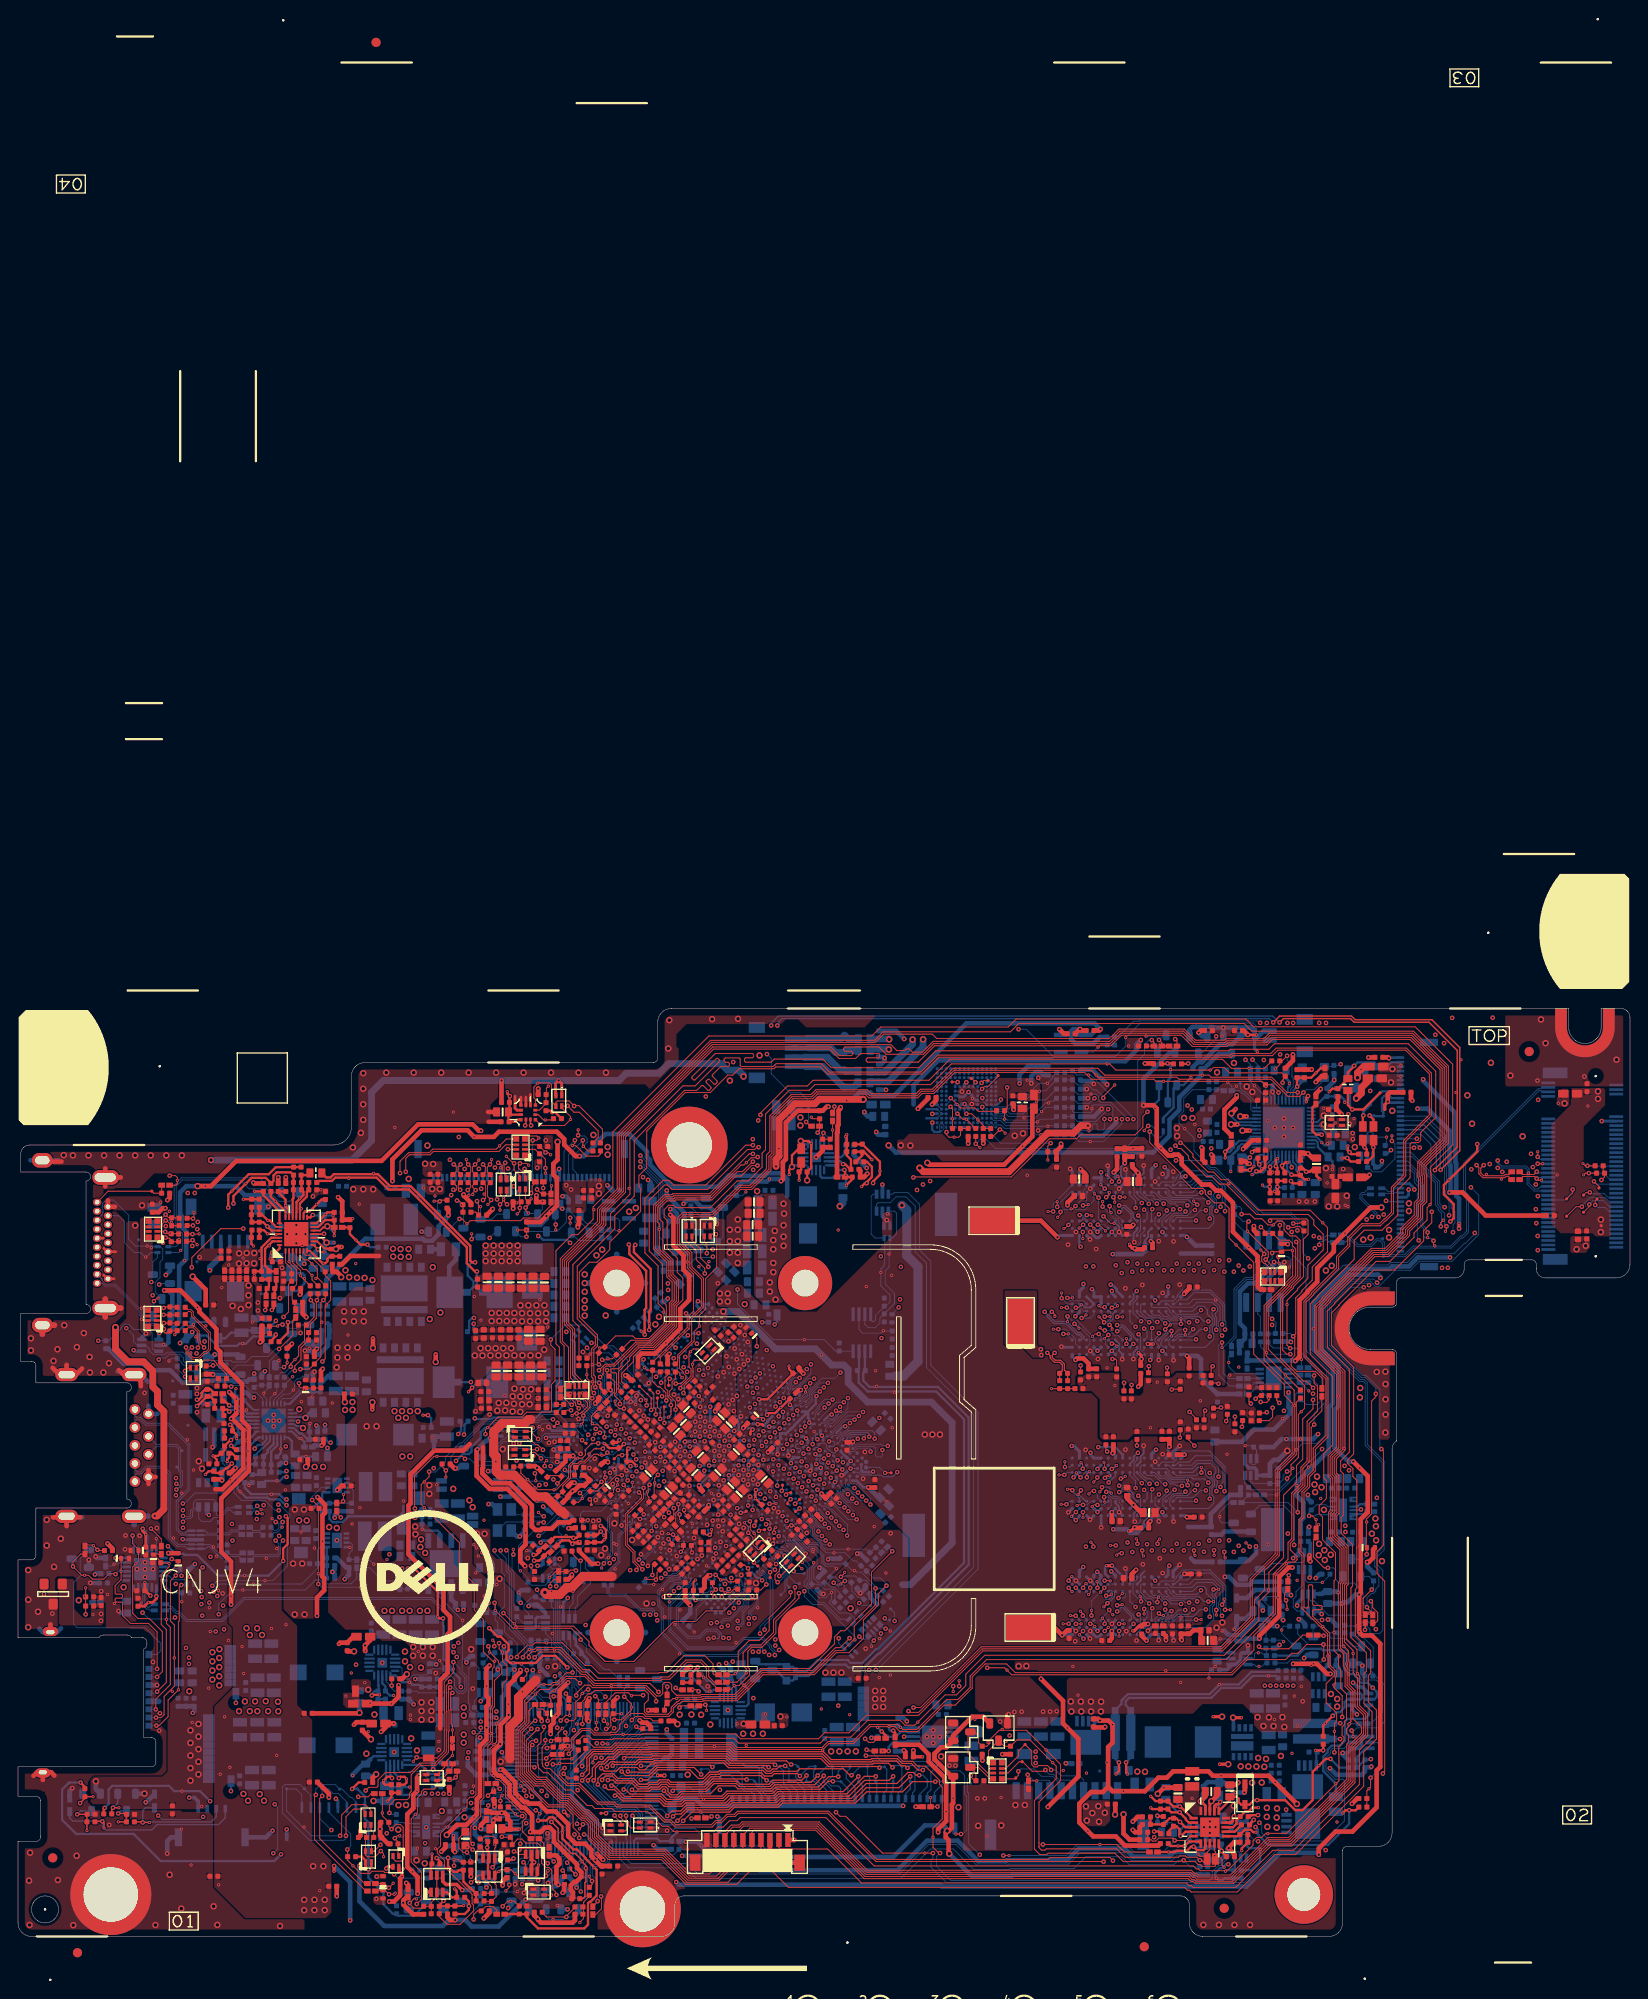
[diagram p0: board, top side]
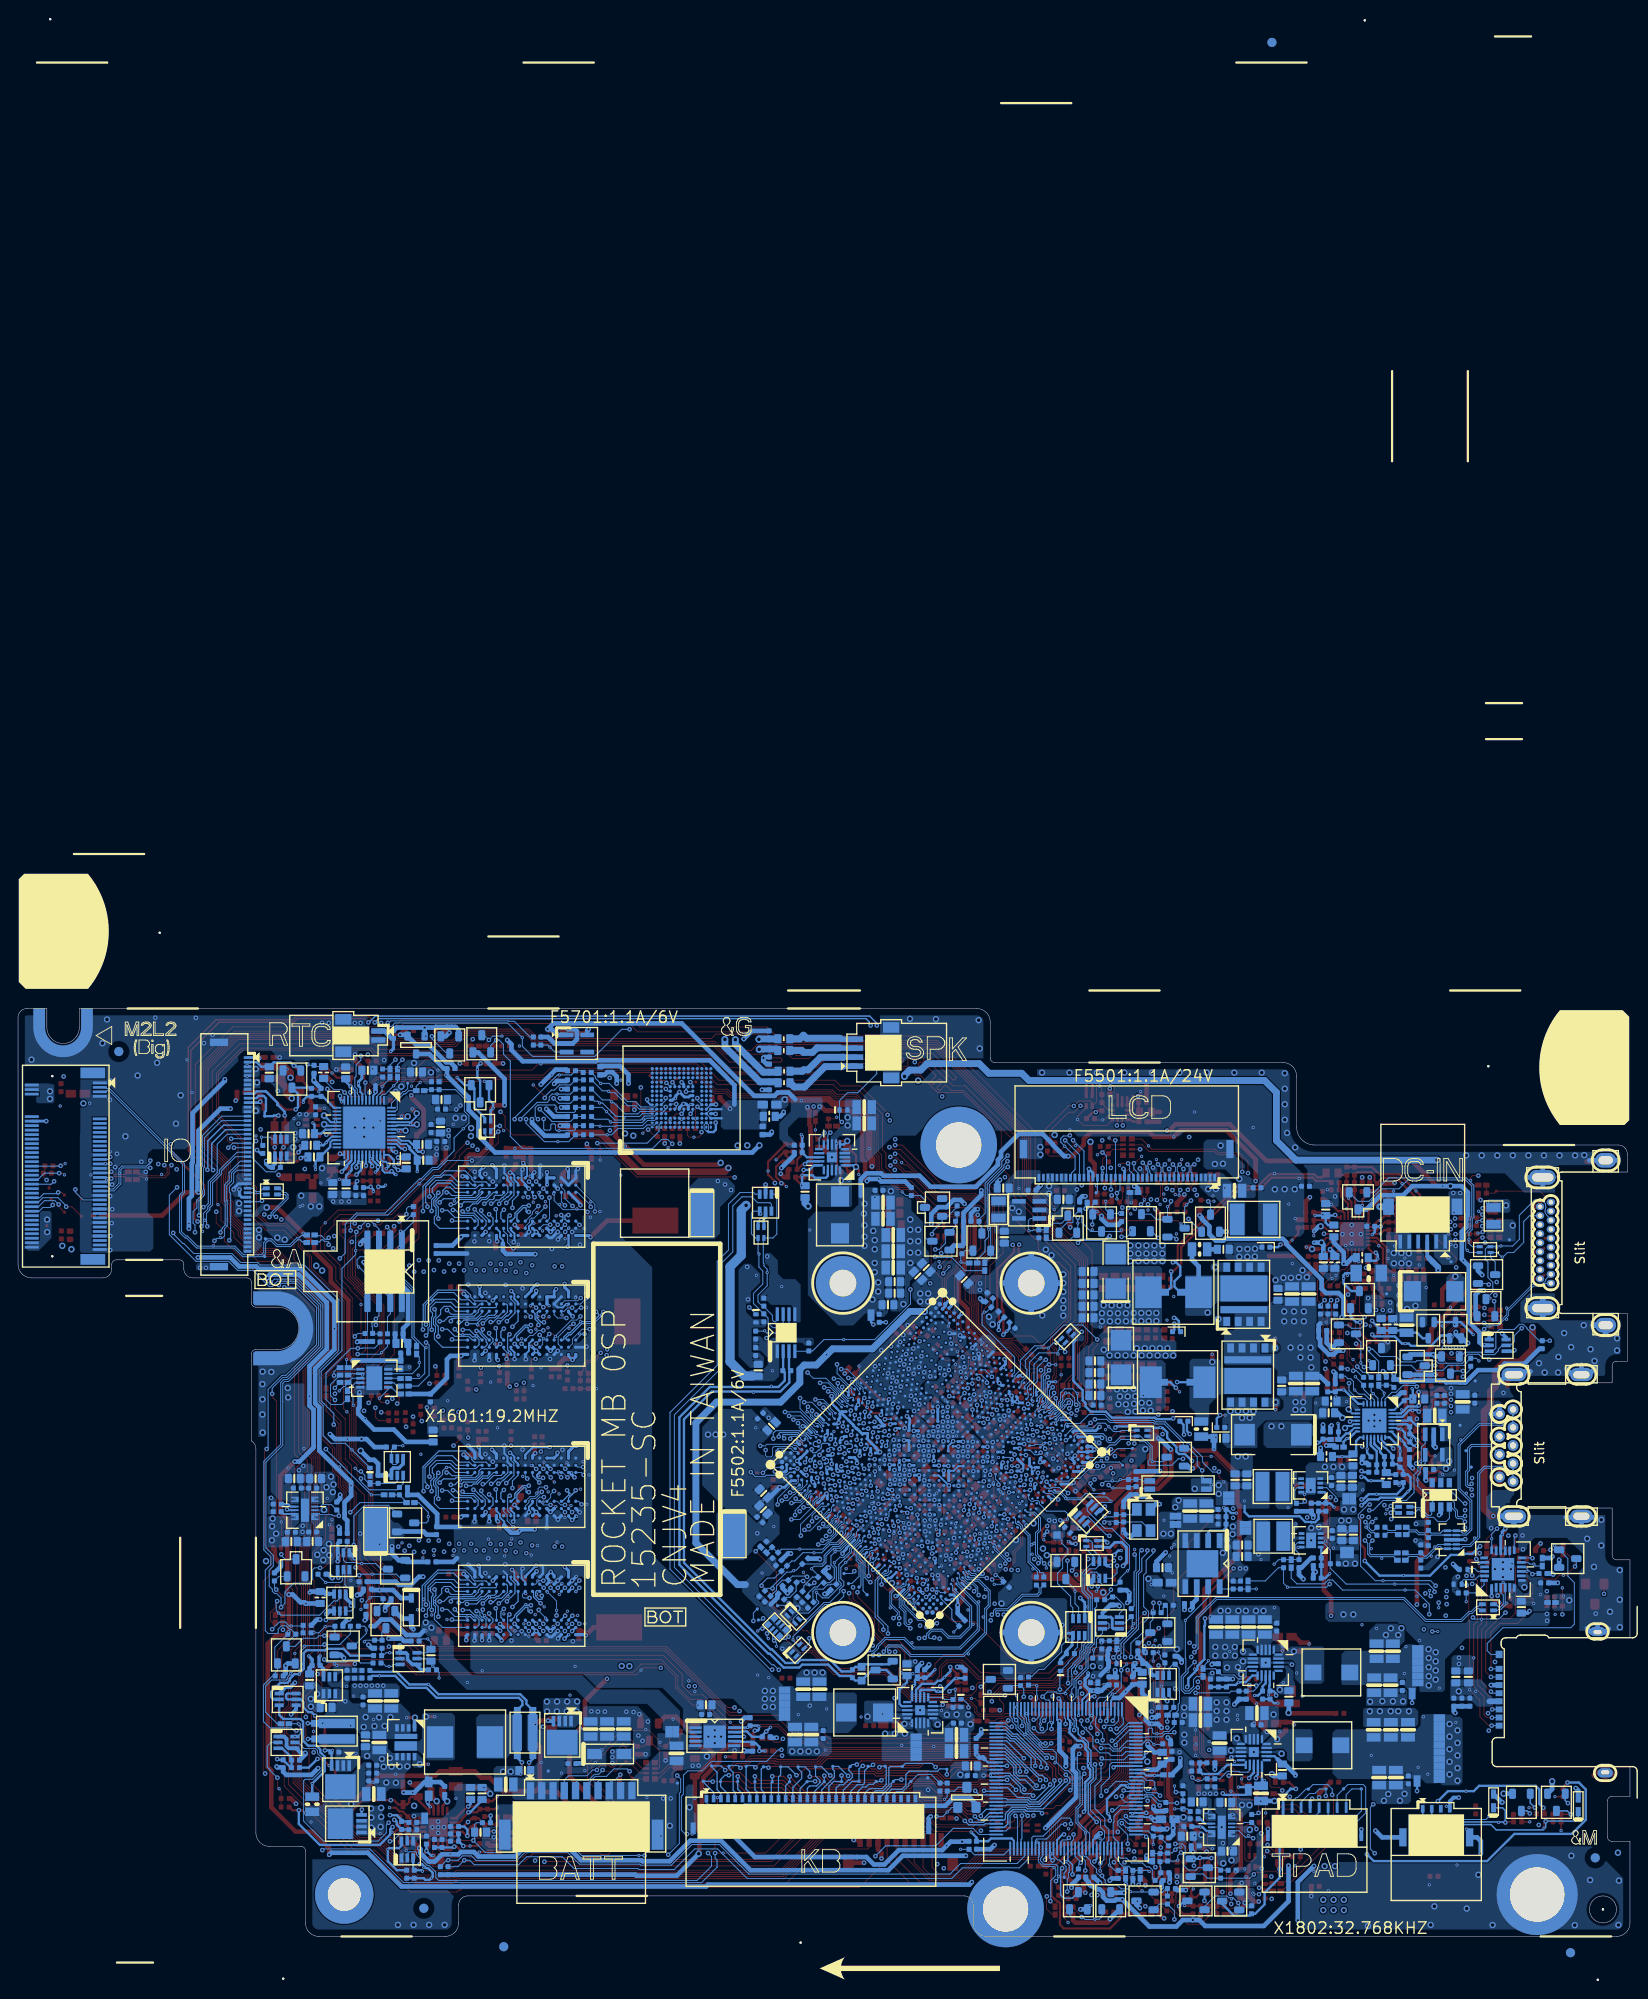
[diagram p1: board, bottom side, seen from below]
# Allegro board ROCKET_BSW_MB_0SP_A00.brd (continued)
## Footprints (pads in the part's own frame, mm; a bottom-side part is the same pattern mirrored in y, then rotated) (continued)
G6179HT0321-001
  rect 0.635x2.108 smd: 1(1.905,3.466) 2(0.635,3.466) 3(-0.635,3.466) 4(-1.905,3.466) 5(-1.905,-3.466) 6(-0.635,-3.466) 7(0.635,-3.466) 8(1.905,-3.466)
GAP-CLOSE-PWR-3
  rect 0.66x0.762 smd: 1(-0.305,0) 2(0.305,0)
HOLE256R142-OG
  round 6.502 hole 3.607: 1(0,0)
HOLE335R197
  round 8.509 hole 5.004: 1(0,0)
HOLE354R237
  round 8.992 hole 6.02: 1(0,0)
L1608-UH38
  custom 0.197x0.197 smd: 1(0,0.66) 2(0,-0.66)
L3030-3009H60
  rect 3.251x1.524 smd: 1(0,1.108) 2(0,-1.108)
L4947-1015H119
  rect 1.753x1.88 smd: 1(0,2.045) 2(0,-2.045)
L4947-1115H119
  rect 2.007x2.261 smd: 1(0,2.049) 2(0,-2.049)
L6965-1330-UH119
  rect 3.505x2.438 smd: 1(0,2.973) 2(0,-2.973)
L7066-1830-UH119
  rect 3.505x2.921 smd: 1(0,2.78) 2(0,-2.78)
L125100-4P-4H24
  rect 0.762x0.432 smd: 1(-0.625,0.341) 2(0.625,0.341) 3(0.625,-0.341) 4(-0.625,-0.341)
L125100-4P-4H28
  rect 0.762x0.432 smd: 1(-0.625,0.341) 2(0.625,0.341) 3(0.625,-0.341) 4(-0.625,-0.341)
LFQFN28J4-G2D7-UH40
  rect 0.203x0.584 smd: 1(1.2,1.86) 2(0.8,1.86) 3(0.4,1.86) 4(0,1.86) 5(-0.4,1.86) 6(-0.8,1.86) 7(-1.2,1.86) 15(-1.2,-1.86) 16(-0.8,-1.86) 17(-0.4,-1.86) 18(0,-1.86) 19(0.4,-1.86) 20(0.8,-1.86) 21(1.2,-1.86)
  rect 0.584x0.203 smd: 8(-1.86,1.2) 9(-1.86,0.8) 10(-1.86,0.4) 11(-1.86,0) 12(-1.86,-0.4) 13(-1.86,-0.8) 14(-1.86,-1.2) 22(1.86,-1.2) 23(1.86,-0.8) 24(1.86,-0.4) 25(1.86,0) 26(1.86,0.4) 27(1.86,0.8) 28(1.86,1.2)
  rect 2.692x2.692 smd: 29(0,0)
LGA12G2H40
  rect 0.381x0.381 smd: 1(0.809,0.809) 4(-0.809,0.809) 7(-0.809,-0.809) 10(0.809,-0.809)
  rect 0.305x0.432 smd: 2(0.25,0.784) 3(-0.25,0.784) 8(-0.25,-0.784) 9(0.25,-0.784)
  rect 0.432x0.305 smd: 5(-0.784,0.25) 6(-0.784,-0.25) 11(0.784,-0.25) 12(0.784,0.25)
LQFP128H63
  rect 0.203x1.524 smd: 1(6.2,7.747) 2(5.8,7.747) 3(5.4,7.747) 4(5,7.747) 5(4.6,7.747) 6(4.2,7.747) 7(3.8,7.747) 8(3.4,7.747) 9(3,7.747) 10(2.6,7.747) 11(2.2,7.747) 12(1.8,7.747) 13(1.4,7.747) 14(0.999,7.747) 15(0.599,7.747) 16(0.199,7.747) 17(-0.199,7.747) 18(-0.599,7.747) 19(-0.999,7.747) 20(-1.4,7.747) 21(-1.8,7.747) 22(-2.2,7.747) 23(-2.6,7.747) 24(-3,7.747) 25(-3.4,7.747) 26(-3.8,7.747) 27(-4.2,7.747) 28(-4.6,7.747) 29(-5,7.747) 30(-5.4,7.747) 31(-5.8,7.747) 32(-6.2,7.747) 65(-6.2,-7.747) 66(-5.8,-7.747) 67(-5.4,-7.747) 68(-5,-7.747) 69(-4.6,-7.747) 70(-4.2,-7.747) 71(-3.8,-7.747) 72(-3.4,-7.747) 73(-3,-7.747) 74(-2.6,-7.747) 75(-2.2,-7.747) 76(-1.8,-7.747) 77(-1.4,-7.747) 78(-0.999,-7.747) 79(-0.599,-7.747) 80(-0.199,-7.747) 81(0.199,-7.747) 82(0.599,-7.747) 83(0.999,-7.747) 84(1.4,-7.747) 85(1.8,-7.747) 86(2.2,-7.747) 87(2.6,-7.747) 88(3,-7.747) 89(3.4,-7.747) 90(3.8,-7.747) 91(4.2,-7.747) 92(4.6,-7.747) 93(5,-7.747) 94(5.4,-7.747) 95(5.8,-7.747) 96(6.2,-7.747)
  rect 1.524x0.203 smd: 33(-7.747,6.2) 34(-7.747,5.8) 35(-7.747,5.4) 36(-7.747,5) 37(-7.747,4.6) 38(-7.747,4.2) 39(-7.747,3.8) 40(-7.747,3.4) 41(-7.747,3) 42(-7.747,2.6) 43(-7.747,2.2) 44(-7.747,1.8) 45(-7.747,1.4) 46(-7.747,0.999) 47(-7.747,0.599) 48(-7.747,0.199) 49(-7.747,-0.199) 50(-7.747,-0.599) 51(-7.747,-0.999) 52(-7.747,-1.4) 53(-7.747,-1.8) 54(-7.747,-2.2) 55(-7.747,-2.6) 56(-7.747,-3) 57(-7.747,-3.4) 58(-7.747,-3.8) 59(-7.747,-4.2) 60(-7.747,-4.6) 61(-7.747,-5) 62(-7.747,-5.4) 63(-7.747,-5.8) 64(-7.747,-6.2) 97(7.747,-6.2) 98(7.747,-5.8) 99(7.747,-5.4) 100(7.747,-5) 101(7.747,-4.6) 102(7.747,-4.2) 103(7.747,-3.8) 104(7.747,-3.4) 105(7.747,-3) 106(7.747,-2.6) 107(7.747,-2.2) 108(7.747,-1.8) 109(7.747,-1.4) 110(7.747,-0.999) 111(7.747,-0.599) 112(7.747,-0.199) 113(7.747,0.199) 114(7.747,0.599) 115(7.747,0.999) 116(7.747,1.4) 117(7.747,1.8) 118(7.747,2.2) 119(7.747,2.6) 120(7.747,3) 121(7.747,3.4) 122(7.747,3.8) 123(7.747,4.2) 124(7.747,4.6) 125(7.747,5) 126(7.747,5.4) 127(7.747,5.8) 128(7.747,6.2)
MSOP8-1H44
  rect 0.356x1.524 smd: 1(-0.975,-2.055) 2(-0.325,-2.055) 3(0.325,-2.055) 4(0.975,-2.055) 5(0.975,2.055) 6(0.325,2.055) 7(-0.325,2.055) 8(-0.975,2.055)
MSOP10-G2D5H44
  rect 0.305x1.372 smd: 1(-1,-2.146) 2(-0.5,-2.146) 3(0,-2.146) 4(0.5,-2.146) 5(1,-2.146) 6(1,2.146) 7(0.5,2.146) 8(0,2.146) 9(-0.5,2.146) 10(-1,2.146)
  rect 2.489x2.489 smd: 11(0,0)
NFSA0-S6705-TP20
  round 0.254 hole 1.651 unplated: (-10,0)
  round 0.254 hole 1.168 unplated: (10,0)
  rect 0.305x1.549 smd: 1(9.25,-5.275) 2(9,2.275) 3(8.75,-5.275) 4(8.5,2.275) 5(8.25,-5.275) 6(8,2.275) 7(7.75,-5.275) 16(5.5,2.275) 17(5.25,-5.275) 18(5,2.275) 19(4.75,-5.275) 20(4.5,2.275) 21(4.25,-5.275) 22(4,2.275) 23(3.75,-5.275) 24(3.5,2.275) 25(3.25,-5.275) 26(3,2.275) 27(2.75,-5.275) 28(2.5,2.275) 29(2.25,-5.275) 30(2,2.275) 31(1.75,-5.275) 32(1.5,2.275) 33(1.25,-5.275) 34(1,2.275) 35(0.75,-5.275) 36(0.5,2.275) 37(0.25,-5.275) 38(0,2.275) 39(-0.25,-5.275) 40(-0.5,2.275) 41(-0.75,-5.275) 42(-1,2.275) 43(-1.25,-5.275) 44(-1.5,2.275) 45(-1.75,-5.275) 46(-2,2.275) 47(-2.25,-5.275) 48(-2.5,2.275) 49(-2.75,-5.275) 50(-3,2.275) 51(-3.25,-5.275) 52(-3.5,2.275) 53(-3.75,-5.275) 54(-4,2.275) 55(-4.25,-5.275) 56(-4.5,2.275) 57(-4.75,-5.275) 58(-5,2.275) 59(-5.25,-5.275) 60(-5.5,2.275) 61(-5.75,-5.275) 62(-6,2.275) 63(-6.25,-5.275) 64(-6.5,2.275) 65(-6.75,-5.275) 66(-7,2.275) 67(-7.25,-5.275) 68(-7.5,2.275) 69(-7.75,-5.275) 70(-8,2.275) 71(-8.25,-5.275) 72(-8.5,2.275) 73(-8.75,-5.275) 74(-9,2.275) 75(-9.25,-5.275)
  rect 1.194x2.743 smd: 76(10.35,-4.5) 77(-10.35,-4.5)
NTC-402H24-U
  custom 0.14x0.14 smd: 1(0,0.445) 2(0,-0.445)
NTC-603H38
  custom 0.216x0.216 smd: 1(0,0.762) 2(0,-0.762)
OSC-3225-4P-4H32
  rect 1.397x1.067 smd: 1(-1.171,-0.756) 2(1.171,-0.756) 3(1.171,0.756) 4(-1.171,0.756)
PAD-87212-1002N
  rect 0.61x1.549 smd: 1(-4.5,-2.525) 2(-3.5,-2.525) 3(-2.5,-2.525) 4(-1.5,-2.525) 5(-0.5,-2.525) 6(0.5,-2.525) 7(1.5,-2.525) 8(2.5,-2.525) 9(3.5,-2.525) 10(4.5,-2.525)
  rect 1.194x1.803 smd: 11(-5.797,0) 12(5.797,0)
POLYSW-2114H30
  rect 1.6x0.965 smd: 1(0,0.94) 2(0,-0.94)
POLYSW-4633-UH43
  rect 3.505x1.626 smd: 1(0,1.834) 2(0,-1.834)
PPAK-8P-2H45
  rect 0.406x1.168 smd: 1(-0.975,-2.351) 2(-0.325,-2.351) 3(0.325,-2.351) 4(0.975,-2.351)
  rect 3.404x2.769 smd: 5(0,0)
  rect 0.025x0.025 smd: 6(1.029,0.902) 7(0.013,0.902) 8(-0.991,0.902)
PPAK-8P-G5324H44-COLAY
  rect 0.762x1.016 smd: 1(-1.905,-3.01) 2(-0.635,-3.01) 3(0.635,-3.01) 4(1.905,-3.01) 5(1.905,3.01) 6(0.635,3.01) 7(-0.635,3.01) 8(-1.905,3.01)
  rect 5.207x2.896 smd: 9(0,0.65)
  rect 5.207x0.787 smd: 10(0,-1.7)
PTFBT4-09GLBS1NN4H2
  rect 0.813x0.762 smd: 1(5.3,11.775)
  rect 0.66x0.762 smd: 2(3.7,11.775) 3(2.8,11.775) 4(1.9,11.775) 5(1,11.775) 6(0.1,11.775) 7(-0.8,11.775) 8(-1.7,11.775) 9(-2.6,11.775)
  oval 1.016x1.702 hole 0.457x0.914: 10(-7.775,0) 11(7.775,0.85)
QFN20G3D5-G2D15H40
  rect 0.305x0.914 smd: 1(1,1.801) 5(-1,1.801) 11(-1,-1.801) 15(1,-1.801)
  rect 0.305x0.965 smd: 2(0.5,1.775) 3(0,1.775) 4(-0.5,1.775) 12(-0.5,-1.775) 13(0,-1.775) 14(0.5,-1.775)
  rect 0.914x0.305 smd: 6(-1.801,1) 10(-1.801,-1) 16(1.801,-1) 20(1.801,1)
  rect 0.965x0.305 smd: 7(-1.775,0.5) 8(-1.775,0) 9(-1.775,-0.5) 17(1.775,-0.5) 18(1.775,0) 19(1.775,0.5)
  rect 2.159x2.159 smd: 21(0,0)
QFN20Z3-G1D1H36
  custom 0.064x0.064 smd: 1(0.9,1.424) 5(-0.9,1.424) 6(-1.424,0.9) 10(-1.424,-0.9) 11(-0.9,-1.424) 15(0.9,-1.424) 16(1.424,-0.9) 20(1.424,0.9)
  rect 0.254x1.168 smd: 2(0.45,1.424) 3(0,1.424) 4(-0.45,1.424) 12(-0.45,-1.424) 13(0,-1.424) 14(0.45,-1.424)
  rect 1.168x0.254 smd: 7(-1.424,0.45) 8(-1.424,0) 9(-1.424,-0.45) 17(1.424,-0.45) 18(1.424,0) 19(1.424,0.45)
  rect 1.092x1.092 smd: 21(0,0)
QFN24-G2D5H40-U
  rect 0.305x0.838 smd: 1(1.25,2.095) 6(-1.25,2.095) 13(-1.25,-2.095) 18(1.25,-2.095)
  rect 0.305x0.965 smd: 2(0.751,2.032) 3(0.25,2.032) 4(-0.25,2.032) 5(-0.751,2.032) 14(-0.751,-2.032) 15(-0.25,-2.032) 16(0.25,-2.032) 17(0.751,-2.032)
  rect 0.838x0.305 smd: 7(-2.095,1.25) 12(-2.095,-1.25) 19(2.095,-1.25) 24(2.095,1.25)
  rect 0.965x0.305 smd: 8(-2.032,0.751) 9(-2.032,0.25) 10(-2.032,-0.25) 11(-2.032,-0.751) 20(2.032,-0.751) 21(2.032,-0.25) 22(2.032,0.25) 23(2.032,0.751)
  rect 2.489x2.489 smd: 25(0,0)
QFN48J6-G465H40
  rect 0.203x0.965 smd: 1(2.2,3.025) 2(1.8,3.025) 3(1.4,3.025) 4(1,3.025) 5(0.6,3.025) 6(0.2,3.025) 7(-0.2,3.025) 8(-0.6,3.025) 9(-1,3.025) 10(-1.4,3.025) 11(-1.8,3.025) 12(-2.2,3.025) 25(-2.2,-3.025) 26(-1.8,-3.025) 27(-1.4,-3.025) 28(-1,-3.025) 29(-0.6,-3.025) 30(-0.2,-3.025) 31(0.2,-3.025) 32(0.6,-3.025) 33(1,-3.025) 34(1.4,-3.025) 35(1.8,-3.025) 36(2.2,-3.025)
  rect 0.965x0.203 smd: 13(-3.025,2.2) 14(-3.025,1.8) 15(-3.025,1.4) 16(-3.025,1) 17(-3.025,0.6) 18(-3.025,0.2) 19(-3.025,-0.2) 20(-3.025,-0.6) 21(-3.025,-1) 22(-3.025,-1.4) 23(-3.025,-1.8) 24(-3.025,-2.2) 37(3.025,-2.2) 38(3.025,-1.8) 39(3.025,-1.4) 40(3.025,-1) 41(3.025,-0.6) 42(3.025,-0.2) 43(3.025,0.2) 44(3.025,0.6) 45(3.025,1) 46(3.025,1.4) 47(3.025,1.8) 48(3.025,2.2)
  rect 4.648x4.648 smd: 49(0,0)
R402H14
  custom 0.14x0.14 smd: 1(0,0.445) 2(0,-0.445)
R402H16
  custom 0.14x0.14 smd: 1(0,0.445) 2(0,-0.445)
R603H22
  custom 0.197x0.197 smd: 1(0,0.66) 2(0,-0.66)
R805H24
  rect 1.549x0.94 smd: 1(0,0.838) 2(0,-0.838)
R1206H28
  rect 1.854x1.27 smd: 1(0,1.397) 2(0,-1.397)
R3720H40
  rect 4.013x1.041 smd: 1(0,0.867) 2(0,-0.867)
SC70-2D2-312H44
  custom 0.152x0.152 smd: 1(-0.65,-0.902) 2(0.65,-0.902) 3(0,0.902)
SC70-6H44
  rect 0.406x1.016 smd: 1(-0.65,-0.94) 2(0,-0.94) 3(0.65,-0.94) 4(0.65,0.94) 5(0,0.94) 6(-0.65,0.94)
SKT-HDMI23-188125-1-U1
  oval 0.762x0.914 hole 0.508: 1(-4.5,6.08) 2(-4,7.28) 3(-3.5,6.08) 4(-3,7.28) 5(-2.5,6.08) 6(-2,7.28) 7(-1.5,6.08) 8(-1,7.28) 9(-0.5,6.08) 10(0,7.28) 11(0.5,6.08) 12(1,7.28) 13(1.5,6.08) 14(2,7.28) 15(2.5,6.08) 16(3,7.28) 17(3.5,6.08) 18(4,7.28) 19(4.5,6.08)
  oval 1.626x2.972 hole 0.914x2.362: 20(7.25,6.98) 22(-7.25,6.98)
  oval 1.626x2.311 hole 0.914x1.6: 21(9.15,0) 23(-9.15,0)
SKT-USB13-160161
  round 1.194 hole 0.711: 1(3.5,9.09) 2(1,9.09) 3(-1,9.09) 4(-3.5,9.09) 5(-4,7.59) 6(-2,7.59) 7(0,7.59) 8(2,7.59) 9(4,7.59)
  oval 1.473x2.515 hole 0.813x1.803: 10(-7.85,0) 11(7.85,0)
  oval 1.473x2.718 hole 0.813x2.007: 12(-7.85,7.5) 13(7.85,7.5)
SMD-ARES4
  rect 0.356x0.66 smd: 1(-0.325,-0.599) 2(0.325,-0.599) 3(0.325,0.599) 4(-0.325,0.599)
SMD-ARES4H18
  rect 0.356x0.66 smd: 1(-0.325,-0.599) 2(0.325,-0.599) 3(0.325,0.599) 4(-0.325,0.599)
SMD-ARES4H20
  rect 0.356x0.66 smd: 1(-0.325,-0.599) 2(0.325,-0.599) 3(0.325,0.599) 4(-0.325,0.599)
SMD-OSC2H56
  rect 1.194x0.61 smd: 1(-3.147,-0.457) 2(3.147,-0.457) 3(3.147,0.457) 4(-3.147,0.457)
SOD123FLAKH40
  rect 1.143x1.651 smd: A(0,1.622) K(0,-1.622)
SOD323AKH38
  rect 0.559x1.016 smd: A(0,1.143) K(0,-1.143)
SOD323AKH42
  rect 0.559x1.016 smd: A(0,1.143) K(0,-1.143)
SOD882-10D6-1H20
  custom 0.114x0.114 smd: 1(0,0.445) 2(0,-0.445)
SOD-523-2H26
  rect 0.559x1.016 smd: 1(0,0.762) 2(0,-0.762)
SOIC8-1H86
  rect 0.635x1.651 smd: 1(-1.905,-3.493) 2(-0.635,-3.493) 3(0.635,-3.493) 4(1.905,-3.493) 5(1.905,3.493) 6(0.635,3.493) 7(-0.635,3.493) 8(-1.905,3.493)
SOIC8-G3530H63
  rect 0.635x1.651 smd: 1(-1.905,-2.555) 2(-0.635,-2.555) 3(0.635,-2.555) 4(1.905,-2.555) 5(1.905,2.555) 6(0.635,2.555) 7(-0.635,2.555) 8(-1.905,2.555)
  rect 3.505x2.997 smd: 9(0,0)
SON14J3020-G2610H32
  rect 0.025x0.025 smd: 1(1.2,1.105) 6(-0.8,1.105) 9(-0.8,-1.105) 14(1.2,-1.105)
  custom 0.151x0.151 smd: 2(0.8,1.105) 7(-1.2,1.105) 8(-1.2,-1.105) 13(0.8,-1.105)
  rect 0.203x0.813 smd: 3(0.4,1.105) 4(0,1.105) 5(-0.4,1.105) 10(-0.4,-1.105) 11(0,-1.105) 12(0.4,-1.105)
  rect 2.591x0.889 smd: 15(0,0)
SOT23-2D4-312H44
  custom 0.191x0.191 smd: 1(-0.984,-0.953) 2(0.984,-0.953) 3(0,0.953)
SOT23-2D4-312H48
  custom 0.191x0.191 smd: 1(-0.984,-0.953) 2(0.984,-0.953) 3(0,0.953)
SOT23-2D8-123H52
  custom 0.254x0.254 smd: 1(0,1.118) 2(-1.016,-1.118) 3(1.016,-1.118)
SOT23CBE2D4H44
  custom 0.191x0.191 smd: B(-0.984,-0.953) C(0,0.953) E(0.984,-0.953)
SOT23CBE2D8H56
  custom 0.254x0.254 smd: B(-1.016,-1.118) C(0,1.118) E(1.016,-1.118)
SOT23DGS2D4H35
  custom 0.191x0.191 smd: D(0,0.953) G(-0.984,-0.953) S(0.984,-0.953)
SOT23DGS2D4H44
  custom 0.191x0.191 smd: D(0,0.953) G(-0.984,-0.953) S(0.984,-0.953)
SOT23DGS2D4H48
  custom 0.191x0.191 smd: D(0,0.953) G(-0.984,-0.953) S(0.984,-0.953)
SOT-6H58
  rect 0.584x1.016 smd: 1(-0.953,-1.346) 2(0,-1.346) 3(0.953,-1.346) 4(0.953,1.346) 5(0,1.346) 6(-0.953,1.346)
SOT-23-5H51
  rect 0.508x1.524 smd: 1(-0.95,-1.143) 2(0,-1.143) 3(0.95,-1.143) 4(0.95,1.143) 5(-0.95,1.143)
SOT-23-5H52
  rect 0.508x1.524 smd: 1(-0.95,-1.143) 2(0,-1.143) 3(0.95,-1.143) 4(0.95,1.143) 5(-0.95,1.143)
SOT-23-5H58
  rect 0.508x1.524 smd: 1(-0.95,-1.143) 2(0,-1.143) 3(0.95,-1.143) 4(0.95,1.143) 5(-0.95,1.143)
SOT-23-9H44
  custom 0.178x0.178 smd: 1(-0.95,-0.999) 2(0.95,-0.999) 3(0,0.999)
SOT-363H44
  rect 0.406x1.016 smd: 1(-0.65,-0.94) 2(0,-0.94) 3(0.65,-0.94) 4(0.65,0.94) 5(0,0.94) 6(-0.65,0.94)
SPR5128H111
  rect 4.801x2.489 smd: 1(-1.397,0)
SPR5432H83
  rect 5.105x2.896 smd: 1(-1.499,0)
STF237R117H67
  round 6.02 hole 2.972: 1(0,0)
TPAD14-OP
  round 0.356 smd: 1(0,0)
unnamed
  round 1.016 smd: (0,0)

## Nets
1V_CPU_CORE: C1027.1 C1029.1 C1030.1 C1032.1 C1033.1 C1036.1 CPU1.AF29 CPU1.AF30 CPU1.AF36 CPU1.AG27 CPU1.AG29 CPU1.AG30 CPU1.AG33 CPU1.AG35 CPU1.AG36 CPU1.AG38 CPU1.AJ27 CPU1.AJ29 CPU1.AJ30 CPU1.AJ33 CPU1.AJ36 CPU1.AJ38 EC1001.1 EC1002.1 EC1003.1 EC1004.1 PC1040.1 PC1041.1 PC1042.1 PC1048.1 PC1058.1 PC1059.1 PC1060.1 PC1061.1 PC1066.1 PC1067.1 PC1068.1 PC1069.1 PC4706.1 PC4707.1 PC4708.1 PG4709.2 PL4701.2 PT4701.1 R1848.1 R1851.1
3V_5V_EN: D4001.1 PR4511.1 PR4514.1 R4001.1 R4005.1 RN4501.1(A)
3V_5V_POK: EC1814.1 PG4534.1 PR4504.1 R1844.2 R4017.1
5V_DDC_HDMI1: D5701.1 RN5701.3(B)
5V_DDC_HDMI2: D5701.2 RN5701.4(B)
5V_HDMI: EC5701.1 F5701.1 HDMI1.18
5V_PWR: PC4514.1 PC4515.1 PC4516.1 PC4517.1 PC4518.1 PC4527.1 PG4519.2 PG4521.1 PG4523.2 PG4532.2 PG4533.2 PG4537.2 PG4538.2 PG4540.2 PG4541.2 PG4544.2 PG4545.2 PL4502.2
5V_PWR_2: PG4525.1 R2915.1
5V_S0: C2706.1 C2707.1 C2708.1 C2709.1 C4003.1 D5701.3 EC4003.1 IOBD1.38 Q5701.2 Q6501.E R2427.1 R2703.2 U2701.41 U2701.46 U4001.13 U4001.14
5V_S0_CT: C4004.1 U4001.12
5V_S5: AFTP5402.1 C3606.1 C4037.1 EC4001.1 EC4006.1 F5701.2 IOBD1.39 IOBD1.40 IOBD1.41 IOBD1.42 IOBD1.43 IOBD1.44 PC5401.1 PG4519.1 PG4523.1 PG4532.1 PG4533.1 PG4537.1 PG4538.1 PG4540.1 PG4541.1 PG4544.1 PG4545.1 PR4303.1 PR4620.1 PR4637.1 PR4817.1 PR4818.1 PR5117.2 PU5402.6 Q6403.E Q6404.E U3601.5 U4001.1 U4001.2 U4001.4 U4016.4
5V_USB30: AFTP3401.1 C3601.1 C3602.1 C3608.1 C3609.1 EU3505.5 R3605.1 U3601.1 USB1.1
12V_BT+: AFTP4304.1 BATT1.1 BATT1.2 BATT1.3 EC4303.1 PC4415.1 PC4416.1 PC4417.1 PC4418.1 PC4419.1 PD4302.K PG4405.2 PG4410.2 PR4416.2 PU4403.5 PU4403.6 PU4403.7 PU4403.8
19V_AD+: PC4303.1 PC4304.1 PC4305.1 PC4306.1 PR4404.1 PR4405.1 PR4407.1 PR4408.1 PR4469.1 PU4301.5 PU4301.6 PU4301.7 PU4301.8 PU4402.5 PU4402.6 PU4402.7 PU4402.8 PU4403.4
19V_DCBATOUT: EC4401.1 EC4402.1 EC4701.1 EC4801.1 EC5501.1 EC5502.1 EC5503.1 F5501.1 PC4406.1 PC4408.1 PC4409.1 PC4426.1 PC4431.1 PC4501.1 PC4502.1 PC4503.1 PC4504.1 PC4505.1 PC4519.1 PC4522.1 PC4523.1 PC4528.1 PC4529.1 PC4702.1 PC4705.1 PC4801.1 PC4811.1 PC5004.1 PC5008.1 PG4403.1 PG5101.1 PG5103.1 PG5106.1 PG5107.1 PR4402.2 PR4468.1 PR4512.1 PR4515.1 PR4607.1 PR4827.1 PT4702.1 PU4403.1 PU4403.2 PU4403.3 PU4405.2 PU4405.3 PU4405.4 PU4405.10 PU4407.3 PU4502.2 PU4502.3 PU4502.4 PU4502.5 PU4503.2 PU4503.3 PU4503.4 PU4503.5 PU4701.2 PU4701.3 PU4701.4 PU4701.10 PU4801.2 PU4801.3 PU4801.4 PU4801.10 PU5001.2 PU5001.3 PU5001.4 PU5001.5
19V_DCBATOUT_LCD: C5502.1 C5503.1 C5504.1 F5501.2 LCD1.1 LCD1.2 LCD1.3 LCD1.4
+3V_1D5V_AVDD: C2715.1 R2705.2 U2701.40
+3V_AVDD: C2701.1 R2713.2 U2701.36
+5V_AVDD: C2710.1 C2711.1 R2703.1 U2701.26
DVDD_1D5V: C2714.2 C2719.1 C2721.2 R2701.2 U2701.9
GND: AFTP3404.1 AFTP4203.1 AFTP4305.1 AFTP6226.1 BATT1.8 BATT1.9 BATT1.10 BATT1.11 BATT1.12 C1001.2 C1002.2 C1003.2 C1004.2 C1005.2 C1006.2 C1007.2 C1008.2 C1013.2 C1015.2 C1016.2 C1017.2 C1018.2 C1019.2 C1020.2 C1021.2 C1022.2 C1023.2 C1024.2 C1025.2 C1026.2 C1027.2 C1028.2 C1029.2 C1030.2 C1032.2 C1033.2 C1034.2 C1035.2 C1036.2 C1037.2 C1038.2 C1039.2 C1047.2 C1049.2 C1050.2 C1056.2 C1057.2 C1101.2 C1102.2 C1103.2 C1104.2 C1105.2 C1106.2 C1107.2 C1108.2 C1109.2 C1110.2 C1111.2 C1112.2 C1113.2 C1114.2 C1115.2 C1116.2 C1117.2 C1121.2 C1125.2 C1126.2 C1127.2 C1128.2 C1129.2 C1130.2 C1131.2 C1132.2 C1133.2 C1134.2 C1137.2 C1138.2 C1143.2 C1144.2 C1147.2 C1148.2 C1149.2 C1150.2 C1201.2 C1203.2 C1204.2 C1205.2 C1206.2 C1207.2 C1209.2 C1210.2 C1211.2 C1212.2 C1213.2 C1214.2 C1215.2 C1216.2 C1217.2 C1219.2 C1220.2 C1221.2 C1222.2 C1223.2 C1601.2 C1602.2 C1801.2 C1802.2 C1803.2 C1806.2 C1807.2 C1810.1 C1811.2 C1910.2 C2401.2 C2414.2 C2417.2 C2428.1 C2429.2 C2430.2 C2431.2 C2432.2 C2433.2 C2439.2 C2440.2 C2441.2 C2443.2 C2444.2 C2445.2 C2446.2 C2447.2 C2501.2 C2502.2 C2505.2 C2601.2 C2602.2 C2606.2 C2701.2 C2704.1 C2706.2 C2707.2 C2708.2 C2709.2 C2714.1 C2716.2 C2717.2 C2718.2 C2719.2 C2721.1 C2723.1 C2901.2 C3301.2 C3302.2 C3303.2 C3304.2 C3305.2 C3306.2 C3307.2 C3308.1 C3309.1 C3310.2 C3508.2 C3509.2 C3510.2 C3511.2 C3601.2 C3602.2 C3606.2 C3608.2 C3609.2 C4001.2 C4002.2 C4003.2 C4004.2 C4005.2 C4011.2 C4012.2 C4037.2 C4038.2 C4039.2 C4041.2 C4042.2 C4043.2 C4046.2 C4050.2 C4051.2 C5502.2 C5503.2 C5504.2 C5508.2 C5509.1 C5511.2 C5512.2 C5514.2 C6102.2 C6103.2 C6104.2 C6301.2 C6302.2 C6303.2 C6304.2 C6305.2 C6701.2 C6702.2 C6901.2 C6902.2 CPU1.A5 CPU1.A7 CPU1.A11 CPU1.A15 CPU1.A19 CPU1.A23 CPU1.A31 CPU1.A39 CPU1.A43 CPU1.A47 CPU1.AA16 CPU1.AA27 CPU1.AA38 CPU1.AA53 CPU1.AB4 CPU1.AB6 CPU1.AB10 CPU1.AB12 CPU1.AB13 CPU1.AB14 CPU1.AB42 CPU1.AB47 CPU1.AB50 CPU1.AC16 CPU1.AC29 CPU1.AC33 CPU1.AC35 CPU1.AC38 CPU1.AD4 CPU1.AD21 CPU1.AD30 CPU1.AD32 CPU1.AD36 CPU1.AD44 CPU1.AE1 CPU1.AE6 CPU1.AE8 CPU1.AE9 CPU1.AE11 CPU1.AE12 CPU1.AE14 CPU1.AE40 CPU1.AE42 CPU1.AE43 CPU1.AE45 CPU1.AE46 CPU1.AE48 CPU1.AE50 CPU1.AE53 CPU1.AF10 CPU1.AF24 CPU1.AF25 CPU1.AF32 CPU1.AF38 CPU1.AF47 CPU1.AG25 CPU1.AH9 CPU1.AH10 CPU1.AH12 CPU1.AH13 CPU1.AH14 CPU1.AH41 CPU1.AH42 CPU1.AH44 CPU1.AH47 CPU1.AJ1 CPU1.AJ3 CPU1.AJ16 CPU1.AJ18 CPU1.AJ25 CPU1.AJ51 CPU1.AJ53 CPU1.AK4 CPU1.AK7 CPU1.AK16 CPU1.AK22 CPU1.AK25 CPU1.AK27 CPU1.AK29 CPU1.AK32 CPU1.AK38 CPU1.AK40 CPU1.AK44 CPU1.AK45 CPU1.AK47 CPU1.AK50 CPU1.AM4 CPU1.AM13 CPU1.AM16 CPU1.AM24 CPU1.AM27 CPU1.AM30 CPU1.AM35 CPU1.AM38 CPU1.AM42 CPU1.AM50 CPU1.AN1 CPU1.AN3 CPU1.AN5 CPU1.AN6 CPU1.AN8 CPU1.AN9 CPU1.AN11 CPU1.AN12 CPU1.AN14 CPU1.AN16 CPU1.AN21 CPU1.AN24 CPU1.AN25 CPU1.AN29 CPU1.AN30 CPU1.AN33 CPU1.AN38 CPU1.AN40 CPU1.AN42 CPU1.AN43 CPU1.AN45 CPU1.AN46 CPU1.AN48 CPU1.AN49 CPU1.AN51 CPU1.AN53 CPU1.AP4 CPU1.AP9 CPU1.AP45 CPU1.AP50 CPU1.AT3 CPU1.AT9 CPU1.AT18 CPU1.AT19 CPU1.AT27 CPU1.AT35 CPU1.AT36 CPU1.AT45 CPU1.AT51 CPU1.AU1 CPU1.AU3 CPU1.AU51 CPU1.AU53 CPU1.AV14 CPU1.AV19 CPU1.AV24 CPU1.AV27 CPU1.AV30 CPU1.AV35 CPU1.AV40 CPU1.AW13 CPU1.AW19 CPU1.AW27 CPU1.AW35 CPU1.AW41 CPU1.AY3 CPU1.AY7 CPU1.AY9 CPU1.AY20 CPU1.AY22 CPU1.AY24 CPU1.AY26 CPU1.AY28 CPU1.AY30 CPU1.AY32 CPU1.AY34 CPU1.AY45 CPU1.AY47 CPU1.AY51 CPU1.B2 CPU1.B28 CPU1.B36 CPU1.BA19 CPU1.BA24 CPU1.BA27 CPU1.BA30 CPU1.BA35 CPU1.BB4 CPU1.BB19 CPU1.BB27 CPU1.BB35 CPU1.BB50 CPU1.BC10 CPU1.BC14 CPU1.BC16 CPU1.BC26 CPU1.BC28 CPU1.BC38 CPU1.BC40 CPU1.BC44 CPU1.BD1 CPU1.BD19 CPU1.BD27 CPU1.BD35 CPU1.BD53 CPU1.BE19 CPU1.BE35 CPU1.BF4 CPU1.BF12 CPU1.BF22 CPU1.BF26 CPU1.BF27 CPU1.BF28 CPU1.BF32 CPU1.BF42 CPU1.BF50 CPU1.BG1 CPU1.BG5 CPU1.BG7 CPU1.BG14 CPU1.BG16 CPU1.BG18 CPU1.BG19 CPU1.BG20 CPU1.BG24 CPU1.BG27 CPU1.BG30 CPU1.BG34 CPU1.BG35 CPU1.BG36 CPU1.BG38 CPU1.BG40 CPU1.BG47 CPU1.BG49 CPU1.BG53 CPU1.BH1 CPU1.BH2 CPU1.BH52 CPU1.BJ7 CPU1.BJ11 CPU1.BJ15 CPU1.BJ19 CPU1.BJ23 CPU1.BJ27 CPU1.BJ31 CPU1.BJ35 CPU1.BJ39 CPU1.BJ43 CPU1.BJ47 CPU1.C1 CPU1.C3 CPU1.C20 CPU1.C22 CPU1.C28 CPU1.C30 CPU1.C36 CPU1.C39 CPU1.C47 CPU1.D10 CPU1.D16 CPU1.D24 CPU1.D27 CPU1.D32 CPU1.D38 CPU1.D40 CPU1.D42 CPU1.E19 CPU1.E35 CPU1.E46 CPU1.E51 CPU1.F1 CPU1.F5 CPU1.F19 CPU1.F24 CPU1.F27 CPU1.F32 CPU1.F35 CPU1.G12 CPU1.G14 CPU1.G22 CPU1.G26 CPU1.G28 CPU1.G30 CPU1.H8 CPU1.H19 CPU1.H27 CPU1.H35 CPU1.J18 CPU1.J19 CPU1.J22 CPU1.J27 CPU1.J30 CPU1.J35 CPU1.J38 CPU1.J42 CPU1.J53 CPU1.K4 CPU1.K12 CPU1.K14 CPU1.K16 CPU1.K22 CPU1.K24 CPU1.K30 CPU1.K32 CPU1.K34 CPU1.K36 CPU1.K45 CPU1.K50 CPU1.L1 CPU1.L19 CPU1.L27 CPU1.L35 CPU1.L41 CPU1.M9 CPU1.M14 CPU1.M19 CPU1.M24 CPU1.M27 CPU1.M35 CPU1.M40 CPU1.M45 CPU1.M50 CPU1.N22 CPU1.N24 CPU1.N32 CPU1.N51 CPU1.N53 CPU1.P4 CPU1.P10 CPU1.P19 CPU1.P22 CPU1.P27 CPU1.P32 CPU1.P35 CPU1.P36 CPU1.P42 CPU1.R1 CPU1.T9 CPU1.T14 CPU1.T47 CPU1.U5 CPU1.U6 CPU1.U8 CPU1.U9 CPU1.U11 CPU1.U12 CPU1.U14 CPU1.U18 CPU1.U21 CPU1.U25 CPU1.U29 CPU1.U30 CPU1.U32 CPU1.U33 CPU1.U36 CPU1.U38 CPU1.U40 CPU1.U42 CPU1.U43 CPU1.U45 CPU1.U46 CPU1.U48 CPU1.U49 CPU1.U53 CPU1.V16 CPU1.V21 CPU1.V25 CPU1.V32 CPU1.V38 CPU1.V41 CPU1.V42 CPU1.V44 CPU1.W1 CPU1.Y4 CPU1.Y9 CPU1.Y10 CPU1.Y14 CPU1.Y16 CPU1.Y19 CPU1.Y21 CPU1.Y22 CPU1.Y24 CPU1.Y29 CPU1.Y38 CPU1.Y40 CPU1.Y45 CPU1.Y50 D4301.1 D4302.1 D4303.1 DB1.1 DB1.3 DB1.11 DB1.12 DCIN1.1 DCIN1.2 DCIN1.7 DCIN1.8 EC502.2 EC503.2 EC504.2 EC1001.2 EC1002.2 EC1003.2 EC1004.2 EC1005.2 EC1006.2 EC1007.2 EC1101.2 EC1102.2 EC1103.2 EC1104.2 EC1105.2 EC1106.2 EC1107.2 EC1108.2 EC1201.2 EC1202.2 EC1203.2 EC1204.2 EC1205.2 EC1206.2 EC1801.2 EC1802.2 EC1803.2 EC1808.2 EC1809.2 EC1810.2 EC1811.2 EC1812.2 EC1813.2 EC1814.2 EC2401.2 EC2402.2 EC2403.2 EC2501.2 EC2502.2 EC2503.2 EC2601.2 EC2602.2 EC2703.2 EC2704.2 EC2705.2 EC2706.2 EC2707.2 EC2708.2 EC2709.2 EC2710.2 EC2901.2 EC2902.2 EC2903.2 EC2904.2 EC3301.2 EC3302.2 EC3303.2 EC3304.2 EC3305.2 EC3306.2 EC3307.2 EC4001.2 EC4002.2 EC4003.2 EC4004.2 EC4005.2 EC4006.2 EC4301.2 EC4302.2 EC4303.2 EC4304.2 EC4305.1 EC4306.2 EC4307.2 EC4308.2 EC4309.2 EC4310.2 EC4311.2 EC4312.2 EC4313.2 EC4401.2 EC4402.2 EC4403.2 EC4701.2 EC4801.2 EC5501.2 EC5502.2 EC5503.2 EC5505.2 EC5506.2 EC5507.2 EC5510.2 EC5701.2 EC6403.2 EC6405.2 EC6427.2 EC6428.2 EC6501.2 EC6502.2 EC6503.2 EC6504.2 EC6505.2 EC6506.2 EU3501.3 EU3501.8 EU3505.2 G1801.1 H1.1 H2.1 H4.1 H9.1 HDMI1.2 HDMI1.5 HDMI1.8 HDMI1.11 HDMI1.17 HDMI1.20 HDMI1.21 HDMI1.22 HDMI1.23 HS1.1 HS2.1 HS3.1 HS4.1 IOBD1.12 IOBD1.13 IOBD1.27 IOBD1.28 IOBD1.29 IOBD1.32 IOBD1.45 IOBD1.46 KB1.30 KB1.31 KB1.32 LCD1.8 LCD1.11 LCD1.14 LCD1.17 LCD1.21 LCD1.28 LCD1.29 LCD1.32 LCD1.34 LCD1.35 LCD1.41 LCD1.42 LED1.4 LED1.5 LED1.6 LIDSW1.1 PC1009.2 PC1010.2 PC1011.2 PC1012.2 PC1014.2 PC1031.2 PC1040.2 PC1041.2 PC1042.2 PC1043.2 PC1044.2 PC1045.2 PC1046.2 PC1048.2 PC1051.2 PC1052.2 PC1053.2 PC1054.2 PC1055.2 PC1058.2 PC1059.2 PC1060.2 PC1061.2 PC1062.2 PC1063.2 PC1064.2 PC1065.2 PC1066.2 PC1067.2 PC1068.2 PC1069.2 PC1070.2 PC1071.2 PC1072.2 PC1073.2 PC1074.2 PC1075.2 PC1076.2 PC1077.2 PC1078.2 PC1079.2 PC1080.2 PC1118.2 PC1119.2 PC1120.2 PC1122.2 PC1123.2 PC1124.2 PC4302.2 PC4303.2 PC4304.2 PC4305.2 PC4306.2 PC4401.2 PC4406.2 PC4407.2 PC4408.2 PC4409.2 PC4415.2 PC4416.2 PC4417.2 PC4418.2 PC4419.2 PC4425.2 PC4426.2 PC4427.2 PC4431.2 PC4501.2 PC4502.2 PC4503.2 PC4504.2 PC4505.2 PC4507.2 PC4508.2 PC4509.2 PC4510.2 PC4511.2 PC4512.2 PC4513.2 PC4514.2 PC4515.2 PC4516.2 PC4517.2 PC4518.2 PC4519.2 PC4520.2 PC4522.2 PC4523.2 PC4524.2 PC4527.2 PC4528.2 PC4529.2 PC4530.2 PC4531.2 PC4534.2 PC4535.2 PC4538.2 PC4603.2 PC4604.2 PC4606.2 PC4608.2 PC4610.1 PC4611.2 PC4614.2 PC4615.2 PC4617.1 PC4618.2 PC4619.2 PC4620.2 PC4702.2 PC4705.2 PC4706.2 PC4707.2 PC4708.2 PC4710.2 PC4801.2 PC4803.2 PC4805.2 PC4806.1 PC4807.2 PC4808.2 PC4809.2 PC4811.2 PC4812.2 PC4814.1 PC4817.2 PC4819.2 PC4820.2 PC4821.2 PC4822.2 PC4823.2 PC4834.2 PC4839.2 PC5000.2 PC5001.2 PC5003.2 PC5004.2 PC5005.2 PC5007.2 PC5008.2 PC5009.2 PC5010.2 PC5011.2 PC5012.2 PC5013.2 PC5014.2 PC5015.2 PC5016.2 PC5018.2 PC5019.2 PC5101.2 PC5102.2 PC5103.2 PC5104.2 PC5105.2 PC5106.2 PC5107.2 PC5108.2 PC5110.2 PC5111.2 PC5113.2 PC5114.2 PC5115.2 PC5116.2 PC5118.2 PC5119.2 PC5120.2 PC5138.2 PC5219.2 PC5220.2 PC5221.2 PC5223.2 PC5224.2 PC5225.2 PC5301.2 PC5306.2 PC5326.2 PC5401.2 PC5402.2 PC5404.2 PC5407.2 PC5427.2 PD4301.A PD4302.A PD4303.1 PG4411.2 PQ4302.E PQ4304.2 PQ4309.S PQ4402.1 PQ4402.4 PQ4408.1 PQ4408.4 PQ4410.1 PQ4410.4 PQ4414.S PR4302.2 PR4310.2 PR4405.2 PR4432.2 PR4433.2 PR4436.2 PR4464.2 PR4467.2 PR4470.1 PR4474.2 PR4513.2 PR4516.2 PR4517.2 PR4518.2 PR4609.2 PR4615.2 PR4619.2 PR4638.2 PR4643.2 PR4644.2 PR4661.2 PR4684.2 PR4802.2 PR4812.2 PR4813.2 PR4819.2 PR4821.2 PR4822.2 PR4828.2 PR4833.2 PR5002.2 PR5003.2 PR5005.2 PR5010.2 PR5104.2 PR5106.1 PR5213.1 PR5401.2 PR5420.2 PT4701.2 PT4702.2 PT4801.2 PU4404.14 PU4405.5 PU4405.6 PU4405.7 PU4407.1 PU4407.2 PU4502.7 PU4502.8 PU4502.18 PU4502.21 PU4503.7 PU4503.8 PU4503.18 PU4503.21 PU4601.11 PU4601.29 PU4701.5 PU4701.6 PU4701.7 PU4801.5 PU4801.6 PU4801.7 PU4802.11 PU4802.29 PU5001.7 PU5001.8 PU5001.18 PU5001.21 PU5002.4 PU5002.8 PU5002.9 PU5101.7 PU5101.8 PU5101.18 PU5101.21 PU5102.4 PU5102.8 PU5102.11 PU5204.4 PU5204.8 PU5204.9 PU5301.2 PU5402.1 Q1801.1 Q1801.4 Q1810.1 Q1810.4 Q1812.S Q1813.1 Q1813.4 Q1814.1 Q1814.4 Q2401.C Q2402.S Q2403.S Q2502.S Q3301.S Q4001.1 Q4001.4 Q4014.1 Q4014.4 Q4015.S Q4016.1 Q4016.4 Q4017.S Q4020.S Q5506.S Q5701.1 Q5701.4 Q5707.S Q6507.1 Q6507.4 R504.2 R508.2 R809.2 R812.2 R813.1 R814.2 R815.2 R817.2 R819.2 R1204.2 R1206.2 R1208.2 R1209.2 R1210.2 R1211.2 R1503.2 R1504.2 R1508.2 R1513.2 R1515.2 R1519.2 R1522.2 R1524.2 R1526.2 R1536.2 R1601.1 R1611.2 R1617.2 R1636.1 R1637.1 R1639.1 R1641.1 R1823.2 R1828.2 R1849.1 R1852.1 R1859.1 R1861.2 R1873.2 R1901.1 R1903.1 R1906.1 R1907.1 R2415.2 R2419.2 R2428.1 R2438.2 R2442.2 R2443.1 R2468.2 R2505.2 R2530.1 R2613.2 R2706.2 R2712.2 R2717.2 R3304.1 R3311.2 R3605.2 R4005.2 R4008.1 R4011.1 R4301.1 R5502.2 R5505.1 R5506.1 R5507.1 R5508.1 R5703.1 R6338.2 R6504.2 R6515.1 R6903.1 RAM1.A9 RAM1.B1 RAM1.B3 RAM1.B9 RAM1.D1 RAM1.D8 RAM1.E1 RAM1.E2 RAM1.E8 RAM1.F9 RAM1.G1 RAM1.G8 RAM1.G9 RAM1.J2 RAM1.J8 RAM1.M1 RAM1.M9 RAM1.P1 RAM1.P9 RAM1.T1 RAM1.T9 RAM2.A9 RAM2.B1 RAM2.B3 RAM2.B9 RAM2.D1 RAM2.D8 RAM2.E1 RAM2.E2 RAM2.E8 RAM2.F9 RAM2.G1 RAM2.G8 RAM2.G9 RAM2.J2 RAM2.J8 RAM2.M1 RAM2.M9 RAM2.P1 RAM2.P9 RAM2.T1 RAM2.T9 RAM3.A9 RAM3.B1 RAM3.B3 RAM3.B9 RAM3.D1 RAM3.D8 RAM3.E1 RAM3.E2 RAM3.E8 RAM3.F9 RAM3.G1 RAM3.G8 RAM3.G9 RAM3.J2 RAM3.J8 RAM3.M1 RAM3.M9 RAM3.P1 RAM3.P9 RAM3.T1 RAM3.T9 RAM4.A9 RAM4.B1 RAM4.B3 RAM4.B9 RAM4.D1 RAM4.D8 RAM4.E1 RAM4.E2 RAM4.E8 RAM4.F9 RAM4.G1 RAM4.G8 RAM4.G9 RAM4.J2 RAM4.J8 RAM4.M1 RAM4.M9 RAM4.P1 RAM4.P9 RAM4.T1 RAM4.T9 RN1501.3(B) RN1501.4(B) RN1806.1(A) RN1806.2(A) RTC1.2 RTC1.3 RTC1.4 SD1.4 SD1.10 SD1.11 SPK1.5 SPK1.6 SPR1.1 SPR2.1 SPR3.1 SPR4.1 SPR5.1 SPR6.1 SSKT1.4 TPAD1.4 TPAD1.9 TPAD1.10 U2401.5 U2401.18 U2401.45 U2401.78 U2401.89 U2401.116 U2404.2 U2501.4 U2503.5 U2503.11 U2601.5 U2701.4 U2701.49 U2901.1 U3301.25 U3601.2 U4001.11 U4001.15 U4016.11 U4016.15 U5501.2 U6301.A6 U6301.C4 U6301.E7 U6301.G5 U6301.H10 U6301.J5 U6301.K8 U6301.N2 U6301.N5 U6301.P4 U6301.P6 U6901.5 U6901.6 U6901.7 U6901.8 USB1.4 USB1.7 USB1.10 USB1.11 USB1.12 USB1.13 WLAN1.1 WLAN1.7 WLAN1.18 WLAN1.33 WLAN1.39 WLAN1.45 WLAN1.51 WLAN1.57 WLAN1.63 WLAN1.69 WLAN1.75 X1601.2 X1601.4 X1802.2 X1802.3
VCC_AXG_SENSE: CPU1.AD24 PR4809.1 R1874.2
VCC_SENSE: CPU1.AG32 PR4658.2 R1851.2
VCC_VCORE1_SENSE: CPU1.AD29 PR4676.1 R1848.2
VSS5: CPU1.B52
VSS_AXG_SENSE: CPU1.AD22 PR4808.1 R1873.1
VSS_SENSE: CPU1.AJ32 PR4652.2 R1852.2
VSS_VCORE1_SENSE: CPU1.AF27 PR4678.1 R1849.2
VSS_VNN_SENSE: CPU1.AC27 PR5039.2 R1875.1
0D675V_PWR: PC5114.1 PG5117.1 PG5118.1 PU5102.3 PU5102.5
0D675V_S0_DISCHG: Q4014.3 R4047.2
0D675V_VREF_S0: C1208.1 C1214.1 C1215.1 C1216.1 C1217.1 C1219.1 C1220.1 EC1205.1 EC1206.1 PG5117.2 PG5118.2 R1217.1 R1218.1 R1219.1 R1220.1 R1221.1 R1222.1 R1223.1 R1224.1 R1225.1 R1226.1 R1227.1 R1228.1 R1229.1 R1230.1 R1231.1 R1232.1 R1233.1 R1234.1 R1237.1 R1240.1 R1241.1 R1242.1 R1244.1 R1245.1 R1246.1 R4047.1
1D5V_BRI_S0: R4021.2 R4022.1
1D5V_DIS_Q: Q4001.3 R4027.2
1D05V_PWR_BS: PR5001.1 PU5001.1
1D05V_PWR_BS_R: C5006.1 PR5001.2
1D05V_PWR_BYP: PC5007.1 PR5007.1 PU5001.15
1D05V_PWR_FB: PC5002.2 PR5005.1 PR5014.2 PU5001.14
1D05V_PWR_FBH: PR5006.2 PR5014.1 PR5039.1
1D05V_PWR_FBL: PC5002.1 PG5001.1 PR5006.1
1D05V_PWR_LDO: PC5009.1 PU5001.17
1D05V_PWR_PH: C5006.2 PL5001.1 PU5001.6 PU5001.19 PU5001.20
1D05V_PWRGD: PR5013.2 PR5066.2 PU5001.9
1D5V_S0: C1102.1 CPU1.AF4 CPU1.AH4 PC5306.1 PU5301.5 R2701.1 R2705.1 R4022.2 R4027.1
1D5V_S0_EN: PC5326.1 PR5315.2 PU5301.3
1D05V_S5: C1001.1 C1002.1 C1003.1 C1004.1 C1005.1 C1006.1 C1007.1 C1008.1 C1013.1 C1015.1 C1016.1 C1017.1 C1018.1 C1019.1 C1020.1 C1021.1 C1022.1 C1023.1 C1024.1 C1025.1 C1050.1 C1056.1 C1057.1 C1125.1 CPU1.AA18 CPU1.AA19 CPU1.AA21 CPU1.AA22 CPU1.AA24 CPU1.AA25 CPU1.AA32 CPU1.AA33 CPU1.AA35 CPU1.AA36 CPU1.AC18 CPU1.AC19 CPU1.AC21 CPU1.AC22 CPU1.AC24 CPU1.AC25 CPU1.AC32 CPU1.AD25 CPU1.AD27 CPU1.AM21 CPU1.AM22 CPU1.AM32 CPU1.AM33 CPU1.AN22 CPU1.AN32 CPU1.G10 CPU1.H10 CPU1.N18 CPU1.U19 CPU1.U22 CPU1.U24 CPU1.U27 CPU1.V18 CPU1.V19 CPU1.V22 CPU1.V24 CPU1.V27 CPU1.V29 CPU1.V33 CPU1.Y30 CPU1.Y32 CPU1.Y33 CPU1.Y35 PC1009.1 PC1010.1 PC1011.1 PC1012.1 PC1014.1 PC1051.1 PC1052.1 PC1053.1 PC1054.1 PC1055.1 PC4615.1 PC4823.1 PC5003.1 PC5005.1 PC5010.1 PC5011.1 PC5012.1 PC5013.1 PG5001.2 PL5001.2 PR4601.2 PR4602.2 PR4621.1 PR4665.2 PR4804.2 PR4805.2 PR4816.1 PR4843.2 R1824.2 R1875.2
1D05V_VNN_EN: PR5004.1 PR5201.1 Q4020.D R4016.2 R4017.2
1D05V_VNN_PG_G: C1801.1 Q1801.2 R1826.2 R1844.1 R1845.1
1D05V_VNN_PWRGD: EC1813.1 PR5009.1 PR5066.1 R1845.2
1D8V_S0: C2432.1 C2433.1 C4012.1 Q5703.G Q5705.G R4021.1 R5521.1 R5526.1 R6311.1 U2401.4 U4016.13 U4016.14
1D8V_S0_EN: C4046.1 RN4001.1(A) U4016.3
1D8V_S5: C1104.1 C1105.1 C1110.1 C1111.1 C1113.1 C1114.1 C1121.1 C1130.1 C2439.1 C2446.1 C4039.1 CPU1.AA29 CPU1.AD33 CPU1.AF33 CPU1.AK18 CPU1.AK19 CPU1.U16 CPU1.Y18 PG5209.2 PG5210.2 PR4635.1 PR4814.1 Q1606.2 Q1606.5 Q1811.G Q6301.G R803.1 R804.1 R808.1 R810.1 R818.1 R1506.1 R1514.1 R1517.1 R1520.1 R1523.1 R1525.1 R1527.1 R1529.1 R1531.1 R1532.1 R1535.1 R1537.1 R1808.2 R1813.2 R1825.1 R1839.1 R1842.1 R1850.2 R1860.1 R2421.1 R2436.1 R2486.1 R2512.1 R5401.2 R5517.1 R5522.1 R5705.1 R6325.2 R6329.2 R6330.2 R6331.2 R6332.2 R6333.2 R6334.2 R6335.2 R6336.2 R6337.2 R6514.1 RN803.3(B) RN803.4(B) RN1502.1(A) RN1502.2(A) RN1601.1(A) RN1601.2(A) RN1607.1(A) RN1607.2(A) RN1801.3(B) RN1801.4(B) RN1805.1(A) RN1805.2(A) RN1805.3(A) RN1805.4(A) RN1901.1(A) RN1901.2(A) RN1902.1(A) RN1902.2(A) U2404.1 U4016.1 U4016.2
1D8V_S5_PG: PR5218.2 PU5204.2 R4064.1
1D8V_SPI: C2501.1 C2502.1 R2512.2 RN2501.6(B) RN2501.7(B) RN2501.8(B) SSKT1.8 U2501.8
1D15V_S5: C1026.1 C1028.1 C1034.1 C1035.1 C1037.1 C1038.1 C1039.1 C1047.1 C1049.1 CPU1.AJ35 CPU1.AK21 CPU1.AK30 CPU1.AK33 CPU1.AK35 CPU1.AK36 CPU1.AM19 CPU1.AM29 PG5002.2 PG5003.2
1D24V_S5: C1106.1 C1107.1 C1108.1 C1109.1 C1116.1 C1117.1 C1128.1 C1129.1 C1131.1 C1134.1 C1137.1 C1138.1 C1147.1 C1148.1 C1149.1 C1150.1 CPU1.AC30 CPU1.AC36 CPU1.AD35 CPU1.AD38 CPU1.AF35 CPU1.H44 CPU1.M41 CPU1.P38 CPU1.P40 CPU1.P41 CPU1.T40 CPU1.U35 CPU1.V30 CPU1.V35 CPU1.V36 CPU1.Y25 CPU1.Y27 CPU1.Y36 PG5408.2 PG5409.2
1D24V_S5_PG: PU5402.7 R4065.1
1D35V_CPU_VDDQ_S3: C1101.1 C1112.1 C1143.1 C1144.1 C1203.1 C1204.1 C1205.1 C1206.1 C1207.1 C1209.1 C1210.1 C1211.1 C1212.1 C1221.1 C1222.1 C1223.1 CPU1.AM18 CPU1.AM25 CPU1.AM36 CPU1.AN18 CPU1.AN19 CPU1.AN27 CPU1.AN35 CPU1.AN36 CPU1.AU18 CPU1.AU36 CPU1.AV10 CPU1.AV16 CPU1.AV38 CPU1.AV44 CPU1.AY10 CPU1.AY44 CPU1.BE1 CPU1.BE3 CPU1.BE51 CPU1.BE53 CPU1.BG3 CPU1.BG51 CPU1.BH4 CPU1.BH5 CPU1.BH49 CPU1.BH50 CPU1.BJ2 CPU1.BJ3 CPU1.BJ5 CPU1.BJ49 CPU1.BJ51 CPU1.BJ52 EC1101.1 EC1102.1 EC1103.1 EC1104.1 EC1105.1 EC1106.1 EC1107.1 EC1108.1 EC1201.1 EC1202.1 EC1203.1 EC1204.1 PC1118.1 PC1119.1 PC1120.1 PC1122.1 PC1123.1 PC1124.1 PC5115.1 PC5118.1 PG5102.2 PG5104.2 PG5105.2 PG5108.2 PG5109.2 PU5102.1 PU5102.2 R1202.1 R1205.1 R4024.1 R4031.1 R4048.1 RAM1.A1 RAM1.A8 RAM1.B2 RAM1.C1 RAM1.C9 RAM1.D2 RAM1.D9 RAM1.E9 RAM1.F1 RAM1.G7 RAM1.H2 RAM1.H9 RAM1.K2 RAM1.K8 RAM1.N1 RAM1.N9 RAM1.R1 RAM1.R9 RAM2.A1 RAM2.A8 RAM2.B2 RAM2.C1 RAM2.C9 RAM2.D2 RAM2.D9 RAM2.E9 RAM2.F1 RAM2.G7 RAM2.H2 RAM2.H9 RAM2.K2 RAM2.K8 RAM2.N1 RAM2.N9 RAM2.R1 RAM2.R9 RAM3.A1 RAM3.A8 RAM3.B2 RAM3.C1 RAM3.C9 RAM3.D2 RAM3.D9 RAM3.E9 RAM3.F1 RAM3.G7 RAM3.H2 RAM3.H9 RAM3.K2 RAM3.K8 RAM3.N1 RAM3.N9 RAM3.R1 RAM3.R9 RAM4.A1 RAM4.A8 RAM4.B2 RAM4.C1 RAM4.C9 RAM4.D2 RAM4.D9 RAM4.E9 RAM4.F1 RAM4.G7 RAM4.H2 RAM4.H9 RAM4.K2 RAM4.K8 RAM4.N1 RAM4.N9 RAM4.R1 RAM4.R9
1D35V_PWR: PC5101.1 PC5102.1 PC5103.1 PC5104.1 PC5105.1 PC5112.1 PG5102.1 PG5104.1 PG5105.1 PG5108.1 PG5109.1 PL5101.2 PR5103.1
1D35V_S3_DISCHG: Q4014.6 R4048.2
1D35V_VTT_PWRGD: EC4005.1 PR5107.1 R4015.2
3D3V_AUX_KBC: D4301.2 D4302.2 D4303.2 PR4412.1 PR4415.1 PR4534.1 Q2404.D R2403.1 R2407.1 R2408.2 R2409.2 R2410.1 R2437.1 R2462.1 R2490.1 R2608.1 R2615.1 RN2402.1(A) RN2402.2(A)
3D3V_AUX_S5: C2442.2 PR4417.1 PR4419.1 PR4434.1 PR4435.1 PR4438.2 PR4532.2 Q2404.S Q2501.2 R1820.2 R1826.1 R1830.2 R2405.1 R2489.2 R2491.2 R2513.2 R2514.1 R2614.1 R4053.1 RN1803.4(B) RN4501.3(B) RN4501.4(B) U2401.75
3D3V_AUX_S5_MUX: R2532.1 U2503.10
3D3V_CAMERA_S0: C5514.1 EC5510.1 F5502.2 LCD1.40
3D3V_CARD: C3301.1 C3302.1 C3303.1 C3304.1 C3305.1 SD1.6 U3301.7
3D3V_CARD_S0: C3306.1 C3307.1 R3302.2 U3301.5 U3301.6 U3301.8
3D3V_GSEN2: C6901.1 C6902.1 R6901.2 R6902.1 R6905.1 U6901.9 U6901.10
3D3V_LCDVDD_S0: C5508.1 C5509.2 C5511.1 LCD1.37 LCD1.38 U5501.3
3D3V_PU5402: PC5402.1 PU5402.5 PU5402.9 R5401.1
3D3V_PWR: PC4509.1 PC4510.1 PC4511.1 PC4512.1 PC4513.1 PG4517.1 PG4527.1 PG4528.1 PG4529.1 PG4535.1 PG4539.1 PG4546.1 PL4501.2
3D3V_PWR_2: PG4542.1 PR4532.1
3D3V_S0: C2601.1 C2602.1 C2716.1 C2717.1 C4005.1 C5512.1 DB1.10 EC4004.1 F5502.1 IOBD1.35 PR5102.2 Q801.G Q1901.G Q2604.2 Q2604.5 R806.1 R1864.1 R1904.1 R2400.1 R2430.1 R2445.1 R2464.1 R2475.1 R2605.1 R2606.1 R2607.2 R2702.1 R2713.1 R2719.1 R2918.1 R3302.1 R3307.1 R3308.1 R5516.1 R5527.1 R6105.1 R6310.1 R6901.1 RN2403.1(A) RN2403.2(A) RN2601.1(A) RN2601.2(A) RN4001.4(B) RN6901.1(A) RN6901.2(A) U2601.1 U2701.1 U4001.8 U4001.9 U5501.4 U5501.5
3D3V_S0_CT: C4001.1 U4001.10
3D3V_S5: C2445.1 C2505.1 C4038.1 C4042.1 C6702.1 EC4002.1 EC4403.1 IOBD1.36 LIDSW1.2 PC5301.1 PD4303.2 PG4517.2 PG4527.2 PG4528.2 PG4529.2 PG4539.2 PG4546.2 PG5004.1 PG5005.1 PG5207.1 PG5208.1 PR4306.1 PR4472.1 PR4473.2 PR4649.1 PR5007.2 PR5008.1 PR5012.1 PR5013.1 PR5218.1 PU5301.1 R1620.1 R1621.1 R1843.2 R1856.2 R1858.2 R1902.1 R2420.1 R2426.1 R2434.1 R2471.1 R2532.2 R2711.2 R4014.1 R4020.1 R6106.1 R6501.1 R6511.1 R6701.2 RN801.3(B) RN801.4(B) RN1803.3(B) RN2401.1(A) RN2401.2(A) RN4001.3(B) RN5704.3(B) RN5704.4(B) U2404.6 U4001.6 U4001.7 U4016.6 U4016.7
3D3V_S5_PRIME: C1103.1 C1115.1 C1126.1 C1127.1 C1133.1 C4011.1 CPU1.B22 CPU1.C23 CPU1.D4 CPU1.E1 CPU1.E2 CPU1.E3 CPU1.G1 R4002.2 R6324.2 U4016.8 U4016.9
3D3V_S5_PRIME_EN: C4050.1 R4064.2 R4065.2 RN4001.2(A) U4016.5
3D3V_S5_PRIME_PG: C4002.1 R4004.2 U2401.29
3D3V_S5_PRIME_PG_1: R4002.1 R4004.1
3D3V_WLAN_S0: AFTP6101.1 C6102.1 C6103.1 C6104.1 R6105.2 R6106.2 WLAN1.2 WLAN1.4 WLAN1.72 WLAN1.74
12MHZ_IN: C3310.1 U3301.24
+DC_IN: AFTP4201.1 EC4308.1 EC4309.1 EC4310.1 EC4311.1 EC4312.1 EC4313.1 EL4301.2 EL4302.2 EL4303.2 EL4304.2 PC4301.1 PC4302.1 PD4301.K PQ4305.2 PR4309.1 PR4316.1 PU4301.1 PU4301.2 PU4301.3
+DC_IN_C: DCIN1.5 DCIN1.6 EC4304.1 EC4306.1 EL4301.1 EL4302.1 EL4303.1 EL4304.1
+RTC_PWR: R2501.2 RTC1.1
+VCHGR_R: PG4405.1 PR4454.1
AC_IN#: PC4401.1 PQ4408.5 PR4425.2 PR4433.1 PR4434.2 PU4404.5 R2487.1
AC_IN_KBC#: R2462.2 U2401.65
AC_PRESENT_CPU: CPU1.C13 R1813.1 R2495.2
AC_PRESENT_KBC: R2495.1 U2401.113
AD+_G_1: PQ4402.5 PQ4402.6 PR4401.1
AD+_G_2: PR4401.2 PR4403.2 PU4402.4
AD+_TO_SYS: PG4402.1 PR4402.1 PR4403.1 PU4402.1 PU4402.2 PU4402.3
AD_IA: C2428.2 C2438.2 PR4422.2 U2401.97
AD_IA_HW: PQ4407.5 U2401.105
AD_IA_HW2: PQ4407.2 U2401.9
AD_OFF_L: PQ4304.3 PQ4305.1
AD_OFF_R: PC4301.2 PQ4305.3 PR4309.2 PR4310.1 PU4301.4
ALERT#: R2605.2 U2601.6
ALL_SYS_PWRGD: R2439.2 U2401.10
ALS_INT#: IOBD1.19 LCD1.33
AMBER_LED_BAT: EC6405.1 Q6404.C R6407.2
AMP_MUTE#: R2708.1 R2712.1 R2719.2 U2401.30
AUD_AGND: AFTP2908.1 C2702.1 C2705.1 C2710.2 C2711.2 C2712.1 C2713.2 C2715.2 C2902.1 EC2703.1 EC2704.1 EC2705.1 EC2706.1 EC2707.1 EC2710.1 EC2905.2 EC2906.2 EC2907.2 EC2908.2 IOBD1.1 IOBD1.11 Q2901.S R2704.1 R2706.1 R2707.2 R2905.2 R2919.2 R2920.2 U2701.25 U2701.38 U2901.4
AUD_HP1_JACK_L: R2908.1 U2701.32
AUD_HP1_JACK_L1: EC2907.1 R2907.1 R2908.2 R2912.2 R2919.1 R2922.2
AUD_HP1_JACK_R: R2910.1 U2701.33
AUD_HP1_JACK_R1: EC2908.1 R2909.1 R2910.2 R2913.2 R2920.1 R2921.2
AUD_PC_BEEP: C2720.2 U2701.12
AUD_PC_BEEP_C: C2720.1 D2701.3 R2717.1
AUD_PORTA_L_R_B: AFTP2906.1 IOBD1.10 R2907.2
AUD_PORTA_R_R_B: AFTP2907.1 IOBD1.9 R2909.2
AUD_SENSE: AFTP2909.1 Q2901.D R2709.2 R2914.2
AUD_SENSE_A: R2702.2 R2709.1 U2701.13
AUD_SPK_L+: EC2902.1 R2902.1 U2701.42
AUD_SPK_L+_C: AFTP2902.1 R2902.2 SPK1.3
AUD_SPK_L-: EC2901.1 R2901.1 U2701.43
AUD_SPK_L-_C: AFTP2901.1 R2901.2 SPK1.4
AUD_SPK_R+: EC2904.1 R2904.1 U2701.45
AUD_SPK_R+_C: AFTP2904.1 R2904.2 SPK1.1
AUD_SPK_R-: EC2903.1 R2903.1 U2701.44
AUD_SPK_R-_C: AFTP2903.1 R2903.2 SPK1.2
AUD_VREF: C2705.2 U2701.28
BAT_AMBER: EC6427.1 LED1.1 R6407.1
BAT_IN#: D4302.3 EC4305.2 PC4433.1 PR4472.2 RN2402.3(B) RN4301.4(A) U2401.80
BAT_SCL: D4301.3 EC4301.1 PG4407.2 PR4415.2 RN4301.2(A) U2401.70
BAT_SDA: D4303.3 EC4302.1 PG4408.2 PR4412.2 RN4301.3(A) U2401.69
BAT_WHITE: EC6428.1 LED1.2 R6408.1
BATT_WHITE_LED#: R6409.2 U2401.118
BATT_WHITE_LED_R#: Q6403.B R6409.1
BKLT_CTRL: D5502.3 R5505.2 R5524.1 RN5501.7(B)
BLON_OUT: RN5501.6(B) U2401.27
BLON_OUT_C: LCD1.25 R5506.2 RN5501.3(A)
BLUETOOTH_EN: AFTP6110.1 R2464.2 U2401.83 WLAN1.54
BOOST_MODE#: PR4418.1 PR4435.2
BOOST_MON_1: PC4427.1 PR4446.1
BT+_R: PG4404.2 PG4409.2 PL4401.2 PR4416.1
BVCCRTC_EXTPAD: C1810.2 CPU1.F16
CAMERA_DET#: LCD1.27 TP5501.1
CAP_LED: AFTP6233.1 EC6506.1 KB1.27 R6503.2
CAP_LED#: R6502.1 U2401.109
CAP_LED_Q: Q6501.C R6503.1
CAP_LED_R#: Q6501.B R6502.2
CARD_AV18: C3308.2 U3301.1
CARD_RREF: R3304.2 U3301.2
CBN: C2703.1 U2701.35
CBP: C2703.2 U2701.37
CFG0: CPU1.AM40 TP1613.1
CFG1: CPU1.AM41 TP1614.1
CFG2: CPU1.AM44 TP1615.1
CFG3: CPU1.AM45 TP1616.1
CFG4: CPU1.AM47 TP1617.1
CFG5: CPU1.AK48 TP1618.1
CFG6: CPU1.AM48 TP1619.1
CFG7: CPU1.AK41 TP1620.1
CFG8: CPU1.AK42 TP1621.1
CHG_AGND: PC4403.2 PC4404.2 PC4410.2 PC4412.2 PC4420.2 PC4422.2 PC4423.2 PG4411.1 PQ4407.1 PQ4407.4 PR4413.2 PR4423.2 PR4424.2 PR4431.2 PU4404.21
CHG_AMBER_LED#: R6406.2 U2401.16
CHG_AMBER_LED_R#: Q6404.B R6406.1
COMBO-GPI: TP2702.1 U2701.48
COREPWROK: CPU1.G16 EC1808.1 Q4016.2 R4008.2 R4029.2
CPU_VSS2: CPU1.A6 TP902.1
CPU_VSS16: CPU1.BH53 TP901.1
CPVEE: C2704.2 U2701.34
CPVREF: R2711.1 U2701.20
D_BAT_AMBER: TP2408.1 U2401.62
D_BAT_WHITE: TP2409.1 U2401.81
DBC_EN: Q801.S R806.2 R5501.2
DBC_EN_C: CPU1.F2 Q801.D RN801.2(A)
DBC_EN_R: LCD1.22 R5501.1
DC_IN_D: PQ4402.3 PR4404.2
DCBATOUT_R: PG4404.1 PR4448.1
DDI0_PLLOBS_N: CPU1.G38 R802.1
DDI0_PLLOBS_P: CPU1.F38 R802.2
DDI1_PLLOBS_N: CPU1.F49 R801.1
DDI1_PLLOBS_P: CPU1.F47 R801.2
DDR3_DRAM_PWROK: CPU1.AV28 EC503.1 R4015.1 R4019.1 R4031.2
DDR3_DRAM_PWROK_D: Q4017.D R4019.2
DDR3_VCCA_PWRGD: CPU1.AV26 EC504.1 Q4016.3 R4024.2
DDR3_VCCA_PWRGD_G: Q4016.5 Q4016.6 R4020.2
DDR_VREF_S3: PC5116.1 PU5102.6
DMIC_CLK: C2723.2 EC5506.1 R2716.1 RN5502.3(B)
DMIC_CLK_C: LCD1.18 RN5502.2(A)
DMIC_CLK_R: R2716.2 U2701.3
DMIC_DATA: EC5505.1 R2714.1 RN5502.4(B)
DMIC_DATA_C: LCD1.19 RN5502.1(A)
DMIC_DATA_R: R2714.2 U2701.2
DP_HPD0_C: LCD1.24 R5507.2 R5518.1
DP_HPD0_G: Q5506.G R5518.2
DRAM_RCOMP_1: CPU1.BA26 R508.1
DRAM_SEL0: CPU1.M12 R808.2 R809.1
DRAM_SEL1: CPU1.M10 R810.2 R812.1
DRAM_SEL2: CPU1.K7 R818.2 R819.1
E51_RX1: TP6102.1 WLAN1.46
E51_RX2: TP6101.1 WLAN1.58
E51_TX1: R6107.2 WLAN1.44
E51_TX2: R6108.2 WLAN1.38
E51_TXD: R6107.1 R6108.1 U2401.111
EAPD#: R2708.2 U2701.47
EC_AGND: C2416.2 C2436.2 C2438.1 R2415.1 U2401.103
EC_AVCC: C2416.1 C2436.1 R2409.1 U2401.102
EC_BRIGHTNESS: D5502.2 U2401.106
EC_VCC1V8: R2486.2 U2401.88
EC_VTT: C2447.1 R2430.2 R2443.2 U2401.12
ECRST#: C2444.1 Q2401.E R2404.2 RN2402.4(B) U2401.85
ECSMI#_KBC: R2461.1 U2401.119
EDM_SOC: CPU1.M13 TP1803.1
EDP_AUX_CON_N: C5505.1 LCD1.13
EDP_AUX_CON_P: C5501.1 LCD1.12
EDP_AUX_CPU_N: C5505.2 CPU1.K42
EDP_AUX_CPU_P: C5501.2 CPU1.M42
EDP_HPD_CPU: CPU1.R51 Q5506.D R5517.2
EDP_TX_CON_N0: C5507.1 LCD1.9
EDP_TX_CON_N1: C5513.1 LCD1.6
EDP_TX_CON_P0: C5506.1 LCD1.10
EDP_TX_CON_P1: C5510.1 LCD1.7
EDP_TX_CPU_N0: C5507.2 CPU1.H51
EDP_TX_CPU_N1: C5513.2 CPU1.K52
EDP_TX_CPU_P0: C5506.2 CPU1.J51
EDP_TX_CPU_P1: C5510.2 CPU1.K51
EMMC_CLK: EC1803.1 R807.2 R6312.1
EMMC_CLK_L: CPU1.M7 R807.1
EMMC_CLK_R: R6312.2 U6301.M6
EMMC_CMD: CPU1.P6 R6313.1 R6329.1
EMMC_CMD_R: R6313.2 U6301.M5
EMMC_DATA_0: CPU1.M6 R6315.2 R6330.1
EMMC_DATA_0_R: R6315.1 U6301.A3
EMMC_DATA_1: CPU1.M4 R6316.2 R6331.1
EMMC_DATA_1_R: R6316.1 U6301.A4
EMMC_DATA_2: CPU1.P9 R6317.2 R6332.1
EMMC_DATA_2_R: R6317.1 U6301.A5
EMMC_DATA_3: CPU1.P7 R6318.2 R6333.1
EMMC_DATA_3_R: R6318.1 U6301.B2
EMMC_DATA_4: CPU1.T6 R6319.2 R6334.1
EMMC_DATA_4_R: R6319.1 U6301.B3
EMMC_DATA_5: CPU1.T7 R6320.2 R6335.1
EMMC_DATA_5_R: R6320.1 U6301.B4
EMMC_DATA_6: CPU1.T10 R6321.2 R6336.1
EMMC_DATA_6_R: R6321.1 U6301.B5
EMMC_DATA_7: CPU1.T12 R6322.2 R6337.1
EMMC_DATA_7_R: R6322.1 U6301.B6
EMMC_E9: TP6301.1 U6301.E9
EMMC_E10: TP6302.1 U6301.E10
EMMC_F10: TP6303.1 U6301.F10
EMMC_K10: TP6304.1 U6301.K10
EMMC_RCLK: CPU1.T13 R6314.1
EMMC_RCLK_R: R6314.2 R6338.1 U6301.H5
EMMC_RESET#: Q6301.S R6309.1 R6326.1 R6327.1
EMMC_RESET#_R: R6309.2 U6301.K5
EMMC_VCC: C6302.1 C6305.1 R6310.2 R6324.1 U6301.E6 U6301.F5 U6301.J10 U6301.K9
EMMC_VCCQ: C6303.1 C6304.1 R6311.2 R6325.1 R6326.2 U6301.C6 U6301.M4 U6301.N4 U6301.P3 U6301.P5
EMMC_VDDI: C6301.1 U6301.C2
FFS_INT2_CPU: CPU1.H3 RN801.1(A)
GFX_CORE: CPU1.AD16 CPU1.AD18 CPU1.AD19 CPU1.AF16 CPU1.AF18 CPU1.AF19 CPU1.AF21 CPU1.AF22 CPU1.AG16 CPU1.AG18 CPU1.AG19 CPU1.AG21 CPU1.AG22 CPU1.AG24 CPU1.AJ19 CPU1.AJ21 CPU1.AJ22 CPU1.AJ24 CPU1.AK24 EC1005.1 EC1006.1 EC1007.1 PC1031.1 PC1043.1 PC1044.1 PC1045.1 PC1046.1 PC1062.1 PC1063.1 PC1064.1 PC1065.1 PC1070.1 PC1071.1 PC1072.1 PC1073.1 PC1074.1 PC1075.1 PC1076.1 PC1077.1 PC1078.1 PC1079.1 PC1080.1 PC4820.1 PC4821.1 PC4822.1 PG4801.2 PL4801.2 PT4801.1 R1874.1
GFX_PWRGD: PC4614.1 PC4809.1 PR4638.1 PU4601.1 PU4802.6 RN5704.1(A)
GP_CAMERASB00: CPU1.AB41 TP807.1
GP_CAMERASB01: CPU1.AB45 TP808.1
GP_CAMERASB02: CPU1.AB44 TP809.1
GP_CAMERASB03: CPU1.AC53 TP810.1
GP_CAMERASB04: CPU1.AB51 TP811.1
GP_CAMERASB05: CPU1.AB52 TP812.1
GP_CAMERASB06: CPU1.AA51 TP813.1
GP_CAMERASB07: CPU1.AB40 TP814.1
GP_CAMERASB08: CPU1.Y44 R1529.2 RN1501.1(A)
GP_CAMERASB09: CPU1.Y42 R1535.2 RN1501.2(A)
GP_CAMERASB11: CPU1.V40 R1536.1 R1537.2
GPIO_ALERT: CPU1.Y3 TP1612.1
GPIO_RCOMP18: CPU1.AH40 R1639.2
GPIO_SUS0: CPU1.AD51 RN1502.4(B)
GPIO_SUS1: CPU1.AD52 RN1502.3(B)
GPIO_SUS2: CPU1.AH50 R1508.1 R1517.2
GPIO_SUS3: CPU1.AH48 R1504.1 R1520.2
GPIO_SUS4: CPU1.AH51 R1503.1 R1532.2
GSEN2_INT1: IOBD1.17 U6901.12
GSEN2_INT2: IOBD1.16 U6901.11
GSENSOR_CS: R6905.2 U6901.2
GSENSOR_SDO: R6902.2 R6903.2 U6901.3
H_A20GATE: R2445.2 U2401.121
H_PROCHOT#: PR4426.2 PR4465.1 PR4466.2 PR4640.2 PR4807.2 Q2402.D R1809.1
H_RCIN#: R2400.2 U2401.122
HALL_KB_DIS#: IOBD1.24 R2434.2 U2401.112
HDA_BITCLK_CODEC: EC2709.1 R1927.1 U2701.6
HDA_BITCLK_CPU: CPU1.AD9 R1927.2
HDA_CODEC_RST#_CTRL: C2901.1 R2918.2 R2923.1 U2901.2
HDA_RST#_CODEC: R1928.1 R2923.2 U2701.11
HDA_RST#_CPU: C1910.1 CPU1.AF13 R1928.2
HDA_SDIN0_CODEC: R2718.2 U2701.8
HDA_SDIN0_CPU: CPU1.AD7 R2718.1
HDA_SDOUT_CODEC: EC2708.1 R1929.1 U2701.5
HDA_SDOUT_CPU: CPU1.AF14 R1929.2
HDA_SPKR: CPU1.H4 RN2701.2(A)
HDA_SPKR_R: D2701.1 RN2701.3(B)
HDA_SYNC_CODEC: R1926.1 U2701.10
HDA_SYNC_CPU: CPU1.AF12 R1926.2
HDD_FALL_INT_C: CPU1.J1 TP806.1
HDMI_CLK_CON: HDMI1.15 Q5703.D RN5701.2(A)
HDMI_CLK_CPU: CPU1.Y51 Q5703.S RN803.1(A)
HDMI_DATA_CON: HDMI1.16 Q5705.D RN5701.1(A)
HDMI_DATA_CON_N0: C5703.2 HDMI1.9 R5714.1 RN5703.2(A)
HDMI_DATA_CON_N1: C5705.2 HDMI1.6 R5715.1 RN5702.4(A)
HDMI_DATA_CON_N2: C5707.2 HDMI1.3 R5716.1 RN5702.2(A)
HDMI_DATA_CON_N3: C5701.2 HDMI1.12 R5717.1 RN5703.4(A)
HDMI_DATA_CON_P0: C5704.2 HDMI1.7 R5714.2 RN5703.1(A)
HDMI_DATA_CON_P1: C5706.2 HDMI1.4 R5715.2 RN5702.3(A)
HDMI_DATA_CON_P2: C5708.2 HDMI1.1 R5716.2 RN5702.1(A)
HDMI_DATA_CON_P3: C5702.2 HDMI1.10 R5717.2 RN5703.3(A)
HDMI_DATA_CPU: CPU1.Y52 Q5705.S RN803.2(A)
HDMI_DATA_CPU_N0: C5703.1 CPU1.F52
HDMI_DATA_CPU_N1: C5705.1 CPU1.H50
HDMI_DATA_CPU_N2: C5707.1 CPU1.C51
HDMI_DATA_CPU_N3: C5701.1 CPU1.G52
HDMI_DATA_CPU_P0: C5704.1 CPU1.F53
HDMI_DATA_CPU_P1: C5706.1 CPU1.H49
HDMI_DATA_CPU_P2: C5708.1 CPU1.D50
HDMI_DATA_CPU_P3: C5702.1 CPU1.G53
HDMI_HPD_G: Q5701.5 Q5707.G R5702.2
HDMI_IN#: Q5707.D RN5704.2(A) U2401.124
HDMI_PCH_DET#: CPU1.W51 Q5701.3 R5705.2
HDMI_PLL_GND: Q5701.6 RN5702.5(B) RN5702.6(B) RN5702.7(B) RN5702.8(B) RN5703.5(B) RN5703.6(B) RN5703.7(B) RN5703.8(B)
HPD_HDMI_CON: HDMI1.19 R5702.1 R5703.2 TP5401.1
ICLKICOMP: CPU1.P20 R1601.2
ICLKRCOMP: CPU1.N20 R1636.2
IMVP_PWRGD: EC2401.1 PC4618.1 PR4649.2 PU4601.6 R2439.1
INT_SERIRQ: C2401.1 R2420.2 R2435.1 U2401.125 U2404.4
INT_SERIRQ_OE: R2419.1 R2421.2 U2404.5
INT_TP#: CPU1.J3 Q6502.D R6510.2 R6511.2
INT_TP#_CONN: Q6502.S R6510.1 R6512.2 TPAD1.5
JACK_PLUG: C2902.2 IOBD1.2 Q2901.G R2905.1 R2914.1
JDREF: R2707.1 U2701.15
KB_LOOP: KB1.1 R6515.2
KBC_BEEP: RN2701.1(A) U2401.32
KBC_BEEP_R: D2701.2 RN2701.4(B)
KBC_ON#_GATE: C2442.1 Q2403.G Q2404.G R2492.2
KBC_ON#_GATE_L: R2491.1 R2492.1 R2493.2
KBC_PECI: TP2407.1 U2401.13
KBC_PWRBTN#: IOBD1.25 R2488.1
KBC_VBKUP: R2425.1 U2401.114
KBC_VCC: C2414.1 C2429.1 C2430.1 C2431.1 C2440.1 C2441.1 R2408.1 U2401.19 U2401.46 U2401.76 U2401.115
KBC_VCORF: C2443.1 U2401.44
KCOL0: AFTP6217.1 KB1.18 U2401.53
KCOL1: AFTP6215.1 KB1.16 U2401.52
KCOL2: AFTP6216.1 KB1.17 U2401.51
KCOL3: AFTP6214.1 KB1.15 U2401.50
KCOL4: AFTP6210.1 KB1.11 U2401.49
KCOL5: AFTP6209.1 KB1.10 U2401.48
KCOL6: AFTP6212.1 KB1.13 U2401.47
KCOL7: AFTP6211.1 KB1.12 U2401.43
KCOL8: AFTP6213.1 KB1.14 U2401.42
KCOL9: AFTP6223.1 KB1.24 U2401.41
KCOL10: AFTP6225.1 KB1.26 U2401.40
KCOL11: AFTP6224.1 KB1.25 U2401.39
KCOL12: AFTP6218.1 KB1.19 U2401.38
KCOL13: AFTP6221.1 KB1.22 U2401.37
KCOL14: AFTP6222.1 KB1.23 U2401.36
KCOL15: AFTP6220.1 KB1.21 U2401.35
KCOL16: AFTP6227.1 KB1.20 U2401.34
KROW0: AFTP6208.1 KB1.9 U2401.54
KROW1: AFTP6206.1 KB1.7 U2401.55
KROW2: AFTP6204.1 KB1.5 U2401.56
KROW3: AFTP6207.1 KB1.8 U2401.57
KROW4: AFTP6203.1 KB1.4 U2401.58
KROW5: AFTP6205.1 KB1.6 U2401.59
KROW6: AFTP6202.1 KB1.3 U2401.60
KROW7: AFTP6201.1 KB1.2 U2401.61
L_BKLT_CTRL: D5502.1 Q5503.C R5524.2 R5527.2
L_BKLT_CTRL_B: Q5503.B R5526.2
L_BKLT_CTRL_CPU: CPU1.P52 Q5503.E R804.2
L_BKLT_EN: R2424.1 U2401.22
L_BKLT_EN_CPU: CPU1.P51 R803.2 R813.2 R2424.2
LCD_BRIGHTNESS: EC5507.1 LCD1.26 RN5501.2(A)
LCD_TST: R2413.1 RN5501.5(B)
LCD_TST_C: LCD1.23 RN5501.4(A)
LCD_TST_EN: D5501.2 R5503.1 U2401.28
LCD_TST_KBC: R2413.2 U2401.123
LDO1_CAP: C2702.2 R2704.2 U2701.27
LDO2_CAP: C2712.2 U2701.39
LDO3_CAP: C2718.1 U2701.7
LID_CLOSE#: C6701.1 LIDSW1.3 R6701.1 U2401.107
LINE1-L_C: C2907.2 R2922.1
LINE1-L_R: C2908.2 R2921.1
LINE1_L: C2907.1 U2701.22
LINE1_R: C2908.1 U2701.21
LINE1_VREFO_L: R2912.1 U2701.31
LINE1_VREFO_R: R2913.1 U2701.30
LPC_AD_CPU_P0: CPU1.M3 RN1802.8(B)
LPC_AD_CPU_P1: CPU1.M2 RN1802.7(B)
LPC_AD_CPU_P2: CPU1.N3 RN1802.6(B)
LPC_AD_CPU_P3: CPU1.N1 RN1802.5(B)
LPC_AD_CPU_R_P0: DB1.9 RN1802.1(A) U2401.126
LPC_AD_CPU_R_P1: DB1.8 RN1802.2(A) U2401.127
LPC_AD_CPU_R_P2: DB1.7 RN1802.3(A) U2401.128
LPC_AD_CPU_R_P3: DB1.6 RN1802.4(A) U2401.1
LPC_CLK_CPU_P0: CPU1.P2 R1803.2
LPC_CLK_CPU_P1: CPU1.R3 R1802.2
LPC_CLK_KBC: EC1802.1 R1802.1 U2401.2
LPC_CLK_LPC: DB1.2 EC1801.1 R1803.1
LPC_CLKRUN#_CPU: CPU1.T3 R2475.2 U2401.8
LPC_FRAME#_CPU: CPU1.P3 R1807.2
LPC_FRAME#_CPU_R: DB1.5 R1807.1 U2401.3
LPC_SERIRQ_CPU: CPU1.T2 R2435.2 R2436.2 U2404.3
LVDS_VDD_EN: D5501.1 Q5501.C R5516.2
LVDS_VDD_EN_B: Q5501.B R5521.2
LVDS_VDD_EN_CPU: CPU1.R53 Q5501.E R2440.2 R5522.2
LVDS_VDD_EN_KBC: R2440.1 U2401.20
LVDS_VDD_EN_R: D5501.3 R5503.2 R5508.2 U5501.1
M_A_A0: CPU1.BB47 R1217.2 RAM1.N3 RAM2.N3 RAM3.N3 RAM4.N3
M_A_A1: CPU1.BC42 R1218.2 RAM1.P7 RAM2.P7 RAM3.P7 RAM4.P7
M_A_A2: CPU1.BJ48 R1219.2 RAM1.P3 RAM2.P3 RAM3.P3 RAM4.P3
M_A_A3: CPU1.BH47 R1220.2 RAM1.N2 RAM2.N2 RAM3.N2 RAM4.N2
M_A_A4: CPU1.BD42 R1221.2 RAM1.P8 RAM2.P8 RAM3.P8 RAM4.P8
M_A_A5: CPU1.BH48 R1222.2 RAM1.P2 RAM2.P2 RAM3.P2 RAM4.P2
M_A_A6: CPU1.BB46 R1223.2 RAM1.R8 RAM2.R8 RAM3.R8 RAM4.R8
M_A_A7: CPU1.BE46 R1224.2 RAM1.R2 RAM2.R2 RAM3.R2 RAM4.R2
M_A_A8: CPU1.BD44 R1225.2 RAM1.T8 RAM2.T8 RAM3.T8 RAM4.T8
M_A_A9: CPU1.BE52 R1226.2 RAM1.R3 RAM2.R3 RAM3.R3 RAM4.R3
M_A_A10: CPU1.BJ45 R1227.2 RAM1.L7 RAM2.L7 RAM3.L7 RAM4.L7
M_A_A11: CPU1.BB49 R1228.2 RAM1.R7 RAM2.R7 RAM3.R7 RAM4.R7
M_A_A12: CPU1.BF48 R1229.2 RAM1.N7 RAM2.N7 RAM3.N7 RAM4.N7
M_A_A13: CPU1.BF44 R1230.2 RAM1.T3 RAM2.T3 RAM3.T3 RAM4.T3
M_A_A14: CPU1.BD47 R1231.2 RAM1.T7 RAM2.T7 RAM3.T7 RAM4.T7
M_A_A15: CPU1.BD49 R1232.2 RAM1.M7 RAM2.M7 RAM3.M7 RAM4.M7
M_A_BS0: CPU1.BH46 R1242.2 RAM1.M2 RAM2.M2 RAM3.M2 RAM4.M2
M_A_BS1: CPU1.AY40 R1244.2 RAM1.N8 RAM2.N8 RAM3.N8 RAM4.N8
M_A_BS2: CPU1.BF52 R1245.2 RAM1.M3 RAM2.M3 RAM3.M3 RAM4.M3
M_A_CAS#: CPU1.BG45 R1240.2 RAM1.K3 RAM2.K3 RAM3.K3 RAM4.K3
M_A_CKE0: CPU1.BB44 R1233.2 RAM1.K9 RAM2.K9 RAM3.K9 RAM4.K9
M_A_CLK0: C1202.1 CPU1.BD40 R1235.2 RAM1.J7 RAM2.J7 RAM3.J7 RAM4.J7
M_A_CLK0_L: C1208.2 R1235.1 R1236.1
M_A_CLK#0: C1202.2 CPU1.BF40 R1236.2 RAM1.K7 RAM2.K7 RAM3.K7 RAM4.K7
M_A_CS#0: CPU1.AY38 R1234.2 RAM1.L2 RAM2.L2 RAM3.L2 RAM4.L2
M_A_DIM0_ODT0: CPU1.AV36 R1246.2 RAM1.K1 RAM2.K1 RAM3.K1 RAM4.K1
M_A_DM0: CPU1.AP52 RAM3.D3
M_A_DM1: CPU1.AT48 RAM1.E7
M_A_DM2: CPU1.AP44 RAM3.E7
M_A_DM3: CPU1.BA53 RAM1.D3
M_A_DM4: CPU1.BG41 RAM2.D3
M_A_DM5: CPU1.AY36 RAM4.E7
M_A_DM6: CPU1.BD32 RAM2.E7
M_A_DM7: CPU1.BH30 RAM4.D3
M_A_DQ0: CPU1.AK51 RAM3.B8
M_A_DQ1: CPU1.AL51 RAM3.A7
M_A_DQ2: CPU1.AT52 RAM3.C3
M_A_DQ3: CPU1.AR51 RAM3.A3
M_A_DQ4: CPU1.AL53 RAM3.D7
M_A_DQ5: CPU1.AK52 RAM3.C8
M_A_DQ6: CPU1.AR53 RAM3.A2
M_A_DQ7: CPU1.AP51 RAM3.C2
M_A_DQ8: CPU1.AP48 RAM1.F8
M_A_DQ9: CPU1.AT47 RAM1.H7
M_A_DQ10: CPU1.AY48 RAM1.F2
M_A_DQ11: CPU1.AV50 RAM1.E3
M_A_DQ12: CPU1.AP47 RAM1.F7
M_A_DQ13: CPU1.AT50 RAM1.H8
M_A_DQ14: CPU1.AY50 RAM1.G2
M_A_DQ15: CPU1.AV45 RAM1.H3
M_A_DQ16: CPU1.AT40 RAM3.F7
M_A_DQ17: CPU1.AP42 RAM3.H8
M_A_DQ18: CPU1.AT38 RAM3.E3
M_A_DQ19: CPU1.AP40 RAM3.F8
M_A_DQ20: CPU1.AT44 RAM3.H3
M_A_DQ21: CPU1.AV41 RAM3.G2
M_A_DQ22: CPU1.AP41 RAM3.H7
M_A_DQ23: CPU1.AV42 RAM3.F2
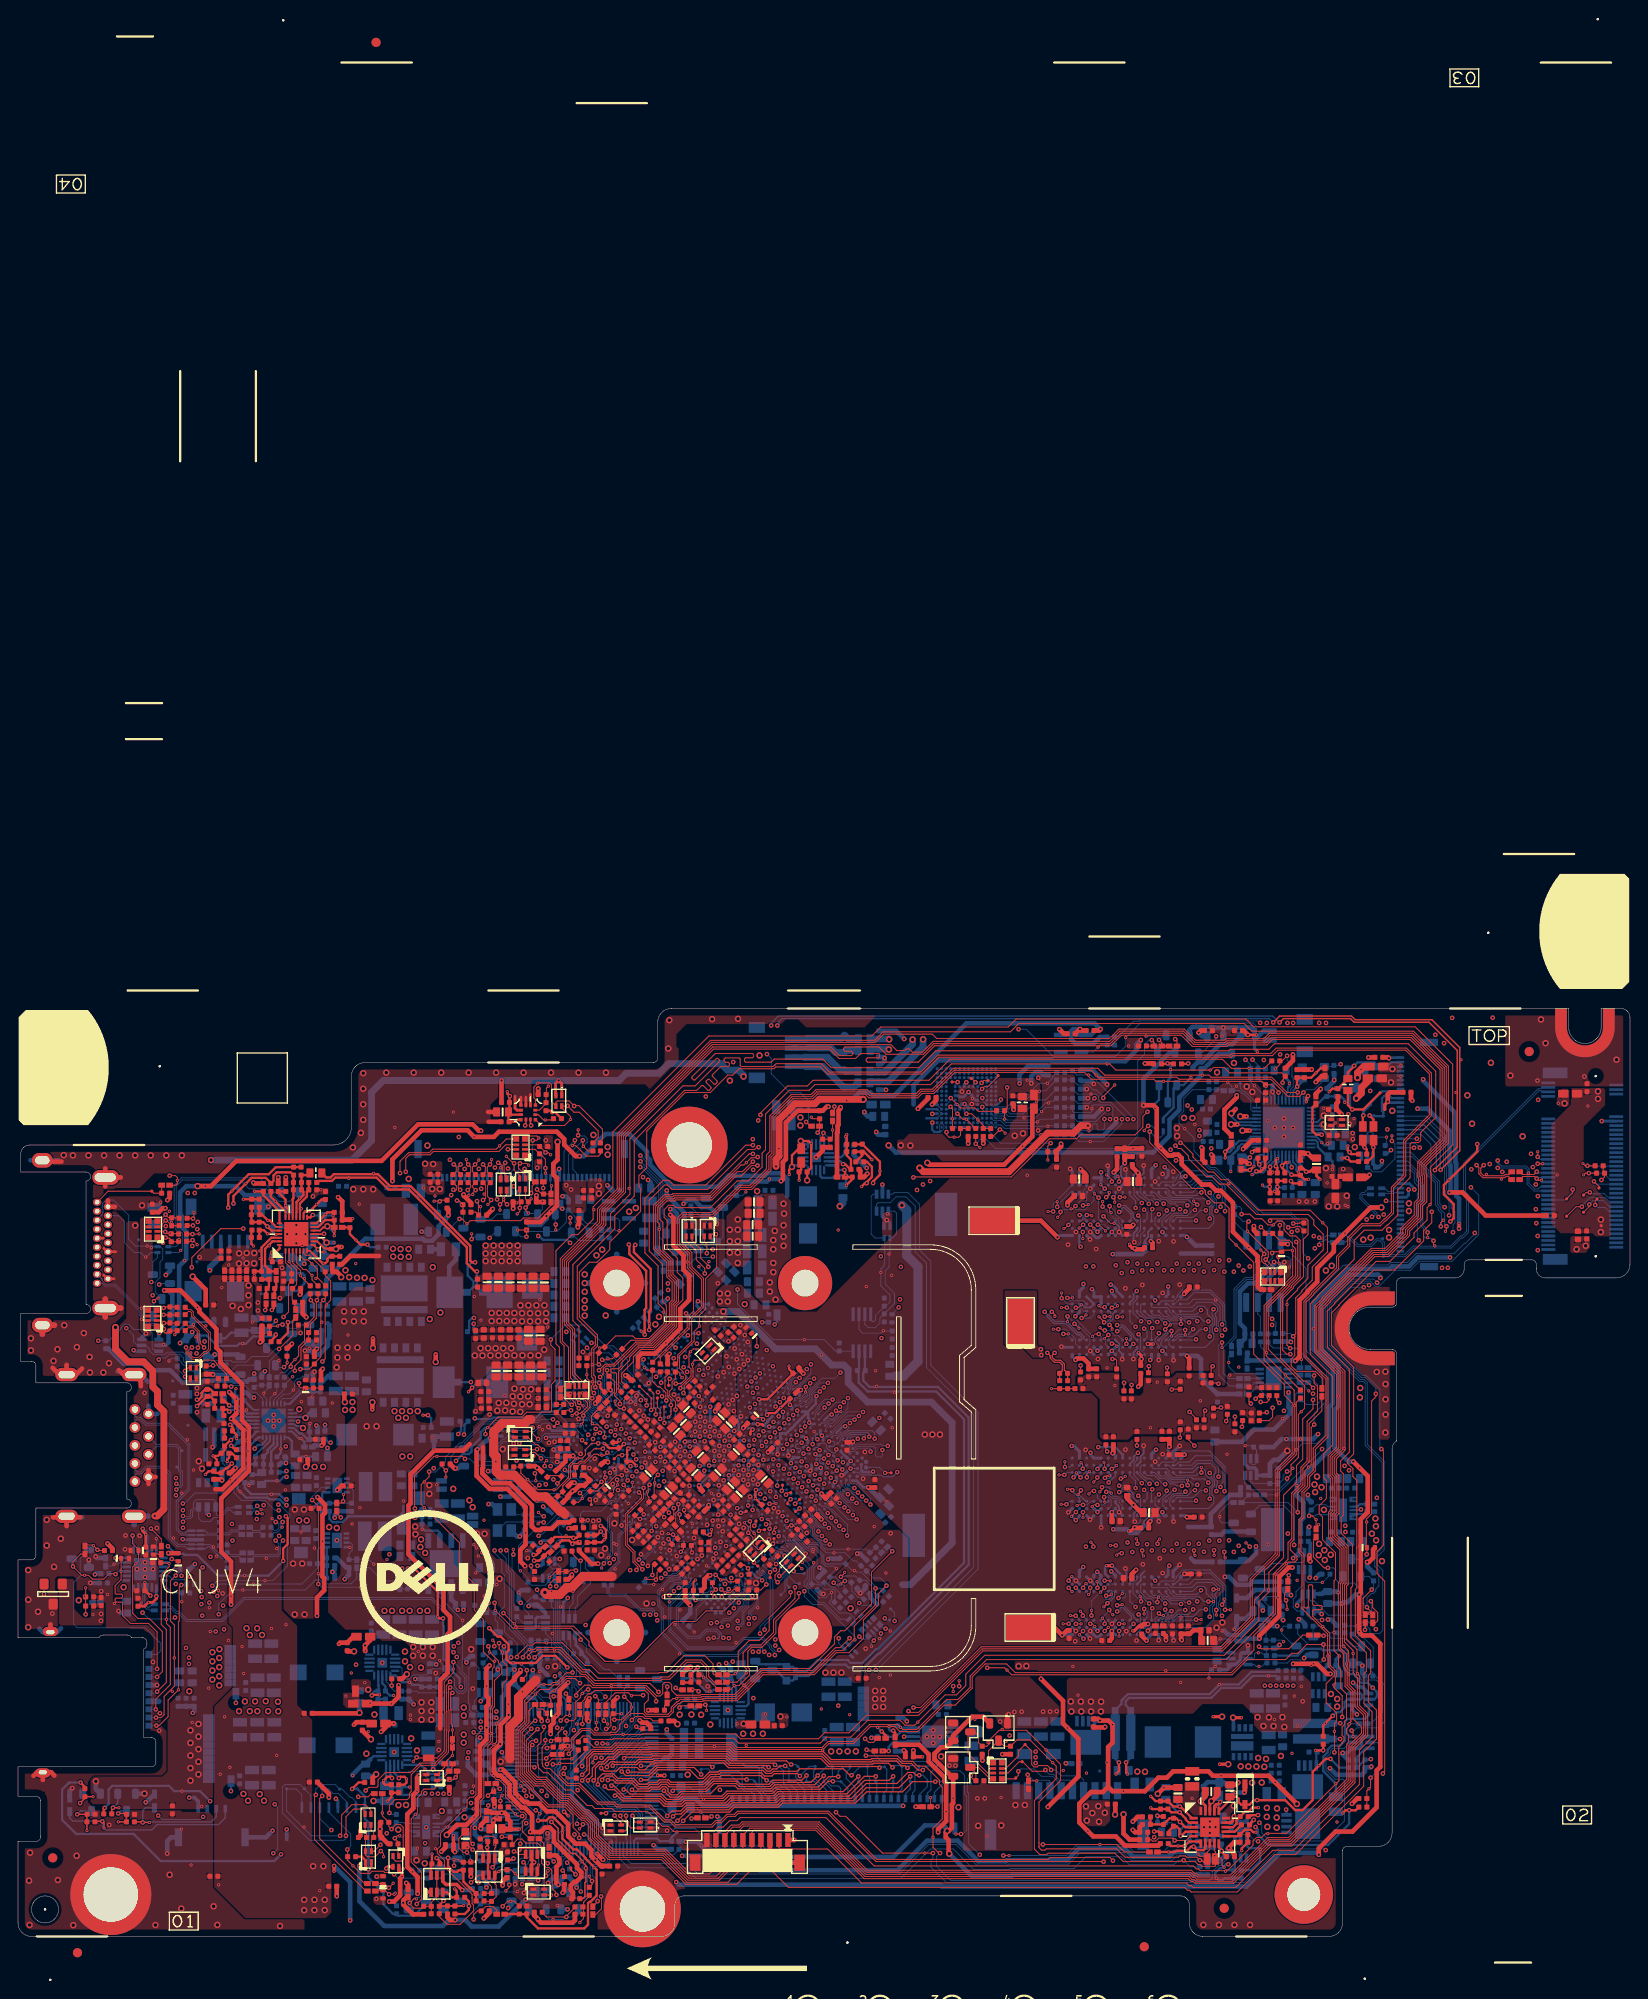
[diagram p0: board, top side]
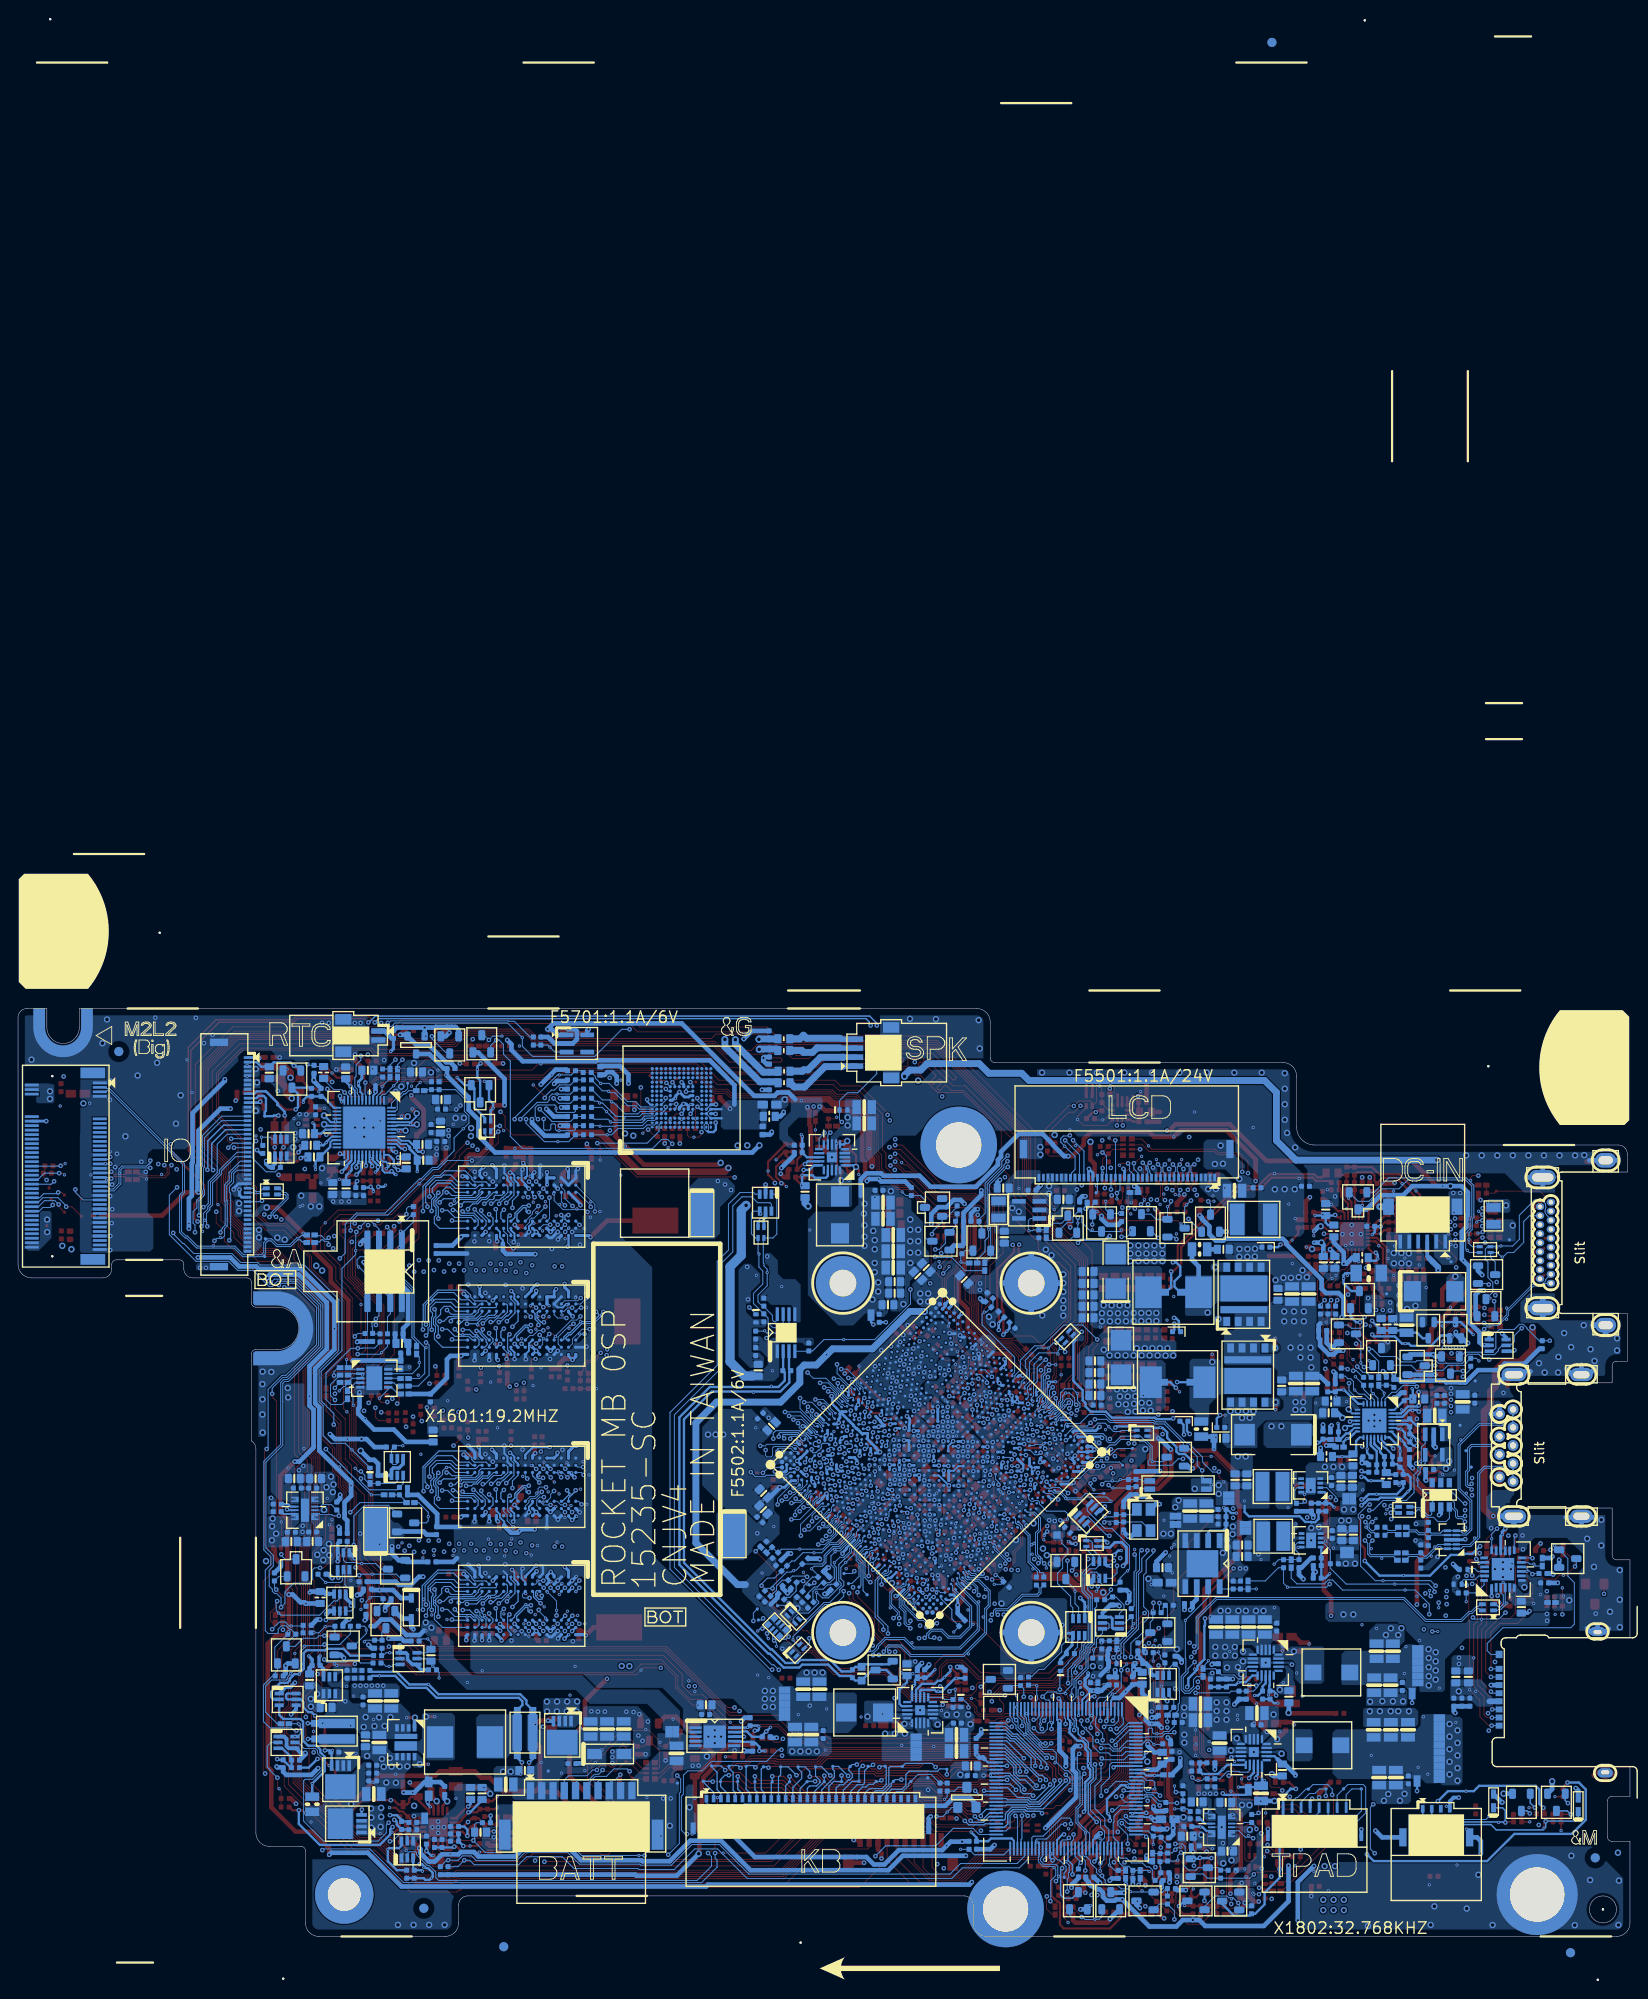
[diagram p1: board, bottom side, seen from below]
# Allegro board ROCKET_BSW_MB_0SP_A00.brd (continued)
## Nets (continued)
M_A_DQ24: CPU1.BD52 RAM1.C3
M_A_DQ25: CPU1.AV52 RAM1.A7
M_A_DQ26: CPU1.BC53 RAM1.C2
M_A_DQ27: CPU1.AV51 RAM1.C8
M_A_DQ28: CPU1.AW51 RAM1.B8
M_A_DQ29: CPU1.BC52 RAM1.A2
M_A_DQ30: CPU1.AW53 RAM1.D7
M_A_DQ31: CPU1.BB51 RAM1.A3
M_A_DQ32: CPU1.BG42 RAM2.C8
M_A_DQ33: CPU1.BG43 RAM2.D7
M_A_DQ34: CPU1.BG37 RAM2.C2
M_A_DQ35: CPU1.BJ37 RAM2.C3
M_A_DQ36: CPU1.BH42 RAM2.B8
M_A_DQ37: CPU1.BJ41 RAM2.A7
M_A_DQ38: CPU1.BH36 RAM2.A2
M_A_DQ39: CPU1.BH38 RAM2.A3
M_A_DQ40: CPU1.BC36 RAM4.H8
M_A_DQ41: CPU1.BA36 RAM4.H7
M_A_DQ42: CPU1.AU34 RAM4.H3
M_A_DQ43: CPU1.AU32 RAM4.G2
M_A_DQ44: CPU1.BF36 RAM4.F8
M_A_DQ45: CPU1.BD36 RAM4.F7
M_A_DQ46: CPU1.AV34 RAM4.E3
M_A_DQ47: CPU1.AV32 RAM4.F2
M_A_DQ48: CPU1.BF34 RAM2.F8
M_A_DQ49: CPU1.BC34 RAM2.H7
M_A_DQ50: CPU1.BA32 RAM2.G2
M_A_DQ51: CPU1.BD30 RAM2.H3
M_A_DQ52: CPU1.BD34 RAM2.H8
M_A_DQ53: CPU1.BA34 RAM2.F7
M_A_DQ54: CPU1.BF30 RAM2.E3
M_A_DQ55: CPU1.BD28 RAM2.F2
M_A_DQ56: CPU1.BJ33 RAM4.C8
M_A_DQ57: CPU1.BG29 RAM4.A2
M_A_DQ58: CPU1.BH34 RAM4.D7
M_A_DQ59: CPU1.BG32 RAM4.B8
M_A_DQ60: CPU1.BG28 RAM4.C2
M_A_DQ61: CPU1.BJ29 RAM4.C3
M_A_DQ62: CPU1.BH28 RAM4.A3
M_A_DQ63: CPU1.BG33 RAM4.A7
M_A_DQS_DN0: CPU1.AM51 RAM3.B7
M_A_DQS_DN1: CPU1.AV48 RAM1.G3
M_A_DQS_DN2: CPU1.AT41 RAM3.G3
M_A_DQS_DN3: CPU1.BA51 RAM1.B7
M_A_DQS_DN4: CPU1.BG39 RAM2.B7
M_A_DQS_DN5: CPU1.AT34 RAM4.G3
M_A_DQS_DN6: CPU1.BC32 RAM2.G3
M_A_DQS_DN7: CPU1.BG31 RAM4.B7
M_A_DQS_DP0: CPU1.AM52 RAM3.C7
M_A_DQS_DP1: CPU1.AV47 RAM1.F3
M_A_DQS_DP2: CPU1.AT42 RAM3.F3
M_A_DQS_DP3: CPU1.AY52 RAM1.C7
M_A_DQS_DP4: CPU1.BH40 RAM2.C7
M_A_DQS_DP5: CPU1.AT32 RAM4.F3
M_A_DQS_DP6: CPU1.BC30 RAM2.F3
M_A_DQS_DP7: CPU1.BH32 RAM4.C7
M_A_RAS#: CPU1.BA40 R1237.2 RAM1.J3 RAM2.J3 RAM3.J3 RAM4.J3
M_A_WE#: CPU1.BH44 R1241.2 RAM1.L3 RAM2.L3 RAM3.L3 RAM4.L3
M_VREF_DQ_DIM0: CPU1.AU28 TP502.1
MCSI_COMP: CPU1.P44 R817.1
ME_FWP_SOC: CPU1.AH52 R1519.1 R1531.2 R1615.1
ME_UNLOCK#: R1615.2 U2401.79
MIC2_VREFO: RN2901.1(A) RN2901.2(A) U2701.29
MIC_CAP: C2713.1 U2701.19
MIC_GND: LCD1.20 R5502.1
MODEL_ID: IOBD1.14 R2414.1
MODEL_ID_AD: R2410.2 R2414.2 U2401.94
NCT3956_OE#_MUX: R2530.2 U2503.6
NCT_CLK: EC2601.1 Q2604.1 RN2601.4(B) U2601.8
NCT_DATA: EC2602.1 Q2604.4 RN2601.3(B) U2601.7
P2800_DXN: C2604.2 C2605.2 Q2601.E R2604.2 U2601.3
P2800_DXP: C2604.1 C2605.1 Q2601.B Q2601.C R2604.1 U2601.2
PBAT_PRES1#: AFTP4301.1 BATT1.6 RN4301.5(B)
PBAT_SMBCLK1: AFTP4303.1 BATT1.4 RN4301.7(B)
PBAT_SMBDAT1: AFTP4302.1 BATT1.5 RN4301.6(B)
PCB_VER_AD: C2417.1 R2437.2 R2438.1 U2401.98
PCH_SUSCLK: CPU1.C15 TP1802.1
PCH_SUSCLK_KBC: TP2403.1 U2401.77
PCIE_OBSN_CPU: CPU1.F26 R1930.1
PCIE_OBSP_CPU: CPU1.D26 R1930.2
PCIE_RX_CPU_N0: CPU1.J20 R6104.2
PCIE_RX_CPU_P0: CPU1.G20 R6101.2
PCIE_TX_CON_N0: C1916.2 WLAN1.37
PCIE_TX_CON_P0: C1915.2 WLAN1.35
PCIE_TX_CPU_N0: C1916.1 CPU1.B24
PCIE_TX_CPU_P0: C1915.1 CPU1.C24
PCU_SMB_ALERT#: CPU1.AM9 TP1622.1
PD4403_A: PD4404.A PQ4409.B
PD4403_K: PD4404.K PR4468.2
PEG_CLK0_CPU: CPU1.A21 WLAN1.47
PEG_CLK0_CPU#: CPU1.C21 WLAN1.49
PEG_CLKREQ0_CPU#: CPU1.AM10 D1901.1 R1905.2 RN1902.4(B)
PEG_CLKREQ0_D: D1901.3 Q1901.D R1902.2
PEG_CLKREQ0_WLAN#: AFTP6102.1 Q1901.S R1904.2 R1905.1 WLAN1.53
PEG_CLKREQ1_CPU#: CPU1.AM12 RN1901.3(B)
PEG_CLKREQ2_CPU#: CPU1.AK14 RN1901.4(B)
PEG_CLKREQ3_CPU#: CPU1.AM14 RN1902.3(B)
PLT_RST#: AFTP6105.1 DB1.4 EC1809.1 R1810.2 U2401.7 WLAN1.52
PLT_RST#_CPU_G: Q1812.G R1827.2 R1842.2
PLT_RST#_D: Q1812.D Q1813.2 R1843.1
PLTRST#: Q1813.6 R1810.1 R1864.2
PLTRST#_CPU: CPU1.F14 R1827.1 R6328.2
PLTRST#_CPU_D: Q6301.D R6327.2 R6328.1
PM_PCIE_WAKE#: CPU1.N16 RN1801.2(A)
PM_PWRBTN#: R2417.1 U2401.91
PM_PWRBTN#_CPU: CPU1.M16 R2417.2 RN1801.1(A)
PM_RSMRST#: CPU1.F18 Q1801.3 R1841.1 R1861.1
PM_SLP_S0IX#: CPU1.A13 TP1801.1
PM_SLP_S3#: PC4803.1 PR4813.1 PR5125.1 PR5315.1 PU4802.1 Q1810.3 R1856.1 R4003.1 R4010.1 U2401.64
PM_SLP_S3#_CPU: CPU1.B14 Q1814.5
PM_SLP_S3#_CPU_D: Q1810.5 Q1814.3 Q4001.5 RN1803.1(A)
PM_SLP_S4#: PR5105.1 PR5114.1 Q1810.6 R4055.2 RN1803.2(A) U2401.21
PM_SLP_S4#_CPU: CPU1.C12 Q1814.2
PM_SLP_S4#_CPU_D: Q1810.2 Q1814.6 Q4017.G R1830.1
PM_SUS_STAT#_CPU: CPU1.D14 R1808.1
PMC_BATLOW#: CPU1.C14 R1839.2
PMC_RSTBTN#: C1811.1 CPU1.AF2 R1825.2
PQ3802_1: PQ4302.B PR4302.1 PR4311.2
PQ4008_2: PC4425.1 PQ4408.2 PR4437.2
PQ4008_6: PQ4408.6 PR4426.1
PQ4209_D: PQ4309.D PR4316.2
PQ4405_2: PQ4410.2 PR4475.2 PR4476.2
PQ4405_3: PQ4410.3 PR4466.1
PQ4405_5: PC4434.1 PQ4410.5 PR4470.2
PQ4405_6: PC4434.2 PQ4410.6 PR4473.1
PQ4406_D: PQ4414.D PR4465.2
PQ4406_G: PC4433.2 PQ4414.G PR4474.1
PQ4408_C: PQ4409.C PR4464.1 PR4475.1
PQ4408_E: PQ4409.E PR4467.1 PR4469.2
PROCHOT#_CPU: CPU1.AD50 R1809.2 R1860.2
PROCHOT#_EC: Q2402.G R2442.1 U2401.24
PS_ID: PQ4301.S PR4307.1
PS_ID_R: AFTP4202.1 DCIN1.3 EC4307.1 PQ4301.D PR4311.1
PSID_DISABLE#_R_C: PQ4301.G PQ4302.C PR4303.2
PSID_EC: PD4303.3 PR4306.2 PR4307.2 U2401.99
PSL_IN1#: R2487.2 U2401.73
PSL_IN2#: R2488.2 R2489.1 U2401.93
PSL_OUT#: R2493.1 U2401.74
PU4401_4: PC4424.2 PR4410.2 PR4454.2 PU4407.4
PU4401_5: PC4424.1 PR4410.1 PR4448.2 PU4407.5
PU4401_6: PR4446.2 PU4407.6
PU4902_S5: PC5119.1 PR5114.2 PU5102.9
PU4902_VCNTL: PC5111.1 PR5117.1 PU5102.10
PURE_HW_SHUTDOWN#: C2606.1 D4001.3 EC2403.1 Q2401.B Q2603.D R2404.1 R2405.2 R2603.1
PWR_1D05V_PWR_EN: PC5001.1 PR5003.1 PR5004.2 PU5001.11
PWR_1D05V_PWR_ILIM: PR5002.1 PR5008.2 PU5001.13
PWR_1D8V: PC5222.1 PC5223.1 PC5224.1 PG5209.1 PG5210.1 PL5201.2 PR5211.2
PWR_1D8V_FB: PC5222.2 PR5211.1 PR5213.2 PU5204.1
PWR_1D8V_PHASE: PL5201.1 PU5204.6
PWR_1D8V_PVDD: PC5219.1 PC5220.1 PC5221.1 PG5207.2 PG5208.2 PU5204.3
PWR_1D8V_S5_EN: PC5225.1 PR5201.2 PR5202.2 PU5204.7
PWR_1D15V: PC5017.1 PC5018.1 PC5019.1 PG5002.1 PG5003.1 PL5002.2 PR5011.1
PWR_1D15V_FB: PC5017.2 PR5010.1 PR5011.2 PU5002.1
PWR_1D15V_PG: PR5012.2 PR5202.1 PR5417.1 PU5002.2
PWR_1D15V_PHASE: PL5002.1 PU5002.6
PWR_1D15V_PVDD: PC5014.1 PC5015.1 PC5016.1 PG5004.2 PG5005.2 PU5002.3
PWR_1D15V_S5_EN: PC5000.1 PR5009.2 PU5002.7
PWR_1D24V: PC5404.1 PC5405.1 PC5407.1 PG5408.1 PG5409.1 PR5419.1 PU5402.3 PU5402.4
PWR_1D24V_EN: PC5427.1 PR5401.1 PR5417.2 PU5402.8
PWR_1D24V_FB\: PC5405.2 PR5419.2 PR5420.1 PU5402.2
PWR_1D35V_BOOT: PR5101.1 PU5101.1
PWR_1D35V_BOOT_R: PC5117.1 PR5101.2
PWR_1D35V_BYP: PC5110.1 PR5102.1 PU5101.15
PWR_1D35V_EN: PC5138.1 PR5105.2 PU5101.11
PWR_1D35V_IMAX: PR5106.2 PU5101.13
PWR_1D35V_LDO_P5: PC5113.1 PU5101.17
PWR_1D35V_PGOOD: PR5107.2 PU5101.9
PWR_1D35V_PHASE: PC5117.2 PL5101.1 PU5101.6 PU5101.19 PU5101.20
PWR_1D35V_VFB: PC5112.2 PR5103.2 PR5104.1 PU5101.14
PWR_3D3V_BOOT: PR4501.1 PU4502.1
PWR_3D3V_BOOT_A: PC4506.1 PR4501.2
PWR_3D3V_EN: PR4510.1 PR4514.2 RN4501.2(A)
PWR_3D3V_EN1: PC4508.1 PC4530.1 PR4510.2 PR4518.1 PU4502.12
PWR_3D3V_EN2: PC4538.1 PR4515.2 PR4517.1 PU4502.11
PWR_3D3V_FB: PC4525.1 PU4502.13
PWR_3D3V_FB2: PC4525.2 PR4506.2
PWR_3D3V_LDO: PC4535.1 PG4542.2 PU4502.17
PWR_3D3V_PH: PC4506.2 PL4501.1 PU4502.6 PU4502.19 PU4502.20
PWR_3D3V_VOUT: PG4535.2 PR4506.1 PU4502.14
PWR_3V_PG: PR4504.2 PR4534.2 PU4502.9
PWR_5V_BOOT: PR4502.1 PU4503.1
PWR_5V_BOOT_A: PC4521.1 PR4502.2
PWR_5V_EN1: PC4507.1 PC4531.1 PR4511.2 PR4516.1 PU4503.12
PWR_5V_EN2: PC4534.1 PR4512.2 PR4513.1 PU4503.11
PWR_5V_FB: PC4526.1 PU4503.13
PWR_5V_FB_A: PC4526.2 PR4507.2
PWR_5V_LDO: PC4520.1 PG4525.2 PU4503.15
PWR_5V_PG: PG4534.2 PU4503.9
PWR_5V_PH: PC4521.2 PL4502.1 PU4503.6 PU4503.19 PU4503.20
PWR_5V_VCC: PC4524.1 PU4503.17
PWR_5V_VOUT: PG4521.2 PR4507.1 PU4503.14
PWR_CHG_ACDET: PC4412.1 PR4407.2 PR4431.1 PU4404.6
PWR_CHG_ACN: PC4402.2 PC4403.1 PG4403.2 PR4406.1 PU4404.1
PWR_CHG_ACOK: PQ4402.2 PQ4408.3 PR4419.2 PR4428.2 PR4436.1 PR4476.1
PWR_CHG_ACP: PC4402.1 PC4404.1 PG4402.2 PR4406.2 PU4404.2
PWR_CHG_AD_OFF: PQ4309.G PR4312.1 U2401.11
PWR_CHG_AD_OFF_R: PQ4304.1 PR4312.2
PWR_CHG_BAT_SCL: PG4407.1 PU4404.9
PWR_CHG_BAT_SDA: PG4408.1 PU4404.8
PWR_CHG_BTST: PR4409.1 PU4404.17
PWR_CHG_BTST_R: PC4411.1 PD4401.K PR4409.2
PWR_CHG_CMPIN: PR4411.2 PR4413.1 PR4414.2 PR4427.2 PR4429.1 PU4404.4
PWR_CHG_CMPIN_R: PQ4407.3 PR4429.2
PWR_CHG_CMPIN_RR: PQ4407.6 PR4427.1
PWR_CHG_CMPOUT: PR4414.1 PR4430.2 PR4432.1 PR4437.1 PR4438.1 PU4404.3
PWR_CHG_CSON_1: PC4421.2 PC4423.1 PG4410.1 PR4420.2
PWR_CHG_CSOP_1: PC4420.1 PC4421.1 PG4409.1 PR4421.2
PWR_CHG_HIDRV: PC4413.2 PU4404.18 PU4405.1
PWR_CHG_IFAULT: PR4418.2 PU4404.11
PWR_CHG_ILIM: PR4417.2 PR4423.1 PU4404.10
PWR_CHG_IOUT: PC4422.1 PR4411.1 PR4422.1 PR4424.1 PU4404.7
PWR_CHG_LODRV: PU4404.15 PU4405.8
PWR_CHG_PHASE: PC4411.2 PC4413.1 PL4401.1 PU4404.19 PU4405.9
PWR_CHG_REGN: PC4407.1 PD4401.A PR4425.1 PR4428.1 PR4430.1 PU4404.16
PWR_CHG_SRN: PR4420.1 PU4404.12
PWR_CHG_SRP: PR4421.1 PU4404.13
PWR_CHG_VCC: PC4410.1 PR4408.2 PU4404.20
PWR_DCBATOUT_1D35V: PC5106.1 PC5107.1 PC5108.1 PG5101.2 PG5103.2 PG5106.2 PG5107.2 PU5101.2 PU5101.3 PU5101.4 PU5101.5
PWR_GFX_ISEN1N: PG4801.1 PR4824.1
PWR_GFX_ISEN1P: PG4802.1 PR4832.2
PWR_GFX_RGND_1: PC4815.1 PC4839.1 PR4808.2 PR4835.2
PWR_GFX_SEN_1: PC4834.1 PR4809.2 PR4836.2
PWR_GFX_SNUB: PC4817.1 PR4847.2
PWR_GFX_VRHOT#: PR4807.1 PR4814.2 PR4816.2 PU4802.2
PWR_VCC0_BT: PR4612.1 PU4601.8
PWR_VCC0_BTR: PC4609.2 PR4612.2
PWR_VCC0_COMP: PC4602.1 PC4613.1 PU4601.23
PWR_VCC0_COMP1: PC4601.2 PR4603.1
PWR_VCC0_COMP2: PC4613.2 PR4616.1
PWR_VCC0_CSCOMP: PC4607.2 PC4612.2 PR4168.2 PR4606.2 PR4648.1 PU4601.19
PWR_VCC0_CSMP1: PR4606.1 PR4614.1 PR4648.2
PWR_VCC0_CSREF: PC4603.1 PR4613.2 PU4601.17
PWR_VCC0_CSSUM: PC4607.1 PC4612.1 PR4614.2 PR4617.1 PU4601.18
PWR_VCC0_DIFFOUT: PR4603.2 PR4604.2 PU4601.25
PWR_VCC0_FB: PC4601.1 PC4602.2 PR4604.1 PR4609.1 PR4616.2 PU4601.24
PWR_VCC0_HG: PU4601.9 PU4701.1
PWR_VCC0_ILIM: PR4168.1 PU4601.21
PWR_VCC0_IMAX: PR4684.1 PU4601.16
PWR_VCC0_IOUT: PC4608.1 PR4619.1 PU4601.20
PWR_VCC0_PVCC: PC4611.1 PR4637.2 PU4601.15
PWR_VCC0_ROSC: PR4615.1 PU4601.22
PWR_VCC0_TSEN: PC4617.2 PR4660.1 PU4601.13
PWR_VCC0_TSEN1: PR4643.1 PR4660.2 PR4661.1
PWR_VCC0_VBOOT/ADDR: PR4644.1 PU4601.14
PWR_VCC0_VCC: PC4604.1 PR4620.2 PU4601.28
PWR_VCC0_VRMP: PC4610.2 PR4607.2 PU4601.7
PWR_VCC0_VSN: PC4606.1 PR4610.1 PU4601.26
PWR_VCC0_VSP: PC4605.2 PR4605.1 PU4601.27
PWR_VCORE_ISEN1N: PG4709.1 PR4613.1
PWR_VCORE_ISEN1P: PG4707.1 PR4617.2
PWR_VCORE_LG1: PU4601.12 PU4701.8
PWR_VCORE_PH1: PC4609.1 PG4707.2 PL4701.1 PR4704.1 PU4601.10 PU4701.9
PWR_VCORE_RGND_1: PC4605.1 PC4619.1 PR4610.2 PR4652.1 PR4678.2
PWR_VCORE_SEN_1: PC4620.1 PR4605.2 PR4658.1 PR4676.2
PWR_VCORE_SNUB: PC4710.1 PR4704.2
PWR_VCORE_VRHOT#: PR4621.2 PR4635.2 PR4640.1 PU4601.2
PWR_VGG_BT: PR4823.1 PU4802.8
PWR_VGG_BTR: PC4813.2 PR4823.2
PWR_VGG_COMP: PC4816.1 PC4818.1 PU4802.23
PWR_VGG_COMP1: PC4804.2 PR4801.1
PWR_VGG_COMP2: PC4816.2 PR4831.1
PWR_VGG_CSCOMP: PC4802.2 PC4810.2 PR4810.1 PR4820.2 PR4825.2 PU4802.19
PWR_VGG_CSMP1: PR4810.2 PR4825.1 PR4830.1
PWR_VGG_CSREF: PC4812.1 PR4824.2 PU4802.17
PWR_VGG_CSSUM: PC4802.1 PC4810.1 PR4830.2 PR4832.1 PU4802.18
PWR_VGG_DIFFOUT: PR4801.2 PR4803.2 PU4802.25
PWR_VGG_FB: PC4804.1 PC4818.2 PR4802.1 PR4803.1 PR4831.2 PU4802.24
PWR_VGG_HG: PU4801.1 PU4802.9
PWR_VGG_ILIM: PR4820.1 PU4802.21
PWR_VGG_IMAX: PR4821.1 PU4802.16
PWR_VGG_IOUT: PC4805.1 PR4819.1 PU4802.20
PWR_VGG_LG: PU4801.8 PU4802.12
PWR_VGG_PVCC: PC4808.1 PR4818.2 PU4802.15
PWR_VGG_ROSC: PR4828.1 PU4802.22
PWR_VGG_SW: PC4813.1 PG4802.2 PL4801.1 PR4847.1 PU4801.9 PU4802.10
PWR_VGG_TSEN: PC4814.2 PR4834.1 PU4802.13
PWR_VGG_TSEN1: PR4812.1 PR4833.1 PR4834.2
PWR_VGG_VBOOT/ADDR: PR4822.1 PU4802.14
PWR_VGG_VCC: PC4807.1 PR4817.2 PU4802.28
PWR_VGG_VRMP: PC4806.2 PR4827.2 PU4802.7
PWR_VGG_VSN: PC4819.1 PR4835.1 PU4802.26
PWR_VGG_VSP: PC4815.2 PR4836.1 PU4802.27
Q3601_2: Q4001.2 R4010.2
Q3615_G: Q4015.G R4055.1
Q6203_S: C6504.2 Q6503.S R6501.2 R6513.2
Q6204_S: C6505.2 Q6504.S R6514.2 R6518.2
Q6205_D: Q6507.6 R6505.2
Q6206_D: Q6507.3 R6506.2
RCOMP_LPC_HVT: CPU1.T4 R1859.2
RING2: EC2905.1 R2906.1 RN2901.3(B) U2701.17
RING2_R: IOBD1.3 IOBD1.4 IOBD1.5 R2906.2
RSMRST#_KBC: EC1812.1 R1841.2 R2528.2 U2401.15
RSMRST#_KBC_G: Q1801.5 Q1801.6 R1820.1
RSMRST#_KBC_MUX: R2528.1 U2503.9
RSVD_VSS#A3: CPU1.A3 TP2101.1
RTC_AUX_S5: C1132.1 CPU1.B6 CPU1.C5 Q2501.3 R1862.1 R1863.1 R2425.2 R2513.1
RTC_DET#: Q2502.D R2403.2 U2401.6
RTC_DET#_G: Q2501.1 Q2502.G R2501.1 R2505.1 R2514.2
RTC_INTRUDER: CPU1.G18 R1823.1
RTC_RST#: C1802.1 CPU1.D18 EC1811.1 G1801.2 Q1813.3 R1863.2
RTC_TEST#: C1803.1 CPU1.J16 R1862.2
RTCRST_ON: EC1810.1 Q1813.5 R1828.1 U2401.120
RUN_ON#: Q4001.6 Q4014.5 R4014.2
RUN_ON_R: C4051.1 R4003.2 U4001.3 U4001.5
S5_ENABLE: Q2403.D R2490.2 R4001.2 U2401.14
SATA_OBSN: CPU1.M30 R1931.1
SATA_OBSP: CPU1.N30 R1931.2
SATA_RXN0: CPU1.M28 R1903.2
SATA_RXN1: CPU1.K28 R1907.2
SATA_RXP0: CPU1.N28 R1901.2
SATA_RXP1: CPU1.J28 R1906.2
SD_CD#: Q3301.G R3308.2 R3309.2 SD1.1
SD_CD#_CARD: Q3301.D R3307.2 R3309.1 U3301.10
SD_MMC_CLK/MS_DATA2: EC3305.1 EC3307.1 R3303.2 SD1.5
SD_MMC_CMM/MS_DATA3: EC3304.1 SD1.7 U3301.20
SD_MMC_DAT1: EC3301.1 SD1.2 U3301.12
SD_MMC_DATA0/MS_DATA5: EC3306.1 SD1.3 U3301.13
SD_MMC_DATA2/MS_BS: EC3302.1 SD1.9 U3301.23
SD_MMC_DATA3/MS_CLK: EC3303.1 SD1.8 U3301.22
SD_WP#/MS_DATA1_C: R3311.1 U3301.11
SDMMC1_RCOMP: CPU1.P13 R814.1
SDMMC3_RCOMP: CPU1.P12 R815.1
SDREG: C3309.2 U3301.16
SEC_GPIO_SUS8: CPU1.AF51 R1522.1 R1523.2
SEC_GPIO_SUS9: CPU1.AF52 R1524.1 R1525.2
SEC_GPIO_SUS10: CPU1.AE51 R1526.1 R1527.2
SENSOR_HUB_RST#_R: CPU1.G2 TP805.1
SENSOR_I2C_SCL: IOBD1.20 R6906.2 RN6901.4(B) U6901.1
SENSOR_I2C_SCL_ALS: LCD1.31 R6906.1
SENSOR_I2C_SDA: IOBD1.21 R6907.2 RN6901.3(B) U6901.4
SENSOR_I2C_SDA_ALS: LCD1.30 R6907.1
SENSOR_KB_DIS: IOBD1.15 R2428.2 U2401.31
SIO_I2C5_CLK: CPU1.AB2 Q1606.1 RN1603.2(A)
SIO_I2C5_DATA: CPU1.AC3 Q1606.4 RN1603.1(A)
SIO_SLP_S4: Q4014.2 Q4015.D R4053.2
SLEEVE: EC2906.1 R2911.1 RN2901.4(B) U2701.18 U2901.3
SLEEVE_CTRL: R2915.2 U2901.5 U2901.6
SLEEVE_R: IOBD1.6 IOBD1.7 IOBD1.8 R2911.2
SM_DRAMRST#: CPU1.BA42 EC502.1 RAM1.T2 RAM2.T2 RAM3.T2 RAM4.T2
SM_RCOMP_0: CPU1.BA28 R504.1
SMB_CLK: CPU1.AM6 RN1601.3(B)
SMB_DATA: CPU1.AM7 RN1601.4(B)
SML1_CLK: Q2604.6 RN2401.3(B) U2401.67
SML1_DATA: Q2604.3 RN2401.4(B) U2401.68
SOC_EXTSMI_N: CPU1.AG53 R1514.2 R1515.1 R2461.2
SOC_RUNTIME_SCI#: CPU1.AG51 R1506.2 R1513.1 R2496.2
SOC_RUNTIME_SCI#_KBC: R2496.1 U2401.17
SP5: R3303.1 U3301.18
SPI_CLK_CPU: CPU1.W3 R1911.1
SPI_CLK_CPU_MUX: R2526.2 U2503.4
SPI_CLK_KBC: R2418.1 U2401.92
SPI_CLK_KBC_MUX: R2524.2 U2503.2
SPI_CLK_KBC_R: R2418.2 R2524.1
SPI_CLK_ROM: R1911.2 R2526.1 R2527.1
SPI_CLK_ROM_MUX: R2522.2 U2503.7
SPI_CLK_ROM_R: EC2502.1 R2522.1 R2527.2 SSKT1.6 U2501.6
SPI_CS_CPU_MUX: R2525.2 U2503.3
SPI_CS_CPU_N0: CPU1.V4 R1909.1
SPI_CS_KBC_MUX: R2523.2 U2503.1
SPI_CS_KBC_N0: R2416.1 U2401.90
SPI_CS_KBC_R_N0: R2416.2 R2523.1
SPI_CS_ROM_MUX: R2521.2 U2503.8
SPI_CS_ROM_N0: R1909.2 R2516.2 R2525.1
SPI_CS_ROM_N0_R: R2516.1 R2521.1 RN2501.2(A) SSKT1.1 U2501.1
SPI_HOLD_CPU: CPU1.U3 R2536.1
SPI_HOLD_ROM: R2536.2 RN2501.1(A) SSKT1.7 U2501.7
SPI_SI_CPU: CPU1.V2 R1910.1
SPI_SI_KBC: R2401.1 U2401.87
SPI_SI_KBC_R: R2401.2 R2511.1
SPI_SI_ROM: EC2503.1 R1910.2 R2511.2 SSKT1.5 U2501.5
SPI_SO_CPU: CPU1.V3 R2529.2
SPI_SO_KBC: R2517.1 U2401.86
SPI_SO_ROM: EC2501.1 R2517.2 R2529.1 SSKT1.2 U2501.2
SPI_WP_CPU: CPU1.U1 R2531.2
SPI_WP_ROM: R2531.1 RN2501.3(A) SSKT1.3 U2501.3
SUS_PWR_ACK_R: R2411.2 U2401.25
SUS_PWRDN_ACK: Q1811.D R1811.2 R1858.1 R2411.1
SUS_PWRDN_ACK_CPU: CPU1.AE3 Q1811.S R1811.1 R1850.1
SUSPWRDNACK_SOC_EC: Q4020.G R4011.2 R4016.1 U2401.100
SYS_PRES1#: BATT1.7 R4301.2
SYS_PWROK: EC2402.1 R2426.2 R2609.2 R4029.1 U2401.84
SYS_PWROK_G: Q2603.G R2607.1 R2609.1
T_CRIT#: R2601.1 R2606.2 U2601.4
THERM_SYS_SHDN#: Q2603.S R2601.2 R2602.1
TOUCH_PANEL_EN: IOBD1.18 R2427.2 U2401.23
TP_CLK: AFTP6232.1 R6509.2 TPAD1.3
TP_CLK_C: AFTP6229.1 RN6502.3(B) TPAD1.8
TP_DAT: AFTP6231.1 R6508.2 TPAD1.2
TP_DATA_C: AFTP6230.1 RN6502.4(B) TPAD1.7
TP_DISABLE#: R2494.1 TPAD1.6
TP_DISABLE#_R: R2494.2 U2401.101
TP_I2C_CLK: EC6505.1 Q1622.1 R1618.2 R1623.2 R6509.1
TP_I2C_CLK_D: Q1606.6 Q1622.6 R1616.2 R1619.1 R1621.2
TP_I2C_DATA: EC6504.1 Q1622.4 R1619.2 R1622.2 R6508.1
TP_I2C_DATA_D: Q1606.3 Q1622.3 R1610.2 R1618.1 R1620.2
TP_ON#: R2407.2 R6516.1 U2401.33
TP_ON#_GATE: C6504.1 C6505.1 Q6503.G Q6504.G Q6507.2 Q6507.5 R6516.2
TP_VDD: AFTP6228.1 EC6502.1 Q1622.2 Q1622.5 Q6502.G Q6503.D R1610.1 R1616.1 R1622.1 R1623.1 R6504.1 R6505.1 R6512.1 R6513.1 RN6503.1(A) RN6503.2(A) TPAD1.1
TP_VDD_1D8V: Q6504.D R6506.1 R6518.1 RN1603.3(B) RN1603.4(B)
TPCLK: EC6501.1 RN6502.2(A) RN6503.3(B) U2401.72
TPDATA: EC6503.1 RN6502.1(A) RN6503.4(B) U2401.71
UART1_CTS: CPU1.AD13 TP1610.1
UART1_RTS: CPU1.AD14 TP1611.1
UART1_RX: CPU1.T52 TP802.1
UART1_RXD: CPU1.AD12 TP1609.1
UART1_TX: CPU1.T51 TP801.1
UART1_TXD: CPU1.AD10 TP1608.1
USB3_OBSN: CPU1.F34 R1642.1
USB3_OBSP: CPU1.D34 R1642.2
USB30_RX_CON_N0: C3511.1 EU3501.1 EU3501.10 R3502.2 USB1.5
USB30_RX_CON_P0: C3510.1 EU3501.2 EU3501.9 R3503.2 USB1.6
USB30_RX_CPU_N0: CPU1.D28 R3502.1
USB30_RX_CPU_P0: CPU1.F28 R3503.1
USB30_TX_CMC_N0: C3506.2 R3509.1
USB30_TX_CMC_P0: C3505.2 R3512.1
USB30_TX_CON_N0: C3509.1 EU3501.4 EU3501.7 R3509.2 USB1.8
USB30_TX_CON_P0: C3508.1 EU3501.5 EU3501.6 R3512.2 USB1.9
USB30_TX_CPU_N0: C3506.1 CPU1.C32
USB30_TX_CPU_P0: C3505.1 CPU1.B32
USB_CON_PN0: AFTP3402.1 EU3505.3 TR3503.3 USB1.2
USB_CON_PN1: IOBD1.30 TR6601.1
USB_CON_PN2: AFTP6111.1 R6103.1 WLAN1.5
USB_CON_PN3: TR3301.4 U3301.3
USB_CON_PN4: LCD1.16 TR5501.1
USB_CON_PP0: AFTP3403.1 EU3505.1 TR3503.2 USB1.3
USB_CON_PP1: IOBD1.31 TR6601.4
USB_CON_PP2: AFTP6113.1 R6102.1 WLAN1.3
USB_CON_PP3: TR3301.1 U3301.4
USB_CON_PP4: LCD1.15 TR5501.4
USB_CPU_PN0: CPU1.B42 TR3503.4
USB_CPU_PN1: CPU1.B44 TR6601.2
USB_CPU_PN2: CPU1.A41 R6103.2
USB_CPU_PN3: CPU1.A45 TR3301.3
USB_CPU_PN4: CPU1.C40 TR5501.2
USB_CPU_PP0: CPU1.C42 TR3503.1
USB_CPU_PP1: CPU1.C43 TR6601.3
USB_CPU_PP2: CPU1.C41 R6102.2
USB_CPU_PP3: CPU1.C45 TR3301.2
USB_CPU_PP4: CPU1.B40 TR5501.3
USB_HSIC_RCOMP: CPU1.N38 R1637.2
USB_OC#0: CPU1.P14 IOBD1.33 RN1607.4(B)
USB_OC#1: CPU1.P16 RN1607.3(B) U3601.3
USB_OTG_ID: CPU1.B48 R1611.1
USB_PWR_EN#: IOBD1.26 R2471.2 U2401.108 U3601.4
USB_RCOMP: CPU1.A48 R1641.2
USB_VBUSSNS: CPU1.B47 R1617.1
V_SM_VREF_CNT: CPU1.AT28 TP501.1
VD1_EN#: R2468.1 U2401.66
VD_IN1: C2612.1 C2613.1 R2608.2 R2612.1 R2614.2 U2401.95 U2401.104
VD_IN1_C: C2612.2 C2613.2 R2612.2 R2613.1
VD_OUT1#: R2602.2 R2603.2 R2615.2 U2401.110
VIDALERT#_CORE: PR4663.1 PU4601.4
VIDALERT#_CPU: CPU1.AD40 R1835.1
VIDALERT#_CPU_R: PR4602.1 PR4663.2 PR4805.1 PR4854.2 R1824.1 R1835.2
VIDALERT#_GFX: PR4854.1 PU4802.4
VIDSCK_CORE: PR4645.2 PU4601.5
VIDSCK_CPU: CPU1.AD42 R1833.1
VIDSCK_CPU_R: PR4601.1 PR4645.1 PR4804.1 PR4875.2 R1833.2
VIDSCK_GFX: PR4875.1 PU4802.5
VIDSOUT_CORE: PR4669.1 PU4601.3
VIDSOUT_CPU: CPU1.AD41 R1821.1
VIDSOUT_CPU_R: PR4665.1 PR4669.2 PR4843.1 PR4855.2 R1821.2
VIDSOUT_GFX: PR4855.1 PU4802.3
VOL_DOWN#: IOBD1.22 RN2403.3(B) U2401.63
VOL_UP#: IOBD1.23 RN2403.4(B) U2401.117
VRAM_CH_A_ZQ_1A: R1208.1 RAM1.L8
VRAM_CH_A_ZQ_2A: R1209.1 RAM2.L8
VRAM_CH_A_ZQ_3A: R1210.1 RAM3.L8
VRAM_CH_A_ZQ_4A: R1211.1 RAM4.L8
VREF_CA: C1201.1 R1207.1 RAM1.M8 RAM2.M8 RAM3.M8 RAM4.M8
VREF_CA_R1207: R1205.2 R1206.1 R1207.2
VREF_DQ: C1213.1 R1203.1 RAM1.H1 RAM2.H1 RAM3.H1 RAM4.H1
VREF_DQ_R1203: R1202.2 R1203.2 R1204.1
VTT_CT_1D8VC: C4041.1 U4016.12
VTT_CT_3D3V_S5_PRIME: C4043.1 U4016.10
VTT_EN: PC5120.1 PR5125.2 PU5102.7
WHITE_LED_BAT: EC6403.1 Q6403.C R6408.2
WIFI_RF_EN: AFTP6104.1 U2401.82 WLAN1.56
WLANTX_N3: R6104.1 WLAN1.43
WLANTX_P3: R6101.1 WLAN1.41
XDP_PREQ#: CPU1.AF41 RN1805.5(B)
XDP_TCK: CPU1.AF42 RN1806.4(B)
XDP_TDI: CPU1.AD47 RN1805.7(B)
XDP_TDO: CPU1.AF40 RN1805.6(B)
XDP_TMS: CPU1.AD48 RN1805.8(B)
XDP_TRST#: CPU1.AB48 RN1806.3(B)
XTL_19D2M_X1_CPU: C1601.1 CPU1.P24 R1603.2 X1601.1
XTL_19D2M_X2_CPU: C1602.1 CPU1.M22 R1603.1 X1601.3
XTL_32D768K_X1_CPU: C1807.1 CPU1.M18 R1816.1 X1802.1
XTL_32D768K_X2_CPU: C1806.1 CPU1.K18 R1816.2 X1802.4

Pads without a net: CPU1 A9 A17 A25 A27 A29 A33 A35 A37 A49 A51 A52 AA1 AA3 AA30 AB3 AB7 AB9 AC1 AC51 AD2 AD3 AD6 AD45 AE4 AF3 AF6 AF7 AF9 AF44 AF45 AF48 AF50 AG1 AG3 AH2 AH3 AH6 AH7 AH45 AK2 AK3 AK6 AK9 AK10 AK12 AK13 AL1 AL3 AM2 AM3 AP2 AP3 AP6 AP7 AP10 AP12 AP13 AP14 AR1 AR3 AT2 AT4 AT6 AT7 AT10 AT12 AT13 AT14 AT16 AT20 AT22 AT24 AT26 AT30 AU16 AU20 AU22 AU24 AU26 AU30 AU38 AV2 AV3 AV4 AV6 AV7 AV9 AV12 AV13 AV18 AV20 AV22 AW1 AW3 AY2 AY4 AY6 AY12 AY14 AY16 AY18 AY42 B4 B5 B7 B8 B10 B12 B16 B18 B20 B26 B30 B34 B38 B46 B49 B50 B53 BA1 BA3 BA12 BA14 BA16 BA18 BA20 BA22 BA38 BB3 BB5 BB7 BB8 BB10 BC1 BC2 BC12 BC18 BC20 BC22 BC24 BD2 BD5 BD7 BD10 BD12 BD14 BD16 BD18 BD20 BD22 BD24 BD26 BD38 BE2 BE8 BF2 BF6 BF10 BF14 BF16 BF18 BF20 BF24 BF38 BG9 BG11 BG12 BG13 BG15 BG17 BG21 BG22 BG23 BG25 BG26 BH6 BH7 BH8 BH10 BH12 BH14 BH16 BH18 BH20 BH22 BH24 BH26 BJ6 BJ9 BJ13 BJ17 BJ21 BJ25 C7 C9 C11 C16 C17 C18 C19 C25 C26 C27 C29 C31 C33 C34 C35 C37 C38 C49 C53 D2 D6 D12 D20 D22 D30 D36 D44 D48 D52 E8 E52 E53 F7 F10 F12 F20 F22 F30 F36 F40 F42 F44 G24 G32 G34 G36 G40 G42 G44 H5 H7 H46 H47 J12 J14 J24 J26 J32 J34 J36 J40 K2 K3 K6 K9 K10 K20 K26 K38 K40 K44 K47 K48 L3 L13 L51 L53 M20 M26 M32 M34 M36 M38 M44 M47 M48 M51 M52 N26 N34 N36 P18 P26 P28 P30 P34 P45 P47 P48 P50 T41 T42 T44 T45 T48 T50 U51 V6 V7 V9 V10 V12 V13 V14 V45 V47 V48 V50 V51 V52 W53 Y2 Y6 Y7 Y12 Y13 Y41 Y47 Y48; D1901 2; D4001 2; DCIN1 4; EU3505 4 6; HDMI1 13 14; IOBD1 34 37; KB1 28 29; LCD1 5 36 39; LED1 3; PU4502 10 15 16; PU4503 10 16; PU5001 10 12 16; PU5002 5; PU5101 10 12 16; PU5204 5; PU5301 4; RAM1 J1 J9 L1 L9; RAM2 J1 J9 L1 L9; RAM3 J1 J9 L1 L9; RAM4 J1 J9 L1 L9; RN2501 4 5; RN4301 1 8; RN5501 1 8; U2401 26 96; U2701 14 16 23 24; U3301 9 14 15 17 19 21; U6301 A1 A2 A7 A8 A9 A10 A11 A12 A13 A14 B1 B7 B8 B9 B10 B11 B12 B13 B14 C1 C3 C5 C7 C8 C9 C10 C11 C12 C13 C14 D1 D2 D3 D4 D12 D13 D14 E1 E2 E3 E5 E8 E12 E13 E14 F1 F2 F3 F12 F13 F14 G1 G2 G3 G10 G12 G13 G14 H1 H2 H3 H12 H13 H14 J1 J2 J3 J12 J13 J14 K1 K2 K3 K6 K7 K12 K13 K14 L1 L2 L3 L12 L13 L14 M1 M2 M3 M7 M8 M9 M10 M11 M12 M13 M14 N1 N3 N6 N7 N8 N9 N10 N11 N12 N13 N14 P1 P2 P7 P8 P9 P10 P11 P12 P13 P14; WLAN1 6 16 17 19 20 21 22 23 24 25 26 27 28 29 30 31 32 34 36 40 42 48 50 55 59 60 61 62 64 65 66 67 68 70 71 73 76 77

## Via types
v1: diameter 0.508, hole 0.254, TOP to BOTTOM, 2297 vias
v2: diameter 0.356, hole 0.178, TOP to BOTTOM, 986 vias
v3: diameter 0.711, hole 0.406, TOP to BOTTOM, 568 vias

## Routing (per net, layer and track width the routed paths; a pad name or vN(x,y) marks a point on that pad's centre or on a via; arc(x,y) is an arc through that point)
1V_CPU_CORE:
  vias: v1(60.13,41.9) v1(77.29,53.9) v1(77.84,54.45) v1(77.83,53.36) v1(78.38,53.91) v1(78.36,52.82) v1(78.92,54.45) v1(79.45,51.74) v1(79.97,51.22) v1(80.53,51.77) v1(80.51,50.68) v1(81.03,50.17) v1(81.06,51.23) v1(81.63,51.76) v1(81.6,50.7) v1(82.11,50.18) v2(54.03,60.05) v2(57.66,59.77) v2(65.53,42.04) v3(53.19,58.36) v3(53.35,59.22) v3(54.06,58.38) v3(54.19,59.23) v3(54.91,59.95) v3(54.89,58.27) v3(55.04,59.12) v3(55.09,60.8) v3(55.74,59.93) v3(55.74,58.23) v3(55.94,59.06) v3(56.04,60.73) v3(56.61,59.94) v3(56.78,59.07) v3(56.94,60.73) v3(64.72,42.32) v3(65.15,43.05)
3V_5V_EN: length 169.1
  TOP w0.102: R4001.1 149.28,35.97 149.28,37.54 v1(150.25,38.5) ; v1(44.25,3.6) 44.78,4.13 44.78,7.12 43.63,8.27 43.63,13.05 v2(44.13,13.55) 44.35,13.77 44.35,15.39 44.76,15.81 44.76,16.07 45.05,16.35 46.17,16.35 46.51,16.7 RN4501.1 46.9,17.32 47.85,18.27 PR4511.1 48.09,18.59 48.09,18.7 48.24,18.85 PR4514.1
  L3 w0.102: v1(150.25,38.5) 149.06,37.32 149.06,30.81 149.63,30.24 149.63,29.33 148.74,28.45 148.74,26.7 149.12,26.32 149.12,25.74 149.52,25.35 149.52,21.61 148.59,20.68 148.59,16.72 140.96,9.09 139.94,9.09 135.84,4.99 131.68,4.99 130.31,6.37 119.66,6.37 114.26,11.77 107.97,11.77 107.66,11.46 105.83,11.46 105.43,11.86 105.23,11.86 104.53,12.56 103.77,12.56 103.55,12.78 100.97,12.78 99.1,10.91 94.13,10.91 93.34,10.13 93.34,10.12 92.28,9.07 88.69,9.07 88.43,9.32 84.43,9.32 84.11,9.64 75.72,9.64 74.35,8.27 73.11,8.27 72.77,8.61 66.13,8.61 65.15,7.63 63.66,7.63 63.29,8 61.61,8 61.29,7.68 60.93,7.68 60.87,7.75 59.02,7.75 58.96,7.69 58.94,7.69 58.16,6.91 58.16,3.85 57.34,3.03 55.15,3.03 54.4,3.78 51.17,3.78 50.65,4.29 50.06,4.29 49.81,4.04 47.96,4.04 47.44,3.52 44.33,3.52 v1(44.25,3.6)
  BOTTOM w0.102: v1(150.25,38.5) 150.44,38.7 R4005.1 149.94,39.97 D4001.1
3V_5V_POK: length 123.7
  TOP w0.102: v1(57.34,30.98) 57.94,31.57 60.04,31.57 62.52,29.1 62.98,29.1 63.99,28.09 70.14,28.09 v1(71.08,27.14) ; v1(137.73,32.17) 137.97,31.93 141.04,31.93 142.56,33.45 R4017.1 ; v1(48.32,30.45) v2(48.32,29.67) 48.32,29.27 47.3,28.26 47.3,27.18 47.32,27.16 47.32,26.67 47.32,26.66 47.32,24.95 47.37,24.89 47.37,22.99 47.3,22.92 47.3,20.6 46.5,19.8 PG4534.1
  L3 w0.102: v1(71.08,27.14) 71.35,26.87 73.34,26.87 74.29,27.83 75.47,27.83 76.65,29.01 88.61,29.01 89.36,28.26 95.26,28.26 97.72,30.72 105.96,30.72 107.3,29.38 112.92,29.38 113.81,30.27 130.05,30.27 131.33,31.55 137.1,31.55 v1(137.73,32.17)
  L4 w0.102: v1(48.32,30.45) 49,30.45 49.48,29.97 51.82,29.97 51.89,29.9 51.89,29.9 52.14,29.64 52.15,29.64 52.16,29.63 52.52,29.63 53.3,30.42 56.78,30.42 v1(57.34,30.98)
  BOTTOM w0.102: EC1814.1 56.98,30.62 v1(57.34,30.98) 56.97,31.35 56.97,31.89 R1844.2 ; PR4504.1 48.11,28.85 48.44,28.53 48.44,27.76 48.73,27.46 48.74,27.46 48.95,27.25 49.35,27.25 49.58,27.48 49.58,28.75 49.04,29.29 49.04,29.73 v1(48.32,30.45)
5V_DDC_HDMI1: length 20.9
  BOTTOM w0.102: D5701.1 28.38,82.6 26.78,84.2 18.16,84.2 17.33,83.37 17.33,80.14 17.33,80.14 17.33,79.83 17.51,79.65 17.51,78.45 17.88,78.09 v2(17.88,77.36) 17.88,77.35 17.88,76.93 17.51,76.56 RN5701.3
5V_DDC_HDMI2: length 24.3
  BOTTOM w0.102: RN5701.4 17.82,75.91 v2(18.06,76.15) 18.23,76.32 18.23,78.05 17.74,78.55 17.74,79.74 17.57,79.91 17.57,79.91 17.56,79.93 17.56,83.28 18.26,83.97 24.64,83.97 25.63,82.98 27.58,82.98 28.96,81.6 30.16,81.6 D5701.2
5V_HDMI: length 1.5
  TOP w0.508: 9.98,81.71 HDMI1.18 10.77,81
  vias: v2(15.83,81.51) v3(13.76,81.14)
5V_PWR:
  vias: v2(22.93,24.38) v2(23.52,18.77) v2(28.7,20.09)
5V_PWR_2: length 196.7
  TOP w0.254: v1(161.95,87.95) 161.95,87.11 v2(158.81,83.97) 158.25,83.41 158.25,82.37 159.33,81.29 159.33,79.72 v1(158.97,79.36)
  L3 w0.254: v1(161.95,87.95) 161.65,87.65 157.05,87.65 156.39,86.99 152.67,86.99 v1(152.37,87.29) ; v1(158.97,79.36) 158.78,79.36 158.6,79.55 157.6,79.55 157.44,79.4 155.04,79.4 154.84,79.21 152.08,79.21 151.15,78.27 151.15,76.65 150.51,76.02 148.98,76.02 148.85,76.02 144.46,71.63 144.46,65.35 144.46,65.1 145.88,63.68 145.88,55.42 145.99,55.32 145.99,52.08 146.75,51.32 146.75,48.35 146.74,48.34 146.41,48.01 146.41,46.77 146.1,46.45 143.75,44.1 143.75,42.07 144.06,41.75 144.06,40.58 144.75,39.89 144.75,39.34 144.75,39.34 144.75,39.33 144.45,39.03 144.44,39.03 143.4,38 143.4,36.7 143.07,36.36 143.07,35.41 143.05,35.39 143.05,35.38 142.76,35.08 142.74,35.08 142.41,34.75 142.41,34.03 138.17,29.79 132.06,29.79 130.78,28.52 115.51,28.52 113.93,26.94 106.37,26.94 104.98,28.33 100.51,28.33 100.2,28.01 100.2,24.07 99.28,23.15 99.28,21.98 98.59,21.3 98.21,21.3 97.37,20.45 97.37,20.21 96.47,19.31 95.45,19.31 93.83,17.69 93.83,17.6 91.99,15.76 76.11,15.76 74.95,16.92 71.3,16.92 71.25,16.86 66.75,16.86 66.05,16.15 64.31,16.15 63.66,16.8 61.89,16.8 61.31,16.23 59.68,16.23 58.76,17.15 58.66,17.15 58.66,17.15 58.04,17.15 58.04,17.15 55.1,17.15 54.71,17.54 52.22,17.54 51.41,16.74 50.4,16.74 49,15.34 45.73,15.34 45.19,15.88 v1(45.19,15.89)
  BOTTOM w0.254: R2915.1 152,86.91 v1(152.37,87.29) ; v1(45.19,15.89) 45.02,15.71 42.61,15.71 PG4525.1
5V_S0: length 328.7
  TOP w0.508: R2427.1 66.05,26.08 v1(66.52,26.54) ; v1(145.65,29.14) 145.29,29.14 144.17,30.26 v2(143.79,30.26) v1(141.51,30.26) ; v1(113.53,28.59) 115.98,26.15 115.98,23.64 v2(116.48,23.14) 117.68,21.94 117.68,17.76 v1(114.3,14.37) ; v1(51.38,89.44) 51.16,89.44 50.44,90.15 44.4,90.15 40.35,86.09 24.22,86.09 21.41,83.29 v2(20.78,83.29) v3(19.93,83.29)
  L3 w0.508: v1(113.53,28.59) 113.34,28.4 106.96,28.4 105.57,29.78 98.93,29.78 97.43,28.29 97.43,25.5 97.43,25.13 96.08,23.79 94.11,23.79 91.83,21.51 89.84,21.51 88.78,20.44 72.98,20.44 70.74,22.67 70.74,25.23 70.09,25.89 69,25.89 68.93,25.95 67.04,25.95 66.52,26.47 v1(66.52,26.54) ; v1(51.38,89.44) 51.45,89.37 56.05,89.37 56.36,89.05 60.2,89.05 60.99,89.84 62.98,89.84 v3(63.85,88.96) ; v1(114.3,14.37) 112.6,16.07 101.36,16.07 100.76,15.47 99.21,15.47 v1(98.23,14.49) ; v3(150.72,43.97) 150.72,43.97 150.33,43.97 149.05,42.68 149.05,39.17 147.94,38.07 147.94,35.23 147.91,35.19 147.91,34.87 147.06,34.02 146.39,33.35 146.39,29.87 v1(145.65,29.14)
  L4 w0.508: v3(63.85,88.96) 63.85,88.98 68.13,88.98 71.64,92.49 76.49,92.49 77.24,93.24 77.24,97.21 78.63,98.6 86.95,98.6 91.21,94.34 94.42,94.34 95.65,93.11 97.54,93.11 102.38,88.27 104.81,88.27 105.2,88.66 109.16,88.66 110.62,90.11 116.76,90.11 117.53,89.35 119.97,89.35 120.58,89.96 124.41,89.96 125.31,90.85 129.4,90.85 v3(129.41,90.86) ; v1(113.53,28.59) 114.89,29.95 141.21,29.95 v1(141.51,30.26)
  BOTTOM w0.406: Q5701.2 16.38,65.61 16.7,65.93
  BOTTOM w0.508: 16.7,65.93 16.7,67.03 17.88,68.22 17.88,74.41 v2(18.48,75.01) 18.66,75.19 18.66,78.23 18.17,78.73 18.17,79.56 18.17,79.56 18.17,79.92 18.16,79.93 18.05,80.04 17.99,80.1 17.99,82.58 18.69,83.29 v3(19.93,83.29) 24.16,83.29 25.16,82.28 27.67,82.28 29.25,80.7 D5701.3 ; v1(98.23,14.49) 76,14.49 75.18,15.31 73.2,15.31 72.57,14.69 Q6501.E
  vias: v2(130.6,90.14) v2(147.29,81.15) v2(147.6,81.03) v2(149.68,46) v3(130.34,90.84) v3(145.15,73.91) v3(145.47,81.03) v3(145.8,74.44) v3(146.41,81.03) v3(147.47,82.22) v3(149.3,77.34) v3(150.12,77.56) v3(150.25,44.71) v3(150.65,46.38) v3(150.7,45.53)
5V_S0_CT: length 1.6
  BOTTOM w0.203: U4001.12 148.17,46.91 148.76,46.91 148.77,46.89 149.43,46.89 C4004.1
5V_S5: length 100.3
  TOP w0.508: PR5117.2 97.69,21.26 97.7,21.28 100.01,21.28 101.08,20.21 101.08,19.4 102.83,17.65 102.83,17.24 103.01,17.06 v2(103.01,13.85) 103.01,12.8 102.11,11.9 v1(102.11,11.57) ; v1(23.46,60.42) v2(24.23,59.65) 24.23,58.03 v1(23.66,57.45) 23.79,57.45 24.99,56.25 24.99,51.98 24.99,51.95 22.67,49.64 21.89,49.64 ; PR4303.1 29.9,65.3 v1(30.39,65.79)
  L3 w0.508: v1(31.77,74.67) 31.76,74.67 31.21,74.67 30.61,74.07 30.61,66 v1(30.39,65.79) ; v1(29.71,54.39) 29.72,54.4 32.47,54.4 33.05,53.82 33.93,53.82 v1(34.34,54.23)
  L4 w0.508: v1(23.46,60.42) 23.35,60.42 23,60.77 23,61.93 23.5,62.43 24.45,62.43 26.64,64.62 27.46,64.62 28.76,65.92 30.26,65.92 v1(30.39,65.79) ; v1(29.71,54.39) 29.7,54.4 28.86,54.4 26.08,57.18 25.05,57.18 24.77,57.45 v1(23.66,57.45) ; v1(22.71,38.08) 22.96,38.33 34.66,38.33 34.96,38.03 47.4,38.03 48.8,36.62 v1(48.8,36.24)
  BOTTOM w0.508: v1(31.77,74.67) 31.76,74.67 ; 31.76,74.67 31.76,75.92 32.87,77.03 PR4818.1 ; 31.76,74.67 31.76,74.67 31.48,74.67 31.07,75.09 31.07,75.09 30.82,75.35 PR4817.1 ; Q6404.E 8.64,16.35 v3(8.64,17.22) ; v3(14.03,15.85) 13.05,15.85 Q6403.E ; v1(48.8,36.24) 48.56,36.49 PC5401.1 48.08,37.42 PU5402.6 ; v1(34.34,54.23) PR4637.1
  vias: v2(16.16,65.7) v2(19.33,23.75) v2(20.38,14.44) v2(21.67,43.23) v2(23.36,32.86) v2(144.35,45.7) v3(13.01,78.91) v3(19.14,22.88) v3(19.14,21.48) v3(19.14,20.08) v3(19.14,18.69) v3(19.14,17.29) v3(20.03,23.58) v3(20.03,22.18) v3(20.03,20.78) v3(20.03,19.39) v3(20.03,17.99) v3(20.06,52.75) v3(20.42,51.92) v3(42.2,11.84) v3(144.4,43.57) v3(144.36,42.32) v3(144.94,47.36) v3(144.98,42.88) v3(145.03,41.79) v3(145.69,42.37) v3(152.16,78.42) v3(152.16,77.58)
5V_USB30: length 1.9
  BOTTOM w0.508: 14.48,58.91 USB1.1 15.48,58
  vias: v2(19.48,51.77)
12V_BT+:
  vias: v2(116,18.42) v2(118.58,18.12) v2(120.85,19.31)
19V_AD+: length 72.9
  TOP w0.508: v3(141.93,14.7) v2(139.52,17.11) 138.79,17.84 v2(133.52,17.84) 132.61,17.84 132.12,18.33 PR4408.1 128.21,18.33 127.5,17.62 126.56,17.62 125.07,16.12 v2(122.68,16.12) 121.47,16.12 120.98,16.61 ; PR4405.1 119.89,24.15 v1(120.08,23.96) 121.03,23.96 v2(121.48,23.51) 121.48,21.51 120.98,21.01 120.98,16.61 ; PR4407.1 126.55,10.08 122.86,10.08 121.84,11.1 119.33,11.1 v2(118.73,11.7) 117.78,12.65 117.78,14.73 119.08,16.03 120.41,16.03 120.98,16.61
  L4 w0.508: v1(140.41,35.1) 140.41,33.96 141.97,32.4 141.97,30.73 142.75,29.96 142.75,27.29 141.91,26.45 141.91,25.67 142.64,24.94 142.64,20.22 141.93,19.5 v3(141.93,14.7)
  BOTTOM w0.381: v1(120.08,23.96) 120.02,23.9 PU4403.4
  BOTTOM w0.508: PR4469.1 140.29,35.23 v1(140.41,35.1)
  vias: v2(146.38,12.7)
19V_DCBATOUT: length 21.9
  TOP w0.508: PR4827.1 35.97,74.61 36.89,75.54 40.07,75.54
  L4 w0.508: v1(142.58,26.1) 143.4,26.92 143.4,32.4 141.12,34.67 141.12,36.8 141.38,37.05 141.38,37.58 141.27,37.68 v1(141.27,37.87)
  BOTTOM w0.508: PR4512.1 v1(46.07,18.55) ; PR4607.1 34.41,62.2 PC4702.1 ; PR4468.1 140.58,38.29 140.92,37.95 141.2,37.95 v1(141.27,37.87)
  vias: v1(46.36,29.24) v2(36.62,66.76) v2(36.83,43.18) v2(37.15,79.68) v2(37.87,81.28) v2(43.55,24.07) v2(43.56,24.56) v2(44.42,31.62) v2(45.95,55.4) v2(80.82,21.21) v2(84.44,87.45) v2(117.64,26.78) v2(139.45,24.08) v2(141.98,23.38) v3(35.45,65.35) v3(35.45,64.26) v3(35.37,63.17) v3(36.19,69.37) v3(36.19,68.28) v3(36.57,65.37) v3(36.57,64.27) v3(37.21,82.94) v3(37.28,69.37) v3(37.28,68.28) v3(37.67,65.37) v3(38.32,82.94) v3(38.37,69.37) v3(38.37,68.28) v3(38.69,56.63) v3(39.41,82.93) v3(39.79,56.63) v3(43.84,31.16) v3(43.86,32.13) v3(44.78,25.98) v3(44.78,25.02) v3(44.78,24.05) v3(44.93,32.13) v3(44.93,31.16) v3(45.87,25.98) v3(45.87,25.02) v3(45.87,24.05) v3(46.02,32.13) v3(46.02,31.16) v3(80.48,22.5) v3(81.57,22.5) v3(82.67,22.5) v3(116.85,26.08) v3(116.9,24.97) v3(117.96,26.07) v3(118,24.97) v3(119.08,26.07) v3(119.09,24.97) v3(120.2,26.06) v3(120.18,24.97) v3(137.57,24.34) v3(138.22,23.35) v3(138.83,24.32) v3(139.35,23.34) v3(140.33,24.34) v3(140.53,23.26)
19V_DCBATOUT_LCD:
  vias: v2(44.98,83.09) v2(46.28,82.2) v3(45.96,82.97) v3(46.82,82.96)
+3V_1D5V_AVDD: length 6.4
  TOP w0.254: R2705.2 134.65,87.76 v1(133.98,87.09) v2(133.98,86.42)
  BOTTOM w0.203: 135.4,88.2 135.53,88.32 136.36,88.32 136.82,88.78 U2701.40
  BOTTOM w0.254: 135.4,88.2 135.12,87.91 C2715.1 134.67,87.28 134.49,87.09 v1(133.98,87.09)
+3V_AVDD: length 5.3
  TOP w0.254: v2(137.16,85.47) 137.13,85.47 136.73,85.07 v1(136.72,85.08) 135.82,85.08 R2713.2
  BOTTOM w0.203: U2701.36 137.76,86.76 137.53,86.52
  BOTTOM w0.254: C2701.1 136.02,85 136.65,85 v1(136.72,85.08) 136.77,85.08 137.19,85.49 137.19,86.19 137.53,86.52
+5V_AVDD: length 0.9
  BOTTOM w0.203: 142.61,85.96 142.28,86.28 U2701.26
  vias: v2(145.29,83.64) v2(145.94,85.51) v3(145.16,85.28)
DVDD_1D5V: length 7.4
  TOP w0.254: v1(141.97,94.33) 141.94,94.36 C2721.2 142.76,95.33 C2719.1 143.52,95.32 v2(144.04,95.85) 144.6,96.4 R2701.2
  BOTTOM w0.203: U2701.9 141.48,93.36 141.53,93.41 141.53,93.9 141.77,94.13
  BOTTOM w0.254: C2714.2 142.54,94.9 v1(141.97,94.33) 141.77,94.13
GND: length 738.1
  TOP w0.203: v1(33.96,78) 33.92,77.95 PU4802.11
  TOP w0.305: 56.87,93.45 U6901.5 ; 55.16,93.26 55.16,91.93 55.38,91.72 U6901.8 ; 10.82,76 HDMI1.8 9.9,76 9.53,76.38 ; v1(66.74,55.09) 66.48,54.83 R815.2 ; 9.53,73.41 9.93,73 HDMI1.2 10.64,73 ; 55.81,93.17 U6901.7 ; 56.37,93.16 U6901.6 ; HDMI1.11 9.47,77.5 ; PU4404.14 134.64,12.63 134.82,12.81 134.82,13.21 v1(134.96,13.35)
  TOP w0.381: EC1812.2 140.73,76.89 140.78,76.84 v1(140.92,76.84) ; v1(58.11,23.91) 58.11,24.15 57.82,24.44 EC1809.2 ; Q6507.1 45.8,4.94 v1(45.23,4.94) ; Q6507.4 47.13,6.12 47.49,5.77 48.68,5.77 v1(49.3,5.15)
  TOP w0.457: EC1002.2 62.27,42.77 63.66,41.38 v1(64.38,41.38)
  TOP w0.508: v1(63.4,26.42) 63.35,26.37 63.35,26.17 63.16,25.98 C2430.2 ; PR4819.2 v1(28.88,84.26) ; v1(22.63,50.62) 22.55,50.7 22.55,50.75 PR4619.2 ; v1(125.24,32.84) 124.7,33.38 R1210.2 ; v3(39.75,18) 39.36,17.62 EC6502.2 ; v1(109.94,24.67) 109.81,24.54 D4301.1 ; v1(88.57,86.49) 89.31,87.22 PR5003.2 89.31,87.61 PC5001.2 ; SD1.10 3.67,18.23 4.04,17.86 ; SD1.10 2.75,17.36 ; SD1.10 2.12,18.23 1.72,17.83 ; v1(89.18,49.14) 89.18,49.1 C1038.2 90.2,49.23 90.2,49.25 ; C4046.2 41.08,10.27 EC6501.2 40.18,11.16 v1(40.18,11.93) 40.18,12.59 C4050.2 ; v1(143.58,96.24) 143.56,96.21 C2719.2 142.76,96.22 C2721.1 ; v1(87.15,62.49) 86.67,62.96 R508.2 ; v3(37.9,24.82) 37.84,24.76 EC4308.2 ; v1(34.5,15.43) 34.5,15.86 EC4311.2 ; C1910.2 72.1,64.47 v1(72.29,64.67) ; PC5306.2 117.84,100.71 v1(117.87,100.71) 118.02,100.56 PC5301.2 ; v1(49.46,82.36) 49.46,82.24 50.27,81.43 R5505.1 ; v1(148.05,14.73) 148.62,15.31 PC4425.2 ; EC1803.2 65.6,60.81 v1(65.76,60.65) ; v1(131.36,87.57) 131.44,87.49 131.44,86.22 EC2707.2 ; PC4805.2 v1(29.72,84.26) ; v1(121.39,33.9) 121.39,33.08 C1212.2 ; SD1.11 3.6,34.64 ; R5703.1 16.83,81.98 v1(16.59,81.74) ; v1(131.03,100.32) 131.26,100.55 R2505.2 ; C1210.2 116.42,33.97 v1(115.89,33.44) 115.02,34.3 SPR4.1 ; v1(125.07,96.9) 125.97,96.9 R2717.2 ; C1204.2 123.61,40.22 v1(124.08,40.69) ; SPR5.1 108.05,79.45 113.52,79.45 v1(115.36,77.61) ; EC1205.2 127.78,55.18 C1215.2 127.79,54.37 v1(127.77,54.36) ; v1(121.49,53.64) 121.57,53.72 C1217.2 ; v1(98.32,20.64) 98.48,20.48 PC5116.2 ; R6903.1 57.72,94.1 v1(57.73,94.11) ; R1204.2 121.97,85.19 v1(121.6,84.81) ; v1(120.64,23.26) 120.57,23.2 119.4,23.2 PR4405.2 ; USB1.10 5.39,45.55 ; USB1.10 5.51,46.53 6.88,46.53 ; USB1.10 5.27,46.53 3.86,46.53 ; EC4301.2 v1(109.24,20.22) ; v1(123.77,78.99) 123.59,78.81 C1209.2 ; C6901.2 53.11,91.52 52.17,91.52 ; C1101.2 94.4,49.82 v1(94.36,49.86) ; PC4407.2 135.16,16.83 135.41,17.09 v1(135.42,17.09) ; R819.2 57.4,52.21 v1(57.6,52) 57.71,52 C1803.2 ; 9.68,83.26 HDMI1.20 ; HDMI1.20 9.68,85.24 ; HDMI1.20 11.39,84.25 ; C1223.2 121.39,46.12 v1(121.39,47.1) ; EC1206.2 118.91,63.01 118.9,63 C1214.2 118.83,63.58 118.25,64.16 117.53,64.16 v1(117.37,63.99) ; R1208.2 125.49,45.92 v1(125.65,46.08) ; v1(83.07,8.65) 83.07,9.24 83.45,9.62 DB1.3 ; EC3304.2 v1(16.69,42.54) ; v1(38,11.73) 38,11.2 EC6503.2 ; 14.48,50.22 USB1.4 ; USB1.4 14.48,51.78 ; USB1.4 15.25,51 ; C1802.2 61.81,45.31 v1(61.1,45.31) ; EC4403.2 121.78,13.56 v3(121.75,13.53) ; EC1201.2 129.47,40.24 v1(129.45,40.25) ; R6338.2 107.13,88.03 v1(107.12,88.03) ; PC4608.2 23.58,51.45 v1(24.13,51.99) ; PR4518.2 42.64,28.59 v3(43.15,29.11) ; v1(80.5,56.43) 80.5,56.49 EC503.2 ; EC4310.2 32.16,52.33 v3(31.95,52.12) ; EC2403.2 150.39,42.95 150.39,42.04 149.91,41.56 149.73,41.56 v1(149.73,41.55) ; 3.84,63.12 4.61,62.35 USB1.11 ; C1106.2 74.03,37.37 74.5,36.9 74.5,36.89 v1(74.61,36.78) ; R5507.1 58.33,81.52 57.55,81.52 EC5505.2 v1(57.53,82.26) ; v1(86.88,60.65) 86.63,60.65 R504.2 ; C1102.2 68.06,61.74 67.53,62.28 v1(67.41,62.28) ; EC1203.2 129.73,46.55 v1(129.73,46.55) ; v1(129.45,53.47) 129.44,53.47 C1211.2 ; EC4402.2 35.9,50.02 v1(35.43,49.55) ; v3(19.38,73.25) 20.83,71.8 PC4302.2 ; v1(51.36,11.96) 51.38,11.98 51.38,12.38 R2415.2 ; EC2709.2 141.49,97.22 v1(141.49,97.9) ; v1(54.95,80.79) 54.94,80.79 EC5506.2 ; 4.83,86.01 2.84,86.01 HDMI1.21 ; USB1.11 6.42,62.35 7.11,63.04 ; USB1.11 5.39,63.43 ; v1(33.16,65.23) 32.89,64.97 PC4615.2 ; C1216.2 129.97,64.2 v1(129.73,64.45) ; v1(61.74,50.36) 61.43,50.36 R812.2 ; R1641.1 76.18,38.72 R1617.2 76.18,39.65 76.62,40.09 v1(76.81,40.09) ; v1(129.42,71.33) 129.42,71.34 129.99,71.92 EC1204.2 ; v1(64.05,59.17) 64.47,59.58 R1859.1 ; PR4432.2 124.24,13.27 v1(123.73,12.76) ; PR5005.2 93.47,85 PC5007.2 93.89,84.29 v1(94.26,84.66) ; EC5503.2 36.22,59.37 v3(36.28,59.31) ; R2428.1 72.84,23.92 v3(73.19,23.56) ; C1221.2 124.39,84.67 v1(124.29,84.78) 123.66,85.4 C1213.2 ; v1(89.15,46.3) 88.67,46.78 C1049.2 ; v1(149.87,97.57) 150.57,97.57 EC2704.2 ; C1219.2 131.27,32.95 C1220.2 130.45,33.99 130.06,33.59 EC1202.2 129.08,33.59 R1206.2 129.07,32.98 v1(129.15,32.89) ; 13.63,61.08 13.63,61.61 USB1.13 12.76,62.48 11.59,62.48 11.2,62.87 ; R2706.2 149.71,84.26 v1(149.98,84.53) ; v1(154.74,92.78) 154.6,92.92 EC2705.2 ; v1(125.72,77.16) 125.91,76.98 R1211.2 ; C6305.2 110.5,92.34 110.5,91.77 v1(110.5,91.76) ; R6515.1 v1(99.63,14.4) ; v1(116.48,81.17) 116.48,81.45 C1205.2 ; C1207.2 123.1,48.6 v1(123.8,47.9) 124.66,47.04 C1203.2 ; v1(127.4,32.88) 127.4,33.34 C1201.2 ; v1(92.66,54.91) 92.61,54.86 C1143.2 ; EC4302.2 107,19.57 v1(107.04,19.53) ; EC5701.2 15.62,80.4 16.06,80.83 v1(16.35,80.83) ; v3(35.86,73.18) 35.86,73.29 35.38,73.78 PC4809.2 34.87,73.88 PC4806.1 ; v1(47.87,15.85) 47.87,16.54 PR4516.2 ; v3(122.69,13.56) 122.69,11.42 123.37,10.74 PR4433.2 ; v1(33.7,54.5) 33.89,54.69 EC4309.2 ; C6303.2 101.88,92.79 v1(101.44,92.35) ; v1(117.91,85.19) 118.44,84.66 C1206.2 ; EC4312.2 v1(35.37,4.47) ; PR5104.2 73.75,29.21 74.45,29.9 v1(74.67,29.9) ; EC2501.2 137.16,78.38 v1(137.16,78.84) ; C1144.2 83.68,54.2 v1(83.24,53.75) ; R1209.2 124.6,61.31 v1(124.33,61.03) ; DB1.11 v1(85.01,8.18) ; PR4833.2 36.02,79.56 PC4814.1 35.98,80.37 PR4822.2 35.98,81.59 v1(35.52,82.05) ; v1(26.12,83.67) 26.21,83.58 PR4828.2 ; C6902.2 52.22,90.43 ; DB1.1 v1(86.15,10.71) ; EC1103.2 115.26,87.02 C6301.2 115.76,87.69 v1(115.76,87.98)
  TOP w0.635: 2.7,66.86 HDMI1.23 4.03,67.85 ; HDMI1.22 9.68,70.74 ; HDMI1.22 11.39,69.75 ; HDMI1.22 9.68,68.76
  L3 w0.305: 9.37,77.5 HDMI1.11 ; 9.45,74.5 HDMI1.5
  L3 w0.508: SD1.11 2.8,33.77 2.44,34.14 ; SD1.11 3.6,34.64 ; SD1.11 4.21,33.77 4.55,34.11 ; 1.6,17.71 2.12,18.23 SD1.10 ; SD1.10 2.75,17.36 ; SD1.10 3.39,18.23 3.81,17.81 ; 9.68,83.26 HDMI1.20 ; HDMI1.20 9.68,85.24 ; HDMI1.20 11.39,84.25 ; 10.62,73 HDMI1.2 9.98,72.44 ; 4.03,86.15 HDMI1.21 1.37,86.15
  L3 w0.635: 4.03,67.85 HDMI1.23 2.7,66.86 ; 12.89,45.71 USB1.12 14.43,46.65 ; 9.68,70.74 HDMI1.22 9.68,68.76
  L4 w0.508: SD1.10 1.94,18.23 1.6,17.88 ; SD1.10 2.75,17.36 ; SD1.10 3.67,18.23 3.94,17.96 ; USB1.10 4.79,46.65 3.73,45.59 ; USB1.10 6.72,46.65 6.84,46.52 ; USB1.10 5.39,45.4 ; 2.44,34.19 2.85,33.77 SD1.11 ; 11.39,84.25 HDMI1.20 9.68,85.24 ; 4.62,34.22 4.18,33.77 SD1.11 ; SD1.11 3.6,34.64 ; 4.03,86.15 HDMI1.21 1.37,86.15
  L4 w0.635: HDMI1.22 9.68,70.74 ; HDMI1.22 11.39,69.75 ; HDMI1.22 9.68,68.76 ; 2.7,66.86 HDMI1.23 4.03,67.85
  BOTTOM w0.089: 102.76,90.07 102.76,89.64 102.51,89.39 102.38,89.39 102.26,89.52 102.26,90.07 U6301.N2 102.76,90.07
  BOTTOM w0.127: U6301.P6 U6301.N5 ; v1(107.02,92.07) 107.02,91.81 U6301.C4
  BOTTOM w0.203: RAM4.J2 123.4,83.57 123.81,83.98 123.81,84.5 124.05,84.74 124.24,84.74 v1(124.29,84.78) ; v1(124.16,71.64) 123.81,71.3 123.81,70.76 123.4,70.35 RAM2.J2 ; PU4601.11 30.98,57.25 v1(31.08,57.15) ; v1(59.45,8.33) 59.18,8.59 U2401.89 ; v1(109.08,92.89) 109.08,92.69 108.71,92.32 U6301.A6 ; CPU1.AA27 75.05,51.69 74.53,52.2 CPU1.Y24 ; U2401.18 63.18,26.2 v1(63.4,26.42) ; U2401.78 63.58,10.72 62.98,11.32 v1(62.81,11.32) ; U2401.5 57.98,24.04 v1(58.11,23.91) ; U4001.11 148.95,47.31 v1(149.04,47.4) ; v1(57.31,18.77) 57.23,18.77 57.09,18.91 U2401.116 ; v1(139.23,93.76) 139.23,93.6 139.48,93.34 U2701.4 ; v1(124.29,53.68) 124.24,53.64 124.2,53.64 123.81,53.25 123.81,52.87 123.4,52.46 RAM1.J2 ; RAM3.J2 123.4,39.26 123.81,39.67 123.81,40.42 v1(124.08,40.69) ; U2401.45 69.18,18.91 v1(69.15,18.94)
  BOTTOM w0.229: CPU1.BH52 93.59,51.73 CPU1.BG53 ; v1(64.05,59.17) 64.05,59.15 CPU1.R1
  BOTTOM w0.254: CPU1.BJ31 86.73,60.51 v1(86.88,60.65) ; 86.96,43.01 86.96,43.11 86.06,44.01 CPU1.AE53 ; v1(123.8,47.9) RAM1.J8 ; CPU1.K14 67.35,51.89 v1(67.52,51.72) ; CPU1.AU51 89.66,48.56 90.08,48.14 90.19,48.14 ; v1(82.58,39.53) 82.32,39.79 82.04,39.79 CPU1.N53 CPU1.N51 ; v1(117.92,76.56) 117.8,76.68 RAM4.B9 ; v1(90.3,57.93) 90.29,57.91 90.09,57.91 CPU1.BJ39 ; CPU1.W1 65.88,60.47 65.76,60.59 v1(65.76,60.65) ; 102.38,89.39 102.27,89.28 101.72,89.28 101.45,89.54 101.45,90.31 v1(101.48,90.34) ; v1(73.33,38.71) 73.63,38.71 CPU1.A43 ; v1(67.41,62.28) 67.8,62.28 67.94,62.13 ; CPU1.AN53 89.15,46.43 v1(89.15,46.3) ; CPU1.BG35 CPU1.BJ35 88.53,59.1 88.53,59.89 v1(88.61,59.97) ; RAM4.J8 123.77,78.97 v1(123.77,78.99) ; v1(62.2,57.46) 62.33,57.33 63.13,57.33 CPU1.L1 ; RAM1.A9 117,46.61 v1(117.39,46.21) 117.8,46.62 RAM1.B9 ; v1(85.06,42.26) CPU1.AA53 ; CPU1.BJ43 91.56,56.63 v1(91.8,56.63) ; v1(64.1,48.45) 64.13,48.45 CPU1.A15 ; v1(123.8,34.7) RAM3.J8 ; v1(84.01,40.71) 83.87,40.71 CPU1.U53 ; v1(123.78,65.77) 123.77,65.77 RAM2.J8 ; CPU1.C3 CPU1.B2 ; RAM3.B9 v1(118.26,33.05)
  BOTTOM w0.305: v1(117.4,38.7) RAM3.B3 ; v1(58.59,55.34) 58.7,55.45 CPU1.F1 ; CPU1.BD53 93.08,50.58 93.81,49.86 v1(94.36,49.86) ; RAM1.B3 117.7,51.5 117.44,51.24 117.42,51.24 v1(117.14,50.96) ; v1(92.66,54.91) 92.52,54.91 92.23,54.62 CPU1.BJ47 ; CPU1.A47 75.06,37.92 74.61,37.47 v1(74.61,36.78) ; CPU1.K12 66.64,52.29 v1(66.2,51.85) ; RAM1.G9 121.79,46.7 v1(121.39,47.1) ; v1(121.39,47.1) 121,46.71 RAM1.F9 ; v1(121.39,47.1) 121.79,47.5 RAM1.G8 ; RAM2.G8 121.79,65.4 v1(121.39,65) ; LCD1.21 56.1,85.08 v1(56.22,85.21) ; v1(65.99,50.21) 66.06,50.14 CPU1.D16 ; v1(175.77,90.5) WLAN1.18 ; RAM3.E2 119.98,39.32 119.98,39.6 120.2,39.82 RAM3.E1 120.2,40.05 v1(119.78,40.47) 119.4,40.09 RAM3.D1 ; CPU1.BG1 75.34,69.98 75.34,70.36 75.46,70.49 v1(75.46,70.51) 75.66,70.51 CPU1.BH1 75.99,69.96 CPU1.BH2 ; CPU1.AY32 83.43,56.53 83.38,56.58 v1(83.38,56.58) 83.31,56.65 82.85,56.65 82.77,56.73 ; v1(59.83,52.67) 59.88,52.62 CPU1.A5 ; 89.08,53.4 88.64,53.4 v1(88.5,53.53) ; v1(68,59.35) 67.87,59.22 67.4,59.22 ; v1(68,59.35) 68,59.82 CPU1.AB4 ; v1(68,59.35) 68.48,59.35 CPU1.AB6 68.58,59.97 v1(68.64,60.02) 68.67,60.02 68.9,60.26 CPU1.AD4 ; RAM2.D1 119.4,71.64 v1(119.19,71.85) ; CPU1.E51 78.87,38.48 v1(78.87,38.56) ; v1(121.39,33.9) 121,33.51 RAM3.F9 ; v1(121.39,33.9) 121.79,33.5 RAM3.G9 ; v1(121.39,33.9) 121.79,34.3 RAM3.G8 ; CPU1.G12 66,52.06 v1(66.2,51.85) ; v1(35.28,15.28) 35.5,15.06 TPAD1.4 ; v1(101.47,91.3) 101.5,91.32 U6301.P4 ; CPU1.BG53 93.76,51.55 94.85,51.55 v1(94.9,51.6) ; v1(66.2,51.85) 66.34,51.72 CPU1.G14 ; CPU1.J53 81.3,37.78 v1(81.51,37.78) ; v1(154.33,82.9) 154.33,82.3 154.08,82.05 IOBD1.32 ; CPU1.AY51 90.45,50.21 v1(90.68,50.44) 90.84,50.6 CPU1.BB50 ; CPU1.A7 60.88,51.61 60.75,51.74 60.74,51.74 v1(60.7,51.79) ; CPU1.BG40 89.06,55.76 v1(89.22,55.59) 89.35,55.47 CPU1.BF42 ; v1(117.37,63.99) 117.8,64.43 RAM2.B9 ; RAM2.B3 117.8,69.29 v1(117.34,68.84) ; PU5102.8 v1(98.34,22.18) ; CPU1.BA30 CPU1.AY30 83.21,57.17 82.77,56.73 ; CPU1.AT51 89.08,48.98 89.16,49.06 89.16,49.12 v1(89.18,49.14) 89.66,48.66 CPU1.AU51 ; CPU1.BG34 87.48,58.25 CPU1.BG35 ; v1(87.4,42.5) 87.4,42.57 86.96,43.01 ; Q1801.1 57.33,34.15 57.46,34.28 57.46,35.29 57.62,35.45 Q1801.4 ; CPU1.BG47 91.33,53.8 92.01,53.12 CPU1.BG49 92.08,53.12 v1(92.42,52.78) 92.08,52.44 CPU1.BF50 ; EC1810.2 63.2,30.75 R1828.2 62.55,31.69 61.91,32.32 61.91,33.02 61.81,33.12 Q1813.4 62.07,33.66 62.48,33.66 ; U6301.K8 104.3,93.32 104.44,93.18 104.94,93.18 v1(105.49,93.73) 105.9,93.32 105.9,93.19 106.26,92.82 U6301.E7 ; CPU1.BD1 74.51,68.79 v1(74.15,69.16) ; RAM4.B3 116.48,81.28 v1(116.48,81.17) ; v1(154.97,82.91) 154.97,83.02 154.44,83.55 IOBD1.29 ; CPU1.BG35 CPU1.BE35 CPU1.BD35 86.19,56.71 85.87,56.38 85.81,56.38 CPU1.BB35 CPU1.BA35 85.1,55.84 CPU1.AY34 84.6,55.34 CPU1.AW35 CPU1.AV35 CPU1.AT35 83.68,54.19 v1(83.24,53.75) 83.28,53.75 83.28,53.74 83.32,53.74 83.4,53.66 CPU1.AT36 ; CPU1.BG35 87.68,58.05 CPU1.BG36 87.82,57.44 v1(87.82,57.04) 87.97,56.88 CPU1.BG38 ; RAM1.E2 v1(119.8,51.9) ; v1(121.39,65) 121,64.61 RAM2.F9 ; v1(121.39,65) 121.79,64.6 RAM2.G9 ; v1(105.25,94.81) 105.01,94.57 U6301.H10 ; v1(61.01,37.57) 60.51,37.07 Q1813.1 ; v1(121.39,78.2) 121.79,78.6 RAM4.G8 ; v1(121.39,78.2) 121,77.81 RAM4.F9 ; v1(121.39,78.2) 121.79,77.8 RAM4.G9 ; v1(72.98,65.35) 72.6,65.73 72.59,65.73 ; v1(61.74,50.36) 61.89,50.22 CPU1.A11 ; U6301.P6 101.55,92.32 101.52,92.35 v1(101.44,92.35) ; CPU1.BB4 75.46,66.91 v1(75.52,66.96) ; 170.47,82.25 WLAN1.51 169.31,82.25 ; v1(74.34,66.73) 74.14,66.52 CPU1.AY3 ; U6301.G5 105.51,91.99 105.32,92.18 105.32,92.18 105.1,92.4 v1(105.04,92.4) 104.74,92.4 104.51,92.17 U6301.J5 ; CPU1.B2 60.13,53.85 59.64,53.85 v1(59.44,54.05) 59.78,54.39 CPU1.C1 ; 169.3,76.25 WLAN1.75 170.47,76.25 ; RAM2.P1 127.66,71.26 v1(127.66,72.14) ; v1(127.01,65) 127.4,64.61 RAM2.P9 ; CPU1.BF32 85.9,58.77 v1(85.67,59) 85.62,59.05 CPU1.BG30 ; v1(69.42,64.06) 69.42,64.01 69.32,63.91 CPU1.AJ1 CPU1.AJ3 ; CPU1.Y29 75.6,51.67 CPU1.AA27 ; 82.77,56.73 CPU1.AV30 ; RAM4.P1 127.65,84.45 127.65,85 v1(127.26,85.38) ; 170.47,80.75 WLAN1.57 169.31,80.75 ; 169.29,77.75 WLAN1.69 170.47,77.75 ; v1(72.29,64.67) 72.23,64.61 CPU1.AP4 ; 170.47,79.25 WLAN1.63 169.32,79.25 ; v1(67.52,51.72) 67.57,51.66 CPU1.K16 ; CPU1.AN3 CPU1.AN1 ; v1(127.77,54.36) 127.65,54.23 127.65,53.35 RAM1.P1 ; RAM2.M1 125.8,71 v1(126.2,70.6) ; LCD1.28 59.6,84.74 v1(60.05,85.19) 60.1,85.14 LCD1.29 ; CPU1.AD21 74.04,54.94 v1(74.02,54.92) ; CPU1.AY47 89.14,51.41 89.14,51.88 89.08,51.94 v1(89.08,52.01) 89.05,52.01 88.96,51.92 88.77,51.92 88.76,51.91 88.62,51.91 CPU1.AY45 ; CPU1.BC40 87.67,55.04 87.46,55.25 v1(87.46,55.28) 87.4,55.28 87.19,55.49 CPU1.BC38 ; RAM4.E1 v1(120.2,84.82) ; RAM1.E1 RAM1.D1 119.03,53.47 v1(119.03,53.69) ; v1(85.79,52.53) 85.79,52.85 86.04,53.1 CPU1.AV40 86.64,53.16 86.67,53.19 ; EU3501.8 EU3501.3 18.34,44.03 v1(18.28,44.1) ; v1(127.77,41.16) 127.65,41.03 127.65,40.15 RAM3.P1 ; CPU1.M14 CPU1.K14
  BOTTOM w0.356: v1(129.45,53.47) 129.08,53.1 RAM1.T1 ; RAM4.E8 120.2,78.59 119.8,78.19 ; RAM2.E2 RAM2.E1 RAM2.D1 ; v1(115.36,77.61) 115.55,77.8 RAM4.A9 ; v1(121.49,53.64) 121.8,53.34 RAM1.G1 ; v1(129.73,64.45) 129.58,64.6 RAM2.T9 ; RAM3.B1 117.8,40.59 v1(118.22,41.01) ; RAM2.B1 117.8,71.62 118.24,72.07 v1(118.24,72.43) ; Q1814.4 58.83,47.17 v1(58.28,47.72) ; 119.8,64.99 119.4,65.39 RAM2.D8 ; 119.8,64.99 v1(119.8,65.01) ; 119.8,64.99 120.2,65.39 RAM2.E8 ; RAM2.M9 125.8,64.13 v1(125.65,63.98) ; RAM3.A9 115.95,33.5 v1(115.89,33.44) ; RAM3.T1 129.08,39.9 129.45,40.27 v1(129.45,40.25) ; RAM1.P9 127.25,46.7 127.03,46.92 127.03,47.08 v1(127.01,47.1) ; RAM3.D8 119.4,34.29 119.8,33.89 ; v1(129.57,84.38) 129.18,84.38 RAM4.T1 ; RAM4.P9 127.03,78.17 127.03,78.18 v1(127.01,78.2) ; v1(12.83,65.08) 12.94,64.96 Q5701.4 ; v1(125.24,32.84) 125.24,32.98 125.77,33.5 RAM3.M9 ; RAM4.T9 129.58,77.8 v1(129.73,77.65) ; RAM1.M9 125.8,46.23 v1(125.65,46.08) ; RAM4.B1 117.8,85.08 v1(117.91,85.19) ; v1(125.72,77.16) 125.8,77.24 RAM4.M9 ; RAM3.P9 127.4,32.89 v1(127.4,32.88) ; RAM2.G1 121.39,71.41 v1(121.39,71.66) ; RAM3.G1 121.8,40.06 v1(121.33,40.53) ; RAM4.D1 RAM4.E1 RAM4.E2 ; 119.8,33.89 120.2,34.29 RAM3.E8 ; 119.8,33.89 v1(119.8,33.91) ; RAM3.T9 129.15,33.35 v1(129.15,32.89) ; v1(119.8,47.11) 119.8,47.09 ; 119.8,47.09 120.2,47.49 RAM1.E8 ; 119.8,47.09 119.4,47.49 RAM1.D8 ; RAM1.B1 117.8,53.83 117.19,54.44 v1(116.94,54.44) ; RAM2.A9 117,64.36 v1(117.37,63.99) ; RAM1.T9 129.58,46.7 v1(129.73,46.55) ; v1(121.6,84.81) 121.6,84.79 121.8,84.59 RAM4.G1 ; Q1810.4 58.23,41.62 58.23,41.34 58.04,41.15 v1(57.65,41.15) ; v1(129.42,71.33) 129.09,71 RAM2.T1 ; 119.8,78.19 119.4,78.59 RAM4.D8 ; 119.8,78.19 v1(119.8,78.21)
  BOTTOM w0.381: Q4014.1 141.95,42.42 141.94,42.42 v1(141.52,41.99) ; v1(143.35,39.83) 143.35,39.92 143.43,40 Q4014.4 ; v1(126.26,85.61) 125.8,85.15 RAM4.M1 ; RAM3.M1 125.8,39.9 v1(126.2,39.5) ; v1(126.3,54.03) 125.8,53.53 RAM1.M1 ; Q4016.4 136.16,52.46 136.62,52 137.24,52 137.46,51.78 Q4016.1 138.17,51.18 ; TPAD1.9 v1(40.18,11.93) ; PR4470.1 134.14,29.6 134.62,30.07 PQ4410.4 135.13,30.19 135.67,30.73 135.67,31.3 135.85,31.47 136.48,31.47 PQ4410.1
  BOTTOM w0.406: PQ4402.4 148.03,25.21 v1(148.6,24.65) ; Q4001.1 142.53,37.55 141.96,36.98 v1(141.96,36.73) ; Q5701.1 15.62,66.92 v1(15.69,66.99) ; v1(11.15,36.12) 11.38,35.89 C3307.2 ; v1(148.17,28.17) 148.64,27.7 149.18,27.7 PQ4402.1 ; TPAD1.10 v1(29.82,11.89) ; v1(59.74,38.86) 59.74,39.54 Q1810.1 ; Q1801.4 58.55,35.92 58.34,36.12 ; PQ4408.1 149.36,22.19 149.1,21.92 149.1,21.12 148.86,20.88 PQ4408.4 148.04,20.88 147.54,20.38 v1(147.02,20.38) ; U2901.1 150.38,85.76 150.66,85.48 C2901.2 151,85.37 151.37,85.74 v1(151.37,86.07) ; v1(19,15.41) 19.58,15.41 20,14.99 LED1.4 ; v1(51.35,26.11) 51.8,26.56 U2404.2 ; v1(136.5,32.3) PQ4410.1
  BOTTOM w0.508: Q4017.S 136.81,44.95 133.9,44.95 133.54,44.59 132.46,44.59 EC1108.2 ; v1(143.15,49.02) 143.15,48.59 C4051.2 ; v1(136.72,86.45) 135.89,86.45 C2701.2 ; v1(65.4,83.38) 65.69,83.09 65.69,83.07 EC5510.2 ; 58.78,28.98 57.87,29.89 EC1814.2 57.87,30.61 57.94,30.67 57.94,30.68 57.98,30.71 57.98,31.24 57.94,31.28 57.94,31.76 C1801.2 ; EC3303.2 19.03,40.73 v1(19.63,41.34) ; R3311.2 8.78,42 v1(8.62,42.17) ; v1(36.25,39.67) 36.73,40.15 PC5225.2 36.46,40.94 35.39,42.01 PR5213.1 ; v1(21.59,54.32) 21.59,54.29 21.78,54.47 U3601.2 ; C1222.2 135.82,54.89 137.2,56.27 139.38,56.27 141.14,58.03 141.14,58.6 141,58.74 v1(141,60.39) ; R4005.2 149.73,41.07 v1(149.73,41.55) ; PC4617.1 33.24,56.59 v1(33.12,56.72) ; v1(19.39,24.81) 19.55,24.96 C3301.2 C3302.2 C3303.2 ; R4011.1 149.2,29.19 v1(149.2,30.06) 148.95,30.3 Q4020.S ; v1(52.21,47.99) 52.62,47.99 X1601.4 ; Q2401.C 54.78,3.53 v1(54.4,3.15) ; R1522.2 R1524.2 89.06,40.93 v1(88.94,40.93) ; Q2502.S 131.95,99.93 131.42,99.93 v1(131.03,100.32) ; v1(77.62,13.31) 77.83,13.1 KB1.32 ; R2468.2 70.99,9.68 v1(70.53,10.14) ; v1(142.14,35.21) 142.32,35.21 142.84,34.68 PR4474.2 ; EC2904.2 v1(96.33,93.97) ; R2530.1 133.12,60.21 ; 133.12,60.21 133.1,60.21 131.3,62.01 131.3,64.05 130.91,64.44 129.74,64.44 v1(129.73,64.45) ; 133.12,60.21 EC1106.2 ; C6304.2 95.45,89 95.25,89.2 v1(95.25,89.31) ; PC4538.2 PR4517.2 v1(44.09,28.58) ; C2439.2 59.17,6.25 59.12,6.25 v1(58.82,5.95) ; PC4610.1 32.7,62.48 v1(32.91,62.68) ; v1(51.54,42.62) 52.55,41.61 PC5402.2 ; 7.04,62.97 6.54,62.47 5.51,62.47 USB1.11 ; EC2903.2 95.81,96.82 96.19,97.2 96.19,97.49 v1(96.17,97.51) 96.06,97.62 EC2902.2 ; EC2901.2 97.46,100.52 v1(98.35,99.62) ; v1(14.17,14.89) 14.22,14.89 EC6428.2 ; SD1.11 4.33,33.77 4.78,34.22 ; SD1.11 3.6,34.64 ; SD1.11 2.75,33.77 2.36,34.16 ; LED1.6 16.98,11 16.55,10.57 v1(16.55,9.2) ; SD1.4 v1(15.43,27.9) ; v1(19.32,67.08) 19.32,66.85 18.87,66.39 PQ4304.2 18.7,66.39 18.58,66.39 18.06,65.86 v1(17.98,65.86) ; 140.38,66.03 141.22,66.03 v1(141.27,65.98) ; 140.38,66.03 139.56,66.03 EC2502.2 ; 140.38,66.03 EC2503.2 ; C1806.2 52.17,51.65 v1(52.16,51.65) ; PC5000.2 35.38,47.19 PR5010.2 35.38,46.99 35.15,46.76 v1(35.15,46.48) ; v1(89.38,38.01) 89.16,38.01 R1526.2 ; USB1.11 5.25,62.49 4.45,62.49 3.89,63.04 ; USB1.11 5.39,63.46 ; PC5119.2 95.3,22.05 v1(94.71,22.05) ; v1(24.13,51.99) 24.48,52.34 PR4615.2 ; v1(60.99,3.01) Q2403.S ; R1504.2 93.12,38.47 v1(93.49,38.1) 94.04,38.65 R1508.2 ; v1(94.18,85.29) 92.75,86.73 PR5002.2 ; v1(138.16,36.18) 138.16,36.53 137.49,37.2 PR4467.2 ; PC5111.2 98.24,24.28 v1(98.64,23.88) ; C3306.2 v1(8.02,39.24) ; v1(74.61,36.78) 74.61,35.87 R1611.2 ; PQ4302.E 32.49,65.9 33.16,65.24 v1(33.16,65.23) 33.18,65.25 33.18,65.39 33.66,65.88 33.66,67.26 PC4823.2 ; v1(117.87,100.71) 117.1,100.71 116.87,100.48 116.87,99.58 117.33,99.12 PU5301.2 119.35,99.12 120.07,99.84 PC5326.2 ; C2446.2 52.54,24.33 53.01,24.33 v1(53.08,24.26) ; v1(43.92,25.76) 43.39,26.28 PC4508.2 PC4530.2 ; v1(116.29,19.22) 116.94,19.22 EC4303.2 ; v1(77.8,30.18) 77.8,30.09 PC5110.2 ; PQ4414.S 143.08,31.26 v1(142.73,30.9) ; v3(37.9,24.82) 37.86,24.86 37.86,25.07 37.86,25.08 PC4535.2 ; HDMI1.20 9.68,85.24 ; HDMI1.20 9.68,83.26 ; HDMI1.20 11.39,84.25 ; USB1.10 5.39,45.55 ; USB1.10 5.52,46.52 7.12,46.52 ; USB1.10 5.27,46.53 3.95,46.53 ; v1(55.08,29.62) 55.08,30.15 C2445.2 ; v1(55.08,29.62) 55.08,28.95 C2432.2 ; v1(55.08,29.62) 54.44,29.62 C2433.2 ; v1(72,22.97) 72,22.54 C2443.2 ; PC4604.2 25.39,60.36 25.93,59.82 v1(26.19,59.82) ; v1(21.18,46.78) 21,46.97 EU3505.2 ; v1(44.79,78.24) 45.55,78.24 Q5506.S ; R1513.2 91.19,41.94 89.98,41.94 v1(89.91,41.87) ; v1(74.67,29.9) 74.15,29.9 PR5106.1 ; R1515.2 93.44,42.51 93.14,42.51 v1(93.13,42.5) ; v1(140.92,76.84) 140.86,76.89 140.86,76.98 140.54,77.3 SSKT1.4 ; C2505.2 135.55,65.74 C2502.2 136.16,66.35 C2501.2 136.16,67.48 135.61,68.04 135.61,71.6 136.51,72.49 137.28,72.49 139.4,74.62 v1(139.4,74.86) ; v1(129.73,77.65) 130.69,76.69 EC1105.2 ; C3606.2 22.68,50.68 v1(22.63,50.62) ; v1(137.4,43.3) 137.4,42.5 136.65,41.76 Q4015.S 135.75,41.57 EC1107.2 ; C2444.2 50.29,5.15 v1(49.3,5.15) ; v1(53.53,48.82) 54.61,48.82 C1807.2 55.46,49.04 56.19,48.31 C1601.2 ; PR4643.2 v1(34.07,56.8) ; 58.34,36.12 57.67,36.79 R1861.2 56.78,36.79 v1(56.67,36.68) ; v3(39.45,15.04) PC4520.2 ; R2438.2 52.8,11.91 52.04,11.91 C2417.2 51.42,11.9 v1(51.36,11.96) ; PC1123.2 95.51,48.71 v1(94.36,49.86) ; v1(111.15,94.68) 111.15,95.66 112.11,96.62 114.19,96.62 C6302.2 ; 14.48,61.52 13.65,62.35 USB1.13 12.53,62.71 11.04,62.71 ; 139.23,94.49 v1(139.23,93.76) ; v3(39.75,18) 39.56,17.81 PC4524.2 ; v3(140.87,53.91) 139.87,52.9 EC2402.2 139.37,52.9 138.94,52.47 R4008.1 138.17,51.18 ; R5502.2 54.6,83 54.87,83.27 v1(55.03,83.27) ; C2606.2 73.14,80.25 72.66,80.73 v1(72.39,80.73) ; PR4684.2 29.74,53.13 v1(29.74,52.56) 29.2,52.56 PC4603.2 ; v1(6.02,16.46) 5.74,16.18 EC6427.2 ; v1(28.25,11.74) 27.51,11 LED1.5 ; C5514.2 70.22,83.68 v1(69.93,83.97) ; C1602.2 56.19,44.91 v1(55.69,44.41) 55.37,44.41 X1601.2 ; v1(140.01,32.36) 139.64,32 PR4464.2 ; Q4001.4 144.35,36.12 v1(144.68,35.79) ; v1(33.7,54.5) 32.85,54.5 PR4644.2 ; v1(53.64,8.96) 53.64,8.61 53.38,8.35 R2613.2 ; v1(98.32,20.64) 98.24,20.57 PC5120.2 ; v1(49.45,36.25) 49.45,36.37 49.45,36.37 49.45,36.94 PC5401.2 ; v1(53.92,32.2) 53.92,31.62 R2419.2 ; Q3301.S v1(7.86,41.8) ; Q5707.S 21.61,64.37 v1(21.83,64.59) 24.42,64.59 PD4303.1 ; v1(147.02,20.38) 147.02,20.21 PR4436.2 ; 1.37,86.15 HDMI1.21 4.53,86.15
  BOTTOM w0.635: HDMI1.22 9.68,70.74 ; HDMI1.22 9.68,68.76 ; HDMI1.22 11.39,69.75 ; 12.89,45.71 USB1.12 14.43,46.65 ; HS3.1 69.64,72.52 ; HS3.1 66.45,75.71 ; HS3.1 66.45,69.33 ; HS3.1 63.26,72.52 ; 66.45,30.54 HS4.1 ; HS4.1 63.26,33.73 ; HS4.1 69.64,33.73 ; 4.03,67.85 HDMI1.23 2.7,66.86
  BOTTOM w0.762: v3(91.21,81.05) 91.55,81.39 PC5009.2 ; DCIN1.8 v1(27.78,81)
  vias: v1(3.8,35.83) v1(9.23,38.32) v1(10.13,12.38) v1(11.93,44.5) v1(11.87,42.96) v1(13.21,40.77) v1(13.5,44.49) v1(14.05,60.33) v1(14.1,41.53) v1(14.1,40.77) v1(14.1,39.88) v1(14.79,72.64) v1(14.94,71.17) v1(14.99,40.77) v1(14.98,30.47) v1(15.41,45.33) v1(15.68,22.85) v1(15.75,24.77) v1(16.07,77.02) v1(16.4,78.84) v1(17.53,50.88) v1(17.53,48.97) v1(17.51,39.13) v1(18.14,40.03) v1(18.3,47.32) v1(18.31,45.37) v1(18.84,82.52) v1(18.97,30.94) v1(18.98,30.25) v1(19.1,39.93) v1(19.34,76.64) v1(19.61,82.52) v1(19.81,64.72) v1(19.94,79.31) v1(19.9,78.5) v1(19.86,60.86) v1(19.86,60.23) v1(19.86,58.19) v1(20.15,75.39) v1(20.34,36.89) v1(20.7,66.04) v1(21.36,42.14) v1(23.74,45.79) v1(23.8,43.94) v1(26.5,46.33) v1(26.62,70.36) v1(26.62,69.48) v1(27.26,47.87) v1(27.74,57.25) v1(28.37,57.89) v1(28.37,57.25) v1(28.37,56.62) v1(29.01,57.25) v1(29.01,46.54) v1(28.98,44.46) v1(29.06,70.85) v1(29.29,74.23) v1(29.87,77.95) v1(30.89,78.97) v1(30.89,77.95) v1(30.89,76.94) v1(31.9,77.95) v1(32.73,82.14) v1(35.39,43.97) v1(37.52,30.17) v1(39.8,6.64) v1(39.77,4.17) v1(40.43,30.38) v1(41.74,20.47) v1(42.64,40.84) v1(43.27,40.84) v1(45.17,10.36) v1(45.31,12.12) v1(45.94,15.85) v1(46.13,51.97) v1(46.6,15.85) v1(47.23,15.85) v1(47.93,86.21) v1(48.08,82.29) v1(48.69,31.02) v1(48.87,32.59) v1(49.56,85.19) v1(49.99,20.45) v1(50.77,58.29) v1(51.15,85.2) v1(51.4,83) v1(52.93,85.35) v1(53.17,81.81) v1(54.39,85.23) v1(56.58,41.99) v1(57.62,85.31) v1(58.57,88.37) v1(59.59,28.88) v1(60.85,83.39) v1(61.38,82.91) v1(62.69,64.89) v1(62.99,34.57) v1(63.42,51.98) v1(63.81,55.22) v1(63.84,46.12) v1(64.01,53.04) v1(64.46,46.2) v1(65.45,57.78) v1(66.12,41.88) v1(66.97,45.62) v1(67.94,40.66) v1(68.96,58.37) v1(69.13,42.41) v1(69.44,57.79) v1(69.49,35.71) v1(69.9,57.38) v1(69.9,41.14) v1(70.51,36.93) v1(70.71,54.86) v1(70.75,52.67) v1(70.94,35.08) v1(71.03,60.41) v1(71.01,44.31) v1(71.48,59.96) v1(71.55,51.68) v1(71.47,44.81) v1(71.64,43.62) v1(71.65,37.7) v1(72.13,72.48) v1(72.15,71.76) v1(72.32,42.87) v1(72.26,40.75) v1(72.76,64.18) v1(72.8,60.15) v1(73.11,42.22) v1(73.28,59.64) v1(73.87,63.18) v1(74.06,64.32) v1(74.26,62.67) v1(75.02,44.23) v1(75.34,65.79) v1(75.4,41.89) v1(75.9,42.28) v1(76.2,54.98) v1(76.16,7.57) v1(76.48,45.7) v1(76.62,33.05) v1(76.92,34.76) v1(77.66,62.17) v1(77.72,46.81) v1(77.78,50.07) v1(77.9,16.27) v1(78.32,62.62) v1(78.32,50.63) v1(78.42,55.02) v1(78.63,64.4) v1(78.79,34.5) v1(78.78,25.12) v1(78.89,63.2) v1(78.86,59.05) v1(78.94,35.93) v1(78.9,33.1) v1(78.97,55.58) v1(79.31,59.55) v1(79.32,30.51) v1(79.54,65.26) v1(79.5,62.47) v1(79.45,58.32) v1(79.76,64.06) v1(79.79,60) v1(80.02,45.8) v1(80.05,62.99) v1(80.17,67.85) v1(80.34,64.63) v1(80.26,40.11) v1(80.53,45.36) v1(80.56,63.49) v1(80.65,66.76) v1(80.68,42.41) v1(80.93,61.03) v1(80.99,65.99) v1(81,63.95) v1(81.11,34.68) v1(81.18,41.94) v1(81.26,48.82) v1(81.4,61.6) v1(81.55,88.49) v1(81.59,85.09) v1(81.55,60.35) v1(81.56,31.6) v1(81.61,26.45) v1(81.71,55.11) v1(81.85,62.04) v1(81.79,59.11) v1(82.02,60.89) v1(82.15,90.58) v1(82.19,53.43) v1(82.33,62.5) v1(83.09,65.08) v1(83.34,44.07) v1(83.36,31.24) v1(83.78,63.29) v1(83.88,47.54) v1(84.05,32.29) v1(84.38,47.1) v1(87.02,49.86) v1(87.53,44.79) v1(91.16,45.57) v1(92.15,47.19) v1(93.69,48.83) v1(94.07,31.94) v1(95.59,57.56) v1(95.75,75.49) v1(95.83,66.41) v1(96.85,44.75) v1(97.89,70.72) v1(97.98,74.32) v1(99.77,82.86) v1(100.43,83.47) v1(100.86,22.18) v1(101.23,83.85) v1(101.57,22.89) v1(101.57,22.18) v1(101.57,21.46) v1(102.29,22.18) v1(103.37,18.96) v1(104.03,18.95) v1(106.47,15.32) v1(107.3,15.32) v1(109,23.86) v1(109.59,21.71) v1(110.05,22.3) v1(110.58,24.91) v1(111.39,24.94) v1(112.94,20.52) v1(112.94,19.88) v1(112.94,19.25) v1(113.23,95.3) v1(113.21,89.46) v1(113.51,65.18) v1(113.57,64.53) v1(113.77,24.96) v1(114.55,24.96) v1(115.27,24.99) v1(126.09,11.02) v1(127.91,87.33) v1(129.8,92.24) v1(130.27,91.79) v1(131.12,89.5) v1(131.12,88.85) v1(138.26,97.28) v1(138.36,27.84) v1(139,27.84) v1(139.18,67.88) v1(139.47,89.78) v1(139.63,27.84) v1(140.27,27.84) v1(140.48,90.8) v1(140.48,89.78) v1(140.48,88.76) v1(140.88,101.4) v1(140.93,44.72) v1(140.9,27.84) v1(141.52,101.4) v1(141.5,89.78) v1(141.54,27.84) v1(143.72,60.24) v1(143.81,77.74) v1(143.93,76.38) v1(144.41,101.4) v1(145.17,101.4) v1(147.22,52.23) v1(147.3,45.58) v1(147.32,44.9) v1(147.72,51.74) v1(149.68,79.58) v1(150.81,48.69) v1(151.57,80.14) v1(151.97,89.59) v1(157.31,100.08) v1(158.04,74.22) v1(158.27,99.15) v1(158.69,74.22) v1(159.17,101.96) v1(161.29,85.15) v1(163.34,85.73) v1(163.66,101.98) v1(164.73,84.87) v1(165.22,85.99) v1(167.92,86.87) v1(168.12,85.4) v1(168.45,83.47) v1(168.45,80.72) v1(168.5,79.17) v1(168.63,95) v1(168.71,92.86) v1(168.68,82.17) v1(168.66,77.75) v1(168.67,76.17) v1(173.84,95.45) v2(18.12,11.91) v2(19.2,7.93) v2(28.13,34.18) v2(31.55,76.7) v2(33.58,82.89) v2(37.48,74.69) v2(39.48,36.49) v2(41.82,89.8) v2(48.18,21.34) v2(48.32,91.51) v2(67.73,48.06) v2(68.56,59.06) v2(71.35,43.09) v2(74.86,45.81) v2(89.31,20.69) v2(94.15,72.13) v2(96.95,73.38) v2(107.54,11.14) v2(109.1,15.42) v2(109.23,22.98) v2(117.07,29.97) v2(132.86,29.96) v2(136.98,18.01) v2(138.7,90.53) v2(140.36,57.48) v2(141.65,26.68) v3(1.13,40.67) v3(1.13,37.37) v3(1.13,34.32) v3(1.23,6.2) v3(1.34,9.29) v3(1.28,1.27) v3(1.43,66.4) v3(1.43,65.04) v3(2.22,36.04) v3(3.18,46.24) v3(3.19,43.4) v3(3.94,63.88) v3(4,41.02) v3(4.38,65.18) v3(4.42,6.26) v3(4.75,44.15) v3(5.08,86.73) v3(5.13,67.85) v3(6.09,86.69) v3(6.13,1.25) v3(6.54,65.41) v3(6.5,8.95) v3(7.31,66.97) v3(7.82,86.69) v3(7.94,64.33) v3(7.98,62.6) v3(9.55,86.69) v3(9.47,62.6) v3(10.1,63.63) v3(11.27,86.69) v3(13,86.69) v3(14.73,86.69) v3(15.25,1.26) v3(16.45,86.69) v3(16.83,6.84) v3(18.12,3.09) v3(18.18,86.69) v3(21.71,3.34) v3(22.12,1.28) v3(24.53,25) v3(25.02,15.83) v3(25.18,26.09) v3(25.36,34.22) v3(25.53,15.06) v3(25.73,33.46) v3(25.72,25) v3(26.31,26.09) v3(26.54,34.2) v3(26.56,25) v3(26.83,15.8) v3(27.09,33.46) v3(27.3,15.06) v3(27.49,26.11) v3(27.75,25) v3(28.85,26.05) v3(28.88,24.99) v3(29.08,1.16) v3(31.2,46.18) v3(32.04,46.17) v3(32.92,52.12) v3(33.86,52.12) v3(34.53,45.44) v3(35.38,45.34) v3(36.34,73.94) v3(36.29,58.44) v3(36.75,73.18) v3(37.12,59.32) v3(37.13,58.46) v3(37.16,87.58) v3(37.62,73.1) v3(38.05,89.2) v3(38.31,95.83) v3(38.31,94.1) v3(38.31,92.37) v3(38.31,90.64) v3(38.46,73.1) v3(38.67,20.29) v3(39.34,72.86) v3(39.56,24.63) v3(40.67,36.14) v3(40.87,95.88) v3(41.51,36.14) v3(41.62,76.33) v3(41.63,75.47) v3(41.78,58.31) v3(42.2,57.57) v3(42.46,76.3) v3(42.47,75.43) v3(42.62,58.31) v3(42.63,36.14) v3(42.65,53.28) v3(42.95,30.54) v3(43.06,57.56) v3(43.34,76.3) v3(43.36,84.09) v3(43.36,75.43) v3(43.51,58.31) v3(43.53,53.28) v3(43.47,36.14) v3(43.51,29.89) v3(43.92,95.88) v3(44.28,20.64) v3(44.36,58.31) v3(44.6,36.15) v3(44.73,44.07) v3(44.65,43.23) v3(44.72,29.84) v3(45.14,8.12) v3(45.17,85.77) v3(45.19,42.57) v3(45.44,87.79) v3(45.44,36.15) v3(46.07,85.74) v3(46.96,95.88) v3(48.3,49.68) v3(49.47,25.41) v3(49.47,24.52) v3(49.46,22.4) v3(49.46,21.51) v3(49.56,13.24) v3(50.01,95.88) v3(50.09,48.41) v3(50.46,47.65) v3(50.7,64.48) v3(51.33,65.29) v3(51.54,64.47) v3(51.89,76.69) v3(51.89,75.8) v3(51.89,74.96) v3(52.17,65.29) v3(52.43,64.49) v3(52.78,76.69) v3(52.78,75.8) v3(52.78,74.96) v3(53.01,65.29) v3(53.06,95.88) v3(53.31,64.49) v3(53.67,76.69) v3(53.67,75.8) v3(53.67,74.96) v3(53.85,65.29) v3(54.2,64.49) v3(54.56,76.69) v3(54.56,75.8) v3(54.56,74.96) v3(54.74,65.29) v3(55.09,64.49) v3(55.45,76.69) v3(55.45,75.8) v3(55.45,74.96) v3(55.98,64.49) v3(56.11,95.88) v3(56.87,64.49) v3(57.76,64.49) v3(58.39,65.13) v3(59.16,95.88) v3(62.2,95.88) v3(62.9,73.49) v3(62.9,72.52) v3(62.9,71.56) v3(62.9,70.59) v3(62.9,69.75) v3(62.9,68.91) v3(64.2,75.61) v3(64.83,76.23) v3(65.23,68.93) v3(65.25,95.88) v3(65.44,87.63) v3(65.44,86.78) v3(72.17,98.56) v3(72.28,101.7) v3(73.43,24.62) v3(74.32,17.95) v3(74.74,24.64) v3(75.81,24.61) v3(77.03,101.82) v3(78.99,78.44) v3(78.99,77.17) v3(78.99,75.9) v3(79.91,101.86) v3(79.88,79.58) v3(79.88,78.44) v3(79.88,77.17) v3(79.88,75.9) v3(79.88,74.75) v3(80.64,70.18) v3(82.02,82.73) v3(82.3,97.79) v3(86.83,90.91) v3(86.83,90.02) v3(89.61,29.29) v3(90.24,20.54) v3(90.5,29.29) v3(91.16,20.54) v3(91.39,29.29) v3(92.07,20.54) v3(92.99,20.54) v3(102.45,19.98) v3(104.38,14.34) v3(106.56,12.28) v3(109.12,12.32) v3(110.69,14.58) v3(111.05,30) v3(111.74,14.59) v3(111.9,30.02) v3(124.22,18.3) v3(125.07,18.28) v3(131.55,1.28) v3(133.07,95.91) v3(133.28,1.28) v3(135.01,1.28) v3(135.7,18.88) v3(136.55,18.86) v3(136.73,1.28) v3(136.96,17.06) v3(137.45,18.86) v3(137.63,19.8) v3(138.03,17.08) v3(138.31,18.83) v3(138.51,19.7) v3(140.16,20.03) v3(145.71,26.91) v3(146.4,26.36) v3(146.4,25.51) v3(150.8,62.66) v3(151.75,62.69) v3(151.77,61.31) v3(151.77,59.62) v3(151.77,57.93) v3(151.75,55.93) v3(152.52,91.65) v3(160.85,93.37) v3(161.37,90.22) v3(163.47,96.98) v3(165.62,95.56) v3(166.98,88.81) v3(169.02,101.78) v3(169.53,99.15) v3(172.97,76.28) v3(173.99,76.66) v3(177.4,97.32)
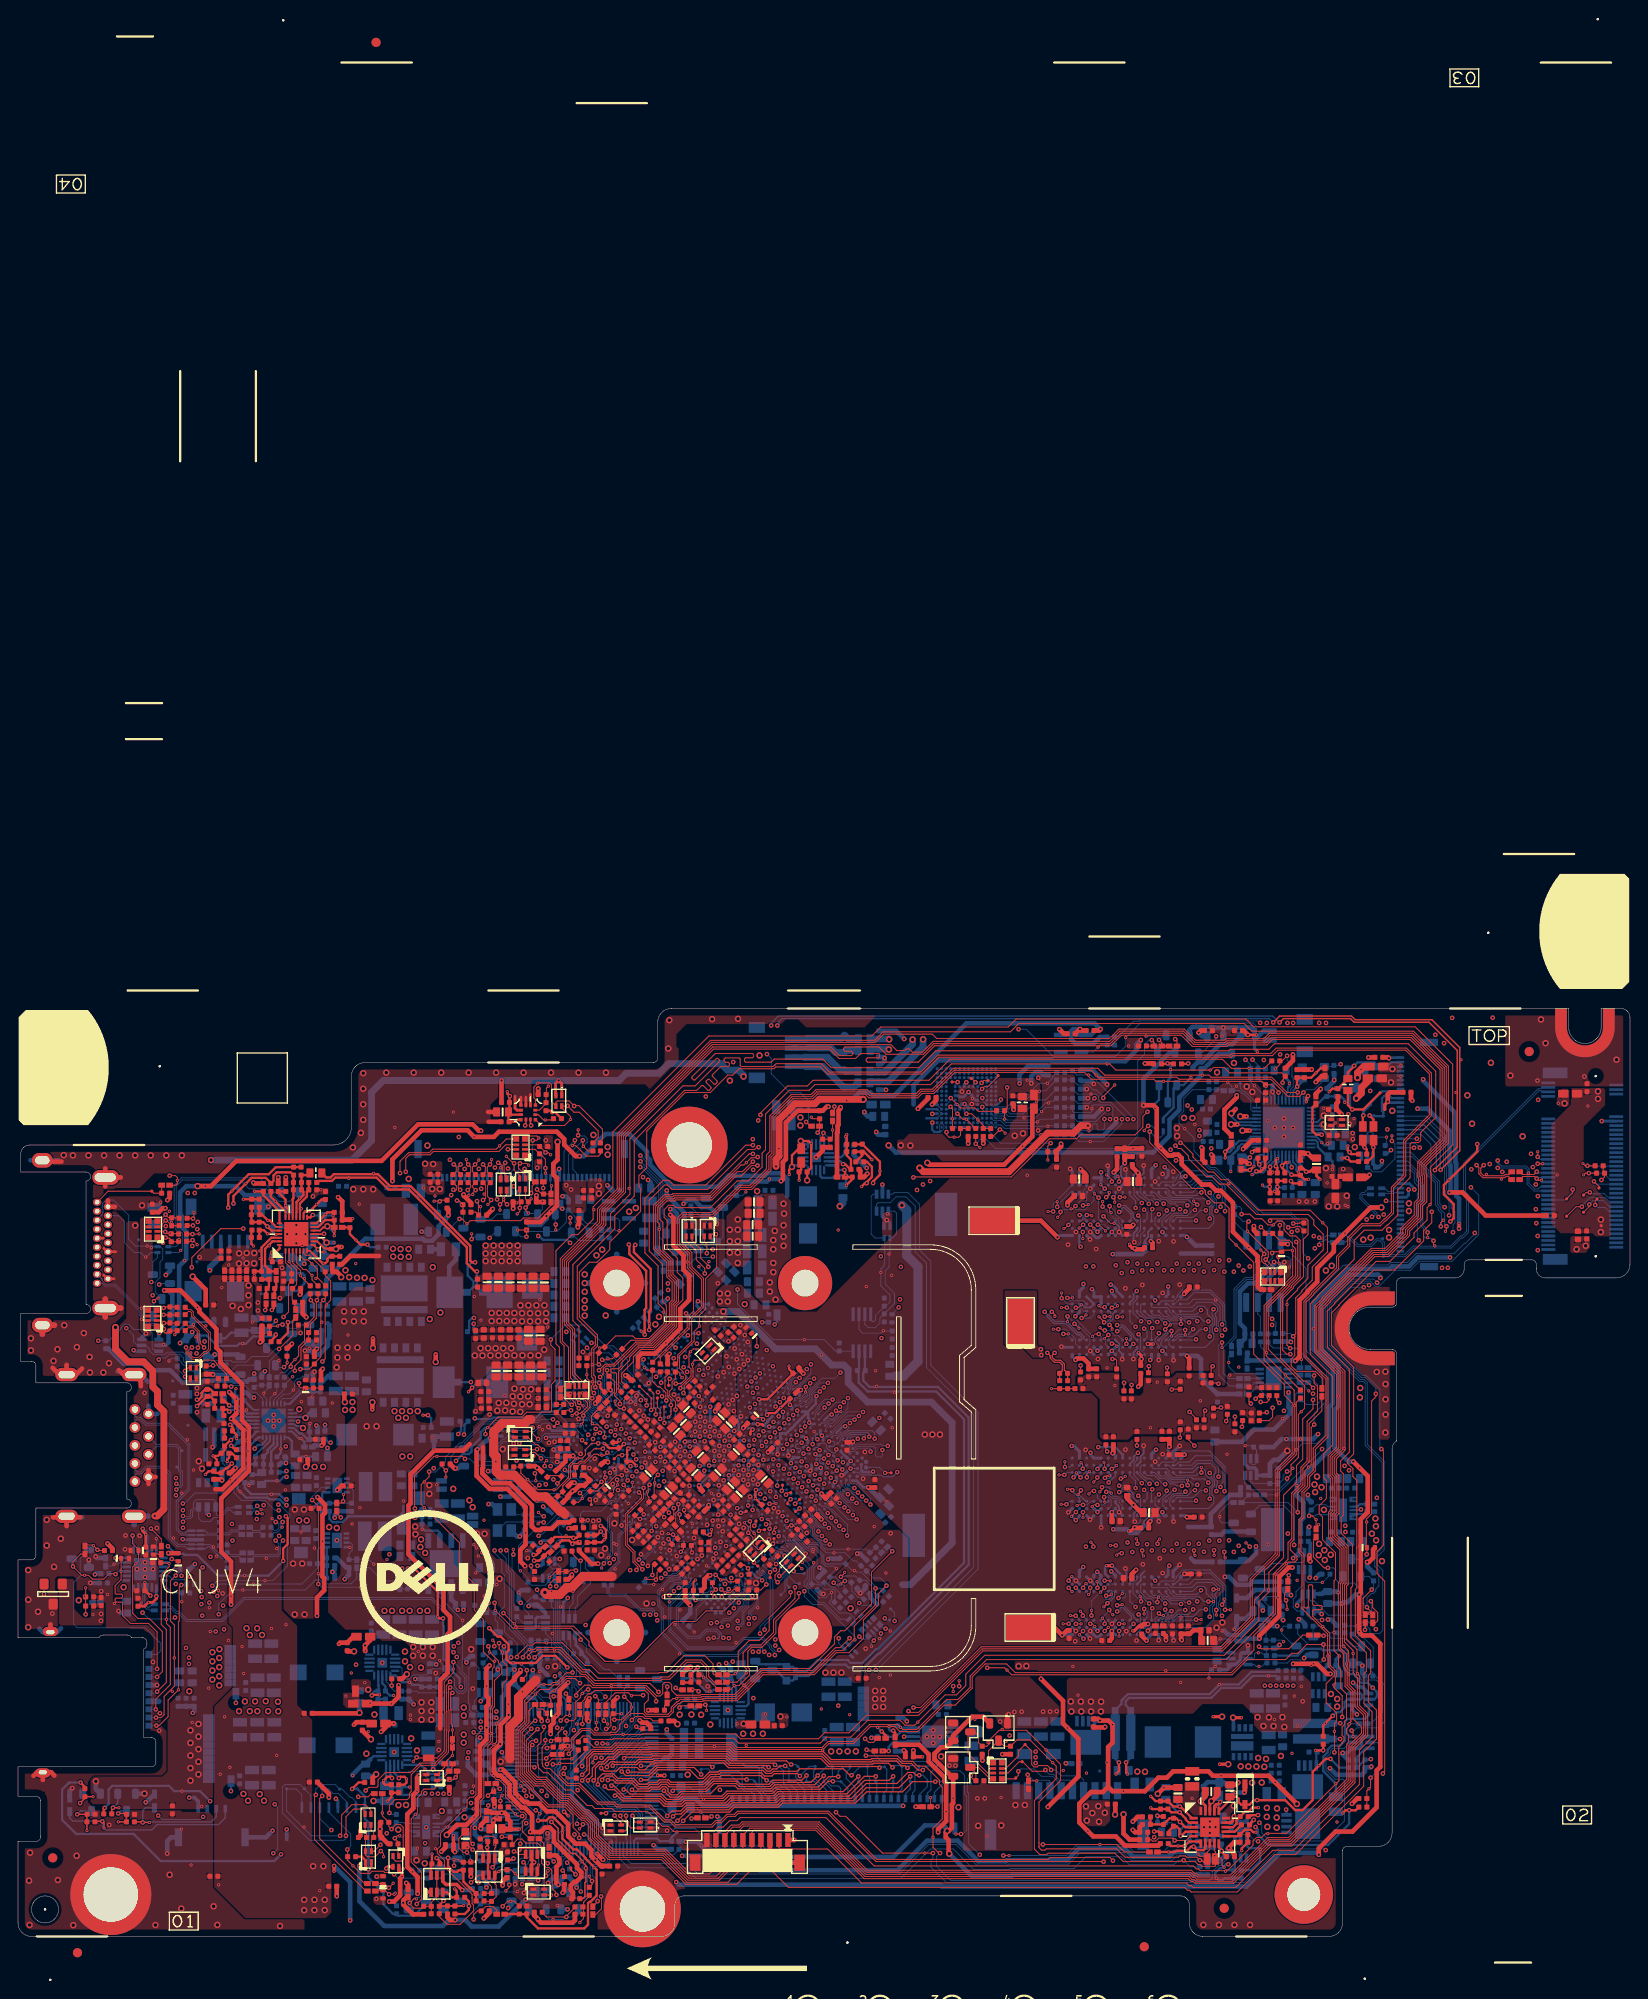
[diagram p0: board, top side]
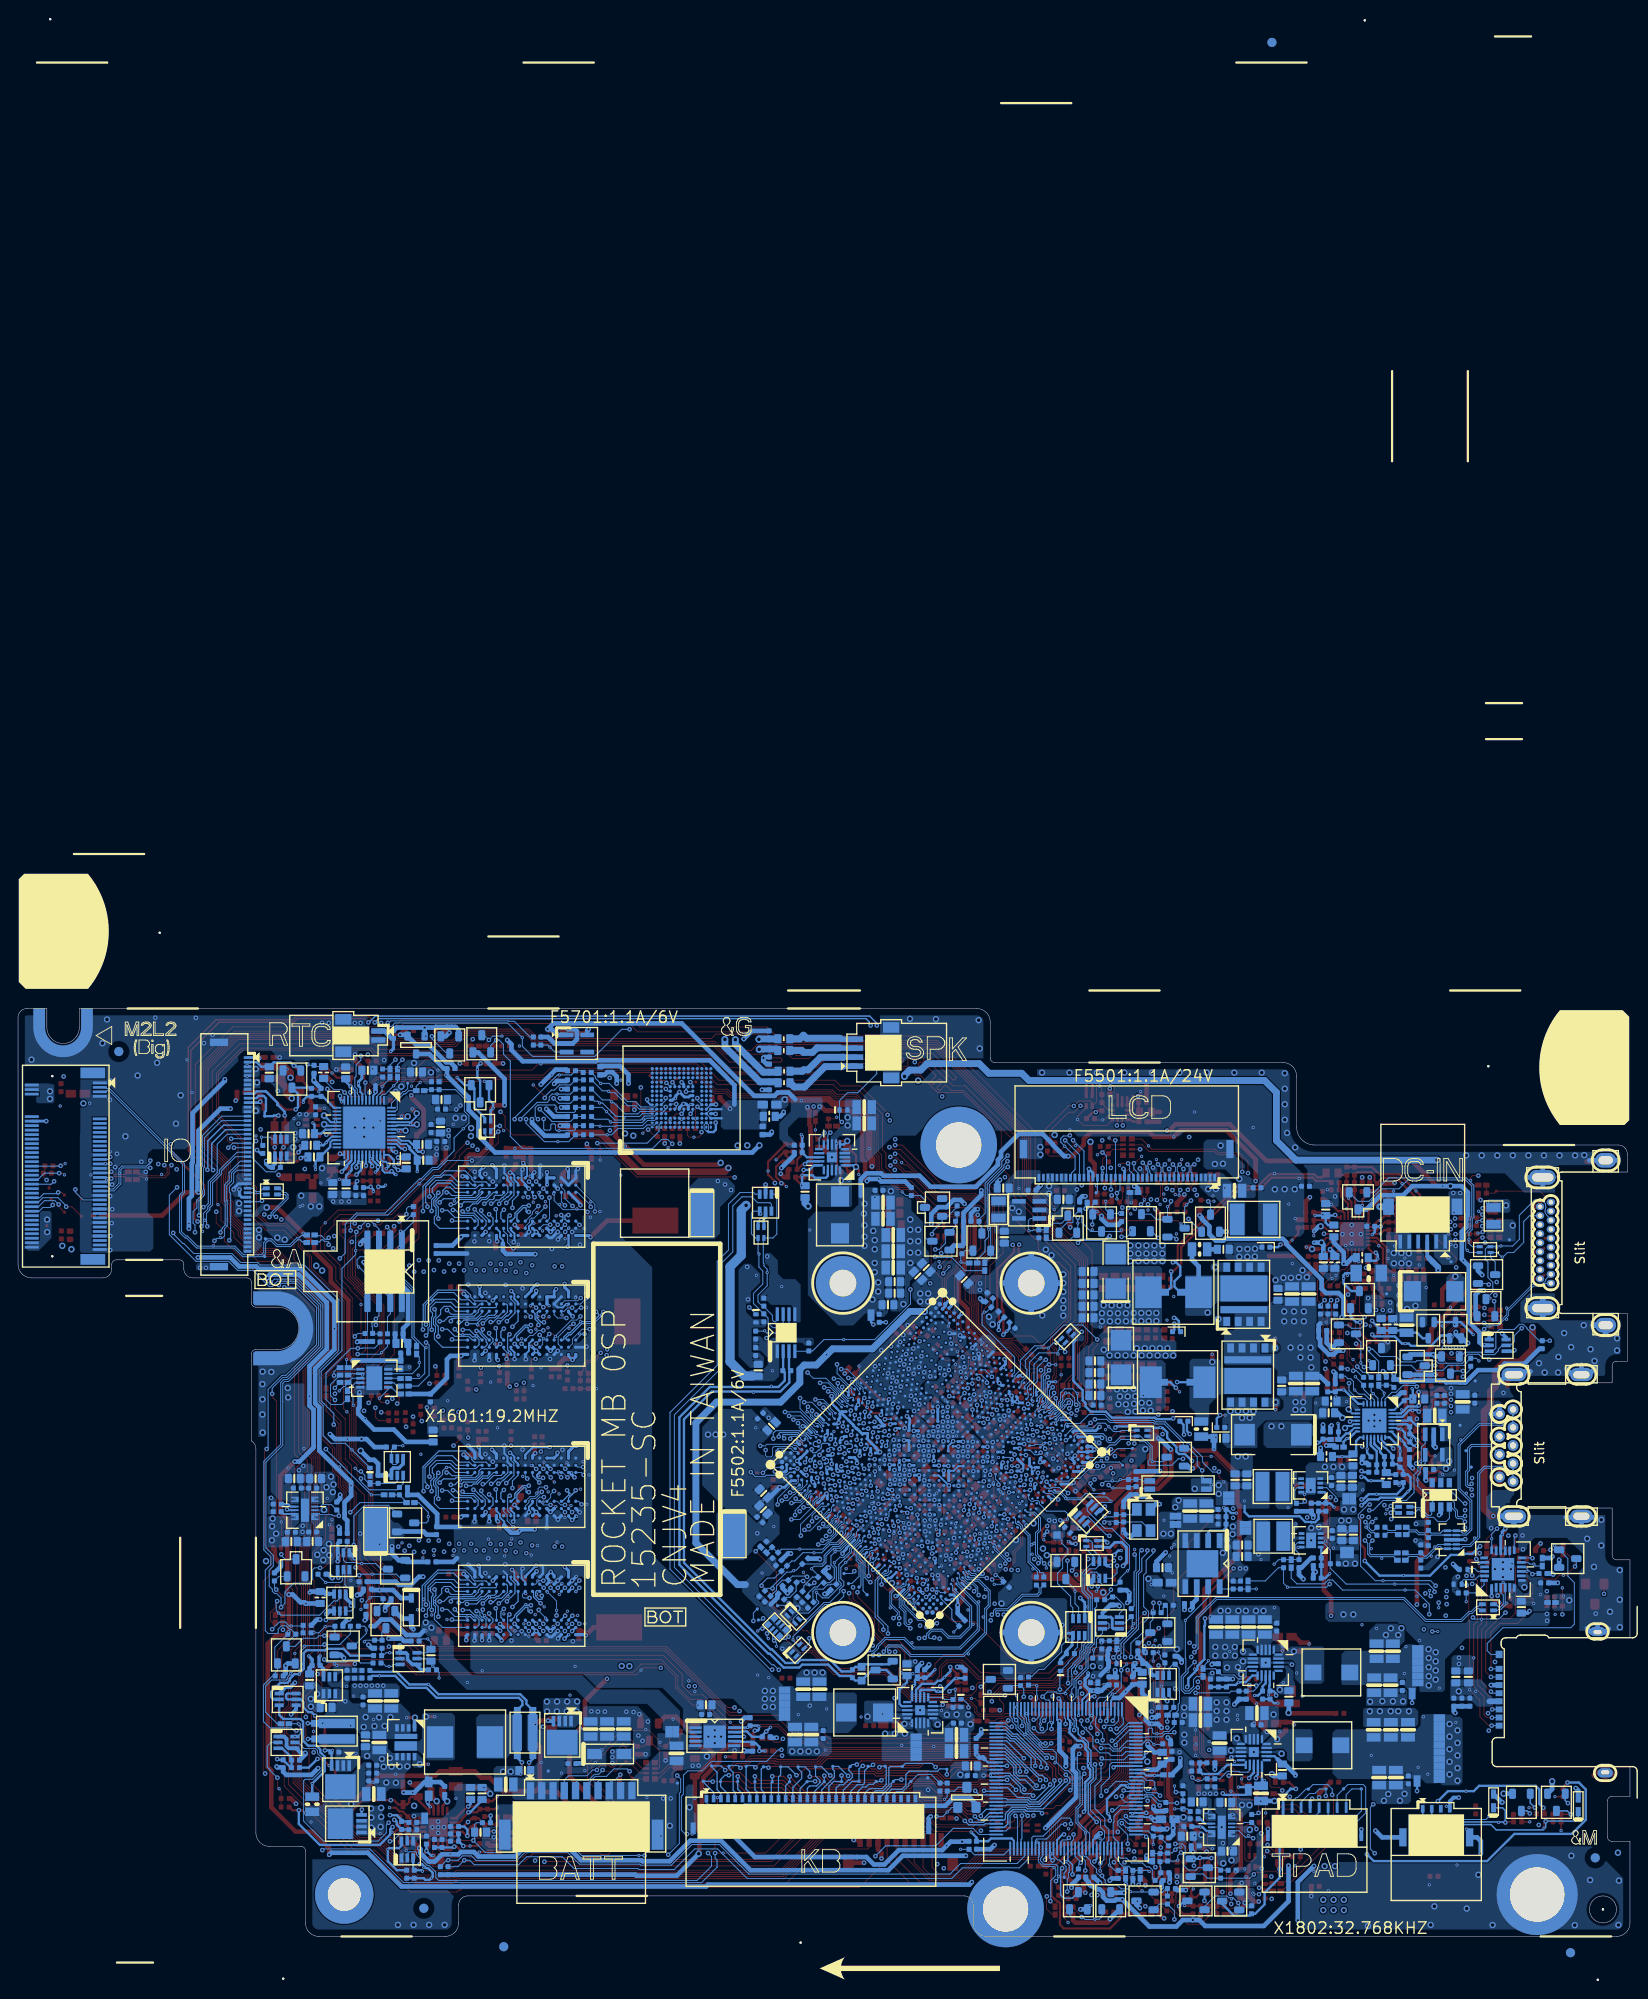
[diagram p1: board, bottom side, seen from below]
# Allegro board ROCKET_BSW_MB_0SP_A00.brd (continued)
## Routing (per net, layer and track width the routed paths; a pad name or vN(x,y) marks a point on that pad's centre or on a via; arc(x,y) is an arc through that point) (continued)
VCC_AXG_SENSE: length 83.3
  TOP w0.254: v1(68.51,76.76) 68.35,76.61 68.35,75.95 70.22,74.08 70.22,69.53 70.05,69.35 v1(70.05,67.32) ; PR4809.1 28.39,69.76 v1(28.17,69.54)
  L4 w0.254: v1(75.12,54.97) 75.12,55.25 74.35,56.01 74.35,56.33 69.5,61.19 69.5,62.2 70.53,63.24 70.53,65.31 70.06,65.77 70.06,67.31 v1(70.05,67.32) ; v1(68.51,76.76) 68.51,77.18 66.87,78.81 63.29,78.81 62.68,78.21 60.68,78.21 60.05,77.57 60.05,68.65 58.32,66.92 50.99,66.92 49.99,65.93 42.25,65.93 40.9,67.27 35.63,67.27 32.85,70.05 29.29,70.05 28.77,69.54 v1(28.17,69.54)
  BOTTOM w0.203: v1(75.12,54.97) 75.65,54.44 CPU1.AD24
  BOTTOM w0.254: v1(70.05,67.32) 70.07,67.34 v2(70.07,68) 70.07,68.1 R1874.2
VCC_SENSE: length 30.6
  TOP w0.254: v1(57.28,41.71) 57.84,41.71 R1851.2 58.82,42.69 59.11,42.69
  L3 w0.254: v1(79.97,52.3) 79.28,52.3 76.01,49.03 72.87,49.03 72.11,48.27 70.82,48.27 69.96,47.41 69.14,47.41 67.99,46.25 67.99,45.23 67.38,44.62 65.83,44.62 65.12,43.91 64.06,43.91 62.39,42.24 60.84,42.24 60.66,42.42 58.39,42.42 57.72,41.74 57.31,41.74 v1(57.28,41.71)
  BOTTOM w0.254: CPU1.AG32 v1(79.97,52.3)
VCC_VCORE1_SENSE: length 19.8
  TOP w0.254: PR4676.1 63.94,43.72 R1848.2 64.78,43.76 v2(65.06,44.03) 65.25,44.23 65.25,45.12 64.81,45.56 v1(64.68,45.56)
  L3 w0.254: v1(76.7,52.27) 76.7,51.52 76.18,50.99 73.55,50.99 73.31,50.76 72.67,50.76 71.4,49.49 70.09,49.49 69.31,48.7 68.06,48.7 66.59,47.24 66.26,47.24 64.68,45.66 v1(64.68,45.56)
  BOTTOM w0.254: v1(76.7,52.27) 76.69,52.26 CPU1.AD29
VSS_AXG_SENSE: length 83.1
  TOP w0.254: v1(69.55,66.8) 69.55,67.1 69.54,67.11 69.54,69.56 69.71,69.74 69.71,73.87 67.85,75.74 67.85,76.74 v1(67.79,76.8) ; PR4808.1 27.53,69.63 v1(27.43,69.53)
  L4 w0.254: v1(69.55,66.8) 69.55,65.56 70.02,65.1 70.02,63.45 68.99,62.41 68.99,60.97 73.84,56.12 73.84,55.8 74.52,55.12 74.52,54.41 v1(74.55,54.38) ; v1(67.79,76.8) 67.79,77.17 66.66,78.3 63.5,78.3 62.9,77.7 60.89,77.7 60.55,77.36 60.55,68.44 58.53,66.42 51.2,66.42 50.2,65.42 42.04,65.42 40.69,66.77 35.42,66.77 32.64,69.55 29.5,69.55 28.98,69.03 27.93,69.03 v1(27.43,69.53)
  BOTTOM w0.203: CPU1.AD22 74.57,54.4 v1(74.55,54.38)
  BOTTOM w0.254: v1(69.55,66.8) 69.55,66.8 v2(69.16,67.19) 68.87,67.48 R1873.1
VSS_SENSE: length 31.8
  TOP w0.254: 58.51,43.28 58.28,43.28 R1852.2 57.79,42.62 57.52,42.34 v1(57.23,42.34)
  L3 w0.254: v1(80.56,52.85) 79.12,52.85 75.8,49.54 72.66,49.54 71.9,48.78 70.61,48.78 69.75,47.92 68.93,47.92 67.48,46.46 67.48,45.44 67.17,45.13 65.62,45.13 64.91,44.42 63.85,44.42 62.18,42.75 61.05,42.75 60.87,42.93 58.18,42.93 57.6,42.34 v1(57.23,42.34)
  BOTTOM w0.254: v2(56.46,42.83) 56.79,42.83 57.23,42.39 v1(57.23,42.34) ; CPU1.AJ32 v1(80.56,52.85)
VSS_VCORE1_SENSE: length 19.6
  TOP w0.254: v1(64.68,44.95) 64.28,44.55 R1849.2 63.17,44.55 PR4678.1
  L3 w0.254: v1(64.68,44.95) 64.75,44.95 65.16,45.36 65.16,45.64 66.4,46.88 66.82,46.88 68.28,48.35 69.45,48.35 70.24,49.14 71.55,49.14 71.79,49.38 72.81,50.4 73.46,50.4 73.7,50.64 76.33,50.64 77.27,51.58 v1(77.27,52.78)
  BOTTOM w0.254: v1(64.68,44.95) 65.02,44.6 v2(65.02,44.48) ; CPU1.AF27 77.28,52.79 v1(77.27,52.78)
VSS_VNN_SENSE: length 60.2
  TOP w0.254: PR5039.2 94.22,85.98 94.77,85.43 94.77,84.3 94.18,83.72 v1(94.18,83.6) 94.15,83.57 93.96,83.57 v2(93.62,83.24)
  L3 w0.254: v1(75.65,52.23) 74.76,51.35 73.4,51.35 73.17,51.11 72.65,51.11 72.03,51.73 72.03,51.88 71.75,52.16 70.53,52.16 70.2,52.5 70.2,52.73 69.77,53.16 69.54,53.16 69.09,53.61 69.09,54.07 71.3,56.28 71.79,56.28 74.86,59.35 75.76,59.35 77.08,60.67 77.08,62.38 78.04,63.35 78.04,66.18 79.18,67.32 81.74,67.32 v1(82.59,68.17) 82.79,68.37 82.79,74.69 83.47,75.38 85.74,75.38 85.83,75.47 90.45,75.47 91.71,76.73 94.22,79.24 94.22,83.57 v1(94.18,83.6)
  BOTTOM w0.254: CPU1.AC27 75.66,52.24 v1(75.65,52.23) ; v1(82.59,68.17) R1875.1
0D675V_PWR:
  vias: v2(107.65,21.55)
0D675V_S0_DISCHG: length 3
  TOP w0.508: v1(143.43,41.64) 143.32,41.75 v2(143.32,42.33)
  BOTTOM w0.381: v1(143.43,41.64) 143.43,41.64 Q4014.3
  BOTTOM w0.406: R4047.2 143.43,43.63 Q4014.3
0D675V_VREF_S0: length 20.9
  L3 w0.508: v1(143.3,45.46) 143.3,45.14 143.3,45.14 143.3,45.02 142.78,44.5 142.78,42.74 142.26,42.21 142.26,37.93 141.05,36.72 141.05,34.8 140.69,34.44 v1(139.75,34.44)
  BOTTOM w0.508: v1(143.3,45.46) 143.21,45.37 R4047.1 ; v1(139.75,34.44) 139.32,34.44 138.6,35.17 137.5,35.17 135.79,33.45 134.34,33.45 133.83,33.96
  vias: v2(106.2,24.11) v2(121.74,61.15) v2(125.68,56.47) v2(126.43,61.53) v2(129.03,28.2) v2(133.62,33.92) v2(134.19,53.52) v2(134.48,62.3) v2(138.76,43.54) v3(133.02,34.27) v3(133.65,34.85)
1D5V_BRI_S0: length 2.6
  TOP w0.356: v2(48.33,11.19) R4022.1
  TOP w0.508: v1(48.49,9.38) 48.33,9.54 R4022.1
  BOTTOM w0.508: v1(48.49,9.38) 48.69,9.59 R4021.2
1D5V_DIS_Q: length 2.8
  BOTTOM w0.406: Q4001.3 143.86,38.03 144.37,38.03
  BOTTOM w0.508: v2(146.51,38.18) 146.41,38.28 R4027.2 144.98,38.28 144.73,38.03 144.37,38.03
1D05V_PWR_BS: length 4.9
  TOP w0.254: PR5001.1 86.63,87.43 85.9,86.7 v3(85.9,85.42) 85.58,85.11 v2(85.58,84.56)
  BOTTOM w0.254: PU5001.1 86.07,85.59 v3(85.9,85.42)
1D05V_PWR_BS_R: length 2.1
  TOP w0.254: PR5001.2 86.92,85.09 C5006.1 v2(86.69,83.94)
1D05V_PWR_BYP: length 4.7
  TOP w0.254: v1(91.71,85.08) 91.79,85 PR5007.1 91.79,84.29 PC5007.1 92.58,84.05 91.95,83.42 v2(91.95,83.37)
  BOTTOM w0.254: v1(91.71,85.08) 91.07,85.08 90.56,85.59 PU5001.15
1D05V_PWR_FB: length 6.9
  TOP w0.254: v1(91.57,85.73) 91.8,85.73 92.38,85.14 PR5005.1 92.44,86.22 91.97,86.69 PR5014.2 PC5002.2 v2(91.97,89)
  BOTTOM w0.254: v1(91.57,85.73) 91.26,86.04 PU5001.14
1D05V_PWR_FBH: length 3.7
  TOP w0.254: PR5006.2 93.64,87.11 PR5014.1 ; PR5006.2 93.7,86.7 PR5039.1 ; PR5006.2 93.92,87.06 v2(94.77,86.21)
1D05V_PWR_FBL: length 30
  TOP w0.254: v1(94.9,83.62) 94.9,83.8 95.66,84.56 v2(95.66,84.96) 95.66,85.99 PR5006.1 93.67,87.92 PC5002.1
  L3 w0.254: v1(94.9,83.62) 94.66,83.39 94.66,79.15 90.6,75.09 85.99,75.09 84.86,73.96 84.86,68.82 v1(83.98,67.93)
  BOTTOM w0.254: v1(83.98,67.93) 84.23,68.19 PG5001.1
1D05V_PWR_LDO: length 5
  BOTTOM w0.254: PC5009.1 91.89,83.66 v2(91.89,84.49) 90.73,84.49 90.44,84.21 89.23,84.21 89.02,84.42 PU5001.17
1D05V_PWR_PH: length 6.5
  TOP w0.254: v3(87.58,83.93) C5006.2 88.02,85.31 v2(88.02,88.02) 87.75,88.29 v3(86.87,88.29)
  BOTTOM w0.254: PU5001.6 87.25,87.91 v3(86.87,88.29)
1D05V_PWRGD: length 4.1
  TOP w0.102: v1(88.74,89.23) 88.96,89.44 PR5066.2 88.97,89.95 PR5013.2 88.21,90.76 v2(88.04,90.93)
  BOTTOM w0.102: PU5001.9 89.02,88.95 v1(88.74,89.23)
1D5V_S0: length 390.8
  TOP w0.356: v1(35.08,7.82) v2(35.08,7.24) ; v1(159.93,78.56) v2(159.93,79.13)
  TOP w0.508: v1(144.04,94.85) 144.7,95.51 R2701.1 ; R4022.2 47.44,9.87 v1(46.98,9.42) ; v1(144.36,9.07) 144.36,9.77 146.23,11.64 148.09,11.64 150.79,14.33 150.79,18.42 151.19,18.82 151.19,32.48 150.26,33.41 149.23,33.41 148.86,33.78 148.86,33.83 v2(148.85,33.83) v1(148.85,37.95) 149.02,38.12 149.02,43.31 149.02,43.31 149.02,46.31 149.8,47.09 149.8,51.1 v2(148.91,51.99) v1(148.19,52.71) ; R2705.1 133.89,89.68 133.89,91.78 135.26,93.14 v1(135.26,93.36) ; PC5306.1 116.08,100.2 v1(115.58,100.7) ; v1(72.39,80.1) 72.74,79.75 72.74,76.71 73.85,75.59 73.85,74 74.46,73.4 74.46,73.39 74.48,73.37 74.48,72.8 74.48,70.63 73.51,69.66 73.51,67.49 v2(71.9,65.89) 70.71,64.7 69.2,64.7 68.81,64.31 68.81,63.22
  L3 w0.508: v1(144.04,94.85) 145.14,95.95 145.14,97.67 146.44,98.97 148.77,98.97 149.4,99.6 154.2,99.6 155.94,97.85 v1(155.94,95.14) ; v1(35.08,7.82) 36.96,7.82 37.99,8.84 42.81,8.84 43.38,9.42 v1(46.98,9.42) ; v1(76.33,93.24) 75.22,93.24 71.2,89.22 71.2,84.78 71.4,84.57 71.4,83.11 71.36,83.07 71.36,80.7 71.97,80.1 v1(72.39,80.1)
  L4 w0.508: v1(151.21,73.09) 151.2,73.11 151.2,73.44 152.54,74.78 156.59,74.78 157.93,76.12 158.49,76.12 159.93,77.57 v1(159.93,78.56) ; v1(144.04,94.85) 144.04,94.44 143.94,94.34 143.94,93.16 143.43,92.65 142.9,92.65 142.57,92.99 136.46,92.99 136.09,93.36 v1(135.26,93.36) 134.02,94.59 134.02,96.41 130.18,100.26 122.88,100.26 122.68,100.06 121.48,100.06 116.22,100.06 v1(115.58,100.7) 112.11,100.7 111.45,100.05 110.57,100.05 109.9,100.71 96.04,100.71 95.31,99.98 95.31,99.98 94.56,99.23 78.37,99.23 76.55,97.41 76.55,93.45 v1(76.33,93.24) ; v1(36.86,1.78) 37.58,1.07 62.61,1.07 67.68,6.14 71.48,6.14 71.59,6.03 v1(73.05,6.03)
  BOTTOM w0.305: CPU1.AF4 69.76,61.17 v1(70,61.42) 70.15,61.57 CPU1.AH4
  BOTTOM w0.508: R4027.1 146.91,36.96 v2(146.94,36.93) 147.09,37.09 147.55,37.09 148.41,37.95 v1(148.85,37.95) ; v1(144.36,9.07) 144.15,9.29 140.08,9.29 136.34,5.55 102.54,5.55 102.33,5.75 73.33,5.75 v1(73.05,6.03) ; v1(155.94,95.14) 155.94,94.98 159.53,91.4 159.53,85.9 159.61,85.81 159.61,82.21 159.93,81.89 v1(159.93,78.56) ; v1(148.19,52.71) 147.66,52.71 146.1,54.28 146.1,58.46 146.55,58.91 v2(146.55,59.97) 146.55,63.3 144.63,65.22 144.63,70.35 144.64,70.36 144.64,70.37 147.67,73.39 147.67,73.39 147.74,73.46 150.95,73.46 151.21,73.2 151.21,73.09 v1(151.21,73.09) ; PU5301.5 115.73,100.55 v1(115.58,100.7) ; v1(35.08,7.82) 36.86,6.03 v1(36.86,1.78)
1D5V_S0_EN: length 4
  BOTTOM w0.102: PU5301.3 119.32,98.17 v2(119.87,98.72) 120.1,98.95 PC5326.1 121.7,98.95 PR5315.2
1D05V_S5: length 116
  TOP w0.508: v1(77.37,58.27) 77.37,58.37 77.76,58.75 C1013.1 ; v1(65.47,52.65) 65.41,52.71 65.13,52.71 64.72,52.41 ; PR4816.1 31.37,71.34 v1(31.29,71.25) ; v1(41.55,83.85) 41.55,86.25 44.79,89.49 49.89,89.49 v2(50.62,88.75) 52.81,88.75 53.38,89.32 59.8,89.32 60.1,89.03 60.62,88.51 60.62,87.88 61.89,86.62 v1(62.33,86.62)
  L3 w0.508: 31.35,66.98 v1(31.36,66.98) ; 31.35,66.98 31.54,66.78 31.54,65.32 v1(31.83,65.03) ; 31.35,66.98 31.32,66.98 31.32,67.01 31.29,67.04 v1(31.29,71.25)
  L4 w0.508: v1(27.41,62.74) 27.97,62.74 29.12,63.89 29.86,63.89 30.48,64.52 31.33,64.52 v1(31.83,65.03) ; v1(31.29,71.25) 29.6,71.25 27.35,73.51 27.35,76.22 26,77.56 24.48,77.56 22.61,79.43 22.61,81.29 23.68,82.35 30.52,82.35 31.69,81.18 39.53,81.18 41.55,83.2 v1(41.55,83.85)
  BOTTOM w0.305: CPU1.G10 65.03,52.65 v1(65.47,52.65) 65.47,53.06 CPU1.H10 ; v1(69.61,52.6) 69.61,52.57 69.74,52.44 CPU1.N18
  BOTTOM w0.508: PR4621.1 27.07,62.4 v1(27.41,62.74) ; v1(31.83,65.03) 32.46,65.03 32.89,64.59 33.42,64.59 34.4,65.57 34.4,66.27 34.55,66.41 PC4823.1 34.55,67.88 34.37,68.06 ; v1(62.33,86.62) 62.81,86.62 64.04,87.84 64.04,87.92 65.18,89.07 67.84,89.07 69.8,87.11 69.8,86.55 70.14,86.2 70.14,85.65 72.58,83.21 77.63,83.21 78.85,84.44 82.85,84.44 83.12,84.71 84.72,84.71 85.37,84.06 85.37,82.2
  vias: v1(71.3,53.24) v1(71.8,52.71) v1(72.93,54.91) v1(72.87,51.64) v1(73.48,54.38) v1(73.48,53.29) v1(74.02,53.84) v1(74.52,50.02) v1(74.55,53.3) v1(77.2,48.44) v1(77.76,49.01) v1(81.14,54.48) v1(81.64,53.97) v2(32.33,65.28) v2(33.72,68.18) v2(66.32,56.26) v2(70.08,53.16) v2(76.95,49.2) v2(83.81,82.04) v2(91.03,78.41) v3(83.44,72.59) v3(83.44,71.58) v3(83.82,77.29) v3(83.82,76.28) v3(83.82,74.75) v3(83.82,73.74) v3(83.99,78.32) v3(84.07,70.69) v3(84.96,81.33) v3(85.02,80.23) v3(84.96,78.94) v3(84.96,77.67) v3(84.96,76.66)
1D05V_VNN_EN: length 329.2
  TOP w0.102: v1(90.6,92.12) 90.6,91.74 90.4,91.54 PR5004.1 ; v1(144.9,33.38) 144.83,33.45 R4017.2
  L3 w0.102: v1(90.6,92.12) 91.1,91.62 91.47,91.62 91.56,91.71 92.01,91.71 93.38,90.34 93.38,90.2 93.84,89.74 100.52,89.74 100.87,89.4 101.96,89.4 102.76,88.6 103.36,88.6 104.07,89.3 108.26,89.3 108.68,88.88 109.28,88.88 110.34,89.93 113.8,89.93 114.17,89.56 117.32,89.56 117.94,88.94 124.66,88.94 124.76,88.83 125.84,88.83 127.37,90.37 128.75,90.37 129.57,89.55 129.57,87.88 133.52,83.93 134.08,83.93 137.56,80.46 143.53,80.46 143.83,80.16 147.27,80.16 153.46,86.36 158.03,86.36 161.25,83.14 v1(161.25,83.15)
  L4 w0.102: v1(90.6,92.12) 90.6,92.22 87.66,95.15 82.06,95.15 80.92,96.29 80.2,96.29 79.88,95.98 79.88,94.39 77.11,91.62 71.93,91.62 69.9,89.59 69.9,84.66 70.41,84.16 70.41,83.67 70.13,83.39 67.77,83.39 65.98,81.6 62.03,81.6 61.03,82.6 59.39,82.6 56.87,80.07 54,80.07 52.88,81.19 47.82,81.19 46.94,82.07 45.9,82.07 44.81,83.16 44.81,84.06 44.81,84.87 43.51,86.17 24.49,86.17 24.49,86.17 24.29,86.17 24.26,86.14 24.22,86.14 18.06,79.98 18.06,74.31 16.94,73.19 16.94,72.14 16.94,72.14 16.94,67.22 16.94,67.22 16.94,67.2 14.68,64.94 14.68,63.42 15.6,62.5 15.6,59.27 16.32,58.54 16.32,58.03 16.33,58.03 16.33,49.06 16.32,49.06 16.32,48.45 17.09,47.68 17.09,44.4 16.16,43.47 16.16,38.77 16.34,38.6 16.34,35.97 16.26,35.89 16.26,34.92 17.06,34.12 21.27,34.12 22.28,35.13 v1(22.28,35.76)
  BOTTOM w0.102: v1(22.28,35.76) 22.28,36.88 23.84,38.45 v2(24.95,38.45) 31.89,38.45 33.01,39.56 33.5,39.56 33.93,39.13 36.96,39.13 37.6,39.77 PR5201.1 ; v1(161.25,83.15) 162.11,82.28 162.11,77.91 159.13,74.93 155.52,74.93 154.53,73.94 152.82,73.94 151.02,72.13 150.66,72.13 150.4,72.39 150.4,72.44 150.12,72.73 147.94,72.73 145.3,70.09 145.3,65.5 148.98,61.82 149.4,61.82 149.75,61.48 149.75,54.61 151.62,52.74 151.62,42.91 150.84,42.13 150.84,41.26 151.46,40.64 151.46,33.95 151.13,33.62 150.11,33.62 150.03,33.71 150.03,34.11 149.67,34.47 149.15,34.47 148.78,34.11 148.62,34.11 R4016.2 149.12,32.5 Q4020.D 148.13,32.2 147.23,33.1 145.77,33.1 145.49,33.38 v1(144.9,33.38)
1D05V_VNN_PG_G: length 6.9
  BOTTOM w0.102: R1826.2 57.78,32.8 C1801.1 57.02,32.81 57.02,32.81 R1844.1 56.6,32.81 55.24,34.16 v2(55.24,34.29) 55.24,35.4 R1845.1 56.05,34.8 Q1801.2
1D05V_VNN_PWRGD: length 117.3
  TOP w0.102: v1(87.47,90.4) 87.94,89.94 PR5066.1 ; v1(35.82,46.52) 35.37,46.97 PR5009.1 ; v1(54.97,42.39) v2(54.97,42.96)
  L3 w0.102: v1(83.12,97.93) 82.73,98.33 81.99,98.33 79.68,96.01 76.13,96.01 69.78,89.67 69.78,85.52 69.22,84.96 68.81,84.96 68.38,84.53 68.38,84.12 63.65,79.4 63.65,76.86 62.49,75.7 62.49,74.2 61.96,73.66 61.96,68.48 64.1,66.35 64.1,65.68 60.82,62.4 60.82,59.33 60.63,59.15 60.63,57.17 60.04,56.57 59.59,56.57 59.16,57 58.69,57 57.67,55.97 55.52,55.97 54.43,54.89 54.43,53.6 55.21,52.82 v1(55.32,52.82) ; v1(35.82,46.52) 36.5,47.2 43.26,47.2 43.57,46.89 43.57,46.3 43.84,46.02 44.73,46.02 45.03,45.73 48.84,45.73 51.52,43.05 51.86,43.05 52.51,42.41 54.96,42.41 v1(54.97,42.39)
  L4 w0.102: v1(55.32,52.82) 55.64,52.5 55.64,49.08 56.07,48.65 56.07,45.02 56.38,44.72 56.38,43.79 55.25,42.66 55.24,42.66 v1(54.97,42.39)
  BOTTOM w0.102: R1845.2 55.04,36.69 55.04,38.56 55.04,40.43 54.83,40.64 54.83,42.25 v1(54.97,42.39) ; v1(83.12,97.93) 83.6,97.45 83.6,96.19 83.6,95.75 85.7,93.65 86.14,93.65 86.85,93.65 87.73,92.77 EC1813.1 87.73,90.66 v1(87.47,90.4)
1D8V_S0: length 225.3
  TOP w0.508: v1(16.23,71.71) 18.03,71.71 v2(19.91,69.83) 20.12,69.62 20.12,69.34 22.02,67.43 22.02,65.34 22.46,64.9 22.46,63.78 22.5,63.74 22.5,63.68 24.87,61.31 24.87,57.29 25.63,56.52 25.63,51.69 22.56,48.62 22.56,42.7 23.64,41.61 v2(23.64,37.76) v1(23.64,36.84) ; v3(47.58,11.27) 48.69,12.38 49.75,12.38 v2(50.62,13.24) 50.92,13.55 50.92,15.24 51.26,15.58 51.26,21.16 51.99,21.88 v1(51.99,23.18) 51.99,25.53 52.21,25.75 52.21,26.47 51.99,26.7 v2(51.99,27.78) 51.99,29.74 v1(52.32,30.08) ; v3(59.88,88.2) 59.88,86.23 59.42,85.76 59.42,84.57 59.81,84.18 59.81,81.11 59.16,80.46 v2(59.15,80.46) v1(58.65,79.97) 57.99,79.3 R5526.1
  L3 w0.508: v1(16.23,71.71) 16.4,71.88 v1(16.4,73.42) ; v1(79.38,97.06) 75.55,97.06 66.86,88.36 65.14,88.36 64.02,87.25 61.18,87.25 60.23,88.2 v3(59.88,88.2) 59.42,87.73 56.79,87.73 55.78,88.74 v1(48.92,88.74)
  L4 w0.508: v1(48.92,88.74) 48.68,88.98 41.34,88.98 38.97,86.6 24.67,86.6 24.47,86.6 24.47,86.6 24.11,86.6 24.08,86.58 24.04,86.58 21.5,84.03 19.41,84.03 17.62,82.24 17.62,74.64 v1(16.4,73.42) ; v1(93.93,91.52) 92.4,93.04 90.71,93.04 88.32,95.43 87.94,95.81 82.34,95.81 81.73,96.42 81.73,96.42 81.67,96.47 81.73,96.41 81.07,97.08 79.45,97.08 79.43,97.06 v1(79.38,97.06) ; v1(52.32,30.08) 52.32,30.41 51.03,31.7 51.03,32.54 49.73,33.83 49.57,33.83 46.51,36.89 34.42,36.89 34.12,37.19 23.99,37.19 v1(23.64,36.84)
  BOTTOM w0.203: 57.3,26.47 57.58,26.18 U2401.4
  BOTTOM w0.508: v1(58.65,79.97) 58.65,79.66 57.99,78.99 56.8,78.99 R5521.1 ; v1(93.93,91.52) 93.93,91.4 94.3,91.03 R6311.1 ; v1(16.23,71.71) 16.65,71.71 17.13,71.23 17.13,69 Q5703.G ; v1(16.4,73.42) 16.87,73.89 Q5705.G ; 57.3,26.47 56.67,26.47 v2(55.98,27.15) 55.21,27.93 C2432.1 55.14,28 C2433.1 54.14,27 53.72,26.58 53.72,24 53.32,23.6 v2(53.06,23.6) 52.41,23.6 v1(51.99,23.18)
  vias: v2(46.35,9.73)
1D8V_S0_EN: length 5.6
  TOP w0.102: RN4001.1 42.18,9.02 C4046.1 42.18,10.52 41.82,10.88 v1(41.82,10.91) 42.11,11.2 v2(42.37,11.2)
  BOTTOM w0.102: v1(41.82,10.91) 41.92,11.01 42.69,11.01 43.4,11.72 U4016.3
1D8V_S5: length 368
  TOP w0.406: Q1606.2 56.98,8.52 v1(57.28,8.23) 56.98,7.94 Q1606.5
  TOP w0.508: v1(59.96,5.74) 59.75,5.95 59.75,7.71 60.08,8.04 60.08,8.59 59.99,8.68 59.99,8.71 59.71,9 R2486.1 ; R1842.1 61.07,39.63 61.47,40.03 v1(61.47,40.16) ; PR4814.1 31.59,69.14 v1(31.99,68.73) ; v1(124.9,92.27) 124.9,92.26 126.01,92.26 126.38,91.9 126.38,87.95 v2(126.86,87.47) 127.65,86.69 128.17,86.69 128.26,86.77 128.77,86.77 129.15,86.39 129.15,85.71 131.4,83.46 131.41,83.46 132.29,83.46 132.97,82.78 133.5,82.78 134.84,81.44 134.84,78.23 v2(136.6,76.47) 137.56,75.5 137.56,74.94 137.61,74.89 137.61,72.11 137.92,71.79 R2512.1 ; R808.1 62.89,51.21 R1813.2 63.45,50.64 62.87,50.06 62.31,50.06 61.77,49.53 61.64,49.53 v1(61.54,49.42) 61.04,48.93 R1839.1 61.04,48.75 R810.1 ; R6329.2 v1(105.45,88.01) ; v1(47.77,80.04) 47.77,80.69 R5517.1 ; R6514.1 47.67,2.12 47.96,1.82 v1(48.51,1.82) ; R1860.1 69.94,25.12 v1(69.94,25.11)
  TOP w0.762: v1(84.12,85.47) 84.12,86.28 84.46,86.61 84.46,90.66 86.22,92.42 88.43,92.42 88.94,92.93 93.77,92.93 v3(93.8,92.9) ; v1(118.75,89.99) 117.96,89.99 117.14,89.18 114.27,89.18 109.98,84.89 100.48,84.89 v3(100.07,85.3)
  L3 w0.508: v1(57.28,8.23) 57.28,7.65 57.01,7.38 57.01,4.77 v1(56.34,4.1) ; v1(37.89,7.85) 38.22,8.17 43.25,8.17 43.97,8.21 v3(44.22,8.46) ; v1(69.94,25.11) 68.86,25.11 68.66,25.32 66.77,25.32 66.6,25.49 59.71,25.49 59.7,25.5 57.79,25.5 57.44,25.85 54.78,25.85 53.9,24.97 v1(53.08,24.97)
  L3 w0.762: v1(77.54,79.08) 77.54,79.49 82.26,84.2 82.85,84.2 v1(84.12,85.47)
  L4 w0.508: v3(92.4,36.42) 90.06,36.42 89.03,37.46 83.03,37.46 81.91,38.59 v3(81.91,39.22) ; v1(31.99,68.73) 30.73,67.47 30.73,66.71 31.03,66.41 31.03,66.05 31.03,65.52 30.66,65.15 30.22,65.15 29.63,64.56 28.89,64.56 27.73,63.4 27.13,63.4 v1(26.21,62.48) ; v1(61.47,40.16) 64.63,36.99 69.71,36.99 v3(69.75,36.96) ; v1(73.86,81.32) 73.86,80.67 72.66,79.46 71.83,79.46 71.11,78.75 68.42,78.75 66.64,80.53 61.5,80.53 61.26,80.78 v1(60.41,80.78) 60.39,80.78 58.58,78.97 48.76,78.97 47.77,79.97 v1(47.77,80.04) ; v1(105.45,88.01) 105.02,87.58 103.76,87.58 101.16,84.98 100.39,84.98 v3(100.07,85.3) ; v1(72.11,70.8) 73.63,70.8 75.32,72.49 v1(77.66,72.49)
  L4 w0.762: v3(93.8,92.9) 93.83,92.88 93.83,92.81 93.96,92.69 93.96,92.6 94.84,91.71 96.86,91.71 99.62,88.95 99.62,88.94 100.46,88.11 100.46,86.63 100.05,86.23 100.05,85.52 100.07,85.5 v3(100.07,85.3)
  BOTTOM w0.305: CPU1.Y18 v1(71.31,54.35) ; v1(76.16,51.7) 76.15,51.69 CPU1.AA29 ; 78.87,50.65 78.87,51.16 v1(78.89,51.19) 78.91,51.21 CPU1.AF33 ; v1(69.6,53.81) 69.63,53.78 CPU1.U16
  BOTTOM w0.508: v1(73.86,81.32) 74.29,81.75 75.06,81.75 75.86,80.95 76.77,80.95 77.54,80.18 v1(77.54,79.08) ; v1(121.86,90.72) 121.86,90.3 120.43,88.87 118.03,88.87 R6333.2 ; R6330.2 119.42,91.01 v1(120.27,91.86) ; v1(47.77,80.04) 47.51,79.79 47.51,79.65 46.68,78.82 46.68,77.95 45.96,77.23 45.13,77.23 44.92,77.44 38.53,77.44 38.15,77.06 38.15,76.86 34.23,72.94 34.23,71.9 33.75,71.42 32.35,71.42 31.79,70.86 31.79,68.93 v1(31.99,68.73) ; R5705.1 10.03,65.24 11.7,63.56 13.91,63.56 14.61,62.86 16.87,62.86 18.22,61.52 18.31,61.52 18.33,61.5 18.86,61.5 18.88,61.52 20.39,61.52 20.39,61.52 20.42,61.52 20.61,61.71 23.85,61.71 23.95,61.6 25.41,61.6 25.64,61.83 PR4635.1 26.2,62.43 26.21,62.44 v1(26.21,62.48) ; R6337.2 118.04,96.21 119.23,96.21 v1(120.88,94.57) ; v1(124.9,92.27) 124.9,95.19 127.85,98.13 Q6301.G ; C2439.1 60.39,6.34 60.1,6.05 60.1,5.88 v1(59.96,5.74) 59.92,5.74 59.77,5.59 59.48,5.59 59.11,5.23 58.86,5.23 58.49,4.86 58.49,4.4 58.05,3.96 57.19,3.96 57.05,4.1 v1(56.34,4.1) 53.34,1.1 50.35,1.1 49.63,1.82 v1(48.51,1.82) 47.79,1.82 47.13,1.16 40.64,1.16 37.89,3.91 v1(37.89,7.85) ; R1520.1 94.62,37.92 94.62,37.58 95.36,36.85 ; v1(60.41,80.78) 60.25,80.94 R5522.1 ; R1825.1 71.77,70.46 v1(72.11,70.8) ; R6331.2 v1(118.75,93.04) ; R6332.2 118.03,94.96 119.08,94.96 v1(119.39,94.64) ; R6336.2 v1(118.62,94.06) ; R6335.2 v1(118.62,92.03) ; R6334.2 v1(118.75,89.99)
  BOTTOM w0.762: v3(78.28,69.37) 79.92,69.37 84.07,65.22 88.5,65.22 v2(89.15,64.57) 90.29,63.43 91.65,63.43 92.13,62.94 92.13,61.45 94.27,59.31 101.37,59.31 103.67,57.01 103.67,43.68 99.05,39.05 98.17,39.05
  vias: v1(50.47,27.51) v1(75.71,58.78) v1(76.26,58.24) v2(44.33,9.8) v2(44.85,45.19) v2(51.74,37.77) v2(53.13,39.05) v2(88.25,42.96) v2(96.32,40.34) v3(44.07,45.49) v3(44.1,44.65) v3(50.29,31.88) v3(53.44,39.7) v3(53.79,54.1) v3(68.15,44.01)
1D8V_S5_PG: length 57.9
  TOP w0.102: v1(37.75,15.5) 38.85,15.5 39.2,15.85 R4064.1
  L3 w0.102: v1(21.69,38.25) 21.68,38.24 21.68,37.55 21.89,37.34 21.89,36.74 21.6,36.45 21.6,34.45 21.12,33.97 21.12,33.2 20.8,32.88 20.8,28.19 22.52,26.47 22.52,16.21 24.5,14.23 33.23,14.23 33.76,14.76 37.01,14.76 v1(37.75,15.5)
  BOTTOM w0.102: PU5204.2 34.06,43.72 33.25,42.91 PR5218.2 33.25,40.87 31.49,39.11 v2(26.12,39.11) 22.37,39.11 21.69,38.44 v1(21.69,38.25)
1D8V_SPI: length 5.3
  BOTTOM w0.508: C2501.1 137.05,65.92 C2502.1 ; 137.54,71.86 v1(140.53,74.85)
  vias: v2(141.11,74.3)
1D15V_S5: length 5.5
  BOTTOM w0.305: v1(76.82,58.79) 76.82,57.18 CPU1.AK21 ; v1(82.17,52.34) 82.16,52.33 ; 82.16,52.33 CPU1.AK35 ; 82.16,52.33 CPU1.AK36 ; v1(80.57,55.06) 80.07,55.06 CPU1.AM29 80.02,55.01 CPU1.AK30 ; CPU1.AK33 81.09,52.33 v1(81.08,52.32) 81.07,52.31 81.07,51.78
  vias: v1(78.84,66.07) v2(45.09,50.45) v2(46.47,50.14) v2(50.8,40.36) v2(59.31,33.63) v2(83.29,52.12) v2(95.02,45.49) v3(45.65,50.09) v3(45.65,49.12)
1D24V_S5: length 6.9
  TOP w0.508: C1131.1 75.79,49.62 75.79,49.72 75.59,49.92 v1(75.59,50.05) ; C1149.1 76.17,47.25 76.65,47.74 v1(76.65,47.89)
  L4 w0.508: v1(76.65,47.89) 75.59,48.96 v1(75.59,50.05)
  BOTTOM w0.203: v1(75.59,50.05) 76.71,51.17 CPU1.AC30
  BOTTOM w0.305: CPU1.H44 77.1,41.86 v1(77.18,41.93)
  vias: v1(77.1,46.16) v1(77.75,45.55) v1(77.95,43.79) v1(78.21,44.97) v1(78.26,46.16) v2(50.88,43.13) v2(51.71,46.2) v2(60.22,36.58) v2(71.53,38.51) v2(76.41,41.14) v2(77.66,46.22) v3(50.94,44.7) v3(51.78,44.7)
1D24V_S5_PG: length 34.4
  TOP w0.102: v1(47.96,27.63) 47.77,27.44 47.77,26.86 47.78,26.85 47.78,25.14 47.83,25.08 47.83,22.8 47.76,22.73 47.76,20.39 46.36,19 44.69,19 43.64,17.95 43.64,16.09 43.43,15.89 43.43,15.41 43.2,15.18 41.84,15.18 41.22,14.56 v1(41.22,13.71)
  BOTTOM w0.102: v1(41.22,13.71) 41.39,13.54 R4065.1 ; v1(47.96,27.63) 48.22,27.63 48.86,26.99 49.43,26.99 49.81,27.37 49.81,28.87 49.29,29.38 49.29,30.79 49.35,30.84 v2(49.35,35.09) 46.81,37.62 PU5402.7
1D35V_CPU_VDDQ_S3: length 79.5
  TOP w0.508: 122.22,78.18 v1(122.2,78.2)
  BOTTOM w0.203: 122.59,64.61 122.2,65 122.2,65.8 RAM2.G7 ; RAM1.K8 124.2,47.32 123.82,46.94 123.82,46.17 v1(123.94,46.04) ; RAM2.K8 124.2,65.22 123.8,64.82 123.8,64.23 123.79,64.22 v1(123.79,64.1) ; RAM4.K8 124.2,78.42 123.8,78.02 123.8,77.15 v1(123.89,77.06) ; 125.03,40.55 124.61,40.13 124.61,39.51 RAM3.K2 ; v1(122.2,78.2) 122.2,78.79 121.8,79.19 RAM4.G7 ; RAM1.G7 121.8,48.09 122.2,47.69 v1(122.2,47.1) ; RAM1.K2 124.58,52.68 124.58,53.26 124.93,53.61 v1(124.93,54.48) ; RAM3.H2 122.6,39.34 123.02,39.76 123.02,40.73 v1(122.9,40.84) ; RAM2.B2 118.06,70.2 118.44,69.82 119.02,69.82 RAM2.D2 ; v1(124.93,85.58) 124.93,84.72 124.58,84.37 124.58,84.04 124.58,84.04 124.58,83.96 124.2,83.58 RAM4.K2 ; RAM4.H2 122.6,83.53 123.02,83.94 123.02,85.03 v1(122.9,85.14)
  BOTTOM w0.254: RAM3.F1 120.64,40.26 120.64,41.15 ; RAM2.C1 RAM2.D2 ; v1(117.4,33.9) RAM3.A8
  BOTTOM w0.305: CPU1.BE51 91.64,51.25 91.45,51.25 v1(91.4,51.2) ; RAM2.D9 119.4,64.6 v1(119,65) ; v1(120.21,45.39) 120.2,45.4 RAM1.E9 ; RAM2.H9 122.59,64.61 122.59,64.11 v1(122.55,64.07) ; v1(116.57,47.08) 116.99,47.5 RAM1.A8 ; RAM2.A8 115.87,65.4 v1(115.81,65.46) ; v1(85.49,53.38) 85.46,53.41 CPU1.AV38 ; v1(80.24,57.74) 79.94,57.43 79.94,56.91 79.99,56.86 79.99,56.19 CPU1.AN27 ; RAM3.B2 v1(117.4,39.5) RAM3.A1 ; CPU1.AU36 84.27,53.56 v1(84.31,53.52) ; RAM3.D2 v1(119,39.5) RAM3.C1 ; v1(79.49,56.11) 78.97,56.11 CPU1.AM25 ; v1(122.2,78.2) RAM4.H9 ; RAM4.E9 120.19,77.8 119.94,77.55 119.65,77.55 RAM4.D9 119.4,77.8 v1(119,78.2) ; v1(118.97,46.27) 119.4,46.69 RAM1.D9 ; v1(120.93,85.55) 121,85.48 RAM4.F1 ; RAM3.E9 120.19,33.5 119.94,33.25 119.65,33.25 RAM3.D9 119.4,33.5 v1(119,33.9) ; RAM3.G7 v1(121.4,34.7) ; CPU1.AY44 88.07,51.88 87.95,51.77 87.95,51.74 87.93,51.72 v1(87.93,51.7) 87.91,51.7 87.87,51.66 CPU1.AV44 ; RAM4.D2 119.4,83.4 v1(119,83) ; v1(116.77,85.21) 117,84.97 RAM4.A1 RAM4.B2 RAM4.C1 ; v1(122.2,47.1) RAM1.H9
  BOTTOM w0.356: RAM3.R1 128.2,40.53 v1(128.93,41.25) ; RAM4.H2 122.6,83.4 v1(122.2,83) ; v1(128.93,54.45) 128.2,53.73 RAM1.R1 ; v1(126.6,32.88) 126.6,32.88 RAM3.N9 ; v1(118.97,46.27) 118.97,46.33 RAM1.C9 ; RAM1.R9 128.2,46.1 v1(128.24,46.06) ; v1(118.97,33.07) 118.97,33.13 RAM3.C9 ; RAM4.C9 118.97,77.43 v1(118.97,77.37) ; v1(128.24,63.96) 128.2,64 RAM2.R9 ; v1(126.6,46.08) 126.6,46.08 RAM1.N9 ; v1(128.24,32.86) 128.2,32.9 RAM3.R9 ; v1(126.6,63.98) 126.6,63.98 RAM2.N9
  BOTTOM w0.508: v1(133.94,39.92) 134.41,39.92 135.3,39.03 136.64,39.03 136.99,39.38 R4048.1 ; R4024.1 135.68,49.01 R4031.1 134.5,49.01 132.38,46.89 132.38,45.55 EC1108.1 132.42,45.45 129.85,45.45 ; EC1107.1 130.59,41.57 130.18,41.99 ; EC1105.1 129.05,75.8
  vias: v1(75.58,62.87) v1(76.07,62.33) v1(76.58,63.1) v1(82.73,52.9) v1(93.79,50.81) v1(93.99,53.78) v1(116.54,76.79) v1(117.32,32.77) v1(117.4,78.2) v1(118.48,54.01) v1(119.65,76.3) v1(119.85,64.1) v1(122.9,71.94) v1(122.9,54.04) v1(123,33.88) v1(124.13,32.84) v1(124.78,72.32) v1(124.83,41.3) v1(126.2,83.8) v1(126.2,52.7) v1(126.6,77.18) v1(126.71,41.97) v1(127.04,84.63) v1(127.04,71.43) v1(127.04,53.53) v1(127.04,40.33) v1(128.21,84.88) v1(128.24,77.16) v1(128.93,72.35) v2(88.35,56.05) v2(95.59,28.73) v2(96.32,48.31) v2(96.81,29.02) v2(97.03,56.47) v2(112.01,84.49) v2(120.85,63.12) v2(127.38,29.49) v2(131.22,59.45) v2(132.91,70.65) v3(77.89,71.36) v3(77.89,70.47) v3(78.77,71.36) v3(78.77,70.47) v3(95.12,27.26) v3(95.12,26.37) v3(95.12,25.48) v3(96.01,27.26) v3(96.01,26.37) v3(96.01,25.48) v3(100.64,55.71) v3(101.48,55.71) v3(102.32,55.71)
1D35V_PWR: length 15.6
  L3 w0.254: v1(91.03,25.62) 88.57,28.08 76.87,28.08 v1(76.54,27.75)
  vias: v2(76.78,27.23) v2(89.15,25.25) v2(92.3,24.61)
1D35V_S3_DISCHG:
  vias: v2(141.96,39.52)
1D35V_VTT_PWRGD: length 113.9
  TOP w0.102: v1(73.41,25.41) 73.6,25.6 PR5107.1
  L3 w0.127: v1(144.73,54.1) 144.73,53.83 144.85,53.71 144.85,51.73 144.98,51.59 145.21,51.36 145.21,48.44 144.11,47.34 144.11,46.49 143.85,46.23 143.12,46.23 142.63,45.74 142.63,45.3 142.11,44.78 142.11,43.3 141.47,42.66 141.24,42.66 140.84,42.27 140.84,42.04 140.07,41.26 140.07,36.21 138.55,34.69 138.55,32.85 138.55,31.96 137.64,31.05 131.53,31.05 130.26,29.78 114.01,29.78 113.12,28.88 107.1,28.88 105.76,30.23 98.74,30.23 96.98,28.47 96.98,25.32 95.9,24.23 93.93,24.23 91.65,21.95 89.66,21.95 88.59,20.89 75.01,20.89 72.65,23.25 72.65,24.64 v1(73.41,25.41)
  BOTTOM w0.102: EC4005.1 74.04,26.34 73.41,25.72 v1(73.41,25.41) ; v1(144.73,54.1) 144.59,53.97 144.59,53.92 v2(139.69,49.02) R4015.2
3D3V_AUX_KBC: length 186.3
  TOP w0.508: v3(103.35,9.18) 103.28,9.25 103.28,10.69 102.96,11.01 102.96,11.57 v3(103.11,11.71) 103.3,11.71 103.64,12.05 103.64,14.65 103.78,14.79 v2(103.78,15.34) D4302.2 103.59,17.78 101.71,19.66 101.71,20.28 102.43,21 103.06,21 D4303.2 103.78,22.28 105.88,24.39 107.1,24.39 D4301.2 ; R2490.1 61.59,4.33 61.59,4.91 61.35,5.15 61.35,5.68 61.72,6.05 61.94,6.05 62.51,6.62 62.51,7.14 62.04,7.61 62.04,7.99 61.28,8.75 61.24,8.75 59.48,10.51 59.48,11.62 59.02,12.07 58.49,12.07 58,11.58 56.87,11.58 v1(56.85,11.61) 57.05,11.81 57.05,13.49 56.25,14.28 55.92,14.28 55.3,14.91 54.55,15.66 54.55,16.86 53.55,17.86 53.25,17.86 52.82,18.29 52.82,20.66 v1(53.52,21.36) 53.56,21.4 53.56,23.5 54.45,24.39 v1(54.45,24.6) 54.42,24.62 v2(54.42,25.79) 54.42,27.87 R2403.1 55.08,28.7 55.75,29.37 v1(55.75,29.57) ; v1(69,23.97) 69.24,23.73 69.32,23.73 69.33,23.72 69.78,23.72 69.92,23.58 69.92,23.58 70.22,23.28 R2407.1
  L3 w0.508: v1(74.12,10.52) 73.81,10.82 71.74,10.82 71.04,11.51 70,11.51 69.31,10.82 64.87,10.82 64.01,11.68 64.01,12.49 62.83,13.67 61.46,13.67 61.1,13.3 60.99,13.3 59.77,12.07 59.02,12.07 58.49,12.07 58.01,11.59 56.86,11.59 v1(56.85,11.61) 56.52,11.94 55.73,11.94 55.73,11.93 52.63,11.93 51.87,12.69 51.09,12.69 50.71,12.31 v1(50.71,12.05) ; v1(54.45,24.6) 55.06,25.21 57.18,25.21 57.56,24.83 66.35,24.83 66.49,24.69 66.5,24.69 66.51,24.68 68.37,24.68 69,24.05 v1(69,23.97) ; v1(55.17,5.79) 55.17,5.48 54.72,5.03 53.29,5.03 52.25,6.08 51.18,6.08 v1(51.1,6) ; v1(46.41,30.19) 46.68,30.19 47.06,29.82 49.47,29.82 50.1,29.19 50.91,29.19 51.29,28.81 52.85,28.81 53.01,28.97 55.31,28.97 55.32,28.99 55.35,28.99 55.72,29.36 55.72,29.38 55.75,29.41 v1(55.75,29.57)
  BOTTOM w0.508: R2437.1 51.08,10.95 50.7,11.33 50.7,12.03 v1(50.71,12.05) 50.71,12.83 R2409.2 ; v1(46.41,30.19) 46.33,30.27 PR4534.1 ; PR4412.1 131.18,6.85 PR4415.1 110.39,6.86 110.28,6.75 105.79,6.75 v3(103.35,9.18) ; v1(56.15,4.85) 57.56,4.85 Q2404.D ; R2408.2 52.79,20.44 53.52,21.17 v1(53.52,21.36) ; R2410.1 v1(55.17,5.79) ; R2462.1 74.08,10.56 v1(74.12,10.52) 75.39,10.52 v2(75.83,10.07) 76.32,9.59 81.14,9.59 82.74,7.99 83.92,7.99 84.74,8.82 85.8,8.82 85.8,8.82 87.09,8.82 97.13,8.82 100.64,12.32 102.71,12.32 102.98,12.05 102.98,11.85 v3(103.11,11.71) ; v1(51.1,6) 51.08,6.03 51.08,6.97 R2608.1
  vias: v2(55.43,4.98) v2(59.85,3.44)
3D3V_AUX_S5: length 435.6
  TOP w0.305: v1(136.5,100.08) v2(137.44,100.08)
  TOP w0.508: v1(64.92,8.52) 64.92,8.52 v2(64.26,9.17) ; R2514.1 136.02,100.55 v1(136.5,100.08) ; v1(44.34,4.74) 44.34,6.6 v2(43.78,7.16) 43.2,7.74 43.2,13.56 43.87,14.23 43.87,15.71 v2(44.28,16.12) 44.28,17.6 v1(44.53,17.85) ; v1(123.72,11.82) 123.97,11.57 PR4434.1 124.49,12.13 PR4438.2 ; PR4417.1 135,9.14 134.37,9.77 v1(134.37,9.81) 134.37,9.85 134.98,10.47 PR4435.1 ; R2491.2 61.81,1.8 61.54,1.53 58.04,1.53 57.7,1.86 v1(57.7,1.93) 57.29,2.35 C2442.2 ; v1(51.7,2.01) 52.3,2.6 R2405.1 ; PR4532.2 41.41,25.85 v2(41.45,25.81) 42.24,26.61 v1(42.24,27.89)
  L3 w0.508: v1(123.72,11.82) 123.79,11.75 123.79,10.64 125.1,9.33 131.98,9.33 133.93,7.38 134.59,7.38 135.06,7.84 135.06,8.52 134.33,9.25 134.33,9.77 v1(134.37,9.81) 135.14,9.81 136.66,11.33 139.99,11.33 145.6,16.93 v1(145.6,18.67) ; v1(73.71,8.95) 73.46,8.95 73.14,9.27 65.68,9.27 v1(64.92,8.52) 64.29,9.15 58.51,9.15 58.14,8.77 58.14,7.59 57.73,7.19 v1(57.73,6.21) 57.73,4.03 57.16,3.46 55.33,3.46 54.58,4.21 53.22,4.21 v1(51.99,5.44) 51.68,5.14 50.29,5.14 49.65,4.49 48.22,4.49 48.02,4.69 46.76,4.69 46.34,4.27 44.81,4.27 v1(44.34,4.74) ; v1(58.78,29.9) 57.67,28.8 57.34,28.8 56.65,28.11 53.38,28.11 53.29,28.02 53.29,28.02 53.21,27.94 50.94,27.94 50.56,28.32 49.75,28.32 49.16,28.91 47.53,28.91 46.51,27.89 v1(42.24,27.89) ; v1(150.19,18.85) 150.32,18.72 150.88,18.72 151.38,19.21 151.38,20.23 151.46,20.32 151.46,41.58 v3(151.38,41.66)
  L4 w0.508: v1(58.01,43.72) 58.31,43.42 58.31,40.89 56.67,39.25 56.67,38.77 55.79,37.89 v1(55.79,37.03) 55.79,34.38 58.22,31.95 58.22,30.45 v1(58.78,29.9) ; v1(42.24,27.89) 42.24,25.45 45.46,22.23 45.46,19.72 44.53,18.79 v1(44.53,17.85) ; v3(151.38,41.66) 151.38,41.7 151.48,41.81 151.48,52.96 150.01,54.43 150.01,62.75 146.72,66.03 146.72,68.96 148.85,71.08 150.53,71.08 151.96,72.5 151.96,73.27 152.84,74.15 156.96,74.15 157.86,75.05 158.61,75.05 v1(158.93,75.37) 160.66,77.1 169.83,77.1 172.91,80.17 172.91,81.49 173.48,82.07 173.48,84.48 172.91,85.06 172.91,94.33 166.11,101.13 156.28,101.13 155.75,100.6 139.32,100.6 138.8,100.08 v1(136.5,100.08) ; v1(57.7,1.93) 57.52,1.75 51.96,1.75 v1(51.7,2.01) 50.99,2.72 49.69,2.72 49.68,2.73 49.68,2.73 49.31,3.1 49.31,3.11 49.09,3.32 45.77,3.32 v1(44.34,4.74)
  BOTTOM w0.203: v1(64.92,8.52) 64.78,8.65 U2401.75
  BOTTOM w0.305: v1(58.01,43.72) 58.23,43.94 RN1803.4
  BOTTOM w0.508: v1(57.73,6.21) 57.5,6.44 R2489.2 ; R4053.1 142.36,46.15 142.66,46.44 142.66,46.95 142.66,46.95 142.66,48.18 141.93,48.91 v2(141.93,50.04) 141.93,50.41 145.46,53.94 145.46,58.72 145.92,59.18 145.92,63.03 143.79,65.16 v2(143.79,67.46) 143.79,70.41 147.47,74.1 152.2,74.1 152.48,74.37 154.35,74.37 155.34,75.37 v1(158.93,75.37) ; v1(51.99,5.44) 51.99,6.05 R2614.1 ; R1830.2 55.87,38.44 v2(55.58,38.15) 55.58,37.25 v1(55.79,37.03) ; v1(145.6,18.67) 146.34,17.93 149.12,17.93 149.48,18.29 PR4419.1 149.54,18.77 150.11,18.77 v1(150.19,18.85) ; Q2404.S 57.7,1.96 v1(57.7,1.93) ; v1(134.37,9.81) 134.23,9.68 134.23,9.25 133.3,8.32 132.64,8.32 131.84,9.11 130.01,9.11 129.75,9.37 128.3,9.37 127.8,8.87 123.72,8.87 122.83,9.76 117.72,9.76 116.42,8.46 109.73,8.46 109.61,8.35 106.57,8.35 104.29,10.63 100.88,10.63 97.6,7.35 82.31,7.35 80.71,8.95 v1(73.71,8.95) ; v1(136.5,100.08) 135.8,100.08 Q2501.2 134.74,99.01 133.37,99.01 131.39,97.03 130.91,97.03 130.4,96.52 R2513.2
3D3V_AUX_S5_MUX:
  vias: v2(135.48,63.2)
3D3V_CAMERA_S0:
  vias: v2(67.82,83.03)
3D3V_CARD: length 15.9
  L4 w0.762: v3(19,27.21) 19,28.62 18.1,29.52 18.1,30.7 14.17,34.63 13.69,34.63 12.97,35.35 12.97,37.52 v3(11.72,38.76)
  BOTTOM w0.635: 15.62,26.1 SD1.6
  vias: v2(17.12,27.2)
3D3V_CARD_S0:
  vias: v2(9.93,37.95) v2(10.69,36.96)
3D3V_GSEN2: length 14.8
  TOP w0.254: R6902.1 59.12,91.66 v1(59.28,91.49) 59.6,91.49 R6905.1 ; U6901.10 55.4,90.66 55.19,90.45 54.52,90.45 C6902.1 54.43,90.49 C6901.1 ; C6901.1 54.73,91.22 U6901.9 ; C6901.1 54.43,91.52 54.55,91.63 R6901.2 54.55,93.25 v1(54.58,93.28) 54.31,93.56 v2(54.31,93.78)
  L3 w0.254: v1(59.28,91.49) 59.28,92.84 58.84,93.28 v1(54.58,93.28)
3D3V_LCDVDD_S0:
  vias: v2(63.91,80.67) v2(64.56,83.96) v3(64.47,83.3) v3(64.47,82.46)
3D3V_PU5402:
  vias: v2(51.09,42.24)
3D3V_PWR:
  vias: v2(24.86,32.17) v2(25.04,29.18)
3D3V_PWR_2:
  vias: v2(36.38,26.67)
3D3V_S0: length 390.3
  TOP w0.305: RN6901.1 60.35,94.67 v1(59.99,95.02) 59.66,94.69 59.66,93.39 RN6901.2
  TOP w0.356: v2(42.61,6.63) 42.61,6.95 42.27,7.3 RN4001.4
  TOP w0.508: v1(48.55,51.96) 48.43,51.96 R806.1 ; R2713.1 136.21,86.04 136.49,85.76 v1(136.67,85.76) ; R5527.1 52.62,80.67 52.62,80.7 v1(52.68,80.75) ; v1(9.93,43.61) 10.48,43.07 R3308.1 ; v1(61.04,28.19) 60.11,27.25 60.11,25.75 R1864.1 60.01,24.77 v2(59.74,24.51) 59.42,24.19 59.42,23.67 59.11,23.36 v1(59.11,22.48) ; v1(33.23,48.76) 34.07,47.93 34.07,47.01 33.79,46.73 v2(33.79,43.87) 33.79,39.94 33.98,39.74 33.98,38.42 33.17,37.61 v1(33.17,35.59) ; v1(61,21.13) 60.4,21.13 R2445.1 ; v1(41.2,3.88) 41.73,3.88 42.41,4.56 42.41,6.43 v2(42.61,6.63) ; v1(53.66,95.01) R6901.1
  TOP w0.762: v3(10.82,67.61) 10.82,65.18 12.21,63.79 13.95,63.79 14.96,62.78 14.96,61.01 15.48,60.49 15.48,58.99 16.19,58.28 16.19,47.43 15.44,46.68 v1(15.17,46.68)
  L3 w0.508: v1(136.67,85.76) 136.93,85.76 138.79,87.62 138.79,91.94 v3(136.99,93.74) ; v1(33.23,48.76) 33.23,50.02 36.14,52.93 41.76,52.93 42.46,52.24 44.06,52.24 45.53,53.71 47.16,53.71 47.8,53.06 47.8,52.63 48.47,51.96 v1(48.55,51.96) ; v1(61.99,5.41) 62.14,5.56 62.14,5.56 62.2,5.62 62.72,5.62 62.77,5.56 62.94,5.56 63.16,5.34 64.79,5.34 66.82,7.37 72.24,7.37 72.58,7.03 75.23,7.03 75.42,6.85 76.44,6.85 76.89,7.29 v1(76.89,8.03) ; v1(51.29,22.08) 51.74,22.53 52.26,22.53 53.01,23.28 55.72,23.28 56.64,22.36 58.18,22.36 58.29,22.48 v1(59.11,22.48) 59.66,22.48 v1(61,21.13)
  L3 w0.762: v3(10.82,67.61) 10.82,67.82 12.17,69.16 12.17,78.53 12.15,78.55 12.15,81.87 15.94,85.67 20.91,85.67 v3(21.42,86.18)
  L4 w0.508: 9.9,39.96 10.33,39.53 12.03,39.53 15.1,36.47 15.1,34.78 16.67,33.21 22.94,33.21 25.36,35.62 28.69,35.62 29.62,34.7 32.28,34.7 v1(33.17,35.59) 33.76,35 37.3,35 38.56,33.73 46.71,33.73 47.41,33.03 47.41,30.1 47.96,29.55 48.93,29.55 49.19,29.29 51.51,29.29 52.06,28.74 56.72,28.74 57.12,29.14 57.12,29.54 v1(57.15,29.57) 57.39,29.57 58.76,28.19 v1(61.04,28.19) 61.55,28.19 62.1,28.74 62.12,28.74 62.4,29.02 70.18,29.02 72.28,31.12 77.81,31.12 v1(78.59,30.34) ; v1(52.68,80.75) 53.8,79.63 57.04,79.63 59.57,82.16 v1(60.44,82.16) 60.82,82.16 61.82,81.16 67.3,81.16 67.82,80.64 v3(67.82,80.45) ; v1(96.42,79.53) 96.44,79.5 ; v1(41.2,3.88) 41.99,3.88 43.69,5.57 45.97,5.57 46.78,4.76 48.25,4.76 48.52,4.49 50.17,4.49 52.18,2.48 57.25,2.48 57.69,2.92 59.9,2.92 61.22,4.24 61.22,4.94 61.7,5.41 v1(61.99,5.41)
  BOTTOM w0.305: RN2601.1 96.11,78.74 96.11,79.22 v1(96.42,79.53) 96.47,79.53 96.77,79.23 RN2601.2
  BOTTOM w0.381: v1(96.42,79.53) 96.32,79.53 95.94,79.91 Q2604.5
  BOTTOM w0.406: Q2604.2 v1(95.94,83.45)
  BOTTOM w0.508: 57.02,28.8 57.12,28.91 57.12,29.54 v1(57.15,29.57) ; 57.02,28.8 R2475.1 ; 57.02,28.8 R2430.1 ; R2400.1 50.97,21.76 v1(51.29,22.08) ; v1(48.55,51.96) 48.82,51.96 49.06,52.21 Q801.G ; R3307.1 8.64,40.29 v1(8.53,40.18) ; R2464.1 61.21,6.48 61.95,5.74 61.95,5.67 61.98,5.65 61.98,5.42 v1(61.99,5.41) ; v1(72,82.8) 72,82.29 73.96,80.32 R1904.1 73.96,76.84 R2607.2 74.75,76.67 74.75,76.67 75.03,76.67 Q1901.G ; R2918.1 146.07,95.78 v1(146.07,95.06) 146.07,94.94 R2702.1 ; v1(64.87,12.04) 61.47,15.44 61.47,18.12 61.83,18.47 61.83,20.82 61.52,21.13 v1(61,21.13) ; v1(78.59,30.34) 79.07,29.86 79.07,29.63 PR5102.2 ; R5516.1 61.1,81.55 61.1,81.83 60.76,82.16 v1(60.44,82.16)
  BOTTOM w0.762: v3(80.52,95.45) 80.52,95.58 79.93,96.17 78.71,96.17 78,96.88 72.23,96.88 71.15,95.81 67.51,95.81 66.71,95.01 60.01,95.01 v1(59.99,95.02) 59.98,95.01 v1(53.66,95.01) 40.55,95.01 39.24,93.7 39.24,88.34 37.07,86.18 v3(21.42,86.18)
  BOTTOM w1.016: v3(98.09,81.15) 98.63,80.62 98.63,75.59 99.88,74.34 99.88,63.82 98.27,62.21 97.39,62.21
  vias: v2(7.37,37.77) v2(65.8,10.47) v2(95.17,62.79) v2(96.47,80.21) v2(111.66,90.86) v2(132.31,96.17) v2(135.22,94.38) v2(147.17,54.15) v2(170.94,92.48) v3(6.74,37.32) v3(68.56,80.86) v3(97.97,87.81) v3(99.03,87.78) v3(110.62,88.88) v3(111.53,89.13) v3(128.61,89.72) v3(128.64,88.84) v3(134.95,96.95) v3(136.36,94.33) v3(148.92,59.83) v3(148.96,60.87) v3(154.37,81.37) v3(154.37,80.52) v3(171.64,92.47)
3D3V_S0_CT: length 1.6
  BOTTOM w0.203: 148.81,47.86 148.66,47.71 U4001.10
  BOTTOM w0.254: 148.81,47.86 148.93,47.98 C4001.1
3D3V_S5: length 333.1
  TOP w0.356: v1(40.87,7.54) 41.07,7.73 RN4001.3
  TOP w0.508: v1(137.77,33.06) 137.77,33.38 139.97,35.58 139.97,39.93 141,40.96 v1(141.44,40.96) ; v1(53.78,5.67) 53.78,6.12 54.19,6.52 R1621.1 ; PR4649.1 33.63,62.81 v1(33.81,63) ; v1(141.75,63.88) 142.23,64.36 142.23,70.63 143.11,71.5 143.11,71.59 144.19,72.67 144.19,74.18 146.03,76.02 146.03,76.83 v2(147.26,78.06) 150.11,80.91 v3(151.31,80.91) ; R2434.1 52.88,15.1 v1(52.88,14.41) ; v1(60.45,4.85) 60.6,5 60.6,5.7 R2426.1 ; v1(89.94,92.1) 89.75,92.1 89.3,91.65 PR5013.1 86.53,91.65 85.22,90.34 85.22,86.29 84.89,85.96 84.89,84.05 v1(84.68,83.85) ; v1(120.14,100.71) 119.99,100.56 PC5301.1 ; v1(50.97,54.06) 50.89,53.98 50.89,51.13 52.34,49.68 54.3,49.68 54.31,49.68 56.33,47.66 v2(56.33,44.78) 56.33,43.49 55.74,42.9 55.74,41.65 v1(56.26,41.12) ; R1620.1 50.25,6.66 v1(50.28,6.64) ; R6106.1 162.89,80.02 160.33,82.58 v1(158.87,82.58) ; R2711.2 144.04,93.54 v1(144.57,94.07) ; R6501.1 43.29,5.73 v1(43.09,5.93) ; PR4306.1 20.89,62.41 21.58,62.41 v1(21.63,62.36) ; PR5007.2 90.9,89.22 90.96,89.29 90.96,89.99 91.07,90.09 91.07,91.68 91.24,91.85 91.24,92 v1(91.29,92.05)
  L3 w0.508: v1(155.32,91.88) 155.49,92.05 155.49,94.07 155.28,94.28 155.28,97.61 153.93,98.96 149.67,98.96 148.79,98.09 146.76,98.09 145.78,97.11 145.78,95.69 144.57,94.48 v1(144.57,94.07) 143.88,94.07 142.51,95.45 142.51,98.04 141.76,98.79 131.42,98.79 129.51,100.7 120.15,100.7 v1(120.14,100.71) ; 141.64,62.72 141.64,60.13 141.39,59.88 141.39,55.82 v1(140.78,55.21) ; v1(49.76,30.42) 49.77,30.42 50.37,29.82 51.42,29.82 51.8,29.44 52.59,29.44 52.75,29.6 53.23,29.6 v1(53.25,29.62) ; v1(33.81,63) 33.81,62.66 31.51,60.35 28.35,60.35 26.76,58.76 26.76,56.08 27.91,54.93 27.91,51.91 30.72,49.1 v3(30.72,47.39) ; v3(144.17,51.04) 144.17,52.64 144.06,52.74 144.06,54.47 144.28,54.69 v1(144.28,55.76)
  L4 w0.508: v1(141.44,40.96) 141.82,40.58 143.56,40.58 144.02,40.12 v1(144.02,39.78) ; v1(53.78,5.67) 53.78,5 55.62,3.16 56.85,3.16 57.65,3.96 60.04,3.96 60.45,4.37 v1(60.45,4.85) ; v1(33.81,63) 33.81,62.4 31.87,60.45 25.19,60.45 24.48,59.74 22.85,59.74 21.73,60.86 21.73,61.86 21.63,61.96 v1(21.63,62.36) ; v1(56.26,41.12) 56.04,40.9 56.04,39.04 55.15,38.15 55.15,31.73 54.71,31.3 v1(54.71,30.98) ; v1(49.76,30.42) 49.56,30.62 49.56,32.18 49.6,32.23 49.6,32.88 47.84,34.65 39.05,34.65 37.6,36.09 37.49,36.09 37.45,36.13 34.02,36.13 33.64,36.52 33.27,36.52 32.58,36.52 v3(31.8,35.74) ; v3(151.31,80.91) 152.65,80.91 153.85,82.11 158.4,82.11 v1(158.87,82.58)
  BOTTOM w0.305: RN1803.3 58.62,43.29 58.52,43.19 57.73,43.19 57.17,43.74 56.42,43.74 55.88,43.21 55.88,41.51 v1(56.26,41.12)
  BOTTOM w0.406: U2404.6 52.97,28.97 53.03,29.03
  BOTTOM w0.508: v1(145.38,35.17) 145.72,35.17 PR4472.1 ; 53.03,29.03 53.25,29.25 v1(53.25,29.62) 53.25,29.83 53.71,30.3 C2445.1 54.05,30.56 54.47,30.98 v1(54.71,30.98) 54.61,31.08 R1858.2 ; PD4303.2 24.66,62.34 21.65,62.34 v1(21.63,62.36) ; v2(52.35,55.32) 52.02,55 51.91,55 v1(50.97,54.06) ; v1(144.28,55.76) 143.73,55.21 v2(142.34,55.21) v1(140.78,55.21) 140.77,55.21 140.22,55.21 139.34,54.32 R4020.1 ; v1(52.88,14.41) 52.88,14.16 52.61,13.9 51.59,13.9 R2471.1 ; R4014.1 144.45,40.21 v1(144.02,39.78) ; v1(155.32,91.88) 156.42,91.88 158.87,89.43 158.87,85.66 158.98,85.55 158.98,82.69 v1(158.87,82.58) ; v1(137.77,33.06) 136.34,33.06 136.07,32.79 PR4473.2 ; v1(49.76,30.42) 49.76,30.67 50.2,31.11 R2420.1 ; v1(141.75,63.88) 141.71,63.93 R2532.2 136.41,64.73 C2505.1 ; PU5301.1 119.06,100.07 119.7,100.71 v1(120.14,100.71) 119.49,101.35 105.24,101.35 97.2,93.31 94.95,93.31 94.58,93.68 93.4,93.68 92.96,93.25 92.63,92.91 ; R1902.1 80.44,83.8 83.11,83.8 v2(83.39,84.08) 84.45,84.08 v1(84.68,83.85)
  vias: v1(9.22,35.8) v1(9.2,35.04) v1(40.92,11.45) v1(72.04,11.74) v2(8.31,35.74) v2(21.16,27.56) v2(31.4,44.9) v2(42.75,7.49) v2(91.97,92.76) v2(144.58,48.62) v3(21.57,31.55) v3(21.57,30.53) v3(21.57,29.52) v3(21.57,28.5) v3(22.33,30.91) v3(22.33,29.89) v3(22.33,28.88) v3(22.33,27.86) v3(22.35,31.88) v3(30.52,41.39) v3(30.71,35.74) v3(31.54,41.39) v3(31.74,47.39) v3(42.23,14.58) v3(43.06,14.59) v3(118.52,14.43) v3(118.62,12.86) v3(119.23,13.69) v3(119.9,14.46) v3(119.97,12.73) v3(120.62,13.73) v3(143.89,50.17) v3(143.95,49.32) v3(144.67,49.86)
3D3V_S5_PRIME: length 155.8
  TOP w0.508: R6324.2 112.57,91.71 112.57,88.81 v2(111.49,87.72) 109.43,85.66 101.13,85.66 v3(100.92,85.87)
  TOP w1.016: 54.58,19.74 54.58,23.27 55.55,24.23 55.55,26.52 57.46,28.44 ; 60.68,46.87 60.36,47.18 60.19,47.18 58.59,48.79 57.47,48.79 55.06,51.2 53.5,51.2 53.09,51.6 53.09,51.71 53.09,51.71 53.09,52.94 53.09,53.26 52.8,53.56 52.8,56.02 53.72,56.94 56.22,56.94 56.65,57.37 56.92,57.37 ; v3(58.47,38.18) 58.7,37.95 60.12,37.95 60.9,38.72 61.45,38.72 62.68,39.96 65.94,39.96
  L3 w0.508: 60.31,55.21 61.61,55.21 63.55,57.15 63.55,58.8 63.13,59.22 63.13,59.56 63.08,59.61 63.08,63.09 63.78,63.8 63.78,63.88 65.01,65.11 65.01,67.5 63.86,68.65 63.86,73.79 65.73,75.66 65.73,77.29 65.39,77.63 65.39,79.55 68.14,82.3 69.68,82.3 70.77,83.39 70.77,84.31 70.56,84.52 70.56,89.48 76.08,95 v3(79,95)
  L3 w1.016: v3(53.56,19.4) 52.7,19.4 50.88,17.58 50.01,17.58 49.19,16.77 45.57,16.77 45.56,16.78 44.83,16.78 44.3,16.26 44.3,15.39 45.13,14.56 46.4,14.56 v3(47.04,13.92)
  L4 w0.508: v3(100.92,85.87) 101.22,86.18 101.22,88.44 97.18,92.47 95.38,92.47 94.15,93.7 90.95,93.7 89.15,95.5 89.15,95.5 88.96,95.69 88.2,96.45 82.6,96.45 81.99,97.06 81.99,97.06 81.33,97.72 79.04,97.72 78.54,97.21 78.54,95.48 79,95.01 v3(79,95)
  BOTTOM w0.305: v1(58.86,56.56) 59.29,56.13 61.67,56.13 CPU1.G1
  vias: v1(58.92,54.8) v1(59.54,54.91) v1(62.43,53.57) v2(57.91,29.41) v2(58.21,56.25) v2(66.4,43.49) v3(59.61,30) v3(66.2,45.85)
3D3V_S5_PRIME_EN: length 14.4
  TOP w0.102: RN4001.2 41.62,8.64 41.9,8.36 42.52,8.36 42.75,8.59 42.75,12.12 42.46,12.41 41.95,12.41 v1(41.46,11.92) 41.15,12.23 C4050.1 40.43,13.39 v2(40.43,13.71) R4064.2
  BOTTOM w0.102: U4016.5 42.94,12.52 42.81,12.65 R4065.2 41.46,12.12 v1(41.46,11.92)
3D3V_S5_PRIME_PG: length 27.6
  L3 w0.102: v1(50.4,16.02) 50.79,16.41 51.73,16.41 52.56,17.24 54.58,17.24 54.98,16.85 58.17,16.85 58.17,16.85 58.53,16.85 58.53,16.85 58.63,16.85 59.55,15.92 61.44,15.92 61.53,16.01 61.88,16.01 v1(62.11,16.24)
  BOTTOM w0.102: R4004.2 C4002.1 49.79,16.02 v1(50.4,16.02) 50.55,16.17 v2(50.55,16.7) ; v1(62.11,16.24) 61.91,16.44 61.91,17.94 62.36,18.39 62.71,18.39 63.68,19.36 63.68,20.34 64.09,20.75 65.15,20.75 67.05,22.64 67.05,23.54 67.24,23.74 67.24,24.15 67.58,24.49 U2401.29
3D3V_S5_PRIME_PG_1: length 1.8
  BOTTOM w0.102: v2(50.53,14.16) R4004.1 49.1,14.16 R4002.1
3D3V_WLAN_S0:
  vias: v2(170.81,84.53) v2(174.22,92.18) v3(175.35,93.81) v3(175.35,92.97) v3(175.67,79.57) v3(175.67,78.18)
12MHZ_IN: length 3.8
  BOTTOM w0.102: v2(18.17,37.16) C3310.1 17.09,38.13 16.19,39.03 U3301.24
+DC_IN:
  vias: v2(22.27,5.73) v2(22.44,18) v2(22.61,72.02) v2(25.62,50.07) v2(26.02,68.19) v2(26.21,73.36) v2(28.95,63.92) v2(29.74,34.6) v2(31.74,12.14) v2(32.65,59.89) v2(33.48,5.08) v2(138.71,11.41) v3(23.81,69.99) v3(24.73,69.65) v3(25.58,72.26) v3(25.58,71.17) v3(25.58,70.08) v3(31.75,4.07) v3(31.75,2.92) v3(32.75,7.8) v3(32.9,4.07) v3(32.9,2.92) v3(33.89,7.8) v3(34.04,4.07) v3(34.04,2.92) v3(138.6,14.27) v3(138.59,13.27) v3(138.66,12.17) v3(139.72,14.2) v3(139.69,13.2) v3(139.69,12.07)
+DC_IN_C:
  vias: v2(23.39,74.53) v2(24.99,75.29) v2(26.85,76.1) v3(24.54,75.83) v3(24.52,74.69) v3(25.38,75.86) v3(25.36,74.73) v3(26.22,75.86) v3(26.2,74.71)
+RTC_PWR: length 3.6
  BOTTOM w0.356: R2501.2 137.23,98.53 v2(137.54,98.22)
  BOTTOM w0.508: RTC1.1 138.22,100.5 137.4,99.68 R2501.2
+VCHGR_R: length 20.1
  BOTTOM w0.254: PG4405.1 121.8,25.14 122.47,25.81 122.47,26.2 123.16,26.89 132.25,26.89 v2(133.33,27.97) 135.47,27.97 136.87,29.37 139.7,29.37 PR4454.1
AC_IN#: length 115.4
  TOP w0.102: PR4434.2 PR4433.1 125.76,10.74 125.91,10.58 126.27,10.58 126.6,10.91 128.11,10.91 v1(128.37,10.66) 128.38,10.65 129.63,10.65 130.11,11.13 PU4404.5 ; v1(109.35,8.98) v2(110,8.98) ; v1(64.72,4.45) 64.76,4.41 64.76,3.07 64.11,2.43 R2487.1
  L3 w0.102: v1(64.72,4.45) 64.72,4.45 65.03,4.45 67.29,6.71 71.75,6.71 72.87,5.59 76.23,5.59 77.47,6.83 85.08,6.83 85.99,7.74 92.35,7.74 92.36,7.74 92.75,7.74 93.35,8.34 106.73,8.34 107.37,8.98 v1(109.35,8.98)
  L4 w0.102: v1(137.77,12.63) 137.88,12.52 137.88,11.33 137.58,11.04 129.83,11.04 129.45,10.66 v1(128.37,10.66)
  BOTTOM w0.102: PR4425.2 128.03,12.62 128.23,12.43 PC4401.1 128.23,10.8 v1(128.37,10.66) 128.37,10.64 127.03,9.3 123.9,9.3 123,10.19 117.54,10.19 116.33,8.98 v1(109.35,8.98) ; v1(137.77,12.63) 138.03,12.36 138.03,11.5 138.95,10.59 144.98,10.59 147.2,12.81 147.2,17.27 147.03,17.45 146.19,17.45 145.16,18.48 145.16,19.82 145.66,20.31 145.66,20.61 145.91,20.87 147.15,20.87 147.82,21.53 PQ4408.5
AC_IN_KBC#: length 6.1
  BOTTOM w0.102: U2401.65 69.48,9.07 72.75,9.07 R2462.2 v2(74.3,9.67)
AC_PRESENT_CPU: length 50.8
  TOP w0.102: v1(52.2,32.21) 52.32,32.08 v2(52.32,31.58) 53.31,30.59 53.31,30.37 53.69,30 53.69,29.22 52.87,28.41 52.87,25.48 52.65,25.26 52.65,21.61 52.14,21.1 R2495.2 ; R1813.1 64.3,50.02 v1(64.75,50.47)
  L3 w0.127: v1(57.16,53.31) 57.14,53.29 57.14,52.99 57.72,52.41 57.85,52.41 58.03,52.23 58.03,51.97 58.42,51.58 59.47,51.58 59.68,51.37 62.14,51.37 62.84,50.67 64.55,50.67 v1(64.75,50.47)
  L4 w0.127: v1(52.2,32.21) 52.32,32.33 52.32,33.05 52.76,33.49 52.76,36.26 53.95,37.44 53.95,38.65 54.83,39.54 54.83,41.62 56.62,43.4 56.62,44.82 56.31,45.12 56.31,48.75 55.88,49.18 55.88,51.97 57.16,53.25 v1(57.16,53.31)
  BOTTOM w0.102: CPU1.C13 64.37,50.08 v1(64.75,50.47)
AC_PRESENT_KBC: length 4.5
  TOP w0.102: R2495.1 53.03,16.81 v1(53.46,16.38)
  BOTTOM w0.102: U2401.113 54.06,17.71 53.67,17.32 52.97,17.32 52.74,17.1 v2(52.74,16.38) v1(53.46,16.38)
AD+_G_1: length 8.6
  TOP w0.254: v1(145.91,24.49) v2(145.09,23.66) 144.86,23.43 PR4401.1
  BOTTOM w0.254: PQ4402.6 149,26.96 149.14,26.82 149.14,26.45 149,26.31 PQ4402.5 147.52,26.31 147.23,26.02 147.23,25.44 146.69,24.9 146.33,24.9 v1(145.91,24.49)
AD+_G_2: length 3.8
  TOP w0.254: PR4401.2 144.86,20.67 v1(144.84,20.65) v2(144,20.65)
  BOTTOM w0.254: PU4402.4 144.1,20.38 PR4403.2 144.36,20.65 v1(144.84,20.65)
AD+_TO_SYS:
  vias: v2(141.39,20.32)
AD_IA: length 83.6
  TOP w0.102: v1(53.7,11.06) 53.75,11.01 C2438.2 54.83,10.82 C2428.2 55.46,10.82 55.9,10.82 56.35,10.36 57.68,10.36 58.12,9.93 58.12,8.13 58.6,7.64 58.93,7.64 59.24,7.33 59.24,6.47 59.28,6.43 59.28,5.31 59.64,4.95 59.64,4.72 v1(59.76,4.6) ; v1(113.74,10.21) v2(120.07,10.21) 121.95,10.21 122.78,9.37 PR4422.2
  L3 w0.127: v1(59.76,4.6) 59.76,4.56 59.77,4.55 59.77,4.52 60.12,4.17 62.43,4.17 63.13,3.47 64.72,3.47 67.71,6.47 71.65,6.47 72.78,5.34 76.32,5.34 77.57,6.59 85.18,6.59 86.09,7.5 92.25,7.5 92.26,7.5 92.86,7.5 93.41,8.05 109.17,8.05 111.32,10.21 v1(113.74,10.21)
  BOTTOM w0.102: U2401.97 53.94,11.31 v1(53.7,11.06)
AD_IA_HW: length 96.7
  TOP w0.102: v2(57.91,13.62) 57.52,14 v1(57.46,14)
  L3 w0.102: v1(137.63,10.56) 137.39,10.32 137.39,9.46 134.88,6.95 133.75,6.95 131.8,8.9 119.08,8.9 114.66,13.31 110.61,13.31 109.85,14.07 105.4,14.07 104.35,15.12 101.26,15.12 98.42,12.28 94.7,12.28 93.56,12.28 93.52,12.24 91.72,10.44 89.25,10.44 88.84,10.86 88.33,11.37 85.8,11.37 85.72,11.28 71.89,11.28 71.22,11.94 69.82,11.94 69.13,11.25 65.05,11.25 64.44,11.86 64.44,12.78 62.93,14.3 59.64,14.3 59.35,14 v1(57.46,14)
  BOTTOM w0.102: PQ4407.5 135.7,11.12 135.9,11.32 136.58,11.32 137.34,10.56 v1(137.63,10.56) ; U2401.105 56.67,14.51 57.19,13.99 57.44,13.99 v1(57.46,14)
AD_IA_HW2: length 95.5
  TOP w0.102: v1(94.1,20.07) 94.13,20.04 97.62,20.04 98.22,19.44 99.3,19.44 99.84,18.9 100.7,18.9 102.26,17.35 102.26,16.9 102.57,16.58 102.57,13.03 101.55,12.01 v2(101.55,11.01) 101.55,9.9 102.19,9.26 v1(102.33,9.26)
  L3 w0.102: v1(94.1,20.07) 93.55,19.53 72.6,19.53 70.82,21.31 67.35,21.31 65.71,22.95 65.71,23.2 65.44,23.47 63.94,23.47 63.56,23.09 62.11,23.09 61.87,23.33 60.01,23.33 v1(59.85,23.17)
  BOTTOM w0.102: PQ4407.2 135.7,9.18 135.48,9.4 134.78,9.4 134.67,9.29 134.67,9.07 133.48,7.88 133.26,7.88 132.54,7.16 132.54,6.53 132.21,6.21 103.53,6.21 101.94,7.8 101.94,8.87 v1(102.33,9.26) ; v1(59.85,23.17) 59.85,23.71 59.58,23.97 U2401.9
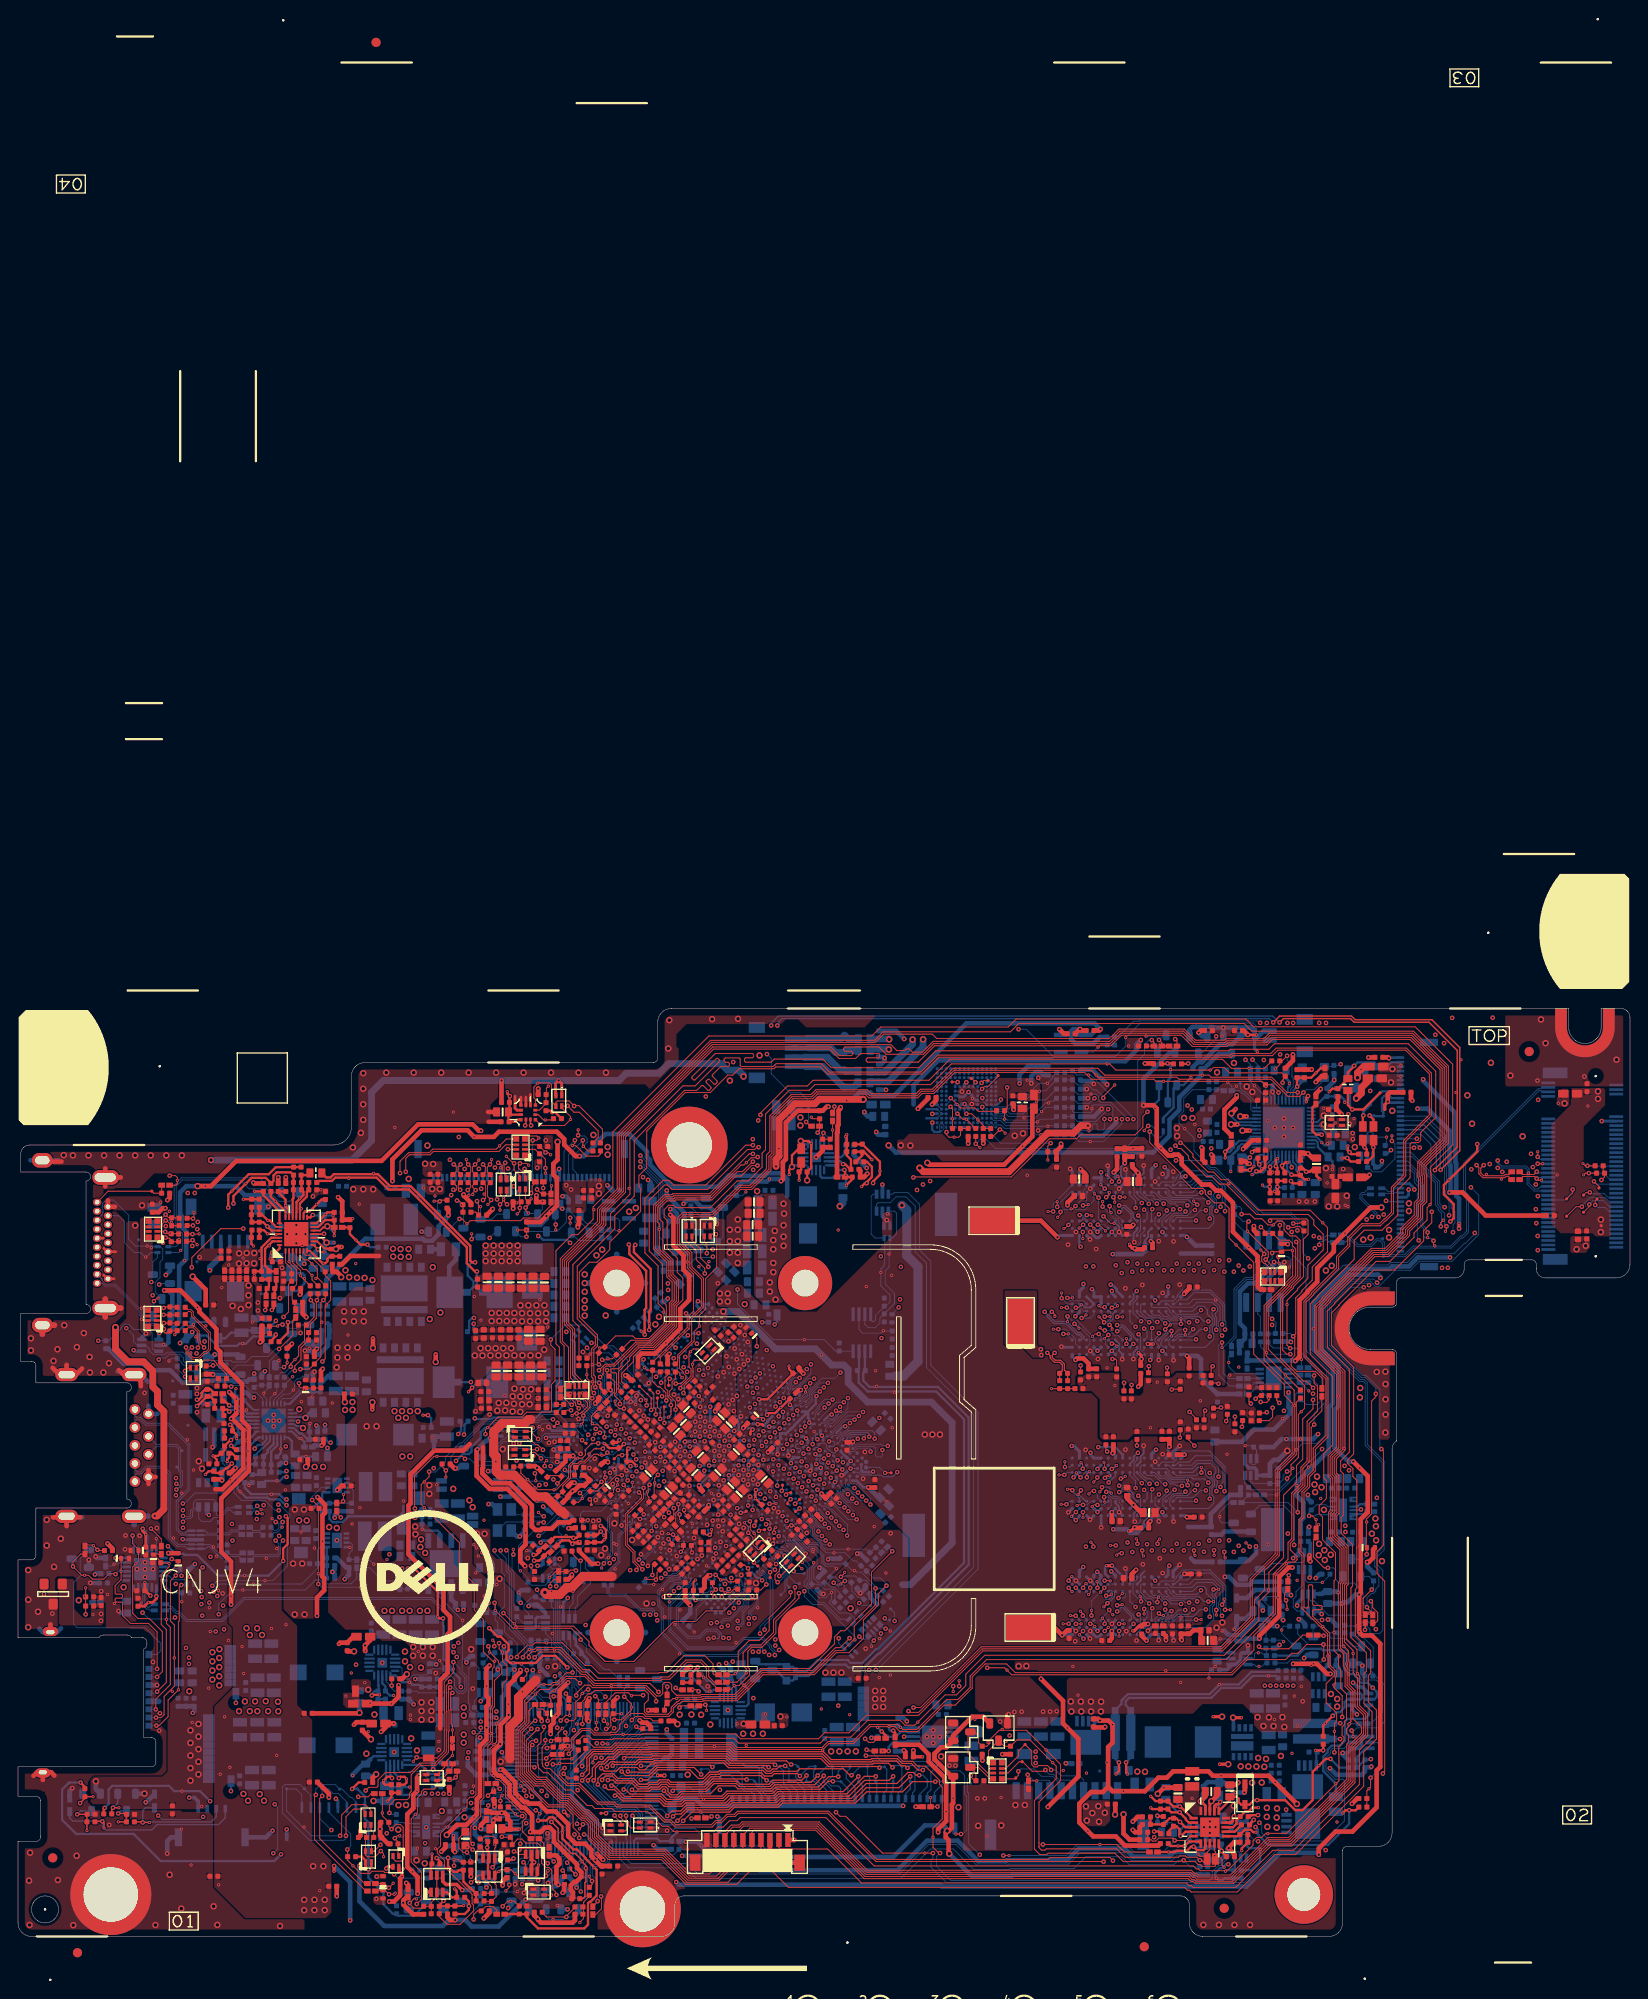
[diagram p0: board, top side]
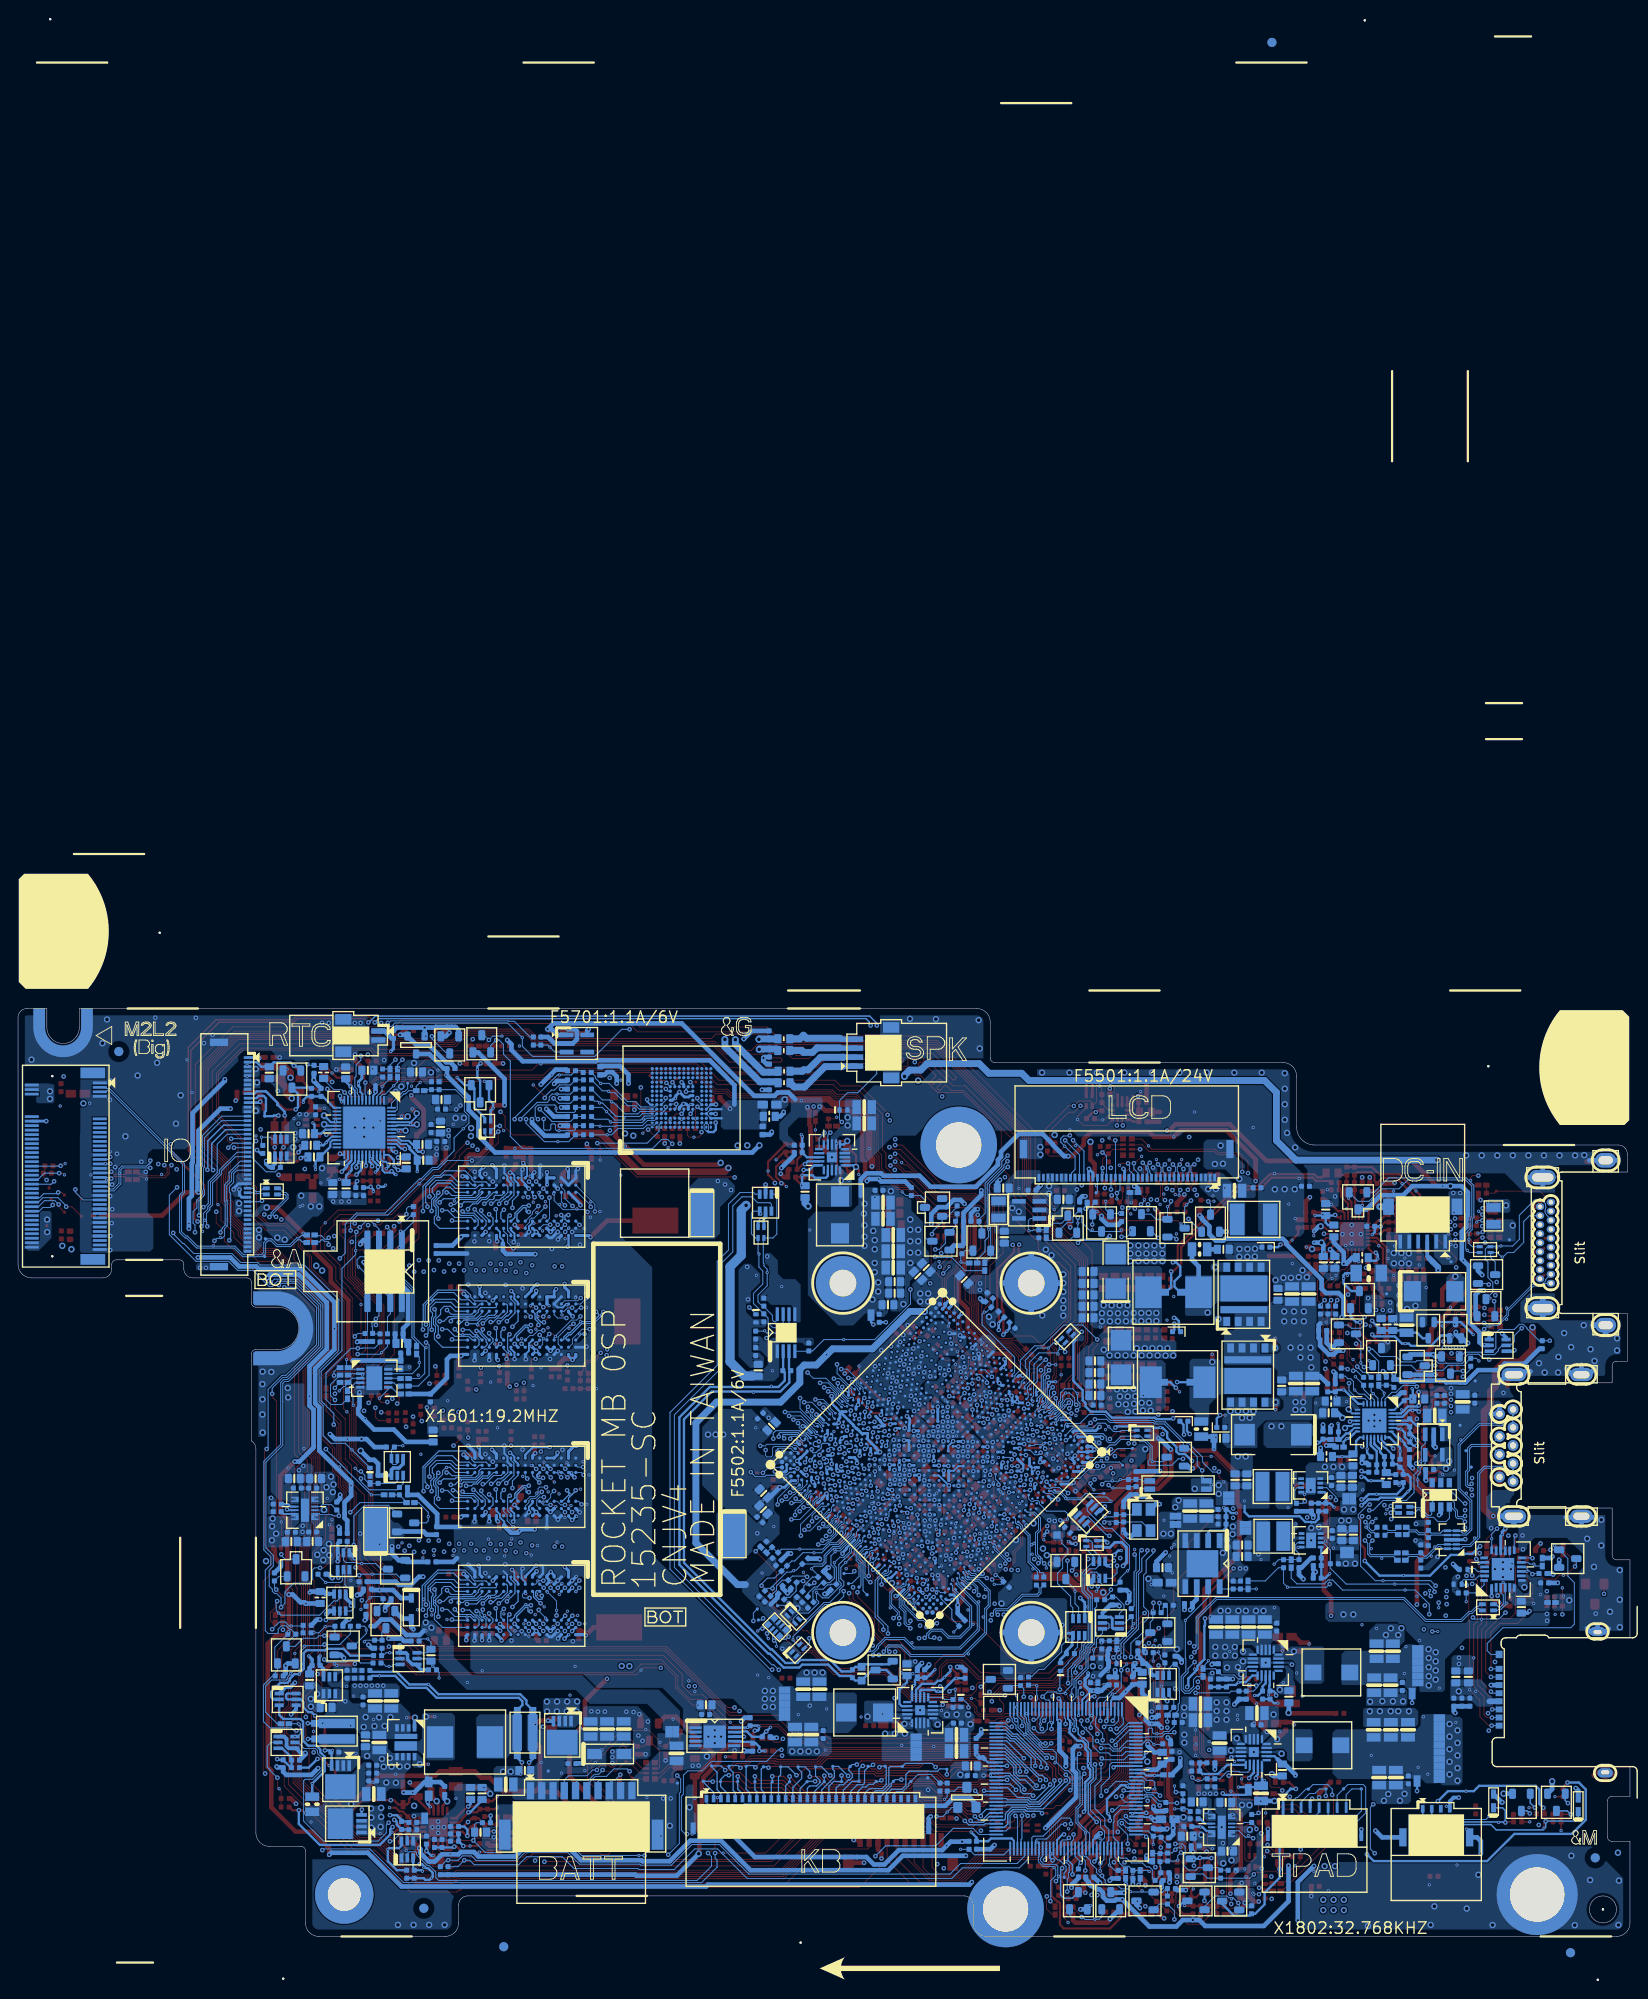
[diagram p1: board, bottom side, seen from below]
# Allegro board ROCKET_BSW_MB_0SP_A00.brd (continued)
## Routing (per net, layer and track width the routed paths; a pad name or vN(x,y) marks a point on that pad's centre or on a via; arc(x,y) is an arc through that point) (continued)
AD_OFF_L: length 4.9
  BOTTOM w0.254: v2(17.4,66.8) 18.79,68.2 PQ4304.3 PQ4305.1
AD_OFF_R: length 185
  TOP w0.254: v1(52.3,34.22) 53.23,33.28 53.57,33.28 54.44,32.41 54.44,31.76 54.21,31.52 54.21,30.77 54.62,30.35 v2(54.94,30.35) 57.44,30.35 58.22,31.14 59.67,31.14 60.95,29.86 v1(60.97,29.86)
  L4 w0.254: v1(60.97,29.86) 61,29.89 61,29.96 61.13,30.09 69.98,30.09 71.82,31.93 79.37,31.93 81.15,30.15 84.92,30.15 85.56,30.79 88.75,30.79 89.38,31.42 94.26,31.42 94.96,30.72 97.36,30.72 98,30.08 106.59,30.08 107.36,29.31 110.86,29.31 112.14,28.03 113.87,28.03 115.11,29.26 140.83,29.26 142.09,28 142.09,27.56 141.28,26.74 141.28,25.41 141.8,24.89 141.8,20.56 140.74,19.5 v1(140.74,14.08) ; v1(28.61,68.34) 27.82,67.55 27.82,65.92 27.15,65.25 25.28,65.25 22.9,62.87 21.11,62.87 19.19,60.95 19.19,59.73 19.19,59.73 19.19,58.38 19.19,58.38 19.19,54.5 21.34,52.35 21.34,50.77 26.84,45.27 26.84,44.08 27.73,43.19 31.49,43.19 33.26,41.42 33.26,40.81 35.4,38.67 49.29,38.67 52.12,35.84 52.12,34.39 v1(52.3,34.22)
  BOTTOM w0.254: v1(140.74,14.08) 140.77,14.05 PU4301.4 ; v1(28.61,68.34) 28.61,68.27 PR4310.1 PR4309.2 25.04,67.26 PC4301.2 23.62,67.02 23,66.39 PQ4305.3
ALERT#: length 5.7
  BOTTOM w0.102: R2605.2 96.07,67.2 v2(96.04,67.23) 95.78,66.97 93.73,66.97 93.34,67.36 U2601.6
ALL_SYS_PWRGD: length 3.5
  TOP w0.102: R2439.2 61.22,25.36 v2(61.22,24.53) 60.78,24.53 v1(60.22,23.97)
  BOTTOM w0.102: v1(60.22,23.97) 60.22,24.09 59.98,24.33 U2401.10
ALS_INT#: length 121.2
  TOP w0.102: v1(62.16,88.92) v2(62.16,89.53)
  L3 w0.102: v1(155.24,88.55) 155.32,88.62 155.32,89.26 156.5,90.44 156.5,98.62 154.88,100.24 146.65,100.24 145.85,99.44 138.32,99.44 138.28,99.4 137.66,99.4 137.47,99.6 135.71,99.6 133.92,101.39 94.48,101.39 92.95,99.86 83.68,99.86 83.58,99.76 82.39,99.76 81.29,98.66 76.54,98.66 66.89,89 65.05,89 64.39,88.34 63.55,88.34 62.98,88.92 v1(62.16,88.92)
  BOTTOM w0.102: v1(62.16,88.92) 62.23,88.85 62.89,88.85 63.17,88.57 63.17,88.17 61.58,86.58 61.58,85.13 61.98,84.73 61.98,84.34 LCD1.33 ; v1(155.24,88.55) 155.25,88.55 IOBD1.19
AMBER_LED_BAT: length 4.7
  TOP w0.152: v1(6.57,13.55) 7.66,13.55 ; 7.66,13.55 EC6405.1 ; 7.66,13.55 7.65,13.54 R6407.2 v2(7.65,11.75)
  BOTTOM w0.152: v1(6.57,13.55) 6.95,13.93 Q6404.C
AMP_MUTE#: length 162.1
  L3 w0.102: v1(67.48,23.36) 69.05,21.79 71.02,21.79 72.8,20.01 88.95,20.01 90.02,21.08 92.06,21.08 94.34,23.36 96.26,23.36 97.86,24.95 97.86,28.06 99.15,29.35 105.39,29.35 106.78,27.97 113.52,27.97 115.09,29.54 130.36,29.54 131.63,30.81 137.74,30.81 138.79,31.86 138.79,32.16 138.79,32.17 138.79,32.75 138.79,34.59 140.31,36.11 140.31,40.64 141.08,41.41 141.08,42.17 141.34,42.42 141.64,42.42 142.35,43.13 142.35,44.68 142.87,45.2 142.87,45.64 143.22,45.99 143.95,45.99 144.16,46.2 144.54,46.2 145.65,47.32 145.65,48.33 145.98,48.66 145.98,50.93 145.36,51.56 145.36,51.56 145.23,51.69 145.23,55 145.12,55.11 145.12,63.36 143.7,64.78 143.7,74.74 v1(143.18,75.26)
  BOTTOM w0.102: U2401.30 67.98,24.47 67.48,23.96 v1(67.48,23.36) ; v1(143.18,75.26) 142.59,75.86 142.59,79.05 141.34,80.3 138.14,80.3 134.35,84.1 134.16,84.1 132.91,85.35 132.37,85.35 130.51,87.21 130.51,88.63 v2(129.48,89.66) 128.86,90.28 128.86,91.08 129.37,91.59 129.37,93.01 130.35,93.99 R2719.2 R2712.1 133.71,93.99 R2708.1
AUD_AGND: length 17.5
  TOP w0.356: v1(152.02,92.66) 151.68,92.33 AFTP2908.1
  TOP w0.508: EC2707.1 132.62,86.61 v1(132.44,86.78) ; R2905.2 146.49,92.62 146.32,92.45 EC2905.2 146.37,91.78 v1(146.91,91.24) ; C2702.1 143.66,86.4 v1(143.17,86.89) 142.82,86.89 142.73,86.98 EC2703.1 142.32,86.96 R2704.1 ; v1(135.97,87.4) 136.94,88.37 EC2710.1 ; v1(152.02,92.66) 152.02,93.45 152.27,93.7 EC2705.1 ; EC2704.1 152.05,97.58 v1(152.15,97.49)
  BOTTOM w0.203: U2701.25 143.04,86.76 v1(143.17,86.89) ; U2701.38 136.92,87.98 136.39,87.45 136.02,87.45 v1(135.97,87.4)
  BOTTOM w0.305: v1(152.02,92.66) 152.13,92.55 IOBD1.11 ; IOBD1.1 152.21,97.55 v1(152.15,97.49)
  vias: v1(132.43,87.47) v1(142.18,81.57) v1(143.01,81.57) v1(143.93,81.58) v1(147.07,85.18) v1(147.65,91.26) v1(148.12,89.17) v1(148.14,88.49) v1(150.07,93.85)
AUD_HP1_JACK_L: length 3.1
  TOP w0.254: R2908.1 139.76,85.33 v1(139.59,85.5) 139.59,86.18 v2(139.75,86.34)
  BOTTOM w0.203: 139.88,86.02 U2701.32
  BOTTOM w0.254: v1(139.59,85.5) 139.59,85.69 139.88,85.98 139.88,86.02
AUD_HP1_JACK_L1: length 19.6
  TOP w0.254: EC2907.1 139.8,82.89 139.76,82.93 v1(139.76,83.2) R2908.2 139.77,83.87 R2912.2 ; R2907.1 150.43,87.61 v1(150.41,87.59) 150.41,86.63 149.8,86.01 R2922.2
  L3 w0.254: v1(139.76,83.2) 139.84,83.28 147.27,83.28 148.2,84.2 148.2,85.37 v1(150.41,87.59)
  BOTTOM w0.254: R2919.1 139.84,83.12 v1(139.76,83.2) 139.47,82.91 v2(139.47,82.67)
AUD_HP1_JACK_R: length 2.9
  TOP w0.254: v1(138.96,85.41) 138.96,84.79 R2910.1
  BOTTOM w0.203: U2701.33 139.48,86.12 139.29,85.93
  BOTTOM w0.254: 139.29,85.93 138.96,85.59 v1(138.96,85.41) 138.96,85.12 v2(139.24,84.83)
AUD_HP1_JACK_R1: length 19
  TOP w0.254: R2910.2 138.93,83.23 v1(138.91,83.21) 138.91,82.96 138.97,82.91 EC2908.1 ; v1(141.28,83.84) 141.53,83.59 R2913.2 ; R2909.1 149.25,87.78 v1(149.44,87.59) 149.68,87.35 R2921.2
  L3 w0.254: v1(138.91,83.21) 139.54,83.84 v1(141.28,83.84) 141.28,83.83 146.96,83.83 147.65,84.53 147.65,85.58 149.44,87.37 v1(149.44,87.59)
  BOTTOM w0.254: v1(138.91,83.21) 138.3,83.21 v2(138.12,83.39) ; v1(141.28,83.84) 141.41,83.71 R2920.1
AUD_PC_BEEP: length 18.2
  TOP w0.254: v2(142.98,92.64) 142.98,93.1 v1(143.17,93.29) ; C2720.2 129.82,96.85 v1(129.87,96.9)
  L3 w0.254: v1(129.87,96.9) 130.58,97.61 135.18,97.61 136.74,96.04 141.16,96.04 141.87,95.33 141.87,95.19 143.17,93.89 v1(143.17,93.29)
  BOTTOM w0.203: U2701.12 143.05,92.81 143.16,92.92
  BOTTOM w0.254: 143.16,92.92 143.16,92.92 143.16,93.28 v1(143.17,93.29)
AUD_PC_BEEP_C: length 6
  TOP w0.254: R2717.1 127.51,96.85 v1(127.57,96.91) 128.18,96.91 C2720.1
  BOTTOM w0.254: v1(127.57,96.91) 127.91,96.57 v2(127.91,96.24) 127.91,95.3 127.61,95 D2701.3
AUD_PORTA_L_R_B: length 7.2
  TOP w0.254: v1(150,91.12) 150.43,90.69 R2907.2
  BOTTOM w0.254: v1(150,91.12) 150.5,91.12 150.57,91.06 AFTP2906.1 151.53,91.5 151.38,91.64 151.38,93.04 151.64,93.3 152.2,93.3 152.45,93.05 IOBD1.10
AUD_PORTA_R_R_B: length 6.9
  TOP w0.254: v1(149.31,91.13) 149.25,91.07 R2909.2
  BOTTOM w0.254: v1(149.31,91.13) 149.31,91.54 AFTP2907.1 150.09,92.51 151.36,93.78 151.4,93.78 151.43,93.8 152.42,93.8 152.67,93.55 IOBD1.9
AUD_SENSE: length 11.2
  TOP w0.254: R2914.2 147.59,92.28 v1(148.08,91.8) 149.31,91.8 AFTP2909.1
  BOTTOM w0.254: v1(148.08,91.8) 147.83,92.05 147.83,93.54 Q2901.D 146.39,94.21 R2709.2
AUD_SENSE_A: length 4.7
  BOTTOM w0.203: 144.18,92.34 143.82,91.98 U2701.13
  BOTTOM w0.254: 144.18,92.34 145.08,93.24 R2702.2 146.31,93.24 R2709.1 146.81,93.25 147.24,92.81 v2(147.24,92.58)
AUD_SPK_L+: length 47.8
  TOP w0.508: v3(135.89,89.44) v2(136.69,89.44)
  L3 w0.762: v3(96.65,98.46) 96.99,98.46 99.25,96.19 120.35,96.19 123.47,93.07 130.07,93.07 134.03,89.1 135.56,89.1 v3(135.89,89.44)
  BOTTOM w0.203: U2701.42 136.03,89.58 v3(135.89,89.44)
  BOTTOM w0.762: v3(96.65,98.46) 96.6,98.51 EC2902.1 94.74,98.51 R2902.1
AUD_SPK_L+_C: length 7.7
  BOTTOM w0.61: 87.73,98.63 87.7,98.6 SPK1.3
  BOTTOM w0.762: 87.73,98.63 90.22,98.63 90.72,98.13 AFTP2902.1 91.94,98.34 R2902.2
AUD_SPK_L-: length 47.6
  TOP w0.508: v3(134.63,90.14) v2(135.33,90.14)
  L3 w0.762: v3(96.68,99.58) 96.69,99.59 97.29,99.59 99.67,97.21 120.77,97.21 123.89,94.08 130.49,94.08 134.44,90.13 134.63,90.13 v3(134.63,90.14)
  BOTTOM w0.203: v3(134.63,90.14) 134.73,90.04 136.84,90.04 136.9,89.98 U2701.43
  BOTTOM w0.762: v3(96.68,99.58) 96.63,99.63 EC2901.1 94.58,99.63 R2901.1
AUD_SPK_L-_C: length 7.7
  BOTTOM w0.508: 87.56,99.6 87.65,99.7
  BOTTOM w0.61: SPK1.4 87.56,99.6
  BOTTOM w0.762: R2901.2 92.13,99.64 AFTP2901.1 91.4,99.7 87.65,99.7
AUD_SPK_R+: length 50.3
  TOP w0.508: v3(135.65,91.02) v2(136.34,91.02)
  L3 w0.762: v3(135.65,91.02) 135.74,91.11 135.74,91.74 131.35,96.13 124.72,96.13 121.59,99.26 110.25,99.26 110.21,99.3 100.73,99.3 v3(100.45,99.57)
  BOTTOM w0.203: U2701.45 135.89,90.78 v3(135.65,91.02)
  BOTTOM w0.762: R2904.1 94.65,94.86 EC2904.1 96.56,94.86 100.45,98.75 v3(100.45,99.57)
AUD_SPK_R+_C: length 8.5
  BOTTOM w0.61: 87.4,96.55 87.35,96.6 SPK1.1
  BOTTOM w0.762: R2904.2 93.03,94.57 93.03,94.57 92.75,94.29 AFTP2904.1 91.6,94.29 89.34,96.55 87.4,96.55
AUD_SPK_R-: length 49.6
  TOP w0.508: v3(134.66,91.36) v2(135.15,91.85)
  L3 w0.762: v3(134.66,91.36) 134.65,91.36 130.89,95.11 124.3,95.11 121.19,98.22 100.28,98.22 99.29,99.21 v3(99.29,99.54)
  BOTTOM w0.203: v3(134.66,91.36) 134.71,91.31 134.71,90.97 135.3,90.38 U2701.44
  BOTTOM w0.762: v3(99.29,99.54) 99.29,99.04 98,97.75 98,97.75 96.18,95.93 EC2903.1 94.65,95.93 R2903.1
AUD_SPK_R-_C: length 8
  BOTTOM w0.61: SPK1.2 87.29,97.6
  BOTTOM w0.762: R2903.2 91.86,96.04 AFTP2903.1 91.22,96.19 89.83,97.58 87.31,97.58 87.29,97.6
AUD_VREF: length 3.5
  BOTTOM w0.203: 141.88,85.22 141.88,85.58 141.48,85.98 U2701.28
  BOTTOM w0.254: C2705.2 142.49,84.43 v2(142.09,84.84) 141.88,85.05 141.88,85.22
BAT_AMBER: length 22.1
  TOP w0.152: R6407.1 8.59,12.77 v1(9.36,12.77) 9.54,12.59 v2(9.54,12.01)
  BOTTOM w0.152: EC6427.1 5.74,13.13 6.07,12.8 9.33,12.8 v1(9.36,12.77) 9.36,12.13 9.66,11.82 14.84,11.82 15.44,12.42 22.24,12.42 23,13.18 LED1.1
BAT_IN#: length 147.9
  TOP w0.102: 106.31,17.29 106.16,17.29 105.74,17.71 v1(105.74,17.86) ; 106.31,17.29 EC4305.2 ; 106.31,17.29 106.31,18.14 105.68,18.76 D4302.3 106.58,18.77 107.86,17.49 RN4301.4 ; RN2402.3 v1(59.12,4.6)
  L3 w0.102: v1(59.12,4.6) 59.12,4.87 59.56,5.31 60.43,5.31 60.45,5.34 61.09,5.34 61.44,4.98 v1(62.46,4.98) 62.53,4.91 65.06,4.91 67.08,6.94 71.84,6.94 72.18,6.6 75.05,6.6 75.24,6.42 76.69,6.42 77.33,7.06 84.99,7.06 85.9,7.97 92.66,7.97 93.34,8.65 104.8,8.65 105.22,9.07 v1(106.74,9.07) 108.4,10.73 113.83,10.73 119.23,5.33 129.87,5.33 131.25,3.95 136.27,3.95 140.37,8.05 142.73,8.05 144.72,10.04 145.26,10.04 149.63,14.41 149.63,20.25 150.61,21.22 150.61,25.9 150.16,26.34 150.16,26.75 149.78,27.13 149.78,28.02 150.79,29.02 150.79,34.01 v1(150.7,34.1)
  BOTTOM w0.102: v1(106.74,9.07) 105.51,10.3 105.51,15.87 105.36,16.02 105.36,17.48 v1(105.74,17.86) ; U2401.80 62.78,8.45 62.23,7.9 62.23,7.14 62.31,7.06 62.31,6.53 62.46,6.38 v1(62.46,4.98) ; PC4433.1 147.26,33.71 PR4472.2 147.32,34.46 v2(148.58,34.46) 148.81,34.46 149.25,34.9 149.9,34.9 v1(150.7,34.1)
BAT_SCL: length 114.2
  TOP w0.102: PG4407.2 132.89,8.28 132.89,7.85 132.82,7.78 131.4,7.78 131.2,7.98 130.96,7.98 130.64,8.31 129.52,8.31 v1(129.37,8.46) 129.17,8.46 129.02,8.31 122.66,8.31 121.73,9.24 114.31,9.24 114.17,9.1 113.4,9.1 112.83,9.67 112.83,9.68 112.8,9.71 112.8,15.08 115.22,17.51 115.22,18.9 v2(114.83,19.29) 112.31,21.81 110.85,21.81 EC4301.1 109.45,21.11 D4301.3 107.71,20.62 107.71,18.77 107.84,18.64 RN4301.2
  BOTTOM w0.102: U2401.70 66.78,8.6 67.77,7.61 74.09,7.61 75.27,6.44 97.98,6.44 101.25,9.71 103.79,9.71 106.07,7.43 109.99,7.43 110.11,7.54 117.19,7.54 118.5,8.85 122.45,8.85 123.34,7.96 128.27,7.96 128.77,8.46 v1(129.37,8.46) 130.08,7.75 PR4415.2
BAT_SDA: length 120.1
  TOP w0.102: PG4408.2 131.57,8.29 131.4,8.46 v1(131.16,8.46) 130.84,8.79 129.72,8.79 129.57,8.94 128.94,8.94 128.79,8.79 122.86,8.79 121.93,9.72 114.11,9.72 113.97,9.58 113.6,9.58 113.31,9.87 113.31,10.03 113.31,14.91 115.7,17.31 115.7,19.1 v2(114.1,20.7) 111.92,22.88 108.89,22.88 107.87,21.86 107.87,21.46 107.52,21.11 EC4302.1 106.6,21.51 106.6,22.28 106.18,22.7 D4303.3 105.44,22.45 105.44,20.3 107.6,18.14 RN4301.3
  BOTTOM w0.102: 131.16,8.46 131.31,8.46 PR4412.2 ; 131.16,8.46 v1(131.16,8.46) ; 131.16,8.46 130.05,8.46 129.57,8.94 128.57,8.94 128.07,8.44 123.54,8.44 122.65,9.33 117.9,9.33 116.6,8.03 109.91,8.03 109.79,7.91 106.39,7.91 104.11,10.2 101.05,10.2 97.78,6.92 75.47,6.92 74.29,8.1 68.02,8.1 67.18,8.93 U2401.69
BAT_WHITE: length 13.7
  TOP w0.152: R6408.1 13.77,12.72 v1(13.83,12.65) v2(14.58,12.65)
  BOTTOM w0.152: EC6428.1 14.14,14.28 13.84,13.98 13.84,12.66 ; 13.84,12.66 13.89,12.71 21.43,12.71 22,13.28 LED1.2 ; 13.84,12.66 v1(13.83,12.65)
BATT_WHITE_LED#: length 54.4
  TOP w0.254: R6409.2 9.51,14.17 v1(9.61,14.27)
  L3 w0.254: v1(21.31,15.02) 23.63,12.7 33.75,12.7 34.36,13.31 38.92,13.31 40.98,15.37 42.17,15.37 43.81,17.01 43.81,17.85 44.35,18.39 44.77,18.39 45.59,17.57 47.53,17.57 48.32,18.37 50.5,18.37 52.58,20.45 v1(53.7,20.45)
  BOTTOM w0.203: U2401.118 54.09,19.71 54,19.8 53.99,19.8 53.87,19.92 53.87,19.93 53.86,19.94 53.86,20.28 v1(53.7,20.45)
  BOTTOM w0.254: v1(21.31,15.02) 20.2,16.13 v2(18.21,16.13) 17.34,16.13 16.75,16.72 10.46,16.72 10.06,16.31 10.06,14.71 v1(9.61,14.27)
BATT_WHITE_LED_R#: length 3.2
  TOP w0.152: v2(11.2,14.29) v1(10.54,14.29) 10.4,14.15 R6409.1
  BOTTOM w0.152: v1(10.54,14.29) 11.07,14.81 Q6403.B
BKLT_CTRL: length 16.2
  TOP w0.102: R5524.1 49.38,81.22 R5505.2 48.92,81.69 v1(48.72,81.69) ; RN5501.7 54.38,87.37 v1(54.37,87.37)
  L4 w0.127: v1(54.37,87.37) 54.61,87.13 54.61,85.64 54.84,85.41 54.84,84.64 52.43,82.22 50.32,82.22 49.78,81.69 v1(48.72,81.69)
  BOTTOM w0.102: v1(48.72,81.69) 48.72,81.69 v2(49.2,81.21) 49.43,80.98 D5502.3
BLON_OUT: length 167.5
  TOP w0.102: v1(64.87,21.43) 64.93,21.37 v2(65.46,21.37) ; RN5501.6 54.11,87.87 53.36,87.12 46.09,87.12 45.73,86.76 43.44,86.76 43.03,86.36 v1(43.03,84.87)
  L3 w0.102: v1(20.39,37.67) 19.66,36.94 19.66,27.69 21.38,25.97 21.38,15.74 24.04,13.07 33.69,13.07 34.23,13.61 38.78,13.61 40.84,15.67 42.04,15.67 43.51,17.14 43.51,17.98 44.23,18.7 44.9,18.7 45.72,17.88 47.4,17.88 48.2,18.67 50.37,18.67 51.1,19.4 51.1,19.56 53.34,21.79 53.7,21.79 56.88,18.61 56.88,18.59 57.38,18.09 59.22,18.09 60.14,17.17 60.92,17.17 61.44,17.69 61.44,18.22 61.55,18.32 61.55,18.55 63.47,20.48 64.35,20.48 64.87,21 v1(64.87,21.43)
  L4 w0.102: v1(43.03,84.87) 42.73,85.18 25.24,85.18 25.04,85.18 24.85,85.18 20.62,80.94 20.62,75.02 19.92,74.33 19.92,72.88 18.21,71.17 18.21,66.75 17.05,65.58 17.05,65.57 16.81,65.34 16.81,59.8 17.57,59.05 17.57,52.33 19,50.89 19,42.09 18.72,41.81 18.72,40.93 19.89,39.75 19.89,38.16 20.39,37.67 v1(20.39,37.67)
  BOTTOM w0.102: v1(64.87,21.43) 65.18,21.43 66.59,22.83 66.59,23.78 66.73,23.92 66.73,24.32 66.78,24.37 U2401.27
BLON_OUT_C: length 6.3
  TOP w0.102: RN5501.3 57.71,87.87 R5506.2 58.55,87.03 v1(58.55,87.02) 58.85,87.02 v2(59.11,86.77)
  BOTTOM w0.102: v1(58.55,87.02) 58.5,87.02 58.1,86.63 58.1,85.47 58.1,85.47 58.1,85.11 58.1,85.11 LCD1.25
BLUETOOTH_EN: length 200.7
  TOP w0.102: AFTP6110.1 172.92,81 v1(173.56,81)
  L3 w0.102: v1(173.56,81) 173.45,80.89 171.97,80.89 169.8,78.72 161.51,78.72 160.52,77.73 158.8,77.73 158.74,77.79 158.38,77.79 155.71,75.12 153.19,75.12 152.75,75.12 151.46,73.83 149.88,73.83 146.65,70.59 146.65,66.01 146.97,65.69 148.07,64.59 148.07,64.58 148.07,56.33 149.54,54.86 149.54,54.86 150.21,54.19 150.56,53.83 150.56,52.47 150.56,52.47 150.56,50.02 150.36,49.82 150.36,46.87 150.03,46.54 149.4,45.91 149.4,44.01 148.73,43.34 148.57,43.17 148.57,42.15 148.57,42.15 148.57,41.37 148.57,41.37 148.57,40.99 148.57,40.99 148.57,39.3 147.48,38.21 147.48,37.83 147.48,37.83 147.48,36.13 147.48,36.13 147.48,35.75 147.48,35.05 146.63,34.2 146.63,34.2 145.96,33.53 145.59,33.17 145.59,30.43 144.97,29.8 144.97,29.06 145.9,28.13 146.98,28.13 148.89,26.22 148.89,25.65 149.29,25.25 149.29,21.7 148.36,20.77 148.36,16.81 140.87,9.32 139.84,9.32 135.74,5.22 131.78,5.22 130.4,6.6 119.76,6.6 114.18,12.17 110.09,12.17 109.34,12.92 108.8,12.92 107.56,11.69 105.93,11.69 105.52,12.09 105.33,12.09 104.63,12.79 104.23,12.79 103.86,12.79 103.65,13.01 100.87,13.01 99,11.14 94.03,11.14 93.99,11.1 92.19,9.3 88.78,9.3 88.53,9.55 84.52,9.55 84.19,9.88 75.64,9.88 74.26,8.5 73.21,8.5 72.87,8.84 66.03,8.84 65.06,7.86 64,7.86 63.55,8.31 61.07,8.31 v1(60.95,8.18)
  BOTTOM w0.102: WLAN1.54 176.64,81.5 176.14,82 174.45,82 173.56,81.1 v1(173.56,81) ; U2401.83 61.58,8.88 60.97,8.27 60.97,8.21 v1(60.95,8.18) 61.21,7.92 R2464.2
BOOST_MODE#: length 2.1
  TOP w0.254: PR4418.1 136.5,11.3 PR4435.2 135.81,9.78 v2(135.81,9.53)
BOOST_MON_1: length 2.3
  BOTTOM w0.356: v2(146.64,31.13) 146.25,30.75 PR4446.1
  BOTTOM w0.508: PC4427.1 146.54,29.79 PR4446.1
BVCCRTC_EXTPAD: length 2.6
  TOP w0.102: C1810.2 66.09,49.32 66.09,49.66 v2(66.55,50.12) 66.55,50.63 v1(66.49,50.69)
  BOTTOM w0.102: v1(66.49,50.69) 66.49,50.21 CPU1.F16
CAMERA_DET#: length 1.7
  BOTTOM w0.102: LCD1.27 59.1,82.69 TP5501.1
CAP_LED: length 7.8
  BOTTOM w0.102: KB1.27 81.7,15.75 81.36,16.09 80.7,16.09 80.05,16.75 80.05,16.96 AFTP6233.1 79.02,17.98 77.55,17.98 EC6506.1 R6503.2
CAP_LED#: length 24.4
  TOP w0.102: v2(55.79,16.73) 56.2,16.32 v1(56.2,16.2) ; v1(74.75,13.08) 74.82,13.16 R6502.1
  L3 w0.102: v1(56.2,16.2) 57.01,16.2 58.06,15.15 59.01,15.15 59.1,15.24 63.39,15.24 64.52,14.1 65.46,14.1 65.78,13.79 65.78,13.24 66.54,12.48 68.63,12.48 70.29,14.13 73.75,14.13 74.75,13.13 v1(74.75,13.08)
  BOTTOM w0.102: U2401.109 55.61,16.11 55.61,16.11 55.95,16.11 55.95,16.11 56.04,16.11 56.13,16.2 v1(56.2,16.2)
CAP_LED_Q: length 3.4
  BOTTOM w0.102: v2(76.07,15.22) 75.77,15.52 R6503.1 74.98,16.13 74.56,16.55 Q6501.C
CAP_LED_R#: length 3.5
  TOP w0.102: v1(76.97,13.32) 76.81,13.16 R6502.2
  BOTTOM w0.102: v1(76.97,13.32) 76.26,13.32 v2(75.78,13.8) 75.26,14.32 Q6501.B
CARD_AV18: length 3.6
  TOP w0.305: C3308.2 14.04,36.66 v2(14.46,37.08) 14.95,37.08 15.35,37.48 v1(15.35,37.77)
  BOTTOM w0.305: U3301.1 v1(15.35,37.77)
CARD_RREF: length 1.7
  TOP w0.305: v1(14.69,37.83) 14.15,38.37 R3304.2 v2(14.08,39.28)
CBN: length 3
  TOP w0.254: v1(137.76,85.7) 137.74,85.72 137.74,85.73 137.61,85.85 C2703.1
  BOTTOM w0.203: U2701.35 138.68,86.28 138.4,85.99 138.05,85.99 v1(137.76,85.7)
  BOTTOM w0.254: v2(138.03,85.21) 137.76,85.48 v1(137.76,85.7)
CBP: length 1.7
  TOP w0.254: v1(136.95,87.06) 137.18,87.28 C2703.2
  BOTTOM w0.203: v1(136.95,87.06) 137.26,87.06 137.46,87.25 U2701.37
CFG0: length 16.3
  L3 w0.127: v1(83.8,51.62) 83.84,51.57 83.84,49.7 87.12,46.43 87.12,45.8 87.95,44.96 87.95,43.28 88.52,42.71 88.52,42.64 89.61,41.56 89.61,40.17 v1(90.53,39.26)
  BOTTOM w0.102: CPU1.AM40 v1(83.8,51.62) ; v1(90.53,39.26) 90.77,39.02 TP1613.1
CFG1: length 19.2
  L4 w0.127: v1(84.26,50.04) 84.26,49.25 87.22,46.28 87.22,45.78 88.04,44.96 88.04,43.11 89.74,41.41 89.78,41.41 89.84,41.35 90.17,41.35 91.06,40.46 91.41,40.46 92.34,39.53 92.34,39.1 92.34,39.1 92.34,37.94 93.27,37 v1(93.36,37)
  BOTTOM w0.102: CPU1.AM41 84.26,50.56 v1(84.26,50.04) ; v1(93.36,37) 93.61,36.76 94.56,36.76 TP1614.1
CFG2: length 1.3
  TOP w0.102: TP1615.1 84.85,49.54 v1(84.77,49.46)
  BOTTOM w0.102: v1(84.77,49.46) 84.9,49.6 CPU1.AM44
CFG3: length 1.2
  TOP w0.102: TP1616.1 85.47,49.27 v1(85.24,49.03)
  BOTTOM w0.102: CPU1.AM45 85.3,49.09 v1(85.24,49.03)
CFG4: length 1.2
  TOP w0.102: v1(85.74,48.53) 85.41,48.2 TP1617.1
  BOTTOM w0.102: v1(85.74,48.53) 85.8,48.59 CPU1.AM47
CFG5: length 1.3
  TOP w0.102: TP1618.1 86.41,47.17 v1(86.75,47.51)
  BOTTOM w0.102: CPU1.AK48 86.64,47.4 v1(86.75,47.51)
CFG6: length 1.3
  TOP w0.102: v1(86.24,48.03) 86.72,48.51 TP1619.1
  BOTTOM w0.102: v1(86.24,48.03) 86.3,48.09 86.82,48.09
CFG7: length 22.1
  L3 w0.127: v1(83.49,49.41) 83.49,48.65 86.66,45.49 86.66,44.43 86.9,44.18 86.9,43.68 88.07,42.52 88.07,40.73 91.29,37.51 92.1,37.51 94.16,35.45 96.06,35.45 v1(96.2,35.31)
  BOTTOM w0.102: v1(83.49,49.41) 83.61,49.53 CPU1.AK41 ; v1(96.2,35.31) 96.39,35.12 TP1620.1
CFG8: length 23.2
  L3 w0.127: v1(97.29,35.02) 97.29,35.07 96.39,35.97 95.17,35.97 93.69,37.45 93.01,37.45 92.54,37.93 91.23,37.93 88.32,40.84 88.32,42.49 88.3,42.51 88.3,42.61 87.13,43.77 87.13,44.27 86.89,44.52 86.89,45.74 84.12,48.52 v1(84.12,48.8)
  BOTTOM w0.102: TP1621.1 97.29,35.91 v1(97.29,35.02) ; CPU1.AK42 v1(84.12,48.8)
CHG_AGND: length 2.5
  TOP w0.508: v3(126.49,15.83) v2(127.19,16.53) PC4410.2
  vias: v1(131.64,12.13) v1(132.27,12.76) v1(132.27,12.13) v1(132.27,11.49) v1(132.91,12.13)
CHG_AMBER_LED#: length 81.5
  TOP w0.254: v1(6.94,17.08) 7.41,16.61 R6406.2 ; v1(60.6,13.84) v2(61.07,13.38)
  L3 w0.254: v1(60.6,13.84) 60.26,13.5 57.04,13.5 56.65,13.88 54.56,13.88 53.89,13.21 53.47,13.21 53.04,13.64 50.96,13.64 49.82,12.5 48.32,12.5 47.93,12.11 46.37,12.11 45.62,12.86 45.01,12.86 44.78,12.63 42.06,12.63 41.91,12.48 40.02,12.48 38.04,10.5 30.57,10.5 v1(29.19,9.11)
  BOTTOM w0.203: 62.17,23.95 62.38,24.16 U2401.16
  BOTTOM w0.254: v1(60.6,13.84) 60.45,13.99 60.45,15.64 60.45,15.65 60.45,17.12 59.9,17.67 59.9,18.53 60.16,18.78 60.16,20.49 60.44,20.78 60.44,21.38 60.76,21.71 61.29,21.71 62.2,22.62 62.2,23.11 62.13,23.17 62.13,23.91 62.17,23.95 ; v1(6.94,17.08) 5.67,17.08 4.9,16.32 4.9,12.93 6.45,11.38 12.83,11.38 15.84,8.36 28.44,8.36 v1(29.19,9.11)
CHG_AMBER_LED_R#: length 3
  TOP w0.152: v1(6.89,14.8) 7.41,15.32 R6406.1 v2(8.33,15.52)
  BOTTOM w0.152: Q6404.B 7.18,15.09 v1(6.89,14.8)
COMBO-GPI: length 3.6
  BOTTOM w0.102: TP2702.1 135.65,94.12 135.99,93.78 136.17,93.78 137.46,92.49 U2701.48
COREPWROK: length 134.6
  TOP w0.102: 65.13,49.62 65.46,49.94 65.46,50.24 66.41,51.2 v1(67,51.2)
  L3 w0.127: v1(140.85,51.61) 141.29,51.17 141.29,50.64 140.58,49.93 140.58,46.11 138.65,44.18 138.65,43.3 136.36,41.02 136.36,38.15 134.66,36.46 134.66,35.05 133.34,33.72 130.78,33.72 129.31,32.25 116.14,32.25 115.36,33.03 96.58,33.03 95.7,32.16 94.84,32.16 94.51,32.49 93.68,32.49 92.86,31.67 86.39,31.67 85.1,32.96 v1(84.05,32.96) ; v1(67,51.2) 66.08,51.2 64.93,50.05 64.41,50.05 64.02,50.44 62.74,50.44 62.12,51.06 59.75,51.06 v1(59.42,50.73)
  L4 w0.127: v1(84.05,32.96) 83.9,33.11 83.9,34.09 83.46,34.53 82.63,34.53 80.73,32.63 70.59,32.63 66.7,36.52 62.87,36.52 59.32,40.07 59.32,44.27 57.84,45.76 57.84,49.38 57.4,49.81 57.4,50.41 58.02,51.02 59.13,51.02 v1(59.42,50.73)
  BOTTOM w0.102: 67.04,50.66 67,50.7 v1(67,51.2) ; Q4016.2 136.81,50.53 137.05,50.29 R4008.2 R4029.2 139.97,50.29 140.41,50.72 140.41,51.17 v1(140.85,51.61) 141.13,51.61 v2(141.48,51.96)
CPU_VSS2: length 5.3
  BOTTOM w0.102: CPU1.A6 61.14,52.22 59.69,52.22 59.26,52.66 56.66,52.66 TP902.1
CPU_VSS16: length 3
  TOP w0.102: TP901.1 96.24,51.46 v1(96.23,51.45)
  BOTTOM w0.102: v1(96.23,51.45) 95.62,52.06 CPU1.BH53
CPVEE: length 6
  TOP w0.305: v1(137.43,84.93) 137.94,84.93 138.4,85.4 138.4,86.36 C2704.2
  BOTTOM w0.203: U2701.34 139.08,86.21 138.46,85.58 138.46,85.04 138.2,84.79 137.58,84.79 v1(137.43,84.93)
  BOTTOM w0.305: v1(137.43,84.93) 137.41,84.93 137.03,84.56 v2(136.96,84.56)
CPVREF: length 5.6
  TOP w0.254: v1(144.67,88.99) 144.07,88.99 143.66,89.41 v2(143.66,90.52) 143.66,92.01 R2711.1
  BOTTOM w0.203: 144.2,89.18 U2701.20
  BOTTOM w0.254: v1(144.67,88.99) 144.49,89.18 144.2,89.18
D_BAT_AMBER: length 7.2
  TOP w0.152: v1(65.26,13.67) TP2408.1
  BOTTOM w0.152: U2401.62 69.44,12.11 69.06,12.49 69.06,13.51 68.49,14.08 67.17,14.08 66.98,13.89 65.47,13.89 v1(65.26,13.67)
D_BAT_WHITE: length 4
  TOP w0.152: TP2409.1 61.34,7.41 v1(61.87,6.88)
  BOTTOM w0.152: U2401.81 62.38,8.46 61.87,7.95 v1(61.87,6.88)
DBC_EN: length 45.9
  TOP w0.102: R806.2 47.07,52.14 v1(47.48,51.72) v2(47.48,50.99) ; R5501.2 58.3,83.11 58.28,83.09 v1(58.28,83.07)
  L3 w0.127: v1(58.28,83.07) 59.45,81.9 59.45,80.65 60.31,79.79 60.31,77.54 60.81,77.05 60.81,74.35 60.65,74.19 60.65,69.06 60.65,67.97 61.86,66.76 61.86,66.33 61.86,64.56 60.5,63.2 60.5,59.36 60.36,59.21 60.36,58.1 59.66,57.4 v1(59.38,57.4)
  BOTTOM w0.102: v1(59.38,57.4) 58.08,57.4 57.72,57.05 52.93,57.05 52.76,56.88 51.67,56.88 49.58,54.79 49.58,54.26 Q801.S 48.95,54.18 48.03,53.26 48.03,52.27 v1(47.48,51.72)
DBC_EN_C: length 14.3
  BOTTOM w0.102: Q801.D 51.41,53.11 51.81,52.71 v2(53.03,52.71) 53.03,54.41 53.76,55.15 53.94,55.15 54.32,55.53 RN801.2 56.47,55.53 57.19,54.81 57.89,54.81 58.13,55.05 58.13,55.45 58.49,55.81 61.41,55.81 61.68,55.54 CPU1.F2
DBC_EN_R: length 3.9
  TOP w0.102: v1(56.94,82.51) 57.06,82.63 57.06,83.29 57.41,83.64 R5501.1
  BOTTOM w0.102: v2(56.94,81.87) v1(56.94,82.51) 56.6,82.85 LCD1.22
DC_IN_D: length 14.5
  BOTTOM w0.254: PQ4402.3 149.91,24.59 149.47,24.14 148.47,24.14 148.46,24.13 147.55,24.13 147.27,23.85 147.27,21.73 146.71,21.17 145.79,21.17 145.35,20.74 145.35,20.44 144.86,19.95 144.86,18.35 v2(146.25,16.96) PR4404.2
DCBATOUT_R: length 19.4
  BOTTOM w0.254: PR4448.1 139.6,28.93 v2(138.78,28.93) 137.05,28.93 135.71,27.59 133.55,27.59 132.45,26.49 123.31,26.49 122.92,26.1 122.92,25.69 123.46,25.14 PG4404.1
DDI0_PLLOBS_N: length 1.4
  TOP w0.102: R802.1 74.73,42.68 v1(74.79,42.62)
  BOTTOM w0.102: v1(74.79,42.62) 74.79,42.9 CPU1.G38
DDI0_PLLOBS_P: length 1.4
  TOP w0.102: v1(73.56,42.69) 73.84,42.97 R802.2
  BOTTOM w0.102: CPU1.F38 73.64,42.61 v1(73.56,42.69)
DDI1_PLLOBS_N: length 2.7
  TOP w0.102: R801.1 79.46,38.55 79.06,38.15 v2(78.49,38.15) 78.42,38.15 v1(78.05,38.52)
  BOTTOM w0.102: v1(78.05,38.52) 77.9,38.68 CPU1.F49
DDI1_PLLOBS_P: length 3.4
  TOP w0.102: R801.2 79.49,39.44 79.41,39.35 78.87,39.35 78.64,39.58 77.97,39.58 v2(77.97,39.57) 77.42,40.12 v1(77.42,40.13)
  BOTTOM w0.102: CPU1.F47 77.29,40.01 v1(77.42,40.13)
DDR3_DRAM_PWROK: length 126.1
  TOP w0.102: v1(82.69,57.4) 82.49,57.59 81.61,57.59 ; v1(143.85,56.82) 143.52,56.49 143.52,52.37 143.25,52.1 v2(143.23,52.1) 143.23,52.08 142.83,51.68 142.83,50.03 142.03,49.23 v1(142.03,47.08)
  L4 w0.127: v1(82.69,57.4) 82.69,58.25 82.91,58.47 82.91,63.63 82.46,64.07 82.46,65.29 83.19,66.02 85.12,66.02 95.07,75.97 95.89,75.97 98.91,79 98.91,83.11 100.1,84.3 101.54,84.3 103.51,86.27 127.71,86.27 128.32,85.66 129.08,85.66 131.56,83.18 132.83,83.18 135.22,80.79 135.84,80.79 137.42,79.21 138.15,79.21 139.16,78.2 v1(141.35,78.2)
  BOTTOM w0.102: v1(143.85,56.82) 143.85,58.05 144.89,59.08 145.26,59.45 145.26,62.72 142.95,65.03 142.95,74.15 141.42,75.68 141.42,78.13 v1(141.35,78.2) ; v1(142.03,47.08) 140.95,48.16 R4019.1 135.79,48.23 R4031.2 137.38,49.01 R4015.1 ; v1(82.69,57.4) 82.67,57.42 CPU1.AV28
DDR3_DRAM_PWROK_D: length 4.6
  BOTTOM w0.102: Q4017.D 133.6,45.91 133.37,46.13 v2(133.37,46.6) 133.37,47.09 134.44,48.16 R4019.2
DDR3_VCCA_PWRGD: length 123.2
  TOP w0.102: v1(82,65.5) 82,66.39 EC504.1 ; v1(141.86,77.1) 142.03,76.93 142.03,73.25 141.08,72.3 141.08,72.17 138.75,69.84 138.75,65.18 142.78,61.14 142.78,58.62 v2(142.41,58.24) 142.09,57.93 142.09,53.17 141.28,52.36 141.28,51.26 v1(140.84,50.82)
  L3 w0.127: v1(81.22,58.71) 81.22,60.08 80.49,60.81 80.49,61.54 82,63.04 v1(82,65.5) 82.34,65.5 85.18,68.34 85.18,73.82 86.12,74.77 90.73,74.77 97.17,81.21 97.18,81.21 100.44,84.47 100.76,84.47 102.46,86.17 115.36,86.17 115.59,86.4 115.63,86.4 115.73,86.5 121.11,86.5 123.13,86.5 123.44,86.19 123.52,86.19 125.14,84.57 126.41,84.57 127.1,83.88 131.79,83.88 133,82.67 133.36,82.67 134.84,81.19 134.84,80.46 138.25,77.05 140.48,77.05 140.74,77.31 141.65,77.31 v1(141.86,77.1)
  BOTTOM w0.102: Q4016.3 136.16,50.25 R4024.2 136.83,49.58 139.92,49.58 140.84,50.5 v1(140.84,50.82) ; v1(81.22,58.71) 81.22,58.22 CPU1.AV26
DDR3_VCCA_PWRGD_G: length 4.2
  BOTTOM w0.102: Q4016.5 136.81,52.53 136.94,52.39 137.27,52.39 137.46,52.58 Q4016.6 137.46,53.99 R4020.2 136.98,54.47 v2(136.2,54.47)
DDR_VREF_S3: length 1.7
  TOP w0.356: v2(100.39,19.94) PC5116.1
  TOP w0.508: v1(99.37,20.64) 99.37,20.64 PC5116.1
DMIC_CLK: length 99.8
  TOP w0.102: v2(55.4,80.2) 55.69,80.48 v1(55.69,80.87) 55.69,81.4 EC5506.1 55.67,81.71 RN5502.3
  L4 w0.127: v1(137.01,97.32) 135.52,98.81 133.3,98.81 132.32,99.8 132.32,100.46 131.48,101.3 121.59,101.3 121.22,101.67 96.43,101.67 96.43,101.67 95.64,101.67 94.35,100.38 94.16,100.19 77.93,100.19 68.93,91.19 68.64,90.9 62.03,90.9 60.63,89.51 60.63,87.98 59.09,86.44 59.09,85.22 57.97,84.11 57.18,84.11 55.89,82.82 55.89,81.17 55.83,81.11 55.83,81.02 v1(55.69,80.87)
  BOTTOM w0.102: C2723.2 138.44,96.28 R2716.1 137.62,96.72 v1(137.01,97.32)
DMIC_CLK_C: length 4.9
  TOP w0.102: RN5502.2 55.67,84.46 55.05,85.07 v1(55.05,85.82) 54.97,85.82 v2(54.2,86.59)
  BOTTOM w0.102: v1(55.05,85.82) 55.05,85.2 54.6,84.74 LCD1.18
DMIC_CLK_R: length 3.2
  BOTTOM w0.102: R2716.2 137.62,95.23 v2(138.49,94.35) 138.49,93.82 139.08,93.23 U2701.3
DMIC_DATA: length 97.1
  TOP w0.102: v2(56.67,80.28) 56.34,80.61 v1(56.34,80.9) 56.64,81.2 EC5505.1 56.32,81.86 RN5502.4
  L4 w0.127: v1(136.23,97.31) 135.24,98.3 133.08,98.3 131.81,99.58 131.81,100.17 131.2,100.79 121.37,100.79 121,101.16 96.22,101.16 96.22,101.16 95.86,101.16 94.86,100.17 94.86,100.16 94.38,99.68 78.14,99.68 69.44,90.98 68.85,90.39 62.24,90.39 61.14,89.3 61.14,87.77 59.6,86.23 59.6,85.01 58.19,83.6 57.39,83.6 56.4,82.61 56.4,80.96 v1(56.34,80.9)
  BOTTOM w0.102: v1(136.23,97.31) 136.78,96.76 R2714.1
DMIC_DATA_C: length 4.9
  TOP w0.102: v2(56.67,85.6) 56.46,85.81 v1(55.7,85.81) 55.54,85.64 55.54,85.28 56.32,84.5 RN5502.1
  BOTTOM w0.102: v1(55.7,85.81) 55.55,85.65 55.55,85.01 55.1,84.56 LCD1.19
DMIC_DATA_R: length 3.5
  BOTTOM w0.102: R2714.2 136.78,94.85 v2(137.21,94.43) 138.16,93.47 138.43,93.47 138.68,93.21 U2701.2
DP_HPD0_C: length 4
  TOP w0.102: v1(57.6,82.92) 58.11,82.41 R5507.2 R5518.1 59.21,82.48 v2(59.21,83.32)
  BOTTOM w0.102: v1(57.6,82.92) LCD1.24
DP_HPD0_G: length 13.7
  TOP w0.102: v1(48.99,79.65) 49.28,79.65 v2(49.83,79.1) 50.19,79.45 55.8,79.45 56.09,79.75 56.8,79.75 56.81,79.74 57.74,79.74 59.15,81.14 R5518.2
  BOTTOM w0.102: v1(48.99,79.65) 47.56,78.22 Q5506.G
DRAM_RCOMP_1: length 6.6
  TOP w0.254: v1(82.23,59.62) 83.17,59.62 R508.1 85.57,62.98 v2(85.57,63.32)
  BOTTOM w0.254: v1(82.23,59.62) 82.35,59.5 CPU1.BA26
DRAM_SEL0: length 7.3
  TOP w0.102: R808.2 61.89,51.34 R809.1 61.98,52.07 62.46,52.55 62.95,52.55 63.92,53.53 64.35,53.53 64.46,53.42 v2(64.8,53.42) 65.12,53.42 v1(65.41,53.7)
  BOTTOM w0.102: CPU1.M12 66.58,53.99 66.06,53.47 65.65,53.47 v1(65.41,53.7)
DRAM_SEL1: length 10.6
  TOP w0.102: R810.2 59.91,48.83 R812.1 60.46,50.01 61.31,50.86 61.31,52.2 61.61,52.5 62.12,52.5 62.37,52.76 62.86,52.76 63.37,53.27 v2(63.37,53.55) 63.37,53.55 63.96,54.14 v1(64.91,54.14)
  BOTTOM w0.102: CPU1.M10 66.15,54.49 66.02,54.62 65.32,54.62 64.91,54.21 v1(64.91,54.14)
DRAM_SEL2: length 14.8
  TOP w0.102: v1(64.39,54.74) 63.67,54.74 62.97,54.03 62.97,53.43 62.63,53.09 v2(62.13,53.09) 61.91,53.09 61.1,52.28 61.1,50.94 59.74,49.58 57.66,49.58 55.8,51.44 R819.1 55.71,52.12 R818.2
  BOTTOM w0.102: CPU1.K7 64.45,54.79 v1(64.39,54.74)
E51_RX1: length 3.6
  TOP w0.102: v1(174.9,83.81) 175.45,83.26 TP6102.1
  BOTTOM w0.102: WLAN1.46 175.21,83.5 v1(174.9,83.81)
E51_RX2: length 3.4
  TOP w0.102: TP6101.1 175.05,81.67 v1(175.05,81.19)
  BOTTOM w0.102: WLAN1.58 176.55,80.5 176.13,80.92 175.32,80.92 v1(175.05,81.19)
E51_TX1: length 4.9
  TOP w0.102: R6107.2 v1(174.33,84.73) 173.93,84.73 v2(173.75,84.54)
  BOTTOM w0.102: v1(174.33,84.73) 175.97,84.73 176.7,84 WLAN1.44
E51_TX2: length 4.7
  TOP w0.102: R6108.2 v1(174.17,85.54) 173.93,85.54 v2(173.67,85.8)
  BOTTOM w0.102: WLAN1.38 174.22,85.5 v1(174.17,85.54)
E51_TXD: length 206
  TOP w0.102: v1(151.47,18.08) 151.68,18.29 151.68,39.43 150.83,40.29 150.83,42.71 151.54,43.43 151.54,53.88 v1(151.31,54.1) ; v1(101.54,9.25) v2(100.64,9.25) 95.95,9.25 91.86,13.34 91.23,13.34 v1(90.78,13.79) ; R6108.1 175.92,84.88 R6107.1 176.08,84.32 v1(175.73,83.97)
  L3 w0.102: v1(175.73,83.97) 176.18,83.52 176.18,80.75 175.51,80.08 174.94,80.08 171.54,76.68 159.63,76.68 157.21,74.26 157.08,74.13 153.16,74.13 152.13,73.09 152.13,72.71 151.16,71.75 149.65,71.75 v1(149.35,72.06) ; v1(151.47,18.08) 151.33,17.94 151.33,15.79 v1(145.13,9.58) ; v1(58.12,16.15) 58.97,16.15 59.42,15.69 63.62,15.69 64.19,15.13 67.73,15.13 68.82,16.22 71.03,16.22 71.43,16.61 74.6,16.61 75.78,15.44 87.44,15.44 88.4,15.44 89.8,14.04 90.53,14.04 v1(90.78,13.79)
  BOTTOM w0.102: v1(58.12,16.15) 58.13,16.15 57.07,17.21 55.87,17.21 55.56,16.91 U2401.111 ; v1(101.54,9.25) 101.54,8.7 101.32,8.48 101.32,7.68 103.03,5.98 136.11,5.98 139.85,9.72 144.99,9.72 v1(145.13,9.58) ; v1(151.31,54.1) 151.15,54.27 151.15,60.73 149.59,62.28 149.18,62.28 145.76,65.7 145.76,69.84 147.98,72.06 v1(149.35,72.06)
EAPD#: length 5.4
  BOTTOM w0.102: v2(134.26,94.81) 134.71,94.37 R2708.2 135.53,93.88 135.88,93.53 136.07,93.53 136.82,92.79 136.82,91.79 137.02,91.58 U2701.47
EC_AGND: length 7.3
  TOP w0.356: v2(55.61,11.9) C2438.1
  TOP w0.508: C2416.2 54.14,11.95 54.19,11.9 C2438.1 54.64,12.75 C2436.2 54.34,13.4 54.02,13.72 v1(53.68,13.72) 52.54,13.72 52.38,13.88 R2415.1
  BOTTOM w0.203: v1(53.68,13.72) 53.69,13.71 U2401.103
EC_AVCC: length 4.9
  TOP w0.508: C2436.1 52.93,13.05 v1(52.75,12.87) 52.75,12.33 C2416.1
  BOTTOM w0.203: v2(53.16,13.25) 53.18,13.24 53.88,13.24 53.95,13.31 U2401.102
  BOTTOM w0.508: v2(53.16,13.25) 52.79,12.87 v1(52.75,12.87) 52.62,13.01 R2409.1
EC_BRIGHTNESS: length 150.7
  TOP w0.102: v1(50.34,77.4) v2(50.34,77.98)
  L3 w0.127: v1(56.41,15.6) 55.38,15.6 53.98,17 53.12,17 52.23,16.1 51.12,16.1 50.34,15.32 49.63,15.32 47.53,13.22 46.67,13.22 46.03,13.86 41.84,13.86 41.55,14.16 40.26,14.16 39.09,12.99 34.49,12.99 32.79,11.29 24.41,11.29 20.87,14.83 20.87,26.14 19.42,27.59 19.42,38.07 20.48,39.13 v1(20.48,40.97)
  L4 w0.127: v1(20.48,40.97) 20.48,41.11 19.72,41.87 19.72,51.19 18.29,52.63 18.29,58.75 18.29,58.75 18.29,59.35 17.58,60.07 17.58,62.42 18.09,62.93 18.09,62.95 18.35,63.21 18.37,63.21 18.39,63.24 20.49,63.24 20.73,63.48 20.76,63.48 21.18,63.89 22.12,63.89 22.52,64.3 22.52,65.7 20.78,67.45 20.78,74.16 21.84,75.22 21.84,81.14 23.52,82.82 30.13,82.82 31.6,84.29 41.75,84.29 48.25,77.79 49.95,77.79 v1(50.34,77.4)
  BOTTOM w0.102: v1(50.34,77.4) 50.58,77.64 D5502.2 ; U2401.106 56.03,14.91 56.41,15.28 v1(56.41,15.6)
EC_VCC1V8: length 2.1
  BOTTOM w0.203: 59.26,11.03 59.58,10.7 U2401.88
  BOTTOM w0.508: 59.26,11.03 58.85,11.44 v1(58.76,11.44)
  vias: v2(58.81,10.85)
EC_VTT: length 7.2
  BOTTOM w0.203: C2447.1 59.88,27.18 60.78,26.27 U2401.12
  BOTTOM w0.356: C2447.1 59.95,27.28 60.48,27.81 60.48,28.59 60.15,28.92 60.15,29.11 60.09,29.18 v2(60.15,29.24)
  BOTTOM w0.508: C2447.1 59.88,27.28 R2443.2 58.65,27.28 58.02,27.91 R2430.2
ECRST#: length 15.6
  TOP w0.102: RN2402.4 58.39,6.53 v1(58.59,6.73) 58.67,6.81 58.67,7.15 58.79,7.27 v2(58.79,7.28)
  BOTTOM w0.102: R2404.2 C2444.1 51.49,5.31 51.87,4.93 Q2401.E 55.33,4.93 55.68,5.28 56.47,5.28 56.89,5.7 57.97,5.7 58.24,5.97 58.24,6.26 58.59,6.61 v1(58.59,6.73) 58.83,6.73 59.22,7.12 59.22,7.49 59.62,7.89 59.63,7.89 59.88,8.15 59.88,8.42 60.31,8.85 60.55,8.85 60.78,9.08 U2401.85
ECSMI#_KBC: length 5
  TOP w0.102: R2461.1 59.06,20.2 v1(58.62,19.76)
  BOTTOM w0.102: U2401.119 55.66,20.11 56.16,19.61 58.47,19.61 v1(58.62,19.76)
EDM_SOC: length 1.7
  TOP w0.102: v1(67.04,53.43) 66.58,53.43 TP1803.1
  BOTTOM w0.102: v1(67.04,53.43) 67.1,53.48 CPU1.M13
EDP_AUX_CON_N: length 3.6
  TOP w0.089: v2(52.55,86.23) 52.55,85.87 v1(52.38,85.69) 52.1,85.41 52.1,84.88 C5505.1
  BOTTOM w0.089: LCD1.13 52.1,84.79 52.03,84.86 52.03,85.35 v1(52.38,85.69)
EDP_AUX_CON_P: length 3
  TOP w0.089: v1(51.62,85.69) 51.9,85.41 51.9,84.86 C5501.1
  BOTTOM w0.089: LCD1.12 51.6,84.7 51.83,84.93 51.83,85.48 v1(51.62,85.69)
EDP_AUX_CPU_N: length 139
  TOP w0.089: C5505.2 52.11,83.36 52.11,82.15 v1(52.5,81.75) 52.5,81.61 v2(52.15,81.25)
  L3 w0.102: v1(52.5,81.75) 52.29,81.96 52.29,82.28 52.01,82.57 51.17,82.57 50.96,82.36 50.67,82.36 50.27,81.96 50.27,81.43 49.94,81.1 48.66,81.1 47.63,82.12 47.63,83.41 47.02,84.03 44.2,84.03 43.69,83.52 42.9,83.52 41.82,84.6 39.52,84.6 38.87,83.95 31.49,83.95 30.07,82.52 23.97,82.52 21.73,80.28 21.73,77.8 21.25,77.32 21.25,74.88 20.6,74.23 20.6,72.78 20,72.18 20,69.28 24.75,64.53 24.75,54.59 26.01,53.34 26.01,48.52 25.94,48.45 25.94,48.44 25.68,48.19 25.68,46.22 26.43,45.47 26.43,42.74 29.61,39.56 33.81,39.56 35.24,38.13 37.92,38.13 38.54,38.75 52.28,38.75 52.84,38.19 54.14,38.19 54.83,37.5 56.59,37.5 57.4,36.69 61.22,36.69 61.86,37.32 64.23,37.32 64.74,37.83 69.39,37.83 69.73,37.49 69.97,37.49 70.05,37.42 70.71,37.42 71.08,37.05 71.53,37.05 72.59,37.05 75.23,39.69 75.23,40.71 77,42.48 77.17,42.48 77.19,42.5 v1(77.46,42.5)
  BOTTOM w0.089: v1(77.46,42.5) 77.2,42.5 CPU1.K42
EDP_AUX_CPU_P: length 138.4
  TOP w0.089: 51.9,82.4 51.9,81.95 51.69,81.74 v1(51.6,81.74) ; 51.9,82.4 v2(51.74,82.4) ; 51.9,82.4 51.9,83.37 C5501.2
  L3 w0.102: v1(51.6,81.74) 51.68,81.67 51.9,81.67 52.08,81.85 52.08,82.19 51.92,82.35 51.26,82.35 51.05,82.14 50.76,82.14 50.48,81.87 50.48,81.34 50.03,80.88 48.57,80.88 47.41,82.03 47.41,83.32 46.93,83.81 44.29,83.81 43.78,83.3 42.81,83.3 41.73,84.38 39.61,84.38 38.96,83.73 31.58,83.73 30.16,82.3 24.06,82.3 21.95,80.19 21.95,77.71 21.46,77.23 21.46,74.79 20.82,74.14 20.82,72.69 20.22,72.09 20.22,69.37 24.97,64.62 24.97,54.68 26.22,53.43 26.22,48.43 26.15,48.36 26.15,48.35 25.89,48.1 25.89,46.31 26.64,45.56 26.64,42.83 29.7,39.77 33.9,39.77 35.33,38.34 37.83,38.34 38.45,38.97 52.37,38.97 52.93,38.4 54.23,38.4 54.92,37.71 56.67,37.71 57.49,36.9 61.13,36.9 61.77,37.54 64.14,37.54 64.65,38.05 69.48,38.05 69.82,37.71 70.06,37.71 70.14,37.63 70.8,37.63 71.17,37.26 71.44,37.26 72.5,37.26 75.02,39.78 75.02,40.8 76.91,42.69 77.08,42.69 77.37,42.99 v1(77.37,43.15)
  BOTTOM w0.089: CPU1.M42 77.92,43.03 77.79,42.9 77.49,42.9 77.37,43.02 v1(77.37,43.15)
EDP_HPD_CPU: length 168.7
  TOP w0.102: v2(46.17,81.61) 46.19,81.63 46.77,81.63 v1(46.8,81.59) 46.94,81.73 R5517.2
  L4 w0.127: v1(46.8,81.59) 46.03,81.59 44.57,83.06 44.57,84.77 43.41,85.93 24.39,85.93 24.36,85.9 24.32,85.9 18.31,79.88 18.31,74.21 17.18,73.09 17.18,72.24 17.18,72.24 17.18,67.12 17.18,67.12 17.18,67.1 15.04,64.96 15.04,63.4 15.84,62.6 15.84,59.37 16.57,58.64 16.57,58.13 16.57,48.55 17.34,47.78 17.34,43.34 17.51,43.16 17.51,41.72 16.4,40.62 16.4,38.87 16.58,38.7 16.58,35.87 16.5,35.79 16.5,35.02 17.16,34.36 21.15,34.36 21.83,35.04 21.83,35.95 22.12,36.23 28.71,36.23 29.78,35.16 32.06,35.16 32.97,36.08 33.45,36.08 33.84,35.69 37.26,35.69 38.78,34.18 46.91,34.18 47.87,33.22 47.87,30.27 48.14,30 49.11,30 49.38,29.73 51.71,29.73 52.04,29.4 52.05,29.4 52.27,29.18 53.43,29.18 54.43,30.18 57.66,30.18 58.5,29.34 59.75,29.34 60.95,30.54 69.8,30.54 71.64,32.37 81.11,32.37 82.35,33.62 v1(82.35,33.62)
  BOTTOM w0.102: CPU1.R51 82.31,40.89 82.31,40.47 82.52,40.26 82.74,40.26 83.48,39.53 83.48,35.54 82.35,34.41 v1(82.35,33.62) ; v1(46.8,81.59) 46.56,81.35 Q5506.D
EDP_TX_CON_N0: length 3.6
  TOP w0.089: v2(49.76,86.23) 49.76,85.89 v1(49.96,85.68) 50.25,85.4 50.25,84.86 C5507.1
  BOTTOM w0.089: v1(49.96,85.68) 50.25,85.4 50.25,84.94 50.1,84.79 LCD1.9
EDP_TX_CON_N1: length 3.2
  TOP w0.089: C5513.1 48.64,84.92 48.64,85.41 v1(48.36,85.69)
  BOTTOM w0.089: LCD1.6 48.6,84.71 48.73,84.84 48.73,85.51 48.55,85.69 v1(48.36,85.69)
EDP_TX_CON_P0: length 3.7
  TOP w0.089: v2(51.13,86.18) 51.13,86.09 v1(50.73,85.68) 50.45,85.41 50.45,84.88 C5506.1
  BOTTOM w0.089: LCD1.10 50.6,84.79 50.45,84.94 50.45,85.41 v1(50.73,85.68)
EDP_TX_CON_P1: length 3
  TOP w0.089: C5510.1 48.84,84.83 48.84,85.42 v1(49.12,85.69)
  BOTTOM w0.089: v1(49.12,85.69) 48.93,85.51 48.93,84.86 49.1,84.7 LCD1.7
EDP_TX_CPU_N0: length 153.8
  TOP w0.089: v1(49.92,82.85) 50.25,83.19 50.25,83.37 C5507.2
  L3 w0.102: v1(79.87,35.03) 80.02,35.03 80.16,34.89 80.16,34.7 80.08,34.62 79.6,34.62 79.46,34.76 79.46,35.44 80.67,36.65 80.67,37.34 80.29,37.72 80.29,39.16 79.81,39.64 79.81,40.06 79.41,40.45 78.37,40.45 77.46,39.54 76.47,39.54 73.84,36.91 73.84,36.63 71.86,34.65 69.72,34.65 67.68,36.69 65.21,36.69 64.57,36.04 62.28,36.04 61.77,35.54 55.68,35.54 54.88,36.34 54.35,36.34 54.1,36.58 51.99,36.58 50.97,37.61 39.01,37.61 38.39,36.98 34.77,36.98 33.78,37.97 29.58,37.97 25.2,42.35 25.2,44.95 24.52,45.62 24.52,48.66 24.86,49 24.86,52.75 23.88,53.74 23.76,53.74 22.95,54.55 22.95,61.25 23.15,61.45 23.15,64.51 18.81,68.85 18.81,74.91 20.07,76.17 20.07,77.76 20.59,78.28 20.59,81.01 24.67,85.09 38.3,85.09 39.65,86.44 46.69,86.44 49.45,83.68 50.03,83.68 50.22,83.5 50.22,83.15 v1(49.92,82.85)
  BOTTOM w0.089: CPU1.H51 79.53,38.88 79.6,38.94 79.73,38.94 79.93,38.75 79.93,38.43 80.9,37.45 80.9,36.62 80.36,36.08 80.36,34.81 80.18,34.63 79.96,34.63 79.87,34.73 v1(79.87,35.03) ; v2(50.04,82.27) 50.04,82.73 v1(49.92,82.85)
EDP_TX_CPU_N1: length 146.4
  TOP w0.089: C5513.2 48.65,83.31 48.65,82.88 48.49,82.72 48.39,82.72 48.31,82.8 v1(48.31,82.88)
  L3 w0.102: v1(48.31,82.88) 48.46,82.88 48.8,83.22 48.8,83.34 47.49,84.65 44.47,84.65 43.82,85.31 39.56,85.31 38.64,84.39 31.31,84.39 29.88,82.96 23.73,82.96 21.29,80.52 21.29,77.99 20.8,77.5 20.8,75.07 20.15,74.41 20.15,72.95 19.56,72.36 19.56,69.1 24.31,64.35 24.31,54.4 25.56,53.15 25.56,48.71 25.22,48.37 25.22,45.98 25.91,45.29 25.91,42.63 29.87,38.67 34.07,38.67 35.06,37.68 38.1,37.68 38.72,38.3 52.02,38.3 52.6,37.72 53.95,37.72 54.64,37.03 55.17,37.03 55.96,36.24 61.44,36.24 61.98,36.78 64.32,36.78 64.92,37.39 67.97,37.39 68.93,36.43 72.64,36.43 75.74,39.52 75.74,40.03 76.73,41.02 80.26,41.02 81.04,40.25 81.04,37.66 81.32,37.38 81.32,35.75 v1(81.74,35.33)
  BOTTOM w0.089: 81.96,36.61 82.14,36.79 82.14,38.19 81.44,38.89 80.92,38.89 80.68,39.13 CPU1.K52 ; 81.96,36.61 81.31,35.95 81.31,35.73 81.7,35.33 v1(81.74,35.33) ; 81.96,36.61 v2(82.09,36.48)
EDP_TX_CPU_P0: length 153.9
  TOP w0.089: C5506.2 50.46,83.36 50.46,83.17 v1(50.78,82.84) 50.47,82.53 v2(50.47,82.35)
  L3 w0.102: v1(50.78,82.84) 50.44,83.19 50.44,83.59 50.12,83.9 49.54,83.9 46.78,86.65 39.56,86.65 38.21,85.3 24.58,85.3 20.37,81.1 20.37,78.37 19.85,77.85 19.85,76.26 18.59,75 18.59,68.76 22.93,64.42 22.93,61.54 22.73,61.34 22.73,54.46 23.67,53.52 23.79,53.52 24.65,52.66 24.65,49.09 24.31,48.75 24.31,45.53 24.98,44.86 24.98,42.26 29.49,37.76 33.69,37.76 34.68,36.77 38.48,36.77 39.1,37.39 50.88,37.39 51.9,36.36 54.01,36.36 54.26,36.12 54.79,36.12 55.59,35.32 61.86,35.32 62.37,35.83 64.66,35.83 65.3,36.47 67.59,36.47 69.63,34.43 71.95,34.43 74.05,36.54 74.05,36.82 76.56,39.32 77.55,39.32 78.46,40.24 79.32,40.24 79.59,39.97 79.59,39.55 80.07,39.07 80.07,37.63 80.42,37.29 80.45,37.25 80.45,36.74 79.24,35.53 79.24,34.67 79.51,34.41 79.65,34.41 v1(79.86,34.19)
  BOTTOM w0.089: CPU1.J51 80.04,38.92 80.13,38.83 80.13,38.51 81.11,37.54 81.11,36.54 80.56,36 80.56,34.72 80.26,34.42 80.09,34.42 v1(79.86,34.19)
EDP_TX_CPU_P1: length 146.5
  TOP w0.089: C5510.2 48.85,83.41 48.85,83.1 v1(49.07,82.88)
  L3 w0.102: v1(49.07,82.88) 49.02,82.93 49.02,83.43 47.58,84.87 44.56,84.87 43.91,85.52 39.47,85.52 38.55,84.61 31.22,84.61 29.79,83.18 23.64,83.18 21.07,80.61 21.07,78.08 20.59,77.59 20.59,75.16 19.93,74.5 19.93,73.04 19.34,72.45 19.34,69.01 24.09,64.26 24.09,54.31 25.34,53.06 25.34,48.8 25.01,48.46 25.01,45.89 25.69,45.2 25.69,42.54 29.78,38.46 33.98,38.46 34.97,37.47 38.19,37.47 38.81,38.09 51.93,38.09 52.51,37.5 53.86,37.5 54.55,36.82 55.08,36.82 55.87,36.03 61.53,36.03 62.07,36.57 64.4,36.57 65.01,37.17 67.88,37.17 68.84,36.21 72.73,36.21 75.96,39.43 75.96,39.94 76.82,40.81 80.17,40.81 80.82,40.16 80.82,37.57 81.1,37.29 v1(81.1,35.34)
  BOTTOM w0.089: CPU1.K51 80.35,39.42 80.35,39.01 80.52,38.84 80.68,38.84 80.84,38.69 81.36,38.69 81.94,38.1 81.94,36.87 81.1,36.03 v1(81.1,35.34)
EMMC_CLK: length 97.8
  TOP w0.102: v1(65.37,62.85) 65.37,62.43 EC1803.1 66.18,61.61 66.18,60.45 65.29,59.56 R807.2 ; v2(109.49,90.73) R6312.1 109.78,91.95 v1(109.78,94.24)
  L3 w0.127: v1(109.78,94.24) 108.65,95.37 98.58,95.37 97.95,96 96.83,96 94.49,98.34 84.9,98.34 78.94,92.39 78.76,92.39 78.62,92.53 78.44,92.53 78.26,92.35 78.26,92.17 78.4,92.03 78.4,91.85 78.22,91.67 78.04,91.67 77.9,91.81 77.73,91.81 77.55,91.63 77.55,91.45 77.68,91.31 77.68,86.58 75.97,84.87 75.8,84.87 75.74,84.92 75.56,84.92 75.38,84.74 75.38,84.56 75.44,84.51 75.44,84.33 75.26,84.15 75.08,84.15 74.52,84.71 74.34,84.71 74.16,84.53 74.16,84.35 74.72,83.79 74.72,83.61 74.54,83.43 74.36,83.43 72.46,85.33 72.28,85.33 72.1,85.15 72.1,84.97 74,83.07 74,82.89 73.82,82.71 73.64,82.71 72.53,83.83 72.35,83.83 72.17,83.65 72.17,83.47 73.28,82.36 73.28,82.18 72.85,81.74 72.85,79.68 70.24,77.07 70.24,76.58 69.38,75.72 69.38,72.25 66.28,69.15 66.28,68.97 66.46,68.79 66.64,68.79 68.97,71.12 69.15,71.12 69.33,70.94 69.33,70.76 66.62,68.05 66.62,65.56 65.94,64.88 65.28,64.22 65.28,63.73 65.37,63.64 v1(65.37,62.85)
EMMC_CLK_L: length 5.2
  TOP w0.102: R807.1 64.57,58.68 64.25,58.36 64.01,58.12 64,58.12 63.65,57.76 63.65,57.06 v2(63.74,56.96) 63.91,56.8 64.36,56.8 65.09,56.07 65.09,55.41 v1(65.09,55.41)
  BOTTOM w0.102: v1(65.09,55.41) 65.17,55.5 CPU1.M7
EMMC_CLK_R: length 6.7
  TOP w0.102: v1(103.51,93.06) v2(104.23,92.35) 104.61,91.96 106.19,91.96 106.56,91.59 108.53,91.59 R6312.2
  BOTTOM w0.102: U6301.M6 103.51,92.83 v1(103.51,93.06)
EMMC_CMD: length 107
  TOP w0.102: R6329.1 105.08,89.69 105.07,89.68 R6313.1 104.6,88.92 104.39,88.71 v2(103.89,88.71) 103.34,88.71 103.05,89 v1(103.05,89.28)
  L3 w0.089: v1(65.33,56.59) 65.37,56.63 65.92,56.63 67.94,54.61
  L3 w0.127: 67.94,54.61 68.16,54.39 68.62,54.39 68.97,54.74 68.97,56.13 69.52,56.68 69.52,57.09 68.54,58.08 68.54,58.47 68.46,58.54 68.31,58.54 68.19,58.67 68.19,58.93 68.31,59.05 68.49,59.05 68.61,59.18 68.61,59.45 68.22,59.85 68.22,60.2 68.51,60.49 68.51,62.82 68.64,62.95 68.83,62.95 68.95,63.08 68.95,63.33 68.83,63.46 68.64,63.46 68.51,63.58 68.51,63.76 69.42,64.66 69.42,64.95 69.64,65.17 69.82,65.17 70.28,64.7 70.46,64.7 70.64,64.88 70.64,65.06 70.18,65.53 70.18,65.71 70.36,65.89 70.54,65.89 71,65.42 71.18,65.42 71.36,65.6 71.36,65.78 70.9,66.25 70.9,66.43 71.08,66.61 71.26,66.61 71.72,66.14 71.9,66.14 72.08,66.32 72.08,66.5 71.62,66.97 71.62,67.15 71.8,67.33 71.97,67.33 72.44,66.86 72.62,66.86 72.8,67.04 72.8,67.22 72.33,67.68 72.33,67.86 73.04,68.57 73.04,72.58 73.52,73.06 73.52,76.38 75.66,78.51 75.66,79.25 80.52,84.12 80.52,89.96 82.6,92.03 82.78,92.03 83.09,91.72 83.27,91.72 83.45,91.9 83.45,92.08 83.13,92.39 83.13,92.57 83.31,92.75 83.49,92.75 83.8,92.44 83.98,92.44 84.16,92.62 84.16,92.8 83.85,93.11 83.85,93.29 84.03,93.47 84.21,93.47 84.52,93.16 84.7,93.16 84.88,93.34 84.88,93.52 84.57,93.83 84.57,94.01 84.97,94.4 89.14,94.4 89.27,94.53 89.27,94.9 89.14,95.02 86.99,95.02 86.87,95.15 86.87,95.4 86.99,95.53 90.4,95.53 93.71,92.22 93.71,92.01 93.56,91.86 93.35,91.86 90.17,95.04 89.99,95.04 89.81,94.86 89.81,94.68 93.44,91.05 93.9,91.05 94.02,90.93 94.02,90.4 94.15,90.28 94.43,90.28 94.56,90.4 94.56,91.03 94.69,91.15 94.94,91.15 95.07,91.03 95.07,90.4 95.2,90.27 95.45,90.27 95.58,90.4 95.58,90.97 95.7,91.1 95.96,91.1 96.08,90.97 96.08,90.53 96.21,90.41 100.56,90.41 101.08,89.89 102.83,89.89 103.05,89.68 v1(103.05,89.28)
  BOTTOM w0.102: CPU1.P6 65.43,56.7 v1(65.33,56.59)
EMMC_CMD_R: length 3.1
  TOP w0.102: v1(103.49,92.09) 103.71,91.87 v2(103.71,90.75) R6313.2
  BOTTOM w0.102: v1(103.49,92.09) 103.22,91.82 U6301.M5
EMMC_DATA_0: length 101.9
  TOP w0.102: v2(64.01,55.75) 64.16,55.91 v1(64.58,55.91)
  L3 w0.089: 63.71,56.68 63.71,56.18 63.98,55.91 v1(64.58,55.91)
  L3 w0.127: 63.71,56.68 64.1,57.08 64.1,58.28 64.5,58.68 64.5,60.61 65.12,61.23 65.12,61.62 65.79,62.29 65.79,64.01 67.13,65.35 67.13,67.84 69.89,70.6 69.89,75.51 70.75,76.37 70.75,76.86 73.37,79.48 73.37,80.2 74.31,81.15 74.31,82.49 78.2,86.38 78.2,90.87 85.15,97.82 94.3,97.82 96.62,95.49 97.74,95.49 98.37,94.86 103,94.86 103.5,94.36 106.08,94.36 106.89,93.55 107.62,93.55 107.8,93.73 112.98,93.73 113.1,93.85 113.1,94.47 113.23,94.59 113.48,94.59 113.61,94.47 113.61,93.85 113.74,93.73 113.99,93.73 114.12,93.85 114.12,94.46 114.25,94.58 114.5,94.58 114.63,94.46 114.63,93.85 114.76,93.73 115.01,93.73 115.14,93.85 115.14,94.45 115.26,94.57 115.52,94.57 115.64,94.45 115.64,93.85 115.77,93.73 118.21,93.73 118.4,93.54 120.62,93.54 120.99,93.16 v1(120.99,91.83)
  BOTTOM w0.102: v1(64.58,55.91) 64.67,56 CPU1.M6 ; v1(120.99,91.83) 119.62,90.45 117.59,90.45 R6330.1 R6315.2
EMMC_DATA_0_R: length 7.2
  BOTTOM w0.102: U6301.A3 109.14,90.82 109.62,90.34 113.06,90.34 v2(113.12,90.41) 113.43,90.71 114.96,90.71 R6315.1
EMMC_DATA_1: length 100.7
  L3 w0.127: v1(119.47,93.03) 119.47,92.61 119.34,92.48 118.01,92.48 117.89,92.61 117.89,93.33 117.76,93.45 117.4,93.45 117.28,93.33 117.28,93.18 117.15,93.05 116.9,93.05 116.77,93.18 116.77,93.35 116.64,93.47 116.39,93.47 116.26,93.35 116.26,93.18 116.13,93.05 115.88,93.05 115.75,93.18 115.75,93.35 115.62,93.47 115.37,93.47 115.24,93.35 115.24,93.18 115.12,93.05 114.86,93.05 114.74,93.18 114.74,93.35 114.61,93.47 114.35,93.47 114.23,93.35 114.23,93.18 114.1,93.05 113.85,93.05 113.72,93.18 113.72,93.35 113.59,93.47 113.34,93.47 113.21,93.35 113.21,93.18 113.08,93.05 112.83,93.05 112.7,93.18 112.7,93.35 112.58,93.47 112.32,93.47 112.19,93.35 112.19,93.18 112.07,93.05 111.81,93.05 111.69,93.18 111.69,93.35 111.56,93.47 111.3,93.47 111.18,93.35 111.18,93.18 111.05,93.05 110.8,93.05 110.67,93.18 110.67,93.35 110.54,93.47 110.29,93.47 110.16,93.35 110.16,93.18 110.03,93.05 109.78,93.05 109.65,93.18 109.65,93.35 109.53,93.47 108.66,93.47 108.54,93.35 108.54,92.4 108.41,92.27 108.14,92.27 108.01,92.4 108.01,93.15 107.88,93.28 107.62,93.28 107.49,93.15 107.49,92.68 107.36,92.56 106.7,92.56 106.57,92.68 106.57,93.14 106.44,93.27 104.62,93.27 103.93,93.96 103.54,93.96 102.9,94.6 98.26,94.6 97.63,95.24 96.52,95.24 96.39,95.36 96.21,95.36 96.1,95.25 95.92,95.25 95.74,95.43 95.74,95.61 95.86,95.72 95.86,95.9 95.68,96.08 95.5,96.08 95.38,95.97 95.2,95.97 95.02,96.14 95.02,96.32 95.14,96.44 95.14,96.62 94.96,96.8 94.78,96.8 94.66,96.68 94.48,96.68 94.3,96.86 94.3,97.04 94.42,97.16 94.42,97.34 94.19,97.56 85.25,97.56 78.45,90.77 78.45,86.27 74.57,82.39 74.57,81.04 73.62,80.1 73.62,79.38 71,76.76 71,76.26 70.15,75.4 70.15,70.49 67.38,67.73 67.38,65.28 66.02,63.92 66.02,62.2 65.41,61.59 65.41,61.11 64.75,60.45 64.75,58.6 64.34,58.19 64.34,56.57 v1(64.12,56.34)
  BOTTOM w0.102: v1(119.47,93.03) 118.92,92.48 117.59,92.48 R6331.1 R6316.2 ; v1(64.12,56.34) 64.25,56.47 CPU1.M4
EMMC_DATA_1_R: length 7.7
  BOTTOM w0.102: U6301.A4 109.61,91.32 109.91,91.02 112.54,91.02 114.03,92.51 v2(114.36,92.51) 114.56,92.71 114.93,92.71 R6316.1
EMMC_DATA_2: length 102.8
  TOP w0.102: v1(120.44,93.07) 120.44,93.24 v2(121.72,94.52)
  L3 w0.089: 64.59,56.95 64.59,56.48 65.44,55.63 v1(66.26,55.63)
  L3 w0.127: v1(120.44,93.07) 120.62,92.89 120.62,92.4 120.53,92.3 119.69,92.3 119.58,92.19 119.58,91.69 119.47,91.58 118.42,91.58 117.22,92.79 109.7,92.79 108.24,91.32 108.01,91.32 107.88,91.45 107.88,91.74 107.76,91.87 107.5,91.87 107.38,91.74 107.38,91.45 107.25,91.32 106.43,91.32 106.31,91.45 106.31,92.87 106.16,93.02 104.52,93.02 103.82,93.71 103.43,93.71 102.79,94.35 98.16,94.35 97.53,94.98 95.81,94.98 93.49,97.31 85.36,97.31 78.71,90.66 78.71,86.17 74.83,82.29 74.83,80.94 73.88,79.99 73.88,79.27 71.26,76.65 71.26,76.15 70.4,75.3 70.4,70.39 67.64,67.63 67.64,65.21 66.25,63.83 66.25,61.87 66.13,61.74 65.9,61.74 65.77,61.62 65.77,61.36 65.9,61.23 66.13,61.23 66.25,61.11 66.25,60.55 65.83,60.12 65.65,60.12 65.36,60.4 65.18,60.4 65,60.22 65,60.04 65.29,59.76 65.29,59.58 64.99,59.28 64.99,58.33 64.59,57.93 64.59,56.95
  BOTTOM w0.102: CPU1.P9 66.32,55.69 v1(66.26,55.63) ; v1(120.44,93.07) 120.44,93.2 119.7,93.95 119.36,93.95 118.8,94.52 117.59,94.52 R6332.1 R6317.2
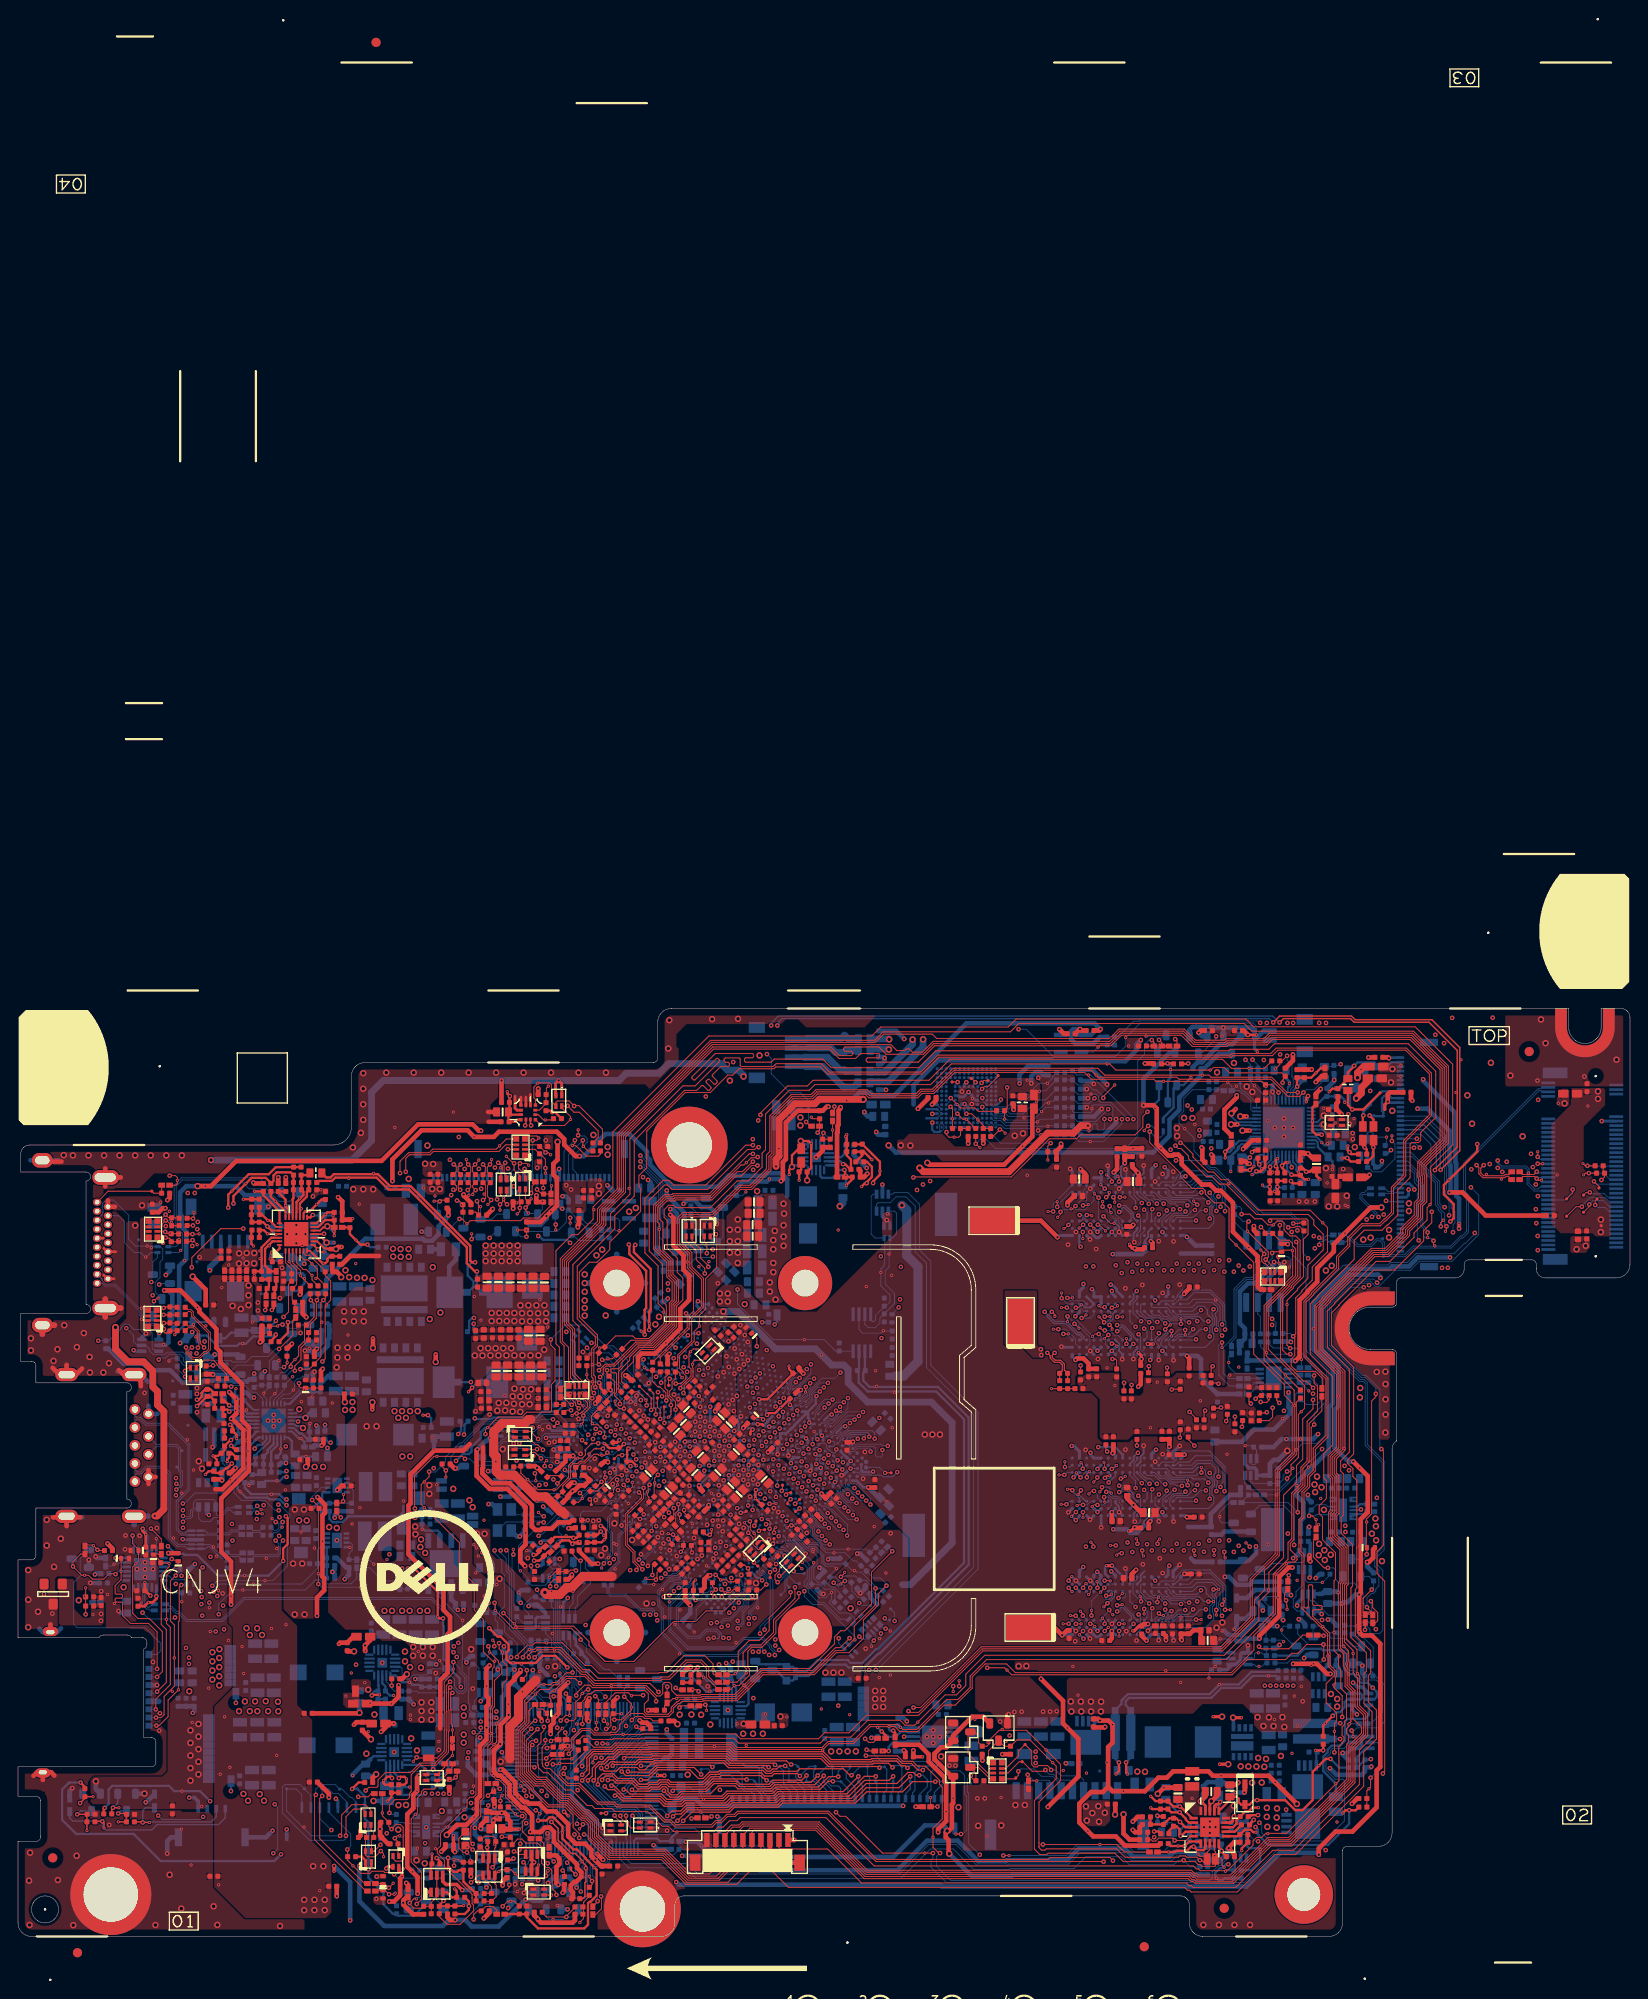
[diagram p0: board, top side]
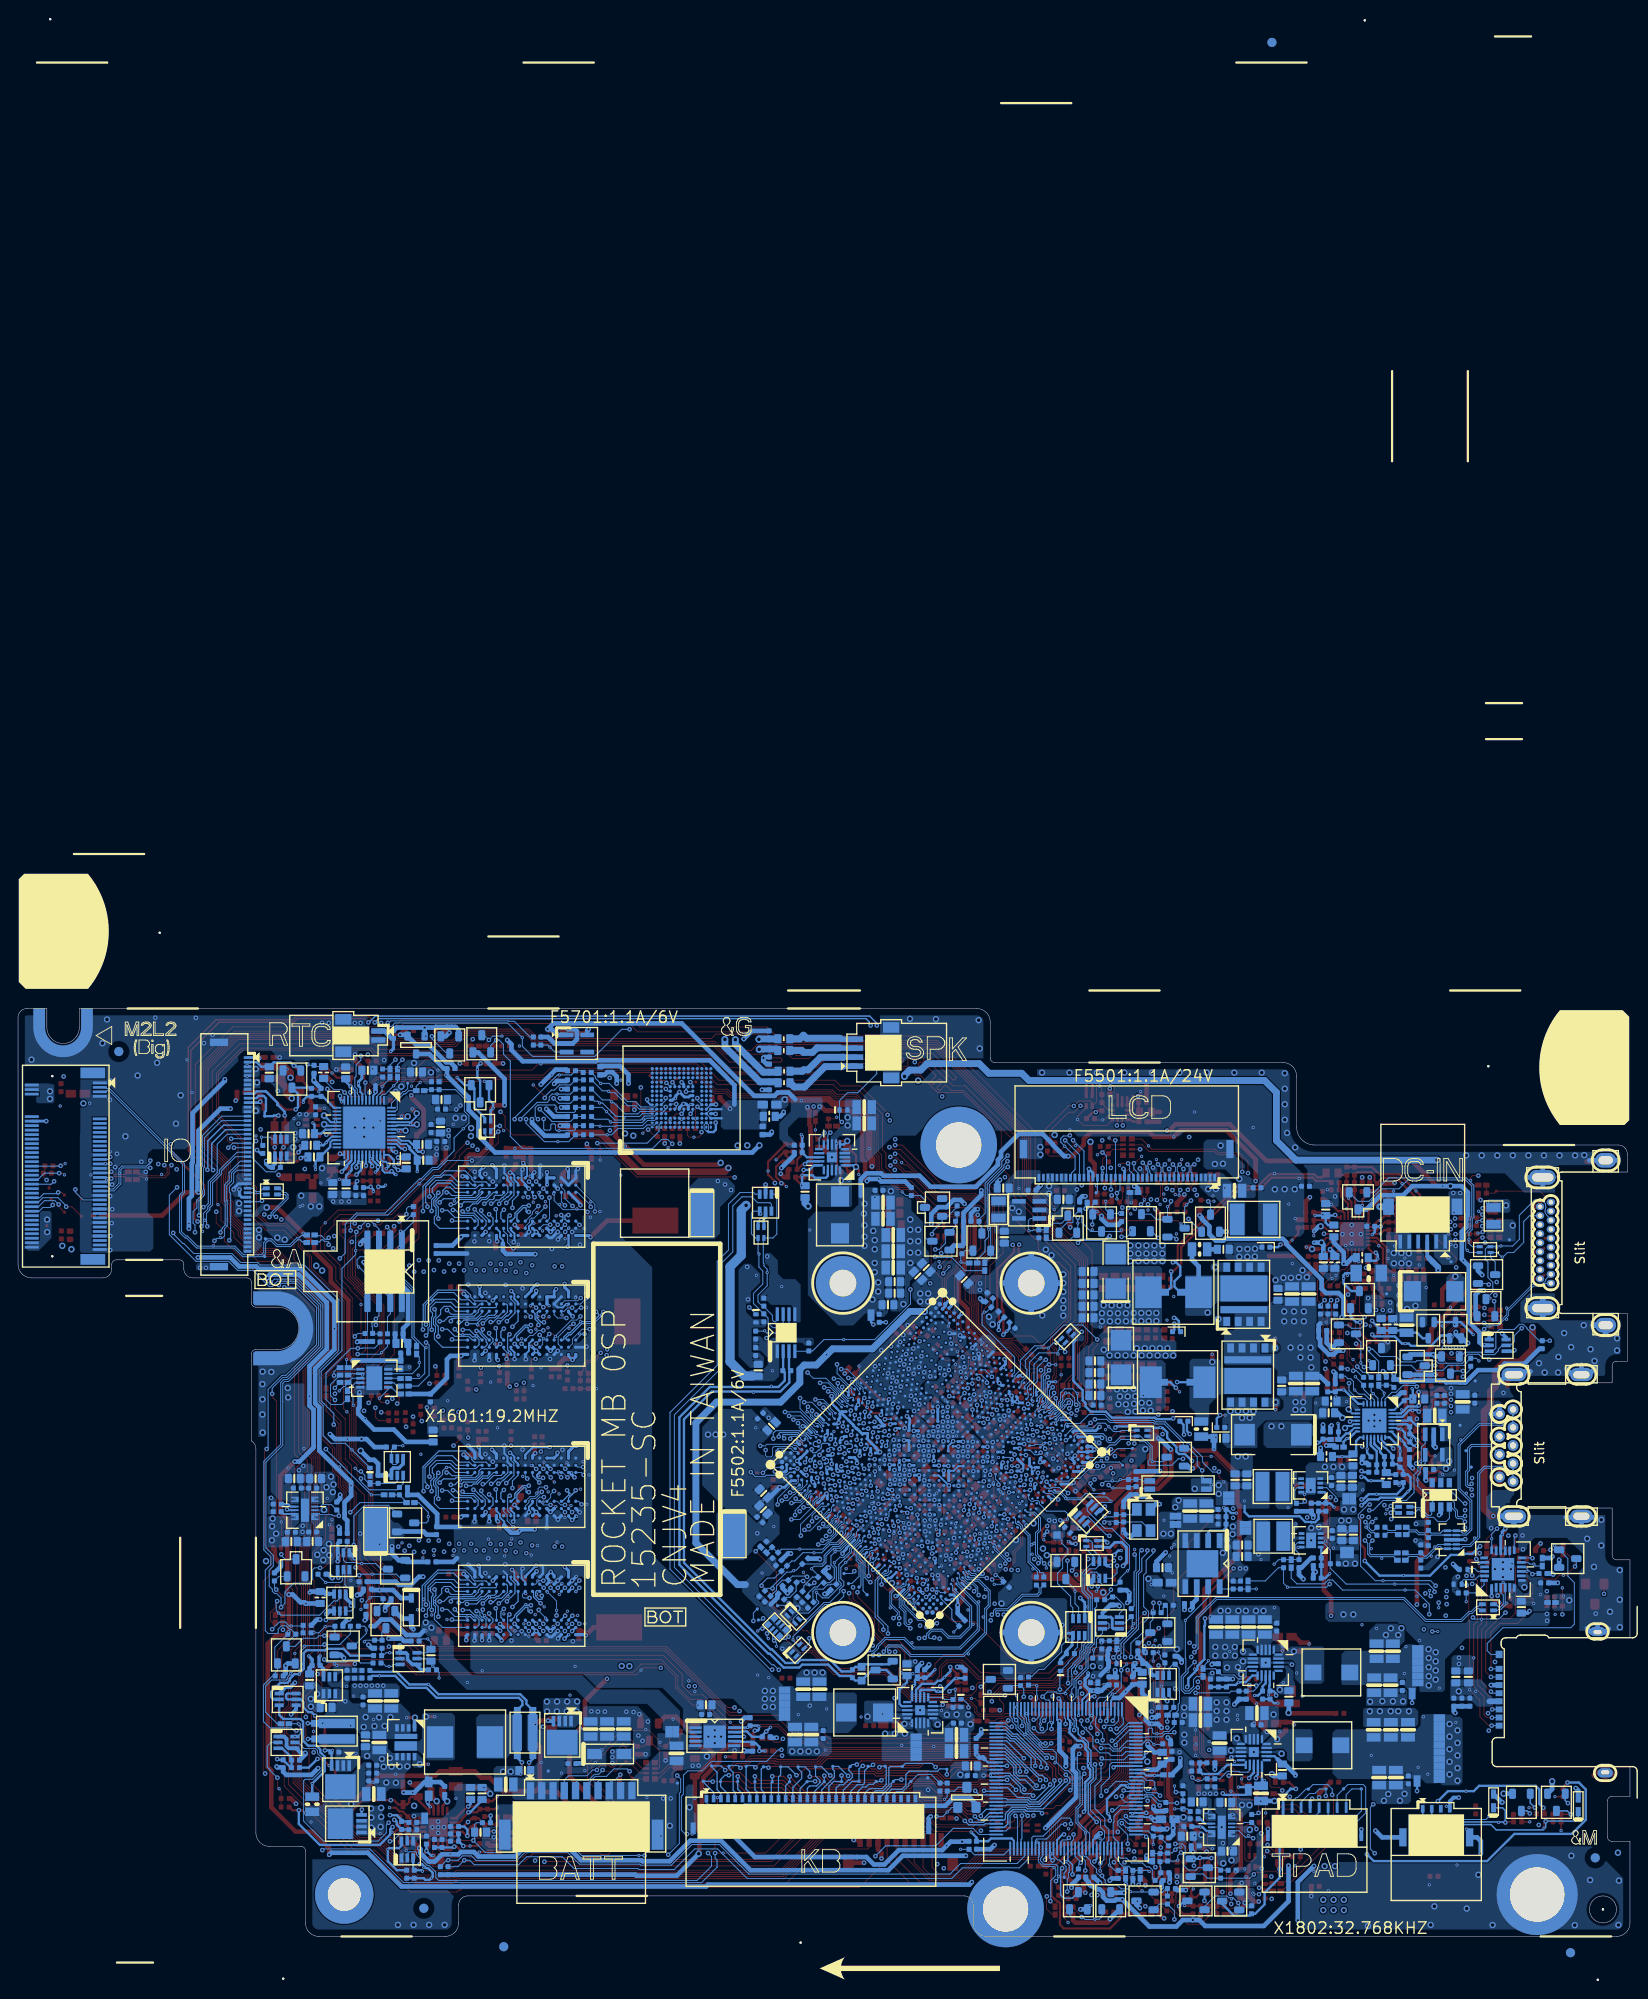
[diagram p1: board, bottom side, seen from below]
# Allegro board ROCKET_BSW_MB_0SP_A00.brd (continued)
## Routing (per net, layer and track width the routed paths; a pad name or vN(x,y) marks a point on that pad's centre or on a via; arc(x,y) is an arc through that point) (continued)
EMMC_DATA_2_R: length 8.1
  BOTTOM w0.102: U6301.A5 109.94,91.82 110.32,92.2 111.22,92.2 112.68,93.66 113.2,93.66 v2(113.36,93.82) 113.41,93.87 114.05,93.87 R6317.1
EMMC_DATA_3: length 102.6
  L3 w0.089: v1(65.79,56.06) 65.28,56.06 64.92,56.42 64.92,56.99
  L3 w0.127: 64.92,56.99 64.92,57.85 65.23,58.16 65.23,59.19 66.48,60.45 66.48,63.73 67.89,65.14 67.89,67.52 70.65,70.28 70.65,75.19 71.51,76.05 71.51,76.55 74.13,79.17 74.13,79.88 75.1,80.85 75.1,82.14 75.79,82.84 75.97,82.84 76.4,82.42 76.61,82.42 76.76,82.57 76.76,82.78 76.33,83.2 76.33,83.38 76.51,83.56 76.69,83.56 77.15,83.1 77.33,83.1 77.51,83.28 77.51,83.46 77.05,83.92 77.05,84.1 78.96,86.01 78.96,90.56 85.46,97.06 93.37,97.06 95.7,94.73 97.42,94.73 98.05,94.1 101.85,94.1 103.33,92.62 104.2,92.62 104.86,91.95 105.35,91.95 106.23,91.07 108.36,91.07 109.82,92.53 117.1,92.53 118.31,91.32 121.91,91.32 v1(122.52,90.72)
  BOTTOM w0.102: CPU1.P7 65.93,56.2 v1(65.79,56.06) ; R6318.2 R6333.1 117.79,88.22 v2(118.99,88.22) 120.48,88.22 122.52,90.26 v1(122.52,90.72)
EMMC_DATA_3_R: length 7.8
  BOTTOM w0.089: 108.82,90.07 108.26,90.07 U6301.B2
  BOTTOM w0.102: 108.82,90.07 109.1,90.07 109.48,89.69 112.3,89.69 113.01,88.98 v2(113.52,88.98) 113.52,88.98 R6318.1
EMMC_DATA_4: length 100.8
  L3 w0.127: v1(120.56,90.74) 120.3,91 118.26,91 116.99,92.28 109.93,92.28 108.46,90.81 104.04,90.81 103.02,91.83 103.02,92.51 101.69,93.84 97.95,93.84 97.32,94.47 96.93,94.47 96.8,94.35 96.8,93.64 96.68,93.52 95.97,93.52 95.84,93.64 95.84,94.21 93.25,96.8 85.57,96.8 79.22,90.45 79.22,84.74 79.09,84.61 78.88,84.61 78.53,84.96 78.35,84.96 78.17,84.78 78.17,84.6 78.56,84.21 78.56,83.96 76.48,81.87 76.3,81.87 75.9,82.27 75.72,82.27 75.54,82.09 75.54,81.91 75.94,81.51 75.94,81.33 74.39,79.78 74.39,79.06 71.77,76.44 71.77,75.94 70.91,75.08 70.91,70.18 68.14,67.41 68.14,65.07 66.71,63.64 66.71,60.35 65.93,59.57 65.93,59.26 65.8,59.13 65.6,59.13 65.47,59 65.47,58.75 65.6,58.62 65.8,58.62 65.93,58.5 65.93,57.51 65.84,57.41 65.66,57.41 65.53,57.29 65.53,57.03 65.66,56.91 66.37,56.91 v1(66.45,56.82)
  BOTTOM w0.102: v1(120.56,90.74) 120.56,89.64 120.43,89.51 119.9,89.51 119.77,89.64 119.77,90.07 119.64,90.2 119.37,90.2 119.24,90.07 119.24,89.56 119.11,89.44 v2(118.86,89.44) 117.19,89.44 117.03,89.59 R6334.1 R6319.2 ; 66.52,57.39 66.52,56.9 v1(66.45,56.82)
EMMC_DATA_4_R: length 7.6
  BOTTOM w0.089: 108.87,90.57 108.26,90.57 U6301.B3
  BOTTOM w0.102: 108.87,90.57 109.04,90.57 109.62,89.99 112.51,89.99 112.57,89.93 v2(114.3,89.93) 114.36,89.99 R6319.1
EMMC_DATA_5: length 100.3
  L3 w0.127: v1(121.2,90.71) 121.2,90.36 121.11,90.27 120.19,90.27 120.12,90.34 120.12,90.6 119.96,90.75 118.16,90.75 116.88,92.03 111.07,92.03 110.97,91.93 110.97,91.47 110.81,91.3 110.17,91.3 110.09,91.38 110.09,91.54 109.95,91.68 109.69,91.68 108.57,90.56 103.93,90.56 102.77,91.72 102.77,92.37 101.56,93.59 97.84,93.59 97.63,93.8 97.15,93.8 97.06,93.7 97.06,93.41 96.91,93.26 95.77,93.26 95.59,93.45 95.59,94.1 93.14,96.55 85.67,96.55 79.49,90.36 79.49,84.52 74.64,79.67 74.64,78.95 72.02,76.34 72.02,75.84 71.16,74.98 71.16,70.07 68.4,67.31 68.4,65 67,63.6 67,63.43 67.12,63.3 67.47,63.3 67.59,63.18 67.59,62.83 67.47,62.7 67.07,62.7 66.94,62.57 66.94,60.24 66.16,59.46 66.16,57.79 67.15,56.8 67.15,56.52 v1(66.95,56.32)
  BOTTOM w0.102: v1(66.95,56.32) 66.95,56.81 CPU1.T7 ; R6320.2 R6335.1 117.03,91.6 117.16,91.47 119.07,91.47 119.19,91.59 v2(119.19,91.88) 119.19,92.16 119.32,92.29 121.21,92.29 121.5,91.99 121.5,91.02 v1(121.2,90.71)
EMMC_DATA_5_R: length 8.1
  BOTTOM w0.089: 108.76,91.07 108.26,91.07 U6301.B4
  BOTTOM w0.102: 108.76,91.07 109.34,91.07 109.79,90.61 112.65,90.61 v2(113.59,91.55) 114.06,92.03 R6320.1
EMMC_DATA_6: length 99.9
  L3 w0.127: v1(67.46,55.82) 67.46,56.83 66.39,57.9 66.39,59.34 67.17,60.12 67.17,61.4 67.83,62.06 67.83,64.07 68.65,64.9 68.65,67.2 71.42,69.97 71.42,74.87 72.27,75.73 72.27,76.23 74.89,78.85 74.89,79.57 79.74,84.42 79.74,90.26 85.78,96.29 92.38,96.29 95.69,92.99 101.44,92.99 102.28,92.14 102.28,91.58 103.56,90.3 108.67,90.3 109.42,91.05 111.01,91.05 111.61,91.64 116.76,91.64 117.93,90.48 119.06,90.48 119.53,90.01 122.44,90.01 v1(123.15,90.72)
  BOTTOM w0.102: R6321.2 R6336.1 117.59,93.5 v2(119.09,93.5) 119.63,93.5 119.94,93.18 119.94,92.82 120.17,92.59 121.28,92.59 v1(123.15,90.72) ; CPU1.T10 67.52,55.88 v1(67.46,55.82)
EMMC_DATA_6_R: length 8.6
  BOTTOM w0.089: 108.77,91.57 108.26,91.57 U6301.B5
  BOTTOM w0.102: R6321.1 114.05,92.85 113.25,92.85 v2(113.04,92.64) 112.95,92.55 112.78,92.55 111.53,91.3 110.11,91.3 109.84,91.57 108.77,91.57
EMMC_DATA_7: length 101.2
  L3 w0.127: v1(123.79,90.72) 122.61,89.54 118.04,89.54 117.14,90.44 109.17,90.44 108.78,90.05 103.45,90.05 101.73,91.77 101.17,91.77 100.41,92.53 95.73,92.53 92.23,96.04 85.88,96.04 80,90.15 80,84.31 75.15,79.46 75.15,78.72 72.53,76.11 72.53,75.63 71.67,74.77 71.67,69.6 72.24,69.04 72.24,68.49 68.91,65.16 68.91,64.83 68.06,63.98 68.06,61.96 67.4,61.3 67.4,60.02 67.35,59.98 67.35,59.08 67.68,58.75 67.68,56.19 67.89,55.98 v1(67.89,55.29)
  BOTTOM w0.102: v1(123.79,90.72) 123.79,90.87 119.03,95.63 v2(118.81,95.63) 117.5,95.63 R6337.1 116.36,96.09 R6322.2 ; v1(67.89,55.29) 67.98,55.38 CPU1.T12
EMMC_DATA_7_R: length 9.1
  BOTTOM w0.089: 109.22,92.07 108.26,92.07 U6301.B6
  BOTTOM w0.102: R6322.1 114.81,95.43 114.81,95.27 v2(114.23,94.69) 113.29,94.69 111.26,92.67 110.37,92.67 109.78,92.07 109.22,92.07
EMMC_E9: length 3
  TOP w0.102: TP6301.1 108.76,95.45 107.64,94.33 107.26,94.33 v1(107,94.07)
  BOTTOM w0.102: U6301.E9 106.76,93.82 v1(107,94.07)
EMMC_E10: length 1.4
  TOP w0.102: v1(106.94,94.75) 107.19,95 TP6302.1
  BOTTOM w0.102: v1(106.94,94.75) U6301.E10
EMMC_F10: length 1.3
  TOP w0.102: TP6303.1 105.83,95.24 v1(106.27,94.8)
  BOTTOM w0.102: v1(106.27,94.8) 106.01,94.55 U6301.F10
EMMC_K10: length 1.2
  TOP w0.102: TP6304.1 104.26,94.85 v1(104.29,94.82)
  BOTTOM w0.102: v1(104.29,94.82) 104.01,94.55 U6301.K10
EMMC_RCLK: length 105.9
  TOP w0.102: R6314.1 108.2,88.8 v1(108.97,89.56) 109.15,89.56 v2(109.56,89.16)
  L3 w0.127: v1(68.45,54.81) 68.31,54.94 68.31,55.66 68.39,55.74 68.59,55.74 68.74,55.89 68.74,56.1 68.59,56.25 68.06,56.25 67.91,56.4 67.91,56.61 68.06,56.75 69.02,56.75 69.17,56.9 69.17,57.11 69.02,57.26 68.05,57.26 67.92,57.39 67.92,57.64 68.05,57.77 68.15,57.77 68.3,57.92 68.3,58.13 68.15,58.28 68.05,58.28 67.92,58.41 67.92,58.83 67.58,59.17 67.58,59.78 67.65,59.85 67.65,60.18 67.85,60.39 68.05,60.39 68.2,60.53 68.2,60.75 68.05,60.89 67.85,60.89 67.72,61.02 67.72,61.27 67.85,61.4 68.16,61.4 68.28,61.53 68.28,63.88 69.14,64.73 69.14,64.99 72.78,68.64 72.78,69.69 72.66,69.82 72.31,69.82 72.21,69.92 72.21,70.23 72.31,70.33 72.66,70.33 72.78,70.46 72.78,72.82 72.66,72.95 72.05,72.95 71.93,73.07 71.93,73.33 72.05,73.46 73.05,73.46 73.18,73.58 73.18,73.84 73.05,73.96 72.08,73.96 71.93,74.11 71.93,74.32 72.08,74.47 72.66,74.47 72.78,74.6 72.78,74.94 72.91,75.07 73.13,75.07 73.26,75.19 73.26,75.45 73.13,75.57 72.91,75.57 72.78,75.7 72.78,76 75.4,78.62 75.4,79.36 80.26,84.21 80.26,90.05 85.99,95.79 90.64,95.79 92.96,93.47 93.1,93.47 93.32,93.68 93.32,93.82 91.73,95.41 91.73,95.59 91.91,95.77 92.09,95.77 95.59,92.27 95.59,92.09 95.41,91.91 95.23,91.91 94.67,92.48 94.49,92.48 94.31,92.3 94.31,92.12 95.03,91.39 95.64,91.39 95.92,91.67 96.17,91.67 96.3,91.55 96.3,91.12 96.43,91 96.68,91 96.81,91.12 96.81,92.16 96.91,92.26 97.22,92.26 97.32,92.16 97.32,90.78 97.42,90.67 97.72,90.67 97.83,90.78 97.83,92.17 97.93,92.28 98.23,92.28 98.33,92.17 98.33,90.78 98.44,90.67 98.74,90.67 98.84,90.78 98.84,92.17 98.94,92.27 99.25,92.27 99.35,92.17 99.35,90.77 99.45,90.67 100.2,90.67 100.3,90.77 100.3,91.75 100.43,91.88 100.68,91.88 100.81,91.75 100.81,91 101.03,90.78 102.33,90.78 103.32,89.8 108.73,89.8 v1(108.97,89.56)
  BOTTOM w0.102: v1(68.45,54.81) 68.51,54.87 CPU1.T13
EMMC_RCLK_R: length 4.2
  TOP w0.102: v1(105.26,91.32) 105.84,91.32 v2(106.53,90.63) 107.13,90.04 R6338.1 R6314.2
  BOTTOM w0.102: U6301.H5 105.01,91.56 v1(105.26,91.32)
EMMC_RESET#: length 35.3
  TOP w0.102: R6326.1 126.05,98.84 R6327.1 126.06,99.27 v1(125.83,99.5) ; v2(106.76,87.55) 106.72,87.55 v1(106.29,87.98) R6309.1
  BOTTOM w0.102: Q6301.S 126.45,98.88 v1(125.83,99.5) 125.5,99.5 125.03,99.03 125.03,97.93 124.26,97.16 124.26,88.81 122.93,87.48 108.46,87.48 107.47,88.47 106.79,88.47 v1(106.29,87.98)
EMMC_RESET#_R: length 3.3
  TOP w0.102: R6309.2 106.27,89.69 v2(105.24,90.71) 104.86,90.71 v1(104.26,91.32)
  BOTTOM w0.102: v1(104.26,91.32) 104.01,91.56 U6301.K5
EMMC_VCC: length 5.7
  BOTTOM w0.102: U6301.J10 104.76,94.07 v1(104.76,93.78) 104.06,93.78 U6301.K9 ; U6301.F5 105.85,91.98 v1(105.85,92.4) 106.44,92.4 U6301.E6
  BOTTOM w0.508: C6302.1 113.8,95.63 113.5,95.94 112.93,95.94 112.45,95.46 v1(112.45,94.69)
  vias: v2(105.93,93.01) v2(111.99,95.05)
EMMC_VCCQ: length 45.1
  TOP w0.508: v1(99.87,91.88) 101,93 C6303.1
  L4 w0.508: v1(107.02,93.07) 104.57,93.07 103.86,93.78 101.78,93.78 v1(99.87,91.88)
  BOTTOM w0.102: v1(107.02,93.07) 107.02,92.81 U6301.C6 ; U6301.M4 U6301.N4 ; U6301.N4 U6301.P3 ; U6301.N4 U6301.P5
  BOTTOM w0.254: 100.82,90.82 100.83,90.82 102.01,90.82 U6301.P3 ; 100.82,91.82 U6301.P5
  BOTTOM w0.508: 99.39,92.34 99.39,94.5 101.19,96.3 101.19,96.32 102.13,97.25 114.69,97.25 114.8,97.15 122.89,97.15 124.14,98.4 124.14,99.03 v1(124.61,99.5)
  vias: v2(123.25,98.84)
EMMC_VDDI: length 10.5
  TOP w0.102: v1(114.61,88.06) 114.29,87.74 C6301.1 114.29,86.19 v2(114.29,86.18)
  BOTTOM w0.089: U6301.C2 107.76,90.07 107.76,89.52
  BOTTOM w0.102: 107.76,89.52 107.76,89.37 109.08,88.06 v1(114.61,88.06)
FFS_INT2_CPU: length 8.9
  BOTTOM w0.102: RN801.1 54.78,56.16 56.45,56.16 56.56,56.05 57.31,56.05 v2(57.84,56.57) 58.24,56.97 59.07,56.97 59.6,56.44 61.82,56.44 61.94,56.33 61.94,56.33 62.14,56.13 62.14,56.13 CPU1.H3
GFX_CORE: length 1
  TOP w0.508: EC1007.1 62.25,79.04 62.13,78.92 v1(62.13,78.72)
  vias: v1(75.15,56.04) v1(75.16,57.13) v1(75.72,57.69) v1(75.7,56.59) v1(75.67,55.5) v1(76.26,57.15) v1(76.25,56.06) v1(76.81,56.59) v1(76.78,55.5) v1(77.32,56.07) v1(77.84,55.56) v2(50.63,71.04) v2(51.38,68.41) v2(57.91,70.68) v2(58.78,67.64) v2(74.75,55.55) v3(52.57,69.2) v3(52.57,68.31) v3(53.41,69.2) v3(53.41,68.31) v3(54.24,69.2) v3(54.24,68.31) v3(55.08,69.2) v3(55.08,68.31) v3(55.75,70.05) v3(55.94,69.17) v3(55.94,68.29) v3(56.64,70.05) v3(56.83,69.17) v3(56.83,68.29) v3(57.53,70.05) v3(57.72,69.17) v3(57.72,68.29) v3(58.42,70.05) v3(58.6,69.17) v3(58.6,68.29) v3(70.73,67.94) v3(71.14,68.78)
GFX_PWRGD: length 36.7
  TOP w0.102: v1(23.66,61.03) 23.6,61.09 PR4638.1 22.97,61.75 PC4614.1 23.14,62.43 22.07,63.5 22.07,63.56 22.03,63.6 22.03,63.62 21.68,63.97 20.68,63.97 20.3,63.59 20.24,63.59 RN5704.1 ; PU4802.6 31.69,75.85 31.92,75.61 32.36,75.61 34.09,73.88 PC4809.1 34.09,73.36 34.7,72.75 34.7,70.63 34.22,70.16 v2(34.22,70.09) 34.09,69.95 34.09,64.12 v1(33.79,63.82)
  L4 w0.102: v1(23.66,61.03) 24.9,61.03 25.48,61.61 30.54,61.61 30.81,61.88 31.42,61.88 32.73,63.18 33.15,63.18 v1(33.79,63.82)
  BOTTOM w0.102: v1(23.66,61.03) 23.8,61.17 25.19,61.17 25.96,60.4 26.41,60.4 27.17,59.65 PU4601.1
GP_CAMERASB00: length 1.4
  TOP w0.102: TP807.1 80.62,47.02 v1(80.21,47.02)
  BOTTOM w0.102: v1(80.21,47.02) 80.35,47.16 CPU1.AB41
GP_CAMERASB01: length 1.4
  TOP w0.102: v1(82.22,45.01) 82.34,45.13 TP808.1
  BOTTOM w0.102: CPU1.AB45 82.22,45.5 v1(82.22,45.01)
GP_CAMERASB02: length 1.3
  TOP w0.102: v1(81.71,45.58) 81.91,45.77 TP809.1
  BOTTOM w0.102: v1(81.71,45.58) 81.71,46 CPU1.AB44
GP_CAMERASB03: length 5.2
  BOTTOM w0.102: CPU1.AC53 85.88,42.82 85.88,41.73 85.56,41.42 85.56,39.96 86.36,39.17 TP810.1
GP_CAMERASB04: length 1.2
  TOP w0.102: v1(83.78,43.59) 83.91,43.72 TP811.1
  BOTTOM w0.102: v1(83.78,43.59) 83.94,43.75 CPU1.AB51
GP_CAMERASB05: length 5.2
  BOTTOM w0.102: TP812.1 85.35,38.99 85.35,41.52 85.67,41.85 85.67,42.52 84.94,43.25 CPU1.AB52
GP_CAMERASB06: length 6.4
  BOTTOM w0.102: TP813.1 85.12,38.37 85.12,41.67 85.47,42.02 85.47,42.43 84.95,42.95 84.48,42.95 84.26,43.16 CPU1.AA51
GP_CAMERASB07: length 11.9
  L3 w0.127: v1(79.81,47.54) 80.5,47.54 82.73,45.31 82.73,44.01 86.08,40.65 v1(86.08,40.54)
  BOTTOM w0.102: TP814.1 86.34,40.29 v1(86.08,40.54) ; v1(79.81,47.54) 80.23,47.54 CPU1.AB40
GP_CAMERASB08: length 6.3
  TOP w0.102: v2(80.6,45.93) 81.04,45.49 v1(81.04,44.81) 81.56,44.29 81.56,43.51 82.12,42.95 82.28,42.95 RN1501.1 82.57,42.1 R1529.2
  BOTTOM w0.102: v1(81.04,44.81) 81.04,45.33 CPU1.Y44
GP_CAMERASB09: length 5.5
  TOP w0.102: R1535.2 83.68,42.89 82.62,43.95 82.36,43.95 RN1501.2 82.11,43.71 81.81,44.01 81.81,44.63 v2(81.7,44.74) 81.29,45.15 81.29,46.01 v1(81.22,46.08)
  BOTTOM w0.102: v1(81.22,46.08) 80.78,46.08 CPU1.Y42
GP_CAMERASB11: length 15.9
  TOP w0.102: v1(70.41,40.12) 70.41,41.05 R1536.1
  L3 w0.127: v1(70.41,40.12) 70.66,40.12 72.69,42.15 72.69,42.5 75.07,44.88 76.35,44.88 77.14,45.67 77.25,45.67 77.79,46.2 77.79,46.28 78.32,46.81 v1(79.09,46.81)
  BOTTOM w0.102: v1(70.41,40.12) 70.27,40.12 R1537.2 69.82,39.09 v2(70.55,39.09) ; CPU1.V40 79.09,46.39 v1(79.09,46.81)
GPIO_ALERT: length 5.4
  BOTTOM w0.102: CPU1.Y3 66.79,59.85 66.79,60.34 66.88,60.43 66.88,60.95 66.15,61.68 66.15,63.5 TP1612.1
GPIO_RCOMP18: length 2.5
  TOP w0.254: v1(81.9,49.55) 81.84,49.49 v2(81.84,48.61) R1639.2
  BOTTOM w0.254: CPU1.AH40 82.29,49.59 81.94,49.59 v1(81.9,49.55)
GPIO_SUS0: length 13.5
  BOTTOM w0.102: CPU1.AD51 85.15,44.25 85.15,43.83 85.34,43.64 85.46,43.64 86.1,43 86.1,42.44 87.03,41.51 v2(87.04,41.51) 87.58,40.97 87.58,39.7 87.25,39.37 87.25,38.96 87.7,38.5 87.7,38.18 88.81,37.08 89.44,37.08 91.3,35.22 RN1502.4
GPIO_SUS1: length 15.1
  BOTTOM w0.102: CPU1.AD52 85.45,43.94 86.4,42.98 86.4,42.63 87.15,41.89 87.2,41.89 87.81,41.28 87.81,39.46 87.55,39.2 87.55,38.98 88.95,37.58 89.64,37.58 90.25,38.2 v2(90.29,38.2) 90.29,37.41 90.04,37.17 90.04,37 91.15,35.89 92.25,35.89 92.86,35.28 92.86,34.95 RN1502.3
GPIO_SUS2: length 16
  TOP w0.102: v1(91.32,39.92) 91.73,40.32 v2(91.73,40.41)
  L4 w0.127: v1(85.31,46.13) 86.15,46.13 86.93,45.34 86.93,44.16 87.26,43.84 87.26,43.57 89.64,41.19 89.68,41.19 89.75,41.12 89.84,41.12 91.04,39.92 v1(91.32,39.92)
  BOTTOM w0.102: v1(91.32,39.92) 91.41,40 92.96,40 R1508.1 94.08,39.54 94.73,38.88 94.73,38.46 94.74,38.45 94.74,38.44 95.07,38.1 95.07,38.1 R1517.2 ; v1(85.31,46.13) 85.81,46.13 CPU1.AH50
GPIO_SUS3: length 15.2
  TOP w0.102: v1(91.77,39.45) 91.65,39.45 v2(91.31,39.12)
  L4 w0.127: v1(91.77,39.45) 90.96,39.45 89.92,40.5 89.92,40.59 87.03,43.48 87.03,43.74 84.85,45.92 v1(84.85,46.66)
  BOTTOM w0.102: CPU1.AH48 85.39,46.66 v1(84.85,46.66) ; v1(91.77,39.45) 92.33,39.45 R1504.1 92.54,39.24 92.54,38.34 93.24,37.64 93.65,37.64 R1520.2
GPIO_SUS4: length 2.9
  TOP w0.102: R1532.2 86.95,44.72 R1503.1 86.04,45.63 v1(85.83,45.63) 85.62,45.63 v2(85.34,45.35)
  BOTTOM w0.102: CPU1.AH51 86.15,45.63 v1(85.83,45.63)
GSEN2_INT1: length 133.2
  TOP w0.152: 159.73,93.68 159.73,98.34 156.6,101.47 148.29,101.47 147.88,101.88 140.44,101.88 v1(140.02,101.46) ; 159.73,93.68 v2(159.59,93.68) ; 159.73,93.68 159.73,87.65 157.25,85.17 v1(157.25,85.07) ; U6901.12 56.87,90.1 v1(56.95,90.02)
  L3 w0.152: v1(56.95,90.02) 57.18,89.79 58.46,89.79 59.4,90.73 59.41,90.73 59.47,90.79 67.92,90.79 76.42,99.29 80.56,99.29 81.75,100.48 83.46,100.48 83.64,100.66 83.64,101.07 v1(83.59,101.12)
  BOTTOM w0.152: v1(83.59,101.12) 83.59,101.37 84.38,102.16 139.25,102.16 139.95,101.46 v1(140.02,101.46) ; IOBD1.17 155.87,89.55 157.4,88.01 157.4,85.22 v1(157.25,85.07)
GSEN2_INT2: length 135
  TOP w0.152: 160.01,97.31 160.01,87.22 v1(157.89,85.1) ; 160.01,97.31 160.01,98.66 156.92,101.75 148.4,101.75 147.99,102.16 140.02,102.16 v1(139.31,101.45) ; 160.01,97.31 v2(160.15,97.31) ; U6901.11 56.37,90.1 v1(56.29,90.02)
  L3 w0.152: v1(84.27,101.11) 84.27,100.68 83.79,100.2 81.86,100.2 80.67,99.01 76.54,99.01 68.04,90.51 67.5,90.51 67.44,90.45 59.51,90.45 58.57,89.51 56.79,89.51 v1(56.29,90.02)
  BOTTOM w0.152: IOBD1.16 156.08,90.05 157.84,88.29 157.84,85.12 157.86,85.1 v1(157.89,85.1) ; v1(84.27,101.11) 84.43,101.27 84.43,101.53 84.78,101.88 138.88,101.88 v1(139.31,101.45)
GSENSOR_CS: length 2.3
  TOP w0.102: R6905.2 59.27,90.63 v2(58.52,90.63) 58.32,90.63 57.74,91.22 U6901.2
GSENSOR_SDO: length 3.5
  TOP w0.102: U6901.3 57.86,91.72 58.6,92.46 R6902.2 58.6,93.44 R6903.2 58.64,93.47 58.64,94.17 v2(58.86,94.39)
H_A20GATE: length 5
  TOP w0.102: R2445.2 58.81,21.02 v1(58.7,20.91)
  BOTTOM w0.102: U2401.121 55.5,20.91 55.58,20.99 56.14,20.99 56.56,20.57 57.39,20.57 57.72,20.91 v1(58.7,20.91)
H_PROCHOT#: length 223.5
  TOP w0.102: v1(144.92,30.74) 144.92,32.24 144.88,32.27 v1(144.88,32.41) 143.02,32.41 142.03,31.43 141.37,31.43 140.67,30.73 136.42,30.73 134.73,29.04 110.28,29.04 v2(109.76,29.56) 109.5,29.82 v1(107.57,29.82) ; PR4807.2 30.48,68.37 30.48,66.73 v1(28.97,65.22) ; v1(72.05,27.72) 72.03,27.7 R1809.1
  L3 w0.127: v1(72.05,27.72) 72.42,28.08 75.39,28.08 76.55,29.25 88.71,29.25 89.46,28.5 95.16,28.5 97.62,30.97 106.06,30.97 107.21,29.82 v1(107.57,29.82) ; v1(15.62,64.04) 15.62,64.02 15.98,63.66 16.25,63.39 16.25,60.27 17.25,59.27 17.25,59.27 17.58,58.94 17.58,51.5 18.46,50.61 19.02,50.06 19.02,41.16 19.69,40.48 19.69,38.7 19.17,38.17 19.17,32.55 v1(18.64,32.03)
  L4 w0.127: v1(72.05,27.72) 72.05,28.39 71.87,28.58 63.5,28.58 62.85,27.92 62.81,27.92 62.55,27.66 58.66,27.66 58.04,28.29 51.88,28.29 51.33,28.84 49.01,28.84 48.74,29.11 47.77,29.11 46.96,29.92 46.96,32.83 46.51,33.29 37.96,33.29 36.99,34.25 29.44,34.25 28.51,35.18 25.54,35.18 23.11,32.74 19.35,32.74 v1(18.64,32.03)
  BOTTOM w0.102: PR4466.2 139.5,30.35 140.89,30.35 141.25,30.71 142.27,30.71 142.52,30.46 144.63,30.46 v1(144.92,30.74) ; Q2402.D 71.23,28.54 v1(72.05,27.72) ; v1(15.62,64.04) 15.8,64.21 16.36,64.21 16.76,64.62 17.97,64.62 18.38,64.21 18.38,63.85 18.6,63.62 21.27,63.62 21.55,63.9 23.66,63.9 23.79,63.77 25.35,63.77 25.95,64.37 27.74,64.37 28.59,65.22 v1(28.97,65.22) 28.97,64.92 27.89,63.83 27.89,62.07 PR4640.2 ; PR4426.2 150.13,23.61 151.44,24.92 151.44,27.77 150.75,28.46 149.13,28.46 149.02,28.56 149.02,28.75 148.76,29.01 148.76,29.03 148.29,29.5 147.82,29.5 147.53,29.79 147.53,31.62 146.88,32.27 145.02,32.27 v1(144.88,32.41) 143.18,32.41 142.02,33.58 PR4465.1
H_RCIN#: length 3.5
  BOTTOM w0.102: R2400.2 51.92,21.31 v2(52.83,21.31) 53.31,21.8 53.74,21.8 53.92,21.62 53.92,21.54 54.16,21.31 U2401.122
HALL_KB_DIS#: length 176.3
  TOP w0.102: v1(156.43,78.15) v2(156.43,77.57) ; R2434.2 52.6,16.08 v1(52.16,15.63)
  L3 w0.102: v1(52.16,15.63) 52.29,15.77 54.43,15.77 55.53,14.66 59.26,14.66 59.35,14.76 63.19,14.76 66.22,11.72 68.95,11.72 69.53,12.3 69.92,12.69 72.1,12.69 72.71,12.08 87.84,12.08 87.84,12.08 88.27,12.08 89.45,10.9 91.53,10.9 93.44,12.81 94.86,12.81 98.39,16.34 100.34,16.34 100.64,16.64 102.52,18.52 104.21,18.52 104.49,18.8 104.49,20.4 109.7,25.62 114.44,25.62 116.05,27.22 131.32,27.22 132.59,28.5 138.71,28.5 141.38,31.17 142.01,31.17 143.41,32.57 143.71,32.86 143.71,33.95 144.42,34.67 145.49,34.67 146.33,35.52 146.33,38.69 146.99,39.35 146.99,39.35 147.42,39.78 147.42,41.46 147.42,42.7 147.42,43.65 148.26,44.48 148.26,45.81 148.26,49.33 149.42,50.49 149.42,52.94 149.42,52.94 149.42,53.36 147.43,55.35 146.92,55.86 146.92,64.11 146.49,64.54 146.49,64.54 145.5,65.53 145.5,71.2 149.28,74.97 149.41,74.97 150.99,74.97 152.28,76.26 152.29,76.26 152.67,76.26 153.73,76.26 154.16,76.69 154.16,76.7 155.61,78.15 156.14,78.15 v1(156.43,78.15)
  BOTTOM w0.102: IOBD1.24 154.24,86.05 155.47,84.81 155.47,83.95 155.97,83.45 155.97,81.63 155.91,81.57 155.91,78.96 156.19,78.68 156.19,78.61 156.43,78.37 v1(156.43,78.15) ; v1(52.16,15.63) 52.48,15.95 53.64,15.95 53.91,16.22 53.91,17.19 54.03,17.31 U2401.112
HDA_BITCLK_CODEC: length 107.1
  TOP w0.102: v1(140.35,94.78) 140.35,95.06 140.64,95.35 EC2709.1 140.26,95.86 134.46,95.86 133.87,96.45 132.67,96.45 132.39,96.17 121.84,96.17 121.16,96.85 v2(120.88,96.85) 103.59,96.85 101.29,94.55 100.89,94.55 88.43,94.55 87.81,93.92 85.6,93.92 82.96,91.28 82.96,87.32 82.58,86.94 82.58,85.4 81.04,83.86 79.81,83.86 76.84,80.89 72.98,80.89 72.71,81.16 72.21,81.16 71.71,80.66 71.71,79.81 72.05,79.47 72.05,76.42 73.17,75.3 73.17,73.71 73.78,73.1 73.78,70.66 73.1,69.97 73.1,67.69 70.56,65.15 69.08,65.15 68.3,64.37 68.3,63.81 67,62.51 67,61.55 R1927.1
  BOTTOM w0.102: v1(140.35,94.78) 140.38,94.75 140.38,93.45 140.28,93.35 U2701.6
HDA_BITCLK_CPU: length 3.2
  TOP w0.102: v1(69.76,58.95) 69.76,59.45 v2(69.7,59.51) 69.7,59.57 68.83,60.44 R1927.2
  BOTTOM w0.102: CPU1.AD9 69.95,59.13 v1(69.76,58.95)
HDA_CODEC_RST#_CTRL: length 29
  TOP w0.102: v1(152.48,88.3) v2(152.48,88.87)
  L3 w0.127: v1(146.79,96.82) 146.95,96.97 147.29,96.97 147.96,97.64 148.97,97.64 149.85,98.52 153.75,98.52 154.76,97.51 154.76,93.45 153.64,92.33 153.64,91.75 152.48,90.59 v1(152.48,88.3)
  BOTTOM w0.102: U2901.2 149.73,85.42 C2901.1 149.83,85.37 150.33,84.87 151.36,84.87 152.82,86.34 152.82,87.95 v1(152.48,88.3) ; R2923.1 145.91,96.56 R2918.2 146.67,96.69 v1(146.79,96.82)
HDA_RST#_CODEC: length 104.1
  TOP w0.102: R1928.1 71.27,64.28 74.48,67.48 74.48,68.54 75.87,69.93 75.87,72.93 74.56,74.25 74.56,75.82 73.4,76.98 73.4,79.65 73.86,80.12 77.07,80.12 80.1,83.15 81.33,83.15 83.34,85.16 83.34,86.6 83.67,86.93 83.67,90.98 85.9,93.21 88.1,93.21 88.64,93.75 94.09,93.75 94.52,93.31 99.76,93.31 100.26,93.81 101.56,93.81 103.89,96.14 119.13,96.14 v2(119.66,95.61) 119.89,95.37 128.62,95.37 128.85,95.14 139.04,95.14 140.93,93.25 142.23,93.25 v1(142.66,93.68)
  BOTTOM w0.102: R2923.2 144.99,95.13 143.84,93.99 142.97,93.99 v1(142.66,93.68) 142.66,93.67 142.28,93.3 U2701.11
HDA_RST#_CPU: length 7.1
  TOP w0.102: v2(72.16,57.63) 72.46,57.94 v1(72.46,58.98) 72.46,59.56 72.11,59.91 72.11,60.57 71.81,60.88 71.81,62.04 72.1,62.33 C1910.1 72.09,62.66 R1928.2
  BOTTOM w0.102: v1(72.46,58.98) 72.46,58.3 CPU1.AF13
HDA_SDIN0_CODEC: length 7.5
  TOP w0.102: v1(140.85,97.75) 140.28,97.19 R2718.2 140.04,96.79 v2(139.54,96.29)
  BOTTOM w0.102: v1(140.85,97.75) 140.85,97.26 141.38,96.73 141.38,95.48 141.52,95.35 141.52,94.31 141.25,94.04 141.25,93.52 141.08,93.36 U2701.8
HDA_SDIN0_CPU: length 98.5
  TOP w0.102: v1(82.4,91.19) 82.4,91.4 85.4,94.41 87.61,94.41 88.23,95.03 101.09,95.03 103.42,97.37 133.66,97.37 134.68,96.35 v2(136.62,96.35) 138.32,96.35 R2718.1
  L3 w0.127: v1(69.11,59.53) 69.17,59.59 69.17,60.1 68.77,60.5 68.77,62.54 69.98,63.75 69.98,63.88 73.3,67.2 73.3,72.37 74.04,73.12 74.04,76.54 75.91,78.41 75.91,79.15 80.83,84.07 80.83,89.89 82.13,91.19 v1(82.4,91.19)
  BOTTOM w0.102: CPU1.AD7 69.21,59.63 v1(69.11,59.53)
HDA_SDOUT_CODEC: length 96.8
  TOP w0.102: R1929.1 73.21,63.81 73.21,64.53 74.76,66.08 74.76,68.53 76.07,69.84 76.07,73.05 74.79,74.34 74.79,75.91 73.62,77.08 73.62,79.56 73.94,79.87 77.15,79.87 80.2,82.92 81.43,82.92 83.57,85.06 83.57,86.51 83.9,86.84 83.9,90.89 85.99,92.98 88.2,92.98 88.73,93.52 93.99,93.52 94.43,93.08 99.85,93.08 100.35,93.58 101.65,93.58 103.98,95.91 118.36,95.91 119.13,95.15 126.06,95.15 126.29,94.92 v2(127.13,94.92) 138.07,94.92 EC2708.1 139.14,94.54 139.89,93.79 v1(139.89,93.67)
  BOTTOM w0.102: v1(139.89,93.67) 139.89,93.4 139.88,93.4 U2701.5
HDA_SDOUT_CPU: length 6.6
  TOP w0.102: v2(73.71,62.05) 73.46,62.3 73.46,62.54 73.33,62.66 R1929.2 72.95,61.92 72.59,61.55 72.59,60.8 72.33,60.54 72.33,60.01 72.97,59.36 v1(72.97,58.48)
  BOTTOM w0.102: CPU1.AF14 72.97,57.81 v1(72.97,58.48)
HDA_SPKR: length 100.3
  TOP w0.102: v2(125,89.45) 125,89.53 v1(125.43,89.96)
  L3 w0.127: v1(63.28,55.69) 64.1,55.69 64.81,54.97 66.15,54.97 67.42,53.71 67.9,53.71 68.35,54.16 68.71,54.16 69.2,54.65 69.2,55.93 70.32,57.05 70.32,57.63 69.34,58.61 69.34,59.16 69.53,59.35 69.53,60.06 68.99,60.6 68.99,62.44 70.21,63.66 73.58,67.03 73.58,72.11 74.32,72.85 74.32,76.46 76.16,78.3 76.16,79.04 81.08,83.96 81.08,88.87 83.23,91.02 83.23,91.29 85.55,93.6 90.53,93.6 93.62,90.51 93.62,90.3 93.94,89.99 100.62,89.99 100.97,89.64 102.06,89.64 102.86,88.84 103.23,88.84 103.27,88.88 103.3,88.88 103.97,89.54 108.36,89.54 108.78,89.12 109.18,89.12 110.24,90.17 113.9,90.17 114.27,89.8 117.42,89.8 118.04,89.18 124.65,89.18 v1(125.43,89.96)
  BOTTOM w0.102: v1(63.28,55.69) 63.17,55.57 CPU1.H4 ; RN2701.2 125.86,89.96 v1(125.43,89.96)
HDA_SPKR_R: length 4.2
  BOTTOM w0.254: RN2701.3 126.45,91.66 v2(126.18,91.93) 126.18,92.42 126.63,92.87 D2701.1
HDA_SYNC_CODEC: length 100
  TOP w0.102: v1(142.02,93.68) 140.82,93.68 139.14,95.37 132.4,95.37 132.17,95.6 v2(131.44,95.6) 120.6,95.6 119.83,96.37 103.79,96.37 101.46,94.04 100.16,94.04 99.66,93.54 94.7,93.54 94.26,93.98 88.54,93.98 88.01,93.44 85.8,93.44 83.44,91.08 83.44,87.12 83.06,86.74 83.06,85.2 81.24,83.38 80.01,83.38 76.98,80.35 73.77,80.35 73.17,79.75 73.17,76.89 74.33,75.72 74.33,74.15 74.97,73.51 74.97,69.4 74.26,68.7 74.26,67.57 R1926.1
  BOTTOM w0.102: v1(142.02,93.68) 142.02,93.41 141.88,93.27 U2701.10
HDA_SYNC_CPU: length 5.9
  TOP w0.102: v2(69.51,63.14) 69.8,62.85 R1926.2 70.38,62.8 70.38,61.64 71.01,61.01 71.24,61.01 71.9,60.35 71.9,59.54 v1(71.95,59.49)
  BOTTOM w0.102: v1(71.95,59.49) CPU1.AF12
HDD_FALL_INT_C: length 3.3
  TOP w0.102: TP806.1 59.5,56.64 v1(59.87,57.01)
  BOTTOM w0.102: CPU1.J1 62.36,56.66 60.22,56.66 v1(59.87,57.01)
HDMI_CLK_CON: length 19
  BOTTOM w0.102: HDMI1.15 9.37,80.24 9.44,80.49 9.4,80.72 9.33,80.91 9.35,81.1 9.39,81.24 9.41,81.37 9.79,81.75 10.57,81.75 12.28,80.04 12.28,77.38 13.02,76.64 v2(14.33,76.64) 14.96,76.64 15.04,76.56 RN5701.2 15.8,76.56 16.06,76.3 16.06,75.16 15.76,74.86 15.76,73.15 15.23,72.61 15.23,71.51 Q5703.D
HDMI_CLK_CPU: length 117.3
  TOP w0.102: RN803.1 84.51,40.8 84.51,40.6 84.01,40.1 84.01,39.62 v1(84.3,39.32) ; v2(15.54,70.85) 15.43,70.85 v1(15.08,70.51)
  L3 w0.127: v1(84.3,39.32) 84.3,36.36 82.85,34.91 81.17,33.22 79.46,33.22 79.09,33.59 76.54,33.59 73.39,30.44 70.33,30.44 68.83,28.95 62.55,28.95 60.04,31.45 54.56,31.45 54.35,31.24 51.81,31.24 50.62,32.44 49.88,32.44 49.28,33.03 48.69,33.03 48.56,32.91 28.96,32.91 21.01,40.87 21.01,41.07 19.52,42.55 19.52,50.27 18.67,51.12 18.09,51.71 18.09,59.15 17.46,59.78 16.76,60.48 16.76,63.6 16.53,63.84 16.53,63.95 15.77,64.7 15.49,64.98 15.49,65.8 14.74,66.56 14.74,67.87 15.08,68.21 v1(15.08,70.51)
  BOTTOM w0.102: CPU1.Y51 83.78,42.86 84.2,42.86 84.38,42.68 84.38,42.37 84.9,41.85 84.9,39.81 84.41,39.32 v1(84.3,39.32) ; v1(15.08,70.51) 15,70.43 Q5703.S
HDMI_DATA_CON: length 11.6
  BOTTOM w0.102: HDMI1.16 11.15,80 11.8,79.35 11.8,77.03 12.91,75.91 13.6,75.91 14.1,75.41 v2(14.17,75.41) 14.25,75.41 14.75,75.91 RN5701.1 15.48,75.38 14.96,74.87 Q5705.D
HDMI_DATA_CON_N0: length 11.6
  TOP w0.089: RN5703.2 16.29,78.26 v1(16.34,78.21) 16.55,78 R5714.1 17.8,78 C5703.2
  L4 w0.076: 9.47,76.5 10.46,76.5
  L4 w0.102: v1(16.34,78.21) 15.34,78.21 13.32,76.19 11.33,76.19 11.02,76.5 10.46,76.5 ; HDMI1.9 9.47,76.5
  BOTTOM w0.089: v2(16.88,78.06) 16.48,78.06 v1(16.34,78.21)
HDMI_DATA_CON_N1: length 11.8
  TOP w0.089: C5705.2 17.63,69.87 R5715.1 16.27,69.87 v1(16.16,69.76) 15.91,69.52 RN5702.4
  L4 w0.102: HDMI1.6 10.39,74.59 11.41,74.59 14.11,71.9 14.11,70.6 15.25,69.46 15.85,69.46 v1(16.16,69.76)
HDMI_DATA_CON_N2: length 12.8
  TOP w0.089: RN5702.2 15.92,68.37 v1(16.2,68.09) 16.2,68.09 R5716.1 17.63,68.09 C5707.2
  BOTTOM w0.089: v2(13.69,69.75) 13.57,69.62 ; 13.57,69.62 13.67,69.53 13.67,69.02 13.77,68.92 13.78,68.92 14.66,68.04 15.33,68.04 15.52,67.85 15.96,67.85 v1(16.2,68.09) ; 13.57,69.62 10.8,72.39 9.73,72.39 9.35,72.77 9.35,72.93 HDMI1.3
HDMI_DATA_CON_N3: length 11
  TOP w0.089: C5701.2 17.83,79.77 R5717.1 16.72,79.77 v1(16.37,80.12) 15.66,79.41 RN5703.4
  L4 w0.102: v1(16.37,80.12) 16.12,79.88 15.76,79.88 13.48,77.6 10.38,77.6 HDMI1.12
  BOTTOM w0.089: v1(16.37,80.12) 16.42,80.12 16.79,80.49 v2(16.79,80.49)
HDMI_DATA_CON_P0: length 11.5
  TOP w0.089: C5704.2 17.77,77.11 R5714.2 17.01,77.31 16.79,77.52 16.43,77.52 v1(16.37,77.58) 16.34,77.61 RN5703.1
  L4 w0.076: 9.4,75.5 10.92,75.5
  L4 w0.102: 10.92,75.5 11.4,75.97 13.41,75.97 15.43,77.99 15.91,77.99 16.33,77.58 v1(16.37,77.58) ; HDMI1.7 9.4,75.5
HDMI_DATA_CON_P1: length 11.7
  TOP w0.089: C5706.2 17.63,68.98 R5715.2 16.18,68.98 v1(16.16,69) 16.03,68.87 RN5702.3
  L4 w0.102: HDMI1.4 10.36,74.38 11.32,74.38 13.89,71.81 13.89,70.51 15.16,69.24 15.92,69.24 v1(16.16,69)
HDMI_DATA_CON_P2: length 12.8
  TOP w0.089: RN5702.1 15.88,67.72 v1(16.18,67.42) 16.18,67.11 16.31,66.98 16.64,66.98 R5716.2 17.63,67.2 C5708.2
  BOTTOM w0.089: v2(13.69,68.51) 13.8,68.61 ; 13.8,68.61 14.57,67.84 15.25,67.84 15.44,67.65 15.95,67.65 v1(16.18,67.42) ; 13.8,68.61 13.69,68.72 13.68,68.72 13.46,68.93 13.46,69.44 10.72,72.19 9.65,72.19 9.33,72.5 HDMI1.1
HDMI_DATA_CON_P3: length 11.3
  TOP w0.089: RN5703.3 15.84,78.76 15.97,78.9 15.97,79.07 v1(16.38,79.48) 16.46,79.48 R5717.2 17.85,78.88 C5702.2
  L4 w0.102: HDMI1.10 10.36,77.38 13.57,77.38 15.85,79.66 16.2,79.66 v1(16.38,79.48)
  BOTTOM w0.089: v2(17.02,79.29) 16.83,79.48 v1(16.38,79.48)
HDMI_DATA_CPU: length 115.4
  TOP w0.102: v2(87,40.82) 86.68,41.14 RN803.2 84.63,40.01 v1(84.49,40.01)
  L3 w0.127: v1(15.67,72.36) 15.67,68.04 15.25,67.62 15.25,66.79 16,66.04 16,65.19 16.28,64.91 16.72,64.47 17.27,63.93 17.27,60.69 17.67,60.28 18.6,59.36 18.6,51.92 18.88,51.63 18.89,51.63 20.03,50.48 20.03,42.79 21.52,41.31 21.52,41.08 29.14,33.45 48.39,33.45 48.47,33.54 49.54,33.54 50.14,32.95 50.83,32.95 52.02,31.75 54.14,31.75 54.35,31.96 60.35,31.96 62.85,29.45 68.62,29.45 70.12,30.95 73.18,30.95 76.15,33.92 79.54,33.92 79.73,33.73 80.96,33.73 83.72,36.49 83.72,39.11 83.88,39.28 83.88,39.5 84.4,40.01 v1(84.49,40.01)
  BOTTOM w0.102: CPU1.Y52 84.07,42.27 84.31,42.03 84.31,41.73 84.54,41.5 84.54,41.17 84.49,41.12 v1(84.49,40.01) ; v1(15.67,72.36) 15.78,72.47 Q5705.S
HDMI_DATA_CPU_N0: length 107.1
  TOP w0.089: C5703.1 19.35,77.97 v1(19.36,77.95) 20.07,77.95 v2(20.1,77.98)
  L3 w0.102: v1(19.36,77.95) 19.14,77.73 18.54,77.73 17.82,77.01 17.82,68.07 17.48,67.72 17.48,67 17.23,66.76 17.23,65.65 17.95,64.94 18.32,64.56 18.46,64.42 18.46,63.73 19.53,62.66 19.53,62.65 19.55,62.64 19.55,62.14 20.54,61.15 20.54,58.23 20.25,57.94 20.25,53.5 21.63,52.12 21.63,43.52 22.77,42.38 22.77,41.51 29.63,34.65 47.63,34.65 47.82,34.84 50.33,34.84 51.02,34.15 51.37,34.15 52,33.52 52.67,33.52 52.87,33.72 54.19,33.72 54.72,33.19 61.2,33.19 63.66,30.72 67.73,30.72 69.29,32.29 72.8,32.29 76.31,35.8 78.04,35.8 78.86,36.62 79.26,36.62 v1(79.45,36.43)
  BOTTOM w0.089: v1(79.45,36.43) 79.45,36.8 79.35,36.9 79.35,37.1 78.97,37.48 CPU1.F52
HDMI_DATA_CPU_N1: length 102.7
  TOP w0.089: 20.72,67.65 v2(20.84,67.77) ; 20.72,67.65 19.44,68.94 19.44,69.34 19.2,69.57 18.82,69.57 C5705.1 ; 20.72,67.65 21.34,67.03 21.34,65.12 20.93,64.71 20.74,64.71 20.1,64.07 19.34,64.07 18.64,64.76 v1(18.64,65.38)
  L3 w0.102: v1(79.15,39.78) 79.15,39.47 79.51,39.11 79.51,38.06 77.8,36.35 75.87,36.35 72.53,33.01 69,33.01 67.43,31.43 64.57,31.43 62.1,33.9 55.03,33.9 54.49,34.43 53.22,34.43 52.72,34.94 51.29,34.94 50.68,35.55 48.15,35.55 47.96,35.73 46.35,35.73 45.96,35.35 34.12,35.35 33.13,36.34 28.93,36.34 23.47,41.8 23.47,42.67 22.34,43.8 22.34,48.85 23.17,49.68 23.17,50.78 22.35,51.6 22.35,52.39 20.95,53.79 20.95,57.65 21.29,57.99 21.29,61.47 20.25,62.51 20.25,63.04 19.16,64.13 19.16,64.71 18.95,64.92 18.95,65.08 v1(18.64,65.38)
  BOTTOM w0.089: CPU1.H50 79.09,39.72 v1(79.15,39.78)
HDMI_DATA_CPU_N2: length 97.2
  TOP w0.089: v1(20.65,65.38) 20.65,65.41 20.28,65.78 20.28,66.04 20.1,66.21 20.1,67.2 19.54,67.76 19.47,67.76 ; C5707.1 18.85,67.76 19.47,67.76 ; 19.47,67.76 v2(19.47,67.94)
  L3 w0.102: v1(20.65,65.38) 20.54,65.27 20.54,64.73 21.11,64.16 21.78,64.16 22.45,63.49 22.45,62.09 22.24,61.88 22.24,53.79 23.28,52.75 23.28,52.04 24.08,51.24 24.08,49.29 23.25,48.46 23.25,47.58 23.36,47.48 23.59,47.48 23.81,47.25 23.81,46.8 23.59,46.57 23.36,46.57 23.25,46.47 23.25,45.11 23.36,45.01 23.89,45.01 24.46,44.44 24.46,42.1 29.3,37.26 33.5,37.26 34.48,36.29 38.68,36.29 39.3,36.91 50.65,36.91 51.69,35.87 53.19,35.87 53.7,35.36 54.86,35.36 55.4,34.83 62.31,34.83 62.81,35.33 63.45,35.33 63.66,35.13 63.66,33.64 63.76,33.54 64.04,33.54 64.14,33.64 64.14,35.13 64.34,35.33 64.84,35.33 65.5,35.99 67.39,35.99 69.44,33.94 72.14,33.94 73.96,35.76 74.27,35.76 75.62,37.11 75.72,37.11 75.82,37.21 75.82,37.89 76.05,38.12 76.43,38.12 76.66,37.89 76.66,37.21 76.76,37.11 77.61,37.11 77.71,37.21 77.71,37.6 77.63,37.68 v1(77.29,37.68)
  BOTTOM w0.089: v1(77.29,37.68) 77.51,37.68 77.71,37.47 CPU1.C51
HDMI_DATA_CPU_N3: length 112.6
  TOP w0.089: v2(19.53,80.37) 19.53,79.79 v1(19.42,79.68) 19.38,79.72 C5701.1
  L3 w0.102: v1(19.42,79.68) 19.19,79.45 18.31,79.45 17.12,78.26 17.12,68.67 16.78,68.33 16.78,67.29 16.54,67.05 16.54,65.54 16.54,65.36 16.78,65.12 17.76,64.13 17.76,60.89 19.09,59.57 19.09,52.12 20.53,50.68 20.53,43.63 22.05,42.12 22.05,41.25 29.34,33.95 47.94,33.95 48.13,34.14 49.91,34.14 50.61,33.44 51.09,33.44 51.71,32.82 52.99,32.82 53.18,33.01 53.86,33.01 54.38,32.49 60.71,32.49 63.25,29.95 68.2,29.95 69.7,31.45 72.97,31.45 76.8,35.27 77.46,35.27 77.57,35.16 v1(77.57,34.86)
  BOTTOM w0.089: CPU1.G52 79.4,38.01 79.86,37.55 80.14,37.55 80.49,37.19 80.49,36.84 78.95,35.29 78.34,35.29 77.91,34.86 v1(77.57,34.86)
HDMI_DATA_CPU_P0: length 106.6
  TOP w0.089: C5704.1 19.24,77.16 v1(19.37,77.29) 19.41,77.29 19.88,76.82 v2(19.88,76.78)
  L3 w0.102: v1(19.37,77.29) 19.15,77.51 18.63,77.51 18.04,76.92 18.04,67.98 17.69,67.63 17.69,66.91 17.45,66.67 17.45,65.74 18.16,65.03 18.16,65.03 18.48,64.71 18.68,64.51 18.68,63.82 19.75,62.75 19.75,62.74 19.77,62.73 19.77,62.23 20.75,61.24 20.75,58.14 20.46,57.85 20.46,53.59 21.84,52.21 21.84,43.61 22.99,42.47 22.99,41.6 29.72,34.86 47.54,34.86 47.73,35.05 50.42,35.05 51.1,34.37 51.46,34.37 52.09,33.73 52.58,33.73 52.78,33.94 54.28,33.94 54.81,33.4 61.29,33.4 63.75,30.94 67.64,30.94 69.2,32.5 72.71,32.5 76.22,36.01 77.95,36.01 78.77,36.83 79.76,36.83 v1(79.99,37.07)
  BOTTOM w0.089: v1(79.99,37.07) 79.99,36.94 79.93,36.88 79.65,36.88 79.55,36.98 79.55,37.18 79.49,37.24 CPU1.F53
HDMI_DATA_CPU_P1: length 102.8
  TOP w0.089: 19.05,64.64 19.42,64.27 20.01,64.27 20.65,64.91 20.85,64.91 21.14,65.21 21.14,66.95 19.24,68.85 19.24,69.25 19.12,69.37 18.9,69.37 C5706.1 ; 19.05,64.64 18.85,64.85 18.85,64.98 19.25,65.38 v1(19.3,65.38) ; 19.05,64.64 v2(19.18,64.77)
  L3 w0.102: v1(19.3,65.38) 19.16,65.24 19.16,65.01 19.24,64.93 19.38,64.8 19.38,64.22 20.46,63.13 20.46,62.6 21.5,61.56 21.5,57.9 21.16,57.56 21.16,53.88 22.56,52.48 22.56,51.69 23.38,50.87 23.38,49.59 22.56,48.76 22.56,43.89 23.69,42.76 23.69,41.89 29.02,36.55 33.22,36.55 34.21,35.56 45.87,35.56 46.26,35.95 48.05,35.95 48.24,35.76 50.77,35.76 51.38,35.16 52.81,35.16 53.31,34.65 54.58,34.65 55.12,34.11 62.19,34.11 64.66,31.65 67.34,31.65 68.91,33.22 72.44,33.22 75.78,36.57 77.71,36.57 79.3,38.15 79.3,39.02 78.64,39.68 78.38,39.68 78.26,39.55 78.26,39.34 v1(78.47,39.13)
  BOTTOM w0.089: CPU1.H49 78.28,39.74 78.16,39.61 78.16,39.25 78.28,39.13 v1(78.47,39.13)
HDMI_DATA_CPU_P2: length 97.1
  TOP w0.089: C5708.1 18.87,67.56 19.46,67.56 19.9,67.12 19.9,66.55 ; v2(19.74,66.55) 19.9,66.55 ; 19.9,66.55 19.9,66.12 20.07,65.95 20.07,65.46 v1(19.97,65.36)
  L3 w0.102: v1(19.97,65.36) 20.32,65 20.32,64.64 21.02,63.95 21.69,63.95 22.23,63.4 22.23,62.18 22.03,61.97 22.03,53.7 23.07,52.66 23.07,51.95 23.86,51.15 23.86,49.38 23.04,48.55 23.04,47.49 23.27,47.27 23.5,47.27 23.6,47.17 23.6,46.89 23.5,46.78 23.27,46.78 23.04,46.56 23.04,45.02 23.27,44.8 23.8,44.8 24.24,44.35 24.24,42.01 29.21,37.05 33.41,37.05 34.39,36.07 38.77,36.07 39.39,36.69 50.56,36.69 51.6,35.65 53.1,35.65 53.61,35.14 54.77,35.14 55.31,34.61 62.4,34.61 62.9,35.12 63.36,35.12 63.44,35.04 63.44,33.55 63.67,33.32 64.13,33.32 64.35,33.55 64.35,35.04 64.43,35.12 64.93,35.12 65.59,35.78 67.3,35.78 69.35,33.72 72.22,33.72 74.05,35.55 74.35,35.55 75.7,36.9 75.81,36.9 76.03,37.12 76.03,37.8 76.14,37.9 76.34,37.9 76.44,37.8 76.44,37.12 76.67,36.9 77.7,36.9 77.93,37.12 77.93,37.49 v1(78.12,37.68)
  BOTTOM w0.089: CPU1.D50 78.02,37.68 v1(78.12,37.68)
HDMI_DATA_CPU_P3: length 111.8
  TOP w0.089: C5702.1 19.41,78.91 v1(19.42,78.92)
  L3 w0.102: v1(19.42,78.92) 19.1,79.24 18.4,79.24 17.34,78.17 17.34,68.58 16.99,68.24 16.99,67.2 16.75,66.96 16.75,65.45 16.99,65.21 16.99,65.21 17.91,64.29 17.98,64.22 17.98,60.98 19.31,59.66 19.31,52.21 20.74,50.77 20.74,43.72 22.26,42.21 22.26,41.34 29.43,34.16 47.85,34.16 48.04,34.36 50,34.36 50.7,33.66 51.18,33.66 51.8,33.03 52.9,33.03 53.09,33.22 53.95,33.22 54.47,32.7 60.8,32.7 63.34,30.16 68.11,30.16 69.61,31.66 72.88,31.66 76.71,35.49 77.55,35.49 78.08,34.95 v1(78.08,34.34)
  BOTTOM w0.089: CPU1.G53 80.06,37.92 80.7,37.28 80.7,36.75 79.03,35.09 78.42,35.09 78.08,34.75 v1(78.08,34.34)
HDMI_HPD_G: length 30.9
  TOP w0.102: R5702.2 17.52,83.39 17.69,83.56 v2(17.69,83.92) 17.69,84.24 17.48,84.45 v1(16.83,84.45)
  L3 w0.127: v1(16.83,84.45) 16.08,84.45 14.34,82.71 14.34,79.31 12.86,77.84 12.86,69.03 12.1,68.26 12.1,67.6 v1(12.01,67.51)
  BOTTOM w0.102: Q5707.G 18.79,64.37 18.31,64.85 16.54,64.85 16.27,64.58 15.04,64.58 14.61,65.01 14.61,65.19 14.18,65.61 Q5701.5 13.26,65.61 12.83,66.04 12.83,66.7 v1(12.01,67.51)
HDMI_IN#: length 92.5
  TOP w0.102: v1(18.53,62.77) 18.91,63.14 RN5704.2
  L3 w0.102: v1(50.57,22.66) 50.34,22.43 50.34,20.7 50.42,20.63 50.42,20.27 50.34,20.19 50.34,19.61 50.09,19.36 45.21,19.36 45.18,19.38 43.94,19.38 42.82,18.26 42.82,17.42 41.84,16.44 39.45,16.44 38.46,15.45 38.46,15.27 37.49,14.3 33.95,14.3 33.41,13.76 24.33,13.76 22.06,16.02 22.06,26.28 20.35,28 20.35,33.07 20.67,33.39 20.67,34.16 21.14,34.64 21.14,36.96 v1(21.23,37.05)
  L4 w0.102: v1(21.23,37.05) 21.13,37.15 21.13,40.93 19.96,42.1 19.96,51.29 18.53,52.73 18.53,58.65 18.53,59.45 17.82,60.17 17.82,62.27 18.31,62.77 v1(18.53,62.77)
  BOTTOM w0.102: v1(18.53,62.77) 19.43,62.77 19.73,62.47 Q5707.D ; v2(21.23,36.48) 21.23,36.48 v1(21.23,37.05) ; v1(50.57,22.66) 50.71,22.52 51.58,22.52 51.95,22.15 53.68,22.15 53.72,22.11 U2401.124
HDMI_PCH_DET#: length 139.5
  L3 w0.127: v1(84.13,41.33) 84.91,40.55 84.91,35.12 82.21,32.41 80.08,32.41 79.32,31.66 78.24,31.66 75.19,28.6 71.19,28.6 70,27.41 65.37,27.41 64.7,26.75 64.7,26.68 63.97,25.94 59.81,25.94 59.81,25.94 59.15,25.94 59,26.1 57.89,26.1 57.7,26.29 54.6,26.29 54,25.69 51.92,25.69 51.64,25.41 51.06,25.41 50.53,25.95 49.8,25.95 49.41,26.34 47.91,26.34 47.47,26.78 41.26,26.78 39.98,25.51 37.39,25.51 36.84,24.96 30.73,24.96 29.56,23.79 23.85,23.79 23.02,24.62 23.02,32.15 21.95,33.22 v1(21.95,33.85)
  L4 w0.127: v1(21.95,33.85) 21.75,33.65 16.85,33.65 15.69,34.81 15.69,36.07 15.8,36.17 15.8,38.47 15.69,38.58 15.69,43.66 16.62,44.6 16.62,47.48 15.85,48.25 15.85,48.84 15.85,48.84 15.85,58.35 15.11,59.09 15.11,62.14 11.12,66.12 v1(8.91,66.12)
  BOTTOM w0.102: v1(21.95,33.85) v2(21.33,33.85) ; Q5701.3 15.23,64.96 14.88,65.31 14.88,66.98 14.5,67.36 12.85,67.36 12.27,67.95 11.84,67.95 11.43,67.54 11.43,67.47 10.06,66.09 9.77,66.09 R5705.2 v1(8.91,66.12) ; v1(84.13,41.33) 84.13,41.37 83.68,41.82 83.68,42.06 83.48,42.27 CPU1.W51
HDMI_PLL_GND: length 0.9
  BOTTOM w0.406: Q5701.6 13.74,66.47 v1(14.2,66.93)
  vias: v2(14.78,76.44)
HPD_HDMI_CON: length 8.6
  TOP w0.102: R5702.1 R5703.2 15.07,82.5 TP5401.1 10,82.72 HDMI1.19
ICLKICOMP: length 3.2
  TOP w0.102: R1601.2 70.6,49.89 70.66,49.95 v2(70.66,50.34) 70.66,50.88 v1(71.02,51.23)
  BOTTOM w0.102: v1(71.02,51.23) 71.02,51.71 CPU1.P20
ICLKRCOMP: length 3.4
  TOP w0.102: R1636.2 70.02,48.75 69.84,48.94 v2(69.84,49.35) 69.93,49.44 69.93,49.99 v1(70.09,50.14)
  BOTTOM w0.102: v1(70.09,50.14) 70.09,50.45 70.41,50.77 CPU1.N20
IMVP_PWRGD: length 117.9
  TOP w0.102: v1(31.18,61.41) 31.18,61.07 31.36,60.89 EC2401.1 31.94,60.87 PC4618.1 33.62,60.87 PR4649.2 ; v1(47.96,28.27) 47.53,27.85 47.53,27.27 47.54,27.26 47.54,26.76 47.55,26.76 47.55,25.04 47.6,24.99 47.6,22.89 47.53,22.82 47.53,20.49 46.28,19.24 44.61,19.24 43.55,18.18 40.76,18.18 39.95,17.38 39.95,16.69 39.82,16.55 38.94,16.55 v1(38.58,16.2) ; v1(60.81,26.95) 61.14,26.62 R2439.1
  L3 w0.102: v1(28.89,47.94) 28.89,49.14 27.43,50.6 27.43,54.69 26.31,55.81 26.31,59.09 28.63,61.41 31.18,61.41 v1(31.18,61.41) ; v1(38.58,16.2) 38.58,15.9 38.23,15.55 38.23,15.37 37.39,14.53 33.86,14.53 33.31,13.98 24.42,13.98 22.29,16.12 22.29,26.38 20.58,28.09 20.58,32.98 20.89,33.29 20.89,34.06 21.37,34.54 21.37,36.55 21.66,36.84 21.66,37.23 21.24,37.66 21.24,38.6 v1(21.56,38.93) ; v1(47.96,28.27) 49.18,28.27 50.04,27.42 50.04,27.33 50.29,27.08 53.42,27.08 54.02,27.67 59.36,27.67 60.08,26.95 v1(60.81,26.95)
  BOTTOM w0.102: v1(31.18,61.41) 31.18,61.41 31.18,60.57 30.31,59.7 29.42,59.7 29.17,59.45 PU4601.6 ; v1(28.89,47.94) 29.04,47.94 30.16,46.82 30.16,46.46 29.9,46.2 29.9,41.12 28.27,39.49 v2(27.41,39.49) 22.13,39.49 v1(21.56,38.93)
INT_SERIRQ: length 14.6
  BOTTOM w0.102: U2404.4 51.15,29.78 50.71,30.22 R2420.2 50.04,29.77 50.04,27.27 50,27.23 50,25.92 50.14,25.78 50.14,25.09 50.43,24.8 R2435.1 50.58,24.42 C2401.1 50.58,23.31 51.14,22.75 51.69,22.75 51.93,22.51 v2(52.5,22.51) 52.87,22.51 52.98,22.61 52.98,23.02 53.08,23.12 53.36,23.12 53.46,23.02 53.46,22.61 53.56,22.51 U2401.125
INT_SERIRQ_OE: length 4.4
  BOTTOM w0.102: v2(52.91,30.56) R2419.1 52.43,31.5 52.12,31.19 52.12,30.87 R2421.2 51.62,29.76 51.8,29.58 U2404.5
INT_TP#: length 76.2
  TOP w0.102: v1(50.46,10.27) 50.26,10.47 50.26,12.25 51.36,13.35 51.36,15.06 51.7,15.4 51.7,20.98 52.42,21.7 52.42,25.35 52.65,25.58 52.65,29.7 52.83,29.89 52.83,30.4 51.65,31.59 51.65,35.2 50.63,36.22 50.63,39.16 48.98,40.82 48.98,43.71 v2(45.09,47.6) 44.74,47.95 44.74,50.15 45.63,51.03 v1(45.63,51.59)
  BOTTOM w0.102: CPU1.J3 62.75,56.34 62.75,56.74 62.55,56.94 61.05,56.94 60.05,57.94 58.29,57.94 57.63,57.28 52.84,57.28 52.68,57.12 51.59,57.12 49.23,54.76 49,54.76 47.45,53.22 47.45,52.68 46.31,51.54 45.67,51.54 v1(45.63,51.59) ; v1(50.46,10.27) 49.67,10.27 49.36,9.96 49.36,9.12 49.5,8.98 49.5,8.16 49.5,8.16 49.5,7.87 49,7.37 48.16,7.37 47.9,7.63 Q6502.D 45.7,7.63 R6510.2 44.61,7.36 R6511.2
INT_TP#_CONN: length 20.5
  TOP w0.102: v1(41.74,6.9) 41.53,7.1 40.69,7.1 40.68,7.12 40.67,7.12 40.55,7.24 39.28,7.24 39.05,7.01 38.02,7.01 v2(37.18,7.85) 36.58,8.44 R6512.2 36.58,9.62 v1(36.55,9.65)
  BOTTOM w0.102: v1(36.55,9.65) 36.92,10.03 36.92,11.37 34.5,13.79 TPAD1.5 ; Q6502.S 48.47,6.93 47.37,6.93 46.91,6.47 R6510.1 42.16,6.47 v1(41.74,6.9)
JACK_PLUG: length 11.1
  TOP w0.254: v2(145.52,93.76) 145.86,94.1 R2905.1 146.49,94.11 R2914.1 147.59,95.91 148.29,96.6 v1(148.29,96.64)
  BOTTOM w0.254: IOBD1.2 152.42,97.05 151.91,96.54 C2902.2 150.54,97.01 148.66,97.01 v1(148.29,96.64) 148.04,96.64 Q2901.G
JDREF:
  vias: v2(144.91,91.92)
KB_LOOP: length 2.9
  TOP w0.102: v1(102.04,14.41) 102.03,14.4 R6515.2 v2(101.28,15.41)
  BOTTOM w0.102: KB1.1 102.5,14.87 v1(102.04,14.41)
KBC_BEEP: length 155.8
  TOP w0.102: v1(125.6,89.34) 125.6,88.12 129.01,84.71 129.01,84.33 130.31,83.02 131.51,83.02 131.77,82.77 131.77,82.42 132.76,81.43 133.8,81.43 134.4,80.82 134.4,77.54 v2(135.19,76.75) 137.14,74.81 137.14,64.65 140.54,61.24 140.54,60.08 141.41,59.22 141.41,53.66 139.52,51.77 139.52,42.46 136.74,39.69 136.74,35.41 133.48,32.15 106.9,32.15 100.16,25.41 v1(99.38,25.41)
  L3 w0.102: v1(99.38,25.41) 99.38,24.01 98.11,22.73 98.11,22.72 94.2,18.82 86.85,18.82 84.88,16.85 82.96,16.85 81.46,18.35 80.03,18.35 79.65,17.97 76.92,17.97 76.07,18.82 72.3,18.82 70.63,20.49 65.41,20.49 v1(64.74,19.83)
  BOTTOM w0.102: v1(125.6,89.34) 126.22,88.72 126.81,88.72 127.1,89.01 RN2701.1 ; v1(64.74,19.83) 64.9,19.83 68.15,23.07 68.15,23.43 68.57,23.85 68.57,24.15 68.78,24.37 U2401.32
KBC_BEEP_R: length 6.5
  BOTTOM w0.254: RN2701.4 127.1,90.87 128.25,92.01 128.25,94.15 D2701.2 129.33,94.49 v2(130.18,95.34)
KBC_ON#_GATE: length 9.8
  TOP w0.102: C2442.1 58.18,2.63 58.65,2.16 v1(60.86,2.16) 60.86,2.26 61.81,3.21 R2492.2
  BOTTOM w0.102: Q2403.G 62.2,2.41 61.94,2.16 v1(60.86,2.16) 60.76,2.16 60.48,1.88 59.41,1.88 v2(59.39,1.91) 58.9,1.91 58.62,2.19 Q2404.G
KBC_ON#_GATE_L: length 3.5
  TOP w0.102: R2493.2 63.4,4.44 62.83,3.87 62.83,3.83 62.76,3.76 62.76,3.33 R2492.1 62.76,3.22 62.76,2.52 R2491.1 62.76,2.41 62.76,1.98 62.36,1.58 v2(62.36,1.55)
KBC_PECI: length 2.5
  BOTTOM w0.102: TP2407.1 61.25,27.37 61.25,26.43 61.18,26.36 U2401.13
KBC_PWRBTN#: length 191.4
  TOP w0.102: v1(157.1,77.22) 157.1,76.79 v2(157.24,76.65)
  L3 w0.102: v1(157.1,77.22) 155.23,75.35 153.29,75.35 153.29,75.35 152.67,75.35 152.66,75.35 151.37,74.06 149.79,74.06 146.55,70.82 146.42,70.69 146.42,65.91 146.87,65.46 147.84,64.49 147.84,64.49 147.84,56.23 149.44,54.63 150.33,53.74 150.33,52.56 150.33,50.12 150.13,49.91 150.13,46.96 149.94,46.77 149.17,46 149.17,44.1 148.64,43.57 148.34,43.27 148.34,43.08 148.34,42.05 148.34,41.27 148.34,41.08 148.34,41.08 148.34,39.4 147.25,38.31 147.25,37.93 147.25,35.52 147.25,35.52 147.25,35.14 146.4,34.29 145.87,33.76 145.86,33.76 145.37,33.26 145.37,30.55 144.74,29.92 144.74,28.97 145.81,27.9 146.89,27.9 148.66,26.13 148.66,25.55 149.06,25.16 149.06,21.8 148.13,20.87 148.13,16.91 140.77,9.55 139.75,9.55 135.65,5.45 131.87,5.45 130.5,6.83 119.85,6.83 114.28,12.4 110.19,12.4 109.43,13.15 108.71,13.15 108.37,12.81 104.93,12.81 104.72,13.02 104.72,13.02 103.96,13.02 103.74,13.24 100.78,13.24 98.91,11.37 94.32,11.37 93.94,11.37 93.9,11.33 92.1,9.53 88.88,9.53 88.62,9.78 84.62,9.78 84.35,10.05 84.35,10.05 84.29,10.11 75.29,10.11 74.58,9.4 73.66,9.4 73.35,9.7 65.07,9.7 65.04,9.67 57.93,9.67 56.8,8.54 56.8,7.85 55.95,7 v1(55.95,5.79)
  BOTTOM w0.102: R2488.1 55.95,6.41 v1(55.95,5.79) ; IOBD1.25 154.41,85.55 155.19,84.77 155.19,83.87 155.74,83.33 155.74,81.72 155.69,81.67 155.69,78.86 155.97,78.58 155.97,78.51 155.99,78.49 155.99,77.76 156.27,77.48 156.84,77.48 v1(157.1,77.22)
KBC_VBKUP: length 3.2
  BOTTOM w0.203: U2401.114 53.95,18.11 53.7,17.86 53.37,17.86
  BOTTOM w0.254: R2425.1 51.85,17.86 v2(52.75,17.86) 53.37,17.86
KBC_VCC: length 53.9
  TOP w0.356: v1(71.73,17.86) 71.01,17.86 v2(70.98,17.88)
  TOP w0.508: C2430.1 63.16,24.04 63.16,24.04 v1(63.32,23.89) ; C2429.1 64.83,7.81 C2441.1 64.72,7.81 v1(64.08,8.45) 64.08,8.45 63.63,8.91 63.63,9.6 62.93,10.3 61.88,10.3 61.06,11.12 61.06,12.46 59.63,13.89 58.68,13.89 57.82,14.75 56.69,14.75 56.52,14.92 56.18,14.92 55.93,15.17 55.93,15.17 v2(55.63,15.47) 55.18,15.92 55.18,17.13 53.8,18.51 v1(53.54,18.51)
  L3 w0.508: v1(53.54,18.51) 55.63,18.51 56.48,17.66 57.83,17.66 57.83,17.66 58.96,17.66 59.89,16.74 61.1,16.74 61.88,17.51 61.88,18.04 61.98,18.14 61.98,18.31 62.32,18.65 62.35,18.65 v1(62.6,18.9) 62.6,18.9 62.63,18.93 63.05,18.93 63.96,18.02 65.87,18.02 66.23,17.65 68.4,17.65 68.79,18.04 71.55,18.04 v1(71.73,17.86)
  BOTTOM w0.203: v1(53.54,18.51) 53.55,18.51 U2401.115 ; v1(64.08,8.45) 64.38,8.75 U2401.76 ; U2401.19 63.58,24.04 63.43,23.89 v1(63.32,23.89)
  BOTTOM w0.508: v1(62.6,18.9) 62.6,19.91 63.32,20.62 v1(63.32,23.89) ; C2431.1 51.28,19.66 51.81,19.12 R2408.1 52.52,18.51 v1(53.54,18.51)
KBC_VCORF: length 3.5
  BOTTOM w0.203: U2401.44 71.25,19.31 71.63,19.69
  BOTTOM w0.508: C2443.1 72.57,20.22 v2(72.47,20.12) 72.21,19.86 71.81,19.86 71.63,19.69
KCOL0: length 22
  TOP w0.127: v1(87.5,17.87) 86.98,17.35 83.79,17.35 83.34,16.89 80.17,16.89 79.84,17.22 77.15,17.22 76.27,16.34 72.84,16.34 v1(72.66,16.16)
  BOTTOM w0.127: U2401.53 72.21,15.71 v1(72.66,16.16) ; KB1.18 88.9,16.67 88.37,17.2 AFTP6217.1 v1(87.5,17.87)
KCOL1: length 23.7
  TOP w0.127: v1(71.69,16.18) 71.69,16.15 72.37,15.46 73.29,15.46 73.66,15.83 76.83,15.83 77.72,16.72 79.56,16.72 79.89,16.39 83.55,16.39 84,16.84 88.42,16.84 v1(89.42,17.84)
  BOTTOM w0.127: KB1.16 90.5,16.09 AFTP6215.1 v1(89.42,17.84) ; U2401.52 71.62,16.11 v1(71.69,16.18)
KCOL2: length 38.5
  TOP w0.127: v1(86.78,17.81) 86.52,18.07 83.94,18.07 83.66,17.8 82.83,17.8 82.47,18.16 77.97,18.16 77.8,17.99 76.84,17.99 75.97,17.12 72.46,17.12 72.19,17.39 71.19,17.39 70.9,17.1 70,17.1 69.78,16.89 68.98,16.89 68.34,17.53 66.58,17.53 66.06,18.05 64.87,18.05 64.35,17.54 v1(64.35,16.87)
  BOTTOM w0.127: v1(86.78,17.81) 87.84,18.87 AFTP6216.1 88.47,18.55 88.3,18.38 88.3,17.67 89.7,16.27 KB1.17 ; v1(64.35,16.87) 64.35,16.79 65.97,15.18 66.45,15.18 66.69,15.42 67.97,15.42 69.06,16.51 U2401.51
KCOL3: length 31.9
  TOP w0.127: v1(68.14,16.27) 68.28,16.12 70.1,16.12 70.31,16.34 71.22,16.34 71.51,16.62 71.87,16.62 72.13,16.36 72.13,16.06 72.48,15.72 73.18,15.72 73.55,16.08 76.37,16.08 77.26,16.97 79.74,16.97 80.07,16.64 83.44,16.64 83.89,17.09 87.98,17.09 v1(88.75,17.86)
  BOTTOM w0.127: v1(88.75,17.86) 89.72,18.83 AFTP6214.1 90.39,17.81 89.9,17.32 89.9,17.07 90.27,16.7 91.04,16.7 91.3,16.44 KB1.15 ; U2401.50 68.77,16.91 v1(68.14,16.27)
KCOL4: length 32.3
  TOP w0.127: v1(92.5,17.89) 92.31,17.89 91.59,18.61 86.74,18.61 86.46,18.33 83.83,18.33 83.59,18.09 83.01,18.09 82.69,18.42 77.87,18.42 77.69,18.24 76.73,18.24 76.04,17.54 76.01,17.54 76,17.53 75.52,17.53 74.55,18.5 71.04,18.5 69.92,17.38 v1(69.13,17.38)
  BOTTOM w0.127: v1(92.5,17.89) 93.44,18.83 AFTP6210.1 94.26,17.93 94.5,17.69 KB1.11 ; v1(69.13,17.38) 69.2,17.31 U2401.49
KCOL5: length 38.6
  TOP w0.127: v1(66.24,15.62) 66.52,15.62 67.1,15.04 71.12,15.04 71.71,14.45 73.71,14.45 74.08,14.81 78.52,14.81 79.07,15.36 83.96,15.36 84.42,15.82 91.98,15.82 93.93,17.77 v1(95.2,17.77)
  BOTTOM w0.127: v1(66.24,15.62) 66.46,15.85 67.38,15.85 67.67,16.13 67.67,16.55 68.94,17.83 69.31,17.83 69.43,17.71 U2401.48 ; v1(95.2,17.77) AFTP6209.1 95.3,17.07 KB1.10
KCOL6: length 35.5
  TOP w0.127: v1(91.03,17.74) 89.96,17.74 88.81,16.58 84.1,16.58 83.64,16.12 78.66,16.12 78.12,15.58 73.76,15.58 73.39,15.21 72.03,15.21 71.44,15.8 67.93,15.8 67.42,16.31 v1(67.21,16.31)
  BOTTOM w0.127: v1(67.21,16.31) 67.21,16.48 68.84,18.11 U2401.47 ; KB1.13 92.9,16.56 91.93,17.53 91.93,18.24 92.33,18.64 AFTP6212.1 91.54,18.83 91.03,18.31 v1(91.03,17.74)
KCOL7: length 40.1
  TOP w0.127: v1(93.27,17.76) 91.58,16.08 84.32,16.08 83.86,15.62 78.87,15.62 78.33,15.07 73.97,15.07 73.61,14.7 71.82,14.7 71.23,15.3 67.2,15.3 66.2,16.29 65.48,16.29 v1(65.11,16.66)
  BOTTOM w0.127: v1(65.11,16.66) 65.48,16.29 66.05,16.29 67.13,17.38 67.75,17.38 68.39,18.02 68.39,18.82 69.28,19.71 U2401.43 ; v1(93.27,17.76) AFTP6211.1 93.7,16.74 KB1.12
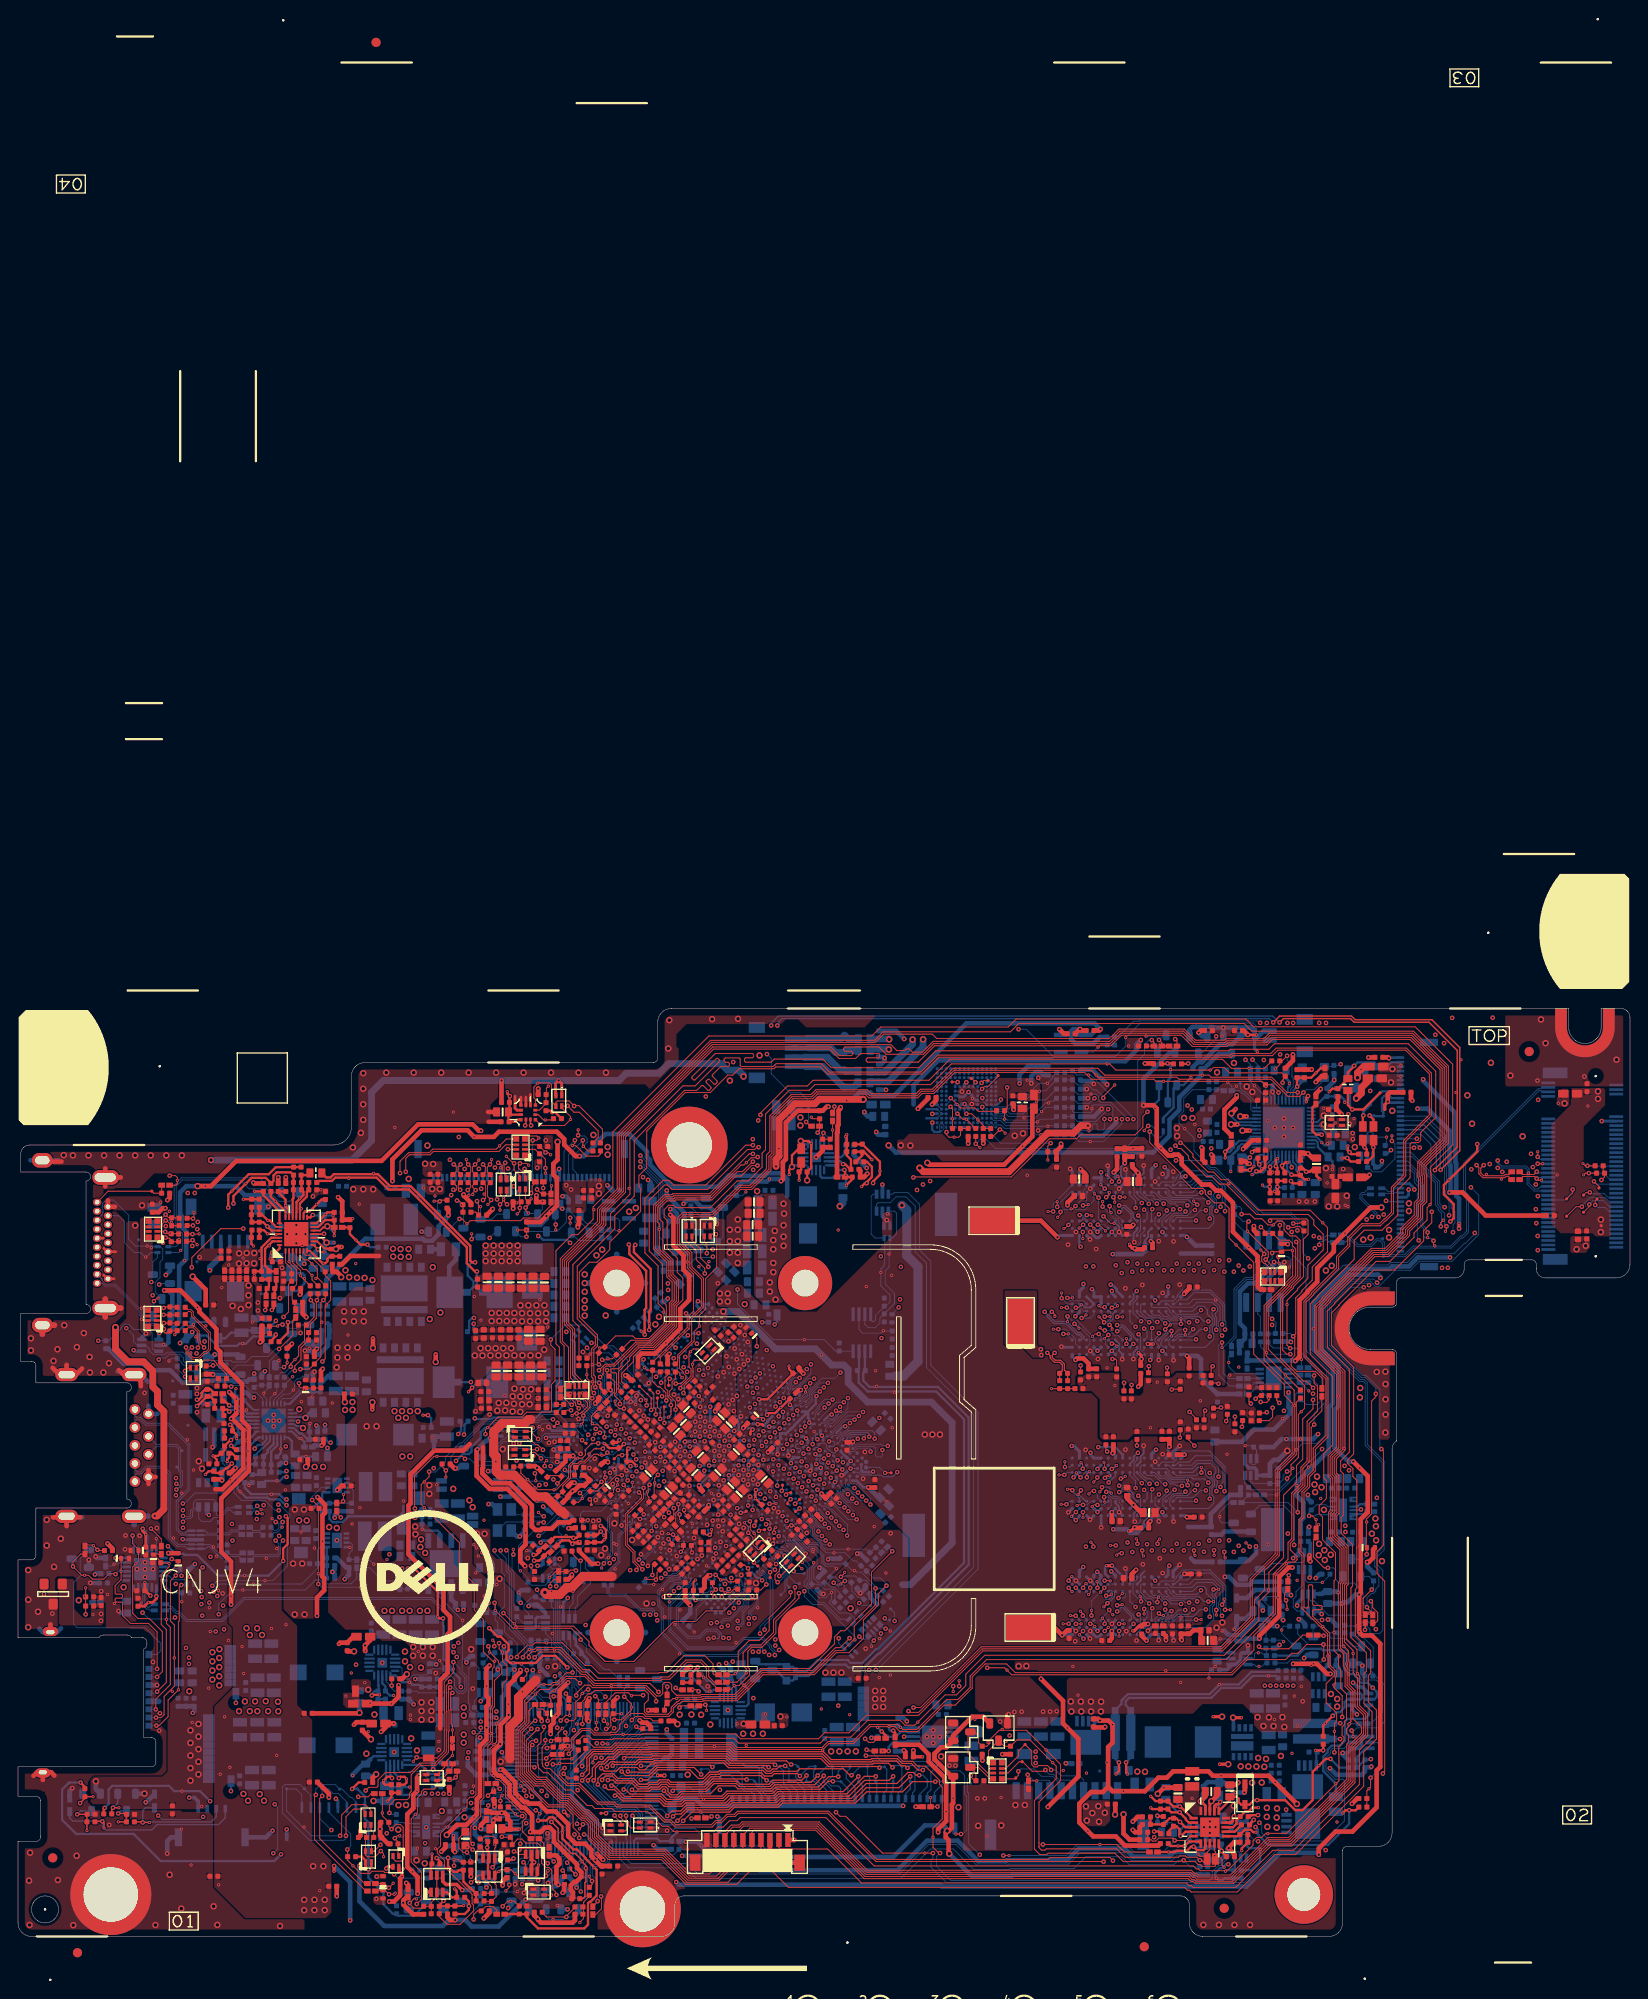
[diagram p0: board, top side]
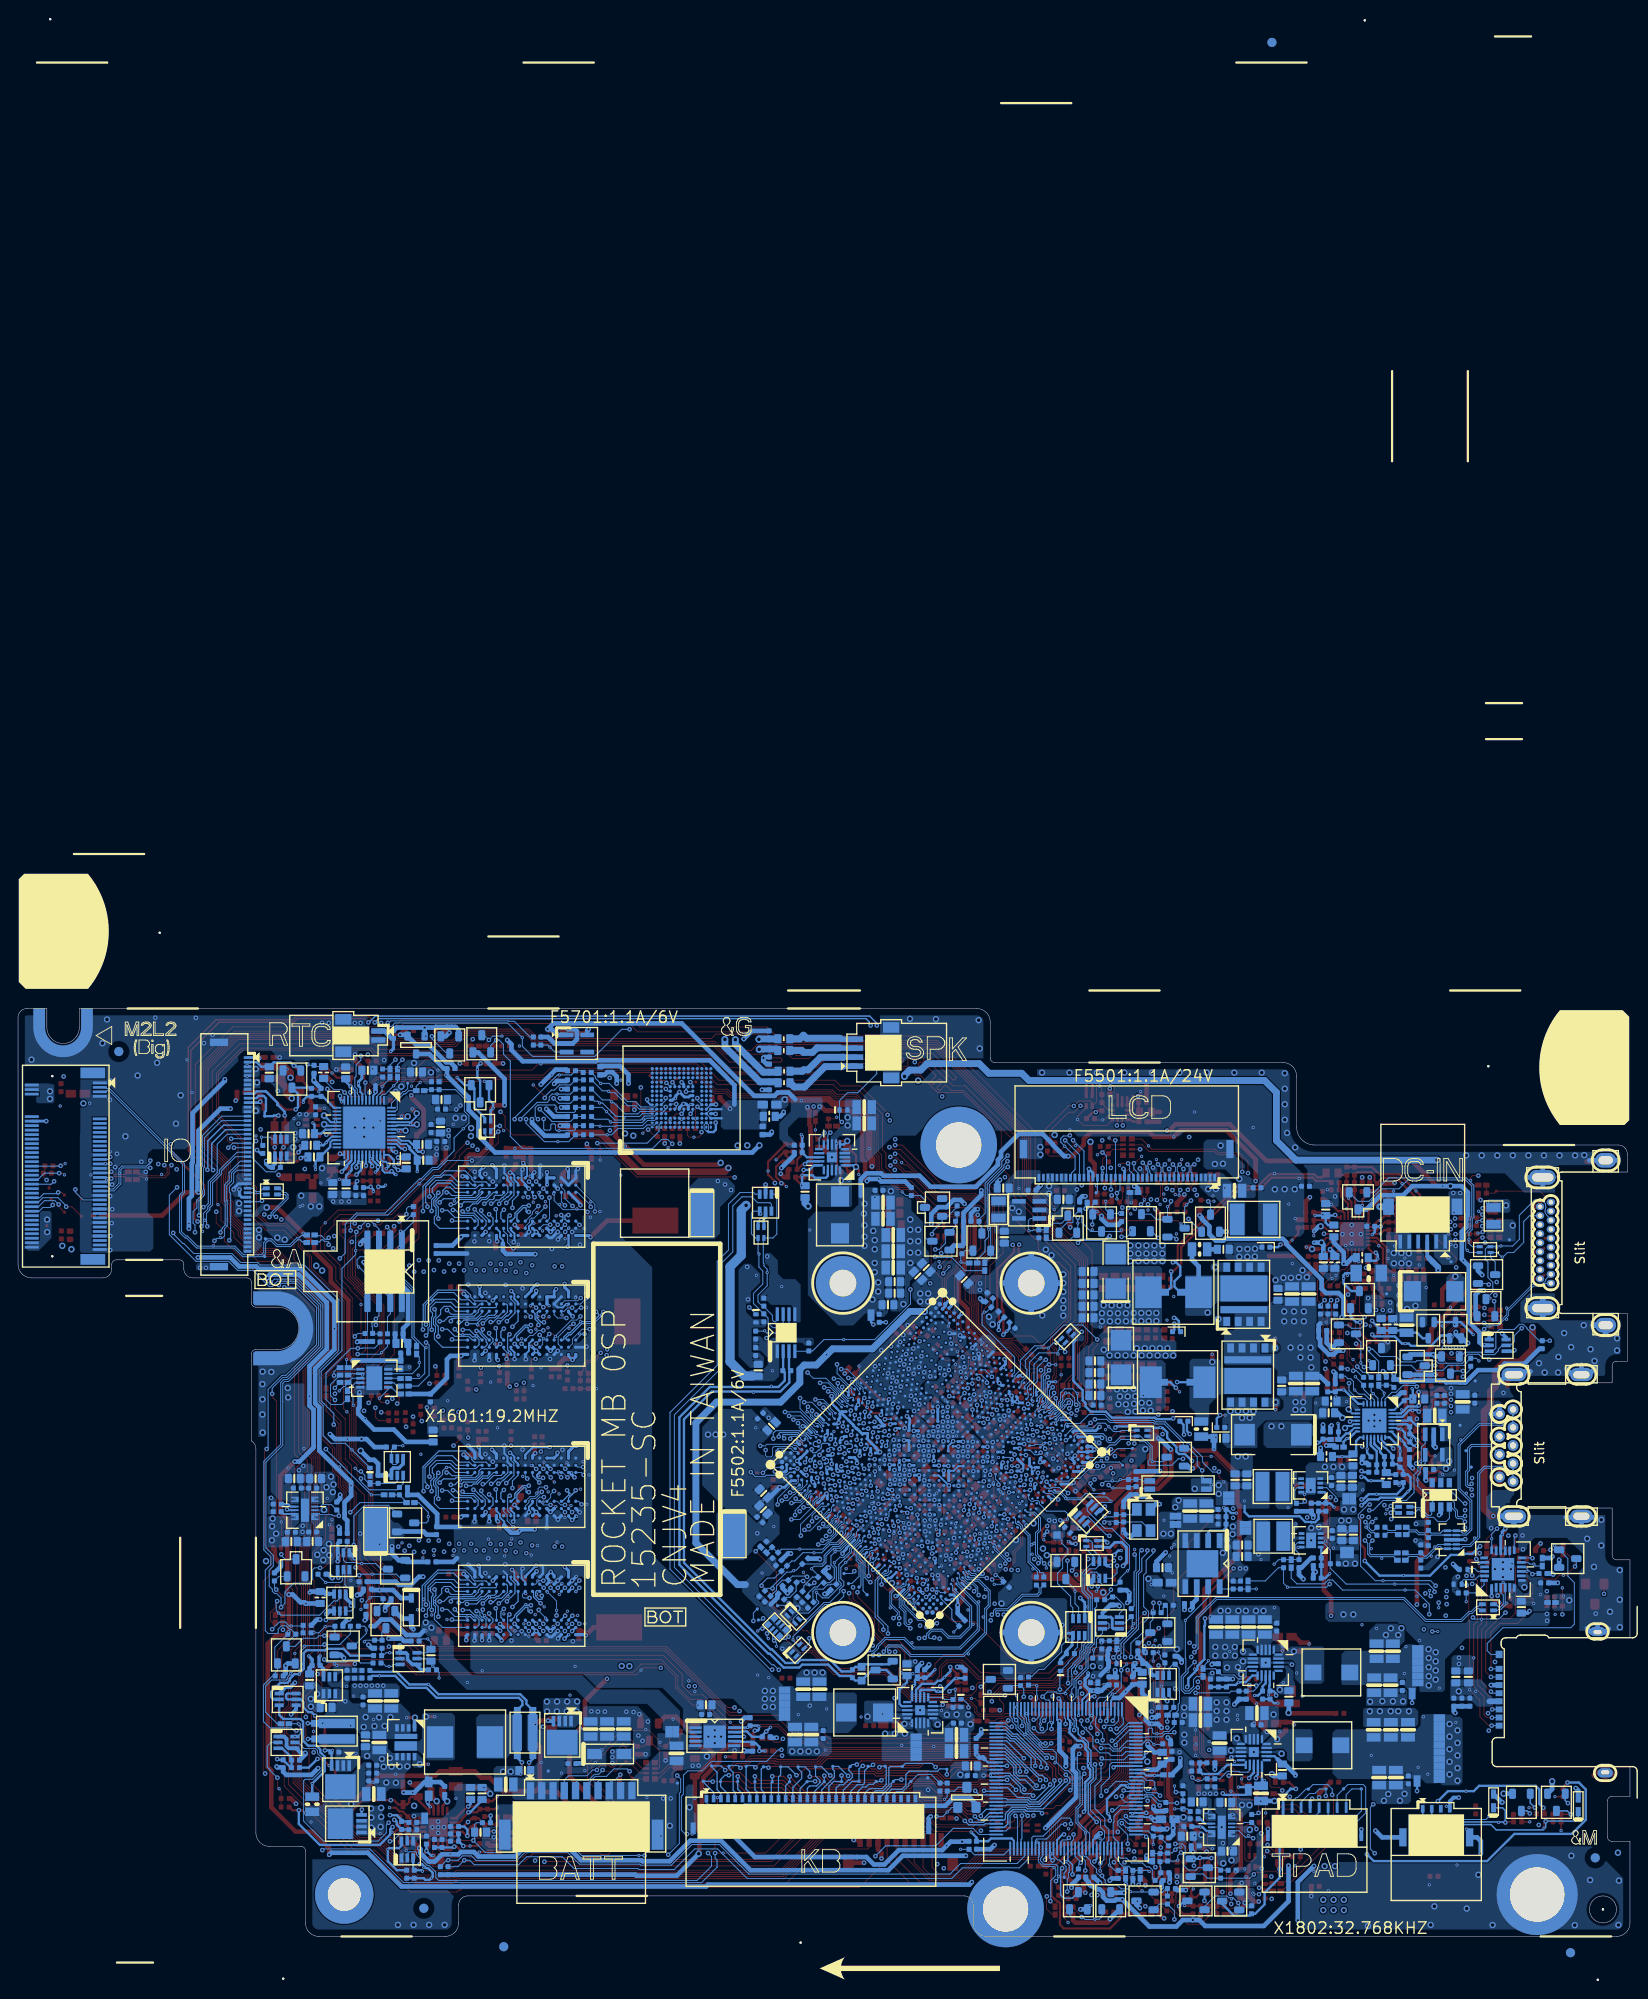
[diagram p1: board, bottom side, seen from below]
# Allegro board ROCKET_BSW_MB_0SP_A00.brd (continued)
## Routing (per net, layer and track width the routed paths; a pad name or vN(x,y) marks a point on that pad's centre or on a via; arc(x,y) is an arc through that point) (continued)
KCOL8: length 35.7
  TOP w0.127: v1(90.44,17.22) 89.9,17.22 89.01,16.33 84.21,16.33 83.75,15.87 78.77,15.87 78.22,15.32 73.87,15.32 73.5,14.96 71.92,14.96 71.33,15.55 67.31,15.55 66.12,16.74 v1(65.86,16.74)
  BOTTOM w0.127: U2401.42 69.32,20.11 68.14,18.93 68.14,18.13 67.83,17.81 66.94,17.81 v1(65.86,16.74) ; v1(90.44,17.22) 91.29,17.22 AFTP6213.1 92.1,16.41 KB1.14
KCOL9: length 23.9
  TOP w0.127: v1(67.69,18.31) 67.75,18.24 70.06,18.24 70.83,19.01 76.85,19.01 v1(77.06,18.8)
  BOTTOM w0.127: KB1.24 84.1,15.79 83.73,16.16 82.89,16.16 82.26,16.79 82.26,18.71 82.1,18.87 AFTP6223.1 80.42,19.2 77.47,19.2 v1(77.06,18.8) ; v1(67.69,18.31) 67.69,18.84 69.36,20.51 U2401.41
KCOL10: length 23.9
  TOP w0.127: v1(75.82,17.98) 75.04,18.75 70.93,18.75 70.04,17.86 67.43,17.86 v1(66.99,18.3)
  BOTTOM w0.127: U2401.40 69.37,20.91 66.99,18.53 v1(66.99,18.3) ; KB1.26 82.5,15.79 81.95,16.34 80.8,16.34 80.37,16.77 80.37,17.96 79.98,18.34 76.86,18.34 76.6,18.6 75.86,18.6 AFTP6225.1 75.82,18.55 v1(75.82,17.98)
KCOL11: length 26.6
  TOP w0.127: v1(65.46,17.35) 66.04,17.35 66.37,17.03 68.12,17.03 68.77,16.38 69.99,16.38 70.21,16.59 71.11,16.59 71.4,16.88 71.98,16.88 72.25,16.61 76.18,16.61 77.05,17.48 80.8,17.48 v1(80.87,17.41)
  BOTTOM w0.127: v1(80.87,17.41) 81.56,17.41 AFTP6224.1 82,16.96 82,16.68 83.3,15.39 KB1.25 ; U2401.39 69.41,21.31 66.85,18.75 66.81,18.75 65.56,17.5 65.56,17.45 v1(65.46,17.35)
KCOL12: length 28.6
  TOP w0.127: v1(85.81,19.08) 85.7,19.08 85.29,19.49 79.17,19.49 78.63,20.02 70.4,20.02 70.27,19.89 67.37,19.89 v1(67.26,19.79)
  BOTTOM w0.127: v1(85.81,19.08) 86.32,19.08 AFTP6218.1 86.7,18.71 86.7,18.42 86.3,18.02 86.3,17.66 86.59,17.37 86.75,17.37 87.28,16.83 87.74,16.83 88.1,16.47 KB1.19 ; v1(67.26,19.79) 69.19,21.71 U2401.38
KCOL13: length 31.9
  TOP w0.127: v1(83.08,17.34) 82.87,17.55 82.73,17.55 82.42,17.86 78.03,17.86 77.9,17.73 76.94,17.73 76.07,16.86 72.35,16.86 72.08,17.13 71.29,17.13 71.01,16.85 70.1,16.85 69.89,16.63 68.88,16.63 68.23,17.28 66.47,17.28 65.96,17.79 65.24,17.79 v1(64.82,17.37)
  BOTTOM w0.127: U2401.37 69.2,22.11 68.79,21.7 68.38,21.7 66.47,19.79 66.47,18.77 65.59,17.89 65.21,17.89 64.82,17.5 v1(64.82,17.37) ; KB1.22 85.7,16.07 85.18,16.59 84.78,16.59 84.48,16.89 83.97,16.89 AFTP6221.1 83.22,17.2 v1(83.08,17.34)
KCOL14: length 30.2
  TOP w0.127: v1(83.3,18.79) 83.11,18.98 78.96,18.98 78.42,19.52 70.62,19.52 70.48,19.38 68.96,19.38 68.66,19.09 66.13,19.09 v1(66,18.95)
  BOTTOM w0.127: v1(83.3,18.79) 83.2,18.89 AFTP6222.1 82.54,18.77 82.54,16.86 82.99,16.41 84.4,16.41 84.9,15.92 KB1.23 ; v1(66,18.95) 66,19.71 68.24,21.95 68.68,21.95 69.24,22.51 U2401.36
KCOL15: length 31.9
  TOP w0.127: v1(84.01,19.04) 83.82,19.24 79.06,19.24 78.53,19.77 70.51,19.77 70.38,19.64 68.86,19.64 68.56,19.34 66.24,19.34 66.18,19.4 65.81,19.4 65.36,18.94 v1(65.36,18.8)
  BOTTOM w0.127: U2401.35 69.28,22.91 68.57,22.21 68.12,22.21 65.36,19.44 v1(65.36,18.8) ; v1(84.01,19.04) 84.18,18.88 AFTP6220.1 84.56,18.77 84.95,18.38 84.95,17.02 85.13,16.84 85.75,16.84 86.5,16.09 KB1.21
KCOL16: length 34.6
  TOP w0.127: v1(85.14,18.93) 84.53,18.93 84.19,18.59 83.73,18.59 83.49,18.35 83.12,18.35 82.74,18.73 78.85,18.73 78.32,19.26 70.72,19.26 70.59,19.13 70.21,19.13 69.57,18.5 68.96,18.5 68.71,18.75 66.81,18.75 66.41,18.35 65.05,18.35 v1(64.73,18.68)
  BOTTOM w0.127: v1(64.73,18.68) 64.73,19.18 68.01,22.46 68.47,22.46 69.32,23.31 U2401.34 ; v1(85.14,18.93) 85.23,18.93 85.57,18.59 AFTP6227.1 86.33,17.21 87.3,16.24 KB1.20
KROW0: length 46.6
  TOP w0.127: v1(63.88,17.31) 64.08,17.51 64.08,18.66 64.54,19.13 65.06,19.13 65.58,19.65 66.2,19.65 66.77,20.23 70.25,20.23 70.3,20.28 78.74,20.28 79.28,19.74 89.08,19.74 89.96,18.87 95.48,18.87 v1(95.61,18.73)
  BOTTOM w0.127: v1(95.61,18.73) 95.76,18.73 95.85,18.83 AFTP6208.1 96.41,18.58 96.41,16.29 96.1,15.98 KB1.9 ; U2401.54 69.23,15.31 69.09,15.16 66.8,15.16 66.56,14.93 65.67,14.93 63.88,16.72 v1(63.88,17.31)
KROW1: length 49.8
  TOP w0.127: v1(97.06,18.77) 96.6,19.23 94.95,19.23 94.85,19.12 90.06,19.12 89.19,20 79.38,20 78.85,20.53 70.19,20.53 70.15,20.48 66.67,20.48 66.09,19.91 65.48,19.91 64.95,19.38 64.44,19.38 63.74,18.68 63.74,17.81 v1(63.24,17.31)
  BOTTOM w0.127: v1(63.24,17.31) 63.24,17 65.57,14.67 66.66,14.67 66.9,14.91 U2401.55 ; KB1.7 97.7,15.94 98.1,16.34 AFTP6206.1 98.01,18.96 97.25,18.96 v1(97.06,18.77)
KROW2: length 53.8
  TOP w0.127: v1(98.72,18.71) 98.48,18.95 98.01,18.95 97.48,19.48 94.85,19.48 94.74,19.37 90.17,19.37 89.29,20.25 79.49,20.25 78.95,20.79 70.09,20.79 70.04,20.74 66.56,20.74 66.1,20.27 63.93,20.27 63.41,19.76 63.41,18.11 v1(62.61,17.31)
  BOTTOM w0.127: KB1.5 99.3,15.98 99.53,16.21 99.53,18.22 100,18.68 AFTP6204.1 99.9,18.98 98.99,18.98 v1(98.72,18.71) ; v1(62.61,17.31) 62.61,17.27 65.46,14.42 66.77,14.42 66.95,14.6 69.18,14.6 69.27,14.51 U2401.56
KROW3: length 31.6
  TOP w0.127: v1(97.12,17.77) 96.67,17.32 93.95,17.32 92.2,15.57 84.53,15.57 84.07,15.11 79.18,15.11 78.63,14.56 74.18,14.56 73.55,13.93 72.6,13.93 v1(72.05,13.37)
  BOTTOM w0.127: v1(97.12,17.77) AFTP6207.1 97.12,16.28 96.9,16.06 KB1.8 ; U2401.57 71.46,14.11 72.05,13.52 v1(72.05,13.37)
KROW4: length 35.9
  TOP w0.127: v1(72.7,13.33) 72.95,13.58 73.57,13.58 74.29,14.31 78.73,14.31 79.28,14.85 84.17,14.85 84.63,15.31 92.48,15.31 94.14,16.98 97.53,16.98 98.76,18.21 99.37,18.21 99.68,17.9 v1(100.02,17.9)
  BOTTOM w0.127: U2401.58 71.08,13.71 71.86,12.93 72.3,12.93 v1(72.7,13.33) ; v1(100.02,17.9) 100.44,17.9 100.93,17.41 AFTP6203.1 100.93,16.64 100.1,15.81 KB1.4
KROW5: length 33.7
  TOP w0.127: v1(73.18,12.84) 74.39,14.05 78.86,14.05 79.41,14.6 84.28,14.6 84.74,15.06 92.69,15.06 94.14,16.51 97.77,16.51 v1(99.02,17.76)
  BOTTOM w0.127: v1(99.02,17.76) 99.02,17.76 99.02,17.67 99.02,17.67 AFTP6205.1 99.02,16.36 98.5,15.84 KB1.6 ; U2401.59 71.11,13.31 71.75,12.67 73.01,12.67 v1(73.18,12.84)
KROW6: length 58.2
  TOP w0.127: v1(100.42,18.47) 99.89,18.47 99.16,19.2 98.12,19.2 97.59,19.73 94.74,19.73 94.64,19.63 90.28,19.63 89.4,20.51 79.59,20.51 79.06,21.04 69.98,21.04 69.93,20.99 66.46,20.99 65.99,20.53 63.82,20.53 63.13,19.84 63.13,18.47 v1(62.61,17.95)
  BOTTOM w0.127: KB1.3 100.9,15.87 101.32,16.29 101.32,18.22 101.93,18.84 AFTP6202.1 100.87,18.93 100.42,18.48 v1(100.42,18.47) ; U2401.60 69.46,12.91 69.32,13.04 69.32,13.62 68.6,14.35 67.06,14.35 66.87,14.16 65.13,14.16 62.16,17.13 62.16,17.5 v1(62.61,17.95)
KROW7: length 37
  TOP w0.127: v1(101.8,17.18) 99.29,17.18 98.16,16.05 94.18,16.05 92.93,14.81 84.84,14.81 84.38,14.35 79.52,14.35 78.97,13.8 74.79,13.8 v1(73.82,12.83)
  BOTTOM w0.127: v1(73.82,12.83) 73.38,12.38 71.68,12.38 71.55,12.51 U2401.61 ; v1(101.8,17.18) 101.84,17.22 AFTP6201.1 102.84,17.14 101.7,16 KB1.2
L_BKLT_CTRL: length 7.9
  TOP w0.102: 51.09,80.09 50.78,80.4 R5524.2 ; 51.09,80.09 51.09,81.47 v1(50.94,81.62) ; 51.09,80.09 R5527.2
  BOTTOM w0.102: Q5503.C 53.16,80.18 52.59,79.61 D5502.1 v2(51.33,81) 50.94,81.39 v1(50.94,81.62)
L_BKLT_CTRL_B: length 3.2
  TOP w0.102: v1(56.43,77.66) 56.44,77.68 R5526.2 v2(55.44,78.41)
  BOTTOM w0.102: Q5503.B 55.81,77.66 v1(56.43,77.66)
L_BKLT_CTRL_CPU: length 167.6
  TOP w0.102: v1(83.06,39.07) 82.45,38.46 R804.2 81.98,37.61 81.74,37.37 80.59,37.37 80.46,37.49 79.72,37.49 78.36,36.13 76.36,36.13 75.19,34.96 72.78,34.96 68.35,30.53 65.14,30.53 63.37,32.3 63.37,32.74 61.66,34.44 55.34,34.44 v2(55.08,34.7) 55.07,34.7 v1(53.87,35.89)
  L4 w0.127: v1(52.34,77.54) 51.84,78.04 48.36,78.04 41.7,84.71 25.05,84.71 21.58,81.25 21.58,75.32 20.51,74.25 20.51,73.37 20.51,72.8 20.34,72.63 20.34,72.42 20.34,67.53 22.05,65.82 22.05,65 22.27,64.78 22.27,64.41 22.01,64.15 21.04,64.15 20.38,63.49 18.29,63.49 18.26,63.46 18.24,63.46 17.84,63.05 17.84,63.04 17.28,62.49 17.28,60 18.04,59.25 18.04,58.86 18.04,52.52 19.47,51.09 19.47,41.9 19.19,41.62 19.19,41.15 20.84,39.5 20.84,37.29 20.79,37.24 20.79,36.87 21.05,36.61 21.42,36.61 21.89,37.09 22.05,37.09 22.59,37.63 22.89,37.63 23.15,37.89 34.43,37.89 34.73,37.59 46.83,37.59 49.11,35.31 50.46,35.31 51.73,34.03 51.73,32.04 52.02,31.75 54.11,31.75 54.37,32.01 54.37,35.4 v1(53.87,35.89)
  BOTTOM w0.102: v1(83.06,39.07) 83.06,39.66 82.66,40.06 82.39,40.06 82.01,40.44 CPU1.P52 ; Q5503.E 53.08,78.27 v1(52.34,77.54)
L_BKLT_EN: length 2.8
  TOP w0.102: v2(65.44,23.58) 65.4,23.58 v1(65.02,23.95) 65.02,24.51 R2424.1
  BOTTOM w0.102: v1(65.02,23.95) 64.78,24.19 U2401.22
L_BKLT_EN_CPU: length 37.4
  TOP w0.102: v1(69.37,26.78) 69.37,26.78 69.37,26.77 68.14,26.77 v2(68.08,26.72) 67.76,27.04 66.29,27.04 65.23,25.98 R2424.2 ; R813.2 80.65,41.23 v1(81.02,40.86) 81.13,40.74 R803.2
  L3 w0.127: v1(81.02,40.86) 82.38,40.86 83.3,41.78 84.3,41.78 85.25,40.82 85.25,35.1 82.31,32.16 80.18,32.16 79.43,31.4 78.35,31.4 75.29,28.35 71.3,28.35 69.72,26.78 v1(69.37,26.78)
  BOTTOM w0.102: 81.52,41 81.16,41 v1(81.02,40.86)
LCD_BRIGHTNESS: length 5.4
  TOP w0.102: RN5501.2 57.38,87.37 EC5507.1 57.94,86.87 58.53,86.28 v1(58.53,85.29) v2(58.53,84.73)
  BOTTOM w0.102: v1(58.53,85.29) 58.6,85.22 LCD1.26
LCD_TST: length 163.3
  TOP w0.102: v1(60.74,22.63) 60.83,22.54 R2413.1 ; RN5501.5 54.2,88.52 v2(53.44,87.75) 53.07,87.39 46.03,87.39 45.63,86.99 43.34,86.99 42.4,86.04 v1(42.4,84.73)
  L3 w0.102: v1(20.33,38.34) 20.35,38.34 20.82,37.86 20.82,37.26 20.8,37.23 20.8,36.87 20.88,36.8 20.88,34.89 20.12,34.13 20.12,27.89 21.83,26.18 21.83,15.93 24.23,13.53 33.5,13.53 34.04,14.07 37.58,14.07 38.69,15.18 38.69,15.36 39.47,16.14 41.86,16.14 43.05,17.33 43.05,18.17 44.04,19.15 45.09,19.15 45.11,19.13 50.18,19.13 50.57,19.51 50.57,19.67 53.15,22.25 53.89,22.25 56.2,19.94 57.28,19.94 58.67,18.55 59.41,18.55 60.33,17.63 60.73,17.63 60.99,17.88 60.99,18.24 60.99,18.24 60.99,18.41 61.09,18.51 61.09,18.78 61.62,19.31 61.62,21.75 60.75,22.62 60.75,22.63 v1(60.74,22.63)
  L4 w0.102: v1(20.33,38.34) 20.33,39.67 18.95,41.05 18.95,41.72 19.23,42 19.23,50.99 17.79,52.42 17.79,59.15 17.04,59.9 17.04,62.59 17.59,63.14 17.59,63.15 18.14,63.7 18.16,63.7 18.29,63.83 20.38,63.83 21.8,65.25 21.8,65.72 20.08,67.45 20.08,72.71 20.15,72.78 20.15,72.97 20.15,74.23 20.84,74.93 20.84,80.85 24.95,84.95 25.15,84.95 42.17,84.95 v1(42.4,84.73)
LCD_TST_C: length 6.7
  TOP w0.102: v1(57.12,88.37) 57.56,88.37 v2(57.81,88.62) 57.58,88.85 56.62,88.85 56.28,88.52 RN5501.4
  BOTTOM w0.102: v1(57.12,88.37) 57.1,88.34 57.1,87.86 LCD1.23
LCD_TST_EN: length 186
  TOP w0.102: v1(61.28,79.77) 61.28,79.19 v2(61.28,79.19)
  L3 w0.102: v1(20.44,35.61) 19.89,35.06 19.89,27.78 21.6,26.07 21.6,15.83 24.14,13.3 33.6,13.3 34.14,13.84 37.68,13.84 38.92,15.08 38.92,15.26 39.56,15.9 41.95,15.9 43.28,17.23 43.28,18.07 44.13,18.92 44.99,18.92 45.81,18.11 47.31,18.11 48.1,18.9 50.28,18.9 50.88,19.5 50.88,19.66 53.24,22.02 53.79,22.02 56.1,19.71 57.18,19.71 58.57,18.32 59.31,18.32 60.24,17.4 60.83,17.4 61.22,17.78 61.22,18.32 61.32,18.42 61.32,18.69 63.34,20.71 63.97,20.71 64.24,20.98 v1(64.24,21.44)
  L4 w0.102: v1(61.28,79.77) 61.09,79.77 59.6,78.28 48.48,78.28 44.07,82.69 44.07,84.45 43.11,85.41 24.53,85.41 18.8,79.68 18.8,74.01 17.69,72.89 17.69,66.91 16.36,65.58 16.36,65.57 16.33,65.54 16.33,59.58 17.06,58.85 17.06,58.56 17.06,48.75 17.83,47.98 17.83,43.59 18.01,43.41 18.01,42.96 18.01,42.95 18.01,41.52 16.99,40.51 16.99,38.98 17.07,38.9 17.07,35.66 16.99,35.59 16.99,35.23 17.25,34.97 19.81,34.97 v1(20.44,35.61)
  BOTTOM w0.102: R5503.1 64.48,77.24 62.23,77.24 61.64,77.83 61.64,77.87 D5501.2 61.28,78.23 v1(61.28,79.77) ; U2401.28 67.18,24.44 66.98,24.23 66.98,23.82 66.82,23.66 66.82,22.74 65.08,21 64.69,21 64.25,21.44 v1(64.24,21.44)
LCD_TST_KBC: length 7.4
  TOP w0.102: v2(60.41,23.11) 59.94,22.64 R2413.2 59.3,21.84 v1(59.15,21.7)
  BOTTOM w0.102: v1(59.15,21.7) 58.79,21.34 57.81,21.34 57.27,20.8 56.71,20.8 55.8,21.71 U2401.123
LDO1_CAP: length 5.6
  TOP w0.305: R2704.2 142.57,85.28 v1(142.96,84.89) 143.39,84.89 143.59,85.08 C2702.2 144.12,84.42 v2(144.5,84.04)
  BOTTOM w0.203: 142.01,86 141.88,86.12 U2701.27
  BOTTOM w0.305: 142.01,86 142.42,85.58 142.42,85.43 v1(142.96,84.89)
LDO2_CAP: length 5.4
  BOTTOM w0.203: 135.52,87.7 135.77,87.94 136.42,87.94 136.86,88.38 U2701.39
  BOTTOM w0.305: 135.52,87.7 135.42,87.6 135.42,87.42 134.59,86.59 C2712.2 v2(134.59,84.9)
LDO3_CAP: length 3.7
  BOTTOM w0.203: 141.06,94.38 140.92,94.23 140.92,93.75 140.68,93.51 U2701.7
  BOTTOM w0.305: C2718.1 140.74,95.25 141.1,94.88 v2(141.1,94.69) 141.1,94.42 141.06,94.38
LID_CLOSE#: length 82.1
  TOP w0.102: v2(7.51,38.69) C6701.1 R6701.1 v1(7.51,35.75) ; LIDSW1.3 v1(2.88,38.03)
  L3 w0.102: v1(20.54,13.28) 21.72,13.28 24.2,10.8 32.97,10.8 33.1,10.93 34.69,12.52 39.29,12.52 39.8,13.03 41.71,13.03 41.84,13.16 44.56,13.16 44.79,13.39 45.84,13.39 46.48,12.75 47.82,12.75 49.08,14.01 50.46,14.01 50.98,14.53 v1(52.19,14.53) ; v1(2.88,38.03) 4.64,36.27 6.99,36.27 v1(7.51,35.75) 8.86,34.39 13.92,34.39 15.19,33.12 15.19,31.21 15.88,30.52 15.88,25.58 16.46,25 16.46,14.31 v1(15.56,13.41)
  BOTTOM w0.102: v1(52.19,14.53) 53.14,15.48 53.77,15.48 53.94,15.31 U2401.107 ; v1(15.56,13.41) 16,12.97 20.24,12.97 v1(20.54,13.28)
LINE1-L_C: length 2.9
  TOP w0.254: R2922.1 147.91,86.01 v1(147.52,86.4) v2(146.94,86.4)
  BOTTOM w0.254: v1(147.52,86.4) 147.4,86.52 C2907.2
LINE1-L_R: length 2.9
  TOP w0.254: v2(147.59,87.74) 147.59,87.24 v1(147.78,87.05) 147.99,86.84 R2921.1
  BOTTOM w0.254: C2908.2 147.78,87.12 v1(147.78,87.05)
LINE1_L: length 4.6
  BOTTOM w0.203: U2701.22 144.02,88.38 144.23,88.17 144.23,87.83 144.26,87.8
  BOTTOM w0.254: 144.26,87.8 144.26,87.63 145.37,86.52 C2907.1 145.88,86.04 v2(145.88,85.12)
LINE1_R: length 2.7
  BOTTOM w0.203: 144.56,88.3 144.08,88.78 U2701.21
  BOTTOM w0.254: 144.56,88.3 144.7,88.16 v2(144.7,88.11) 145,87.82 C2908.1
LINE1_VREFO_L: length 2.9
  TOP w0.254: R2912.1 140.59,85 140.29,85.3 v1(140.29,85.56) 140.65,85.92 v2(140.93,85.92)
  BOTTOM w0.203: 140.28,86.02 U2701.31
  BOTTOM w0.254: v1(140.29,85.56) 140.29,85.65 140.28,85.65 140.28,86.02
LINE1_VREFO_R: length 4.6
  TOP w0.254: v1(141.33,84.56) 141.41,84.48 R2913.1 142.77,84.04 v2(143.23,84.04)
  BOTTOM w0.203: 140.68,86.02 U2701.30
  BOTTOM w0.254: 140.68,86.02 140.68,85.88 140.83,85.74 140.83,85.06 v1(141.33,84.56)
LPC_AD_CPU_P0: length 5.9
  TOP w0.102: RN1802.8 62.93,59.96 63.47,59.41 63.47,58.7 62.74,57.96 v1(62.74,57.81) 62.74,57.08 v2(62.51,56.85)
  BOTTOM w0.102: CPU1.M3 64.05,57.09 63.64,57.09 63.44,57.29 63.44,57.41 63.22,57.63 62.92,57.63 v1(62.74,57.81)
LPC_AD_CPU_P1: length 6.2
  TOP w0.102: v2(61.49,57.81) 61.73,58.05 v1(62,58.05) 62.4,58.05 62.57,58.22 62.61,58.22 63.2,58.8 63.2,59.26 62.82,59.64 62.41,59.64 62.28,59.77 RN1802.7
  BOTTOM w0.102: v1(62,58.05) 62.4,58.05 62.57,58.22 62.92,58.22 CPU1.M2
LPC_AD_CPU_P2: length 4.5
  TOP w0.102: v2(62.71,58.9) 62.71,58.9 62.69,58.93 62.61,58.93 62.29,59.25 v1(62.28,59.25) 62.28,59.26 61.78,59.76 RN1802.6
  BOTTOM w0.102: 64.35,57.49 64.1,57.49 63.89,57.7 63.74,57.7 62.77,58.67 62.77,58.77 62.29,59.25 v1(62.28,59.25)
LPC_AD_CPU_P3: length 6
  TOP w0.102: RN1802.5 61.13,59.92 61.87,59.17 61.87,58.97 v1(62.23,58.62)
  BOTTOM w0.102: CPU1.N1 63.68,58.15 63.63,58.15 63.02,58.76 63.02,59.09 62.75,59.37 62.75,59.48 62.53,59.69 62.14,59.69 61.87,59.43 61.87,59.42 61.87,59.42 61.87,59.08 61.91,59.04 61.91,58.93 v1(62.23,58.62)
LPC_AD_CPU_R_P0: length 335.5
  TOP w0.102: RN1802.1 62.93,61.34 61.78,62.49 61.78,67.45 61.1,68.13 61.1,74.82 65.24,78.96 65.24,80.41 67.41,82.59 67.41,88.72 77.19,98.5 90.08,98.5 91.13,97.44 92.95,97.44 93.52,98.01 95.52,98.01 95.62,97.91 95.62,97.63 95.52,97.53 94.28,97.53 94.13,97.39 94.13,97.19 94.28,97.05 99.91,97.05 101.73,98.87 121.31,98.87 122.47,100.03 129.09,100.03 130.33,98.79 134.16,98.79 134.33,98.96 138.62,98.96 139.23,99.57 154.49,99.57 157.83,96.23 157.83,88.44 155.35,85.96 155.35,84.28 155.42,84.2 155.42,83.95 155.43,83.94 155.43,81.93 154.96,81.46 154.96,80.09 153.45,78.58 153.45,78.1 151.73,76.38 150.2,76.38 144.73,70.91 144.73,70.82 143.91,70 143.91,64.81 146.35,62.37 146.35,54.33 145.4,53.38 145.4,51.07 145.68,50.79 145.68,47.32 145.45,47.09 145.45,44.18 146.71,42.93 146.71,39.45 146.54,39.28 146.54,31.93 147.08,31.38 147.08,30.01 147.28,29.81 147.28,27.76 147.92,27.11 147.92,23.87 147.7,23.64 v2(147.7,23.55) 147.7,23.32 147.43,23.06 147.43,22.5 147.65,22.29 147.65,21.53 147.47,21.36 147.47,17.45 140.98,10.96 138.68,10.96 134.54,6.81 131,6.81 130.8,7.02 130.56,7.02 130.24,7.34 94.27,7.34 88.9,12.71 80.35,12.71 80,12.36 79.17,12.36 78.46,11.66 77.9,11.66 77.45,11.2 DB1.9 77.45,7.67 76.71,6.93 74.63,6.93 71.87,9.69 65.99,9.69 64.43,11.25 64.43,12.94 63.33,14.05 62.98,14.05 61.25,15.78 60.52,15.78 58.62,17.68 57.65,17.68 56.87,18.46 56.87,21.03 v1(57.08,21.24)
  BOTTOM w0.102: v1(57.08,21.24) 57.08,21.38 55.55,22.91 U2401.126
LPC_AD_CPU_R_P1: length 337.6
  TOP w0.102: RN1802.2 62.28,61.59 61.55,62.32 61.55,67.35 60.87,68.03 60.87,74.91 65.01,79.05 65.01,80.51 67.19,82.68 67.19,88.82 77.1,98.73 90.19,98.73 91.16,97.77 92.5,97.77 92.64,97.91 92.64,98.11 92.5,98.25 91.78,98.25 91.63,98.39 91.63,98.59 91.78,98.73 95.54,98.73 96.34,97.92 100.46,97.92 101.63,99.1 121.21,99.1 122.37,100.26 129.26,100.26 130.5,99.02 134.07,99.02 134.23,99.19 138.53,99.19 139.14,99.8 154.58,99.8 158.05,96.33 158.05,88.34 155.57,85.86 155.57,84.37 155.65,84.3 155.65,84.04 155.66,84.03 155.66,81.83 155.19,81.36 155.19,79.99 153.68,78.48 153.68,78 151.82,76.15 150.29,76.15 144.96,70.82 144.96,70.73 144.14,69.91 144.14,64.91 146.58,62.47 146.58,54.24 145.62,53.28 145.62,51.17 145.91,50.88 145.91,47.22 145.68,46.99 145.68,44.27 146.93,43.02 146.93,39.36 146.76,39.19 146.76,32.02 147.46,31.33 v2(147.46,30.24) 147.46,29.96 147.51,29.9 147.51,27.85 148.15,27.21 148.15,24.17 149.11,23.22 149.11,22.58 147.7,21.17 147.7,17.36 141.07,10.73 138.78,10.73 134.63,6.59 130.9,6.59 130.7,6.79 130.47,6.79 130.14,7.11 94.17,7.11 88.81,12.48 80.44,12.48 80.1,12.13 79.33,12.13 78.45,11.26 DB1.8 78.45,7.64 77.51,6.7 74.53,6.7 71.77,9.46 65.89,9.46 64.2,11.15 64.2,12.84 63.22,13.82 62.88,13.82 61.16,15.55 60.43,15.55 58.56,17.42 57.57,17.42 56.64,18.35 56.64,21.41 56.96,21.73 v1(57.49,21.73)
  BOTTOM w0.102: v1(57.49,21.73) 57.29,21.73 55.71,23.31 U2401.127
LPC_AD_CPU_R_P2: length 337.5
  TOP w0.102: RN1802.3 61.78,61.54 61.32,61.99 61.32,67.26 60.64,67.94 60.64,75.01 64.78,79.15 64.78,80.6 66.96,82.78 66.96,88.91 77.04,98.99 96.87,98.99 97.54,98.32 98.4,98.32 98.6,98.53 98.88,98.53 99.26,98.15 100.36,98.15 101.57,99.36 121.15,99.36 122.28,100.49 129.35,100.49 130.59,99.25 133.97,99.25 134.14,99.42 138.34,99.42 138.96,100.03 154.68,100.03 158.28,96.42 158.28,88.25 155.8,85.77 155.8,84.47 155.88,84.39 155.88,84.14 155.89,84.13 155.89,81.74 155.42,81.27 155.42,79.89 153.99,78.47 153.99,78 151.91,75.92 150.39,75.92 145.19,70.72 145.19,70.63 144.37,69.81 144.37,65 146.81,62.56 146.81,54.14 145.85,53.19 145.85,51.26 146.14,50.98 146.14,47.13 145.91,46.9 145.91,44.37 147.16,43.11 147.16,39.26 146.99,39.09 146.99,32.37 v2(147.13,32.23) 147.64,31.72 147.64,31.47 147.69,31.43 147.69,30.52 147.81,30.39 147.81,30.09 147.74,30.02 147.74,27.95 148.38,27.3 148.38,25.5 149.33,24.54 149.33,22.49 147.93,21.08 147.93,17.26 141.17,10.5 138.87,10.5 134.73,6.36 130.81,6.36 130.61,6.56 130.37,6.56 130.05,6.88 94.08,6.88 88.71,12.25 80.54,12.25 80.02,11.74 79.6,11.74 79.45,11.59 DB1.7 79.45,8.2 77.72,6.47 74.44,6.47 71.68,9.23 65.8,9.23 63.97,11.06 63.97,12.56 63.97,12.56 63.97,12.75 63.13,13.59 62.79,13.59 61.06,15.32 60.34,15.32 58.49,17.17 57.5,17.17 56.41,18.25 56.41,21.77 v1(57.65,23.01)
  BOTTOM w0.102: v1(57.65,23.01) 57.11,22.47 56.87,22.47 55.64,23.71 U2401.128
LPC_AD_CPU_R_P3: length 336.7
  TOP w0.102: v1(56.97,23.06) 56.18,22.27 56.18,18.16 57.41,16.94 58.39,16.94 60.24,15.09 60.97,15.09 62.7,13.36 63.03,13.36 63.74,12.65 63.74,10.96 65.7,9.01 71.58,9.01 74.34,6.24 77.83,6.24 80.45,8.86 DB1.6 80.45,11.25 81.22,12.02 88.62,12.02 93.99,6.65 129.96,6.65 130.28,6.33 130.51,6.33 130.71,6.13 134.82,6.13 138.97,10.28 141.26,10.28 148.16,17.17 148.16,20.98 149.56,22.39 149.56,24.64 148.67,25.54 148.67,28.66 148.31,29.01 148.31,29.14 148.18,29.28 v2(148.18,31.41) 148.18,31.73 147.22,32.68 147.22,39 147.39,39.17 147.39,43.21 146.14,44.46 146.14,46.8 146.37,47.03 146.37,51.07 146.08,51.36 146.08,53.09 147.04,54.05 147.04,62.66 144.6,65.1 144.6,69.72 145.42,70.54 145.42,70.63 150.48,75.69 152.01,75.69 154.22,77.9 154.22,78.37 155.65,79.8 155.65,81.17 156.12,81.64 156.12,84.22 156.11,84.23 156.11,84.48 156.03,84.56 156.03,85.67 158.51,88.15 158.51,96.52 154.77,100.26 138.86,100.26 138.25,99.64 134.04,99.64 133.88,99.48 130.68,99.48 129.45,100.72 122.18,100.72 121.14,99.67 101.96,99.67 101.47,100.16 96.07,100.16 95.15,99.24 76.96,99.24 66.73,89.01 66.73,82.87 64.55,80.7 64.55,79.24 60.41,75.1 60.41,66.08 61.09,65.4 61.09,61.9 61.13,61.86 RN1802.4
  BOTTOM w0.102: U2401.1 56.38,24.36 56.24,24.22 56.24,23.6 56.78,23.06 v1(56.97,23.06)
LPC_CLK_CPU_P0: length 8.2
  TOP w0.102: R1803.2 60.82,58.4 v1(61.38,58.4)
  BOTTOM w0.102: v1(61.38,58.4) 61.04,58.74 61.04,59.18 61.3,59.44 61.3,60.24 v2(61.34,60.28) 61.85,60.78 62.75,60.78 63.19,60.34 63.19,59.5 63.43,59.26 63.43,58.92 63.8,58.56 63.96,58.56 CPU1.P2
LPC_CLK_CPU_P1: length 6.4
  TOP w0.102: R1802.2 v2(63.13,62.35) 63.13,61.96 63.46,61.62 63.46,60 v1(63.73,59.74)
  BOTTOM w0.102: v1(63.73,59.74) 63.64,59.65 63.64,59 63.88,58.76 64.05,58.76 64.44,58.37 64.62,58.37 64.82,58.17 CPU1.R3
LPC_CLK_KBC: length 332.6
  TOP w0.102: R1802.1 62.27,63.39 EC1802.1 62.27,64.34 62.26,64.35 62.26,67.67 61.58,68.35 61.58,74.58 65.75,78.75 65.75,80.22 67.91,82.38 67.91,88.53 73.79,94.42 75.16,94.42 77.86,97.12 77.86,97.27 77.67,97.46 77.52,97.46 75.13,95.07 74.98,95.07 74.79,95.27 74.79,95.41 77.39,98.01 81.51,98.01 81.64,97.89 81.64,97.66 81.51,97.53 80.74,97.53 80.64,97.43 80.64,97.15 80.74,97.05 83.58,97.05 83.92,97.39 89.31,97.39 90.26,96.43 99.97,96.43 101.85,98.31 134.36,98.31 134.53,98.48 138.82,98.48 139.43,99.09 154.29,99.09 157.34,96.03 157.34,95.63 157.34,90.91 155.68,89.24 155.68,88.37 155.42,88.11 154.66,88.11 154.5,87.95 154.5,84.23 153.13,82.86 153.13,80.08 152.01,78.95 151.94,78.95 151.38,78.4 149.41,78.4 148.29,77.27 148.29,75.15 144.25,71.11 144.25,71.02 143.43,70.2 143.43,64.61 145.87,62.17 145.87,54.53 144.91,53.58 144.91,50.87 145.2,50.59 145.2,48.59 144.4,47.8 144.4,46.95 144.78,46.58 144.78,44.04 146.22,42.59 146.22,39.65 146.05,39.48 v2(146.05,33.76) 146.05,31.73 146.55,31.23 146.55,29.86 146.8,29.61 146.8,27.56 147.44,26.91 147.44,24.07 147.22,23.84 147.22,23.52 146.95,23.26 146.95,22.3 147.16,22.09 147.16,21.73 146.95,21.52 146.95,21.43 146.58,21.06 146.58,20.2 146.6,20.18 146.6,17.26 140.78,11.44 138.48,11.44 138.03,10.99 137.45,10.99 137.06,10.6 137.06,10.14 134.22,7.3 131.2,7.3 131,7.5 130.76,7.5 130.44,7.82 95.03,7.82 89.66,13.19 80.15,13.19 79.8,12.85 78.97,12.85 78.26,12.14 77.7,12.14 77.22,11.66 72.73,11.66 72.71,11.69 72.17,12.23 71.5,12.23 71.09,12.64 69.85,13.88 66.23,13.88 65.9,14.2 64.01,14.2 63.68,14.53 63.18,14.53 61.45,16.26 60.72,16.26 58.81,18.17 58.31,18.17 57.74,18.73 57.74,18.95 57.68,19.01 57.68,21.2 58.04,21.56 58.04,22.53 58.37,22.85 v1(58.37,23.26)
  BOTTOM w0.102: U2401.2 56.78,23.93 57.27,23.44 58.16,23.44 58.34,23.26 58.36,23.26 v1(58.37,23.26)
LPC_CLK_LPC: length 297.4
  TOP w0.102: DB1.2 84.45,9.85 84.6,9.71 89.84,9.71 93.62,5.93 129.67,5.93 129.98,5.62 130.22,5.62 130.42,5.42 135.12,5.42 139.26,9.56 141.56,9.56 148.87,16.87 148.87,20.69 150.27,22.1 150.27,24.93 149.38,25.83 149.38,29.18 149.64,29.44 149.64,31.49 147.93,33.2 147.93,38.7 148.1,38.87 148.1,43.5 146.85,44.76 146.85,46.51 147.08,46.74 147.08,51.37 146.79,51.65 146.79,52.8 147.75,53.75 147.75,62.95 145.31,65.39 145.31,69.42 146.13,70.24 146.13,70.33 150.73,74.93 152.26,74.93 154.93,77.61 154.93,78.08 156.38,79.53 156.38,80.9 v2(156.71,81.23) 156.83,81.35 156.83,84.52 156.82,84.53 156.82,84.78 156.74,84.86 156.74,85.38 159.22,87.86 159.22,96.81 155.07,100.97 137.13,100.97 136.27,101.83 110.78,101.83 109.89,100.94 95.75,100.94 94.76,99.95 76.67,99.95 66.02,89.3 66.02,83.17 63.83,80.98 63.83,79.6 62.12,77.89 61.48,77.89 59.7,76.11 59.7,65.78 60.08,65.41 60.08,61.47 59.72,61.11 59.72,59.08 EC1801.1 60.57,59.05 R1803.1
LPC_CLKRUN#_CPU: length 343.3
  TOP w0.102: v1(120.48,8.3) 120.47,8.31 95.23,8.31 89.87,13.67 79.95,13.67 79.6,13.33 78.76,13.33 78.06,12.62 77.5,12.62 77.02,12.14 72.93,12.14 72.37,12.71 71.7,12.71 70.05,14.36 69.65,14.36 66.43,14.36 66.1,14.69 64.28,14.69 62.23,16.74 60.92,16.74 59.01,18.65 58.51,18.65 58.23,18.93 58.23,19.15 58.17,19.21 58.17,20.99 58.52,21.35 v1(58.52,21.78) ; v1(146.96,24.36) 146.96,26.71 146.05,27.62 v2(146.05,27.92) 146.2,28.07 146.2,28.75 146.32,28.86 146.32,29.41 145.62,30.1 145.62,31.48 145.57,31.53 145.57,33.66 143.69,35.55 143.69,36.16 143.79,36.26 144.63,36.26 144.73,36.36 144.73,36.64 144.63,36.74 143.79,36.74 143.69,36.85 143.69,38.93 143.58,39.03 143.3,39.03 143.2,38.93 143.2,36.57 143.1,36.46 142.82,36.46 142.72,36.57 142.72,42.38 142.39,42.71 142.39,46.19 142.72,46.52 142.72,49.27 143.35,49.9 143.35,51.04 143.98,51.66 143.98,54.06 145.39,55.46 145.39,61.97 142.95,64.41 142.95,70.4 143.77,71.22 143.77,71.31 146.56,74.11 146.56,75.38 147.8,76.62 147.8,77.47 149.21,78.88 151.18,78.88 151.74,79.44 151.81,79.44 152.65,80.28 152.65,83.06 154.02,84.43 154.02,88.26 156.86,91.11 156.86,95.83 154.09,98.6 139.63,98.6 139.02,97.99 134.73,97.99 134.56,97.83 102.08,97.83 100.2,95.95 90.05,95.95 89.13,96.87 84.15,96.87 84.02,96.75 84,96.75 83.81,96.55 80.28,96.55 80.15,96.68 80.15,97.39 80.02,97.52 78.5,97.52 78.36,97.38 78.36,97.18 78.5,97.04 78.82,97.04 78.94,96.91 78.94,96.68 78.82,96.55 77.98,96.55 77.05,95.63 77.05,95.48 77.59,94.95 77.59,94.8 77.39,94.61 77.25,94.61 76.71,95.14 76.57,95.14 76.37,94.94 76.37,94.8 76.91,94.26 76.91,94.12 76.71,93.92 76.56,93.92 76.03,94.46 75.88,94.46 75.34,93.91 73.97,93.91 68.39,88.33 68.39,82.18 66.23,80.02 66.23,78.55 62.06,74.38 62.06,68.55 64.08,66.54 64.08,65.64 63.67,65.23 63.67,62.1 63.81,61.96 63.81,61.27 63.67,61.13 63.67,60.57 v1(63.92,60.32)
  L3 w0.127: v1(146.96,24.36) 147.19,24.13 147.19,21.4 146.57,20.78 146.57,20.56 146.57,20.56 146.57,20.19 146.57,20.19 146.57,16.92 140.28,10.63 139.51,10.63 135.34,6.45 132.18,6.45 130.88,7.75 121.03,7.75 v1(120.48,8.3)
  BOTTOM w0.102: R2475.2 56.99,27.76 58.2,26.54 58.85,26.54 59.18,26.21 U2401.8 59.18,24.31 59.31,24.19 59.31,23.3 58.52,22.51 v1(58.52,21.78) ; v1(63.92,60.32) 63.92,60.15 64.48,59.59 64.48,59.13 64.83,58.78 64.83,58.65 65.01,58.47 65.38,58.47 65.47,58.38 65.51,58.38 CPU1.T3
LPC_FRAME#_CPU: length 7.7
  TOP w0.102: v1(61.45,59.01) 61.36,59.01 60.5,59.87 R1807.2
  BOTTOM w0.102: CPU1.P3 64.73,57.79 64.31,57.79 64.14,57.96 64.14,58.08 63.87,58.35 63.71,58.35 63.23,58.84 63.23,59.17 62.95,59.45 62.95,60.01 v2(62.64,60.32) 62.18,60.32 61.64,59.78 61.64,59.2 v1(61.45,59.01)
LPC_FRAME#_CPU_R: length 338.1
  TOP w0.102: v1(57.4,23.94) 57.24,23.94 55.96,22.66 55.96,18.06 57.31,16.71 58.3,16.71 60.18,14.83 60.9,14.83 62.6,13.13 62.94,13.13 63.51,12.56 63.51,10.87 65.61,8.78 71.47,8.78 74.24,6.02 78.78,6.02 81.45,8.68 DB1.5 81.45,11.58 81.67,11.79 88.52,11.79 93.9,6.41 129.87,6.41 130.18,6.1 130.42,6.1 130.62,5.9 134.92,5.9 139.06,10.05 141.36,10.05 148.39,17.08 148.39,20.89 149.79,22.3 149.79,24.73 148.9,25.63 148.9,28.93 v2(148.67,29.16) 148.61,29.22 148.61,31.84 147.45,33 147.45,38.9 147.62,39.07 147.62,43.3 146.37,44.56 146.37,46.71 146.6,46.94 146.6,51.16 146.31,51.45 146.31,53 147.27,53.95 147.27,62.75 144.82,65.19 144.82,69.62 145.65,70.44 145.65,70.53 150.57,75.46 152.1,75.46 154.45,77.81 154.45,78.28 155.88,79.71 155.88,81.08 156.35,81.55 156.35,84.32 156.34,84.33 156.34,84.58 156.26,84.66 156.26,85.58 158.74,88.06 158.74,96.61 154.87,100.48 136.93,100.48 136.09,101.33 111.06,101.33 110.14,100.41 96,100.41 95.06,99.47 76.87,99.47 66.5,89.1 66.5,82.97 64.32,80.79 64.32,79.37 60.18,75.23 60.18,65.98 60.6,65.56 60.6,61.14 R1807.1
  BOTTOM w0.102: v1(57.4,23.94) 57.4,24.06 57.18,24.28 U2401.3
LPC_SERIRQ_CPU: length 335.1
  TOP w0.102: v1(64.07,60.96) 64.07,62.13 63.9,62.31 63.9,65.14 64.31,65.54 64.31,66.75 62.29,68.76 62.29,73.73 63.39,74.83 64.25,74.83 65.68,76.26 65.68,77.07 69.1,80.49 69.1,83.03 68.91,83.22 68.91,84.46 69.78,85.32 69.78,89.39 74.07,93.68 76.85,93.68 78.77,95.61 79.32,95.61 80.03,96.32 83.89,96.32 84.09,96.52 89.05,96.52 89.85,95.72 100.3,95.72 102.18,97.6 134.66,97.6 134.82,97.76 139.21,97.76 139.82,98.38 153.99,98.38 156.63,95.74 156.63,91.2 153.79,88.36 153.79,84.53 152.42,83.16 152.42,80.37 151.71,79.67 151.64,79.67 151.09,79.11 149.71,79.11 149.12,79.11 147.58,77.57 147.58,76.72 146.34,75.48 146.34,75.29 146.34,74.2 143.54,71.41 143.54,71.32 142.72,70.5 142.72,64.32 145.16,61.88 145.16,55.6 143.75,54.19 143.75,51.76 143.13,51.14 143.13,50 142.49,49.36 142.49,46.61 142.16,46.28 142.16,42.62 142.49,42.28 142.49,36.42 145.34,33.57 145.34,31.44 145.39,31.38 145.39,30.01 146.09,29.31 146.09,28.96 145.18,28.05 145.18,25.96 146.34,24.79 146.34,23.87 146.1,23.63 v2(146.1,22.77) 146.1,20.44 v1(146.09,20.43) ; v1(60.66,18.69) 60.49,18.69 60.12,18.33 60.12,17.88 61.03,16.97 62.33,16.97 64.38,14.92 66.2,14.92 66.52,14.59 69.56,14.59 70.15,14.59 71.8,12.94 72.46,12.94 73,12.4 76.95,12.4 77.41,12.85 77.96,12.85 78.67,13.56 79.51,13.56 79.72,13.77 79.85,13.9 89.97,13.9 95.32,8.55 114.3,8.55 114.5,8.75 121.18,8.75 v1(121.52,8.42)
  L3 w0.127: v1(60.66,18.69) 60.59,18.69 59.95,19.33 59.95,19.51 60.18,19.75 60.18,19.93 60,20.1 59.82,20.1 59.59,19.87 59.41,19.87 59.07,20.21 56.44,20.21 54.15,22.49 53.05,22.49 52.16,21.6 51.14,21.6 50.81,21.93 50.81,22.27 51.02,22.47 51.02,22.84 50.91,22.95 50.91,23.4 v1(51.36,23.85) ; v1(146.09,20.43) 146.13,20.4 146.13,16.83 140.17,10.88 139.41,10.88 135.23,6.71 132.29,6.71 130.99,8.01 121.93,8.01 v1(121.52,8.42)
  BOTTOM w0.102: v1(64.07,60.96) 64.41,60.62 64.41,59.94 64.68,59.68 64.68,59.22 65.03,58.86 65.03,58.86 CPU1.T2 ; v1(51.36,23.85) 51.32,23.88 R2435.2 51.32,24.68 50.63,25.37 R2436.2 50.63,26.15 51.15,26.66 U2404.3
LVDS_VDD_EN: length 10.2
  BOTTOM w0.102: D5501.1 63.37,78.34 62.48,79.22 61.87,79.22 61.82,79.28 61.82,79.88 R5516.2 60.84,80.41 60.84,79.26 59.83,78.25 Q5501.C 56.6,78.25 v2(56.44,78.41)
LVDS_VDD_EN_B: length 2.9
  BOTTOM w0.102: v2(58.19,81.59) 58.19,80.68 Q5501.B 57.56,80.25 R5521.2
LVDS_VDD_EN_CPU: length 191.9
  TOP w0.102: R2440.2 64.41,26.33 v1(64.07,26.67) ; v1(59.67,79.02) v2(59.67,78.44)
  L3 w0.127: v1(22.76,36.73) 22.72,36.69 22.72,35.05 22.4,34.74 22.4,33.46 23.27,32.59 23.27,24.72 23.95,24.04 29.45,24.04 30.62,25.21 36.73,25.21 37.28,25.76 39.76,25.76 41.04,27.04 47.57,27.04 48.02,26.59 49.52,26.59 49.9,26.2 50.63,26.2 51.17,25.67 51.54,25.67 51.81,25.95 53.89,25.95 54.49,26.54 57.84,26.54 58.03,26.35 59.1,26.35 59.26,26.2 59.91,26.2 59.92,26.19 62.16,26.19 62.88,26.9 63.83,26.9 v1(64.07,26.67) 65.07,27.67 69.9,27.67 71.1,28.87 75.1,28.87 78.14,31.91 79.22,31.91 80.01,32.71 82.14,32.71 82.86,33.42 v1(82.86,34.05)
  L4 w0.127: v1(59.67,79.02) 59.18,78.53 48.58,78.53 44.31,82.79 44.31,84.55 43.21,85.65 24.43,85.65 18.56,79.78 18.56,74.52 18.56,74.11 17.44,72.99 17.44,67.01 16.09,65.65 16.09,62.98 16.09,59.48 16.82,58.75 16.82,58.24 16.82,48.65 17.59,47.88 17.59,43.44 17.76,43.27 17.76,41.62 16.75,40.61 16.75,38.88 16.83,38.8 16.83,35.76 16.75,35.69 16.75,35.13 17.14,34.73 20.26,34.73 22.01,36.49 22.52,36.49 v1(22.76,36.73)
  BOTTOM w0.102: CPU1.R53 82.72,40.58 83.78,39.52 83.78,35.45 82.86,34.53 v1(82.86,34.05) ; v1(59.67,79.02) 59.63,79.07 Q5501.E 59.63,81.23 R5522.2
LVDS_VDD_EN_KBC: length 4.1
  TOP w0.102: v1(64.2,23.02) v2(64.2,23.75) 64.2,24.51 R2440.1
  BOTTOM w0.102: U2401.20 63.98,23.68 64.2,23.46 v1(64.2,23.02)
LVDS_VDD_EN_R: length 7.6
  BOTTOM w0.102: D5501.3 62.39,79.85 63.08,79.17 64.05,79.17 R5503.2 R5508.2 66.22,78.43 66.31,78.34 v2(66.7,78.34) 66.78,78.41 66.78,79.45 66.53,79.7 U5501.1
M_A_A0: length 146.3
  TOP w0.114: v1(129.8,50.09) v2(129.8,50.65) ; R1217.2 131.63,58.25 v1(131.75,58.36)
  L3 w0.152: v1(129.95,74.68) 129.95,73.63 130.21,73.37 130.21,72.6 129.95,72.34 129.95,71.48 130.86,70.57 130.86,69.29 131.62,68.53 131.62,67.9 131.4,67.67 131.4,67.17 131.72,66.85 131.72,66.45 131.47,66.2 131.47,65.17 131.62,65.02 132.89,65.02 133.11,64.8 133.11,61.99 131.7,60.58 131.7,58.41 v1(131.75,58.36) 131.69,58.31 131.69,55.92 131.96,55.65 131.96,55.26 131.85,55.16 131.58,55.16 131.43,55 131.43,54.7 131.58,54.55 132.56,54.55 132.72,54.39 132.72,54.09 132.56,53.94 132.22,53.94 132.06,53.78 132.06,53.48 132.22,53.33 132.58,53.33 132.69,53.21 132.69,52.83 132.58,52.72 132.22,52.72 132.06,52.56 132.06,52.26 132.22,52.11 132.56,52.11 132.72,51.95 132.72,51.52 132.79,51.45 132.79,49.95 132.57,49.73 132.57,49.08 132.73,48.92 132.73,48.29 129.95,45.51 v1(129.95,43.58)
  L4 w0.152: v1(129.97,68.16) 129.97,68.3 129.52,68.75 129.52,70.81 130.14,71.43 130.14,71.86 129.95,72.05 v1(129.95,74.68) 129.95,77.12 130.16,77.34 130.16,77.83 129.8,78.19 129.8,79.91 130.18,80.3 130.18,80.79 129.83,81.14 v1(129.78,81.14) ; v1(131.75,58.36) 131.75,57.57 131.6,57.42 131.24,57.42 131.09,57.57 131.09,58.12 130.94,58.27 130.63,58.27 130.48,58.12 130.48,57.56 130.33,57.41 128.1,57.41 127.77,57.08 116.45,57.08 110.62,51.26 110.27,51.26 110.13,51.41 110.13,51.83 109.98,51.98 109.7,51.98 109.55,51.83 109.55,51.41 109.4,51.26 106.79,51.26 106.64,51.41 106.64,51.72 106.79,51.87 108.75,51.87 111.23,54.35 111.23,54.55 111,54.78 110.8,54.78 108.5,52.48 98.01,52.48 97.46,53.03 93.72,53.03 92.95,53.81 91.18,53.81 91,53.63 90.77,53.63 89.92,52.78 v1(89.92,52.6) ; v1(129.8,50.09) 129.8,49.88 130.18,49.5 130.18,49.2 129.8,48.81 129.8,47.09 130.16,46.73 130.16,46.24 129.95,46.02 v1(129.95,43.58) 129.95,40.95 130.14,40.76 130.14,40.33 129.52,39.71 129.52,37.7 129.97,37.25 v1(129.97,37.06)
  BOTTOM w0.114: RAM1.N3 126.6,51.33 126.81,51.11 127.34,51.11 128.02,50.44 129.45,50.44 v1(129.8,50.09) ; v1(129.97,37.06) 129.5,37.06 129.24,37.31 127.91,37.31 127.5,37.72 127.18,37.72 RAM3.N3 ; v1(129.97,68.16) 129.68,68.16 129.43,68.42 127.91,68.42 127.5,68.82 127.18,68.82 RAM2.N3 ; v1(129.78,81.14) 129.39,81.54 128,81.54 127.53,82.01 127.02,82.01 126.6,82.43 RAM4.N3 ; CPU1.BB47 89.76,51.99 89.64,52.11 89.64,52.44 89.79,52.6 v1(89.92,52.6)
M_A_A1: length 149.2
  TOP w0.114: v1(129.54,67.33) v2(129.54,66.77) ; v1(132.58,63.29) 132.42,63.12 R1218.2
  L3 w0.152: v1(129.4,42.84) 129.13,43.11 129.13,45.27 131.23,47.37 131.23,48.58 131.65,49 132.01,49 132.31,49.3 132.31,49.88 132.54,50.11 132.54,50.76 132.39,50.91 132.11,50.91 131.8,51.22 131.8,53.63 131.15,54.28 131.15,60.83 132.58,62.26 v1(132.58,63.29) 131.89,63.29 131.71,63.1 131.71,62.25 131.56,62.1 131.12,62.1 130.97,62.25 130.97,63.97 131.12,64.12 132.64,64.12 132.79,64.27 132.79,64.58 132.64,64.73 131.47,64.73 131.17,65.03 131.17,66.45 131.14,66.48 131.14,67.86 131.33,68.05 131.33,68.46 131.03,68.76 130.7,68.76 130.6,68.86 130.6,69.43 130.44,69.59 129.45,69.59 129.29,69.74 129.29,70.05 129.45,70.2 130.26,70.2 130.42,70.35 130.42,70.65 130.25,70.81 128.89,70.81 128.75,70.95 128.75,71.78 128.89,71.92 129.55,71.92 129.69,72.06 129.69,72.69 129.55,72.83 128.91,72.83 128.76,72.99 128.76,73.29 128.91,73.44 129.24,73.44 129.4,73.6 v1(129.4,73.94)
  L4 w0.102: 90.2,55.65 90.07,55.52 90.02,55.52 89.51,55.02 89.51,54.52 v1(88.96,53.97)
  L4 w0.152: v1(132.58,63.29) 132.84,63.03 133.8,63.03 134.01,63.24 134.01,64.13 133.8,64.34 132.76,64.34 132.75,64.35 131.98,64.35 131.83,64.19 131.83,62.53 131.68,62.39 131.22,62.39 131.07,62.54 131.07,63.5 130.91,63.65 128.66,63.65 128.51,63.5 128.51,63.2 128.66,63.04 130.36,63.04 130.51,62.89 130.51,62.54 130.36,62.38 125.12,62.38 124.61,62.9 113.97,62.9 113.38,63.49 111.79,63.49 110.57,64.7 105.47,64.7 104.52,63.76 99.68,63.76 94.56,58.65 93.19,58.65 90.2,55.65 ; v1(129.57,49.37) 129.57,49.1 128.91,48.44 128.91,47.75 129.3,47.36 129.3,46.37 129.4,46.27 v1(129.4,42.84) 129.4,40.98 128.97,40.55 128.97,37.75 129.54,37.19 v1(129.54,36.23) ; v1(129.57,80.47) 129.57,80.2 128.91,79.54 128.91,78.85 129.3,78.46 129.3,77.47 129.4,77.37 v1(129.4,73.94) 129.4,72.08 128.97,71.65 128.97,68.84 129.54,68.27 v1(129.54,67.33)
  BOTTOM w0.114: RAM4.P7 128.29,80.29 129.38,80.29 v1(129.57,80.47) ; CPU1.BC42 88.37,54.13 88.52,54.28 88.81,54.28 88.96,54.13 v1(88.96,53.97) ; RAM3.P7 127.4,35.11 127.96,35.67 128.22,35.67 128.78,36.23 v1(129.54,36.23) ; RAM1.P7 128.27,49.17 129.36,49.17 v1(129.57,49.37) ; RAM2.P7 127.4,66.21 127.96,66.77 128.23,66.77 128.79,67.33 v1(129.54,67.33)
M_A_A2: length 140.2
  TOP w0.114: v1(130.87,81.23) v2(130.47,81.63) ; v1(133.52,58.71) 133.45,58.64 R1219.2
  L3 w0.152: v1(131.04,43.58) 131.04,44.24 130.86,44.42 130.86,44.95 134.89,48.98 134.89,50.79 133.52,52.16 133.52,55.37 133.37,55.52 133.08,55.52 132.93,55.67 132.93,55.98 133.08,56.13 133.37,56.13 133.52,56.28 133.52,56.59 133.37,56.74 133.09,56.74 132.94,56.89 132.94,57.2 133.09,57.35 133.38,57.35 133.55,57.52 133.55,58.68 v1(133.52,58.71) 133.52,59.28 133.37,59.43 133.13,59.43 132.98,59.58 132.98,59.89 133.13,60.04 133.37,60.04 133.52,60.19 133.52,60.62 134.17,61.27 134.17,66.45 134.46,66.74 134.46,68.53 131.04,71.94 131.04,73.91 131.47,74.34 131.47,74.6 131.32,74.75 131.11,74.75 v1(131.04,74.68)
  L4 w0.152: v1(130.86,37.2) 130.14,37.92 130.14,38.27 130.37,38.5 130.37,38.9 130.12,39.14 130.12,39.51 131.04,40.43 v1(131.04,43.58) 131.04,44.04 130.77,44.32 130.77,46.84 130.31,47.3 130.31,48.58 131.07,49.34 131.07,49.79 130.87,49.98 v1(130.87,50.13) ; v1(133.52,58.71) 133.52,58.17 133.37,58.02 133.01,58.02 132.86,58.17 132.86,58.71 132.22,59.35 129.09,59.35 128.75,59.01 127.43,59.01 127.11,58.68 112.33,58.68 108.67,55.03 108.46,55.03 108.24,55.24 108.24,55.46 111,58.22 111,58.43 110.79,58.65 110.57,58.65 106,54.08 97.1,54.08 97.02,53.99 v1(95.93,53.99) ; v1(130.86,68.3) 130.86,68.39 130.14,69.11 130.14,69.37 130.37,69.6 130.37,70 130.12,70.24 130.12,70.61 131.04,71.53 v1(131.04,74.68) 131.04,75.14 130.77,75.42 130.77,77.94 130.31,78.4 130.31,79.68 131.07,80.44 131.07,80.89 130.87,81.08 v1(130.87,81.23)
  BOTTOM w0.089: CPU1.BJ48 92.77,54.15 93,54.38 95,54.38 95.15,54.22 95.15,53.38 95.3,53.23 95.78,53.23 95.93,53.38 v1(95.93,53.99)
  BOTTOM w0.114: RAM4.P3 127.4,82.46 128.05,81.8 129.85,81.8 130.42,81.23 v1(130.87,81.23) ; RAM3.P3 127.4,38.14 128,37.53 129.36,37.53 129.41,37.48 130.75,37.48 130.86,37.36 v1(130.86,37.2) ; RAM1.P3 127.4,51.36 128.05,50.7 129.85,50.7 130.42,50.13 v1(130.87,50.13) ; v1(130.86,68.3) 130.86,68.47 130.75,68.58 130.45,68.58 130.4,68.63 128,68.63 127.4,69.24 RAM2.P3
M_A_A3: length 165.7
  TOP w0.114: R1220.2 139.7,59.52 v1(139.99,59.23) ; v1(133.96,36.26) v2(134.56,36.26)
  L3 w0.152: v1(135.99,73.92) 136.29,73.62 136.94,73.62 137.29,73.27 137.29,72.58 137.5,72.37 137.72,72.37 138.1,72.75 138.32,72.75 138.53,72.54 138.53,72.32 138.15,71.93 138.15,71.72 139.26,70.61 139.26,69.62 139.77,69.11 139.77,59.45 v1(139.99,59.23) 139.99,56.21 139.8,56.02 139.8,47.07 136.11,43.38 136.11,42.93 v1(135.99,42.82)
  L4 w0.152: v1(133.96,36.26) 134.01,36.26 136,38.26 136,42.81 v1(135.99,42.82) 136,42.83 136,47.31 v1(133.9,49.42) ; v1(96.53,54.46) 96.68,54.62 105.78,54.62 110.39,59.22 126.89,59.22 127.21,59.54 128.53,59.54 128.87,59.89 132.44,59.89 132.9,59.43 132.94,59.39 134.98,59.39 136.21,58.16 137.73,58.16 138.8,59.23 v1(139.99,59.23) ; v1(133.96,80.51) 134.01,80.46 134.01,80.29 136,78.29 136,73.93 v1(135.99,73.92) 136,73.91 136,69.36 134.01,67.36 v1(133.96,67.36)
  BOTTOM w0.089: CPU1.BH47 92.08,54.05 92.54,54.51 92.83,54.51 92.95,54.63 95.8,54.63 95.97,54.46 v1(96.53,54.46)
  BOTTOM w0.114: RAM4.N2 126.95,83.75 128.24,83.75 128.54,84.05 128.54,84.24 129.28,84.99 131.53,84.99 132.05,84.47 132.75,84.47 133.96,83.26 v1(133.96,80.51) ; v1(133.96,36.26) 134.04,36.34 134.04,38.93 132.31,40.67 129.28,40.67 128.55,39.93 128.55,39.77 128.24,39.46 126.96,39.46 RAM3.N2 ; v1(133.96,67.36) 134.04,67.44 134.04,68.25 133.93,68.36 133.93,70.14 132.33,71.74 129.24,71.74 128.66,71.17 128.66,70.98 128.22,70.54 126.94,70.54 RAM2.N2 ; v1(133.9,49.42) 133.96,49.49 133.96,52.12 132.19,53.88 129.28,53.88 128.54,53.14 128.54,52.92 128.26,52.65 126.95,52.65 RAM1.N2
M_A_A4: length 146.4
  TOP w0.114: v1(130.02,58.22) 130.79,57.46 R1221.2 ; v1(128.01,67.21) v2(128.01,66.65)
  L3 w0.152: v1(128.06,42.84) 128.06,42.84 128.06,45.15 128.74,45.83 128.74,47.93 129.41,48.6 129.89,48.6 130.37,49.08 130.82,49.08 131.1,49.36 131.1,49.75 131.33,49.98 131.33,50.34 130.88,50.8 129.58,50.8 129.17,51.21 129.17,52.92 129.02,53.07 129.02,53.7 129.56,54.25 129.56,55.89 128.96,56.49 128.96,57.51 129.67,58.22 v1(130.02,58.22) 130.03,58.23 130.03,58.72 129.88,58.87 129.23,58.87 129.08,59.03 129.08,59.33 129.23,59.48 129.88,59.48 130.03,59.64 130.03,59.94 129.88,60.09 129.61,60.09 129.46,60.25 129.46,60.55 129.61,60.7 129.88,60.7 130.03,60.86 130.03,63.59 130.19,63.75 130.19,64.75 129.99,64.96 129.99,67.53 129.5,68.02 129.5,68.24 129.17,68.57 128.9,68.57 128.67,68.34 128.46,68.34 128.24,68.56 128.24,68.77 128.47,69 128.47,69.22 127.89,69.79 127.89,71.51 128.09,71.7 128.09,72.32 128.06,72.35 v1(128.06,73.94)
  L4 w0.152: v1(90.83,54.06) 93.05,54.06 93.83,53.29 97.95,53.29 98.22,53.02 108.17,53.02 112.76,57.6 112.97,57.6 113.19,57.39 113.19,57.17 111.38,55.36 111.38,55.15 111.6,54.93 111.81,54.93 114.49,57.61 114.71,57.61 114.92,57.39 114.92,57.18 110.35,52.61 110.35,52.39 110.57,52.18 110.78,52.18 116.22,57.62 127.55,57.62 127.88,57.94 129.19,57.94 129.47,58.22 v1(130.02,58.22) ; v1(128.36,49.58) 128.26,49.49 128.26,49.1 127.79,48.63 127.79,45.77 128.06,45.5 v1(128.06,42.84) 128.06,42.62 127.88,42.43 127.88,41.69 128.24,41.33 128.24,36.53 128.01,36.3 v1(128.01,36.11) ; v1(128.01,67.21) 128.01,67.4 128.24,67.63 128.24,72.19 127.9,72.53 127.9,73.55 128.06,73.72 v1(128.06,73.94) 128.06,76.6 127.79,76.88 127.79,79.73 128.22,80.15 v1(128.22,80.71)
  BOTTOM w0.114: v1(128.01,67.21) 127.76,67.21 127.62,67.06 127.62,66.91 126.95,66.24 126.95,65.98 126.82,65.85 126.82,65.69 127.11,65.4 RAM2.P8 ; v1(128.01,36.11) 127.79,36.11 127.64,35.96 127.64,35.66 127.43,35.45 127.26,35.45 126.96,35.15 126.96,34.4 127.05,34.3 127.12,34.3 127.12,34.3 RAM3.P8 ; v1(128.36,49.58) 128.23,49.58 127.55,48.9 127.51,48.9 127.05,48.44 127.05,47.85 RAM1.P8 ; v1(90.83,54.06) 90.83,53.85 90.67,53.7 90.34,53.7 90.03,54.01 89.96,54.01 89.76,54.22 89.76,54.59 89.6,54.74 89.02,54.74 CPU1.BD42 ; v1(128.22,80.71) 128.22,80.68 127.53,80 127.51,80 126.96,79.44 126.96,78.95 127.31,78.6 RAM4.P8
M_A_A5: length 156.4
  TOP w0.114: v2(132.99,35.68) 132.98,35.69 v1(132.98,36.24) ; R1222.2 138.51,58.1 v1(138.6,58.18)
  L3 w0.152: v1(134.94,42.69) 134.94,43.14 134.94,43.72 138.68,47.46 138.68,57.14 138.49,57.33 138.49,58.08 138.6,58.18 v1(138.6,58.18) 138.6,66.48 138.19,66.88 138.19,70.07 134.94,73.33 v1(134.94,73.79)
  L4 w0.152: v1(132.98,67.34) 132.98,68.37 133.23,68.62 133.71,68.62 134.94,69.85 v1(134.94,73.79) 134.94,77.85 133,79.79 v1(133,80.53) ; v1(132.98,36.24) 132.98,37.27 133.23,37.52 133.71,37.52 134.94,38.75 v1(134.94,42.69) 134.94,46.75 133,48.69 v1(133,49.43) ; v1(94.62,53.82) 95.38,53.82 95.64,53.56 98.2,53.56 98.22,53.55 106.23,53.55 107.51,54.83 107.72,54.83 107.94,54.62 107.94,54.4 107.55,54.01 107.55,53.79 107.76,53.58 107.98,53.58 112.55,58.15 127.33,58.15 127.66,58.48 128.97,58.48 129.31,58.82 132,58.82 132.32,58.5 132.32,57.59 132.49,57.41 133.54,57.41 134.05,57.93 134.05,58.7 134.2,58.85 134.59,58.85 134.74,58.7 134.74,58.32 134.9,58.17 135.45,58.17 136.02,57.6 138.48,57.6 138.6,57.71 v1(138.6,58.18)
  BOTTOM w0.089: v1(94.62,53.82) 94.62,54.11 94.55,54.19 93.15,54.19 92.79,53.82 92.4,53.82 92.32,53.75 CPU1.BH48
  BOTTOM w0.114: RAM1.P2 127.72,52.3 128.1,51.92 130.34,51.92 130.92,52.5 132.37,52.5 132.92,51.95 132.92,51.47 132.74,51.29 132.74,50.94 133.1,50.58 133.1,50.12 133,50.03 v1(133,49.43) ; RAM3.P2 127.64,39.1 127.99,38.75 130.3,38.75 130.85,39.29 132.55,39.29 133.12,38.72 133.12,38.32 132.84,38.04 132.84,37.85 133.01,37.68 133.01,36.27 v1(132.98,36.24) ; v1(133,80.53) 133,81.78 132.65,82.12 132.65,82.31 132.92,82.57 132.92,83.05 132.36,83.62 130.93,83.62 130.34,83.02 128.1,83.02 127.72,83.4 RAM4.P2 ; v1(132.98,67.34) 133.01,67.37 133.01,68.72 132.89,68.83 132.89,69.19 133.13,69.43 133.13,69.8 132.54,70.39 130.85,70.39 130.3,69.85 127.99,69.85 127.64,70.2 RAM2.P2
M_A_A6: length 150.3
  TOP w0.114: v1(130.51,42.84) 130.51,42.41 v2(130.63,42.28) ; v1(133.23,61.36) 133.15,61.44 R1223.2
  L3 w0.152: v1(130.51,73.94) 130.51,73.46 130.68,73.3 130.68,72.81 130.51,72.65 130.51,72.11 130.75,71.86 130.75,71.65 130.55,71.45 130.55,71.23 130.77,71.02 130.98,71.02 131.18,71.22 131.4,71.22 131.65,70.96 131.65,70.79 131.5,70.64 131.5,70.36 131.66,70.21 132.1,70.21 132.25,70.06 132.25,69.79 132.1,69.64 131.88,69.64 131.73,69.49 131.73,68.94 131.87,68.8 132.3,68.8 132.56,69.07 133.15,69.07 133.48,68.74 133.48,68.45 133.33,68.3 132.7,68.3 132.55,68.15 132.55,67.06 132.75,66.85 132.98,66.85 133.13,66.7 133.13,66.23 132.98,66.08 131.87,66.08 131.72,65.92 131.72,65.62 131.87,65.47 133.49,65.47 133.64,65.31 133.64,61.53 133.47,61.36 v1(133.23,61.36) 132.4,60.52 132.4,55.26 132.97,54.69 132.97,51.96 134.35,50.57 134.35,49.23 130.51,45.39 v1(130.51,42.84)
  L4 w0.089: v1(89.45,53.04) 89.45,53.78 90.64,54.97
  L4 w0.152: v1(130.42,36.31) 130.42,37.27 129.78,37.91 129.78,39.55 130.51,40.29 v1(130.51,42.84) 130.51,46.74 130.05,47.2 130.05,48.7 130.62,49.27 v1(130.62,49.53) ; v1(130.42,67.41) 130.42,68.39 129.78,69.03 129.78,70.65 130.51,71.39 v1(130.51,73.94) 130.51,77.84 130.05,78.3 130.05,79.8 130.62,80.37 v1(130.62,80.63) ; v1(133.23,61.36) 133.23,61.67 133.12,61.79 132.57,61.79 132.27,61.49 128.78,61.49 128.48,61.79 126.3,61.79 125.96,61.44 125.31,61.44 124.51,62.25 113.9,62.25 113.73,62.42 106.06,62.42 105.91,62.57 105.91,62.88 106.06,63.03 110.13,63.03 110.28,63.18 110.28,63.49 110.13,63.64 105.91,63.64 104.96,62.69 100.12,62.69 94.76,57.34 93.96,57.34 92.4,55.78 91.46,55.78 90.64,54.97
  BOTTOM w0.114: v1(130.62,49.53) 130.37,49.53 129.76,48.93 128.35,48.93 127.83,48.41 127.83,47.87 RAM1.R8 ; CPU1.BB46 89.11,52.5 88.96,52.65 88.96,52.89 89.11,53.04 v1(89.45,53.04) ; RAM3.R8 128.01,34.3 127.74,34.57 127.74,35.14 128.05,35.45 128.37,35.45 128.64,35.73 128.66,35.73 129.86,35.73 130.42,36.29 v1(130.42,36.31) ; v1(130.42,67.41) 130.42,67.39 129.86,66.83 128.75,66.83 128.47,66.55 128.05,66.55 127.74,66.24 127.74,65.67 128.01,65.4 RAM2.R8 ; RAM4.R8 127.83,78.97 127.83,79.51 128.35,80.03 129.76,80.03 130.37,80.63 v1(130.62,80.63)
M_A_A7: length 162.2
  TOP w0.114: R1224.2 138.85,57.25 139.24,57.64 v1(139.24,58.69) ; v1(133.63,36.83) 133.88,37.08 v2(133.88,37.42)
  L3 w0.152: v1(135.47,74.46) 135.47,74.01 135.47,73.55 135.93,73.09 136.34,73.09 136.62,72.81 136.62,72.4 138.73,70.29 138.73,67.1 139.13,66.7 139.13,58.8 v1(139.24,58.69) 139.3,58.69 139.45,58.54 139.45,58.16 139.3,58.01 139.18,58.01 139.02,57.85 139.02,57.55 139.18,57.4 139.3,57.4 139.45,57.24 139.45,56.94 139.22,56.71 139.22,47.24 135.47,43.49 v1(135.47,43.36)
  L4 w0.152: v1(133.46,49.89) 133.44,49.88 133.44,49.01 135.47,46.97 135.47,43.37 v1(135.47,43.36) 135.47,38.53 133.77,36.83 v1(133.63,36.83) ; v1(133.63,67.93) 133.77,67.93 135.47,69.63 v1(135.47,74.46) 135.47,78.07 133.43,80.11 133.43,80.73 133.46,80.76 v1(133.46,81) ; v1(90.95,52.85) 91.31,53.21 92.76,53.21 93.52,52.45 95.93,52.45 97.5,50.88 100.55,50.88 100.75,50.68 100.75,50.1 101.19,49.66 111.29,49.66 113.59,51.96 113.59,52.22 117.13,55.76 128.71,55.76 128.76,55.81 129.91,55.81 131.04,54.68 131.04,53.63 131.54,53.13 132.91,53.13 135.15,55.37 135.15,56.54 135.67,57.06 138.7,57.06 139.24,57.6 v1(139.24,58.69)
  BOTTOM w0.114: v1(133.46,81) 133.46,81.26 133.66,81.46 133.66,83.24 132.64,84.25 131.96,84.25 131.69,84.52 130.86,84.52 130.09,83.75 128.81,83.75 128.46,83.4 RAM4.R2 ; v1(133.63,36.83) 133.63,36.86 133.73,36.96 133.73,38.94 132.33,40.33 130.56,40.33 129.78,39.56 128.83,39.56 128.37,39.1 RAM3.R2 ; v1(90.95,52.85) 90.71,53.09 90.71,53.15 CPU1.BE46 ; v1(133.46,49.89) 133.46,50.16 133.73,50.42 133.73,52.04 132.41,53.36 130.68,53.36 129.96,52.65 128.81,52.65 128.46,52.3 RAM1.R2 ; RAM2.R2 128.37,70.2 128.83,70.66 129.73,70.66 130.54,71.47 132.29,71.47 133.71,70.05 133.71,68.01 v1(133.63,67.93)
M_A_A8: length 162.9
  TOP w0.114: R1225.2 138.85,59.56 138.58,59.28 137.96,59.28 v1(137.91,59.33) ; v1(132.68,38.52) 133.23,38.52 v2(133.24,38.53)
  L3 w0.152: v1(134.41,75.07) 134.4,75.07 134.4,73.11 137.66,69.85 137.66,66.66 138.06,66.26 138.06,61.45 137.89,61.27 137.89,59.6 137.89,59.59 137.89,59.35 v1(137.91,59.33) 137.98,59.26 137.98,58.88 138.06,58.8 138.06,58.41 137.9,58.25 137.87,58.25 137.72,58.11 137.72,57.31 138.15,56.88 138.15,47.68 134.43,43.97 v1(134.41,43.97)
  L4 w0.152: v1(132.26,51.46) 132.26,51.32 132.56,51.02 132.56,49 132.74,48.82 132.74,48.19 134.4,46.53 134.4,43.97 v1(134.41,43.97) 134.4,43.97 134.4,39.31 134.25,39.16 134.07,39.16 133.79,39.43 133.58,39.43 133.34,39.2 133.34,38.98 133.77,38.56 133.77,38.34 133.52,38.1 133.31,38.1 132.88,38.52 v1(132.68,38.52) ; v1(132.68,69.62) 132.88,69.62 133.31,69.2 133.52,69.2 133.77,69.44 133.77,69.66 133.34,70.09 133.34,70.3 133.58,70.54 133.79,70.54 134.07,70.26 134.25,70.26 134.4,70.41 134.4,75.07 v1(134.41,75.07) 134.4,75.07 134.4,77.63 132.74,79.29 132.74,79.93 132.56,80.11 132.56,82.12 132.26,82.42 v1(132.26,82.56) ; v1(137.91,59.33) 137.91,59.1 137.5,58.69 136.43,58.69 135.2,59.92 133.16,59.92 132.66,60.42 128.65,60.42 128.3,60.08 126.99,60.08 126.67,59.75 110.16,59.75 106.78,56.37 102.99,56.37 102.84,56.22 102.84,55.91 102.99,55.76 105.53,55.76 105.68,55.61 105.68,55.3 105.53,55.15 100.14,55.15 99.99,55.3 99.99,55.77 99.84,55.92 99.53,55.92 99.38,55.77 99.38,55.3 99.23,55.15 96.58,55.15 95.91,54.48 92.33,54.48 92.18,54.63 92.18,55.34 92.03,55.49 91.72,55.49 91.57,55.34 91.57,54.65 91.42,54.5 90.52,54.5 89.95,53.92 v1(89.95,53.44)
  BOTTOM w0.114: RAM4.T8 132.13,78.6 132.7,79.17 132.7,79.87 132.51,80.05 132.51,80.89 132.75,81.13 132.75,81.72 132.42,82.05 132.42,82.39 v1(132.26,82.56) ; RAM2.T8 131.79,65.4 132.69,66.3 132.69,66.97 132.57,67.09 132.57,67.72 132.79,67.94 132.79,68.6 132.53,68.86 132.53,69.48 v1(132.68,69.62) ; RAM3.T8 131.79,34.3 132.69,35.2 132.69,35.87 132.57,35.99 132.57,36.6 132.79,36.83 132.79,37.56 132.53,37.81 132.53,38.38 v1(132.68,38.52) ; CPU1.BD44 89.95,53.51 v1(89.95,53.44) ; RAM1.T8 132.13,47.5 132.7,48.07 132.7,48.77 132.51,48.95 132.51,49.79 132.78,50.06 132.78,50.59 132.42,50.95 132.42,51.29 v1(132.26,51.46)
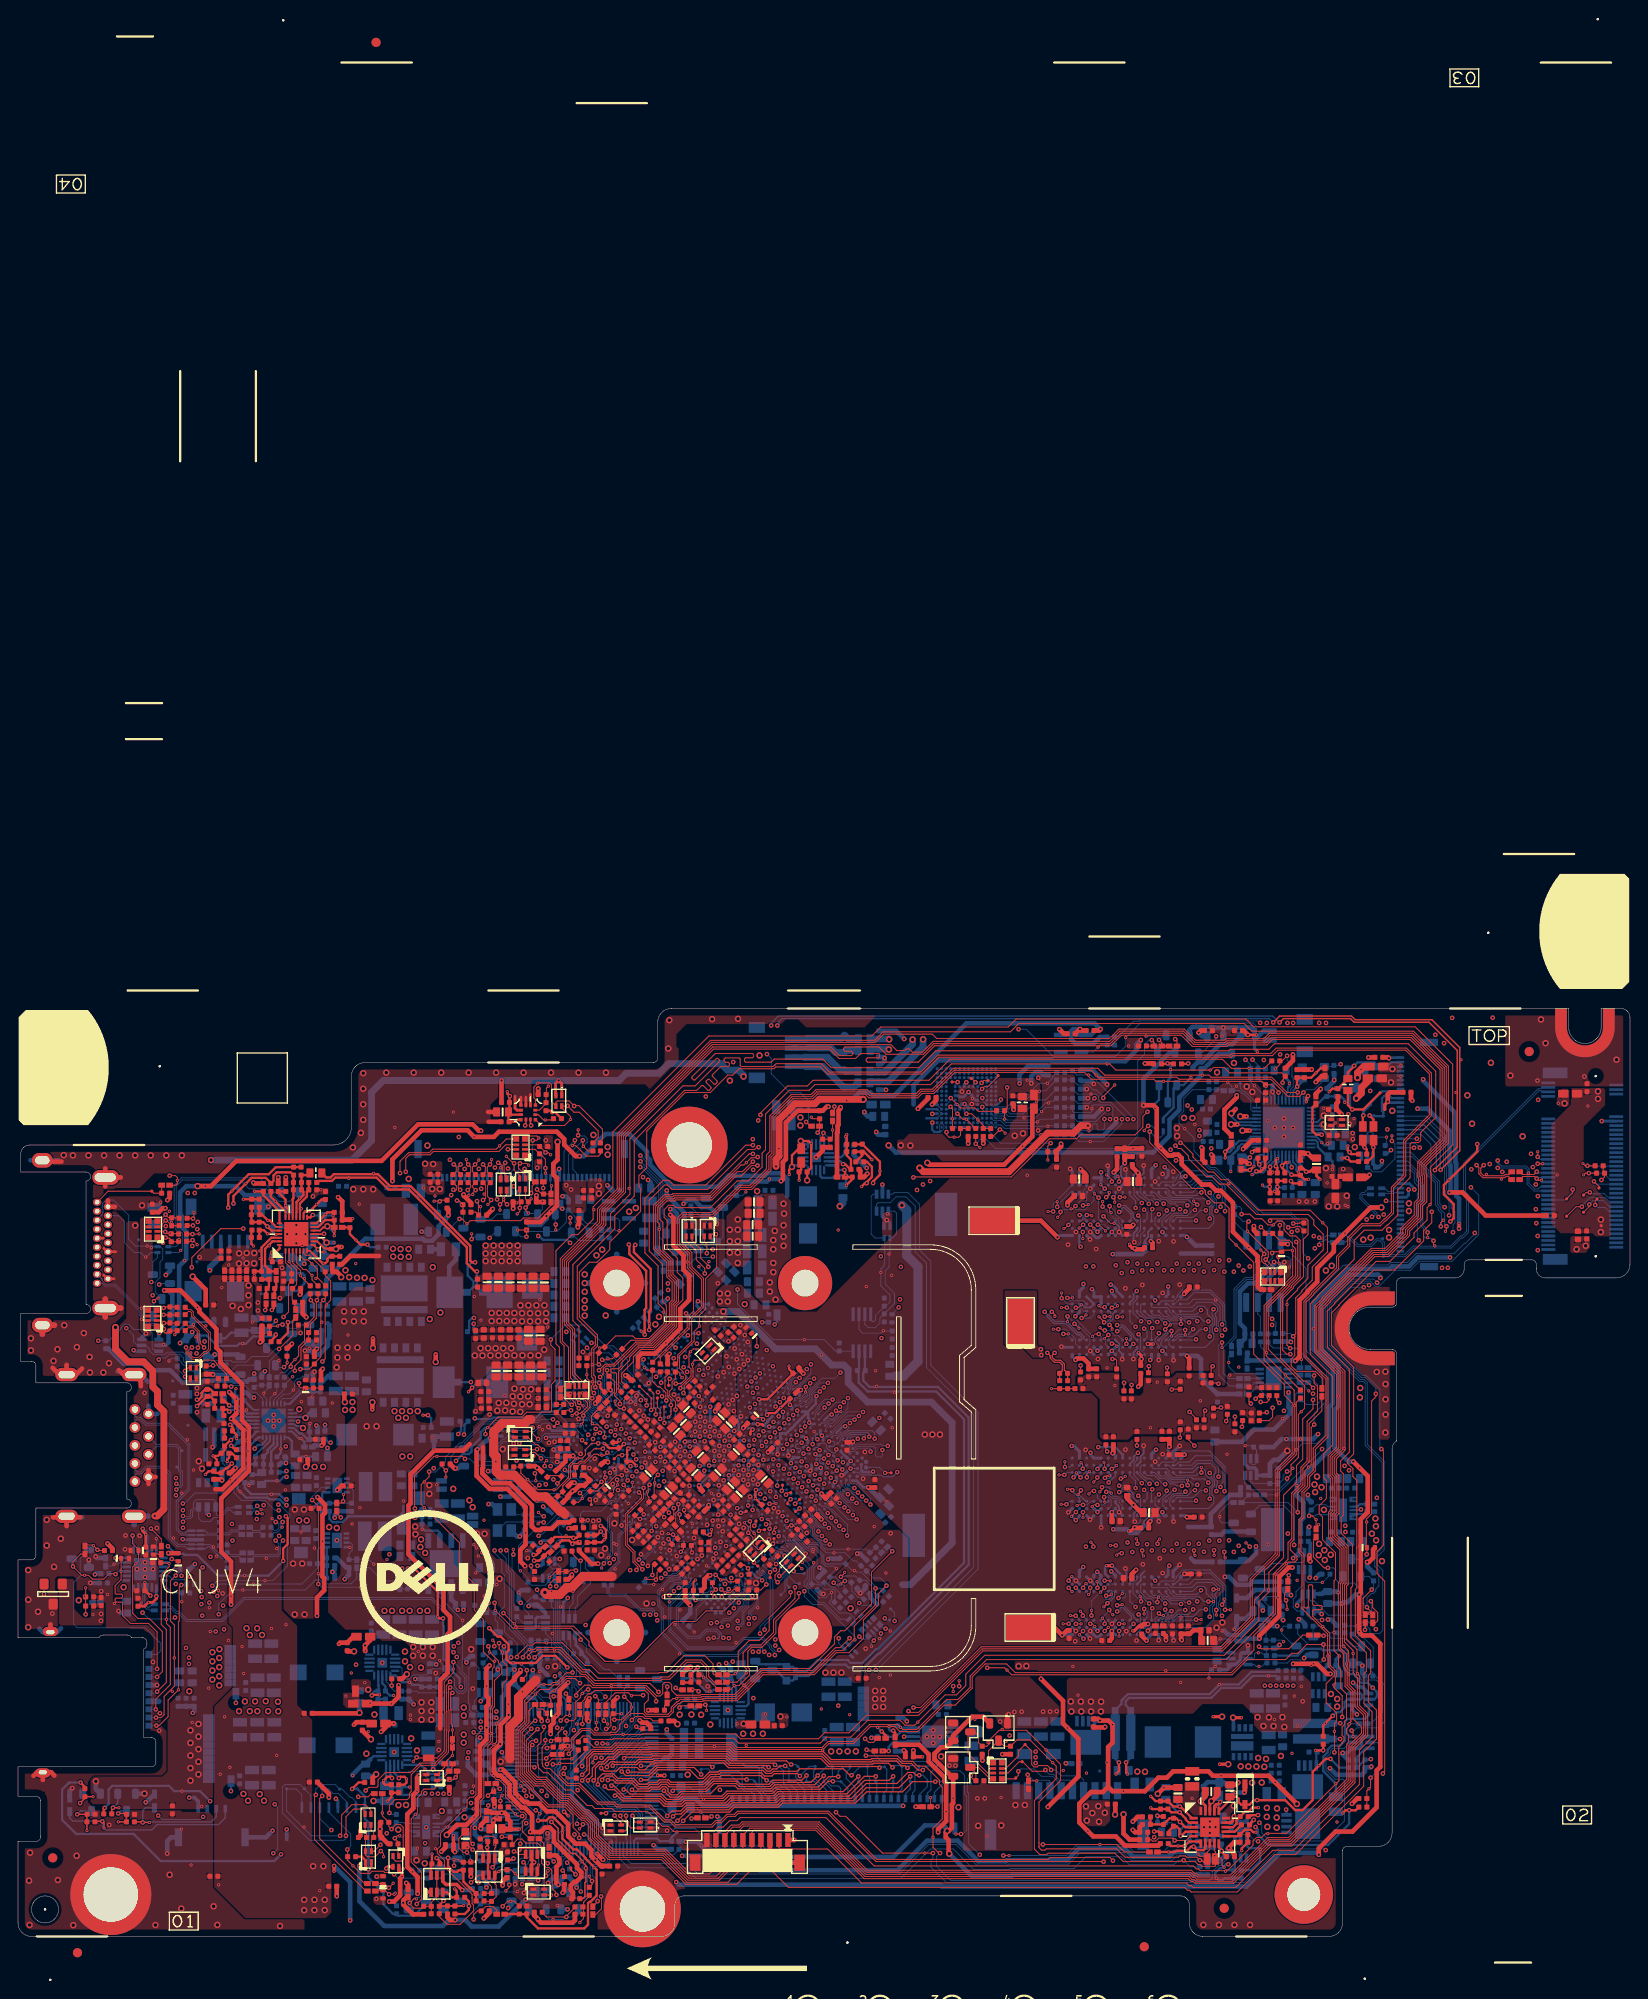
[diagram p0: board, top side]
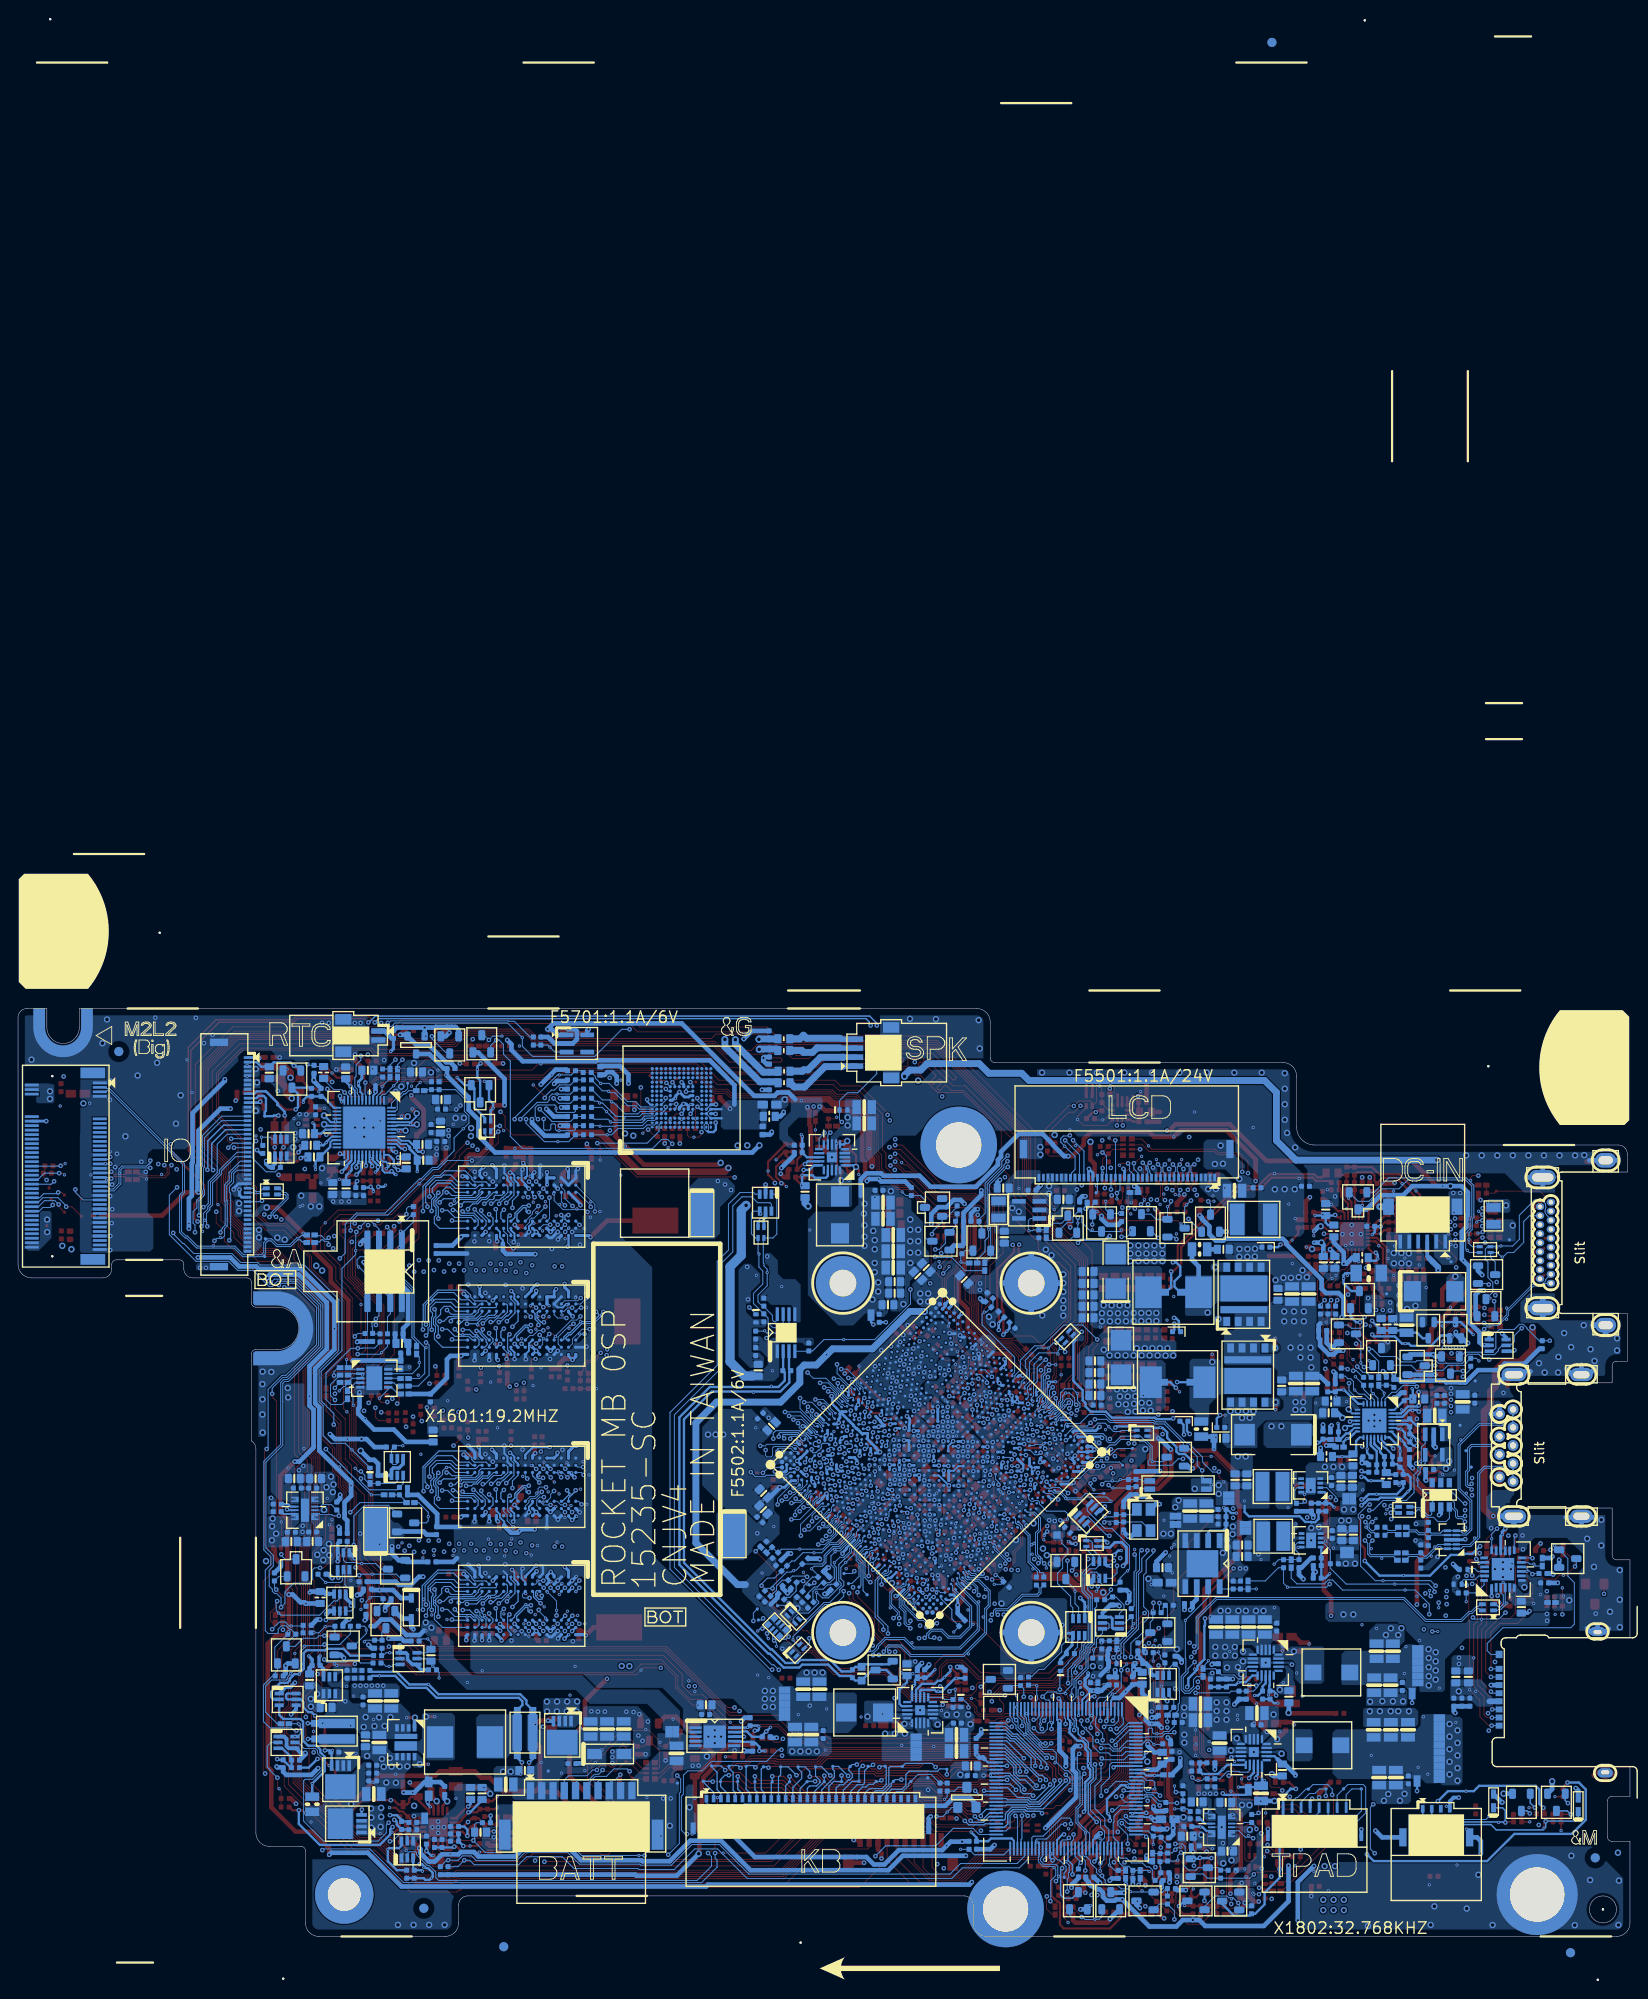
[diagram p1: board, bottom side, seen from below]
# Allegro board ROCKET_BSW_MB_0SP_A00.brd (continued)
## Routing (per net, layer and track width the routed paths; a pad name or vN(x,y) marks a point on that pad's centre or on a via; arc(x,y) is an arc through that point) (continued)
M_A_A9: length 143.6
  TOP w0.114: v1(131.33,51.49) v2(131.33,52.06) ; R1226.2 135.05,57.69 v1(135.06,57.7)
  L3 w0.152: v1(132.2,43.94) 132.2,44.78 136.02,48.6 136.02,51.59 135.89,51.72 135.89,53.23 135.78,53.34 135.29,53.34 135.19,53.45 135.19,54.45 135.07,54.56 134.72,54.56 134.59,54.69 134.59,55.05 134.72,55.17 135.17,55.17 135.29,55.3 135.29,55.66 135.17,55.78 134.75,55.78 134.62,55.91 134.62,56.29 134.75,56.41 135.14,56.41 135.29,56.57 135.29,56.87 135.14,57.02 134.73,57.02 134.62,57.14 134.62,57.62 134.7,57.7 v1(135.06,57.7) 135.14,57.78 135.14,60.3 135.24,60.4 135.24,66.01 135.53,66.29 135.53,68.97 132.2,72.29 v1(132.2,75.04)
  L4 w0.152: v1(131.33,82.59) 131.33,82.44 131.33,82.44 131.33,80.27 131.32,80.25 131.32,78.49 132.2,77.6 v1(132.2,75.04) 132.2,73.66 132.48,73.38 132.48,73.07 132.33,72.92 131.75,72.92 131.6,72.77 131.6,72.46 131.75,72.31 132.38,72.31 132.53,72.16 132.53,71.85 132.38,71.7 131.99,71.7 131.15,70.85 131.15,69.88 131.29,69.73 v1(131.29,69.52) ; v1(131.29,38.42) 131.29,38.63 131.15,38.78 131.15,39.75 131.99,40.6 132.38,40.6 132.53,40.75 132.53,41.06 132.38,41.21 131.75,41.21 131.6,41.36 131.6,41.67 131.75,41.82 132.33,41.82 132.48,41.97 132.48,42.28 132.2,42.56 v1(132.2,43.94) 132.2,46.5 131.32,47.39 131.32,49.15 131.33,49.17 131.33,51.34 131.33,51.34 v1(131.33,51.49) ; v1(135.06,57.7) 135.06,57.42 134.62,56.98 134.62,55.59 134.15,55.12 133.77,55.12 133.56,54.92 133.56,54.54 132.93,53.9 131.77,53.9 131.62,54.06 131.62,54.36 131.77,54.51 132.68,54.51 132.83,54.67 132.83,54.97 132.68,55.12 131.48,55.12 130.92,55.69 130.92,56.19 130.77,56.34 128.54,56.34 128.21,56.02 116.89,56.02 111.07,50.2 102.68,50.2 102.53,50.35 102.53,50.65 102.68,50.81 104.3,50.81 104.44,50.94 104.44,51.28 104.3,51.41 102.08,51.41 101.89,51.23 101.89,50.32 101.77,50.2 101.41,50.2 101.28,50.32 101.28,51.23 101.09,51.41 97.7,51.41 v1(97.58,51.54)
  BOTTOM w0.114: RAM4.R3 128.56,82.24 130.75,82.24 131.1,82.59 v1(131.33,82.59) ; v1(131.29,38.42) 130.83,37.96 128.54,37.96 RAM3.R3 ; v1(131.29,69.52) 130.83,69.06 128.54,69.06 RAM2.R3 ; CPU1.BE52 93.27,51.53 93.57,51.23 94.69,51.23 94.73,51.19 95.86,51.19 96.02,51.03 97.07,51.03 v1(97.58,51.54) ; v1(131.33,51.49) 131.1,51.49 130.75,51.14 128.56,51.14 RAM1.R3
M_A_A10: length 147.7
  TOP w0.114: v1(122.76,61.46) 122.74,61.44 R1227.2 ; v1(124.98,36.36) v2(124.98,35.8)
  L3 w0.152: v1(123.67,42.67) 123.67,42.67 123.67,44.7 123.39,44.98 123.39,46.15 124.29,47.05 124.29,48.11 123.58,48.82 123.58,52.7 122.65,53.63 122.64,53.63 122.45,53.81 122.45,54.39 123.05,54.99 123.05,59.87 122.9,60.02 122.59,60.02 122.44,59.87 122.44,55.03 122.29,54.88 121.98,54.88 121.83,55.03 121.83,60.28 122.2,60.65 122.89,60.65 123.04,60.81 123.04,61.31 122.89,61.46 v1(122.76,61.46) 121.29,61.46 121.13,61.31 121.13,60.35 120.98,60.19 120.63,60.19 120.48,60.35 120.48,61.12 120.38,61.22 120.38,62.07 120.53,62.22 124.07,62.22 124.22,62.37 124.22,62.68 124.07,62.83 120.37,62.83 120.22,62.98 120.22,63.29 120.37,63.44 122.93,63.44 123.08,63.59 123.08,64.41 123.46,64.79 123.46,65.2 123.31,65.35 122.9,65.35 122.75,65.2 122.75,64.66 122.6,64.51 122.29,64.51 122.14,64.66 122.14,65.87 122.57,66.29 122.93,66.29 123.05,66.4 123.05,71.13 123.35,71.42 123.35,72.29 123.5,72.45 124.3,72.45 124.45,72.6 124.45,72.9 124.3,73.06 123.56,73.06 123.41,73.21 123.41,73.62 123.56,73.77 v1(123.67,73.77)
  L4 w0.152: v1(124.98,67.46) 124.98,67.8 125.1,67.92 125.1,68.72 124.76,69.06 124.76,70.88 124.5,71.14 123.95,71.14 123.63,71.46 123.63,72.07 123.95,72.39 123.95,72.89 123.67,73.17 123.67,73.77 v1(123.67,73.77) 123.67,73.77 123.67,75.24 124.46,76.02 124.46,77.71 125.15,78.41 125.15,80.37 124.98,80.54 v1(124.98,80.66) ; v1(93.87,55.28) 93.87,55.58 94.08,55.79 94.08,56.01 93.89,56.19 93.89,56.41 94.11,56.63 94.32,56.63 94.51,56.44 94.73,56.44 95.12,56.83 95.93,56.83 99.5,60.41 104.45,60.41 104.61,60.56 104.61,60.86 104.45,61.02 100.59,61.02 100.44,61.17 100.44,61.47 100.59,61.63 105.3,61.63 105.57,61.35 122.65,61.35 v1(122.76,61.46) ; v1(124.98,49.56) 124.98,49.44 125.15,49.27 125.15,47.31 124.46,46.61 124.46,44.92 123.67,44.14 123.67,42.67 v1(123.67,42.67) 123.67,42.07 123.95,41.79 123.95,41.29 123.6,40.93 123.6,40.4 123.95,40.04 124.5,40.04 124.76,39.78 124.76,37.96 125.1,37.62 125.1,36.82 124.98,36.69 v1(124.98,36.36)
  BOTTOM w0.114: RAM1.L7 125.31,48.61 125.31,49.24 v1(124.98,49.56) ; RAM3.L7 125.31,35.41 125.31,36.04 v1(124.98,36.36) ; RAM4.L7 125.31,79.71 125.31,80.34 v1(124.98,80.66) ; CPU1.BJ45 91.54,55.11 91.62,55.03 91.82,55.03 92.04,55.26 92.04,55.33 92.42,55.71 93.96,55.71 94.06,55.6 94.06,55.38 93.96,55.28 v1(93.87,55.28) ; RAM2.L7 125.31,66.51 125.31,67.14 v1(124.98,67.46)
M_A_A11: length 144.7
  TOP w0.114: v1(132.74,42.86) 132.74,42.31 v2(132.75,42.3) ; R1228.2 135.92,56.66 v1(135.83,56.57)
  L3 w0.152: v1(132.74,73.96) 132.74,72.51 136.06,69.19 136.06,66.07 135.83,65.84 v1(135.83,56.57) 135.88,56.52 136.25,56.52 136.43,56.34 136.43,55.97 136.3,55.84 135.94,55.84 135.83,55.73 135.83,55.34 135.94,55.23 136.45,55.23 136.55,55.13 136.55,54.72 136.45,54.62 135.82,54.62 135.72,54.52 135.72,54.11 135.82,54.01 136.41,54.01 136.54,53.88 136.54,52.98 136.42,52.86 136.42,51.94 136.55,51.81 136.55,48.38 132.75,44.57 132.75,43.77 133.13,43.38 133.13,43.02 132.97,42.86 v1(132.74,42.86)
  L4 w0.102: 94.78,50.43 93.99,51.22 92.08,51.22 91.65,50.79 91.23,50.79 90.86,51.16 v1(90.86,51.71)
  L4 w0.152: 94.78,50.43 97.18,48.03 98.35,48.03 100.07,46.31 112.82,46.31 113.79,47.28 113.79,49.5 114.86,50.57 114.86,52.05 115.99,53.18 117.01,53.18 118.58,54.75 122.85,54.75 123.36,54.23 123.36,53.85 123.11,53.6 123.11,52.26 123.31,52.05 130.07,52.05 130.44,52.42 130.44,52.79 130.59,52.95 130.9,52.95 131.05,52.79 131.05,52.44 131.2,52.29 132.83,52.29 135.83,55.29 v1(135.83,56.57) ; v1(131.83,80.6) 131.83,80.23 131.57,79.97 131.57,78.72 132.56,77.73 132.56,75.54 132.74,75.37 v1(132.74,73.96) 132.74,73.6 132.81,73.53 132.81,71.77 131.74,70.7 131.74,69.04 131.55,68.86 131.55,68.11 131.83,67.83 v1(131.83,67.4) ; v1(131.83,49.5) 131.83,49.13 131.57,48.87 131.57,47.62 132.56,46.63 132.56,44.44 132.74,44.27 v1(132.74,42.86) 132.74,42.5 132.81,42.43 132.81,40.67 131.74,39.6 131.74,37.94 131.58,37.79 131.58,36.96 131.83,36.72 v1(131.83,36.3)
  BOTTOM w0.114: RAM2.R7 128.48,66.2 128.89,66.61 130.43,66.61 131.21,67.4 v1(131.83,67.4) ; CPU1.BB49 90.65,51.49 v1(90.86,51.71) ; RAM1.R7 128.61,48.71 130.42,48.71 131.21,49.5 v1(131.83,49.5) ; v1(131.83,36.3) 131.21,36.3 130.43,35.51 128.73,35.51 128.32,35.1 RAM3.R7 ; v1(131.83,80.6) 131.21,80.6 130.42,79.81 128.61,79.81 RAM4.R7
M_A_A12: length 140.1
  TOP w0.114: R1229.2 128.99,55.43 v1(128.94,55.38) ; v1(127.32,67.38) 127.82,67.88 v2(127.88,67.88)
  L3 w0.152: v1(127.2,42.84) 127,43.04 127,44.11 127.81,44.93 127.81,47.9 128.8,48.9 129.82,48.9 130.07,49.15 130.07,49.66 130.26,49.85 130.26,50.36 130.1,50.52 128.59,50.52 128.44,50.67 128.44,51.04 128.59,51.2 128.76,51.2 128.91,51.35 128.91,51.65 128.76,51.8 127.98,51.8 127.83,51.96 127.83,52.26 127.98,52.41 128.71,52.41 128.86,52.57 128.86,52.87 128.71,53.02 128,53.02 127.84,53.18 127.84,53.51 128,53.66 128.34,53.66 128.49,53.81 128.49,54.45 128.12,54.82 127.04,54.82 126.89,54.98 126.89,55.28 127.04,55.43 128.36,55.43 128.42,55.38 v1(128.94,55.38) 128.93,55.38 129,55.46 129,55.7 128.42,56.28 128.43,56.29 128.43,56.96 128.28,57.12 127.73,57.12 127.58,57.27 127.58,57.57 127.73,57.73 128.28,57.73 128.43,57.88 128.43,58.18 128.28,58.34 127.78,58.34 127.63,58.49 127.63,58.79 127.78,58.95 128.28,58.95 128.43,59.1 128.43,60.16 128.92,60.64 128.92,61.55 129.41,62.05 129.41,64.08 128.97,64.52 128.97,67.42 127.47,68.92 127.47,71.72 127.04,72.15 127.04,73.79 v1(127.2,73.94)
  L4 w0.102: v1(91.55,52.63) 91.83,52.36 92.73,52.36 92.93,52.16
  L4 w0.152: v1(127.32,36.28) 127.75,36.71 127.75,37.38 127.53,37.6 127.53,40.55 127.2,40.89 v1(127.2,42.84) 127.2,43.69 127.49,43.99 127.49,47.24 127.25,47.49 127.25,48.54 127.48,48.77 v1(127.48,49.48) ; 92.93,52.16 95.31,52.16 95.51,51.96 95.51,51.3 95.87,50.94 96.85,50.94 97.01,50.78 97.01,49.77 97.16,49.62 97.46,49.62 97.62,49.77 97.62,50.19 97.77,50.34 98.07,50.34 98.23,50.19 98.23,49.79 98.38,49.64 98.68,49.64 98.84,49.79 98.84,50.19 98.99,50.34 100,50.34 100.12,50.22 100.12,49.52 99.74,49.14 99.74,48.92 99.96,48.71 100.17,48.71 100.67,49.21 100.89,49.21 101.1,48.99 101.1,48.78 100.71,48.38 100.71,48.16 100.92,47.95 101.14,47.95 101.53,48.34 101.75,48.34 102.18,47.91 106.56,47.91 106.71,48.06 106.71,48.37 106.56,48.52 102.47,48.52 102.32,48.67 102.32,48.98 102.47,49.13 111.51,49.13 113.97,51.6 113.97,52.25 117.24,55.51 124.58,55.51 124.71,55.38 v1(128.94,55.38) ; v1(127.32,67.38) 127.75,67.81 127.75,68.48 127.53,68.7 127.53,71.65 127.2,71.99 v1(127.2,73.94) 127.2,74.79 127.49,75.09 127.49,78.34 127.25,78.59 127.25,79.64 127.49,79.88 v1(127.49,80.58)
  BOTTOM w0.114: v1(127.48,49.48) 127.48,49.27 126.6,48.38 RAM1.N7 ; v1(127.32,36.28) 127.4,36.2 127.4,35.9 126.81,35.31 RAM3.N7 ; RAM4.N7 126.6,79.49 127.49,80.39 v1(127.49,80.58) ; CPU1.BF48 91.39,52.79 v1(91.55,52.63) ; v1(127.32,67.38) 127.4,67.3 127.4,67 RAM2.N7
M_A_A13: length 159.8
  TOP w0.114: v1(137.35,59.68) 137.71,60.04 R1230.2 ; v2(133.98,42.02) 133.87,42.12 v1(133.87,42.69)
  L3 w0.152: v1(133.87,42.69) 133.87,44.17 137.62,47.92 137.62,56.66 137.16,57.12 137.16,58.31 137.36,58.51 137.36,59.37 137.35,59.37 v1(137.35,59.68) 136.93,60.1 136.93,61.36 137.08,61.52 137.38,61.52 137.53,61.67 137.53,61.97 137.38,62.13 137.08,62.13 136.93,62.28 136.93,62.58 137.08,62.74 137.38,62.74 137.53,62.89 137.53,63.19 137.38,63.35 137.08,63.35 136.93,63.5 136.93,63.8 137.08,63.96 137.38,63.96 137.53,64.11 137.53,64.41 137.38,64.57 137.08,64.57 136.93,64.72 136.93,65.02 137.08,65.18 137.38,65.18 137.53,65.33 137.53,66.04 137.38,66.18 137.26,66.18 137.13,66.32 137.13,69.63 133.87,72.89 v1(133.87,73.79)
  L4 w0.152: v1(132.26,66.59) 132.26,67.1 132.54,67.39 132.54,68.52 132.24,68.82 132.24,69.97 133.87,71.6 v1(133.87,73.79) 133.87,75.85 133.71,76.01 133.27,76.01 133.12,76.16 133.12,76.56 133.27,76.72 133.71,76.72 133.86,76.87 133.86,77.17 133.71,77.33 133.28,77.33 133.14,77.46 133.14,77.98 132.08,79.03 132.08,79.38 132.26,79.56 v1(132.26,79.68) ; v1(137.35,59.68) 137.9,60.23 139.07,60.23 139.23,60.38 139.23,60.69 139.07,60.84 138.14,60.84 137.99,60.99 137.99,61.29 138.14,61.45 139.07,61.45 139.22,61.6 139.22,61.9 139.07,62.06 138.1,62.06 137.83,62.33 132.87,62.33 132.67,62.13 125.01,62.13 124.49,62.64 113.86,62.64 113.55,62.95 111.57,62.95 110.35,64.17 105.69,64.17 104.74,63.23 99.9,63.23 94.26,57.59 93.76,57.59 92.33,56.17 91.24,56.17 v1(90.02,54.95) ; v1(132.26,48.58) 132.26,48.46 132.08,48.28 132.08,47.93 133.15,46.87 133.15,46.47 133.28,46.33 133.71,46.33 133.87,46.18 133.87,45.87 133.71,45.72 133.28,45.72 133.12,45.57 133.12,45.16 133.28,45.01 133.72,45.01 133.87,44.86 v1(133.87,42.69) 133.87,40.5 132.24,38.87 132.24,37.72 132.54,37.42 132.54,36.29 132.26,36 v1(132.26,35.49)
  BOTTOM w0.114: RAM2.T3 130.37,69.4 130.91,69.94 131.62,69.94 132,69.56 132,69.07 132.55,68.52 132.55,68.02 132.26,67.73 132.26,66.6 v1(132.26,66.59) ; RAM1.T3 130.37,51.5 130.95,52.08 131.38,52.08 131.78,51.67 131.78,51.28 132.55,50.51 132.55,50.14 132.26,49.85 v1(132.26,48.58) ; RAM3.T3 130.37,38.3 130.91,38.84 131.62,38.84 131.88,38.58 131.88,38.07 132.55,37.41 132.55,36.91 132.26,36.63 132.26,35.5 v1(132.26,35.49) ; CPU1.BF44 90.49,54.39 90.64,54.54 90.64,54.8 90.49,54.95 v1(90.02,54.95) ; v1(132.26,79.68) 132.26,80.96 132.52,81.22 132.52,81.65 131.76,82.4 131.76,82.79 131.37,83.18 130.95,83.18 130.37,82.6 RAM4.T3
M_A_A14: length 137.8
  TOP w0.114: v2(131.3,35.18) 131.18,35.18 131.17,35.17 v1(130.74,35.17) ; v1(134.08,57.2) 134.21,57.33 R1231.2
  L3 w0.152: v1(131.62,73.8) 131.62,72.12 134.99,68.75 134.99,66.51 134.71,66.23 134.71,61.05 134.07,60.41 134.07,59.68 134.19,59.56 134.44,59.56 134.59,59.4 134.59,59.1 134.44,58.95 134.24,58.95 134.08,58.79 v1(134.08,57.2) 134.05,57.17 134.05,54.14 134.21,53.99 134.5,53.99 134.65,53.84 134.65,53.54 134.5,53.38 134.21,53.38 134.05,53.23 134.05,52.93 134.21,52.77 135.15,52.77 135.3,52.62 135.3,52.32 135.15,52.16 134.88,52.16 134.73,52.01 134.73,51.71 134.88,51.55 135.27,51.55 135.42,51.4 135.42,48.75 131.62,44.95 131.62,43.71 131.82,43.51 131.82,42.9 v1(131.62,42.7)
  L4 w0.152: v1(130.74,35.17) 130.74,35.89 131.33,36.48 131.33,37.46 130.85,37.93 130.85,39.84 131.34,40.32 131.34,42.06 131.62,42.34 v1(131.62,42.7) 131.62,43.99 131.02,44.58 131.02,44.85 131.17,45 131.65,45 131.8,45.15 131.8,45.46 131.65,45.61 131.17,45.61 131.02,45.76 131.02,46.07 131.17,46.22 131.49,46.22 131.64,46.37 131.64,46.68 131.49,46.83 131.18,46.83 130.56,47.45 130.56,48.11 130.74,48.28 v1(130.74,48.37) ; v1(134.08,57.2) 134.08,55.81 133.93,55.66 131.61,55.66 131.46,55.81 131.46,56.11 131.61,56.27 133.37,56.27 133.52,56.42 133.52,56.72 133.37,56.88 128.32,56.88 127.99,56.55 116.67,56.55 110.84,50.73 105.13,50.73 104.97,50.88 104.97,51.19 105.13,51.34 105.99,51.34 106.11,51.46 106.11,51.83 105.99,51.95 97.88,51.95 97.05,52.78 93.62,52.78 92.84,53.56 91.3,53.56 91.06,53.32 90.81,53.32 90.42,52.92 v1(90.42,52.2) ; v1(130.74,66.27) 130.74,66.99 131.3,67.55 131.3,68.51 130.85,68.96 130.85,70.94 131.34,71.42 131.34,73.2 131.62,73.48 v1(131.62,73.8) 131.62,75.09 131.02,75.68 131.02,75.95 131.17,76.1 131.65,76.1 131.8,76.25 131.8,76.56 131.65,76.71 131.17,76.71 131.02,76.86 131.02,77.17 131.17,77.32 131.49,77.32 131.64,77.47 131.64,77.78 131.49,77.93 131.18,77.93 130.56,78.55 130.56,79.21 130.74,79.38 v1(130.74,79.47)
  BOTTOM w0.114: RAM4.T7 130.67,79.4 v1(130.74,79.47) ; RAM1.T7 130.67,48.3 v1(130.74,48.37) ; RAM3.T7 130.67,35.1 v1(130.74,35.17) ; RAM2.T7 130.67,66.2 v1(130.74,66.27) ; v1(90.42,52.2) 90.44,52.2 90.6,52.36 90.6,52.64 CPU1.BD47
M_A_A15: length 139.1
  TOP w0.114: v1(124.17,54.49) 124.18,54.49 R1232.2 ; v2(124.91,42.23) 124.77,42.37 v1(124.77,42.84)
  L3 w0.152: v1(124.77,42.84) 124.77,44.81 124.95,44.99 125.56,44.99 125.71,45.15 125.71,45.45 125.56,45.6 125.14,45.6 124.99,45.76 124.99,46.4 125.14,46.56 125.63,46.56 125.79,46.71 125.79,47.01 125.63,47.17 125.14,47.17 124.99,47.32 124.99,47.62 125.14,47.77 125.63,47.77 125.79,47.93 125.79,48.23 125.63,48.38 125.18,48.38 125.03,48.54 125.03,48.84 125.18,48.99 125.31,48.99 125.42,49.11 125.42,49.78 125.15,50.05 125.15,50.85 125.3,51 125.86,51 126.01,51.15 126.01,51.46 125.86,51.61 124.46,51.61 124.31,51.76 124.31,52.07 124.46,52.22 125.36,52.22 125.51,52.37 125.51,52.68 125.36,52.83 124.68,52.83 124.53,52.98 124.53,53.29 124.68,53.44 125.34,53.44 125.49,53.59 125.49,53.89 125.34,54.04 124.62,54.04 v1(124.17,54.49) 124.17,58.89 124.78,59.5 124.78,63.07 124.25,63.61 124.25,64.64 124.47,64.87 124.47,66.06 123.6,66.93 123.6,68.89 124.73,70.02 124.73,71.18 125.56,72 125.56,72.82 124.76,73.61 124.76,73.94 v1(124.77,73.94)
  L4 w0.152: v1(125.88,80.73) 125.88,80.53 125.81,80.46 125.81,78.31 124.97,77.47 124.97,75.53 124.77,75.33 v1(124.77,73.94) 124.77,73.6 124.61,73.44 124.61,72.98 124.79,72.8 125.06,72.8 125.27,72.59 125.27,69.45 125.97,68.74 125.97,67.88 125.88,67.79 v1(125.88,67.53) ; v1(124.17,54.49) 124.24,54.49 124.84,53.89 125.21,53.89 125.81,54.48 127.02,54.48 127.61,53.9 129.23,53.9 129.26,53.93 129.68,53.93 130.09,53.52 130.09,53.02 129.65,52.58 129.26,52.58 129.11,52.73 129.11,53.06 128.95,53.22 128.65,53.22 128.5,53.06 128.5,52.73 128.34,52.58 128.04,52.58 127.89,52.73 127.89,53.05 127.74,53.2 127.43,53.2 127.28,53.05 127.28,52.73 127.13,52.58 126.82,52.58 126.67,52.73 126.67,53.07 126.33,53.41 125.71,53.41 125.56,53.26 125.56,52.73 125.41,52.58 125.1,52.58 124.95,52.73 124.95,53.08 124.81,53.22 124.48,53.22 124.34,53.08 124.34,52.73 124.19,52.58 123.88,52.58 123.73,52.73 123.73,54.85 123.58,55 118.47,55 117.12,53.65 116.1,53.65 114.6,52.16 114.6,50.93 113.26,49.58 113.26,47.5 112.6,46.84 100.3,46.84 98.57,48.57 97,48.57 94.88,50.69 94.85,50.69 94.09,51.45 91.87,51.45 v1(91.49,51.83) ; v1(125.88,49.63) 125.88,49.43 125.81,49.36 125.81,47.21 124.97,46.37 124.97,44.43 124.77,44.23 v1(124.77,42.84) 124.77,42.55 124.6,42.38 124.6,41.92 124.78,41.74 125.05,41.74 125.27,41.52 125.27,38.35 125.97,37.64 125.97,36.78 125.88,36.69 v1(125.88,36.43)
  BOTTOM w0.114: RAM1.M7 125.8,49.55 v1(125.88,49.63) ; RAM4.M7 125.8,80.65 v1(125.88,80.73) ; RAM3.M7 125.8,36.35 v1(125.88,36.43) ; v1(91.49,51.83) 91.14,52.18 CPU1.BD49 ; RAM2.M7 125.8,67.45 v1(125.88,67.53)
M_A_BS0: length 157.3
  TOP w0.114: v1(136.82,59.15) 136.61,59.36 R1242.2 ; v2(132.68,37.18) v1(132.1,37.18)
  L3 w0.152: v1(133.33,43.94) 133.28,43.99 133.28,44.34 137.08,48.14 137.08,56.44 136.55,56.98 136.54,56.98 136.37,57.15 136.37,58.57 136.43,58.62 136.7,58.62 136.82,58.75 v1(136.82,59.15) 136.82,59.15 136.82,59.39 136.36,59.84 136.36,65.62 136.59,65.85 136.59,69.41 133.33,72.67 v1(133.33,75.04)
  L4 w0.152: v1(132.1,81.48) 132.06,81.43 132.06,81.08 132.29,80.85 132.29,80.33 131.82,79.87 131.82,78.84 132.86,77.8 132.86,75.82 133.33,75.35 v1(133.33,75.04) 133.33,71.82 131.99,70.48 131.99,68.56 132.1,68.45 v1(132.1,68.28) ; v1(132.1,37.18) 132.1,37.35 131.99,37.46 131.99,39.38 133.33,40.72 v1(133.33,43.94) 133.33,44.2 132.81,44.72 132.81,46.73 132.44,47.1 132.44,47.12 131.82,47.74 131.82,48.77 132.29,49.23 132.29,49.75 132.06,49.98 132.06,50.33 v1(132.1,50.38) ; v1(136.82,59.15) 136.82,59.23 136.63,59.41 136.63,59.72 137.16,60.24 137.16,61.67 137.03,61.8 133.92,61.8 133.77,61.64 133.77,61.34 133.92,61.19 136.47,61.19 136.62,61.03 136.62,60.73 136.47,60.58 133.26,60.58 132.89,60.95 128.56,60.95 128.26,61.25 126.52,61.25 126.09,60.82 125.18,60.82 124.01,61.99 122.98,61.99 122.98,61.99 122.54,61.99 122.43,61.88 105.8,61.88 105.52,62.16 100.37,62.16 99.9,61.69 99.9,61.13 99.71,60.94 99.28,60.94 96.06,57.72 96.06,57.42 95.73,57.08 94.07,57.08 93.51,56.53 93.51,55.98 93.39,55.86 92.96,55.86 92.81,55.71 92.81,55.39 92.96,55.24 v1(93.2,55.24)
  BOTTOM w0.089: v1(93.2,55.24) 93.2,55.37 93.08,55.49 92.52,55.49 92.4,55.37 92.4,55.21 92.17,54.99 92.07,54.99 91.84,54.76 91.84,54.6 91.7,54.46 CPU1.BH46
  BOTTOM w0.114: v1(132.1,50.38) 131.7,50.78 130.42,50.78 130.28,50.92 128.14,50.92 127.75,51.32 127.75,51.66 127.49,51.92 126.25,51.92 126.02,51.92 125.8,52.14 RAM1.M2 ; RAM2.M2 125.8,69.9 125.9,69.8 127.53,69.8 127.82,69.52 127.82,69.31 128.28,68.85 130.56,68.85 130.61,68.8 131.12,68.8 131.64,68.28 v1(132.1,68.28) ; RAM4.M2 125.8,83.24 126.02,83.02 126.25,83.02 127.49,83.02 127.75,82.76 127.75,82.42 128.14,82.02 130.28,82.02 130.42,81.88 131.7,81.88 v1(132.1,81.48) ; RAM3.M2 125.8,38.8 125.9,38.7 127.53,38.7 127.82,38.41 127.82,38.21 128.28,37.75 129.47,37.75 129.53,37.69 131.12,37.69 131.64,37.18 v1(132.1,37.18)
M_A_BS1: length 152.8
  TOP w0.114: v1(127.53,63.13) 127.56,63.1 R1244.2 ; v2(127.13,35.62) 126.86,35.62 v1(126.62,35.86)
  L3 w0.152: v1(125.83,42.84) 125.83,44.43 126.21,44.81 126.65,44.81 127.11,45.26 127.11,46.31 126.44,46.97 126.44,47.61 127.93,49.09 127.93,49.66 127.8,49.78 127.8,50.41 126.73,51.48 126.73,53.07 126.57,53.22 126.57,53.68 126.73,53.84 126.73,54.31 125.24,55.8 125.24,58.45 126.3,59.5 126.3,59.69 126.08,59.91 126.08,60.12 126.29,60.34 126.51,60.34 126.59,60.26 126.81,60.26 127.53,60.98 v1(127.53,63.13) 126.89,63.13 126.78,63.02 126.78,61.41 126.63,61.26 126.26,61.26 126.11,61.41 126.11,64.29 126.26,64.44 127,64.44 127.15,64.29 127.15,64 127.31,63.85 127.61,63.85 127.76,64 127.76,64.95 127.41,65.31 127.41,65.77 127.63,65.99 127.9,65.99 128.05,66.15 128.05,66.45 127.9,66.6 126.87,66.6 126.72,66.45 126.72,65.74 126.57,65.59 126.26,65.59 126.11,65.74 126.11,67.11 126.47,67.46 126.77,67.46 126.87,67.56 126.87,69.38 126.72,69.54 126.23,69.54 126.07,69.69 126.07,69.99 126.23,70.15 126.72,70.15 126.87,70.3 126.87,70.58 126.4,71.05 126.17,71.05 126.06,71.16 126.06,73.31 125.83,73.54 v1(125.83,73.94)
  L4 w0.089: v1(86.96,54.8) 86.96,55.36 88.34,56.73
  L4 w0.152: v1(126.62,66.96) 126.62,67.61 126.87,67.87 126.87,69.3 125.77,70.4 125.77,70.78 125.83,70.84 v1(125.83,73.94) 125.83,75.19 125.99,75.35 126.37,75.35 126.52,75.5 126.52,75.81 126.37,75.96 125.98,75.96 125.84,76.1 125.84,76.44 126.17,76.78 126.17,77.56 126.32,77.71 126.32,79.72 126.62,80.02 v1(126.62,80.16) ; v1(126.62,35.86) 126.62,36.53 126.87,36.79 126.87,38.2 125.77,39.3 125.77,39.68 125.83,39.74 v1(125.83,42.84) 125.83,44.09 125.99,44.25 126.37,44.25 126.52,44.4 126.52,44.71 126.37,44.86 125.98,44.86 125.84,45 125.84,45.34 126.17,45.68 126.17,46.46 126.32,46.61 126.32,48.62 126.62,48.92 v1(126.62,49.06) ; 88.34,56.73 96.77,65.17 96.99,65.17 97.2,64.95 97.2,64.74 93.03,60.56 93.03,60.34 93.24,60.13 93.46,60.13 101.74,68.41 108.49,68.41 109.14,67.75 113.7,67.75 115.54,65.91 116.06,65.91 118.82,63.15 124.88,63.15 125.16,62.87 126.05,62.87 126.15,62.97 126.15,63.07 126.3,63.23 126.59,63.23 126.75,63.07 126.75,62.98 126.83,62.9 127.3,62.9 v1(127.53,63.13)
  BOTTOM w0.114: RAM3.N8 126.6,34.52 126.19,34.93 126.19,35.24 126.62,35.67 v1(126.62,35.86) ; v1(126.62,66.96) 126.62,66.77 126.19,66.34 126.19,66.03 126.6,65.62 RAM2.N8 ; RAM1.N8 126.19,47.91 126.19,48.63 v1(126.62,49.06) ; CPU1.AY40 86.76,53.78 86.87,53.89 86.87,54.05 86.76,54.16 86.44,54.16 86.29,54.31 86.29,54.52 86.44,54.66 86.82,54.66 v1(86.96,54.8) ; v1(126.62,80.16) 126.19,79.73 126.19,79.01 RAM4.N8
M_A_BS2: length 145.5
  TOP w0.114: v1(130.56,54.48) 129.87,55.17 R1245.2 ; v1(129.07,68) v2(129.07,68.57)
  L3 w0.152: v1(128.6,43.58) 128.6,45.23 129.1,45.73 129.1,47.44 129.33,47.67 129.62,47.67 130.21,47.07 130.43,47.07 130.65,47.29 130.65,47.51 130.05,48.1 130.05,48.35 130.53,48.83 130.93,48.83 131.35,49.25 131.35,49.65 131.66,49.95 131.66,50.91 131.51,51.06 129.7,51.06 129.54,51.21 129.54,51.77 129.7,51.92 131.22,51.92 131.37,52.08 131.37,52.38 131.22,52.53 129.73,52.53 129.58,52.69 129.58,52.99 129.73,53.14 131.18,53.14 131.33,53.3 131.33,53.6 131.18,53.75 130.72,53.75 130.56,53.91 v1(130.56,54.48) 130.56,65.45 130.31,65.71 130.31,66.59 130.88,67.17 130.88,67.58 130.43,68.04 130.43,68.41 129.99,68.85 129.74,68.85 128.49,70.09 128.49,73.57 128.6,73.67 v1(128.6,74.68)
  L4 w0.152: v1(130.56,54.48) 129.74,54.48 129.28,54.93 124.68,54.93 124.35,55.26 118.36,55.26 117.01,53.9 115.99,53.9 114.35,52.26 114.35,51.08 111.87,48.6 107.4,48.6 107.25,48.44 107.25,48.14 107.4,47.99 112.12,47.99 112.29,48.16 112.51,48.16 112.72,47.94 112.72,47.72 112.37,47.38 100.52,47.38 98.8,49.1 97.14,49.1 95.07,51.17 94.72,51.17 94.12,51.78 92.56,51.78 v1(92.4,51.94) ; v1(129.07,68) 129.07,68.22 128.49,68.8 128.49,72.61 128.6,72.72 v1(128.6,74.68) 128.6,75 128.82,75.22 128.82,75.93 128.6,76.15 128.6,76.7 128.93,77.03 128.93,78.24 128.22,78.95 128.22,79.46 128.96,80.2 v1(128.96,80.73) ; v1(129.07,36.9) 129.07,37.12 128.49,37.7 128.49,41.51 128.6,41.62 v1(128.6,43.58) 128.6,45.6 128.76,45.76 128.76,47.3 128.42,47.64 128.42,48.56 128.96,49.1 128.96,49.81 v1(129.17,50.02)
  BOTTOM w0.114: v1(129.07,68) 128,68 127.46,68.54 127.07,68.54 126.67,68.94 126.06,68.94 125.8,69.2 RAM2.M3 ; CPU1.BF52 v1(92.4,51.94) ; RAM3.M3 125.8,38.1 126.03,37.87 126.7,37.87 127.13,37.44 127.46,37.44 128,36.9 v1(129.07,36.9) ; v1(129.17,50.02) 129.16,50.02 128.57,50.02 128.37,50.22 127.92,50.22 127.28,50.86 126.76,50.86 126.12,51.5 RAM1.M3 ; v1(128.96,80.73) 128.96,80.78 128.43,81.32 127.9,81.32 127.42,81.79 126.93,81.79 126.12,82.6 RAM4.M3
M_A_CAS#: length 134.2
  TOP w0.114: R1240.2 123.57,61.21 v1(123.58,61.23) ; v1(124.23,43.58) 124.23,44.02 v2(124.11,44.14)
  L3 w0.152: v1(124.23,74.68) 124.21,74.66 124.21,73.67 125.3,72.58 125.3,72.11 124.26,71.07 123.46,71.07 123.31,70.92 123.31,70.61 123.46,70.46 124.2,70.46 124.35,70.31 124.35,70 124.2,69.85 123.5,69.85 123.34,69.7 123.34,66.82 124.21,65.95 124.21,65.28 124.1,65.16 123.83,65.16 123.72,65.05 123.72,64.69 123.36,64.32 123.36,63.32 123.56,63.12 124.3,63.12 124.51,62.92 124.51,62.2 124.25,61.94 124.25,61.62 123.86,61.23 v1(123.58,61.23) 123.58,60.61 123.74,60.46 124.04,60.46 124.19,60.3 124.19,60 124.04,59.85 123.74,59.85 123.58,59.7 123.58,53.56 124.02,53.12 124.02,50.4 124.48,49.95 124.48,49.46 124.76,49.17 124.76,48.74 124.73,48.71 124.73,45.56 124.23,45.06 v1(124.23,43.58)
  L4 w0.152: v1(125.54,68.18) 125.69,68.33 125.69,68.61 125.01,69.29 125.01,71.4 124.23,72.17 v1(124.23,74.68) 124.23,75.3 124.71,75.78 124.71,77.57 125.44,78.3 125.44,81.1 125.5,81.15 v1(125.5,81.32) ; v1(94.47,55.47) 95.54,56.54 96.41,56.54 98.39,58.52 99.34,58.52 99.48,58.65 107.53,58.65 107.69,58.81 107.69,59.11 107.53,59.26 99.72,59.26 99.57,59.42 99.57,59.72 99.72,59.87 104.92,59.87 105.15,60.1 105.15,60.67 105.3,60.82 105.69,60.82 105.84,60.67 105.84,59.96 105.99,59.81 106.29,59.81 106.45,59.96 106.45,60.67 106.6,60.82 106.9,60.82 107.06,60.67 107.06,60.01 107.21,59.86 107.51,59.86 107.67,60.01 107.67,60.67 107.82,60.82 108.12,60.82 108.28,60.67 108.28,60.02 108.43,59.87 108.73,59.87 108.89,60.02 108.89,60.67 109.04,60.82 123.43,60.82 123.58,60.98 v1(123.58,61.23) ; v1(125.58,50.25) 125.44,50.11 125.44,47.2 124.71,46.47 124.71,44.68 124.23,44.2 v1(124.23,43.58) 124.23,41.24 125.01,40.47 125.01,38.19 125.63,37.57 125.63,37.05 v1(125.54,36.97)
  BOTTOM w0.089: CPU1.BG45 91.24,55.01 91.24,55.32 91.46,55.55 91.47,55.55 91.48,55.56 91.96,55.56 92.03,55.63
  BOTTOM w0.114: RAM1.K3 124.2,51.44 124.98,50.66 125.06,50.66 125.47,50.25 v1(125.58,50.25) ; RAM4.K3 124.2,82.41 124.53,82.09 124.63,82.09 124.88,81.83 124.99,81.83 v1(125.5,81.32) ; v1(125.54,36.97) 125.46,36.97 124.2,38.22 RAM3.K3 ; RAM2.K3 124.2,69.22 124.53,68.89 124.68,68.89 125.38,68.18 v1(125.54,68.18) ; 92.03,55.63 92.33,55.92 94.33,55.92 94.47,55.78 v1(94.47,55.47)
M_A_CKE0: length 150
  TOP w0.114: v2(121.94,42.32) 122.16,42.54 v1(122.49,42.54) ; R1233.2 120.73,53.96 v1(120.87,53.82)
  L3 w0.152: v1(122.49,73.64) 122.49,73.21 122.22,72.94 122.22,71.45 122.43,71.24 122.43,66.92 122.02,66.51 121.49,66.51 120.52,65.53 120.52,65.09 119.95,64.53 119.67,64.53 119.31,64.17 119.31,60.01 120.76,58.56 120.76,53.93 v1(120.87,53.82) 121.03,53.66 121.03,53.49 121.46,53.06 121.91,53.06 123.07,51.9 123.07,46.62 122.49,46.04 122.49,43.63 123.14,42.98 123.14,42.45 123.45,42.14 123.87,42.14 124.01,42 124.01,41.59 123.86,41.44 122,41.44 121.85,41.59 121.85,41.79 121.7,41.94 119.86,41.94 119.7,42.1 119.7,42.38 119.86,42.54 v1(122.49,42.54)
  L4 w0.089: v1(88.59,52.44) 89.3,52.44 91.15,50.59 92,50.59 92.15,50.74 93.27,50.74 93.66,50.36 94.43,50.36 95.05,49.73
  L4 w0.152: v1(124.33,80.02) 124.55,79.8 124.55,78.72 122.43,76.6 122.43,76.17 122.86,75.74 122.86,75.44 122.49,75.07 v1(122.49,73.64) 122.47,73.62 122.47,71.76 124.18,70.06 124.18,68.14 124.46,67.86 124.46,67.3 124.36,67.2 v1(124.36,66.84) ; v1(120.87,53.82) 120.87,53.21 120.72,53.05 120.3,53.05 120.15,53.21 120.15,53.71 119.99,53.86 119.69,53.86 119.54,53.71 119.54,53.29 119.33,53.09 117.83,53.09 117.51,52.77 115.94,52.77 115.16,52 115.16,50.33 114.04,49.21 114.04,46.76 111.84,44.56 102.13,44.56 101.98,44.71 101.98,45.01 102.13,45.17 111.18,45.17 111.33,45.32 111.33,45.62 111.18,45.78 99.85,45.78 97.93,47.7 97.09,47.7 95.05,49.73 ; v1(124.33,48.92) 124.55,48.7 124.55,47.62 122.43,45.5 122.43,45.07 122.86,44.64 122.86,44.34 122.49,43.97 v1(122.49,42.54) 122.47,42.52 122.47,40.66 124.18,38.96 124.18,37.04 124.46,36.76 124.46,36.2 124.36,36.1 v1(124.36,35.74)
  BOTTOM w0.114: v1(124.36,66.84) 124.36,66.78 124.56,66.59 124.56,65.13 124.45,65.02 124.33,64.9 124.33,64.89 124.2,64.77 RAM2.K9 ; RAM1.K9 124.2,46.9 124.56,47.26 124.56,48.69 v1(124.33,48.92) ; RAM3.K9 124.2,33.67 124.33,33.79 124.33,33.8 124.45,33.92 124.56,34.03 124.56,35.49 124.36,35.68 v1(124.36,35.74) ; v1(124.33,80.02) 124.56,79.79 124.56,78.36 124.2,78 RAM4.K9 ; CPU1.BB44 88.57,52.89 88.57,52.46 v1(88.59,52.44)
M_A_CLK0: length 173.8
  TOP w0.127: R1235.2 C1202.1 116.13,62.87 116.13,63.53 115.7,63.96 115.11,63.96 114.78,64.28 114.78,64.51 v1(115.04,64.78) ; v1(119.35,43.27) 119.35,43.49 v2(119.07,43.76)
  L3 w0.14: v1(119.35,43.27) 119.35,44.75 119.73,45.13 119.73,46.56 118.95,47.34 118.95,50.2 119.35,50.6 119.35,52.45 117.92,53.88 117.92,54.43 114.66,57.69 114.66,62.15 114.8,62.29 115.08,62.29 115.22,62.15 115.22,57.95 115.51,57.66 115.97,57.66 116.26,57.95 116.26,63.05 115.98,63.33 115.27,63.33 115.04,63.55 v1(115.04,64.78) 115.04,65.35 115.7,66 116.41,66 118.73,68.33 118.73,69.62 118.45,69.9 118.23,69.9 118.07,70.06 118.07,70.29 118.23,70.46 118.72,70.46 119.02,70.76 119.02,71.19 118.72,71.5 116.83,71.5 115.2,73.12 115.2,74.89 114.91,75.18 114.46,75.18 114.16,74.89 114.16,73.39 114.01,73.24 113.76,73.24 113.6,73.39 113.6,75.32 114.07,75.79 115.61,75.79 115.76,75.64 115.76,73.42 116.06,73.12 116.51,73.12 116.8,73.42 116.8,75.43 116.94,75.57 117.22,75.57 117.36,75.43 117.36,73.12 117.6,72.89 118.81,72.89 119.15,73.22 119.15,74.17 v1(119.35,74.37)
  L4 w0.089: 89.53,56.81 89.51,56.79 89.51,56.75 89.5,56.74 88.28,55.52 88.28,54.73 v1(88.19,54.64)
  L4 w0.14: v1(121.99,36.08) 122.17,36.26 122.59,36.26 122.86,36.53 122.86,38.36 120.62,40.59 120.62,41.2 119.17,42.65 119.17,43.1 v1(119.35,43.27) 119.08,43.54 118.91,43.54 118.76,43.69 118.76,45.06 119.8,46.11 120,46.11 120.21,45.9 120.61,45.9 120.95,46.24 120.95,46.64 120.74,46.85 120.74,47.05 121.56,47.87 121.56,49.34 121.8,49.58 122,49.58 122.21,49.37 v1(122.21,49.32) ; v1(122.21,80.42) 122.21,80.47 122,80.68 121.8,80.68 121.56,80.44 121.56,78.97 120.74,78.15 120.74,77.95 120.95,77.74 120.95,77.34 120.61,77 120.21,77 120,77.21 119.8,77.21 118.76,76.16 118.76,74.79 118.91,74.64 119.08,74.64 v1(119.35,74.37) 119.17,74.2 119.17,73.75 120.62,72.3 120.62,71.79 122.86,69.56 122.86,67.63 122.59,67.36 122.19,67.36 122.15,67.33 122.14,67.33 v1(121.99,67.18) ; v1(115.04,64.78) 115.04,65.71 114.64,66.12 114.24,66.12 113.98,65.86 113.78,65.86 113.58,66.06 113.58,66.26 113.84,66.52 113.84,66.92 113.53,67.23 108.93,67.23 108.27,67.88 102.32,67.88 102.03,67.59 102.03,67.13 102.32,66.84 107.81,66.84 107.96,66.69 107.96,66.43 107.81,66.28 100.36,66.28 93.58,59.51 92.66,59.51 90.24,57.08 89.81,57.08 89.53,56.81
  BOTTOM w0.127: RAM2.J7 123.5,66.2 123.57,66.27 123.57,66.62 122.56,67.63 122.35,67.63 122.28,67.56 122.28,67.21 122.19,67.13 122.04,67.13 v1(121.99,67.18) ; RAM3.J7 123.49,35.1 123.56,35.17 123.56,35.54 122.57,36.53 122.37,36.53 122.31,36.47 122.31,36.12 122.22,36.03 122.03,36.03 v1(121.99,36.08) ; v1(122.21,80.42) 122.28,80.35 122.42,80.35 122.51,80.43 122.51,80.84 122.57,80.9 122.8,80.9 123.53,80.18 123.53,79.47 123.46,79.4 RAM4.J7 ; v1(88.19,54.64) 88.19,54.98 88.17,55 88.17,55.29 ; RAM1.J7 123.46,48.3 123.53,48.37 123.53,49.07 122.79,49.81 122.58,49.81 122.52,49.74 122.52,49.34 122.43,49.25 122.28,49.25 v1(122.21,49.32)
M_A_CLK0_L: length 2.6
  TOP w0.127: v2(114.69,60.8) R1236.1 115.61,60.8 R1235.1 116.5,60.81 C1208.2
M_A_CLK#0: length 174.3
  TOP w0.127: v1(121.98,36.76) 122.46,36.76 v2(122.54,36.84) ; v1(114.24,64.78) 114.55,64.46 114.55,64.19 115.01,63.73 115.6,63.73 115.9,63.43 115.9,62.81 C1202.2 115.61,62.51 R1236.2
  L3 w0.14: v1(118.51,74.37) 118.75,74.37 118.9,74.22 118.9,73.32 118.71,73.13 117.7,73.13 117.6,73.22 117.6,75.53 117.32,75.81 116.84,75.81 116.56,75.53 116.56,73.52 116.41,73.36 116.16,73.36 116,73.52 116,75.74 115.71,76.03 113.97,76.03 113.36,75.42 113.36,73.29 113.66,73 114.11,73 114.4,73.29 114.4,74.79 114.56,74.94 114.81,74.94 114.96,74.79 114.96,73.02 116.73,71.26 118.62,71.26 118.78,71.09 118.78,70.86 118.62,70.7 118.13,70.7 117.83,70.39 117.83,69.96 118.13,69.65 118.35,69.65 118.49,69.52 118.49,68.43 116.31,66.24 115.6,66.24 114.8,65.45 114.8,65.14 114.44,64.78 v1(114.24,64.78) 114.8,64.21 114.8,63.45 115.17,63.09 115.88,63.09 116.02,62.95 116.02,58.05 115.87,57.9 115.61,57.9 115.46,58.05 115.46,62.25 115.18,62.53 114.7,62.53 114.42,62.25 114.42,57.59 117.68,54.33 117.68,53.78 119.11,52.35 119.11,50.7 118.71,50.3 118.71,47.24 119.49,46.46 119.49,45.23 119.11,44.85 119.11,43.69 118.69,43.27 v1(118.51,43.27)
  L4 w0.089: v1(88.72,55.19) 88.55,55.19 88.47,55.27 88.47,55.44 89.65,56.62 89.68,56.62 89.7,56.63
  L4 w0.14: v1(121.98,67.86) 121.98,67.69 122.07,67.6 122.49,67.6 122.62,67.73 122.62,69.46 120.38,71.69 120.38,72.2 118.93,73.65 118.93,74.19 118.75,74.37 v1(118.51,74.37) 118.51,76.26 119.7,77.45 120.1,77.45 120.31,77.24 120.51,77.24 120.71,77.44 120.71,77.64 120.5,77.85 120.5,78.25 121.32,79.07 121.32,80.54 121.7,80.92 122,80.92 v1(122.21,81.13) ; v1(121.98,36.76) 121.98,36.59 122.07,36.5 122.49,36.5 122.62,36.63 122.62,38.26 120.38,40.49 120.38,41.1 118.93,42.55 118.93,43.09 118.75,43.27 v1(118.51,43.27) 118.51,45.16 119.7,46.35 120.1,46.35 120.31,46.14 120.51,46.14 120.71,46.34 120.71,46.54 120.5,46.75 120.5,47.15 121.32,47.97 121.32,49.44 121.7,49.82 122,49.82 v1(122.21,50.03) ; 89.7,56.63 89.91,56.84 90.34,56.84 92.76,59.27 93.68,59.27 100.46,66.04 107.91,66.04 108.2,66.33 108.2,66.79 107.91,67.08 102.42,67.08 102.27,67.23 102.27,67.49 102.42,67.64 108.17,67.64 108.83,66.98 113.43,66.98 113.6,66.81 113.6,66.62 113.34,66.36 113.34,65.96 113.68,65.62 114.08,65.62 114.34,65.88 114.54,65.88 114.8,65.61 114.8,65.34 v1(114.24,64.78)
  BOTTOM w0.127: CPU1.BF40 88.56,55.77 88.49,55.7 88.49,55.27 88.56,55.19 v1(88.72,55.19) ; RAM1.K7 124.13,48.3 123.76,48.68 123.76,49.16 122.89,50.03 v1(122.21,50.03) ; v1(121.98,67.86) 122.65,67.86 123.79,66.72 123.79,66.59 124.18,66.2 RAM2.K7 ; v1(122.21,81.13) 122.89,81.13 123.76,80.27 123.76,79.81 124.17,79.4 RAM4.K7 ; RAM3.K7 124.16,35.1 123.79,35.47 123.79,35.63 122.67,36.76 v1(121.98,36.76)
M_A_CS#0: length 157.2
  TOP w0.114: R1234.2 125.46,63.26 v1(125.5,63.3) ; v1(126.44,37.1) 126.44,37.53 v2(126.57,37.66)
  L3 w0.152: v1(125.3,43.53) 125.3,44.56 125.41,44.68 125.7,44.68 126.17,45.15 126.17,49.25 126.88,49.96 126.88,50.63 126.73,50.79 126.54,50.79 126.39,50.94 126.39,51.64 125.77,52.26 125.77,54.7 125.43,55.04 124.86,55.04 124.71,55.19 124.71,58.67 125.32,59.28 125.32,63.11 v1(125.5,63.3) 125.5,63.37 125.35,63.52 125.26,63.52 125.14,63.64 125.14,64.58 125.26,64.7 126.41,64.7 126.56,64.85 126.56,65.16 126.42,65.3 124.89,65.3 124.72,65.46 124.72,66.13 124.88,66.28 125.69,66.28 125.85,66.43 125.85,66.74 125.69,66.89 124.92,66.89 124.55,67.26 124.55,67.77 124.22,68.1 124.01,68.1 123.86,68.26 123.86,68.57 124.01,68.73 126.09,68.73 126.22,68.86 126.22,69.18 126.07,69.34 125,69.34 124.87,69.46 124.87,69.79 125.02,69.95 125.64,69.95 125.8,70.1 125.8,70.45 125.64,70.6 125.22,70.6 125.06,70.75 125.06,71.1 125.22,71.25 125.66,71.25 125.81,71.41 125.81,73.15 125.3,73.66 125.3,74.16 125.3,74.16 v1(125.3,74.63)
  L4 w0.089: v1(85.99,53.88) 85.99,54.71 86.23,54.95 86.23,55.28 86.02,55.49 86.02,55.84 90.18,60
  L4 w0.152: v1(126.44,37.1) 126.44,37.33 126.61,37.51 126.61,38.1 126.39,38.33 125.73,38.33 125.52,38.54 125.52,41.67 125.3,41.89 v1(125.3,43.53) 125.3,44.26 125.52,44.48 125.52,45.6 125.22,45.9 125.22,46.26 126.07,47.11 126.07,49.13 126.32,49.38 126.32,49.97 126.39,50.05 v1(126.39,50.24) ; v1(126.39,81.34) 126.39,81.15 126.32,81.07 126.32,80.48 126.07,80.23 126.07,78.21 125.22,77.36 125.22,77 125.52,76.7 125.52,75.58 125.3,75.36 v1(125.3,74.63) 125.3,72.99 125.52,72.77 125.52,69.64 125.73,69.43 126.39,69.43 126.61,69.2 126.61,68.61 126.44,68.43 v1(126.44,68.2) ; v1(125.5,63.3) 125.32,63.3 125.22,63.4 125.22,64.73 125,64.95 124.37,64.95 124.22,64.8 124.22,63.56 124.07,63.41 123.13,63.41 122.98,63.56 122.98,64.54 122.82,64.69 122.05,64.69 121.9,64.54 121.9,63.66 121.64,63.4 119.24,63.4 116.46,66.18 115.65,66.18 113.64,68.19 113.45,68.19 113.28,68.36 113.28,68.85 113.13,69.01 112.72,69.01 112.57,68.85 112.57,68.44 112.42,68.29 112.07,68.29 111.91,68.44 111.91,68.84 111.76,69 111.46,69 111.3,68.84 111.3,68.44 111.15,68.29 110.85,68.29 110.69,68.44 110.69,68.86 110.54,69.01 110.24,69.01 110.08,68.86 110.08,68.44 109.93,68.29 109.47,68.29 109.31,68.44 109.31,68.87 109.24,68.94 101.52,68.94 97.86,65.28 97.64,65.28 97.43,65.5 97.43,65.71 100.17,68.46 100.17,68.67 99.96,68.89 99.74,68.89 91.01,60.16 90.34,60.16 90.18,60
  BOTTOM w0.114: CPU1.AY38 85.88,54.48 85.77,54.37 85.77,53.99 85.89,53.88 v1(85.99,53.88) ; v1(126.39,50.24) 126.24,50.24 125.68,50.8 125.29,50.8 125.16,50.93 125.09,50.93 124.54,51.48 124.54,52.13 124.7,52.3 RAM1.L2 ; RAM4.L2 124.7,83.4 124.54,83.23 124.54,82.58 125.09,82.03 125.16,82.03 125.45,81.74 125.84,81.74 126.24,81.34 v1(126.39,81.34) ; RAM2.L2 124.73,70.2 124.59,70.07 124.59,69.28 125.24,68.63 125.72,68.63 126.16,68.2 v1(126.44,68.2) ; v1(126.44,37.1) 126.16,37.1 125.72,37.53 125.24,37.53 124.59,38.18 124.59,38.97 124.73,39.1 RAM3.L2
M_A_DIM0_ODT0: length 160
  TOP w0.114: v1(121.46,64.1) 121.8,64.1 121.93,63.97 R1246.2 ; v1(124.64,37.19) 124.64,37.63 v2(124.52,37.75)
  L3 w0.152: v1(123.14,43.73) 123.02,43.85 123.02,46.18 123.33,46.48 123.33,52.43 121.3,54.45 121.3,58.78 119.84,60.23 119.84,63.52 120.02,63.69 121.27,63.69 121.46,63.89 v1(121.46,64.1) 121.46,64.39 121.89,64.82 121.89,66 122.68,66.79 122.68,71.55 122.47,71.76 122.47,72.51 122.92,72.96 122.92,73.88 122.39,74.41 122.39,75.38 122.03,75.74 122.03,77.53 122.19,77.68 122.53,77.68 122.68,77.53 122.68,76.13 122.93,75.88 125.6,75.88 125.75,75.73 125.75,75.41 125.6,75.26 123.29,75.26 123.14,75.1 v1(123.14,74.83)
  L4 w0.102: 90.31,60.46 84.91,55.06 v1(84.91,54.12)
  L4 w0.152: v1(124.72,81.42) 124.72,81.25 124.55,81.08 124.55,80.45 124.8,80.2 124.8,79.91 124.8,79.91 124.8,78.61 123.14,76.95 123.14,74.86 123.14,74.86 v1(123.14,74.83) 123.14,74.35 123.04,74.25 123.04,73.53 123.32,73.26 123.32,73.01 123.06,72.75 123.06,72.45 123.37,72.15 123.37,71.36 124.49,70.24 124.49,68.88 124.64,68.73 v1(124.64,68.29) ; v1(121.46,64.1) 121.46,63.83 121.29,63.66 119.38,63.66 116.6,66.44 115.75,66.44 113.59,68.61 113.59,69.09 113.12,69.55 102.14,69.55 101.99,69.7 101.99,70.31 101.84,70.46 101.53,70.46 101.38,70.31 101.38,69.57 101.23,69.42 100.92,69.42 100.77,69.57 100.77,70.29 100.62,70.45 100.31,70.45 100.16,70.29 100.16,69.6 100.01,69.45 99.7,69.45 99.55,69.6 99.55,70.28 99.4,70.43 99.09,70.43 98.94,70.28 98.94,69.41 98.79,69.26 97.63,69.26 95.74,67.37 95.74,67.16 95.96,66.94 96.17,66.94 97.91,68.68 98.12,68.68 98.34,68.46 98.34,68.24 93.28,63.18 93.06,63.18 92.85,63.4 92.85,63.61 95.37,66.14 95.37,66.35 95.15,66.57 94.94,66.57 92.19,63.82 92.19,62.33 90.31,60.46 ; v1(124.64,37.19) 124.64,37.63 124.49,37.78 124.49,39.14 123.34,40.29 123.34,41.08 123.06,41.36 123.06,41.65 123.32,41.91 123.32,42.16 123.04,42.43 123.04,43.15 123.14,43.25 v1(123.14,43.73) 123.14,45.85 124.8,47.51 124.8,48.81 124.8,48.81 124.8,49.1 124.55,49.35 124.55,49.98 124.72,50.15 v1(124.72,50.32)
  BOTTOM w0.114: RAM1.K1 124.2,52.89 123.86,52.55 123.86,51.17 v1(124.72,50.32) ; RAM4.K1 124.2,83.99 123.86,83.65 123.86,82.27 v1(124.72,81.42) ; CPU1.AV36 84.68,54.67 84.57,54.55 84.57,54.27 84.72,54.12 v1(84.91,54.12) ; RAM2.K1 124.2,70.75 123.74,70.29 123.74,69.19 v1(124.64,68.29) ; RAM3.K1 124.2,39.65 123.74,39.19 123.74,38.09 v1(124.64,37.19)
M_A_DM0: length 42.6
  TOP w0.089: v1(119.8,38.7) 119.8,39.32 v2(119.75,39.37)
  L4 w0.114: v1(90.27,46.49) 90.27,45.98 90.64,45.61 90.64,44.98 92.5,43.12 93.22,43.12 93.56,42.78 93.56,42.34 96.09,39.81 96.59,39.81 100.03,36.38 111.01,36.38 111.13,36.49 111.13,36.72 111.01,36.83 109.64,36.83 109.53,36.95 109.53,37.18 109.64,37.29 119.3,37.29 119.8,37.79 v1(119.8,38.7)
  BOTTOM w0.089: v1(90.27,46.49) 89.79,46.49 88.91,47.38 CPU1.AP52 ; RAM3.D3 v1(119.8,38.7)
M_A_DM1: length 49
  TOP w0.089: v1(119.42,49.45) 119.17,49.45 v2(118.85,49.13)
  L4 w0.089: 93.4,46.6 91.34,48.66 89.1,48.66 88.73,49.03 v1(88.73,49.59)
  L4 w0.114: v1(119.42,49.45) 118.53,49.45 118.08,49 116.76,49 115.9,48.15 115.9,44.41 113.3,41.8 109.55,41.8 109.43,41.69 109.43,41.2 109.32,41.08 109.09,41.08 108.98,41.2 108.98,41.68 108.86,41.79 108.63,41.79 108.52,41.68 108.52,41.2 108.41,41.08 108.18,41.08 108.06,41.2 108.06,41.68 107.95,41.79 107.72,41.79 107.61,41.68 107.61,41.2 107.49,41.08 107.26,41.08 107.15,41.2 107.15,41.68 107.03,41.79 106.8,41.79 106.69,41.68 106.69,41.2 106.58,41.08 106.35,41.08 106.23,41.2 106.23,41.68 106.12,41.79 105.89,41.79 105.78,41.68 105.78,41.2 105.66,41.08 105.43,41.08 105.32,41.2 105.32,41.66 105.2,41.78 104.97,41.78 104.86,41.66 104.86,41.2 104.75,41.08 100.61,41.08 97.61,44.09 96.81,44.09 95.07,45.83 94.17,45.83 93.4,46.6
  BOTTOM w0.089: CPU1.AT48 88.59,49.45 v1(88.73,49.59) ; v1(119.42,49.45) 119.78,49.08 119.78,48.72 RAM1.E7
M_A_DM2: length 55
  TOP w0.089: v1(121.11,36.25) 121.11,36.11 v2(121.51,35.71)
  L3 w0.089: v1(86.56,50.32) 86.56,49.73 89.74,46.55 89.74,46.44 90.76,45.42 90.76,44.66 91.46,43.96 92.09,43.96
  L3 w0.114: v1(121.11,36.25) 120.69,36.25 119.71,37.23 114.81,37.23 114.45,37.59 114.45,37.78 114.33,37.9 114.1,37.9 113.99,37.78 113.99,37.59 113.87,37.48 112.69,37.48 112.59,37.58 112.59,37.69 112.47,37.81 112.24,37.81 112.13,37.69 112.13,37.58 112.01,37.47 104.83,37.47 104.56,37.74 99.54,37.74 99.41,37.88 99.41,38.07 99.54,38.2 104.13,38.2 104.27,38.33 104.27,38.52 104.13,38.66 98.93,38.66 94.1,43.48 93.56,43.48 93.08,43.96 92.09,43.96
  BOTTOM w0.089: v1(121.11,36.25) 121.11,36.13 120.2,35.22 RAM3.E7 ; CPU1.AP44 86.03,50.32 v1(86.56,50.32)
M_A_DM3: length 32.7
  TOP w0.089: v2(118.91,51.58) 118.62,51.29 v1(118.62,50.97)
  L3 w0.114: v1(92.11,49.08) 92.11,49.72 92.74,50.35 94.64,50.35 95.1,49.88 112.91,49.88 115.89,52.86 117.87,52.86 118.62,52.11 v1(118.62,50.97)
  BOTTOM w0.089: v1(118.62,50.97) 119.15,51.5 RAM1.D3 ; CPU1.BA53 91.98,49.09 92.1,49.09 v1(92.11,49.08)
M_A_DM4: length 39
  TOP w0.089: v2(118.53,68.99) 118.18,68.65 v1(118.04,68.65)
  L3 w0.114: v1(92.11,59.75) 92.11,59.87 93.19,60.95 97.92,60.95 99.36,62.39 105.06,62.39 113.22,70.55 114.26,70.55 115.43,69.39 116.81,69.39 116.95,69.26 117.92,69.26 118.04,69.14 v1(118.04,68.65)
  BOTTOM w0.089: v1(92.11,59.75) 92.11,58.6 90.64,57.13 90.54,57.13 90.33,56.92 90.09,56.92 89.86,56.7 89.86,56.59 89.64,56.37 CPU1.BG41 ; RAM2.D3 119.4,69.01 119.03,68.65 v1(118.04,68.65)
M_A_DM5: length 63.5
  TOP w0.089: v2(119.46,82.44) 119.9,82 v1(119.92,82)
  L3 w0.089: 85.07,61.5 85.07,60.81 86.42,59.46 86.59,59.46 87.26,58.79 87.26,57.95 85.34,56.02 v1(85.34,54.64)
  L3 w0.114: 85.07,61.5 85.07,63.69 95.17,73.79 96.29,73.79 97.96,75.46 99.25,75.46 100.78,76.98 100.78,77.15 100.61,77.31 100.45,77.31 99.34,76.2 99.18,76.2 99.02,76.36 99.02,76.52 105.98,83.48 119.22,83.48 119.48,83.23 119.48,82.44 v1(119.92,82)
  BOTTOM w0.089: v1(85.34,54.64) 85.27,54.71 CPU1.AY36 ; RAM4.E7 119.92,79.68 v1(119.92,82)
M_A_DM6: length 56.5
  TOP w0.089: v1(119.94,66.87) 119.52,66.87 v2(119.25,66.61)
  L4 w0.089: 87.57,61.77 87.43,61.63 87.29,61.63 86.46,60.8 86.46,58.96 85.58,58.08 85.58,57.47 v1(85.53,57.42)
  L4 w0.114: 87.57,61.77 89.38,63.57 89.38,64.39 97.75,72.76 114.18,72.76 114.29,72.65 114.29,72.42 114.18,72.31 110.72,72.31 110.61,72.19 110.61,71.96 110.72,71.85 114.54,71.85 114.99,71.39 116.6,71.39 118.72,69.27 118.72,68.18 118.46,67.91 118.46,67.38 118.97,66.87 v1(119.94,66.87)
  BOTTOM w0.089: RAM2.E7 120.2,66.61 v1(119.94,66.87) ; CPU1.BD32 85.42,57.53 v1(85.53,57.42)
M_A_DM7: length 44.2
  TOP w0.089: v2(115.38,79.83) 115.7,80.14 v1(115.7,80.43)
  L3 w0.114: v1(115.7,80.43) 115.13,79.86 113.9,79.86 108.06,74.02 105.98,74.02 101.88,69.91 99.1,69.91 98.06,68.87 95.21,68.87 89.83,63.49 89.83,63.32 88.42,61.91 v1(88.35,61.91)
  BOTTOM w0.089: v1(115.7,80.43) 115.95,80.67 118.4,80.67 119.4,81.68 RAM4.D3 ; CPU1.BH30 86.4,60.41 86.4,60.74 86.71,61.05 86.84,61.05 87.71,61.91 v1(88.35,61.91)
M_A_DQ0: length 42
  TOP w0.089: v1(117.4,34.7) v2(117.99,34.7)
  L4 w0.114: v1(90.09,43.51) 90.09,43.11 90.58,42.62 90.58,42.19 90.94,41.83 91.13,41.83 93.91,39.05 93.91,38.22 95.48,36.65 97.1,36.65 100.08,33.67 105.48,33.67 105.6,33.79 105.6,34.02 105.48,34.13 104.44,34.13 104.33,34.25 104.33,34.47 104.44,34.59 116.03,34.59 116.41,34.21 116.92,34.21 v1(117.4,34.7)
  BOTTOM w0.089: v1(90.09,43.51) 89.34,43.51 88.96,43.89 88.71,43.89 87.99,44.61 87.99,45.22 87.5,45.72 87.39,45.72 87.22,45.89 87.22,46.29 CPU1.AK51 ; RAM3.B8 v1(117.4,34.7)
M_A_DQ1: length 41
  TOP w0.089: v1(116.6,34.7) v2(115.99,34.7)
  L4 w0.114: v1(116.6,34.7) 116.35,34.96 102.47,34.96 102.36,34.84 102.36,34.61 102.47,34.5 103.84,34.5 103.95,34.38 103.95,34.16 103.84,34.04 100.23,34.04 97.19,37.09 95.57,37.09 94.28,38.37 94.28,39.2 92.14,41.34 91.92,41.34 90.82,42.45 90.82,43.36 89.73,44.45 v1(89.22,44.45)
  BOTTOM w0.089: CPU1.AL51 87.81,46.39 87.81,46.01 88.39,45.43 88.39,44.75 88.69,44.45 v1(89.22,44.45) ; RAM3.A7 v1(116.6,34.7)
M_A_DQ2: length 40.9
  TOP w0.089: v2(118.53,39.18) 118.2,38.85 v1(118.2,38.7)
  L4 w0.114: v1(118.2,38.7) 118.26,38.64 118.26,38.18 118.11,38.03 103.61,38.03 103.5,37.91 103.5,37.68 103.61,37.57 105.52,37.57 105.63,37.46 105.63,37.23 105.52,37.11 100.33,37.11 96.9,40.55 96.4,40.55 94.3,42.65 94.3,42.87 93.55,43.62 92.72,43.62 92.02,44.32 v1(92.02,44.49)
  BOTTOM w0.089: RAM3.C3 v1(118.2,38.7) ; CPU1.AT52 89.71,48.06 92.06,45.72 92.06,44.53 v1(92.02,44.49)
M_A_DQ3: length 43.7
  TOP w0.089: v2(116.98,38.28) 116.6,38.65 v1(116.6,38.7)
  L4 w0.114: v1(90.77,46.08) 91.26,46.08 93.42,43.91 93.79,43.91 94.67,43.03 94.67,42.8 96.54,40.92 97.04,40.92 100.49,37.48 103,37.48 103.12,37.6 103.12,37.82 103,37.94 100.68,37.94 100.57,38.05 100.57,38.28 100.68,38.4 115.79,38.4 115.91,38.51 115.91,38.74 115.79,38.85 114.35,38.85 114.23,38.97 114.23,39.2 114.35,39.31 116.14,39.31 116.6,38.85 v1(116.6,38.7)
  BOTTOM w0.089: RAM3.A3 v1(116.6,38.7) ; CPU1.AR51 89.2,47.75 89.73,47.75 90.77,46.71 v1(90.77,46.08)
M_A_DQ4: length 42.2
  TOP w0.089: v1(119,34.7) 119.21,34.7 v2(119.51,34.41)
  L4 w0.114: v1(88.83,44.96) 89.53,44.96 91.03,43.45 91.03,42.6 92.06,41.57 92.43,41.57 94.65,39.35 94.65,38.53 95.72,37.46 97.34,37.46 100.39,34.41 101.86,34.41 101.98,34.52 101.98,34.75 101.86,34.87 100.58,34.87 100.47,34.98 100.47,35.21 100.58,35.33 116.86,35.33 117.05,35.13 118.85,35.13 119,34.97 v1(119,34.7)
  BOTTOM w0.089: RAM3.D7 v1(119,34.7) ; v1(88.83,44.96) 88.83,45.27 88.13,45.97 CPU1.AL53
M_A_DQ5: length 39.9
  TOP w0.089: v1(118.2,33.9) v2(117.79,33.49)
  L4 w0.114: v1(89.63,43.96) 89.63,42.81 92.92,39.52 92.92,37.95 93.26,37.61 94,37.61 95.42,36.19 97.04,36.19 99.93,33.31 105.73,33.31 106.65,34.22 115.81,34.22 116.55,33.49 v2(117.79,33.49) v1(118.2,33.9)
  BOTTOM w0.089: v1(89.63,43.96) 89.16,43.96 89.04,44.08 88.79,44.08 88.18,44.69 88.18,45.33 87.51,46 CPU1.AK52 ; RAM3.C8 v1(118.2,33.9)
M_A_DQ6: length 43.5
  TOP w0.089: v2(116.96,39.95) 116.6,39.6 v1(116.6,39.5)
  L4 w0.114: v1(89.86,47) 90.26,47 90.36,46.9 90.74,46.9 93.47,44.17 94.05,44.17 95.04,43.19 95.04,42.95 96.7,41.29 97.2,41.29 99.72,38.76 113.4,38.76 114.24,39.61 115.52,39.61 116.35,40.45 117.7,40.45 117.81,40.56 117.81,40.79 117.7,40.9 117.1,40.9 116.98,41.02 116.98,41.33 117.1,41.45 119.25,41.45 119.37,41.33 119.37,41.02 119.25,40.9 118.71,40.9 118.59,40.79 118.59,40.56 118.71,40.45 119.27,40.45 119.39,40.33 119.39,40.07 119.27,39.95 117.06,39.95 v1(116.6,39.5)
  BOTTOM w0.089: v1(89.86,47) 89.86,47.09 CPU1.AR53 ; RAM3.A2 v1(116.6,39.5)
M_A_DQ7: length 45.5
  TOP w0.089: v1(119,38.7) 119,38.13 v2(118.82,37.95)
  L4 w0.114: v1(91.62,45.13) 91.61,45.12 91.61,44.32 92.58,43.35 93.29,43.35 93.93,42.71 93.93,42.49 96.25,40.18 96.75,40.18 100.18,36.74 109.04,36.74 109.15,36.86 109.15,37.09 109.04,37.2 106.12,37.2 106,37.32 106,37.55 106.12,37.66 118.73,37.66 119.09,38.02 119.09,38.61 v1(119,38.7)
  BOTTOM w0.089: RAM3.C2 v1(119,38.7) ; CPU1.AP51 88.6,47.66 88.6,47.24 88.77,47.07 88.95,47.07 91,45.02 91.5,45.02 91.62,45.13 v1(91.62,45.13)
M_A_DQ8: length 47.7
  TOP w0.089: v2(120.62,48.21) 120.54,48.3 v1(120.54,48.76)
  L4 w0.089: v1(88.07,48.83) 88.07,48.09 88.42,47.74 90.08,47.74 90.52,47.3 90.9,47.3 93.38,44.82 93.98,44.82
  L4 w0.114: 93.98,44.82 94.45,44.82 95.77,43.49 95.77,43.39 96.9,42.26 97.86,42.26 100.14,39.98 111.53,39.98 111.65,40.09 111.65,40.23 111.76,40.34 111.99,40.34 112.1,40.23 112.1,40.09 112.22,39.98 112.45,39.98 112.56,40.09 112.56,40.49 112.68,40.61 112.9,40.61 113.02,40.49 113.02,40.09 113.13,39.98 113.36,39.98 113.48,40.09 113.48,40.57 113.59,40.68 113.74,40.68 115.7,42.65 115.87,42.65 116.07,42.45 116.23,42.45 116.39,42.61 116.39,42.77 116.19,42.97 116.19,43.13 116.35,43.29 116.51,43.29 116.69,43.12 116.85,43.12 117.01,43.28 117.01,43.44 116.84,43.62 116.84,43.78 116.89,43.83 116.89,45.13 119.23,47.47 119.23,47.99 119.59,48.35 120.12,48.35 v1(120.54,48.76)
  BOTTOM w0.089: v1(88.07,48.83) 88,48.76 87.49,48.76 ; RAM1.F8 121.32,47.82 121.32,48.43 121,48.76 v1(120.54,48.76)
M_A_DQ9: length 49.2
  TOP w0.089: v1(120.3,49.86) 120.3,49.59 v2(120.06,49.35)
  L4 w0.089: v1(87.74,50.55) 87.59,50.4 87.59,50.04 88.52,49.12 88.52,48.97 89.02,48.47 89.92,48.47 90.69,47.7 91.07,47.7 92.88,45.89
  L4 w0.114: v1(120.3,49.86) 120.3,49.68 119.48,48.86 119.28,48.86 118.99,49.15 118.54,49.15 118.4,49.01 118.4,48.65 118.32,48.57 117.55,48.57 117.41,48.44 117.25,48.44 117.18,48.51 117.02,48.51 116.86,48.35 116.86,48.19 117.07,47.98 117.07,47.71 116.92,47.56 116.33,47.56 116.15,47.38 116.15,46.76 116.27,46.64 116.44,46.64 116.55,46.53 116.55,46.3 116.44,46.19 116.27,46.19 116.15,46.07 116.15,44.14 113.45,41.43 110.26,41.43 109.54,40.72 100.45,40.72 97.61,43.56 96.83,43.56 94.88,45.5 93.28,45.5 92.88,45.89
  BOTTOM w0.089: CPU1.AT47 87.67,50.48 v1(87.74,50.55) ; RAM1.H7 122.08,48.82 122.08,48.81 121.57,48.81 121.18,49.2 121.18,49.72 121.02,49.88 120.32,49.88 v1(120.3,49.86)
M_A_DQ10: length 43.6
  TOP w0.089: v1(120.6,51.91) 120.6,52.55 v2(120.52,52.63)
  L4 w0.089: v1(89.73,51.41) 89.73,50.82 90.08,50.46 90.08,50.19 90.43,49.84 91.28,49.84 91.4,49.96 92.09,49.96 92.49,50.36 93.07,50.36 93.41,50.02 93.41,49.97 94.15,49.23 94.36,49.23 95.01,48.59
  L4 w0.114: 95.01,48.59 96.77,46.82 97.35,46.82 100.62,43.56 112.49,43.56 114.5,45.57 114.5,49.02 115.68,50.2 115.68,51.43 115.92,51.67 116.41,51.67 117.06,52.32 120.18,52.32 v1(120.6,51.91)
  BOTTOM w0.089: RAM1.F2 120.61,51.91 v1(120.6,51.91) ; CPU1.AY48 89.58,51.25 v1(89.73,51.41)
M_A_DQ11: length 43.5
  TOP w0.089: v2(119.38,50.44) 119.78,50.84 v1(119.78,50.95)
  L4 w0.089: v1(89.46,50.25) 90.25,49.46 91.44,49.46 91.51,49.53 92.32,49.53 93.15,48.7 93.15,48.69
  L4 w0.114: v1(119.78,50.95) 119.78,51.1 119.67,51.22 119.15,51.22 119.04,51.1 119.04,50.66 118.92,50.54 116.63,50.54 115.83,49.74 115.83,49.38 114.93,48.48 114.93,44.91 112.84,42.82 102.17,42.82 102.05,42.71 102.05,42.25 101.94,42.14 101.71,42.14 101.6,42.25 101.6,42.71 101.48,42.82 101.25,42.82 101.14,42.71 101.14,42.47 101.03,42.35 100.8,42.35 100.68,42.47 100.68,42.71 100.57,42.82 100.31,42.82 96.95,46.19 96.4,46.19 95.52,47.07 94.77,47.07 93.15,48.69
  BOTTOM w0.089: v1(119.78,50.95) 120.2,51.37 RAM1.E3 ; v1(89.46,50.25) 89.35,50.14 CPU1.AV50
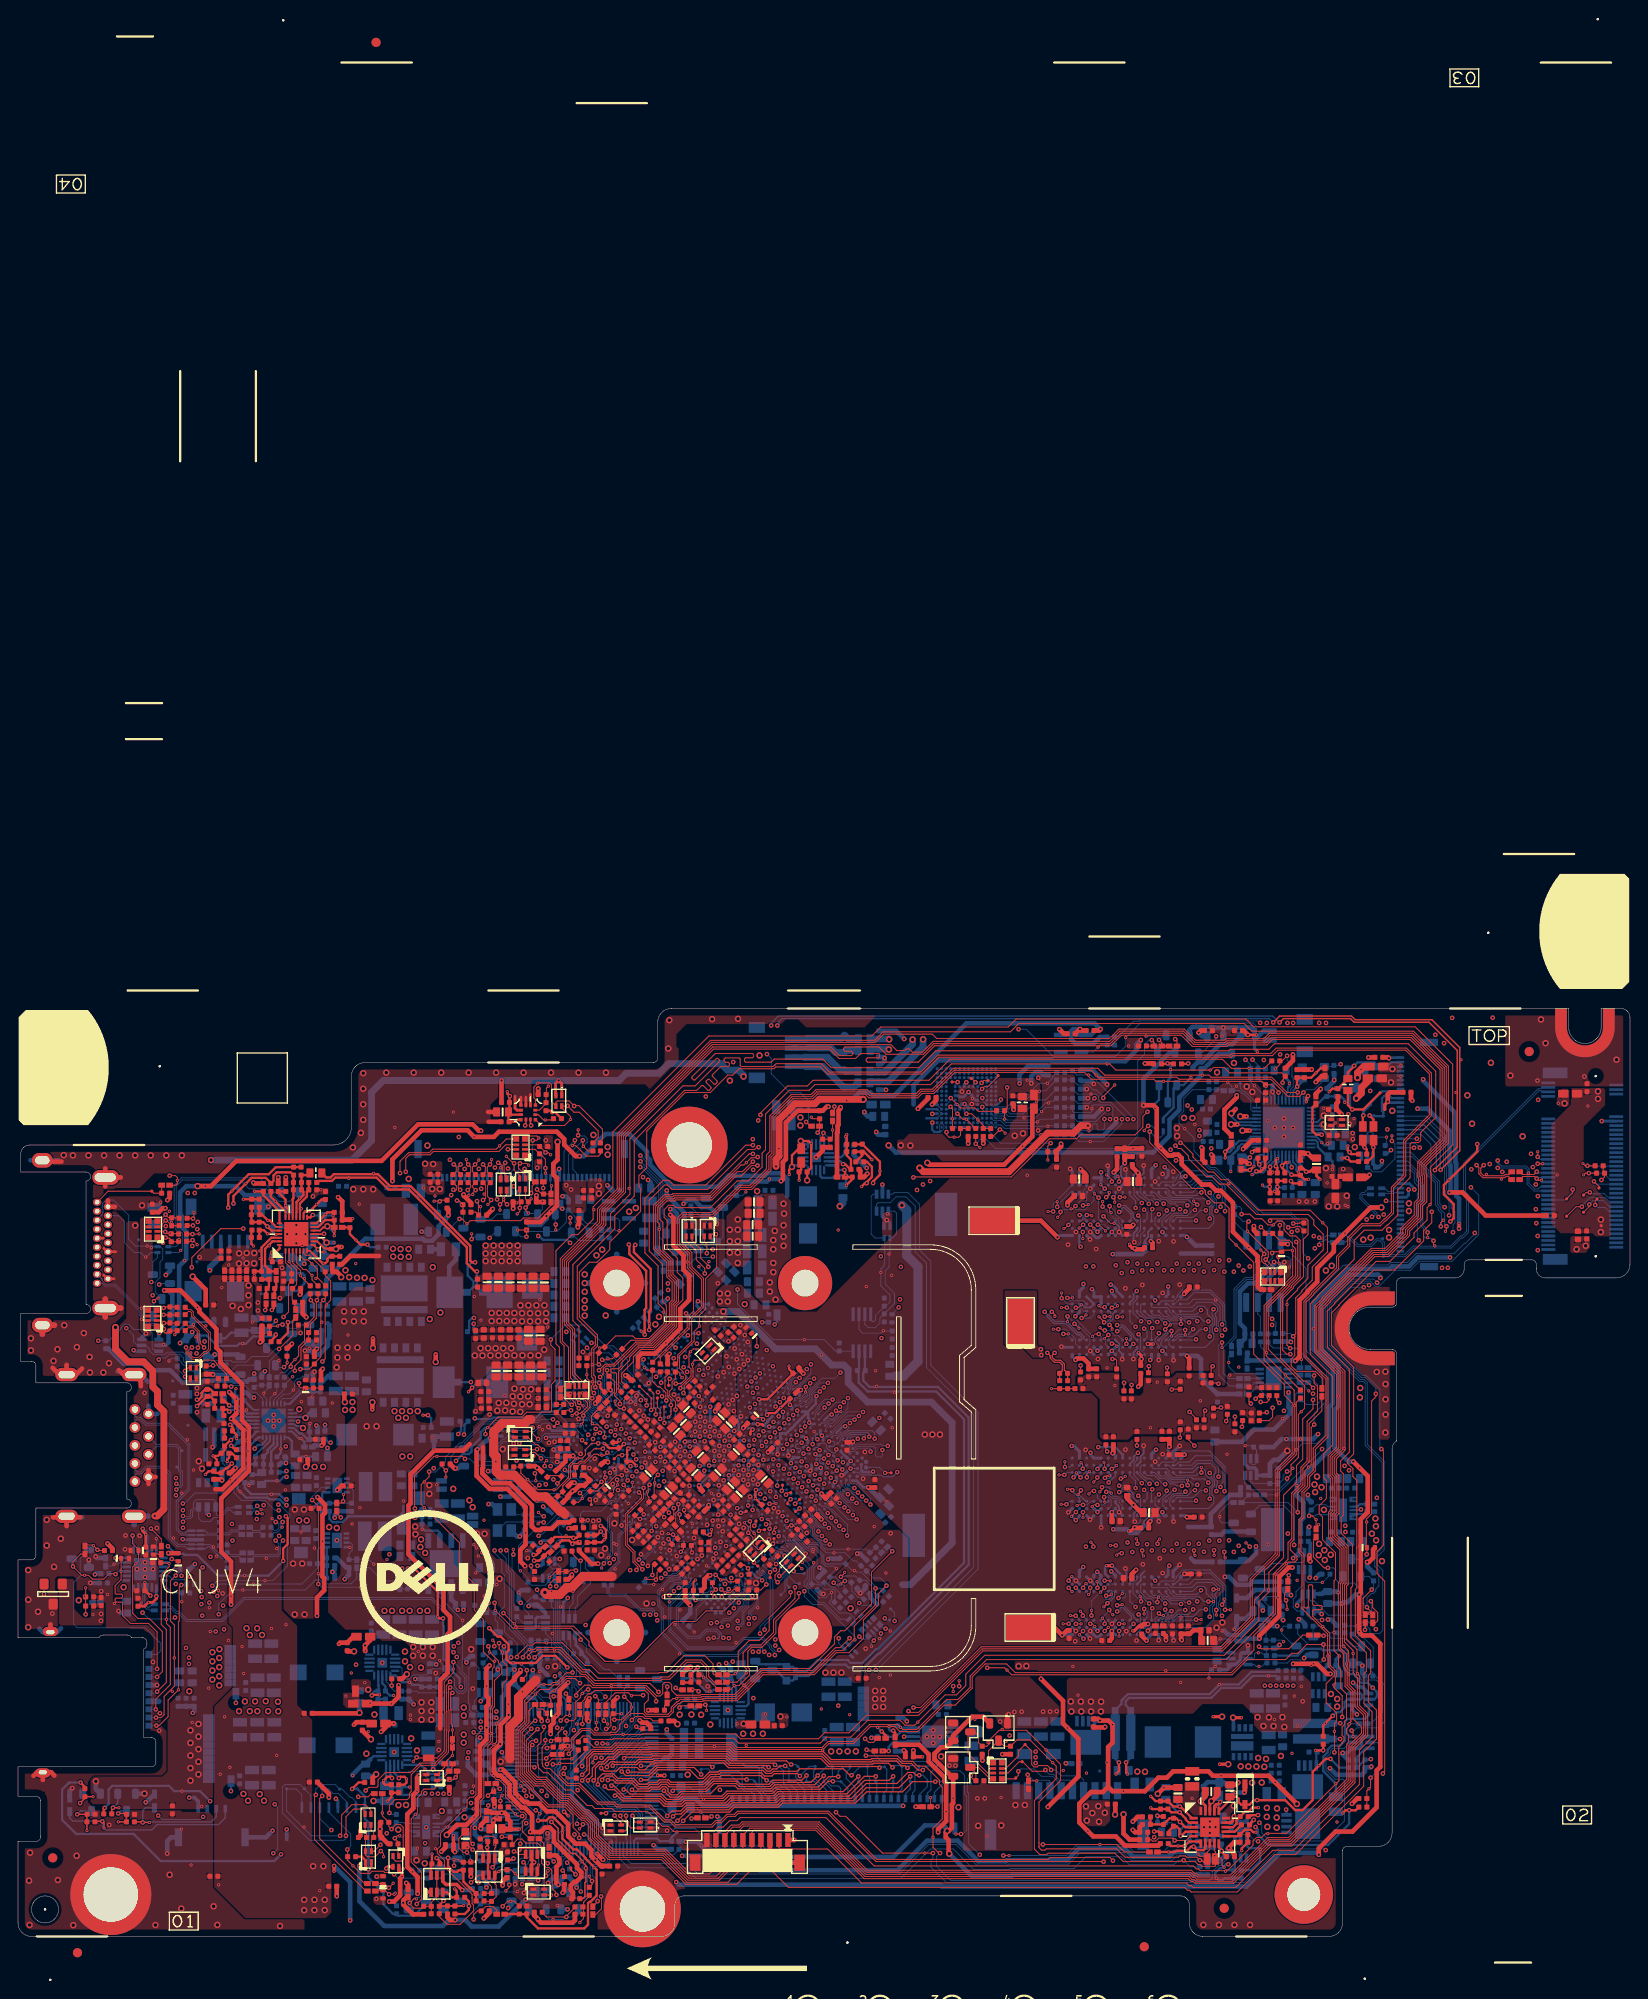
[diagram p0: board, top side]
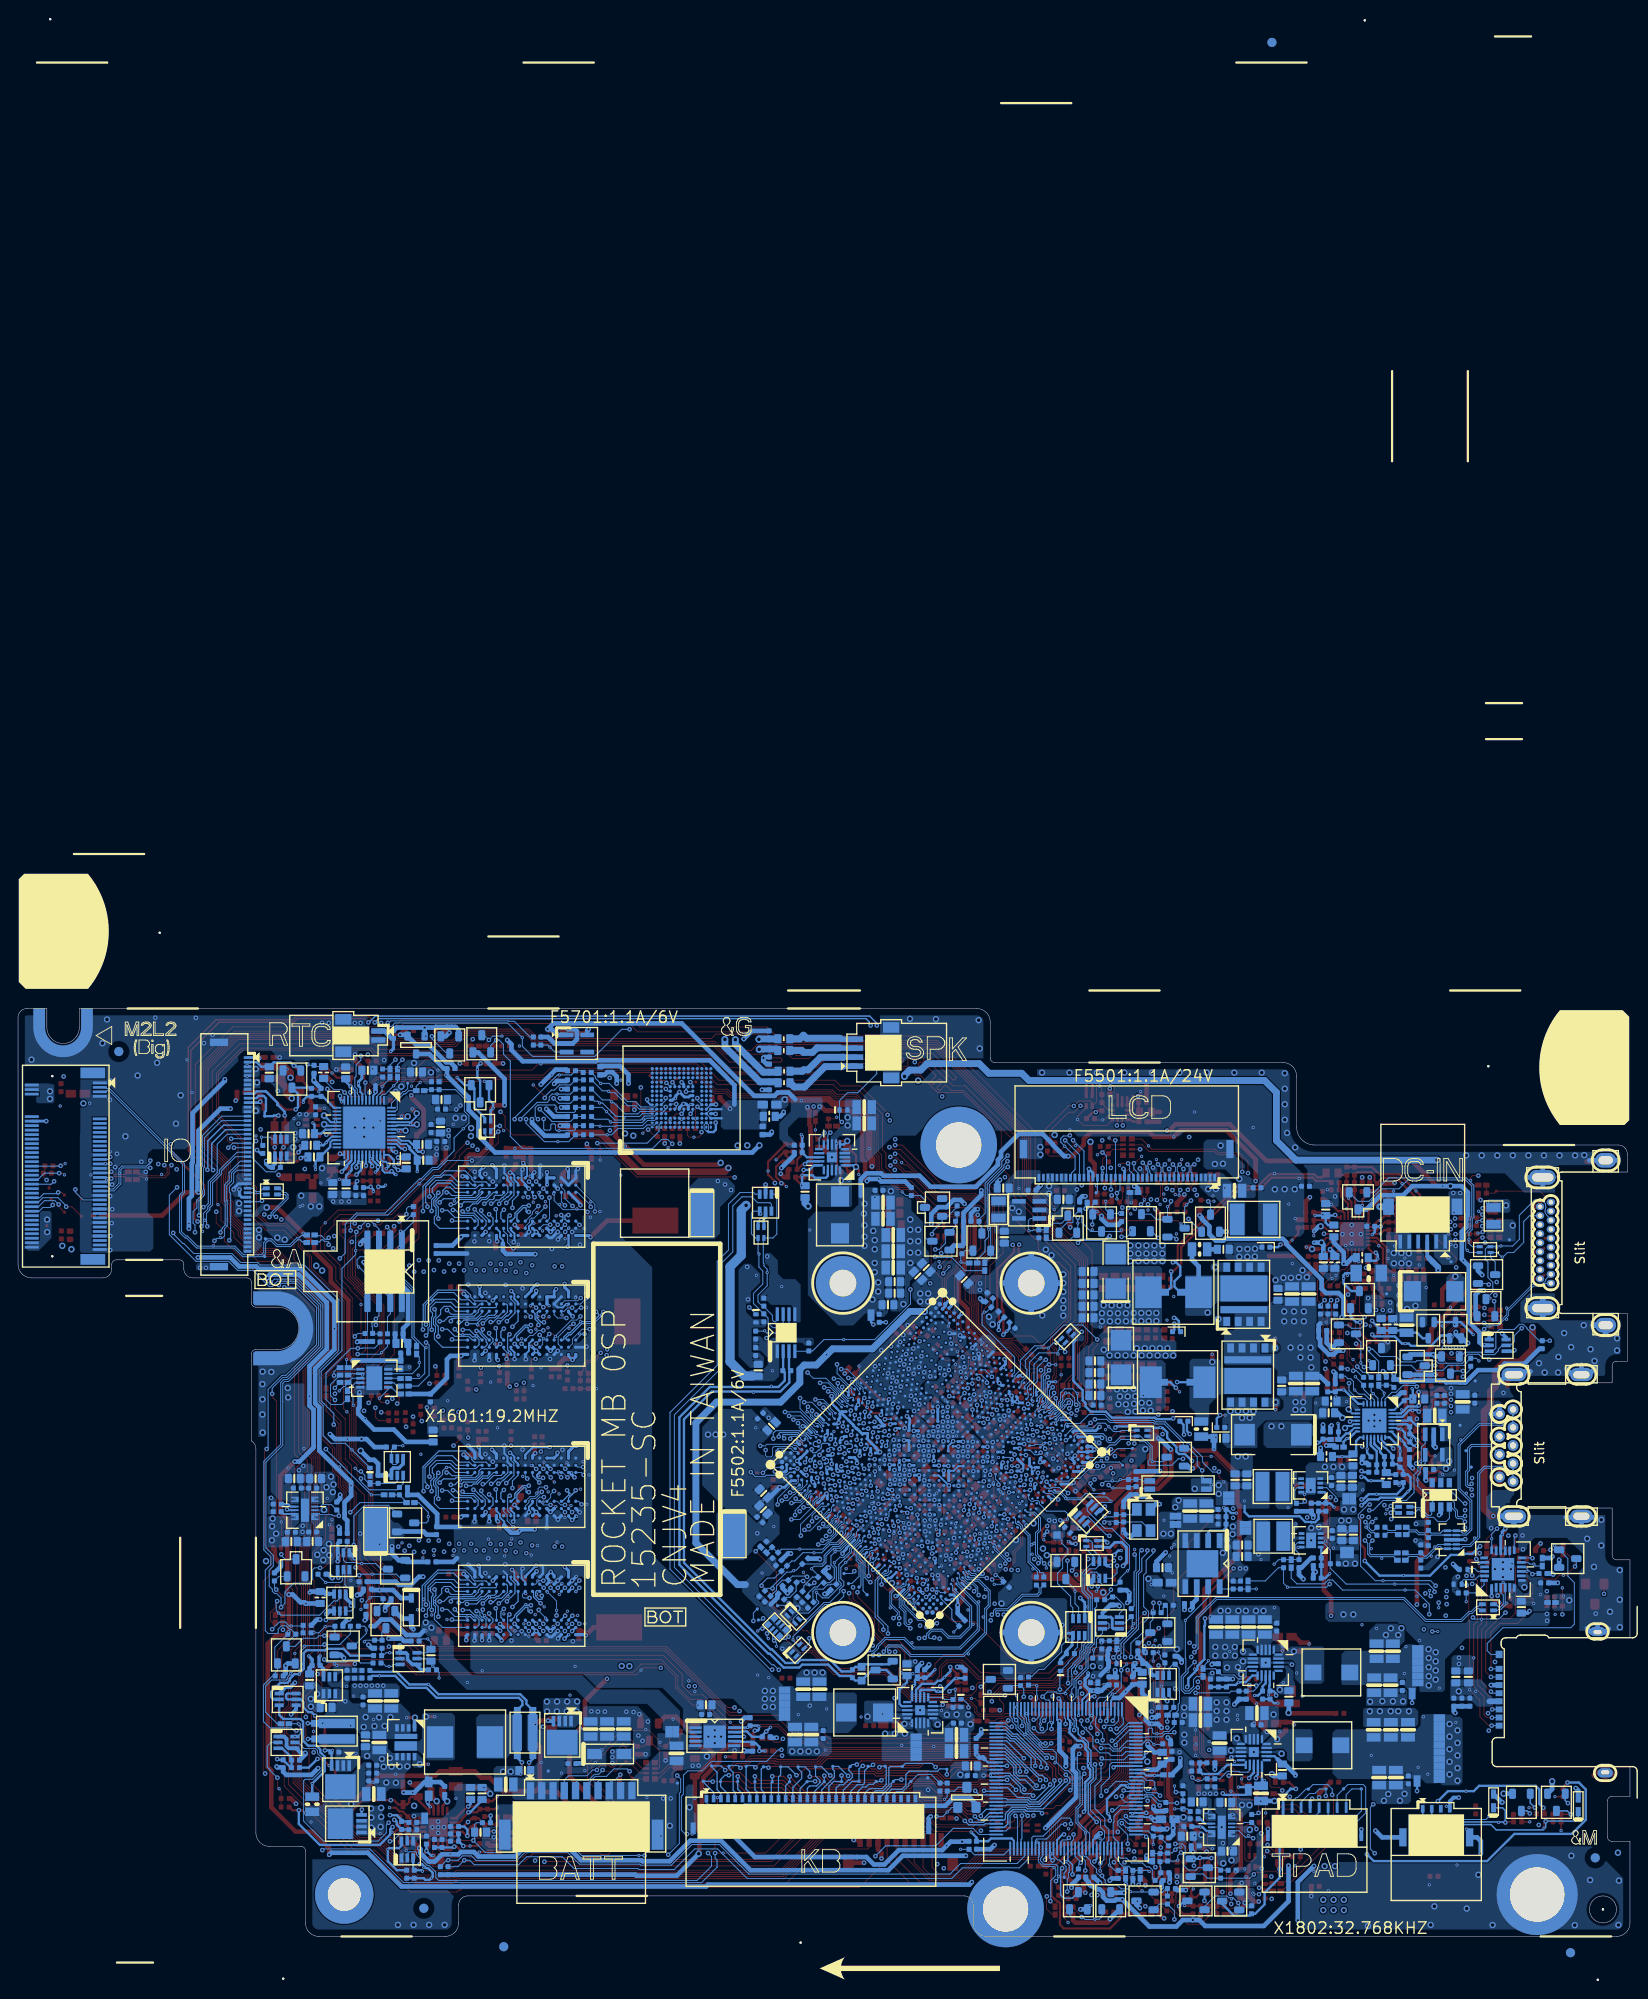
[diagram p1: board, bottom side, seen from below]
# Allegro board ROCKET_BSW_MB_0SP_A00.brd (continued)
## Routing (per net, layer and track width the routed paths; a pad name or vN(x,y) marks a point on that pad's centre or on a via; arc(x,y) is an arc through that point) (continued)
M_A_DQ12: length 48.5
  TOP w0.089: v1(119.8,47.9) 119.41,47.9 v2(119.21,47.71)
  L4 w0.089: v1(87.5,49.4) 87.5,48.37 88.32,47.55 90,47.55 90.44,47.11 90.83,47.11 93.4,44.53 93.92,44.53
  L4 w0.114: v1(119.8,47.9) 119.8,47.73 117.38,45.31 117.38,43.13 116.2,41.94 116.03,41.94 115.76,42.21 115.6,42.21 115.44,42.05 115.44,41.89 116.02,41.3 116.02,41.14 115.86,40.98 115.69,40.98 115.11,41.56 114.95,41.56 114.79,41.4 114.79,41.24 115.38,40.65 115.38,40.49 115.21,40.33 115.05,40.33 114.47,40.92 114.3,40.92 113.74,40.35 113.74,40.05 113.3,39.61 99.99,39.61 97.71,41.89 96.75,41.89 95.4,43.23 95.4,43.34 94.22,44.53 93.92,44.53
  BOTTOM w0.089: v1(119.8,47.9) 120.6,47.9 RAM1.F7 ; v1(87.5,49.4) 87.37,49.26 CPU1.AP47
M_A_DQ13: length 46.8
  TOP w0.089: v1(120.78,49.35) 121.19,49.35 v2(121.34,49.2)
  L4 w0.089: 94.08,45.13 93.34,45.13 90.96,47.51 90.61,47.51 89.85,48.28 88.64,48.28 v1(88.54,48.38)
  L4 w0.114: 94.08,45.13 94.73,45.13 96.67,43.19 97.46,43.19 100.3,40.35 110.14,40.35 110.26,40.46 110.26,40.91 110.37,41.02 110.6,41.02 110.71,40.91 110.71,40.48 110.83,40.36 111.06,40.36 111.17,40.48 111.17,40.94 111.29,41.05 111.51,41.05 111.63,40.94 111.63,40.83 111.74,40.72 111.97,40.72 112.09,40.83 112.09,40.94 112.2,41.05 113.59,41.05 116.52,43.99 116.52,45.29 116.98,45.75 116.98,47.31 118.02,48.35 118.64,48.35 118.88,48.59 119.6,48.59 120.36,49.35 v1(120.78,49.35)
  BOTTOM w0.089: CPU1.AT50 88.54,48.86 v1(88.54,48.38) ; RAM1.H8 122.6,47.77 122.2,48.17 122.2,48.36 121.93,48.62 121.46,48.62 120.77,49.31 120.77,49.34 v1(120.78,49.35)
M_A_DQ14: length 45.5
  TOP w0.089: v2(121.92,52.27) 121.55,51.9 121.4,51.9 v1(121.4,51.89)
  L4 w0.089: 94.3,49.44 94.3,49.45 94.2,49.45 93.6,50.05 93.6,50.1 93.14,50.55 92.42,50.55 92.02,50.15 91.32,50.15 91.21,50.04 90.51,50.04 90.27,50.27 90.27,50.84 v1(90.2,50.92)
  L4 w0.114: v1(121.4,51.89) 121.24,52.05 121.24,52.22 121.91,52.89 121.91,53.05 121.75,53.21 121.59,53.21 120.91,52.54 116.04,52.54 115.44,51.94 115.44,50.27 114.28,49.11 114.28,45.87 112.33,43.93 100.77,43.93 97.62,47.07 96.9,47.07 94.53,49.44 94.3,49.44
  BOTTOM w0.089: RAM1.G2 121.39,51.89 v1(121.4,51.89) ; v1(90.2,50.92) 90.05,50.77 CPU1.AY50
M_A_DQ15: length 47.9
  TOP w0.089: v1(122.39,50.81) 122.63,50.81 v2(122.89,51.07)
  L4 w0.089: v1(88.45,51.25) 89.03,51.25 89.73,50.55 89.89,50.39 89.89,50.11 90.35,49.65 91.36,49.65 91.48,49.77 92.2,49.77 92.6,50.17 92.99,50.17 93.22,49.94 93.22,49.89 94.17,48.95
  L4 w0.114: 94.17,48.95 94.34,48.95 96.86,46.42 97.24,46.42 100.47,43.19 112.69,43.19 114.71,45.21 114.71,48.64 115.58,49.5 115.58,49.8 115.92,50.14 115.92,50.59 116.1,50.77 116.34,50.77 116.94,51.38 117.07,51.38 117.19,51.49 117.19,51.92 117.3,52.03 117.53,52.03 117.64,51.92 117.64,51.49 117.76,51.38 118.65,51.38 118.75,51.48 120.88,51.48 120.99,51.36 120.99,51.15 121.1,51.03 121.33,51.03 121.45,51.15 121.45,51.36 121.56,51.48 122.04,51.48 122.39,51.14 v1(122.39,50.81)
  BOTTOM w0.089: CPU1.AV45 87.96,51.24 88.44,51.24 v1(88.45,51.25) ; RAM1.H3 122.6,51.03 v1(122.39,50.81)
M_A_DQ16: length 56
  TOP w0.089: v1(120.6,34.7) 120.6,35.07 v2(120.34,35.33)
  L3 w0.089: v1(84.99,51.91) 84.99,50.44 88.19,47.24 88.19,46.21 90.59,43.81 90.59,43.58
  L3 w0.114: v1(120.6,34.7) 120.6,35.13 119.41,36.32 113.36,36.32 113.21,36.17 104.38,36.17 104.03,36.51 99.79,36.51 98.99,36.51 97.04,38.46 96.21,38.46 95.94,38.74 95.94,39.76 94,41.7 93.76,41.7 93.59,41.53 93.59,41.29 95.29,39.59 95.29,39.43 95.09,39.23 94.93,39.23 93.24,40.93 93.08,40.93 93,40.85 92.81,40.85 92.68,40.98 92.68,41.17 92.97,41.47 92.97,41.66 92.84,41.79 92.65,41.79 92.31,41.46 92.15,41.46 91.99,41.62 91.99,41.78 92.11,41.9 92.11,42.06 92.04,42.13 91.88,42.13 91.67,41.92 91.51,41.92 91.35,42.08 91.35,42.24 91.56,42.45 91.56,42.61 91.39,42.77 91.23,42.77 91.02,42.57 90.86,42.57 90.7,42.73 90.7,42.89 90.91,43.1 90.91,43.26 90.59,43.58
  BOTTOM w0.089: v1(120.6,34.7) RAM3.F7 ; CPU1.AT40 85.23,52.15 v1(84.99,51.91)
M_A_DQ17: length 55.9
  TOP w0.089: v1(122.2,33.9) v2(122.2,33.33)
  L3 w0.089: 91.7,43.32 90.53,44.49 90.53,45.38 89.55,46.37 89.55,46.47 86.07,49.95 v1(86.07,50.81)
  L3 w0.114: 91.7,43.32 92.03,42.99 92.42,42.99 92.53,43.11 92.53,43.56 92.64,43.67 92.87,43.67 92.99,43.56 92.99,43.11 93.1,42.99 93.74,42.99 99.48,37.25 104.34,37.25 104.6,36.99 119.62,36.99 121.16,35.44 122.45,35.44 122.63,35.63 122.63,36.38 122.75,36.49 123.11,36.49 123.23,36.38 123.23,35.8 123.38,35.64 123.83,35.64 124.31,35.16 124.77,35.16 124.98,34.96 124.98,33.46 124.77,33.26 122.41,33.26 122.2,33.46 v1(122.2,33.9)
  BOTTOM w0.089: v1(122.2,33.9) RAM3.H8 ; v1(86.07,50.81) 85.51,50.81 CPU1.AP42
M_A_DQ18: length 49.7
  TOP w0.089: v1(119.13,35.62) 119.13,36.04 119.14,36.04 v2(119.14,36.2)
  L3 w0.089: 88.42,44.21 88.23,44.4 88.23,45.03 87.64,45.62 87.64,47.25 84.31,50.59 84.31,51.73 83.82,52.21 v1(83.82,52.96)
  L3 w0.114: 88.42,44.21 88.42,44.03 95.25,37.2 97.26,37.2 99.27,35.18 118.7,35.18 v1(119.13,35.62)
  BOTTOM w0.089: v1(83.82,52.96) 83.83,52.97 CPU1.AT38 ; v1(119.13,35.62) 119.13,37.23 RAM3.E3
M_A_DQ19: length 53.4
  TOP w0.089: v2(121,34.3) v1(120.6,33.9)
  L3 w0.089: v1(84.4,52.31) 84.4,51.91 84.58,51.73 84.58,50.59 87.83,47.33 87.83,45.78 88.43,45.19 88.43,44.54 90.45,42.52
  L3 w0.114: v1(120.6,33.9) 120.47,33.9 119.7,34.68 119.7,35.73 119.32,36.11 113.51,36.11 113.21,35.8 104.2,35.8 103.87,36.13 103.57,36.13 103.45,36.02 103.45,35.68 103.34,35.57 103.11,35.57 102.99,35.68 102.99,35.96 102.86,36.09 102.67,36.09 102.54,35.96 102.54,35.68 102.42,35.57 102.19,35.57 102.08,35.68 102.08,36.02 101.97,36.13 101.74,36.13 101.62,36.02 101.62,35.68 101.51,35.57 101.28,35.57 101.17,35.68 101.17,36.02 101.05,36.13 100.82,36.13 100.71,36.02 100.71,35.68 100.59,35.57 100.37,35.57 100.25,35.68 100.25,36.02 100.14,36.13 99.91,36.13 99.79,36.02 99.79,35.68 99.68,35.57 99.45,35.57 99.34,35.68 99.34,36.02 99.22,36.13 98.84,36.13 97.25,37.72 96.97,37.72 96.86,37.84 96.86,37.84 96.73,37.98 96.54,37.98 96.4,37.84 96.4,37.72 96.27,37.58 96.08,37.58 95.95,37.72 95.95,37.95 95.83,38.06 94.93,38.06 94.46,38.53 94.46,38.66 90.6,42.52 90.45,42.52
  BOTTOM w0.089: v1(120.6,33.9) RAM3.F8 ; CPU1.AP40 84.47,52.24 v1(84.4,52.31)
M_A_DQ20: length 56.3
  TOP w0.089: v1(122.13,37.57) 122.13,37.63 v2(122.56,38.06)
  L3 w0.089: 89.99,48.15 89.99,48.93 87.83,51.1 v1(87.21,51.1)
  L3 w0.114: 89.99,48.15 93.44,44.71 94.79,44.71 96.29,43.21 97.2,43.21 97.47,42.94 97.47,41.54 97.75,41.26 97.91,41.26 98.42,41.77 98.61,41.77 98.74,41.64 98.74,41.45 98.23,40.94 98.23,40.78 98.39,40.62 98.56,40.62 99.09,41.15 99.26,41.15 99.41,40.99 99.41,40.83 98.88,40.29 98.88,40.13 99.16,39.85 99.72,39.85 99.83,39.97 99.83,40.45 99.97,40.59 100.15,40.59 100.29,40.45 100.29,39.97 100.4,39.85 100.63,39.85 100.75,39.97 100.75,40.46 100.88,40.59 101.07,40.59 101.2,40.46 101.2,39.97 101.32,39.85 101.55,39.85 101.66,39.97 101.66,40.45 101.79,40.59 101.98,40.59 102.12,40.45 102.12,39.97 102.23,39.85 102.46,39.85 102.57,39.97 102.57,40.46 102.71,40.6 102.9,40.6 103.03,40.46 103.03,39.97 103.15,39.85 103.37,39.85 103.49,39.97 103.49,40.45 103.62,40.58 103.81,40.58 103.95,40.45 103.95,39.97 104.06,39.85 104.29,39.85 104.4,39.97 104.4,40.46 104.54,40.59 104.73,40.59 104.86,40.46 104.86,39.97 104.98,39.85 105.2,39.85 105.32,39.97 105.32,40.46 105.45,40.6 105.64,40.6 105.78,40.46 105.78,39.97 105.89,39.85 114.49,39.85 116.1,38.24 120.46,38.24 120.48,38.26 121.44,38.26 v1(122.13,37.57)
  BOTTOM w0.089: v1(87.21,51.1) 86.81,51.1 CPU1.AT44 ; RAM3.H3 122.91,37.99 122.91,37.71 122.77,37.57 v1(122.13,37.57)
M_A_DQ21: length 55.5
  TOP w0.089: v1(120.6,39.49) 121.19,39.49 v2(121.22,39.46)
  L3 w0.089: v1(86.97,52.72) 87.74,52.72 88.43,52.04 88.49,52.04 89.2,51.33 89.22,51.33 90.22,50.33 90.22,49.64 90.79,49.07 90.79,47.94 92.49,46.24 92.54,46.24
  L3 w0.114: v1(120.6,39.49) 120.07,39.49 119.25,40.32 115.57,40.32 114.27,41.62 99.85,41.62 99.72,41.75 99.72,41.94 99.85,42.08 105.84,42.08 105.98,42.21 105.98,42.4 105.84,42.53 98.91,42.53 97.5,43.95 96.79,43.95 95.52,45.22 93.55,45.22 92.54,46.24
  BOTTOM w0.089: v1(86.97,52.72) 86.91,52.66 CPU1.AV41 ; RAM3.G2 121.47,39.1 121.08,39.49 v1(120.6,39.49)
M_A_DQ22: length 52.1
  TOP w0.089: v1(122.2,34.7) v2(122.77,34.7)
  L3 w0.089: 91.06,43.62 88.43,46.26 88.43,47.28 85.6,50.1 v1(85.6,51.34)
  L3 w0.114: v1(122.2,34.7) 122.59,34.3 123.24,34.3 123.69,33.85 124.24,33.85 124.44,34.06 124.44,34.65 123.88,35.21 120.88,35.21 119.56,36.54 104.53,36.54 104.19,36.88 99.64,36.88 99.64,36.88 99.33,36.88 94.14,42.07 92.61,42.07 91.06,43.62
  BOTTOM w0.089: CPU1.AP41 85.04,51.34 v1(85.6,51.34) ; RAM3.H7 v1(122.2,34.7)
M_A_DQ23: length 56.2
  TOP w0.089: v1(120.56,38.7) 120.56,38.63 v2(120.14,38.21)
  L3 w0.089: 93.41,45.05 90.6,47.86 90.6,48.92 89.96,49.56 89.96,50.32 89.14,51.14 89.12,51.14 88.41,51.85 88.35,51.85 88,52.19 v1(87.52,52.19)
  L3 w0.114: 93.41,45.05 93.51,44.95 95.27,44.95 96.64,43.58 97.35,43.58 99.95,40.98 106.59,40.98 106.82,41.21 107.01,41.21 107.14,41.07 107.14,40.32 107.24,40.22 107.5,40.22 107.6,40.32 107.6,41.13 107.72,41.25 107.93,41.25 108.05,41.13 108.05,40.32 108.16,40.22 108.41,40.22 108.51,40.32 108.51,41.11 108.64,41.24 108.83,41.24 108.97,41.11 108.97,40.32 109.07,40.22 109.32,40.22 109.43,40.32 109.43,41.11 109.56,41.24 109.75,41.24 109.88,41.11 109.88,40.3 109.96,40.22 110.26,40.22 110.34,40.3 110.34,41.13 110.46,41.25 110.68,41.25 110.8,41.13 110.8,40.32 110.89,40.22 114.06,40.22 114.2,40.35 114.2,40.54 114.06,40.68 111.45,40.68 111.34,40.79 111.34,41.02 111.45,41.13 114.43,41.13 115.46,40.1 119.11,40.1 120.51,38.7 v1(120.56,38.7)
  BOTTOM w0.089: v1(87.52,52.19) 87.49,52.16 CPU1.AV42 ; RAM3.F2 120.97,39.1 120.57,38.7 v1(120.56,38.7)
M_A_DQ24: length 31.7
  TOP w0.089: v1(117.92,50.96) 117.92,50.99 v2(117.45,51.46)
  L3 w0.114: v1(117.92,50.96) 117.92,50.96 117.31,50.36 116.62,50.36 113.35,47.09 103.78,47.09 102.72,48.15 101.75,48.15 101.26,47.65 98.52,47.65 98.31,47.87 94.67,47.87 v1(94.6,47.94)
  BOTTOM w0.089: v1(94.6,47.94) 94.6,48.62 92.99,50.23 92.53,50.23 92.31,50.45 92.31,50.72 92.32,50.73 CPU1.BD52 ; v1(117.92,50.96) 117.92,50.96 118.45,51.5 RAM1.C3
M_A_DQ25: length 33.3
  TOP w0.089: v1(116.36,47.97) v2(115.77,47.97)
  L3 w0.114: v1(116.36,47.97) 116.08,47.69 116.08,46.68 115.65,46.25 114.05,46.25 113.92,46.12 113.92,45.93 114.05,45.8 114.97,45.8 115.09,45.68 115.09,45.45 114.97,45.34 101.04,45.34 100.43,45.95 98.07,45.95 97.65,46.38 94.11,46.38 93.29,47.2 92.82,47.2 92.4,47.63 v1(91.72,47.63)
  BOTTOM w0.089: CPU1.AV52 90.68,48.33 90.68,48 91.05,47.63 v1(91.72,47.63) ; v1(116.36,47.97) 116.69,48.3 RAM1.A7
M_A_DQ26: length 32.8
  TOP w0.089: v2(117.97,52.58) 118.16,52.39 v1(118.16,51.91)
  L3 w0.114: v1(92.82,49.77) 93.86,49.77 94.28,49.36 98.78,49.36 99.16,48.97 100.22,48.97 100.63,49.39 103.44,49.39 104.02,48.81 105.54,48.81 105.65,48.92 105.65,49.17 105.79,49.3 105.97,49.3 106.11,49.17 106.11,48.92 106.22,48.81 106.45,48.81 106.57,48.92 106.57,49.23 106.68,49.35 106.91,49.35 107.02,49.23 107.02,48.92 107.14,48.81 107.37,48.81 107.48,48.92 107.48,49.23 107.59,49.35 107.82,49.35 107.94,49.23 107.94,48.92 108.05,48.81 108.44,48.81 109.02,49.39 113.35,49.39 114.74,50.78 114.74,51.4 115.98,52.65 117.43,52.65 v1(118.16,51.91)
  BOTTOM w0.089: v1(118.16,51.91) 118.55,52.3 RAM1.C2 ; CPU1.BC53 92.23,50.11 92.56,49.77 v1(92.82,49.77)
M_A_DQ27: length 33.4
  TOP w0.089: v1(118.2,47.1) v2(118.2,46.51)
  L3 w0.114: v1(93.07,46.29) 93.73,45.64 97.34,45.64 98.91,44.07 114.64,44.07 117.26,46.69 117.79,46.69 v1(118.2,47.1)
  BOTTOM w0.089: v1(93.07,46.29) 93.06,46.28 92.13,46.28 90.49,47.92 90.49,48.22 90.27,48.44 90.17,48.44 89.97,48.63 89.97,49.04 CPU1.AV51 ; v1(118.2,47.1) RAM1.C8
M_A_DQ28: length 33.5
  TOP w0.089: v1(117.4,47.1) v2(116.92,46.62)
  L3 w0.114: v1(117.4,47.1) 117.31,47.1 114.93,44.72 100.75,44.72 100.64,44.83 100.64,45.19 100.5,45.33 100.31,45.33 100.18,45.19 100.18,44.83 100.07,44.72 99.84,44.72 99.72,44.83 99.72,45.22 99.59,45.35 99.4,45.35 99.27,45.22 99.27,44.83 99.15,44.72 98.78,44.72 97.5,46.01 93.99,46.01 93.22,46.77 v1(92.66,46.77)
  BOTTOM w0.089: CPU1.AW51 90.57,49.13 90.96,49.13 91.18,48.9 91.18,48.73 91.89,48.01 91.89,48.01 92.13,47.78 92.13,47.78 92.33,47.58 92.34,47.58 92.66,47.26 v1(92.66,46.77) ; v1(117.4,47.1) RAM1.B8
M_A_DQ29: length 32.9
  TOP w0.089: v1(116.19,52.1) v2(116.19,52.69)
  L3 w0.114: v1(116.19,52.1) 115.58,51.5 115.58,50.24 115.42,50.09 115.26,50.09 115.07,50.29 114.88,50.29 114.74,50.15 114.74,49.97 114.94,49.77 114.94,49.61 114.78,49.44 114.62,49.44 114.41,49.65 114.22,49.65 114.09,49.52 114.09,49.33 114.29,49.12 114.29,48.96 114.11,48.77 110.14,48.77 110.02,48.66 110.02,48.28 109.91,48.18 109.67,48.18 109.56,48.28 109.56,48.66 109.45,48.77 109.22,48.77 109.11,48.66 109.11,48.26 108.97,48.12 103.95,48.12 103.08,49 101.11,49 100.6,48.48 99,48.48 98.6,48.88 94.29,48.88 93.82,49.34 93.3,49.34 v1(93.23,49.27)
  BOTTOM w0.089: RAM1.A2 116.8,52.1 v1(116.19,52.1) ; CPU1.BC52 91.84,50.59 91.84,49.97 92.04,49.77 92.26,49.77 92.76,49.27 v1(93.23,49.27)
M_A_DQ30: length 32.8
  TOP w0.089: v1(118.2,47.9) 117.61,47.9 v2(117.53,47.82)
  L3 w0.114: v1(118.2,47.9) 117.58,47.9 117.1,48.38 115.98,48.38 115.71,48.1 115.71,46.71 115.57,46.57 114,46.57 113.38,45.95 101,45.95 100.48,46.46 98.08,46.46 97.8,46.74 94.16,46.74 93.37,47.53 92.95,47.53 92.38,48.1 v1(91.19,48.1)
  BOTTOM w0.089: v1(91.19,48.1) 90.94,48.36 90.94,48.76 90.88,48.82 ; v1(118.2,47.9) 118.66,47.9 119.06,48.3 RAM1.D7
M_A_DQ31: length 33.3
  TOP w0.089: v1(116.12,51.23) v2(115.53,51.23)
  L3 w0.114: v1(94.14,48.38) 94.2,48.44 98.37,48.44 98.76,48.05 100.99,48.05 101.54,48.6 102.93,48.6 103.98,47.54 110.2,47.54 110.31,47.66 110.31,48.02 110.45,48.15 110.64,48.15 110.77,48.02 110.77,47.66 110.89,47.54 111.12,47.54 111.23,47.66 111.23,48.04 111.36,48.17 111.55,48.17 111.69,48.04 111.69,47.66 111.8,47.54 112.03,47.54 112.14,47.66 112.14,47.88 112.28,48.02 112.47,48.02 112.6,47.88 112.6,47.6 112.73,47.47 112.92,47.47 113.06,47.6 113.06,48 113.17,48.12 114.01,48.12 116.12,50.23 v1(116.12,51.23)
  BOTTOM w0.089: CPU1.BB51 91.34,50.2 91.99,49.55 92.21,49.55 92.72,49.04 92.81,49.04 93.48,48.38 v1(94.14,48.38) ; RAM1.A3 116.39,51.5 v1(116.12,51.23)
M_A_DQ32: length 39.5
  TOP w0.089: v2(117.75,67.51) 117.25,68 v1(117.25,68)
  L3 w0.114: v1(92.84,57.37) 92.84,58.53 93.44,59.13 98.48,59.13 98.99,59.64 101.13,59.64 101.25,59.75 101.25,59.98 101.13,60.1 100.64,60.1 100.53,60.21 100.53,60.44 100.64,60.55 105.63,60.55 113.08,68 v1(117.25,68)
  BOTTOM w0.089: RAM2.C8 118.96,65.76 118.96,66.54 117.65,67.85 117.4,67.85 v1(117.25,68) ; v1(92.84,57.37) 92.72,57.37 92.7,57.39 91.93,57.39 90.52,55.99 90.52,55.88 90.36,55.71 90.13,55.71 89.92,55.51 CPU1.BG42
M_A_DQ33: length 39.1
  TOP w0.089: v1(116.47,68.83) v2(116.47,68.24)
  L3 w0.114: v1(116.47,68.83) 113.25,68.83 105.59,61.16 99.7,61.16 99.58,61.05 99.58,60.82 99.7,60.71 100.04,60.71 100.15,60.59 100.15,60.36 100.04,60.25 99.08,60.25 98.34,59.51 94.97,59.51 94.84,59.64 93.41,59.64 92.33,58.56 v1(92.33,56.99)
  BOTTOM w0.089: CPU1.BG43 90.55,55.62 90.94,55.62 91.29,55.97 91.3,55.97 91.3,55.98 91.72,55.98 92.2,56.47 92.2,56.87 v1(92.33,56.99) ; v1(116.47,68.83) 116.88,68.42 117.49,68.42 119.4,66.5 RAM2.D7
M_A_DQ34: length 41.1
  TOP w0.089: v1(116.46,70.87) v2(117.05,70.87)
  L3 w0.114: v1(116.46,70.87) 115.24,72.09 112.09,72.09 106.16,66.15 106,66.15 105.84,66.31 105.84,66.48 106.48,67.12 106.48,67.28 106.31,67.44 106.15,67.44 104.36,65.65 99.48,65.65 96.37,62.55 92.97,62.55 90.74,60.32 90.36,60.32 89.96,59.91 v1(89.96,59.15)
  BOTTOM w0.089: v1(116.46,70.87) 116.77,70.56 118.24,70.56 RAM2.C2 ; 88.27,57.46 88.49,57.69 88.49,58.07 88.96,58.54 88.96,58.77 89.38,59.19 89.76,59.19 89.8,59.15 v1(89.96,59.15)
M_A_DQ35: length 39.6
  TOP w0.089: v2(118,70.1) 117.69,69.79 v1(117.4,69.79)
  L3 w0.114: v1(117.4,69.79) 116.77,70.42 115.46,70.42 114.57,71.31 112.64,71.31 105.8,64.48 101.14,64.48 101.03,64.36 101.03,64.13 101.14,64.02 102.16,64.02 102.28,63.9 102.28,63.68 102.16,63.56 99.25,63.56 97.37,61.68 93.06,61.68 91.06,59.68 91.06,59.63 90.13,58.7 v1(89.51,58.7)
  BOTTOM w0.089: CPU1.BJ37 89.51,58.7 v1(89.51,58.7) ; v1(117.4,69.79) 117.43,69.76 117.91,69.76 118.27,69.4 RAM2.C3
M_A_DQ36: length 37.3
  TOP w0.089: v1(115.46,67.41) v2(114.9,67.41)
  L3 w0.114: v1(93.33,57.77) 93.33,58.38 93.71,58.76 98.76,58.76 99.1,59.1 102.87,59.1 102.99,59.21 102.99,59.44 102.87,59.56 101.76,59.56 101.64,59.67 101.64,59.9 101.76,60.01 105.61,60.01 113,67.41 v1(115.46,67.41)
  BOTTOM w0.089: CPU1.BH42 92.01,57.77 v1(93.33,57.77) ; RAM2.B8 117.76,65.4 117.38,65.78 117.38,66.32 116.29,67.41 v1(115.46,67.41)
M_A_DQ37: length 37.5
  TOP w0.089: v1(116.02,66.88) v2(116.59,66.88)
  L3 w0.114: v1(116.02,66.88) 115.82,66.68 112.89,66.68 105.63,59.41 103.55,59.41 103.44,59.3 103.44,59.07 103.55,58.95 105.96,58.95 106.07,58.84 106.07,58.61 105.96,58.49 99.59,58.49 99.31,58.21 v1(93.79,58.21)
  BOTTOM w0.089: CPU1.BJ41 90.47,56.62 92.08,58.22 93.68,58.22 93.69,58.21 v1(93.79,58.21) ; RAM2.A7 116.32,66.88 v1(116.02,66.88)
M_A_DQ38: length 39.9
  TOP w0.089: v1(115.82,70.84) v2(115.82,71.43)
  L3 w0.114: v1(90.41,59.6) 92.92,62.12 96.92,62.12 98.92,64.12 100.52,64.12 100.64,64.23 100.64,64.46 100.52,64.58 99.64,64.58 99.53,64.69 99.53,64.92 99.64,65.04 104.54,65.04 105.37,65.86 105.53,65.86 105.69,65.7 105.69,65.54 105.39,65.24 105.39,65.08 105.56,64.92 105.72,64.92 112.51,71.71 114.95,71.71 v1(115.82,70.84)
  BOTTOM w0.089: RAM2.A2 116.94,70.2 116.94,70.2 116.46,70.2 115.83,70.84 v1(115.82,70.84) ; v1(90.41,59.6) 89.52,59.6 88.76,58.84 88.76,58.64 CPU1.BH36
M_A_DQ39: length 40.6
  TOP w0.089: v1(116.4,69.8) v2(115.81,69.8)
  L3 w0.114: v1(116.4,69.8) 115.49,69.8 114.37,70.92 113,70.92 105.99,63.92 102.79,63.92 102.67,63.81 102.67,63.58 102.79,63.46 105.02,63.46 105.14,63.35 105.14,63.12 105.02,63.01 99.36,63.01 97.66,61.31 93.01,61.31 91.65,59.95 v1(91.65,59.3)
  BOTTOM w0.089: v1(116.4,69.8) 116.6,69.8 RAM2.A3 ; v1(91.65,59.3) 90.79,59.3 CPU1.BH38
M_A_DQ40: length 63.6
  TOP w0.089: v1(120.37,81.02) v2(120.37,81.58)
  L3 w0.089: 85.71,62.65 85.71,62.41 85.53,62.23 85.53,60.89 86.58,59.84 86.75,59.84 87.64,58.95 87.64,57.79 86.42,56.57 v1(86.42,55.66)
  L3 w0.114: 85.71,62.65 85.71,63.29 95.42,73 97.27,73 98.25,73.98 98.94,73.98 105.13,80.16 105.13,80.33 104.97,80.49 104.8,80.49 103.14,78.82 102.95,78.82 102.81,78.96 102.81,79.14 106.42,82.75 118.14,82.75 120.01,80.88 120.24,80.88 v1(120.37,81.02)
  BOTTOM w0.089: RAM4.H8 122.6,78.8 122.12,79.27 122.12,79.53 121.93,79.73 121.63,79.73 120.37,80.99 v1(120.37,81.02) ; v1(86.42,55.66) 86.28,55.81 CPU1.BC36
M_A_DQ41: length 63.3
  TOP w0.089: v1(121.15,81.06) 121.15,80.51 v2(121.32,80.35)
  L3 w0.089: v1(85.83,55.12) 85.83,56.24 87.45,57.87 87.45,58.87 86.67,59.65 86.5,59.65 85.34,60.81 85.34,62.54
  L3 w0.114: 85.34,62.54 85.34,63.44 95.32,73.42 96.45,73.42 97.99,74.96 99.4,74.96 102.76,78.31 102.76,78.48 102.6,78.64 102.43,78.64 101.23,77.43 101.07,77.43 100.91,77.6 100.91,77.76 106.26,83.12 118.15,83.12 119.79,81.48 120.74,81.48 v1(121.15,81.06)
  BOTTOM w0.089: RAM4.H7 121.79,80.21 121.79,80.43 v1(121.15,81.06) ; v1(85.83,55.12) 85.83,55.13 85.77,55.18 CPU1.BA36
M_A_DQ42: length 62.8
  TOP w0.089: v1(122.28,82.06) v2(122.85,82.06)
  L3 w0.089: 83.36,59.61 83.36,59.35 83.31,59.29 83.31,58.52 83.58,58.25 83.58,57.63 82.98,57.03 82.98,56.41 83.5,55.9 v1(83.5,55.43)
  L3 w0.114: 83.36,59.61 83.36,64.03 95.26,75.93 96.32,75.93 102.29,81.9 102.29,82.06 102.12,82.22 101.96,82.22 101.4,81.66 101.24,81.66 101.08,81.82 101.08,81.98 102.01,82.91 103.72,84.63 103.95,84.86 116.11,84.86 116.22,84.74 119.58,84.74 122.27,82.06 v1(122.28,82.06)
  BOTTOM w0.089: CPU1.AU34 83.59,55.33 v1(83.5,55.43) ; RAM4.H3 122.6,82.38 v1(122.28,82.06)
M_A_DQ43: length 62.1
  TOP w0.089: v2(122.06,84.38) 122.2,84.25 v1(122.2,83.8)
  L3 w0.089: v1(82.23,55.61) 82.23,56.14 81.69,56.67 81.69,57.49 82.75,58.55 82.75,60.36
  L3 w0.114: 82.75,60.36 82.75,64.13 83.62,65 83.62,65.32 95,76.71 95.99,76.71 98.9,79.61 98.9,80.85 103.65,85.59 115.79,85.59 116.19,86 121.12,86 122.08,85.03 122.08,83.91 v1(122.2,83.8)
  BOTTOM w0.089: v1(82.23,55.61) 82.31,55.53 CPU1.AU32 ; RAM4.G2 v1(122.2,83.8)
M_A_DQ44: length 62.7
  TOP w0.089: v2(120.69,78.31) 120,79 v1(119.84,79)
  L3 w0.089: v1(87.35,56.6) 87.95,56.6 88.22,56.87 88.22,58.92 86.91,60.22 86.74,60.22 85.91,61.05 85.91,61.94 86.13,62.16
  L3 w0.114: v1(119.84,79) 119.14,79.7 119.14,80.86 117.99,82.01 108.1,82.01 103.89,77.81 103.89,77.65 104.06,77.49 104.22,77.49 106.59,79.86 106.75,79.86 106.92,79.7 106.92,79.54 103.12,75.74 101.75,75.74 98.98,72.97 98.29,72.97 97.53,72.21 95.83,72.21 86.42,62.8 86.42,62.45 86.13,62.16
  BOTTOM w0.089: v1(87.35,56.6) 87.27,56.68 CPU1.BF36 ; v1(119.84,79) 120.6,79 RAM4.F8
M_A_DQ45: length 62.6
  TOP w0.089: v2(121.65,79.17) 121.23,79.17 v1(120.46,79.94)
  L3 w0.089: 86.05,62.81 86.05,62.42 85.72,62.08 85.72,60.97 86.66,60.03 86.83,60.03 87.83,59.03 87.83,57.71 86.91,56.78 v1(86.91,56.15)
  L3 w0.114: 86.05,62.81 86.05,63.11 95.56,72.61 97.41,72.61 98.14,73.34 98.82,73.34 101.68,76.2 102.98,76.2 103.81,77.03 103.81,77.19 103.65,77.36 103.49,77.36 102.81,76.68 102.65,76.68 102.49,76.84 102.49,77 106.93,81.44 106.93,81.6 106.76,81.76 106.6,81.76 105.52,80.68 105.36,80.68 105.2,80.85 105.2,81.01 106.57,82.38 118.02,82.38 v1(120.46,79.94)
  BOTTOM w0.089: v1(86.91,56.15) 86.78,56.27 CPU1.BD36 ; v1(120.46,79.94) RAM4.F7
M_A_DQ46: length 62.5
  TOP w0.089: v1(120.6,83) v2(120.16,83.45)
  L3 w0.089: v1(84.01,55.95) 84.01,56.61 84.28,56.89 84.28,57.27 83.9,57.66 83.9,58.29 83.57,58.62 83.57,59.32 83.8,59.55 83.8,59.75
  L3 w0.114: v1(120.6,83) 120.6,83.22 119.34,84.49 104.1,84.49 102.35,82.73 102.35,82.57 102.51,82.41 102.67,82.41 104.29,84.02 104.45,84.02 104.61,83.86 104.61,83.7 95.79,74.88 94.74,74.88 84.24,64.38 84.24,62.76 83.8,62.32 83.8,59.75
  BOTTOM w0.089: RAM4.E3 v1(120.6,83) ; CPU1.AV34 84.1,55.86 v1(84.01,55.95)
M_A_DQ47: length 63.8
  TOP w0.089: v2(120.82,84.53) 120.88,84.53 121.4,84.02 v1(121.4,83.8)
  L3 w0.089: 83.12,60.36 83.12,59.38 83.12,59.37 83.12,58.52 82.29,57.69 82.29,57.23 82.73,56.78 v1(82.73,56.08)
  L3 w0.114: v1(121.4,83.8) 121.4,84.21 119.92,85.68 116.41,85.68 115.95,85.22 103.8,85.22 99.27,80.69 99.27,80.53 99.43,80.37 99.59,80.37 100.7,81.48 100.86,81.48 101.02,81.32 101.02,81.15 96.17,76.3 95.11,76.3 84.15,65.33 84.15,65.2 83.12,64.17 83.12,60.36
  BOTTOM w0.089: CPU1.AV32 82.78,56.03 v1(82.73,56.08) ; RAM4.F2 v1(121.4,83.8)
M_A_DQ48: length 54.2
  TOP w0.089: v1(121.01,66.76) 120.96,66.76 v2(120.55,66.35)
  L4 w0.089: v1(86.48,58.37) 87.87,59.76 87.87,60.51 88.96,61.6 88.96,62
  L4 w0.114: 88.96,62 88.96,62.53 89.65,63.22 89.65,64.14 97.9,72.4 110.12,72.4 110.23,72.28 110.23,72.05 110.12,71.94 107.89,71.94 107.77,71.82 107.77,71.59 107.89,71.48 114.46,71.48 115.7,70.25 116.61,70.25 116.9,69.96 116.9,69.61 117.19,69.32 118.07,69.32 118.5,68.9 118.5,68.43 118.15,68.08 118.15,67.13 118.82,66.46 120.7,66.46 v1(121.01,66.76)
  BOTTOM w0.089: CPU1.BF34 86.57,58.29 86.53,58.32 86.53,58.32 v1(86.48,58.37) ; v1(121.01,66.76) 120.68,66.43 120.68,65.72 RAM2.F8
M_A_DQ49: length 54.4
  TOP w0.089: v2(120.09,67.57) 120.38,67.27 v1(120.6,67.27)
  L4 w0.089: 87.51,62.22 87.33,62.05 87.33,61.95 86.09,60.71 86.09,58.86 85.35,58.12 85.35,57.98 85.05,57.68 v1(85.05,56.96)
  L4 w0.114: 87.51,62.22 89.05,63.76 89.05,64.59 97.6,73.13 113.04,73.13 113.15,73.25 113.15,73.48 113.04,73.59 112.05,73.59 111.94,73.7 111.94,73.93 112.05,74.05 113.48,74.05 115.72,71.82 116.48,71.82 118.94,69.36 118.94,68.56 120.23,67.27 v1(120.6,67.27)
  BOTTOM w0.089: RAM2.H7 122.09,66.71 121.72,66.71 121.17,67.27 v1(120.6,67.27) ; CPU1.BC34 85.16,56.85 v1(85.05,56.96)
M_A_DQ50: length 54
  TOP w0.089: v2(122.03,70) 121.82,69.79 v1(121.4,69.79)
  L4 w0.114: v1(121.4,69.79) 119.81,71.38 119.81,71.98 115.4,76.39 97.5,76.39 83.66,62.55 83.66,57.31 v1(83.85,57.12)
  BOTTOM w0.089: v1(83.85,57.12) 83.93,57.03 CPU1.BA32 ; v1(121.4,69.79) 121.4,69.8 RAM2.G2
M_A_DQ51: length 55.3
  TOP w0.089: v1(122,68.77) v2(122.59,68.77)
  L4 w0.114: v1(122,68.77) 121.54,69.23 121.06,69.23 120.93,69.37 120.42,69.37 120.12,69.66 120.12,69.97 114.53,75.56 111.24,75.56 110.33,74.66 105.86,74.66 105.75,74.78 105.75,75 105.86,75.12 107.26,75.12 107.38,75.23 107.38,75.46 107.26,75.58 97.82,75.58 84.56,62.31 v1(84.56,59.3)
  BOTTOM w0.089: RAM2.H3 122,68.8 v1(122,68.77) ; v1(84.56,59.3) 84.72,59.14 CPU1.BD30
M_A_DQ52: length 54.4
  TOP w0.089: v1(123.01,65.79) v2(123.01,66.35)
  L4 w0.089: v1(86.03,57.88) 86.63,57.88 88.12,59.37 88.12,60.36 89.4,61.65 89.4,61.97
  L4 w0.114: v1(123.01,65.79) 122.56,66.24 118.73,66.24 117.74,67.23 117.74,68.16 117.48,68.41 117.18,68.41 116.93,68.67 116.93,69 116.65,69.28 116.22,69.28 114.39,71.11 105.16,71.11 105.05,71.23 105.05,71.46 105.16,71.57 107.26,71.57 107.37,71.68 107.37,71.91 107.26,72.03 98.05,72.03 90.01,63.99 90.01,63.08 89.4,62.47 89.4,61.97
  BOTTOM w0.089: v1(123.01,65.79) 122.63,65.4 RAM2.H8 ; CPU1.BD34 86.11,57.8 v1(86.03,57.88)
M_A_DQ53: length 51.5
  TOP w0.089: v1(121.4,65.8) 121.66,65.8 v2(121.95,65.52)
  L4 w0.114: v1(84.54,56.38) 85.6,56.38 89.03,59.8 89.03,59.89 90.34,61.2 90.34,63.79 98.21,71.66 104.53,71.66 104.65,71.54 104.65,71.32 104.53,71.2 103.76,71.2 103.65,71.09 103.65,70.86 103.76,70.74 114.3,70.74 115.49,69.55 115.49,69.09 118.78,65.8 v1(121.4,65.8)
  BOTTOM w0.089: CPU1.BA34 84.57,56.35 v1(84.54,56.38) ; RAM2.F7 v1(121.4,65.8)
M_A_DQ54: length 56.1
  TOP w0.089: v1(120.6,68.81) v2(121.19,68.81)
  L4 w0.114: v1(84.98,59.77) 84.98,62.2 97.98,75.21 105.1,75.21 105.22,75.09 105.22,74.86 105.1,74.75 101.86,74.75 101.74,74.64 101.74,74.41 101.86,74.29 110.48,74.29 110.77,74.57 111.26,75.06 114.5,75.06 116.49,73.07 116.6,73.07 119.88,69.79 119.88,69.53 v1(120.6,68.81)
  BOTTOM w0.089: v1(84.98,59.77) 85.2,59.55 CPU1.BF30 ; RAM2.E3 120.2,69.21 v1(120.6,68.81)
M_A_DQ55: length 55
  TOP w0.089: v2(119.95,70.01) 120.12,69.85 v1(120.6,69.85)
  L4 w0.114: v1(84.07,58.82) 84.07,62.35 97.75,76.02 109.59,76.02 109.71,75.91 109.71,75.68 109.59,75.57 108.08,75.57 107.97,75.45 107.97,75.22 108.08,75.11 110.26,75.11 111.08,75.93 115.33,75.93 118.75,72.52 118.75,71.7 v1(120.6,69.85)
  BOTTOM w0.089: v1(120.6,69.85) 120.95,70.2 RAM2.F2 ; v1(84.07,58.82) 84.02,58.87 84.02,59.35
M_A_DQ56: length 44.1
  TOP w0.089: v2(117.77,78.64) 117.85,78.64 v1(118.2,79)
  L3 w0.114: v1(89.88,61.45) 90.78,62.34 90.78,62.74 91.29,63.25 91.82,63.25 94.11,65.54 94.27,65.54 94.6,65.21 94.76,65.21 94.93,65.37 94.93,65.53 94.6,65.86 94.6,66.02 95.83,67.26 99.16,67.26 100.18,68.27 102.73,68.27 104.85,70.4 105.01,70.4 105.7,69.72 105.86,69.72 106.02,69.88 106.02,70.04 105.44,70.62 105.44,70.78 105.6,70.95 105.76,70.95 106.27,70.44 106.46,70.44 113.61,77.59 114.52,77.59 114.96,78.03 116.42,78.03 117.38,79 v1(118.2,79)
  BOTTOM w0.089: v1(118.2,79) RAM4.C8 ; v1(89.88,61.45) 88.98,61.45 87.83,60.3 87.83,59.78 CPU1.BJ33
M_A_DQ57: length 45
  TOP w0.089: v1(114.88,80.47) v2(114.31,80.47)
  L3 w0.114: v1(86.31,61.53) 87.3,61.53 95.16,69.38 97.94,69.38 98.85,70.29 101.73,70.29 106.44,75 106.77,75 107.3,74.47 107.46,74.47 107.63,74.63 107.63,74.79 107.01,75.41 107.01,75.57 107.17,75.73 107.33,75.73 108.18,74.88 108.36,74.88 113.95,80.47 v1(114.88,80.47)
  BOTTOM w0.089: v1(86.31,61.53) 86.31,61.39 85.74,60.82 85.74,60.72 85.52,60.5 CPU1.BG29 ; RAM4.A2 114.88,81.28 v1(114.88,80.47)
M_A_DQ58: length 43
  TOP w0.089: v1(119,79) v2(119.4,78.6)
  L3 w0.114: v1(119,79) 118.59,78.59 118.59,77.97 117.96,77.34 117.59,77.34 117.47,77.22 117.47,76.73 117.36,76.61 117.13,76.61 117.01,76.73 117.01,77.22 116.9,77.34 116.09,77.34 115.46,76.71 113.92,76.71 104.44,67.22 100.8,67.22 100.05,66.47 97.54,66.47 94.45,63.37 93.03,63.37 90.14,60.49 v1(88.99,60.49)
  BOTTOM w0.089: RAM4.D7 v1(119,79) ; v1(88.99,60.49) 88.87,60.37 88.45,60.37 88.21,60.14 88.21,59.47 CPU1.BH34
M_A_DQ59: length 45.6
  TOP w0.089: v1(118.18,78.21) v2(118.18,77.45)
  L3 w0.114: v1(91.27,62.59) 91.36,62.68 91.68,62.68 92.83,63.83 94.25,63.83 97.27,66.85 99.62,66.85 100.53,67.76 102.75,67.76 103.56,68.57 103.72,68.57 104.27,68.02 104.43,68.02 104.59,68.18 104.59,68.34 104.05,68.89 104.05,69.05 104.21,69.21 104.37,69.21 104.96,68.62 105.12,68.62 105.28,68.78 105.28,68.94 104.72,69.5 104.72,69.67 104.89,69.83 105.05,69.83 105.7,69.17 105.86,69.17 113.77,77.08 115.53,77.08 116,77.55 117.52,77.55 v1(118.18,78.21)
  BOTTOM w0.089: RAM4.B8 118.19,78.21 v1(118.18,78.21) ; v1(91.27,62.59) 90.64,61.96 89.23,61.96 87.64,60.38 87.64,59.97 87.11,59.45 87.11,59.34 86.92,59.15 86.8,59.15 86.59,58.94 86.31,58.94
M_A_DQ60: length 46.2
  TOP w0.089: v2(116.87,80.76) 117.04,80.76 v1(117.36,81.07)
  L3 w0.114: v1(117.36,81.07) 117.36,81.1 116.88,81.58 114.87,81.58 114.75,81.46 114.75,81.32 114.64,81.21 114.41,81.21 114.29,81.32 114.29,81.46 114.18,81.58 113.87,81.58 110.44,78.15 108.31,78.15 101.33,71.16 95.85,71.16 88.5,63.81 88.5,63.34 88.14,62.97 v1(87.54,62.97)
  BOTTOM w0.089: RAM4.C2 118.6,83.17 118.21,82.78 118.21,81.92 v1(117.36,81.07) ; CPU1.BG28 85.12,60.51 85.12,60.9 85.31,61.1 85.41,61.1 85.67,61.36 85.67,61.78 86.87,62.97 v1(87.54,62.97)
M_A_DQ61: length 45.8
  TOP w0.089: v1(118.2,81.14) 118.66,81.14 v2(118.77,81.26)
  L3 w0.114: v1(118.2,81.14) 118.2,81.4 117.8,81.8 113.56,81.8 110.43,78.67 110.27,78.67 109.57,79.37 109.4,79.37 109.24,79.21 109.24,79.05 109.42,78.87 109.42,78.7 109.26,78.54 109.1,78.54 108.68,78.96 108.52,78.96 101.11,71.54 95.69,71.54 88.24,64.1 88.24,63.74 v1(88,63.5)
  BOTTOM w0.089: CPU1.BJ29 86.12,60.82 86.21,60.82 86.63,61.24 86.75,61.24 88,62.49 88,63.49 v1(88,63.5) ; v1(118.2,81.14) 118.6,81.54 RAM4.C3
M_A_DQ62: length 46.5
  TOP w0.089: v1(115.33,80.98) v2(115.33,81.54)
  L3 w0.114: v1(86.75,61.99) 87.46,61.99 88.72,63.25 88.72,63.51 95.48,70.27 98.28,70.27 98.78,70.77 101.7,70.77 107.65,76.73 107.81,76.73 108.65,75.89 108.81,75.89 108.97,76.05 108.97,76.21 108.14,77.05 108.14,77.21 108.3,77.38 108.46,77.38 109.3,76.54 109.46,76.54 109.62,76.7 109.62,76.86 109.13,77.35 109.13,77.52 109.29,77.68 109.45,77.68 109.94,77.18 110.11,77.18 113.9,80.98 v1(115.33,80.98)
  BOTTOM w0.089: RAM4.A3 116.81,82.6 115.33,81.12 v1(115.33,80.98) ; CPU1.BH28 85.88,61.26 85.88,61.71 86.16,61.99 v1(86.75,61.99)
M_A_DQ63: length 43.7
  TOP w0.089: v1(116.58,78.98) 116.18,78.58 v2(116.07,78.58)
  L3 w0.114: v1(89.44,60.94) 89.47,60.98 89.47,61.74 91.31,63.58 91.59,63.58 95.67,67.66 98.75,67.66 99.79,68.7 102.55,68.7 105.76,71.91 105.92,71.91 106.57,71.26 106.73,71.26 106.89,71.42 106.89,71.58 106.24,72.23 106.24,72.39 106.41,72.55 106.57,72.55 107.22,71.91 107.38,71.91 113.76,78.28 114.97,78.28 115.08,78.4 115.08,78.72 115.2,78.83 115.43,78.83 115.54,78.72 115.54,78.4 115.66,78.28 115.88,78.28 116,78.4 116,78.71 116.12,78.83 116.43,78.83 v1(116.58,78.98)
  BOTTOM w0.089: RAM4.A7 v1(116.58,78.98) ; CPU1.BG33 87.18,58.84 87.4,59.06 87.5,59.06 88.02,59.58 88.02,60.22 88.75,60.94 v1(89.44,60.94)
M_A_DQS_DN0: length 43.8
  TOP w0.127: v1(117.38,35.6) 116.82,35.6 v2(116.79,35.63)
  L4 w0.14: v1(117.38,35.6) 117.68,35.89 117.68,36.58 117.56,36.7 116.72,36.7 116.61,36.59 116.61,35.99 116.33,35.71 115.85,35.71 115.57,35.99 115.57,36.53 115.43,36.67 115.15,36.67 115.01,36.53 115.01,35.99 114.73,35.71 114.25,35.71 113.97,35.99 113.97,36.53 113.83,36.67 113.55,36.67 113.41,36.53 113.41,35.99 113.13,35.71 112.65,35.71 112.37,35.99 112.37,36.53 112.23,36.67 111.95,36.67 111.81,36.53 111.81,36.02 111.49,35.71 99.63,35.71 97.47,37.86 96.37,37.86 95.62,38.62 95.62,39.4 93.2,41.82 92.15,41.82 91.34,42.64 91.34,43.51 90.17,44.68 90.17,45.15 v1(89.99,45.34)
  BOTTOM w0.089: CPU1.AM51 87.91,46.98 87.91,46.57 88.09,46.39 88.23,46.39 88.47,46.15 88.47,45.91 89.02,45.36 89.97,45.36 v1(89.99,45.34)
  BOTTOM w0.127: RAM3.B7 117.8,35.18 v1(117.38,35.6)
M_A_DQS_DN1: length 45.7
  L4 w0.089: 93.76,46.94 93.74,46.95 93.74,46.99 93.47,47.27 93.06,47.27 91.47,48.85 90.23,48.85 89.44,49.65 89.23,49.65 88.8,50.08 v1(88.23,50.08)
  L4 w0.14: 93.76,46.94 94.44,46.26 95.38,46.26 96.09,45.54 96.71,45.54 100.79,41.47 102.52,41.47 102.8,41.75 102.8,42.05 102.94,42.19 103.22,42.19 103.36,42.05 103.36,41.75 103.64,41.47 104.12,41.47 104.4,41.75 104.4,42.05 104.53,42.19 113.11,42.19 115.56,44.63 115.56,48.21 116.55,49.21 116.55,49.72 116.8,49.96 119.74,49.96 120.06,50.29 120.95,50.29 v1(121.05,50.39)
  BOTTOM w0.127: v1(88.23,50.08) 88.3,50.15 CPU1.AV48 ; RAM1.G3 121.8,51.14 v1(121.05,50.39)
M_A_DQS_DN2: length 57.4
  TOP w0.127: v1(120.91,36.98) 120.91,36.98 120.52,36.6 v2(120.51,36.59)
  L3 w0.089: v1(86.28,52.03) 86.28,51.17 86.47,50.97 87.62,49.83 87.64,49.83 88.65,48.82 88.67,48.82 88.9,48.59 88.91,48.59 89.15,48.36 89.15,48.32
  L3 w0.14: v1(120.91,36.98) 120.33,36.98 119.69,37.62 115.18,37.62 114.48,38.33 114.48,38.99 114.28,39.19 113.9,39.19 113.69,38.99 113.69,38.21 113.39,37.91 112.96,37.91 112.65,38.21 112.65,39.09 112.51,39.23 112.23,39.23 112.09,39.09 112.09,38.2 111.79,37.9 111.36,37.9 111.05,38.2 111.05,39.09 110.91,39.23 110.63,39.23 110.49,39.09 110.49,38.19 110.19,37.89 109.76,37.89 109.45,38.19 109.45,39.09 109.31,39.23 109.03,39.23 108.89,39.09 108.89,38.21 108.59,37.91 108.16,37.91 107.85,38.21 107.85,39.09 107.71,39.23 107.43,39.23 107.29,39.09 107.29,38.22 106.99,37.91 106.56,37.91 106.25,38.22 106.25,39.09 106.11,39.23 105.83,39.23 105.69,39.09 105.69,38.22 105.39,37.92 104.96,37.92 104.65,38.22 104.65,39.09 104.51,39.23 98.9,39.23 94.33,43.8 93.67,43.8 89.15,48.32
  BOTTOM w0.127: v1(120.91,36.98) 120.98,36.98 121.69,37.69 121.69,38.19 RAM3.G3 ; CPU1.AT41 85.81,52.11 86.2,52.11 v1(86.28,52.03)
M_A_DQS_DN3: length 33.5
  TOP w0.127: v1(117.02,49.53) 116.9,49.64 v2(116.47,49.64)
  L3 w0.14: v1(117.02,49.53) 117.35,49.19 117.35,49.05 117.21,48.91 115.63,48.91 113.42,46.7 102.98,46.7 102.82,46.85 102.82,47.44 102.52,47.75 102.09,47.75 101.78,47.44 101.78,46.85 101.64,46.71 101.14,46.71 100.61,47.24 98.35,47.24 98.14,47.45 94.37,47.45 93.21,48.6 v1(92.59,48.6)
  BOTTOM w0.089: CPU1.BA51 91.23,49.84 91.23,49.42 91.56,49.09 91.56,48.93 92.1,48.39 92.33,48.39 92.54,48.6 v1(92.59,48.6)
  BOTTOM w0.127: v1(117.02,49.53) 117.02,49.45 117.8,48.66 RAM1.B7
M_A_DQS_DN4: length 38.6
  TOP w0.127: v1(90.77,58.35) 90.88,58.24 91.31,58.24 91.31,58.24 v2(91.33,58.24)
  L3 w0.14: v1(90.77,58.35) 90.88,58.25 91.29,58.25 91.59,58.55 91.89,58.55 93.36,60.02 98,60.02 99.75,61.76 105.35,61.76 113.65,70.07 114.05,70.07 114.27,69.85 114.27,69.52 114.08,69.34 v1(113.94,69.34)
  BOTTOM w0.089: CPU1.BG39 89.18,57 89.59,57 90.11,57.51 90.48,57.51 90.5,57.53 90.77,57.8 v1(90.77,58.35)
  BOTTOM w0.127: v1(113.94,69.34) 114.22,69.05 114.22,68.8 114.99,68.03 116.3,68.03 117.55,66.78 117.76,66.78 118.09,66.45 118.09,66.33 117.96,66.2 RAM2.B7
M_A_DQS_DN5: length 60.7
  TOP w0.127: v1(121.56,82.06) 121.71,81.91 v2(121.71,81.5)
  L3 w0.089: 84.52,61.46 84.52,61.43 84.55,61.41 84.55,60.8 86.26,59.08 86.39,59.08 86.88,58.59 86.88,58.16 84.94,56.22 84.94,56.04 83.7,54.8 83.12,54.8 v1(83.02,54.9)
  L3 w0.14: v1(121.56,82.06) 121.04,82.58 120.43,82.58 120.07,82.94 120.07,83.43 119.4,84.11 105.65,84.11 96.05,74.5 94.89,74.5 84.52,64.13 84.52,61.46
  BOTTOM w0.127: v1(121.56,82.06) 121.8,82.3 RAM4.G3 ; v1(83.02,54.9) 83.02,54.41 83.09,54.33
M_A_DQS_DN6: length 53.6
  TOP w0.127: v2(121.43,67.4) 121.43,67.58 v1(121.14,67.88)
  L4 w0.089: 85.73,61.3 85.73,61.28 85.71,61.26 85.71,59.61 84.61,58.51 84.61,58.35 84.74,58.22 v1(84.91,58.22)
  L4 w0.14: 85.73,61.3 85.73,61.94 97.32,73.53 98.44,73.53 98.72,73.81 98.72,74.19 98.86,74.33 99.14,74.33 99.28,74.19 99.28,73.81 99.56,73.53 100.04,73.53 100.32,73.81 100.32,74.19 100.46,74.33 100.74,74.33 100.88,74.19 100.88,73.81 101.16,73.53 110.91,73.53 111.82,74.44 114.09,74.44 116.22,72.3 116.48,72.3 119.32,69.47 119.32,68.73 120.31,67.74 121,67.74 v1(121.14,67.88)
  BOTTOM w0.127: v1(121.14,67.88) 121.14,68.15 121.51,68.52 121.51,69.11 RAM2.G3 ; CPU1.BC32 84.92,58.22 v1(84.91,58.22)
M_A_DQS_DN7: length 44.2
  TOP w0.127: v2(87.41,60.41) 87.41,60.98 v1(87.43,61)
  L3 w0.14: v1(117.82,80.07) 117.82,80.26 117.68,80.4 116.81,80.4 115.64,79.23 114.15,79.23 107.58,72.65 107.18,72.65 106.44,73.39 106.3,73.39 101.98,69.08 99.58,69.08 98.59,68.09 95.47,68.09 89.13,61.75 89.13,61.24 88.52,60.63 88.09,60.63 87.72,61 v1(87.43,61)
  BOTTOM w0.089: CPU1.BG31 86.21,59.79 86.26,59.84 86.47,59.84 86.56,59.75 86.84,59.75 87.26,60.16 87.26,60.53 87.43,60.7 v1(87.43,61)
  BOTTOM w0.127: v1(117.82,80.07) 118.1,80.07 118.2,79.98 118.2,79.63 117.97,79.4 RAM4.B7
M_A_DQS_DP0: length 43.7
  TOP w0.127: v2(117.91,36.1) 118.18,35.83 v1(118.18,35.6)
  L4 w0.14: v1(118.18,35.6) 118.1,35.6 117.92,35.77 117.92,36.68 117.66,36.94 116.62,36.94 116.37,36.69 116.37,36.09 116.23,35.95 115.95,35.95 115.81,36.09 115.81,36.63 115.53,36.91 115.05,36.91 114.77,36.63 114.77,36.09 114.63,35.95 114.35,35.95 114.21,36.09 114.21,36.63 113.93,36.91 113.45,36.91 113.17,36.63 113.17,36.09 113.03,35.95 112.75,35.95 112.61,36.09 112.61,36.63 112.33,36.91 111.85,36.91 111.57,36.63 111.57,36.12 111.39,35.95 99.73,35.95 97.57,38.11 96.47,38.11 95.86,38.72 95.86,39.5 93.3,42.06 92.25,42.06 91.58,42.74 91.58,43.61 90.41,44.78 90.41,45.51 90.12,45.8 v1(89.54,45.8)
  BOTTOM w0.089: v1(89.54,45.8) 89.54,45.6 89.49,45.55 89.1,45.55 88.66,45.99 88.66,46.23 CPU1.AM52
  BOTTOM w0.127: v1(118.18,35.6) 118.6,35.18 RAM3.C7
M_A_DQS_DP1: length 46.4
  TOP w0.127: v1(120.63,50.9) 120.86,51.13 v2(121.16,51.13)
  L4 w0.089: 93.93,47.11 93.91,47.13 93.88,47.13 93.55,47.46 93.13,47.46 91.55,49.04 90.31,49.04 89.51,49.84 89.31,49.84 88.7,50.45 88.7,50.61 88.83,50.74 v1(88.97,50.74)
  L4 w0.14: 93.93,47.11 94.54,46.5 95.48,46.5 96.19,45.79 96.81,45.79 100.89,41.71 102.42,41.71 102.56,41.85 102.56,42.15 102.84,42.43 103.32,42.43 103.6,42.15 103.6,41.85 103.74,41.71 104.02,41.71 104.16,41.85 104.16,42.15 104.43,42.43 113.01,42.43 115.32,44.73 115.32,48.31 116.31,49.31 116.31,49.82 116.7,50.21 119.64,50.21 119.96,50.53 120.57,50.53 120.63,50.58 v1(120.63,50.9)
  BOTTOM w0.127: RAM1.F3 121.08,51.5 121.35,51.23 121.35,51.02 121.15,50.81 120.72,50.81 v1(120.63,50.9) ; CPU1.AV47 88.46,50.74 v1(88.97,50.74)
M_A_DQS_DP2: length 57.5
  TOP w0.127: v2(121.34,37.99) 121.17,37.82 v1(120.77,37.82)
  L3 w0.089: v1(86.76,51.55) 86.76,50.96 87.69,50.02 87.72,50.02 88.73,49.01 88.75,49.01 88.98,48.78 88.99,48.78 89.27,48.51 89.3,48.51 89.32,48.49
  L3 w0.14: v1(120.77,37.82) 120.78,37.82 120.78,37.84 120.87,37.74 120.87,37.56 120.6,37.28 120.37,37.28 119.79,37.87 115.28,37.87 114.72,38.43 114.72,39.09 114.38,39.43 113.8,39.43 113.45,39.09 113.45,38.31 113.29,38.15 113.06,38.15 112.89,38.31 112.89,39.19 112.61,39.47 112.13,39.47 111.85,39.19 111.85,38.3 111.69,38.14 111.46,38.14 111.29,38.3 111.29,39.19 111.01,39.47 110.53,39.47 110.25,39.19 110.25,38.29 110.09,38.13 109.86,38.13 109.69,38.29 109.69,39.19 109.41,39.47 108.93,39.47 108.65,39.19 108.65,38.31 108.49,38.15 108.26,38.15 108.09,38.31 108.09,39.19 107.81,39.47 107.33,39.47 107.05,39.19 107.05,38.32 106.89,38.16 106.66,38.16 106.49,38.32 106.49,39.19 106.21,39.47 105.73,39.47 105.45,39.19 105.45,38.32 105.29,38.16 105.06,38.16 104.89,38.32 104.89,39.19 104.61,39.47 99,39.47 94.43,44.04 93.77,44.04 89.32,48.49
  BOTTOM w0.127: CPU1.AT42 86.26,51.55 v1(86.76,51.55) ; v1(120.77,37.82) 120.71,37.76 120.71,37.49 120.79,37.41 121.09,37.41 121.46,37.78 121.46,38.25 121.31,38.39 121.09,38.39 RAM3.F3
M_A_DQS_DP3: length 33.6
  TOP w0.127: v1(117.96,49.52) 117.96,49.37 v2(117.64,49.04)
  L3 w0.14: v1(93.06,48.11) 93.36,48.11 94.27,47.21 98.04,47.21 98.25,47 100.51,47 101.04,46.47 101.74,46.47 102.02,46.75 102.02,47.34 102.19,47.5 102.42,47.5 102.58,47.34 102.58,46.75 102.88,46.45 113.52,46.45 115.73,48.67 117.31,48.67 117.59,48.95 117.59,49.15 v1(117.96,49.52)
  BOTTOM w0.089: CPU1.AY52 91.37,49.01 91.37,48.85 92.02,48.2 92.67,48.2 92.76,48.11 v1(93.06,48.11)
  BOTTOM w0.127: v1(117.96,49.52) 117.74,49.3 117.74,49.04 118.48,48.3 RAM1.C7
M_A_DQS_DP4: length 38.7
  TOP w0.127: v1(114.73,69.34) 115.08,68.99 v2(115.08,68.83)
  L3 w0.14: v1(114.73,69.34) 114.51,69.56 114.51,69.95 114.15,70.31 113.55,70.31 105.25,62 99.65,62 97.9,60.26 93.26,60.26 91.79,58.79 v1(91.23,58.79)
  BOTTOM w0.089: CPU1.BH40 90.19,57.32 90.56,57.32 90.58,57.34 90.96,57.72 90.96,57.96 91.4,58.39 91.4,58.63 v1(91.23,58.79)
  BOTTOM w0.127: v1(114.73,69.34) 114.45,69.05 114.45,68.9 115.09,68.26 116.39,68.26 117.65,67.01 117.85,67.01 118.31,66.55 118.31,66.33 118.44,66.2 RAM2.C7
M_A_DQS_DP5: length 60.7
  TOP w0.127: v1(120.77,82.05) 121.12,82.41 v2(121.12,82.56)
  L3 w0.089: 84.76,61.46 84.76,61.43 84.74,61.41 84.74,60.88 86.34,59.27 86.47,59.27 87.07,58.67 87.07,58.08 85.13,56.14 85.13,55.96 83.78,54.61 83.43,54.61 83.13,54.32 82.69,54.32 v1(82.56,54.45)
  L3 w0.14: 84.76,61.46 84.76,64.03 94.99,74.26 96.15,74.26 105.75,83.87 119.3,83.87 119.83,83.33 119.83,82.84 120.33,82.34 120.68,82.34 120.77,82.25 v1(120.77,82.05)
  BOTTOM w0.127: v1(82.56,54.45) 82.4,54.6 CPU1.AT32 ; v1(120.77,82.05) 120.91,82.05 121.1,82.24 121.1,82.5 RAM4.F3
M_A_DQS_DP6: length 53.8
  TOP w0.127: v1(120.53,68.17) 120.53,68.22 v2(119.96,68.78)
  L4 w0.089: 85.49,61.3 85.49,61.28 85.52,61.26 85.52,59.69 84.42,58.59 v1(84.42,57.73)
  L4 w0.14: v1(120.53,68.17) 120.22,68.17 119.56,68.83 119.56,69.57 116.58,72.54 116.32,72.54 114.19,74.68 111.72,74.68 110.81,73.77 101.26,73.77 101.12,73.91 101.12,74.29 100.84,74.57 100.36,74.57 100.08,74.29 100.08,73.91 99.94,73.77 99.66,73.77 99.52,73.91 99.52,74.29 99.24,74.57 98.76,74.57 98.48,74.29 98.48,73.91 98.34,73.77 97.22,73.77 85.49,62.04 85.49,61.3
  BOTTOM w0.127: v1(84.42,57.73) 84.42,58.04 CPU1.BC30 ; v1(120.53,68.17) 120.83,68.17 121.29,68.62 121.29,69.27 121.16,69.4 RAM2.F3
M_A_DQS_DP7: length 44.3
  TOP w0.127: v2(119.18,79.99) 119.09,80.07 v1(118.62,80.07)
  L3 w0.14: v1(118.62,80.07) 118.05,80.64 116.71,80.64 115.54,79.47 114.05,79.47 107.48,72.89 107.28,72.89 106.54,73.64 106.2,73.64 101.88,69.32 99.48,69.32 98.49,68.33 95.37,68.33 88.89,61.85 88.89,61.34 88.42,60.87 88.19,60.87 87.92,61.14 v1(87.92,61.41)
  BOTTOM w0.089: CPU1.BH32 87.45,60.08 87.45,60.45 87.92,60.92 v1(87.92,61.41)
  BOTTOM w0.127: v1(118.62,80.07) 118.43,79.89 118.43,79.57 RAM4.C7
M_A_RAS#: length 160
  TOP w0.114: R1237.2 117.92,63.37 v1(117.92,63.37) ; v1(121.84,43.4) v2(121.25,43.4)
  L3 w0.152: v1(121.84,43.4) 121.84,44.02 122.03,44.21 122.03,46.15 122.82,46.93 122.82,51.79 121.84,52.76 121.26,52.76 120.36,53.66 120.36,55.43 120.23,55.57 120.23,58.29 120.08,58.44 119.77,58.44 119.62,58.29 119.62,56.02 119.47,55.87 119.16,55.87 119.01,56.02 119.01,59.42 118.78,59.65 118.78,60.18 118.63,60.33 118.2,60.33 118.05,60.49 118.05,60.79 118.2,60.94 118.62,60.94 118.77,61.1 118.77,61.4 118.62,61.55 118.2,61.55 118.05,61.7 118.05,62.01 118.2,62.16 118.8,62.16 118.95,62.31 118.95,62.84 118.8,63 118.03,63 117.92,63.1 v1(117.92,63.37) 117.92,63.68 118.08,63.83 118.86,63.83 119.01,63.98 119.01,64.37 118.86,64.52 117.67,64.52 117.52,64.67 117.52,65.3 117.67,65.45 120.01,65.45 120.73,66.17 120.73,66.39 120.51,66.6 120.33,66.6 120.13,66.41 119.71,66.41 119.3,65.99 119.08,65.99 118.87,66.21 118.87,66.46 120.02,67.62 120.02,69.16 120.15,69.29 121.67,69.29 121.71,69.34 121.99,69.34 122.14,69.49 122.14,70.23 121.99,70.38 120.64,70.38 120.49,70.53 120.49,70.84 120.64,70.99 121.68,70.99 121.84,71.14 121.84,72.64 121.68,72.79 120.13,72.79 119.98,72.94 119.98,73.25 120.13,73.41 121.88,73.41 122.04,73.56 122.04,73.8 121.88,73.95 120.67,73.95 120.52,74.1 120.52,75.08 120.67,75.23 121.72,75.23 121.84,75.12 v1(121.84,74.5)
  L4 w0.102: 90.09,56.02 89.66,55.59 89.66,55.45 88.31,54.11 v1(87.73,54.11)
  L4 w0.152: v1(124.03,49.77) 124.03,49.46 123.71,49.14 123.71,48.68 124.27,48.12 124.27,47.7 122.07,45.5 122.07,44.46 121.84,44.23 v1(121.84,43.4) 121.84,42.37 121.84,42.36 122.22,41.98 122.22,40.52 123.82,38.91 123.82,36.93 124.03,36.73 v1(124.03,36.57) ; v1(124.03,67.67) 124.03,67.83 123.82,68.03 123.82,70.01 122.22,71.62 122.22,72.89 121.84,73.27 121.84,74.5 v1(121.84,74.5) 121.84,74.5 121.84,75.33 122.07,75.56 122.07,76.6 124.27,78.8 124.27,79.11 123.71,79.67 123.71,80.24 124.03,80.56 v1(124.03,80.87) ; 90.09,56.02 92.97,58.9 94.06,58.9 99.45,64.29 104.27,64.29 104.42,64.45 104.42,64.75 104.27,64.9 100.7,64.9 100.54,65.05 100.54,65.36 100.7,65.51 104.48,65.51 104.75,65.24 108.58,65.24 108.74,65.39 108.74,66.3 108.89,66.46 110.67,66.46 110.82,66.3 110.82,66 110.67,65.85 109.44,65.85 109.29,65.69 109.29,65.39 109.44,65.24 110.79,65.24 112.01,64.02 112.22,64.02 112.44,64.24 112.44,64.45 111.33,65.56 111.33,65.78 111.55,65.99 111.76,65.99 113.12,64.64 113.12,64.2 113.24,64.08 113.98,64.08 114.13,63.93 114.13,63.34 114.28,63.19 114.59,63.19 114.74,63.34 114.74,63.99 114.89,64.14 115.26,64.14 115.42,63.99 115.42,63.36 115.57,63.21 115.87,63.21 116.02,63.36 116.02,63.99 116.18,64.14 116.48,64.14 116.63,63.99 116.63,63.52 116.79,63.37 v1(117.92,63.37)
  BOTTOM w0.114: v1(87.73,54.11) 87.73,54.33 87.58,54.48 87.29,54.48 87.16,54.36 CPU1.BA40 ; v1(124.03,67.67) 123.4,68.3 RAM2.J3 ; v1(124.03,49.77) 124.03,50.56 123.4,51.19 RAM1.J3 ; v1(124.03,36.57) 123.4,37.2 RAM3.J3 ; v1(124.03,80.87) 124.03,81.66 123.4,82.29 RAM4.J3
M_A_WE#: length 147.6
  TOP w0.114: R1241.2 128.08,60.74 v1(128.04,60.71) ; v2(126.69,44.1) 126.46,43.88 v1(126.46,43.58)
  L3 w0.152: v1(126.46,43.58) 126.46,44.26 127.55,45.35 127.55,48.02 128.79,49.26 128.79,49.79 127.47,51.11 127.47,53.93 125.8,55.61 125.8,58.25 126.83,59.28 126.83,59.49 v1(128.04,60.71) 128.23,60.71 128.38,60.86 128.38,61.33 128.09,61.63 128.09,62.13 128.24,62.28 129,62.28 129.16,62.43 129.16,62.74 129,62.89 128.19,62.89 128.04,63.04 128.04,63.35 128.19,63.5 128.85,63.5 129.04,63.69 129.04,63.92 128.72,64.24 128.72,64.87 128.57,65.03 128.14,65.03 127.99,65.18 127.99,65.48 128.14,65.64 128.57,65.64 128.72,65.79 128.72,66.09 128.57,66.25 128.49,66.25 128.34,66.4 128.34,66.7 128.49,66.86 128.57,66.86 128.72,67.01 128.72,67.31 127.17,68.86 127.17,69.45 127.02,69.6 127.02,70.08 127.17,70.23 127.17,70.65 126.32,71.5 126.32,71.86 126.47,72.01 126.58,72.01 126.73,72.16 126.73,72.47 126.58,72.62 126.47,72.62 126.32,72.77 126.32,73.28 126.46,73.42 v1(126.46,74.68)
  L4 w0.152: v1(127.32,50.2) 127.32,49.99 127.05,49.72 127.05,48.81 126.58,48.33 126.58,46.92 127.04,46.46 127.04,44.33 126.46,43.76 v1(126.46,43.58) 126.46,43.22 126.63,43.05 126.63,42.56 126.18,42.11 126.18,40.13 127.13,39.19 127.13,37.4 127.32,37.21 v1(127.32,36.95) ; v1(95.08,55.25) 95.12,55.29 95.34,55.29 95.74,54.88 95.96,54.88 96.17,55.1 96.17,55.32 95.79,55.69 95.79,55.91 96.13,56.25 96.35,56.25 96.92,55.67 97.13,55.67 97.35,55.89 97.35,56.11 96.96,56.49 96.96,56.73 97.12,56.88 97.74,56.88 97.9,56.73 97.9,55.76 98.05,55.6 98.35,55.6 98.51,55.76 98.51,57.83 98.66,57.98 98.96,57.98 99.12,57.83 99.12,56.62 99.27,56.47 99.57,56.47 99.72,56.62 99.72,56.81 99.88,56.97 100.28,56.97 100.44,56.81 100.44,56.43 100.59,56.28 100.89,56.28 101.05,56.43 101.05,56.8 101.2,56.96 101.5,56.96 101.66,56.8 101.66,56.39 101.81,56.24 102.11,56.24 102.26,56.39 102.26,56.75 102.42,56.9 103.12,56.9 103.28,57.05 103.28,57.36 103.12,57.51 99.83,57.51 99.67,57.66 99.67,57.97 99.83,58.12 106.4,58.12 106.55,57.97 106.55,57.66 106.4,57.51 103.96,57.51 103.81,57.36 103.81,57.05 103.96,56.9 106.56,56.9 109.94,60.28 126.45,60.28 126.88,60.72 128.04,60.72 v1(128.04,60.71) ; v1(127.15,81.33) 127.15,81.21 127.05,81.11 127.05,79.9 126.58,79.43 126.58,78.02 127.04,77.56 127.04,75.43 126.46,74.86 v1(126.46,74.68) 126.46,74.32 126.59,74.2 126.59,73.61 126.18,73.21 126.18,71.46 127.13,70.51 127.13,68.5 127.32,68.31 v1(127.32,68.05)
  BOTTOM w0.114: v1(127.32,50.2) 127.08,50.2 126.11,51.16 125.31,51.16 125,51.47 RAM1.L3 ; v1(127.32,36.95) 127.29,36.95 126.65,37.6 125.97,37.6 125.81,37.76 125.54,37.76 RAM3.L3 ; RAM2.L3 125.54,68.86 125.81,68.86 125.99,68.68 126.63,68.68 127.26,68.05 v1(127.32,68.05) ; RAM4.L3 125,82.49 125.23,82.26 125.95,82.26 126.06,82.15 126.06,81.91 126.19,81.79 126.59,81.79 127.04,81.33 v1(127.15,81.33) ; v1(95.08,55.25) 95.08,55.87 94.81,56.14 92.16,56.14 91.8,55.78 91.39,55.78 CPU1.BH44
M_VREF_DQ_DIM0: length 1.2
  TOP w0.254: v1(82.09,56.84) 82.59,56.84 TP502.1
  BOTTOM w0.254: v1(82.09,56.84) 82.02,56.91 CPU1.AU28
MCSI_COMP: length 12.8
  TOP w0.102: v2(69.68,39.76) 69.83,39.61 v1(70.79,39.61) 70.91,39.74 70.91,40.37 R817.1
  L3 w0.127: v1(70.79,39.61) 70.79,39.92 72.65,41.79 74.67,41.79 76.45,43.57 77.54,43.57 77.78,43.34 v1(78.57,43.34)
  BOTTOM w0.102: v1(78.57,43.34) 78.65,43.41 79.12,43.41
ME_FWP_SOC: length 10.9
  BOTTOM w0.102: CPU1.AH52 87.08,45.06 87.08,44.67 88.05,43.7 88.87,43.7 89.58,42.99 v2(92.13,42.99) 94.17,42.99 R1531.2 94.61,42.61 R1519.1 95.83,42.6 R1615.1
ME_UNLOCK#: length 75.9
  TOP w0.102: v1(97.03,42.75) 94.72,40.44 94.72,36.89 91.76,33.93 91.3,33.93 90.61,33.23 90.61,32.48 87.86,29.73 82.41,29.73 79.52,26.85 75.78,26.85 75.7,26.77 73.24,26.77 73.24,26.78 73.07,26.78 72.55,27.3 72.55,27.94 72.28,28.2 71.79,28.2 71.56,27.98 71.56,26.98 71.27,26.69 70.87,26.69 69.72,27.84 63.91,27.84 62.88,28.87 60.78,28.87 59.85,27.93 59.45,27.93 58.93,27.41 57.94,27.41 v2(57.43,26.9) 56.46,25.94 56.46,23.81 55.5,22.84 55.5,17.88 56.97,16.41 56.97,16.21 58.81,14.37 60.71,14.37 61.6,13.48 61.6,12.33 61.61,12.32 61.61,12.09 62.27,11.43 v1(62.27,10.93)
  BOTTOM w0.102: U2401.79 63.18,10.5 62.97,10.71 62.49,10.71 v1(62.27,10.93) ; v1(97.03,42.75) 96.55,43.23 R1615.2
MIC2_VREFO: length 9.9
  L3 w0.762: v1(141.36,85.37) 141.36,85.36 142.08,86.08 143.64,86.08 v1(147.78,90.22)
  BOTTOM w0.203: v1(141.36,85.37) 141.36,85.61 141.17,85.8 141.17,86.04 141.08,86.12 U2701.29
  vias: v2(148.27,90.78)
MIC_CAP: length 3.9
  BOTTOM w0.203: 144.24,89.55 144.1,89.55 144.07,89.58 U2701.19
  BOTTOM w0.254: 144.24,89.55 144.8,89.55 145.24,89.11 C2713.1 146,90.12 v2(146.18,90.3)
MIC_GND:
  vias: v2(55.35,81.43)
MODEL_ID: length 202.6
  TOP w0.102: v2(54.14,5.07) 54.53,5.45 v1(54.53,5.74)
  L3 w0.102: v1(54.53,5.74) 54.53,5.95 56.57,7.99 56.57,8.63 57.84,9.9 58.03,9.9 64.94,9.9 64.98,9.93 69.68,9.93 70.35,10.61 70.69,10.61 71.37,9.93 73.45,9.93 73.75,9.63 74.49,9.63 75.2,10.34 84.38,10.34 84.71,10.01 88.72,10.01 88.97,9.75 92,9.75 92.66,10.41 93.84,11.6 94.41,11.6 98.82,11.6 100.68,13.47 103.84,13.47 104.05,13.25 104.44,13.25 104.82,13.25 105.02,13.04 108.27,13.04 108.61,13.38 109.57,13.38 110.32,12.63 114.37,12.63 119.95,7.05 130.59,7.05 131.96,5.68 135.55,5.68 139.67,9.8 140.7,9.8 147.9,17 147.9,20.58 147.9,20.96 148.68,21.74 148.68,23.88 148.01,24.56 148.01,26.46 146.79,27.67 145.71,27.67 144.39,28.99 144.39,33.49 144.89,33.99 145.77,33.99 146.17,34.39 147.02,35.24 147.02,35.94 147.02,38.4 147.28,38.66 148.11,39.49 148.11,41.18 148.11,42.98 148.11,43.36 148.54,43.79 148.94,44.2 148.94,46.1 149.9,47.06 149.9,50.01 150.11,50.21 150.11,52.65 150.11,53.64 149.75,54 147.61,56.14 147.61,64.4 146.78,65.23 146.19,65.82 146.19,70.81 149.67,74.29 149.69,74.29 151.27,74.29 152.56,75.58 152.57,75.58 153.38,75.58 154.8,75.58 154.93,75.71 156.9,77.68 157.21,77.68 157.26,77.62 157.87,77.62 158.36,78.11 159.2,78.11 v1(159.26,78.16)
  BOTTOM w0.102: R2414.1 54.36,5.91 v1(54.53,5.74) ; IOBD1.14 156.29,91.05 158.44,88.9 158.44,85.48 158.55,85.37 158.55,82.87 158.44,82.76 158.44,82.4 158.55,82.3 158.55,82.25 159.05,81.74 159.05,80.86 159.47,80.44 159.47,79.19 159.26,78.98 v1(159.26,78.16)
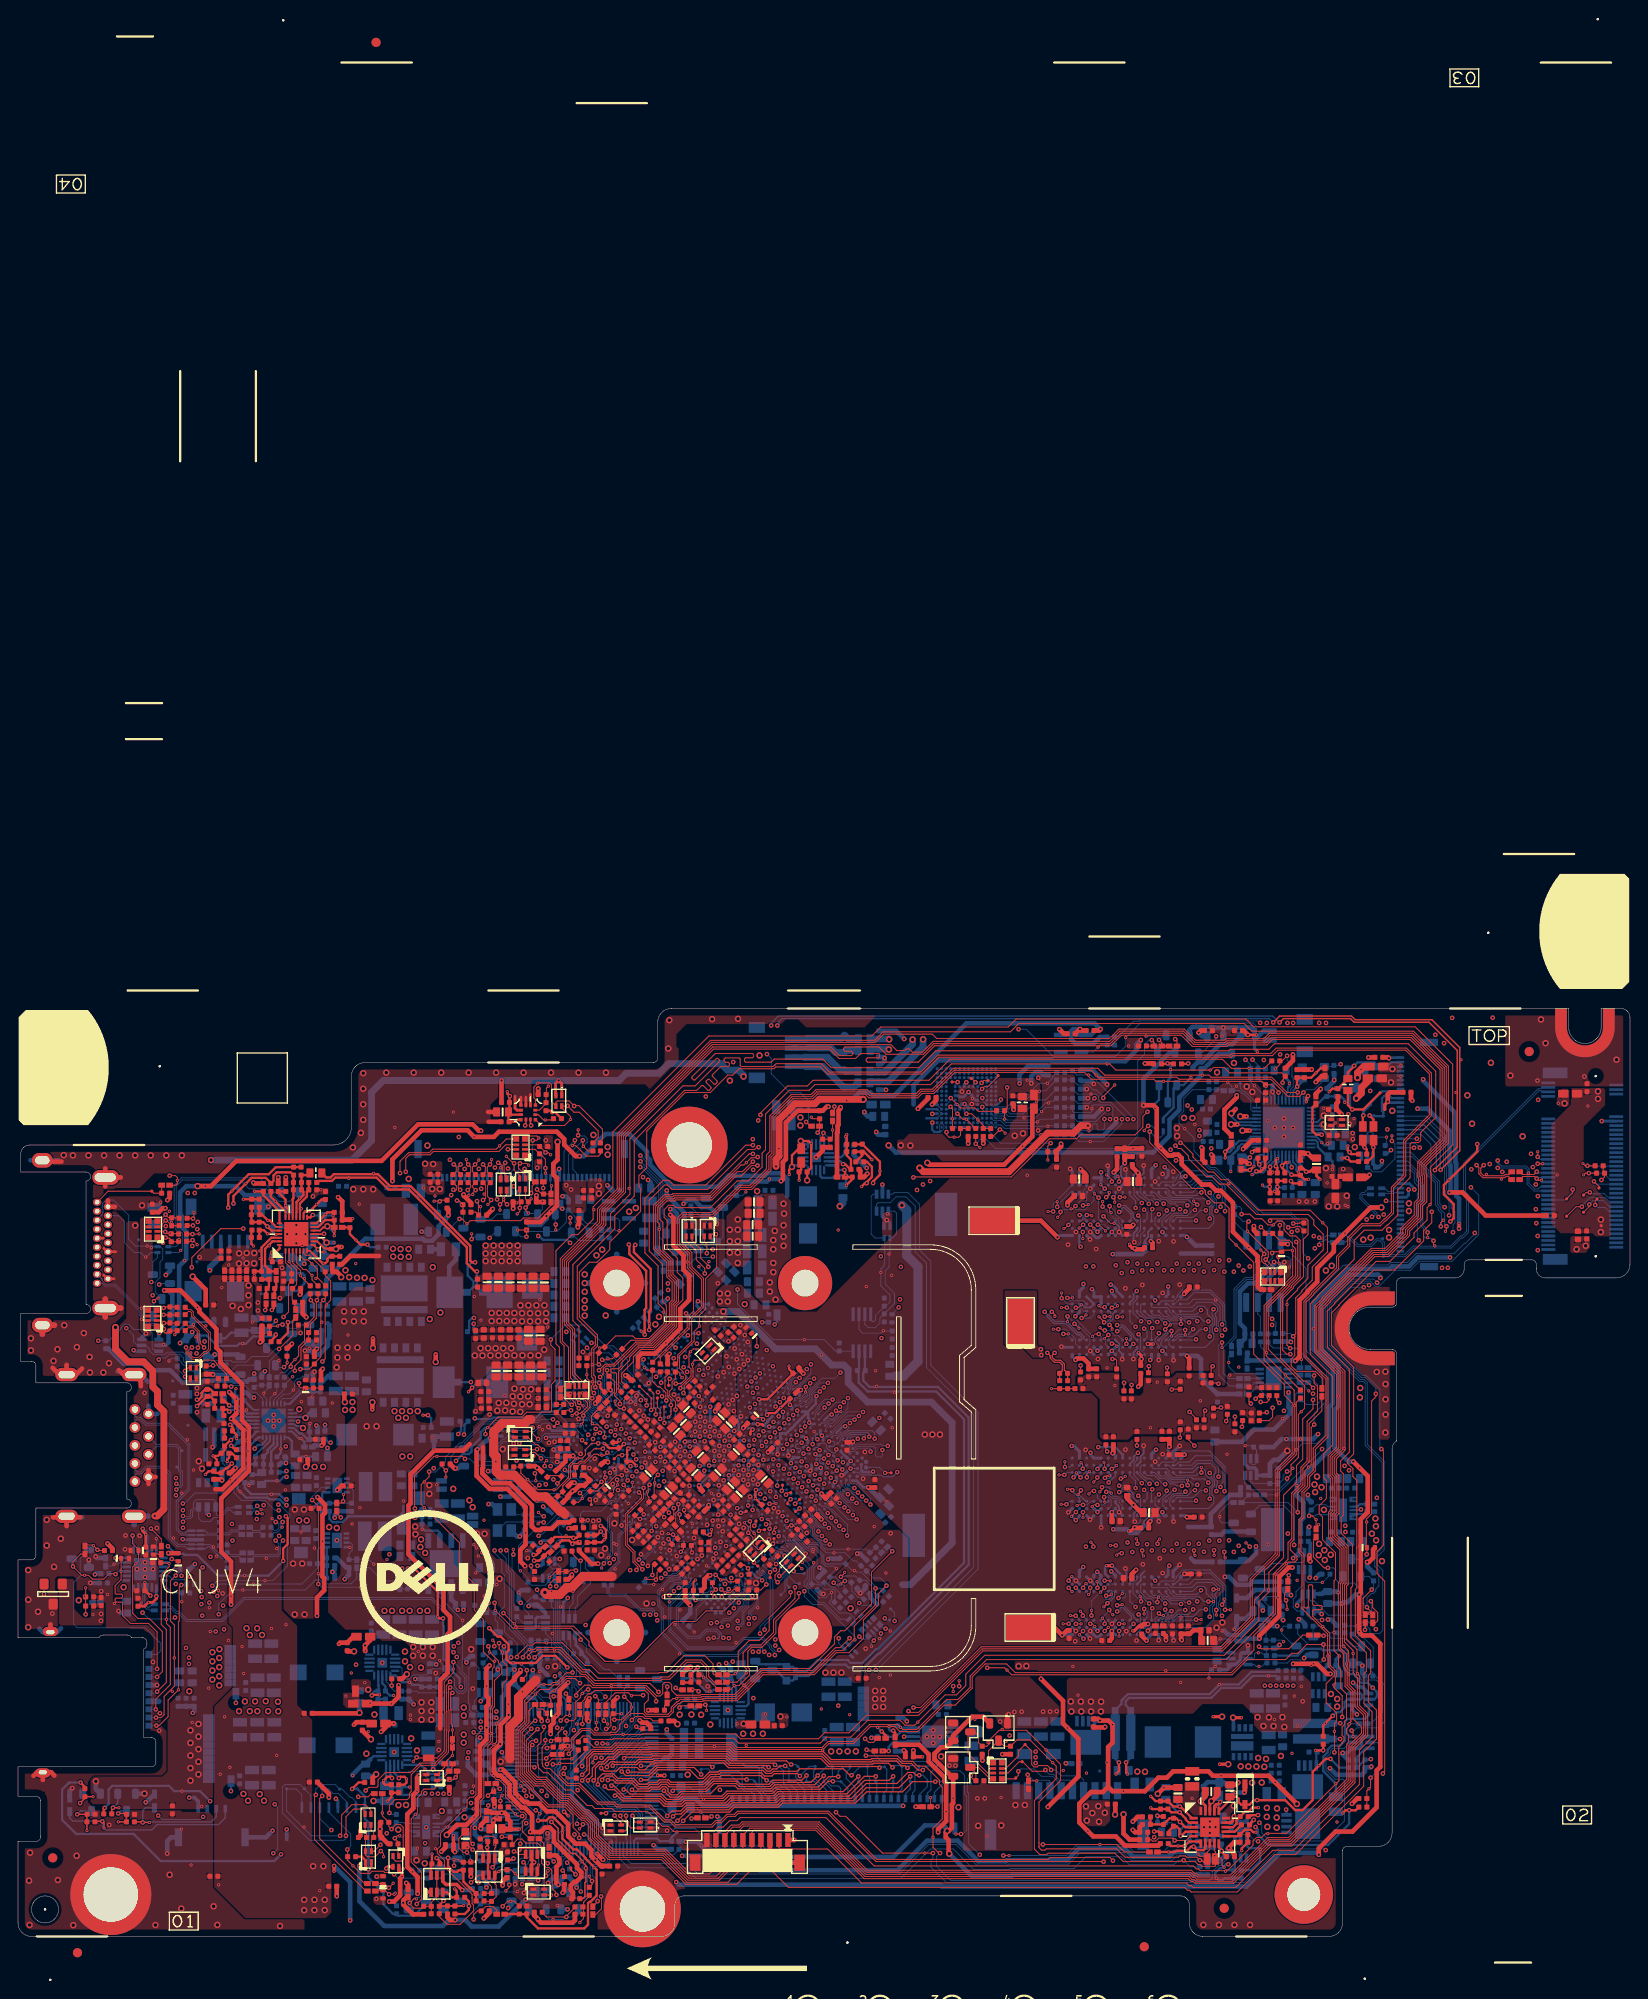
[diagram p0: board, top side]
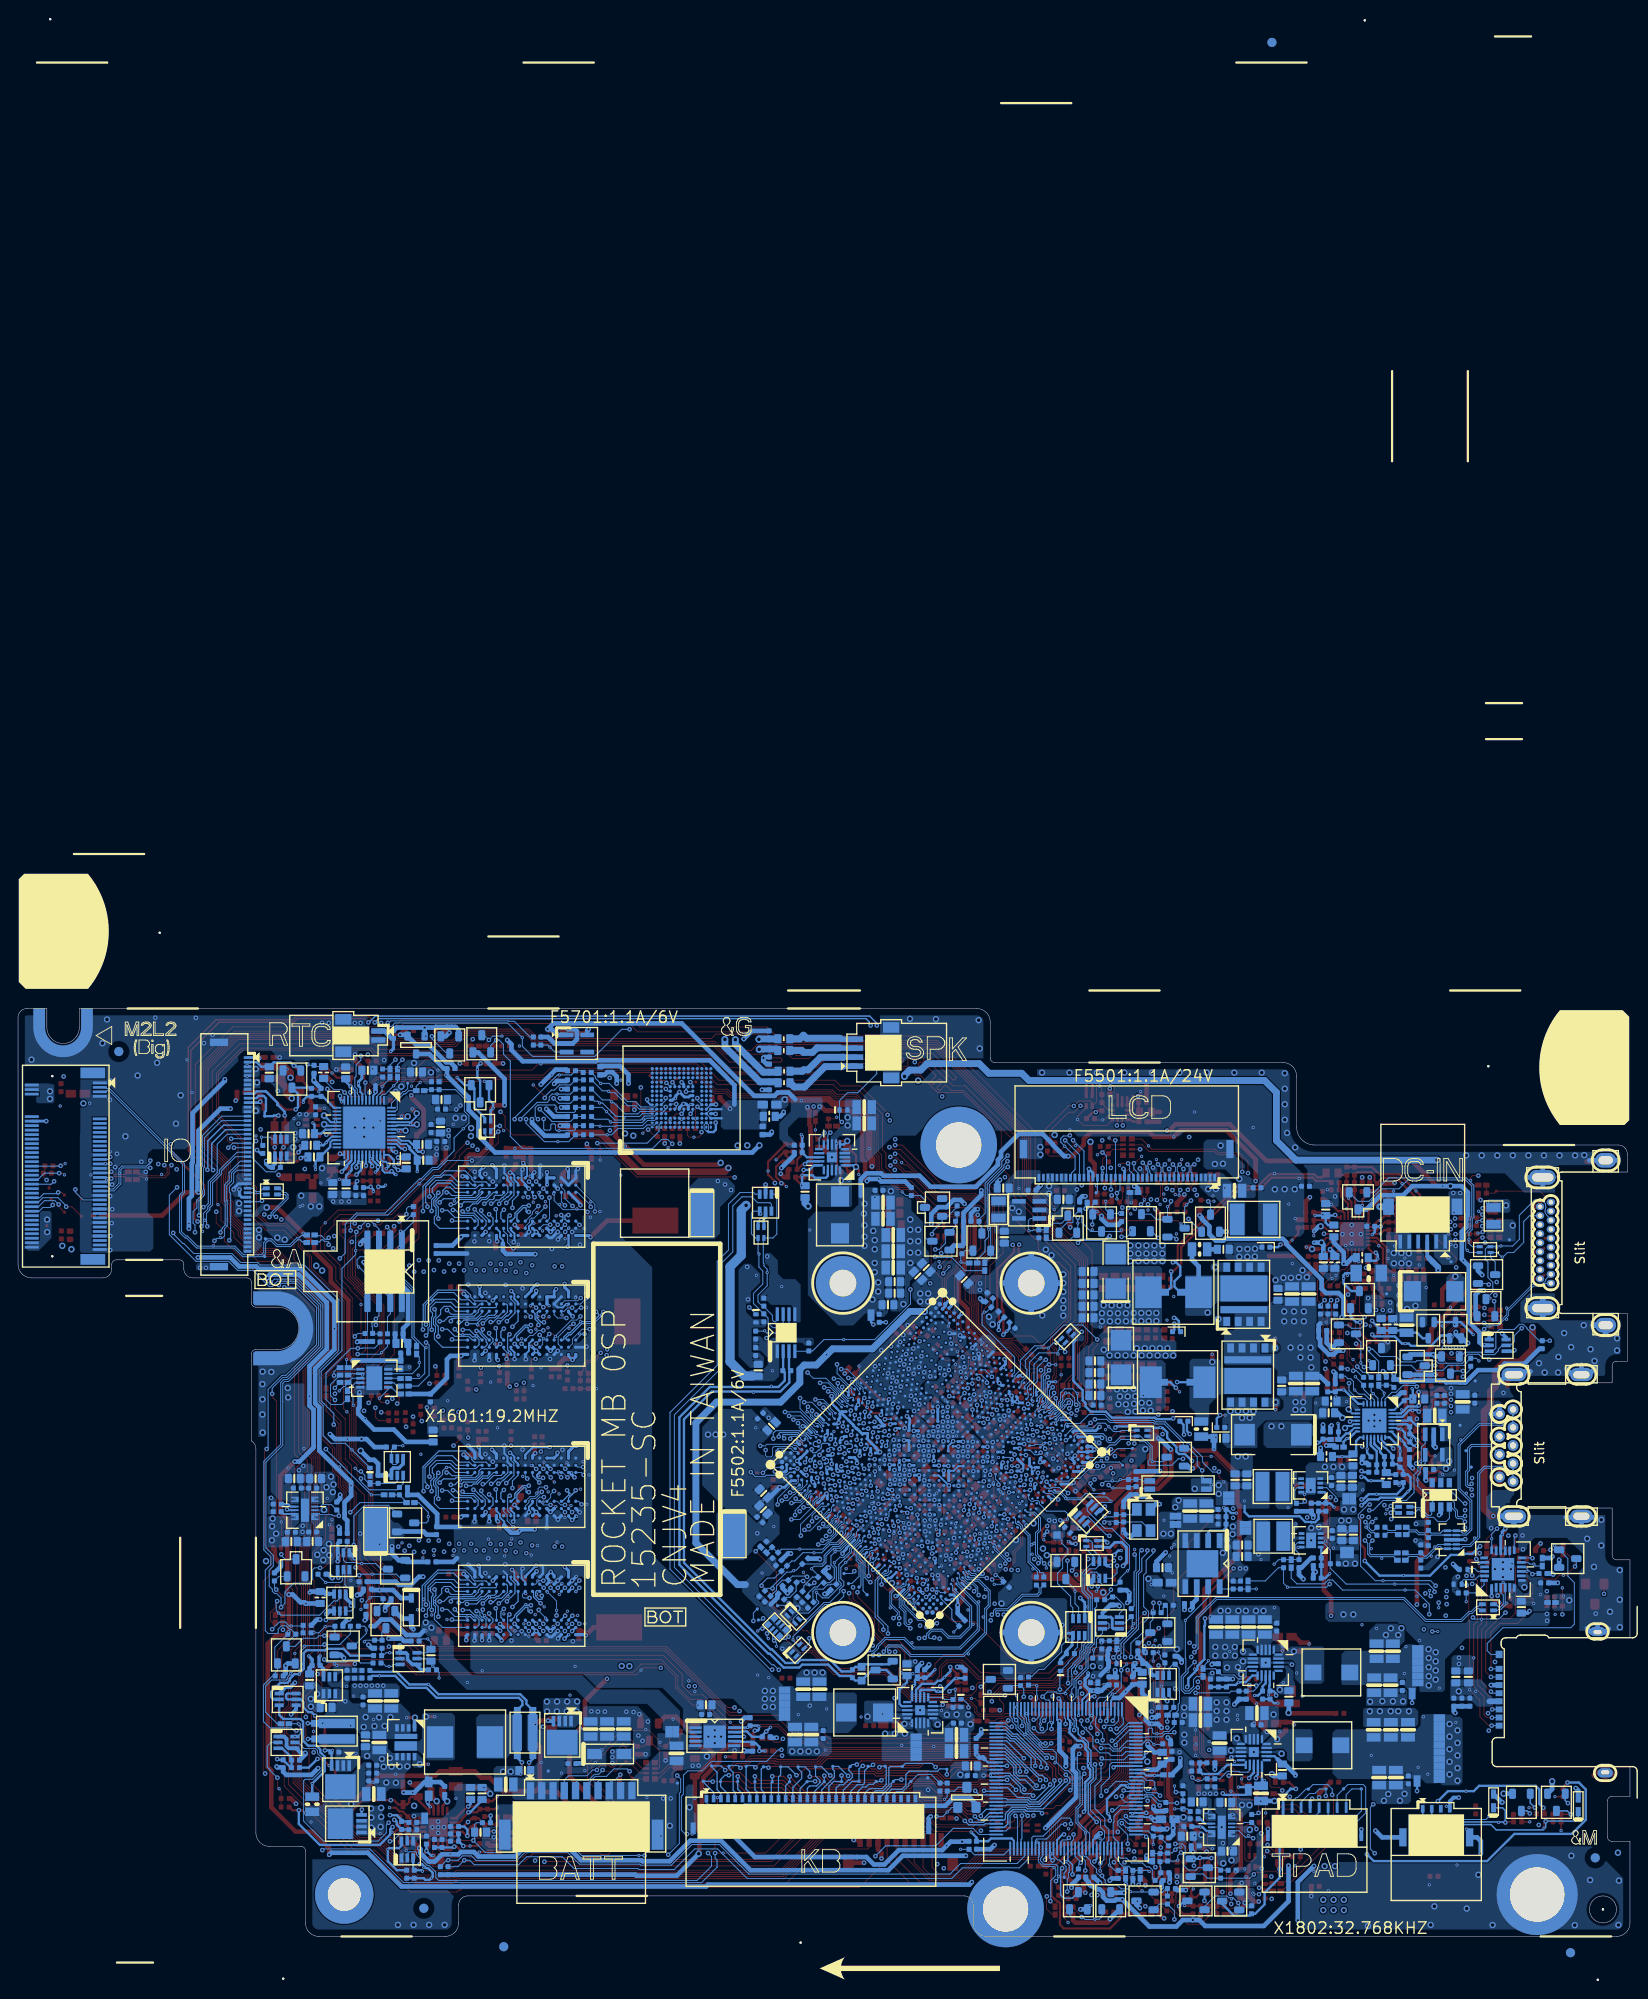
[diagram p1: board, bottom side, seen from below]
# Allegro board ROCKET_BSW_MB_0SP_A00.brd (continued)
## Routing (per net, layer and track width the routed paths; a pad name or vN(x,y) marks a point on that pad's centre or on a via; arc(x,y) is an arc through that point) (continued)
MODEL_ID_AD: length 5.5
  BOTTOM w0.102: U2401.94 57.18,8.85 56.67,8.33 56.67,8.18 56.28,7.79 55.63,7.79 R2410.2 R2414.2 53.48,7.33 v2(53.37,7.22)
NCT3956_OE#_MUX: length 3.3
  BOTTOM w0.102: R2530.2 136.71,60.21 137.46,60.96 U2503.6 137.81,60.72 v2(138.79,59.74)
NCT_CLK: length 18.3
  BOTTOM w0.102: U2601.8 94.64,68.43 94.81,68.25 94.99,68.25 95.17,68.43 95.17,68.95 96.13,69.91 EC2601.1 96.31,69.97 96.78,70.44 96.78,71.2 95.76,72.22 v2(95.76,73.71) 95.76,74.07 96.11,74.42 96.11,74.67 96.19,74.76 96.19,77.46 RN2601.4 95.11,77.53 94.69,77.95 94.69,82.17 94.91,82.39 Q2604.1
NCT_DATA: length 18.2
  BOTTOM w0.102: Q2604.4 97.3,80.51 97.51,80.29 97.51,77.99 97.05,77.53 RN2601.3 96.77,75.91 96.67,75.81 v2(96.67,75.75) 96.67,74.3 96.24,73.87 96.24,72.42 97.28,71.38 97.28,70.26 EC2602.1 95.66,68.63 95.66,68.1 95.13,67.57 94.35,67.57 93.99,67.94 U2601.7
P2800_DXN: length 61.9
  BOTTOM w0.254: 97.27,60.48 101.91,60.48 104.99,57.4 104.99,41.47 95.4,31.88 95.24,31.88 93.72,30.35 92.41,30.35 92.08,30.68 88.76,30.68 87.49,29.42 86.48,29.42 C2604.2 85.98,29.92 R2604.2 85,30.2 84.41,30.2 84.41,30.21 83.05,30.21 83.05,30.2 82.18,30.2 Q2601.E ; 97.27,60.48 v2(97.27,60.41) ; 97.27,60.48 94.29,60.48 93.3,61.48 93.3,62.63 C2605.2 93.34,63 U2601.3
P2800_DXP: length 63.5
  BOTTOM w0.254: U2601.2 93.99,62.83 C2605.1 93.81,62.58 93.81,61.69 94.51,60.99 95.29,60.99 ; 95.29,60.99 102.12,60.99 105.5,57.61 105.5,41.26 95.61,31.37 95.45,31.37 93.93,29.85 92.19,29.85 91.87,30.18 88.97,30.18 87.7,28.91 86.48,28.91 C2604.1 85.98,28.4 R2604.1 84.1,29.57 Q2601.C 82.53,29.57 81.82,28.87 Q2601.B ; 95.29,60.99 v2(95.29,61.07)
PBAT_PRES1#: length 8.7
  TOP w0.102: v1(111.02,18.33) 111.02,17.87 AFTP4301.1 110.64,17.49 RN4301.5
  BOTTOM w0.102: v1(111.02,18.33) 111.28,18.59 112.77,18.59 113.6,17.77 114.83,17.77 115.77,16.82 BATT1.6
PBAT_SMBCLK1: length 14.3
  TOP w0.102: v1(114.66,18.48) 114.66,18.56 114.25,18.96 113.26,18.96 113.12,18.82 112.76,18.82 112.5,19.07 112.5,20.56 AFTP4303.1 111.04,20.58 111.04,20.06 109.62,18.64 RN4301.7
  BOTTOM w0.102: BATT1.4 118.28,17.36 117.81,17.83 115.77,17.83 115.13,18.48 v1(114.66,18.48)
PBAT_SMBDAT1: length 10.4
  TOP w0.102: v1(114.02,18.48) 113.88,18.33 112.56,18.33 111.49,19.4 AFTP4302.1 111.12,19.4 109.86,18.14 RN4301.6
  BOTTOM w0.102: v1(114.02,18.48) 114.17,18.33 114.17,18.28 114.46,18 114.93,18 115.57,17.35 116,17.35 116.75,17.35 117.03,17.08 BATT1.5
PCB_VER_AD: length 5.3
  BOTTOM w0.102: v2(52.91,10.22) R2438.1 ; R2438.1 53.49,11.71 U2401.98 ; R2438.1 52.15,11.13 C2417.1 52.04,10.91 R2437.2
PCH_SUSCLK: length 2.6
  TOP w0.102: v1(63.46,48.51) 63.63,48.34 TP1802.1
  BOTTOM w0.102: CPU1.C15 64.84,49.16 64.19,49.16 63.55,48.51 v1(63.46,48.51)
PCH_SUSCLK_KBC: length 4
  BOTTOM w0.102: TP2403.1 62.81,6.58 62.81,7.04 62.66,7.18 62.66,7.21 62.59,7.28 62.59,7.75 63.32,8.49 63.53,8.49 63.98,8.94 U2401.77
PCIE_OBSN_CPU: length 1.2
  TOP w0.102: R1930.1 69.44,47.01 v1(69.44,46.84)
  BOTTOM w0.102: CPU1.F26 69.49,46.79 v1(69.44,46.84)
PCIE_OBSP_CPU: length 1.3
  TOP w0.102: v1(69.04,46.33) 68.87,46.33 R1930.2
  BOTTOM w0.102: CPU1.D26 v1(69.04,46.33)
PCIE_RX_CPU_N0: length 161
  TOP w0.102: v1(161.87,85.61) 162.13,85.36 162.13,84.66 162.57,84.22 164.63,84.22 ; 164.63,84.22 v2(164.63,84.07) ; 164.63,84.22 165,84.22 165.16,84.38 165.4,84.38 R6104.2 ; v1(69.29,40.75) 69.01,41.03 69.01,41.1 68.47,41.64 68.47,42.7 67.61,43.55 67.61,46.8 69.42,48.61 v1(69.42,49.79)
  L4 w0.114: v1(161.87,85.61) 162.15,85.33 162.15,84.78 162.03,84.65 160.49,84.65 159.31,85.83 152.34,85.83 145.64,79.13 143.23,79.13 142.42,78.31 142.42,76.53 140.97,75.08 140.97,74.64 139.94,73.61 139.94,68.01 138.76,66.83 138.76,63.86 141.45,61.17 141.45,57.39 139.96,55.91 139.96,49.72 139.11,48.87 139.11,46.18 138.06,45.14 138.06,38.22 133.43,33.59 130.49,33.59 129.25,32.36 115.67,32.36 115.49,32.53 98.92,32.53 96.61,34.84 95.19,34.84 94.97,35.06 90.45,35.06 88.74,36.76 81.42,36.76 80.36,37.82 79.5,37.82 78.91,37.23 76.49,37.23 74.29,39.44 71.88,39.44 71.21,38.77 70.5,38.77 69.11,40.16 69.11,40.58 v1(69.29,40.75)
  BOTTOM w0.102: v1(69.42,49.79) 69.41,49.8 CPU1.J20
PCIE_RX_CPU_P0: length 161
  TOP w0.102: 162.96,84.43 v2(162.96,84.59) ; 162.96,84.43 164.91,84.43 165.07,84.59 165.48,84.59 R6101.2 ; 162.96,84.43 162.66,84.43 162.34,84.75 162.34,85.29 v1(162.67,85.61) ; v1(68.65,40.68) 68.79,40.83 68.79,41.01 68.25,41.55 68.25,42.61 67.39,43.46 67.39,46.89 69.21,48.7 69.21,49 v1(68.92,49.29)
  L4 w0.114: v1(162.67,85.61) 162.38,85.33 162.38,84.68 162.12,84.42 160.39,84.42 159.22,85.6 152.43,85.6 145.73,78.9 143.33,78.9 142.65,78.22 142.65,76.43 141.2,74.98 141.2,74.54 140.17,73.51 140.17,67.92 138.99,66.74 138.99,63.96 141.67,61.27 141.67,57.29 140.19,55.81 140.19,49.62 139.34,48.77 139.34,46.09 138.29,45.04 138.29,38.13 133.53,33.36 130.58,33.36 129.35,32.13 115.58,32.13 115.4,32.31 98.82,32.31 96.52,34.61 95.1,34.61 94.88,34.83 90.35,34.83 88.65,36.53 81.32,36.53 80.26,37.59 79.6,37.59 79.01,37 76.4,37 74.19,39.21 71.97,39.21 71.31,38.54 70.4,38.54 68.88,40.06 68.88,40.45 v1(68.65,40.68)
  BOTTOM w0.102: CPU1.G20 68.91,49.3 v1(68.92,49.29)
PCIE_TX_CON_N0: length 159.6
  TOP w0.102: v1(168.66,85.77) v2(169.21,85.77)
  L4 w0.114: v1(70.16,35.71) 70.26,35.61 70.26,34.49 70.66,34.08 77.35,34.08 77.88,33.56 79.32,33.56 79.51,33.37 80.76,33.37 82.42,35.03 83.72,35.03 84.66,34.08 84.66,32.58 85.89,31.35 88.52,31.35 89.59,32.43 94.45,32.43 95.05,31.83 97.11,31.83 98.29,30.65 129.9,30.65 130.92,31.67 134.67,31.67 139.8,36.8 139.8,44.46 141.03,45.69 141.03,48.23 142.58,49.77 142.58,55.04 143.16,55.63 143.16,61.83 143.1,61.89 140.72,64.27 140.72,66.42 141.63,67.34 141.63,72.76 152.45,83.58 159.15,83.58 160.25,82.48 164.18,82.48 167.79,86.09 168.34,86.09 v1(168.66,85.77)
  BOTTOM w0.102: v1(168.66,85.77) 168.68,85.75 WLAN1.37 ; v1(70.16,35.71) 70.42,35.97 70.42,36.08 70.35,36.15 68.99,36.15 67.37,37.77 65.7,37.77 65.37,38.11 65.37,38.7 C1916.2
PCIE_TX_CON_P0: length 159.3
  TOP w0.102: v2(168.66,87.09) v1(168.66,86.53)
  L4 w0.114: v1(168.66,86.53) 168.44,86.32 167.69,86.32 164.09,82.71 160.34,82.71 159.25,83.8 152.36,83.8 141.41,72.85 141.41,67.43 140.49,66.52 140.49,64.18 140.9,63.77 142.94,61.73 142.94,55.72 142.35,55.14 142.35,49.87 140.8,48.32 140.8,45.79 139.57,44.55 139.57,36.9 134.57,31.9 130.83,31.9 129.8,30.87 98.39,30.87 97.2,32.06 95.14,32.06 94.54,32.66 89.5,32.66 88.43,31.58 85.98,31.58 84.89,32.68 84.89,34.18 83.81,35.26 82.32,35.26 80.66,33.6 79.6,33.6 79.41,33.79 77.97,33.79 77.45,34.31 70.76,34.31 70.49,34.58 70.49,35.37 v1(70.82,35.71)
  BOTTOM w0.102: C1915.2 65.58,38.7 65.58,38.2 65.79,37.99 67.46,37.99 69.08,36.37 70.44,36.37 70.64,36.17 70.64,35.89 v1(70.82,35.71) ; WLAN1.35 168.94,86.25 v1(168.66,86.53)
PCIE_TX_CPU_N0: length 7.7
  BOTTOM w0.102: 66.58,42.42 66.58,44.56 67.41,45.39 67.41,45.58 67.85,46.02 CPU1.B24 ; 66.58,42.42 66.58,41.63 65.54,40.59 65.54,40.45 65.47,40.38 65.17,40.38 65.05,40.27 C1916.1 ; 66.58,42.42 v2(66.34,42.42)
PCIE_TX_CPU_P0: length 8
  BOTTOM w0.102: 66.16,40.9 65.76,40.5 65.76,40.02 C1915.1 ; 66.16,40.9 v2(66.27,40.79) ; 66.16,40.9 66.8,41.54 66.8,44.47 67.62,45.3 67.62,45.49 67.87,45.73 68.01,45.73 68.18,45.9 68.18,46.31 CPU1.C24
PCU_SMB_ALERT#: length 1.5
  TOP w0.102: TP1622.1 72.2,61.79 v1(72.32,61.9)
  BOTTOM w0.102: CPU1.AM9 72.34,61.88 v1(72.32,61.9)
PD4403_A: length 3.5
  BOTTOM w0.508: v2(135,34.09) 135.25,34.34 PD4404.A 136.24,35.27 PQ4409.B
PD4403_K: length 4.8
  BOTTOM w0.508: PD4404.K 136.39,37.56 137.28,38.45 v2(138.78,38.45) 139.58,38.45 PR4468.2
PEG_CLK0_CPU: length 166
  L4 w0.114: v1(65.66,41.44) 65.39,41.17 65.39,40.56 67.54,38.41 69.84,38.41 70.26,37.99 70.74,37.99 72.59,36.13 77.85,36.13 78.59,35.4 79.26,35.4 79.89,36.03 88.39,36.03 90.11,34.3 94.46,34.3 95.63,33.13 97.17,33.13 98.49,31.81 129.66,31.81 130.5,32.65 133.63,32.65 138.85,37.86 138.85,44.89 139.95,45.99 139.95,48.51 141.6,50.16 141.6,55.6 142.21,56.21 142.21,61.44 139.66,63.98 139.66,66.71 140.67,67.72 140.67,73.32 142.17,74.81 142.17,75.21 143.14,76.18 143.14,78.01 143.53,78.4 145.93,78.4 152.16,84.62 159.45,84.62 160.23,83.84 163.39,83.84 163.78,84.24 163.78,85.49 164.22,85.92 v1(164.22,86.12)
  BOTTOM w0.102: WLAN1.47 169,83.25 168.71,82.97 168.33,82.97 167.7,83.6 167.7,85.2 167.38,85.52 164.62,85.52 164.4,85.74 164.3,85.74 164.22,85.81 v1(164.22,86.12) ; v1(65.66,41.44) 65.52,41.44 65.45,41.51 65.45,41.83 65.97,42.36 65.97,43.64 ; 65.97,43.64 65.97,44.81 65.64,45.14 65.64,46.37 66.16,46.88 66.49,46.88 CPU1.A21 ; 65.97,43.64 v2(66.14,43.64)
PEG_CLK0_CPU#: length 166.6
  L4 w0.114: v1(164.22,85.3) 164.01,85.1 164.01,84.14 163.48,83.61 160.14,83.61 159.36,84.4 152.25,84.4 146.03,78.18 143.63,78.18 143.37,77.92 143.37,76.09 142.4,75.11 142.4,74.72 140.9,73.22 140.9,67.63 139.89,66.62 139.89,64.08 142.44,61.53 142.44,56.12 141.83,55.51 141.83,50.07 140.18,48.42 140.18,45.9 139.08,44.8 139.08,37.77 133.73,32.42 130.6,32.42 129.76,31.58 98.4,31.58 97.07,32.9 95.54,32.9 94.37,34.07 90.02,34.07 88.3,35.8 79.98,35.8 79.35,35.17 78.5,35.17 77.76,35.9 72.5,35.9 70.64,37.76 70.16,37.76 69.74,38.18 67.45,38.18 65.16,40.46 65.16,41.26 v1(65.02,41.41)
  BOTTOM w0.102: WLAN1.49 168.24,82.75 167.48,83.51 167.48,85.11 167.29,85.3 v1(164.22,85.3) ; CPU1.C21 66.91,47.1 66.07,47.1 65.43,46.46 65.43,45.05 65.76,44.72 65.76,42.44 65.23,41.92 65.23,41.62 v1(65.02,41.41) 64.77,41.16 v2(64.77,40.9)
PEG_CLKREQ0_CPU#: length 25.4
  TOP w0.102: v1(72.99,61.36) 73.57,61.36 74.11,61.91 74.11,62.25 73.85,62.51 73.85,62.63 73.42,63.06 73.42,64.45 75.04,66.07 75.04,67.15 v2(75.64,67.75) 75.64,68.96 76.32,69.64 76.32,73.01 77.55,74.24 77.55,77.87 v1(77.47,77.95) 77.06,77.95 RN1902.4
  BOTTOM w0.102: v1(72.99,61.36) 73.52,61.36 CPU1.AM10 ; v1(77.47,77.95) 77.35,78.07 77.35,78.31 76.34,79.31 D1901.1 75.71,79.93 74.68,80.97 R1905.2
PEG_CLKREQ0_D: length 8
  BOTTOM w0.102: Q1901.D 77.8,77.17 78.25,77.62 D1901.3 78.25,81.75 78.73,82.23 R1902.2 80.37,82.23 v2(80.78,82.64)
PEG_CLKREQ0_WLAN#: length 128.6
  TOP w0.102: AFTP6102.1 172.54,82.54 v1(172.54,82.92) ; v1(125.35,91.54) 124.84,91.02 124.84,89.83 123.98,88.97 117.91,88.97 117.48,88.54 114.47,88.54 110.24,84.3 99.42,84.3 v1(99.36,84.25)
  L3 w0.127: v1(125.35,91.54) 126.27,90.61 128.85,90.61 129.81,89.65 129.81,87.98 133.62,84.17 134.18,84.17 137.66,80.7 143.64,80.7 143.87,80.47 147.14,80.47 153.27,86.6 156.62,86.6 157.35,87.33 169.85,87.33 172.54,84.64 v1(172.54,82.92) ; v1(99.36,84.25) 99.06,83.95 95.21,83.95 94.95,84.21 94.13,84.21 93.73,83.81 93.73,79.2 91.39,76.86 90.31,75.79 85.7,75.79 85.61,75.69 82.84,75.69 80.95,73.8 79.56,73.8 v1(77.1,76.26)
  BOTTOM w0.102: WLAN1.53 171.66,81.75 172.54,82.63 v1(172.54,82.92) ; v1(77.1,76.26) 76.65,76.26 75.98,76.93 75.98,77.69 Q1901.S 74.85,78.82 R1904.2 74.68,79.57 R1905.1
PEG_CLKREQ1_CPU#: length 6.8
  TOP w0.102: v1(73.51,60.86) 73.51,61.01 74.69,62.19 74.69,62.99 74.47,63.21 74.47,64.74 v2(74.62,64.89) 74.94,65.21 75.51,65.21 RN1901.3
  BOTTOM w0.102: CPU1.AM12 74.02,60.86 v1(73.51,60.86)
PEG_CLKREQ2_CPU#: length 7
  TOP w0.102: v1(73.85,60.31) 73.93,60.39 73.93,61.13 74.92,62.12 74.92,63.08 74.86,63.13 v2(74.86,63.51) 74.86,63.72 75.11,63.96 76.04,63.96 RN1901.4
  BOTTOM w0.102: v1(73.85,60.31) 74.35,59.82 CPU1.AK14
PEG_CLKREQ3_CPU#: length 20.6
  TOP w0.102: v1(76.45,75.84) 76.45,76.82 76.17,77.1 RN1902.3 ; v2(76,59.54) 75.56,59.97 v1(75.55,59.97)
  L3 w0.127: v1(76.45,75.84) 76.45,75.84 76.45,75.42 77.13,74.73 77.13,70.61 76.06,69.53 76.06,65.81 74.81,64.56 74.81,62.26 75.55,61.51 v1(75.55,59.97)
  BOTTOM w0.102: v1(75.55,59.97) 75.45,59.87 CPU1.AM14
PLT_RST#: length 218.8
  TOP w0.102: 82.45,8.49 79.75,5.79 74.14,5.79 71.37,8.55 65.51,8.55 63.29,10.78 63.29,12.46 62.85,12.9 62.51,12.9 60.81,14.6 58.9,14.6 57.19,16.31 57.19,16.5 55.73,17.97 55.73,22.75 56.69,23.72 56.69,25.06 R1810.2 57.38,25.63 57.77,25.24 58.22,25.24 EC1809.1 58.78,24.68 v1(58.78,23.93) ; 82.45,8.49 85.49,5.45 129.47,5.45 129.78,5.14 130.02,5.14 130.22,4.94 135.32,4.94 139.46,9.08 141.76,9.08 149.35,16.67 149.35,20.49 150.76,21.9 150.76,25.13 149.86,26.03 149.86,28.98 150.12,29.24 150.12,31.69 148.41,33.4 148.41,38.5 148.59,38.67 148.59,43.13 148.59,50.62 148.15,51.05 148.15,51.92 147.9,52.17 147.89,52.17 147.57,52.5 147.57,52.89 148.23,53.55 148.23,63.15 145.79,65.59 145.79,69.22 146.61,70.04 146.61,70.13 150.45,73.98 152.77,73.98 156,77.21 156,78.33 156.9,79.23 v1(156.9,80.44) ; 82.45,8.49 DB1.4 ; v1(174.44,82.59) 174.05,82.59 AFTP6105.1
  L3 w0.127: v1(156.9,80.44) 157.73,81.26 158.01,81.26 158.14,81.4 158.51,81.4 158.64,81.26 163.45,81.26 164.77,79.95 170.37,79.95 172.1,81.68 173.53,81.68 v1(174.44,82.59)
  BOTTOM w0.102: v1(58.78,23.93) U2401.7 ; WLAN1.52 176.5,82 176.06,82.44 174.59,82.44 174.44,82.58 v1(174.44,82.59)
PLT_RST#_CPU_G: length 4.4
  TOP w0.102: v2(59,39.85) 59.66,40.51 R1827.2 60.01,40.52 R1842.2 61.15,40.52 61.29,40.66 61.88,40.66 v1(61.93,40.62)
  BOTTOM w0.102: v1(61.93,40.62) 61.92,40.62 61.63,40.91 Q1812.G
PLT_RST#_D: length 8.7
  TOP w0.102: R1843.1 61.48,42.51 62.28,41.71 v1(62.43,41.71)
  BOTTOM w0.102: v1(62.43,41.71) 62.43,39.84 Q1812.D ; Q1812.D 62.61,39.52 61.59,38.51 v2(61.59,38.3) 61.59,36.93 61.19,36.53 61.19,35.31 Q1813.2 ; Q1812.D 62.62,39.66
PLTRST#: length 12.6
  TOP w0.102: v1(62.37,28.11) 61.85,28.63 60.87,28.63 59.52,27.28 v2(59.52,27.26) 59.28,27.26 59.01,26.99 59.01,26.46 59.12,26.36 R1864.2 58.36,25.66 R1810.1
  BOTTOM w0.102: v1(62.37,28.11) 62.37,29.63 61.86,30.13 61.86,30.23 61.06,31.03 61.06,31.67 60.84,31.88 60.84,32.58 60.51,32.91 Q1813.6
PLTRST#_CPU: length 136.4
  TOP w0.102: R1827.1 59.49,39.62 59.06,39.2 v1(59.06,38.86) ; v1(128.43,99.6) 128.63,99.4 R6328.2
  L3 w0.127: v1(65.7,51.47) 65.11,51.47 64.77,51.13 62.79,51.13 61.91,52 61.1,52 60.89,52.21 60.46,52.21 60.2,51.95 59.21,51.95 59.11,52.05 v1(59.11,52.21) 58.68,52.64 57.87,52.64 57.58,52.94 57.58,53.49 57.18,53.88 57.18,55.28 57.57,55.66 57.85,55.66 58.33,56.14 60.08,56.14 60.95,57.01 60.95,59.12 61.06,59.23 61.06,62.3 64.34,65.58 64.34,66.45 62.35,68.43 62.35,73.71 62.73,74.1 62.73,75.6 63.9,76.76 63.9,79.3 68.62,84.02 68.62,84.43 68.91,84.72 69.32,84.72 70.02,85.42 70.02,89.57 76.14,95.68 79.73,95.68 80.26,96.21 82.02,96.21 84.71,98.89 93.16,98.89 94.68,100.41 110.09,100.41 110.53,99.96 128.07,99.96 v1(128.43,99.6)
  L4 w0.127: v1(59.06,38.86) 59.06,44.17 57.58,45.65 57.58,49.27 57.15,49.71 57.15,50.51 58.3,51.66 58.56,51.66 v1(59.11,52.21)
  BOTTOM w0.102: v1(65.7,51.47) 65.7,51 CPU1.F14 ; v2(59.22,38.32) 59.06,38.48 v1(59.06,38.86)
PLTRST#_CPU_D: length 4.2
  TOP w0.102: v1(126.63,99.51) 126.95,99.19 R6327.2 R6328.1
  BOTTOM w0.102: v2(125.19,99.93) 126.21,99.93 v1(126.63,99.51) 127.16,100.04 Q6301.D
PM_PCIE_WAKE#: length 40.5
  TOP w0.102: v1(52.86,32.21) 52.86,32.71 v2(52.69,32.88) ; v1(57.6,54.08) 57.57,54.08 57.53,54.04 RN1801.2
  L3 w0.127: v1(69.22,52.05) 68.82,52.05 68.21,52.66 67.7,52.66 67.64,52.6 66.01,52.6 65.64,52.23 65.29,52.23 65.05,52.47 64.7,52.47 64.51,52.28 63.71,52.28 63.59,52.4 62.16,52.4 62.1,52.46 61.29,52.46 61.08,52.67 60.77,52.67 60.04,53.4 58.3,53.4 58.22,53.48 57.91,53.48 57.6,53.78 v1(57.6,54.08)
  L4 w0.127: v1(52.86,32.21) 52.86,33.03 53.02,33.19 53.02,36.15 54.2,37.34 54.2,38.55 55.09,39.43 55.09,41.51 56.87,43.29 56.87,44.92 56.57,45.23 56.57,48.85 56.13,49.28 56.13,51.87 57.15,52.88 57.32,52.88 57.61,53.17 57.61,53.95 57.6,53.96 v1(57.6,54.08)
  BOTTOM w0.102: CPU1.N16 69.05,52.22 v1(69.22,52.05)
PM_PWRBTN#: length 5.8
  TOP w0.102: v1(58.78,8.12) 58.35,8.56 58.35,10.32 R2417.1
  BOTTOM w0.102: U2401.91 58.38,8.52 v1(58.78,8.12) 58.78,7.31 v2(58.81,7.28)
PM_PWRBTN#_CPU: length 62.7
  TOP w0.102: R2417.2 56.78,10.85 55.97,11.67 55.97,12.75 56.39,13.17 56.39,13.54 56.13,13.79 55.8,13.79 54.86,14.73 54.86,14.73 54.11,15.48 54.11,16.68 53.37,17.42 53.07,17.42 52.38,18.11 52.38,20.84 53.12,21.57 53.12,23.68 53.74,24.3 53.74,28.01 54.26,28.54 54.26,30.07 53.77,30.56 v2(53.77,31.56) 53.39,31.94 v1(53.39,32.56) ; RN1801.1 56.64,53.39 56.99,53.73 57.37,53.73 v1(58.05,53.06)
  L3 w0.127: v1(58.05,53.06) 58.07,53.09 60.01,53.09 60.65,52.44 60.98,52.44 61.2,52.23 62.01,52.23 62.88,51.35 64.67,51.35 65.2,51.89 65.63,51.89 66.04,52.3 66.43,52.3 66.53,52.2 v1(67.97,52.2)
  L4 w0.127: v1(53.39,32.56) 53.26,32.68 53.26,33.08 53.27,33.08 53.27,36.03 54.45,37.22 54.45,38.44 55.34,39.33 55.34,41.4 57.13,43.18 57.13,45.03 56.82,45.33 56.82,48.96 56.39,49.39 56.39,51.76 57.28,52.65 57.64,52.65 v1(58.05,53.06)
  BOTTOM w0.102: CPU1.M16 68.04,52.17 68,52.2 v1(67.97,52.2)
PM_RSMRST#: length 32
  TOP w0.102: v2(57.45,50.57) 57.45,51.32 v1(57.37,51.41)
  L3 w0.127: v1(57.37,51.41) 58.07,51.41 59.97,49.51 60.5,49.51 60.91,49.92 61.27,49.92 61.27,49.92 61.62,49.92 61.62,49.92 63.86,49.92 64.42,49.36 66.4,49.36 v1(66.58,49.54)
  L4 w0.127: v1(57.37,51.41) 57.37,51.09 56.9,50.62 56.9,49.6 57.33,49.17 57.33,45.54 58.76,44.12 58.76,40.71 57.61,39.56 v1(57.61,38.48)
  BOTTOM w0.102: CPU1.F18 66.65,49.47 v1(66.58,49.54) ; v1(57.61,38.48) 57.61,38.3 57.94,37.97 57.94,37.96 58.3,37.6 R1841.1 58.28,37.37 57.91,37.37 57.59,37.68 R1861.1 57.42,37.67 57.04,37.67 56.16,36.79 56.16,36.35 56.67,35.84 Q1801.3
PM_SLP_S0IX#: length 6
  BOTTOM w0.102: CPU1.A13 63.73,49.42 63.19,49.42 62.46,48.68 60.9,48.68 60.41,49.17 TP1801.1
PM_SLP_S3#: length 514.8
  TOP w0.102: v1(29.46,68.76) 30.02,69.31 30.02,72.39 PR4813.1 PC4803.1 30.37,74.1 29.69,74.78 PU4802.1 ; PR5125.1 94.31,20.59 v1(94.18,20.72) ; v1(56.93,41.14) 56.93,40.9 R1856.1 ; v1(19.29,74.26) 19.29,75.35 22.5,78.56 v1(25,78.56) ; v1(149.71,36.54) 149.71,36.5 150.35,35.86 R4010.1 ; R4003.1 143.78,44.06 143.78,42.09 144.97,40.91 v1(145.37,40.91) ; v1(104.66,11.37) 104.11,11.37 104.1,11.37 v2(104.08,11.37)
  L3 w0.127: v1(150.84,72.57) 151.32,72.57 151.66,72.91 151.66,73.29 152.97,74.6 152.98,74.6 156.88,74.6 159.43,77.15 171.25,77.15 174.65,80.55 175.31,80.55 175.66,80.89 175.66,82.06 167.45,90.26 167.45,91.01 156.96,101.5 146.13,101.5 145.33,100.7 138.42,100.7 137.86,101.25 v1(137.86,101.42) ; v1(25,78.56) 25.56,78.01 26.21,78.01 27.47,76.74 27.47,73.99 29.53,71.93 29.53,68.82 v1(29.46,68.76) ; v1(13.82,35.94) 13.82,35.29 15.66,33.45 15.66,31.4 16.35,30.72 16.35,25.78 16.93,25.19 16.93,13.43 25.09,5.27 36.81,5.27 40.1,1.99 47.55,1.99 48.49,2.93 49.2,2.93 49.61,2.53 54.03,2.53 54.11,2.45 54.69,2.45 54.76,2.53 57.54,2.53 58.66,3.64 58.66,4.63 58.68,4.65 58.68,4.78 59.51,5.62 59.51,5.65 59.52,5.66 59.52,6.31 59.87,6.66 60.78,6.66 61.54,7.42 62.5,7.42 62.94,6.98 65.24,6.98 66.36,8.09 72.54,8.09 72.88,7.75 74.61,7.75 75.95,9.09 83.57,9.09 v1(83.75,8.92) 83.86,8.8 88.22,8.8 88.47,8.55 92.5,8.55 93.86,9.91 94.34,10.39 103.68,10.39 v1(104.66,11.37) 104.68,11.34 105.21,11.34 105.62,10.94 107.87,10.94 108.18,11.25 114.05,11.25 119.45,5.85 130.09,5.85 131.46,4.47 136.05,4.47 140.15,8.57 142.49,8.57 144.55,10.63 145.12,10.63 149.11,14.63 149.11,20.46 150.04,21.39 150.04,25.56 149.64,25.96 149.64,26.53 149.26,26.91 149.26,28.23 150.18,29.15 150.18,30.9 149.83,31.25 149.83,33.75 149.94,33.86 149.94,34.23 149.83,34.34 149.83,36.29 149.71,36.41 v1(149.71,36.54)
  L4 w0.127: v1(56.93,41.14) 56.93,41.32 56.7,41.55 56.39,41.55 56.37,41.57 56.08,41.57 55.59,41.09 55.59,39.22 54.71,38.33 54.71,31.99 54.21,31.5 51.92,31.5 51.48,31.94 51.48,32.77 50.9,33.35 50.9,33.95 50.23,34.62 49.43,34.62 46.72,37.33 34.62,37.33 34.32,37.63 23.28,37.63 23.01,37.37 22.69,37.37 22.1,36.78 21.95,36.78 21.24,36.07 20.24,36.07 19.58,35.41 v1(17.42,35.41) 18.59,36.57 18.59,40.35 18.48,40.46 18.48,41.91 18.76,42.19 18.76,50.79 17.33,52.23 17.33,58.95 16.85,59.43 16.57,59.7 16.57,65.44 16.71,65.58 16.71,65.59 17.93,66.81 17.93,72.67 19.29,74.03 v1(19.29,74.26)
  BOTTOM w0.102: v1(104.66,11.37) 104.7,11.41 104.9,11.41 105.28,11.8 105.28,15.57 105.05,15.8 105.05,17.9 104.57,18.38 102.99,18.38 101.94,19.43 95.82,19.43 94.52,20.72 v1(94.18,20.72) ; v1(145.37,40.91) 145.98,40.91 146.2,40.69 146.2,39.64 146.63,39.22 148.3,39.22 149.24,38.27 149.24,38.16 149.28,38.13 149.28,36.97 v1(149.71,36.54) 149.71,37.58 150.2,38.07 150.42,38.07 150.68,38.32 150.68,38.54 151.03,38.89 151.03,40.65 150.57,41.1 150.57,42.29 151.39,43.11 151.39,52.64 149.52,54.52 149.52,59.37 149.52,59.37 149.52,61.39 149.31,61.59 148.87,61.59 145.07,65.39 145.07,70.19 147.85,72.96 150.45,72.96 150.84,72.58 v1(150.84,72.57) ; U2401.64 72.22,11.31 72.9,11.99 75.11,11.99 77.04,10.06 82.6,10.06 v1(83.75,8.92) ; v1(13.82,35.94) 14.53,35.23 17.25,35.23 v1(17.42,35.41) ; Q1810.3 57.53,39.75 56.93,40.34 v1(56.93,41.14) ; PR5315.1 122.07,99.84 123.82,101.58 124.43,101.58 124.47,101.63 137.53,101.63 137.74,101.42 v1(137.86,101.42)
PM_SLP_S3#_CPU: length 9.8
  BOTTOM w0.102: Q1814.5 58.93,48.18 57.72,48.18 v2(57.59,48.3) 58.06,48.77 60.34,48.77 60.63,48.47 62.54,48.47 63.28,49.21 63.93,49.21 64.17,49.46 CPU1.B14
PM_SLP_S3#_CPU_D: length 141.6
  TOP w0.102: v1(57.03,15.5) 57.03,15.64 56.74,15.93 56.74,16.31 55.27,17.78 55.27,22.94 56.24,23.9 56.24,26.21 57.99,27.97 v2(58.37,27.97) 59.11,27.97 59.32,28.18 59.78,28.18 60.86,29.26 61.51,29.26 v1(61.54,29.3)
  L3 w0.127: v1(57.03,15.5) 57.63,14.91 59.16,14.91 59.25,15 63.29,15 66.32,11.96 68.85,11.96 69.82,12.93 72.2,12.93 72.81,12.32 87.74,12.32 88.37,12.32 89.55,11.14 91.43,11.14 93.34,13.05 94.76,13.05 98.29,16.58 100.24,16.58 100.4,16.74 103.07,19.41 103.15,19.41 109.63,25.88 114.37,25.88 115.95,27.47 131.22,27.47 132.49,28.74 138.61,28.74 141.4,31.54 142.04,31.54 143.46,32.96 143.46,34.3 144.37,35.21 144.65,35.21 v1(144.73,35.13)
  BOTTOM w0.102: Q1814.3 59.99,45.49 59.99,44.88 60.34,44.54 RN1803.1 60.32,43.92 59.87,43.92 59.66,43.72 59.66,42.98 58.89,42.2 Q1810.5 58.89,41.22 59.3,40.8 59.96,40.8 60.58,40.18 60.58,38.38 59.9,37.7 59.9,32.73 59.93,32.7 59.93,32.65 60.39,32.19 60.39,31.69 60.6,31.48 60.6,30.84 61.4,30.04 61.4,29.94 61.54,29.8 v1(61.54,29.3) ; v1(144.73,35.13) 144.65,35.21 143.51,35.21 143.18,35.54 Q4001.5
PM_SLP_S4#: length 131.5
  TOP w0.102: PR5114.1 94.94,21.54 94.41,21.54 v1(94.01,21.93) ; PR5105.1 73.2,27.38 v1(72.98,27.59) ; R4055.2 140.93,38.44 140.56,38.08 140.56,37.49 140.69,37.37 140.69,37.36 v1(140.74,37.31) 140.74,37.26 140.8,37.21 140.8,36.73 140.84,36.68 v2(140.84,36.3)
  L3 w0.127: v1(140.74,37.31) 140.69,37.26 140.69,37.15 140.55,37.01 140.55,36.42 140.55,36.01 139.03,34.49 139.03,32.65 139.03,32.27 139.03,32.26 139.03,31.75 137.85,30.57 131.73,30.57 130.46,29.29 115.19,29.29 113.61,27.71 106.69,27.71 105.29,29.11 99.25,29.11 98.1,27.96 98.1,25.41 98.1,25.41 98.1,24.86 96.36,23.11 96.36,22.6 95.34,21.58 94.37,21.58 v1(94.01,21.93) 93.65,21.57 93.65,20.2 93.22,19.77 72.7,19.77 70.92,21.55 67.72,21.55 v1(66.16,23.11) ; v1(72.98,27.59) 72.64,27.25 71.83,27.25 71.4,27.68 70.99,27.68 69.64,26.33 69.18,26.33 68.38,27.14 65.72,27.14 v1(65.19,26.61)
  BOTTOM w0.102: v1(66.16,23.11) 65.64,22.6 65.09,22.6 64.66,23.03 64.66,23.59 64.38,23.87 U2401.21 64.38,26.1 64.52,26.24 64.82,26.24 v1(65.19,26.61) 64.67,27.13 63.67,27.13 63.52,26.98 62.88,26.98 61.93,27.93 61.93,29.08 61.98,29.12 61.98,29.69 61.63,30.04 61.63,30.14 60.83,30.93 60.83,31.57 60.62,31.79 60.62,32.33 60.17,32.77 60.17,32.78 60.13,32.82 60.13,37.61 60.81,38.28 60.81,40.36 Q1810.6 59.54,42.19 60.34,42.99 RN1803.2
PM_SLP_S4#_CPU: length 21.2
  TOP w0.102: v1(58.45,52.21) 58.45,52.6 v2(58.68,52.84)
  L4 w0.127: v1(58.45,52.21) 58.23,52.42 57.41,52.42 56.64,51.66 56.64,49.49 57.07,49.06 57.07,45.44 57.53,44.98 57.53,44.87 57.77,44.63 v1(57.77,44.47)
  BOTTOM w0.102: 64.26,50.64 63.99,50.64 63.8,50.45 63.56,50.45 63.47,50.54 62.29,50.54 61.99,50.85 61.06,50.85 60.11,51.8 58.86,51.8 v1(58.45,52.21) ; v1(57.77,44.47) 57.9,44.59 58.12,44.59 60.11,46.58 60.53,46.58 Q1814.2
PM_SLP_S4#_CPU_D: length 142.4
  TOP w0.102: v1(70.82,26.1) 70.82,26.42 69.63,27.61 63.76,27.61 63.48,27.9 62.88,27.9 62.14,27.16 62.14,27.13 61.95,26.95 v1(61.95,26.75)
  L3 w0.127: v1(70.82,26.1) 71.1,26.38 73.14,26.38 74.17,25.34 74.17,22.08 75.12,21.14 88.49,21.14 89.55,22.21 91.54,22.21 93.82,24.49 95.79,24.49 96.73,25.42 96.73,28.74 98.47,30.48 105.86,30.48 107.2,29.14 113.02,29.14 113.91,30.03 130.15,30.03 131.43,31.31 137.53,31.31 138.28,32.05 138.28,34.82 139.68,36.23 139.68,41.51 v1(141.63,43.45)
  BOTTOM w0.102: v1(141.63,43.45) 141.63,43.67 141.63,43.67 141.63,44.03 141.63,44.03 141.63,46.66 140.44,47.86 137.8,47.86 Q4017.G ; Q1814.6 60.24,47.79 60.24,47.25 58.29,45.3 57.51,45.3 55.55,43.34 55.55,40.79 v2(55.75,40.59) 55.78,40.59 56.6,39.77 R1830.1 56.95,38.97 58.51,38.97 58.63,39.1 58.63,39.12 58.89,39.37 Q1810.2 58.89,40.11 59.21,40.43 59.81,40.43 60.17,40.07 60.17,38.46 59.67,37.97 59.67,32.63 59.7,32.61 59.7,32.55 60.16,32.1 60.16,31.6 60.38,31.38 60.38,29.84 61.7,28.52 61.7,27.69 61.95,27.44 v1(61.95,26.75)
PM_SUS_STAT#_CPU: length 3.9
  TOP w0.102: v2(65.13,51.54) 65.13,51.01 v1(65.19,50.95) 65.19,50.32 64.3,49.43 R1808.1
  BOTTOM w0.102: v1(65.19,50.95) 65.19,50.56 65.36,50.38
PMC_BATLOW#: length 4.8
  TOP w0.102: v1(62.36,49.22) 62.63,48.95 v2(62.63,48.62) 62.2,48.2 R1839.2
  BOTTOM w0.102: CPU1.C14 64.75,49.76 64.24,49.76 64.15,49.85 63.34,49.85 62.98,49.49 62.63,49.49 v1(62.36,49.22)
PMC_RSTBTN#: length 10.9
  BOTTOM w0.102: CPU1.AF2 68.56,62.35 68.3,62.62 68.3,64.28 71.9,67.88 71.9,69.07 v2(71.66,69.31) 71.42,69.31 R1825.2 70.7,70.02 70.7,70.83
PQ3802_1: length 5.6
  TOP w0.102: v1(29.36,67.92) 28.97,67.92 v2(28.81,67.76) 28.79,67.73 PR4302.1 27.9,66.95 PR4311.2
  BOTTOM w0.102: v1(29.36,67.92) 29.46,67.92 29.87,67.51 30.93,67.51 31.29,67.87 PQ4302.B
PQ4008_2: length 8.8
  TOP w0.102: PR4437.2 149.69,14.36 PC4425.1 149.69,16.15 v2(149.93,16.39) 150.11,16.57 v1(150.11,17.62)
  BOTTOM w0.102: PQ4408.2 150.83,21.53 151.25,21.12 151.25,18.81 150.93,18.5 150.93,18.44 v1(150.11,17.62)
PQ4008_6: length 3
  BOTTOM w0.102: PQ4408.6 147.89,22.19 147.57,22.5 147.57,23.38 v2(147.8,23.61) PR4426.1
PQ4209_D: length 4.5
  BOTTOM w0.254: PQ4309.D 30.94,71.64 31.79,72.49 v2(31.79,73.04) 31.79,73.4 31.56,73.63 PR4316.2
PQ4405_2: length 3.5
  BOTTOM w0.102: PQ4410.2 137.1,30.84 137.23,30.96 137.23,31.35 137.37,31.49 v2(137.65,31.49) 138.05,31.49 138.37,31.17 PR4476.2 138.55,31.94 PR4475.2
PQ4405_3: length 2.4
  BOTTOM w0.102: PR4466.1 138.43,30.35 138.05,29.98 v2(137.72,29.98) 137.41,29.98 137.2,30.19 PQ4410.3
PQ4405_5: length 3.9
  BOTTOM w0.102: PQ4410.5 133.35,30.84 PC4434.1 133.07,30.22 PR4470.2 132.17,29.31 v2(132.17,28.69)
PQ4405_6: length 4.1
  BOTTOM w0.102: PR4473.1 134.15,33.02 v2(133.42,33.02) 133.07,32.67 PC4434.2 133.46,31.49 PQ4410.6
PQ4406_D: length 3.8
  BOTTOM w0.102: PR4465.2 140.45,34.44 140.24,34.22 v2(140.24,34.01) 140.24,33.62 141.63,32.24 PQ4414.D
PQ4406_G: length 4.2
  BOTTOM w0.102: PQ4414.G 143.73,33.26 PR4474.1 144.76,34.44 v2(144.81,34.39) 145.5,33.7 PC4433.2
PQ4408_C: length 3.6
  BOTTOM w0.102: v2(140.46,32.72) 140.29,32.89 PR4464.1 138.97,32.89 138.96,32.88 PR4475.1 138.52,33.76 PQ4409.C
PQ4408_E: length 4.4
  BOTTOM w0.102: PR4469.2 140.29,37.13 v2(139.83,37.59) 139.7,37.72 138.62,37.72 PR4467.1 138.38,37.09 139.05,36.42 PQ4409.E
PROCHOT#_CPU: length 39.3
  TOP w0.102: v1(92.29,33.1) 91.23,32.05 90.72,32.05 88.17,29.51 82.5,29.51 79.62,26.62 75.87,26.62 75.8,26.55 73.22,26.55 v2(73.09,26.42) 73.08,26.41 72.68,26.41 72.2,25.92 R1809.2 71.75,25.63 R1860.2
  L3 w0.127: v1(84.43,44.43) 84.43,44.22 85.76,42.89 85.76,41.9 86.77,40.89 86.77,40.16 88.31,38.62 88.31,37.64 92.29,33.66 v1(92.29,33.1)
  BOTTOM w0.102: v1(84.43,44.43) 84.45,44.45 84.45,44.97
PROCHOT#_EC: length 8.6
  TOP w0.102: v1(67.28,26.61) 68.08,25.8 v2(68.08,25.45) 68.08,25.16 66.98,24.05 v1(66.18,24.05)
  BOTTOM w0.102: v1(67.28,26.61) 67.28,27.49 R2442.1 68.74,27.85 Q2402.G ; U2401.24 65.58,24.39 65.92,24.05 v1(66.18,24.05)
PS_ID: length 10.8
  BOTTOM w0.102: PQ4301.S 24.28,63.4 23.67,62.79 21.78,62.79 21.72,62.84 20.75,62.84 20.2,63.4 18.39,63.4 18.15,63.63 18.15,63.7 PR4307.1 17.06,64.17 v2(16.76,63.88)
PS_ID_R: length 17.8
  TOP w0.635: v1(26.87,65.99) 27.03,66.15 PR4311.1 27.07,66.96 EC4307.1
  L4 w0.635: v1(26.87,65.99) 23.47,65.99 21.29,68.17 v1(21.29,73.94)
  BOTTOM w0.406: DCIN1.3 22.5,75.5 22.33,75.32
  BOTTOM w0.635: 22.33,75.32 AFTP4202.1 21.29,74.28 v1(21.29,73.94)
PSID_DISABLE#_R_C: length 6.5
  TOP w0.102: PR4303.2 29.85,63.53 v1(29.52,63.19)
  BOTTOM w0.102: PQ4302.C 30.41,66.49 29.87,65.95 29.87,64.69 29.88,64.67 29.88,63.71 v2(29.87,63.7) 29.87,63.54 v1(29.52,63.19) 29.49,63.16 28.8,63.16 PQ4301.G
PSID_EC: length 101.5
  TOP w0.102: v1(21.64,63.38) 21.57,63.31 PR4306.2
  L3 w0.102: v1(56.4,12.57) 53.66,12.57 52.9,13.34 51.09,13.34 49.94,12.19 48.45,12.19 48.06,11.8 46.24,11.8 45.49,12.55 45.13,12.55 44.38,11.8 43.21,11.8 42.7,11.3 42.04,11.3 42,11.34 41.52,11.34 41.13,10.96 39.16,10.96 38.4,10.19 31.1,10.19 29.59,8.68 28.88,8.68 v1(28.33,9.23) ; v1(22.11,37.78) 22.12,37.77 22.12,36.65 21.83,36.36 21.83,34.35 21.35,33.88 21.35,33.1 21.03,32.79 21.03,28.28 22.75,26.57 22.75,16.4 24.69,14.46 28.28,14.46 v1(28.49,14.67)
  L4 w0.102: v1(22.11,37.78) 22.12,37.79 22.12,40.39 20.56,41.95 20.56,51.02 18.76,52.82 18.76,58.56 18.76,59.55 18.57,59.74 18.57,62.1 v1(18.54,62.13) 18.69,62.28 19.91,62.28 21.01,63.38 v1(21.64,63.38)
  BOTTOM w0.102: U2401.99 55.93,12.11 v1(56.4,12.57) ; v2(22.24,38.4) 22.24,37.91 v1(22.11,37.78) ; PR4307.2 17.68,62.99 v1(18.54,62.13) ; v1(28.49,14.67) 28.81,14.35 28.81,9.72 v1(28.33,9.23) ; PD4303.3 21.67,63.35 v1(21.64,63.38)
PSL_IN1#: length 8.4
  TOP w0.102: v1(64.33,3.92) 64.33,3.85 R2487.2
  BOTTOM w0.102: v1(64.33,3.92) 64.29,3.96 64.29,4.05 64.29,4.05 64.29,6.2 63.73,6.76 63.73,7.44 v2(63.92,7.63) 64.06,7.77 65.12,7.77 65.66,8.32 65.66,8.81 65.58,8.88 U2401.73
PSL_IN2#: length 4
  BOTTOM w0.102: U2401.93 57.58,8.81 57.77,8.62 v2(57.77,7.92) 57.18,7.33 R2489.1 R2488.2
PSL_OUT#: length 6.8
  TOP w0.102: v2(63.4,6.68) 63.4,6.53 63.71,6.22 v1(63.71,6.14) 63.71,5.76 R2493.1
  BOTTOM w0.102: v1(63.71,6.14) 63.5,6.35 63.5,7.77 63.73,8 65.02,8 65.42,8.4 65.42,8.67 65.18,8.9 U2401.74
PU4401_4:
  vias: v2(143.52,30.1)
PU4401_5:
  vias: v2(142.42,27.75)
PU4401_6: length 2.6
  BOTTOM w0.356: v2(145.37,31.13) 145.49,31.01 145.49,30.2 PR4446.2
  BOTTOM w0.381: PU4407.6 144.99,29.71 PR4446.2
PU4902_S5: length 5.8
  TOP w0.254: v1(95.86,22.75) 96.29,22.32 PR5114.2
  BOTTOM w0.254: v2(95.4,23.21) v1(95.86,22.75) 96.31,22.3 PC5119.1 97.42,22.16 98.02,22.76 98.58,22.76 98.67,22.68 PU5102.9
PU4902_VCNTL: length 4.5
  TOP w0.254: PR5117.1 97.34,22.63 v1(97.13,22.84)
  BOTTOM w0.254: v1(97.13,22.84) 96.82,22.84 96.67,22.98 v2(96.67,23.3) 96.76,23.39 PC5111.1 97.87,23.18 PU5102.10
PURE_HW_SHUTDOWN#: length 386.8
  TOP w0.102: v1(149.68,42.42) 149.7,42.44 EC2403.1 149.63,43.22 149.63,43.85 149.64,43.86 149.64,46.32 150.23,46.91 150.23,59.43 150.7,59.9 v1(150.7,60.24) ; v1(50.56,1.89) 50.56,2.4 50.99,2.84 R2405.2 51.91,3.34 52.71,3.34 53.12,2.92 R2603.1
  L3 w0.102: v1(149.94,72.29) 150.1,72.13 151.22,72.13 151.9,72.81 151.9,73.19 153.07,74.36 156.98,74.36 159.53,76.91 171.35,76.91 174.75,80.31 175.41,80.31 175.9,80.79 175.9,82.2 173.9,84.2 173.9,84.9 157.02,101.78 145.4,101.78 145.34,101.83 140.7,101.83 140.45,101.58 140.45,101.16 140.29,101 139,101 v1(138.6,101.4) ; v1(50.56,1.89) 50.52,1.89 50.13,2.29 49.51,2.29 49.5,2.29 48.19,2.29 47.65,1.74 40,1.74 36.71,5.03 25.19,5.03 25.19,5.03 24.99,5.03 16.69,13.33 16.69,25.09 16.1,25.68 16.1,30.62 15.42,31.3 15.42,33.35 13.39,35.38 13.39,37.61 15.44,39.65 15.44,39.68 15.44,43.97 15.84,44.38 15.84,58.22 14.51,59.54 14.51,60.85 14.43,60.93 14.43,62.66 14.43,62.66 14.43,62.75 13.65,63.54 13.65,64.89 12.49,66.05 12.49,67.66 12.49,68.26 13.11,68.88 13.11,77.74 14.58,79.21 14.58,82.1 16.32,83.85 17.64,83.85 18.9,85.11 21.68,85.11 23.61,87.03 37.49,87.03 40.03,89.57 47.19,89.57 48.45,88.31 55.6,88.31 57.39,86.52 58.07,86.52 58.1,86.49 58.99,86.49 59.02,86.52 61.21,86.52 61.81,85.92 68.32,85.92 v1(69.07,86.68) 69.07,89.96 75.68,96.57 79.53,96.57 82.48,99.53 93.1,99.53 94.5,100.93 110.81,100.93 v1(111.03,100.7)
  BOTTOM w0.102: D4001.3 149.26,41.87 149.68,42.3 v1(149.68,42.42) ; v1(138.6,101.4) 138.6,101.35 138.23,100.98 137.62,100.98 137.58,101.01 137.44,101.01 137.06,101.4 124.56,101.4 v2(122.93,99.77) 122.93,98.82 121.79,97.68 114.89,97.68 111.88,100.7 v1(111.03,100.7) ; v1(150.7,60.24) 150.7,60.85 149.5,62.05 149.07,62.05 145.53,65.59 145.53,70 148.04,72.5 149.73,72.5 v1(149.94,72.29) ; Q2603.D 71.93,78.71 72.25,79.02 C2606.1 72.25,79.59 71.57,80.28 71.57,83.6 69.71,85.46 69.71,86.02 69.37,86.37 69.37,86.38 v1(69.07,86.68) ; v1(50.56,1.89) 50.56,2.82 R2404.1 52.24,3.6 Q2401.B
PWR_1D05V_PWR_EN: length 5.7
  TOP w0.102: v1(89.39,89.19) 89.31,89.11 PR5003.1 90.14,88.5 PC5001.1 90.4,88.76 v2(90.4,89.52) PR5004.2
  BOTTOM w0.102: PU5001.11 89.99,88.58 v1(89.39,89.19)
PWR_1D05V_PWR_ILIM: length 3.9
  BOTTOM w0.254: PU5001.13 91.34,86.49 PR5002.1 PR5008.2 v2(91.86,88.79)
PWR_1D8V: length 10.1
  L4 w0.254: v1(34.89,40.47) 34.9,40.47 41.18,40.47 41.52,40.82 41.52,42.12 v1(41.22,42.42)
  BOTTOM w0.508: PC5222.1 35.15,40.21 v1(34.89,40.47) 35.15,40.73 PR5211.2
  vias: v2(40.94,41.84)
PWR_1D8V_FB: length 4.6
  BOTTOM w0.254: v2(33.32,40.26) 33.81,39.77 PC5222.2 PR5211.1 PR5213.2 PU5204.1
PWR_1D8V_PHASE:
  vias: v2(37.08,45.8)
PWR_1D8V_PVDD:
  vias: v2(32.92,43.11)
PWR_1D8V_S5_EN: length 5.5
  BOTTOM w0.102: v2(39.49,41.31) 38.99,41.82 PR5202.2 38.44,41.82 PR5201.2 37.59,41.83 PC5225.1 36.73,42.51 37.1,42.88 37.1,43.5 36.88,43.72 PU5204.7
PWR_1D15V: length 11.2
  BOTTOM w0.254: 42.77,47.8 42.77,47.12 42.29,46.64 36.66,46.64 36.03,46.01 35.4,46.01 35.37,45.99 35.37,45.98 35.36,45.98 34.92,45.98 34.56,46.34 PC5017.1 PR5011.1
  vias: v2(42.8,48.34)
PWR_1D15V_FB: length 4.4
  BOTTOM w0.254: PR5011.2 33.75,49.16 33.91,49.31 PU5002.1 ; PR5011.2 PC5017.2 PR5010.1 ; PR5011.2 33.27,48.08 v2(32.84,47.65)
PWR_1D15V_PG: length 23.8
  TOP w0.102: v1(33.32,39.12) 33.32,47.43 PR5012.2 33.4,47.68 v1(32.64,48.45)
  BOTTOM w0.102: v1(32.64,48.45) 32.64,48.81 33.64,49.81 PU5002.2 ; v1(33.32,39.12) 33.67,38.76 v2(38.01,38.76) 38.45,39.21 PR5202.1 39.02,40.93 40.48,39.46 PR5417.1
PWR_1D15V_PHASE:
  vias: v2(37.95,47.6)
PWR_1D15V_PVDD:
  vias: v2(29.66,49.57)
PWR_1D15V_S5_EN: length 4.9
  TOP w0.102: PR5009.2 35.89,48.11 v1(36.08,48.3) 36.12,48.34 v2(36.12,49.06)
  BOTTOM w0.102: v1(36.08,48.3) 36.29,48.08 PC5000.1 37.2,48.26 37.2,49.56 36.95,49.81 PU5002.7
PWR_1D24V:
  vias: v2(50.6,43.49)
PWR_1D24V_EN: length 4.2
  BOTTOM w0.102: v2(41.47,38.57) PR5417.2 42.39,38.57 PC5427.1 PR5401.1 45.28,38.57 PU5402.8
PWR_1D24V_FB\: length 6.4
  BOTTOM w0.254: PU5402.2 46.81,44.83 46.6,45.04 45.18,45.04 44.83,45.38 PR5419.2 PC5405.2 PR5420.1 44.68,47.4 44.27,46.99 v2(43.69,46.99)
PWR_1D35V_BOOT:
  vias: v2(79.81,23.6) v3(80.52,23.6)
PWR_1D35V_BOOT_R:
  vias: v2(82.96,24.68)
PWR_1D35V_BYP: length 4.8
  BOTTOM w0.254: PU5101.15 79.68,27.61 79.35,27.94 79.35,28.46 PR5102.1 PC5110.1 78.04,28.72 v2(77.14,29.62)
PWR_1D35V_EN: length 5.8
  TOP w0.102: PR5105.2 75.36,27.38 v1(75.53,27.21)
  BOTTOM w0.102: v1(75.53,27.21) 75.51,27.21 75.29,27.43 v2(74.89,27.43) 74.89,26.54 PC5138.1 76.07,26.3 76.31,26.54 PU5101.11
PWR_1D35V_IMAX: length 6.5
  BOTTOM w0.254: PR5106.2 v2(74.77,28.66) 74.9,28.66 76.4,27.15 76.96,27.15 77.18,27.38 78.67,27.38 78.78,27.26 PU5101.13
PWR_1D35V_LDO_P5: length 4.4
  BOTTOM w0.254: PU5101.17 80.83,25.57 81.07,25.81 81.07,27.39 v2(80.57,27.89) 80.24,28.22 PC5113.1
PWR_1D35V_PGOOD: length 2.6
  TOP w0.102: v2(76.41,25.08) 76.41,25.57 v1(76.27,25.71) 76.27,25.71 75.67,25.71 PR5107.2
  BOTTOM w0.102: PU5101.9 76.42,25.57 v1(76.27,25.71)
PWR_1D35V_PHASE: length 8.3
  L4 w0.508: v3(76.83,23.53) 78.95,23.53 79.97,24.55 84.48,24.55 v3(84.62,24.41)
  vias: v2(85.33,24.36)
PWR_1D35V_VFB: length 8.9
  TOP w0.254: v1(75.43,29.9) 75.43,29.88 74.68,29.12 PR5103.2 PC5112.2 74.63,28.18 PR5104.1
  BOTTOM w0.254: PU5101.14 79.23,27.37 78.56,28.04 77.14,28.04 76.81,28.37 76.48,28.37 v2(76.1,28.75) 75.43,29.42 v1(75.43,29.9)
PWR_3D3V_BOOT: length 1.9
  TOP w0.508: v2(38.56,31.68) 38.51,31.72 v1(38.51,32.31) 39.09,32.88 PR4501.1
PWR_3D3V_BOOT_A: length 2.3
  TOP w0.508: v2(35.61,32.47) 35.74,32.61 PC4506.1 37.2,33.27 PR4501.2
PWR_3D3V_EN: length 3.8
  TOP w0.102: RN4501.2 47.35,18.8 PR4514.2 47.35,19.26 47.59,19.5 47.59,19.51 47.7,19.62 47.71,19.62 48.17,20.08 v2(48.22,20.08) PR4510.1
PWR_3D3V_EN1: length 14.8
  TOP w0.102: PR4510.2 v2(48.22,22.92) 48.22,23.45 48.06,23.61 48.06,25.18 48.01,25.23 48.01,26.84 v1(48.2,27.03) ; v1(41.47,27.84) 41.48,27.85 PR4518.1
  BOTTOM w0.102: v1(48.2,27.03) 44.45,27.03 44.25,27.23 PC4508.1 PC4530.1 41.78,27.23 41.47,27.54 v1(41.47,27.84) 41.31,27.84 40.88,28.27 PU4502.12
PWR_3D3V_EN2: length 5.8
  BOTTOM w0.254: PU4502.11 41.9,28.96 42.64,28.22 v2(43.46,28.22) 43.76,27.92 44.56,27.92 PR4517.1 PC4538.1 PR4515.2
PWR_3D3V_FB: length 3
  BOTTOM w0.254: v2(41.68,26.75) 41.27,26.75 PC4525.1 40.78,27.75 40.43,28.1 PU4502.13
PWR_3D3V_FB2: length 1.9
  BOTTOM w0.254: PC4525.2 PR4506.2 39.5,25.9 v2(39.08,25.9)
PWR_3D3V_LDO:
  vias: v2(38.48,28.17) v3(38.86,27.38)
PWR_3D3V_PH: length 6.5
  TOP w0.508: PC4506.2 36.61,31.64 v3(37.29,31.64)
  L4 w0.508: v3(37.29,31.64) 37.31,31.62 v3(42.94,31.62)
  vias: v2(36.99,29.24)
PWR_3D3V_VOUT: length 20.5
  TOP w0.254: v2(40.12,26.82) 39.45,26.82 39.38,26.75 v1(39.27,26.75)
  L3 w0.254: v1(39.27,26.75) 39.12,26.6 37.17,26.6 36.54,25.97 29.88,25.97 29.13,26.72 24.92,26.72 24.18,25.99 v1(24.18,25.93)
  BOTTOM w0.254: v1(39.27,26.75) 39.27,26.93 39.58,27.24 PR4506.1 40.03,27.24 40.03,27.84 39.98,27.89 PU4502.14 ; PG4535.2 v1(24.18,25.93)
PWR_3V_PG: length 8.2
  BOTTOM w0.102: v2(46.8,30.62) 46.8,30.52 47.38,29.94 PR4504.2 47.33,29.7 45.99,29.7 PR4534.2 45.32,29.02 43.93,29.02 43.48,28.57 43.31,28.57 42.92,28.57 42.62,28.88 42.62,29.76 42.44,29.93 PU4502.9
PWR_5V_BOOT: length 2.1
  TOP w0.508: v1(40.3,22.71) 40.78,23.19 PR4502.1 40.79,23.64 41.67,23.64 41.68,23.65 v2(41.71,23.65)
PWR_5V_BOOT_A: length 2.2
  TOP w0.508: v2(37.28,23.5) 37.56,23.78 PC4521.1 39.1,23.78 PR4502.2
PWR_5V_EN1: length 9.2
  TOP w0.102: PR4516.1 48.36,17.44 v1(48.57,17.65) 48.74,17.82 PR4511.2
  BOTTOM w0.102: v1(48.57,17.65) 48.23,17.31 v2(47.93,17.31) 47.48,17.31 47.3,17.5 PC4507.1 46.92,17.49 PC4531.1 45.51,17.49 44.68,18.32 43.4,18.32 43.31,18.24 42.42,18.24 42.19,18.46 PU4503.12
PWR_5V_EN2: length 7.4
  BOTTOM w0.254: PR4512.2 47.76,19.27 PR4513.1 PC4534.1 47.44,18.03 45.71,18.03 v2(45.17,18.57) 44.7,19.04 PU4503.11
PWR_5V_FB: length 4.1
  TOP w0.254: PC4526.1 42.89,16.84 43.11,17.07 v2(43.11,17.49) 42.88,17.72 42.41,17.72 v1(42.26,17.57)
  BOTTOM w0.254: PU4503.13 41.74,18.17 42.26,17.65 v1(42.26,17.57)
PWR_5V_FB_A: length 2
  TOP w0.254: PC4526.2 PR4507.2 41.44,15.47 v2(40.98,15.01)
PWR_5V_LDO: length 4.9
  BOTTOM w0.254: v2(43.45,16.58) PG4525.2 41.09,16.58 PC4520.1 40.84,16.82 PU4503.15
PWR_5V_PG: length 2.8
  TOP w0.102: v2(43.88,19.43) 43.88,19.51 v1(44.25,19.88) 44.32,19.8 PG4534.2
  BOTTOM w0.102: v1(44.25,19.88) 44.11,20.02 PU4503.9
PWR_5V_PH: length 6.1
  TOP w0.508: v3(39.17,21.88) 38.21,22.84 PC4521.2
  L4 w1.016: v3(43.63,21.99) 43.35,21.71 39.35,21.71 v3(39.17,21.88)
  vias: v2(38.86,22.73)
PWR_5V_VCC: length 4.1
  BOTTOM w0.254: 39.1,19.65 39.47,20.02 PU4503.17
  BOTTOM w0.508: v2(37.13,17.86) 37.13,17.96 38.31,19.13 PC4524.1 39.1,19.65
PWR_5V_VOUT: length 23.3
  TOP w0.254: PR4507.1 40.73,16.84 40.57,17.01 40.57,17.3 v2(40.57,17.31) 40.99,17.73 41.36,17.73 v1(41.51,17.58)
  L3 w0.254: v1(41.51,17.58) 41.23,17.3 32.69,17.3 32.33,16.94 24.44,16.94 v1(23.63,16.14)
  BOTTOM w0.254: PG4521.2 v1(23.63,16.14) ; v1(41.51,17.58) 41.51,17.76 41.29,17.98 PU4503.14
PWR_CHG_ACDET: length 5.6
  TOP w0.254: PR4407.2 127.93,10.04 v2(128.74,10.04) v1(129.48,10.04) 129.98,10.54 131.06,10.54 PU4404.6
  BOTTOM w0.254: PR4431.1 PC4412.1 v1(129.48,10.04)
PWR_CHG_ACN: length 31.5
  TOP w0.254: PU4404.1 130.3,13.13 129.01,14.42 v1(128.94,14.42) 128.23,14.42 PC4402.2 126.8,15.03 PR4406.1 126.24,15.03 v2(125.72,15.55)
  L3 w0.254: v1(146.75,23.66) 146.75,23.38 146.33,22.97 145.53,22.97 138.96,16.4 137.54,16.4 136.19,15.05 136.19,14.44 135.5,13.75 135.5,13.16 134.86,12.52 134.57,12.52 133.39,13.7 129.73,13.7 129,14.42 v1(128.94,14.42)
  BOTTOM w0.254: PC4403.1 128.67,14.69 v1(128.94,14.42) ; PG4403.2 146.73,23.65 v1(146.75,23.66)
PWR_CHG_ACOK: length 30
  L3 w0.254: v1(150.35,27.6) 150.8,27.15 150.8,26.33 150.95,26.18 150.95,20.53 150.55,20.12 150.55,20.09 v1(150.14,19.69)
  BOTTOM w0.254: PR4476.1 142.02,31.17 142.77,31.93 144.63,31.93 144.79,31.77 146.88,31.77 147.2,31.45 147.2,29.69 147.64,29.25 147.64,29.16 v2(147.69,29.11) 148.25,29.11 148.46,28.9 148.46,28.88 148.72,28.62 148.72,28.44 149,28.15 149.8,28.15 v1(150.35,27.6) 150.8,27.15 150.8,26.59 150.52,26.31 PQ4402.2 ; v1(150.14,19.69) 150.05,19.6 PR4419.2 148.62,18.74 PR4428.2 148.55,19.57 PR4436.1 148.64,19.68 148.64,19.96 149.56,20.88 PQ4408.3
PWR_CHG_ACP: length 32.6
  TOP w0.254: PU4404.2 129.95,12.63 129.62,12.95 129.62,13.06 128.92,13.75 v1(128.92,13.78) 127.99,13.78 PC4402.1 PR4406.2 125.86,14.14 v2(125.72,14.28)
  L3 w0.254: v1(146.73,21.91) 146.64,21.91 146.72,21.99 146.72,22.31 146.45,22.59 145.68,22.59 139.09,15.99 137.67,15.99 136.57,14.89 136.57,14.28 135.88,13.59 135.88,13 135.02,12.14 134.41,12.14 133.23,13.32 129.39,13.32 v1(128.92,13.78)
  BOTTOM w0.254: PG4402.2 146.72,21.92 v1(146.73,21.91) ; v1(128.92,13.78) 128.73,13.78 127.4,15.1 PC4404.1
PWR_CHG_AD_OFF: length 129
  TOP w0.254: v1(47.17,35.3) 46.76,35.3 v2(46.58,35.48) 46.58,38.25 v1(43.98,40.84) ; PR4312.1 29.96,67.01 v1(29.96,68.18)
  L3 w0.254: v1(57.12,56.48) 57.27,56.48 59.89,59.09 59.89,59.37 60.06,59.54 60.06,63.38 61.36,64.69 61.36,66.6 v1(60.85,67.11) ; v1(49.15,27.69) 49.15,27.59 50.09,26.65 53.6,26.65 54.2,27.24 58.84,27.24 v1(59.44,26.64) ; v1(29.96,68.18) 29.97,68.19 29.97,71.05 29.98,71.06 29.98,74.34 30.09,74.45 30.09,75.58 29.36,76.3 29.36,79.05 29.84,79.52 32.99,79.52 33.5,80.03 43.87,80.03 46.24,77.66 49.81,77.66 50.33,78.19 57.3,78.19 v1(57.74,77.75)
  L4 w0.254: v1(61.26,76.99) 61.44,76.81 61.44,67.43 61.13,67.11 v1(60.85,67.11) ; v1(48.62,52.78) 48.14,52.3 47.2,52.3 45.63,50.73 45.42,50.73 45,50.3 45,48.8 46.26,47.54 46.26,41.87 45.23,40.84 v1(43.98,40.84)
  BOTTOM w0.203: U2401.11 60.38,26.01 59.75,26.64 v1(59.44,26.64)
  BOTTOM w0.254: v1(47.17,35.3) 47.17,34.53 47.24,34.45 47.24,30.76 48.01,30 48.01,29.63 49.02,28.62 49.02,27.82 v1(49.15,27.69) ; v1(61.26,76.99) 60.94,77.32 58.27,77.32 57.83,77.75 v1(57.74,77.75) ; v1(29.96,68.18) 30.38,68.18 31.01,68.8 PQ4309.G ; v1(48.62,52.78) 49.38,53.55 50.06,53.55 50.34,53.82 50.34,54.32 51.37,55.35 51.37,55.97 51.85,56.45 52.94,56.45 53.11,56.61 56.99,56.61 v1(57.12,56.48)
PWR_CHG_AD_OFF_R: length 10.7
  TOP w0.254: PR4312.2 28.08,66.11 28.6,66.64 v1(28.6,66.81)
  BOTTOM w0.254: v1(28.6,66.81) 28.59,66.81 28.38,66.6 26.1,66.6 25.3,65.8 v2(24.94,65.8) 24.55,65.8 24.31,65.55 22.09,65.55 20.94,66.7 20.32,66.7 PQ4304.1
PWR_CHG_BAT_SCL: length 3.3
  TOP w0.102: v2(133.86,7.67) 133.63,7.9 133.63,8.54 133.27,8.9 PG4407.1 132.89,9.41 132.77,9.53 PU4404.9
PWR_CHG_BAT_SDA: length 2.7
  TOP w0.102: PU4404.8 132.27,9.64 131.98,9.35 PG4408.1 131.19,8.9 v2(130.94,9.15)
PWR_CHG_BTST: length 2.8
  TOP w0.254: v1(133.42,14.92) 133.19,14.69 132.97,14.69 132.77,14.49 PU4404.17
  BOTTOM w0.254: PR4409.1 133.32,15.02 v1(133.42,14.92) 133.42,14.67 v2(133.14,14.39)
PWR_CHG_BTST_R: length 6.2
  TOP w0.508: v1(136.11,15.98) 136.11,16.12 136.17,16.18 PD4401.K
  BOTTOM w0.508: v1(136.11,15.98) 136.1,15.97 v2(135.09,15.97) 134.93,15.97 133.77,17.13 PR4409.2 132.03,17.13 PC4411.1
PWR_CHG_CMPIN: length 18.1
  TOP w0.254: PU4404.4 129.57,11.63 129.11,11.16 v1(129.03,11.16) 128.89,11.3 128.89,11.92 128.58,12.23 PR4414.2 127.72,11.71 PR4411.2
  L3 w0.254: v1(134.33,8.01) 134.01,8.01 132.19,9.84 132.13,9.84 132.01,9.95 131.65,9.95 130.44,11.16 v1(129.03,11.16)
  BOTTOM w0.254: PR4413.1 129.37,12.2 129.03,11.86 v1(129.03,11.16) ; PR4427.2 135.76,6.46 PR4429.1 133.89,6.46 133.71,6.28 133.22,6.28 v2(133.02,6.48) 132.87,6.63 132.87,7.06 133.39,7.58 133.61,7.58 134.04,8.01 v1(134.33,8.01)
PWR_CHG_CMPIN_R: length 2.4
  BOTTOM w0.254: v2(134.01,7.24) 134.12,7.35 PR4429.2 135.05,7.48 PQ4407.3
PWR_CHG_CMPIN_RR: length 6
  BOTTOM w0.254: PR4427.1 136.84,7.35 137.86,8.37 v2(137.86,9.65) 137.7,9.81 136.61,9.81 136.35,10.07 PQ4407.6
PWR_CHG_CMPOUT: length 31.8
  TOP w0.254: PU4404.3 129.54,12.13 128.97,12.7 v1(128.96,12.7) 128.54,13.12 PR4414.1 127.82,13.12 PR4430.2 127.11,12.43 PR4438.1 125.68,13.26 PR4432.1 ; v2(147.03,13.7) 147.34,14.01 v1(147.74,14.01) 148.46,14.01 PR4437.1
  L4 w0.254: v1(128.96,12.7) 129.39,12.7 130.08,13.4 133.26,13.4 134.68,11.97 137.17,11.97 v1(137.34,12.14)
  BOTTOM w0.254: v1(137.34,12.14) 137.6,11.88 137.6,11.31 138.75,10.16 145.4,10.16 147.74,12.49 v1(147.74,14.01)
PWR_CHG_CSON_1: length 25.8
  TOP w0.254: v1(137.14,12.94) 137.14,12.89 136.67,12.41 PR4420.2 ; v2(121.86,18.02) 122.18,18.33 v1(122.18,19.3)
  L3 w0.254: v1(122.18,19.3) 122.23,19.26 122.23,18.42 127.24,13.41 127.24,12.99 128.55,11.68 130.64,11.68 131.85,10.47 134.79,10.47 136.9,12.58 136.9,12.69 v1(137.14,12.94)
  BOTTOM w0.254: PG4410.1 121.76,19.72 v1(122.18,19.3) ; v1(137.14,12.94) 137.08,12.94 136.87,12.74 136.87,12.42 PC4421.2 135.56,11.88 PC4423.1
PWR_CHG_CSOP_1: length 26
  TOP w0.254: v2(123.13,18.02) 122.98,18.17 v1(122.98,19.32) ; PR4421.2 136.7,13.3 136.76,13.36 136.76,13.36 136.86,13.46 v1(137.62,13.46)
  L3 w0.254: v1(122.98,19.32) 122.98,18.21 127.62,13.57 127.62,13.33 128.76,12.19 130.85,12.19 132.06,10.98 134.58,10.98 136.39,12.79 136.39,12.97 136.88,13.46 v1(137.62,13.46)
  BOTTOM w0.254: v1(122.98,19.32) 123.49,19.83 PG4409.1 ; v1(137.62,13.46) 136.86,13.46 136.36,12.97 136.36,12.8 PC4421.1 135.63,12.76 PC4420.1
PWR_CHG_HIDRV: length 14.9
  TOP w0.305: PU4404.18 132.27,14.81 132.44,14.98 v3(132.44,15.02)
  TOP w0.356: v3(134.85,24.28) v2(135.77,24.28)
  TOP w0.508: PC4413.2 133.09,15.63 132.54,15.08 132.5,15.08 v3(132.44,15.02)
  L4 w1.016: v3(134.85,24.28) 134.85,23.92 132.44,21.51 v3(132.44,15.02)
  BOTTOM w0.381: v3(134.85,24.28) 134.89,24.24 PU4405.1
PWR_CHG_IFAULT: length 3.7
  TOP w0.254: v2(137.39,11.58) 137.09,11.58 136.83,11.84 136.15,11.84 135.61,11.31 PR4418.2 135.42,11.13 PU4404.11
PWR_CHG_ILIM: length 3.5
  TOP w0.254: PU4404.10 133.27,9.88 133.57,9.58 v1(133.57,9.49) 133.57,9.39 PR4417.2
  BOTTOM w0.254: v2(132.83,8.97) 133.04,8.97 v1(133.57,9.49) PR4423.1
PWR_CHG_IOUT: length 14.9
  TOP w0.254: PR4411.1 126.58,11.65 v1(126.09,11.65) ; PR4422.1 v2(127.69,9.37) 128.42,9.37 128.55,9.5 129.73,9.5 130.19,9.96 v1(130.47,9.96) 130.86,9.58 131.58,9.58 131.77,9.77 PU4404.7
  L3 w0.254: v1(126.09,11.65) 126.15,11.59 126.32,11.59 127.81,10.1 128.54,10.1 129.04,10.59 129.84,10.59 v1(130.47,9.96)
  BOTTOM w0.254: v1(130.47,9.96) 130.56,9.87 PC4422.1 131.98,9.87 PR4424.1
PWR_CHG_LODRV: length 5.8
  TOP w0.356: v3(134.32,19.12) v2(133.36,19.12)
  L4 w1.016: v3(134.93,14.5) 134.34,15.09 134.34,19.09 v3(134.32,19.12)
PWR_CHG_PHASE: length 14.8
  TOP w0.305: PU4404.19 131.77,14.51 v3(131.27,15.01)
  TOP w0.356: v3(133.63,24.39) v2(132.65,24.39)
  TOP w0.508: PC4413.1 131.76,15.52 131.27,15.03 v3(131.27,15.01)
  L4 w1.016: v3(133.63,24.39) 131.27,22.03 v3(131.27,15.01)
  BOTTOM w0.508: v3(131.27,15.01) 131.54,15.28 PC4411.2
PWR_CHG_REGN: length 35.5
  TOP w0.254: PU4404.16 134.49,15.14 PC4407.1 135.24,15.51 135.48,15.27 135.48,14.9 135.74,14.63 PD4401.A 136.68,14.63 137.17,15.13 v1(137.52,15.13) 140.64,15.13 141.74,14.02 142.56,14.02 143.69,15.15 143.69,18.28 v2(144.37,18.96) 145.12,19.7 v1(145.67,19.7) ; v1(126.45,13.4) 126.54,13.31 PR4430.1
  L4 w0.254: v1(137.52,15.13) 136.91,14.51 136.76,14.51 135.46,13.22 135.46,13.14 135.17,12.84 134.74,12.84 133.68,13.9 129.86,13.9 129.18,13.22 126.63,13.22 v1(126.45,13.4)
  BOTTOM w0.254: v1(145.67,19.7) 146.63,18.74 PR4428.1 ; v1(126.45,13.4) 126.47,13.38 PR4425.1
PWR_CHG_SRN: length 2
  TOP w0.254: PU4404.12 135.02,11.63 PR4420.1
PWR_CHG_SRP: length 4.7
  TOP w0.254: PU4404.13 134.85,12.13 135.23,12.5 135.23,12.89 PR4421.1 136.21,13.87 136.55,13.87 136.97,14.29 v2(137.67,14.29)
PWR_CHG_VCC:
  vias: v2(130.3,15.32)
PWR_DCBATOUT_1D35V:
  vias: v2(77.28,21.08)
PWR_GFX_ISEN1N: length 26
  TOP w0.254: PR4824.1 33.43,83.86 34.84,83.86 35.21,84.23 36.71,84.23 ; 36.71,84.23 v2(36.71,84.14) ; 36.71,84.23 39.79,84.23 41.11,82.91 43.4,82.91 49.81,76.5 49.81,74.71 50.71,73.81 v1(50.93,73.81)
  BOTTOM w0.254: v1(50.93,73.81) 50.93,72.06 PG4801.1
PWR_GFX_ISEN1P: length 26.9
  TOP w0.254: 39.46,84.61 39.95,84.61 41.27,83.29 43.55,83.29 50.19,76.65 50.19,75.01 50.37,74.83 v1(50.73,74.83) ; 39.46,84.61 v2(39.46,84.7) ; 39.46,84.61 35.05,84.61 34.69,84.24 34.22,84.24 PR4832.2
  BOTTOM w0.254: v1(50.73,74.83) 50.37,74.83 49.91,74.36 49.91,73.37 50.55,72.73 50.55,72.11 PG4802.1
PWR_GFX_RGND_1: length 2.8
  TOP w0.254: PR4835.2 PC4815.1 27.84,72.12 PC4839.1 27.53,71.81 PR4808.2
PWR_GFX_SEN_1: length 1.9
  TOP w0.254: PR4809.2 28.49,71.2 PC4834.1 28.66,72.09 PR4836.2
PWR_GFX_SNUB: length 1.1
  BOTTOM w0.508: PR4847.2 PC4817.1
PWR_GFX_VRHOT#: length 7.2
  TOP w0.102: PR4807.1 30.7,69.71 PR4814.2 30.43,70.67 30.43,71.87 PR4816.2 30.92,72.36 30.92,73.99 30.09,74.82 v2(30.09,74.91) PU4802.2
PWR_VCC0_BT:
  vias: v2(31.45,59.36)
PWR_VCC0_BTR:
  vias: v2(34.87,59.21)
PWR_VCC0_COMP: length 4.7
  TOP w0.254: PC4613.1 24.09,54.03 v1(23.66,54.46)
  BOTTOM w0.203: 25.8,56.32 25.93,56.45 PU4601.23
  BOTTOM w0.254: 25.8,56.32 v2(25.4,56.32) 24.99,55.91 24.99,55.44 PC4602.1 24.03,54.48 23.67,54.48 v1(23.66,54.46)
PWR_VCC0_COMP1: length 0.8
  TOP w0.254: PC4601.2 22.91,55.33 PR4603.1
PWR_VCC0_COMP2: length 2
  TOP w0.254: PC4613.2 23.76,53.62 PR4616.1 23.43,53.15 23.22,52.94 23.22,52.71 v2(23.21,52.71)
PWR_VCC0_CSCOMP: length 39.3
  L4 w0.254: v1(48.86,55.77) 48.86,55.64 47.77,54.55 44.46,54.55 44.19,54.28 42.13,54.28 41.05,53.19 37.79,53.19 34.86,50.26 32.03,50.26 30.99,49.23 29.79,49.23 29.29,48.72 29.29,48.3 29.58,48 29.66,48 v1(29.8,47.87)
  BOTTOM w0.203: PC4612.2 26.36,53.45 27.11,54.2 27.17,54.2 27.62,54.65 27.97,55.01 PU4601.19
  BOTTOM w0.254: v1(48.86,55.77) 48.86,55.78 49.17,56.09 49.17,57.08 PR4648.1 ; v1(29.8,47.87) 29.72,47.87 29.46,48.13 29.42,48.13 29.1,48.45 29.1,48.45 29.03,48.51 27.93,48.51 27.7,48.7 25.32,48.7 v2(24.65,49.37) 24.35,49.67 24.35,50.95 24.68,51.27 PR4606.2 25.17,51.72 PR4168.2 25.87,52.43 PC4607.2 PC4612.2
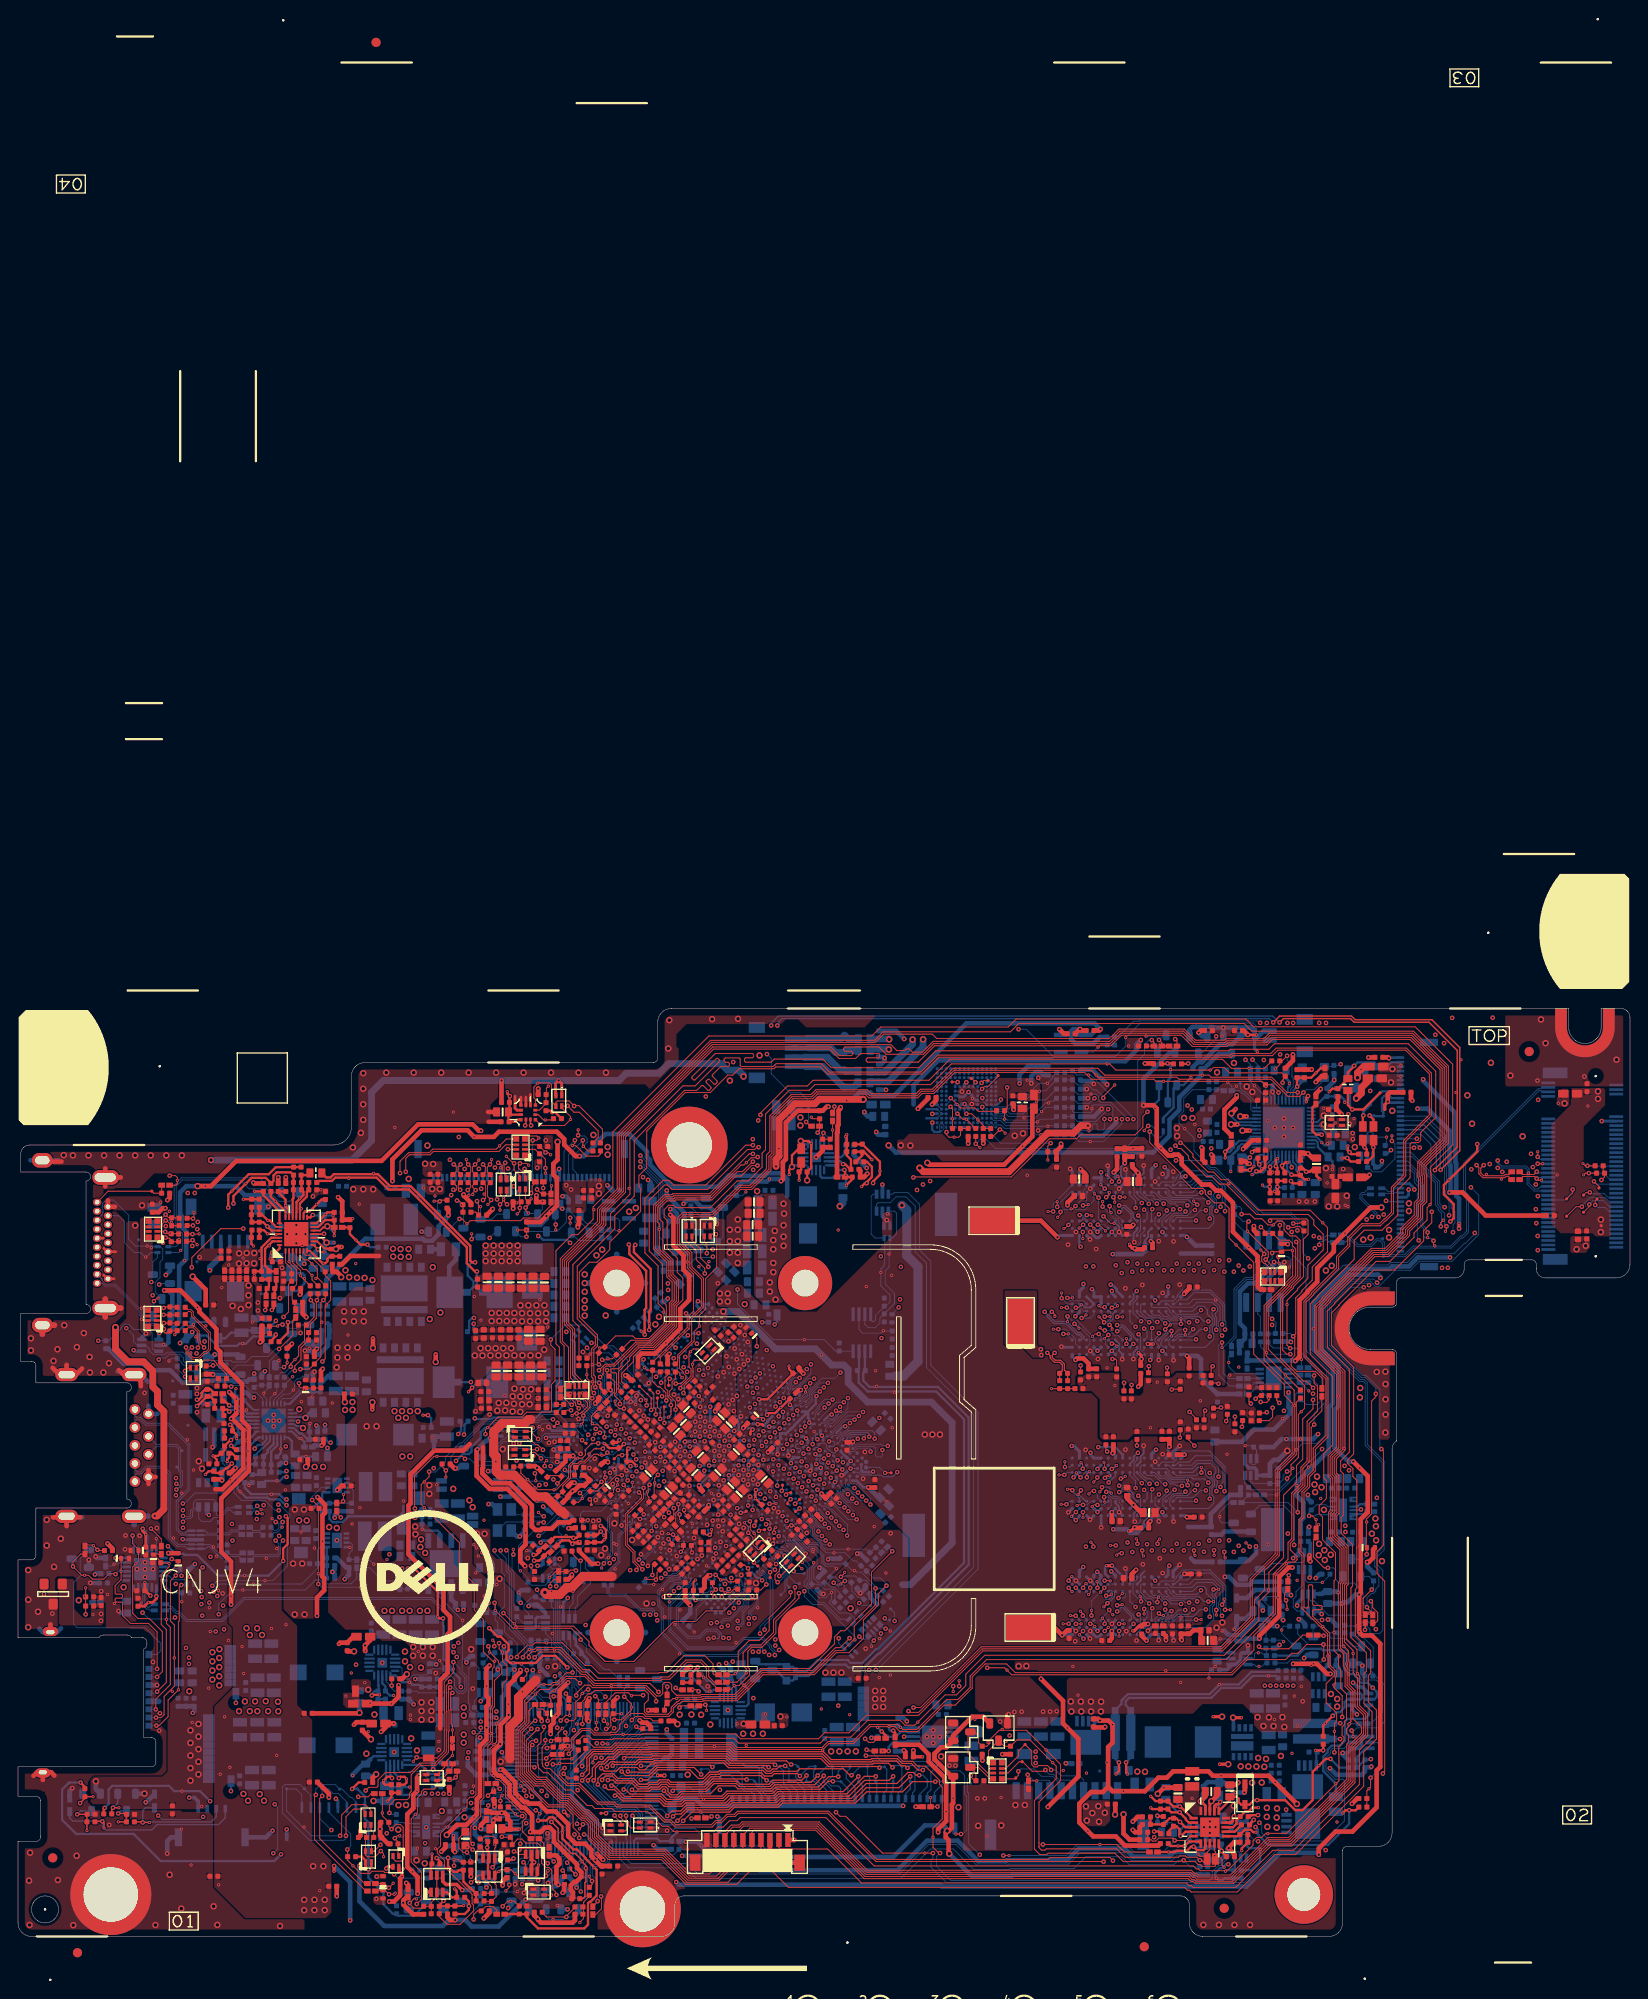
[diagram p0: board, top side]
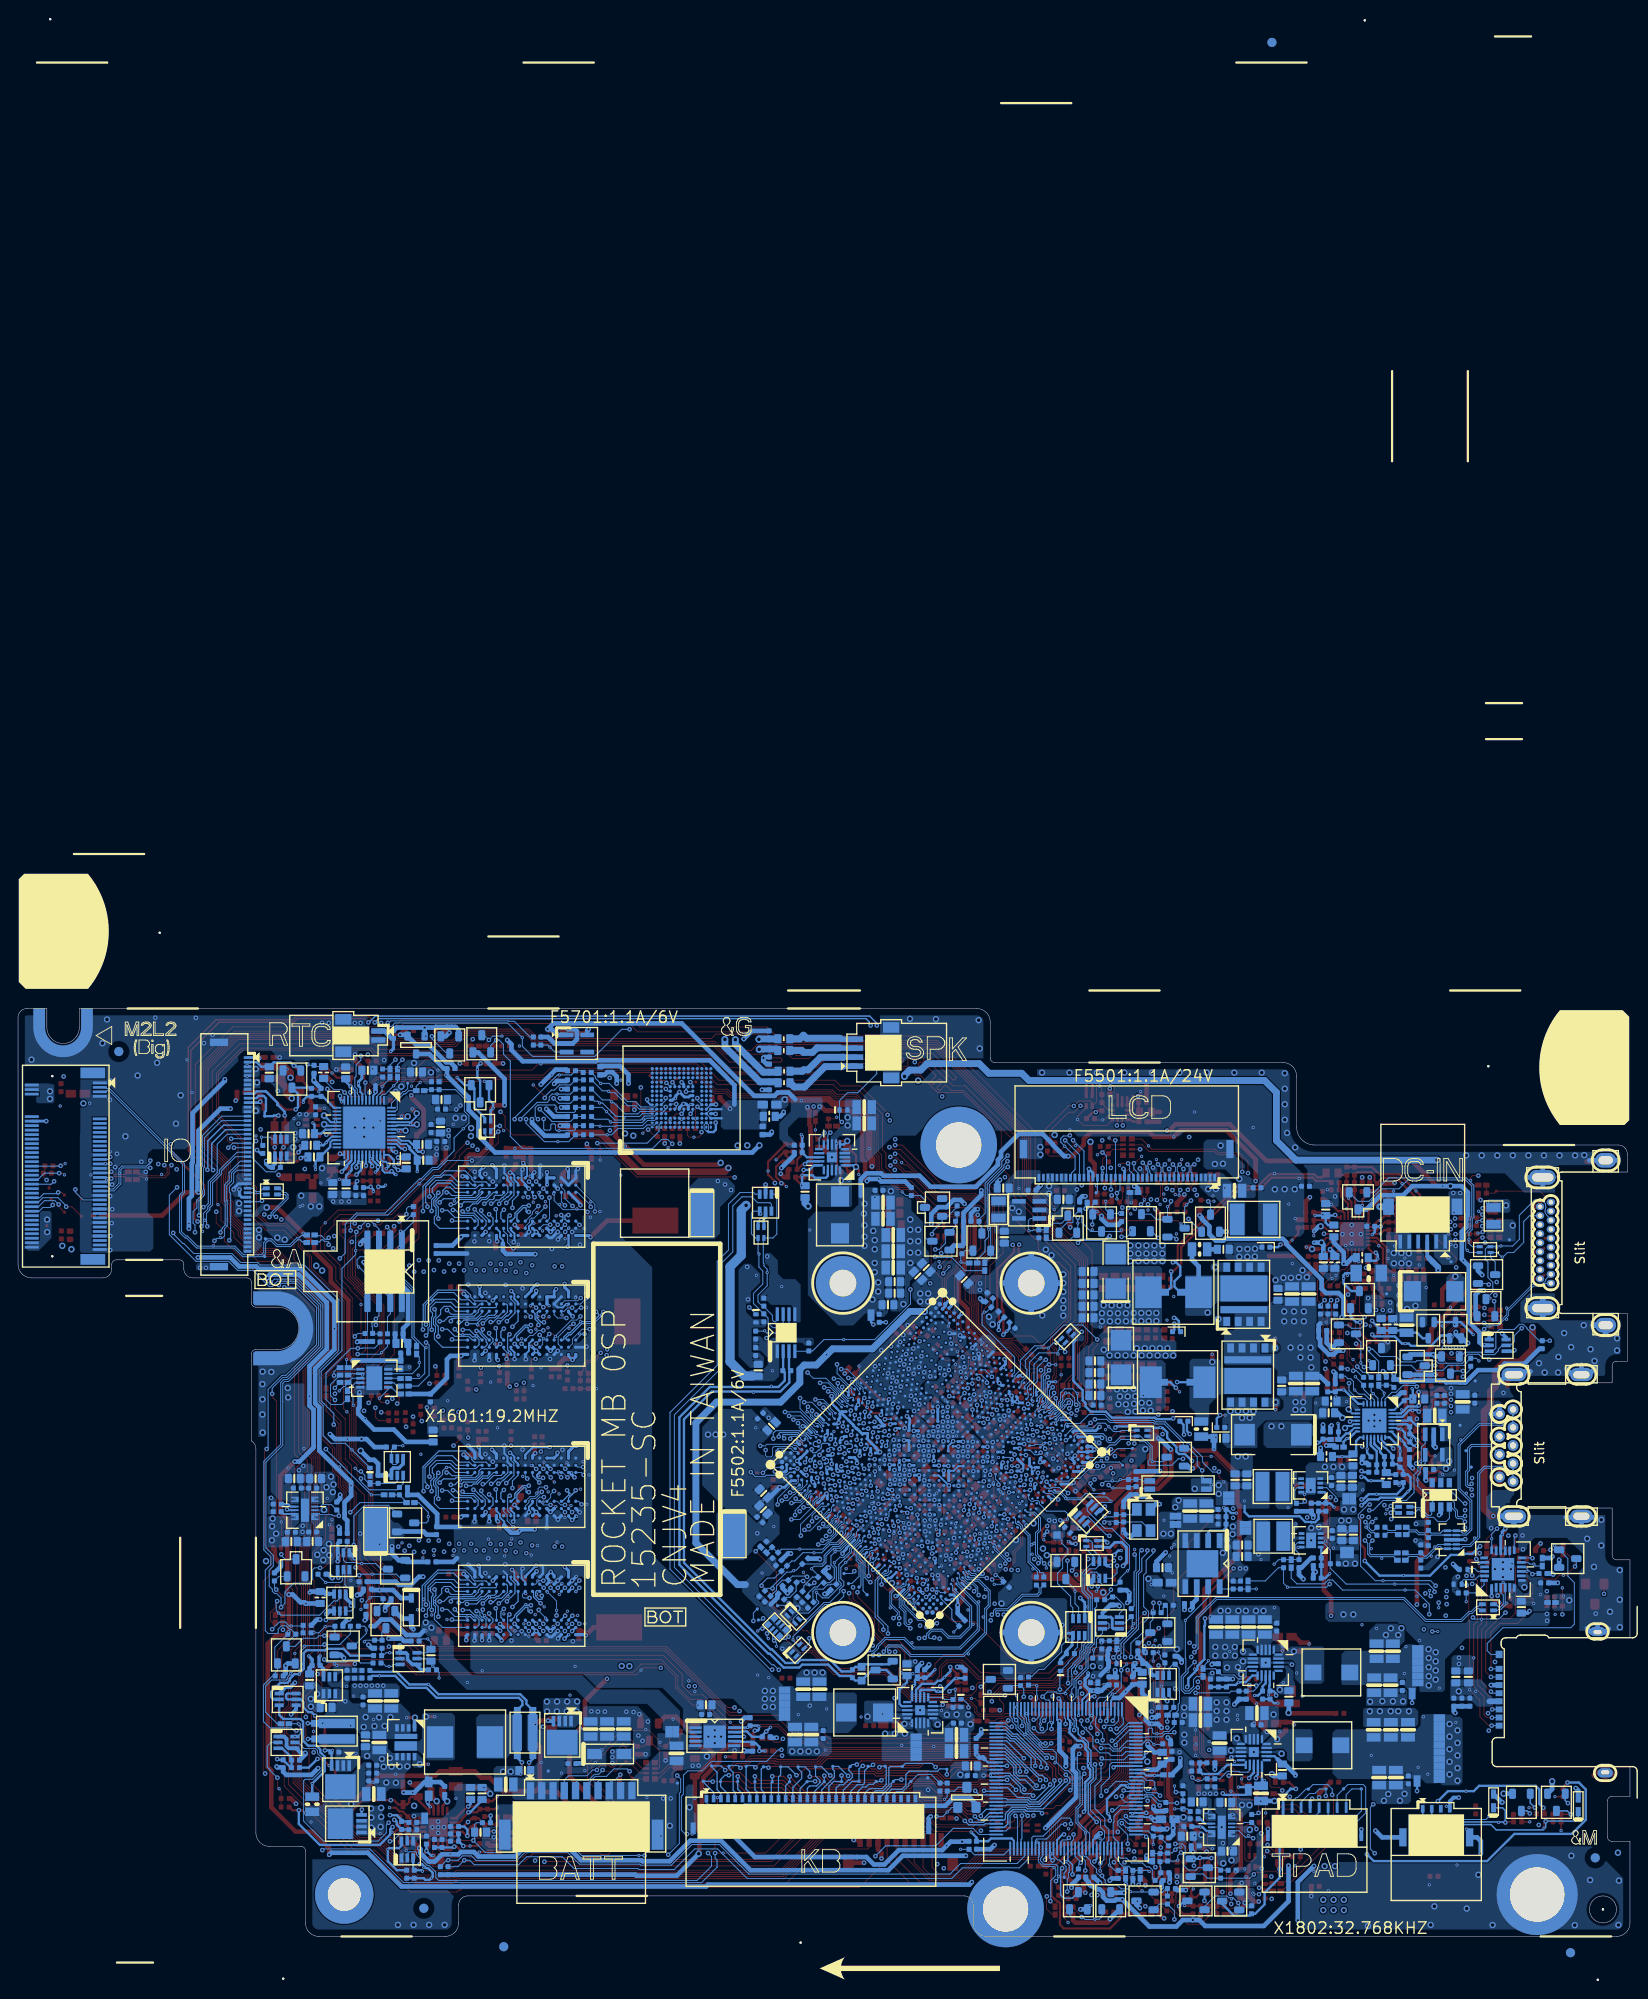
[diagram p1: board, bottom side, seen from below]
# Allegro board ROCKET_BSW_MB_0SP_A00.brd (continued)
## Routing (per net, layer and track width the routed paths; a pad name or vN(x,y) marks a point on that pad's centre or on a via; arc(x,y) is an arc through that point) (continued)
PWR_VCC0_CSMP1: length 30.9
  L4 w0.254: v1(29.79,48.51) 30.13,48.85 31.15,48.85 32.18,49.88 35.02,49.88 37.95,52.81 41.21,52.81 42.29,53.89 44.35,53.89 44.62,54.17 47.98,54.17 49.5,55.68 v1(49.5,55.7)
  BOTTOM w0.254: PR4614.1 25.17,50.38 PR4606.1 25.17,49.8 25.88,49.09 v2(28.14,49.09) 29,49.09 29.25,48.83 29.26,48.83 29.62,48.51 v1(29.79,48.51) ; v1(49.5,55.7) 49.55,55.75 49.55,56.79 PR4648.2
PWR_VCC0_CSREF: length 4.1
  BOTTOM w0.203: 28.77,54.83 PU4601.17
  BOTTOM w0.254: PR4613.2 28.1,52.35 PC4603.1 28.11,53.85 28.77,54.52 28.77,54.83
PWR_VCC0_CSSUM: length 5.6
  BOTTOM w0.203: PU4601.18 28.37,54.82
  BOTTOM w0.254: PR4614.2 26.83,51.27 PR4617.1 27.25,51.69 PC4607.1 PC4612.1 27.72,53.75 27.72,54.01 27.92,54.22 27.93,54.22 28.37,54.66 28.37,54.82
PWR_VCC0_DIFFOUT: length 5.2
  TOP w0.254: v1(23.55,56.8) 23.8,56.54 PR4603.2 24.27,55.65 v2(24.27,55.26)
  BOTTOM w0.203: PU4601.25 25.79,57.25
  BOTTOM w0.254: 25.79,57.25 24.63,57.25 PR4604.2 23.79,56.8 v1(23.55,56.8)
PWR_VCC0_FB: length 8.1
  TOP w0.254: PR4609.1 22.07,52.92 v2(21.64,53.34) 22.2,53.34 22.48,53.62 PR4616.2 22.92,54.01 PC4601.1 22.92,54.45 23.55,55.07 23.61,55.07 v1(23.63,55.1)
  BOTTOM w0.203: 25.84,56.85 PU4601.24
  BOTTOM w0.254: 25.84,56.85 24.73,56.85 PR4604.1 PC4602.2 24.31,55.77 v1(23.63,55.1)
PWR_VCC0_HG: length 13.3
  TOP w0.508: v3(39.39,65.32) v2(39.39,66.39)
  L4 w1.016: v3(39.39,65.32) 39.1,65.32 32.79,59.01 31.73,59.01 31.24,58.52 v3(31.22,58.52)
  BOTTOM w0.203: PU4601.9 30.83,58.05 31.22,58.44 v3(31.22,58.52)
PWR_VCC0_ILIM: length 3.4
  BOTTOM w0.203: PU4601.21 26.81,55.39
  BOTTOM w0.254: PR4168.1 v2(25.51,53.88) 25.51,54.24 26.67,55.39 26.81,55.39
PWR_VCC0_IMAX: length 2.3
  BOTTOM w0.203: PU4601.16 v2(29.17,54.12) 29.17,54.1
  BOTTOM w0.254: 29.17,54.1 29.17,53.66 PR4684.1
PWR_VCC0_IOUT: length 8.8
  TOP w0.254: v2(20.79,51.28) 21.15,51.64 PR4619.1 21.91,51.45 PC4608.1 23.07,51.97 23.15,51.97 23.15,51.98 23.21,51.98 23.24,52.01 23.25,52.01 v1(23.72,52.49)
  L4 w0.254: v1(23.72,52.49) 25.32,54.09 26.2,54.09 v1(26.26,54.15)
  BOTTOM w0.203: 27.26,54.8 27.57,55.11 PU4601.20
  BOTTOM w0.254: v1(26.26,54.15) 26.26,54.19 26.64,54.56 27.02,54.56 27.26,54.8
PWR_VCC0_PVCC: length 5
  BOTTOM w0.203: PU4601.15 30,55.39 30.16,55.23
  BOTTOM w0.254: PR4637.2 v2(31.95,53.26) 31.05,53.26 PC4611.1 30.39,53.91 30.39,54.99 30.16,55.23
PWR_VCC0_ROSC: length 2.9
  BOTTOM w0.203: 26.17,55.72 PU4601.22
  BOTTOM w0.254: 26.17,55.72 25.87,55.41 25.69,55.41 v2(25.37,55.09) 24.99,54.71 24.99,54.57 PR4615.1
PWR_VCC0_TSEN: length 4.5
  BOTTOM w0.203: PU4601.13 30.59,56.45 30.9,56.14
  BOTTOM w0.254: 30.9,56.14 31.21,55.83 31.5,55.83 32.16,55.16 PR4660.1 PC4617.2 32.35,56.89 v2(32.41,56.95)
PWR_VCC0_TSEN1: length 15.8
  TOP w0.254: v2(44.93,57.87) v1(45.49,57.87)
  L3 w0.254: v1(45.49,57.87) 45.49,57.75 42.92,55.17 35.05,55.17 v1(34.7,54.81)
  BOTTOM w0.254: PR4661.1 45.86,57.5 v1(45.49,57.87) ; PR4660.2 33.28,55.2 PR4643.1 34.45,54.81 v1(34.7,54.81)
PWR_VCC0_VBOOT/ADDR: length 2.6
  BOTTOM w0.203: PU4601.14 30.39,56.05 30.66,55.79
  BOTTOM w0.254: 30.66,55.79 31.17,55.27 v2(31.42,55.27) 31.78,54.91 PR4644.1
PWR_VCC0_VCC: length 4.1
  BOTTOM w0.203: PU4601.28 26.13,58.45 25.78,58.8
  BOTTOM w0.254: v2(24.19,60.81) 24.1,60.72 PR4620.2 24.86,59.67 PC4604.1 25.12,59.47 25.78,58.8
PWR_VCC0_VRMP: length 4.7
  BOTTOM w0.203: 29.96,59.11 PU4601.7
  BOTTOM w0.254: PR4607.2 33.55,60.45 PC4610.2 32.5,60.66 v2(31.78,60.66) 31.7,60.66 30.16,59.11 29.96,59.11
PWR_VCC0_VSN: length 5.3
  TOP w0.254: PC4606.1 22.72,57.95 PR4610.1 22.86,58.48 23.23,58.48 v1(23.44,58.26)
  BOTTOM w0.203: 25.92,57.65 PU4601.26
  BOTTOM w0.254: 24.13,58.44 24.48,58.44 25.25,57.67 25.9,57.67 25.92,57.65 ; 24.13,58.44 v2(24.13,58.37) ; 24.13,58.44 23.63,58.44 v1(23.44,58.26)
PWR_VCC0_VSP: length 5.5
  TOP w0.254: PR4605.1 22.6,60.13 22.6,59.55 PC4605.2 22.95,59.43 v1(23.44,58.94)
  BOTTOM w0.203: 26.04,58.05 PU4601.27
  BOTTOM w0.254: 25.18,58.28 24.64,58.83 23.56,58.83 v1(23.44,58.94) ; 25.18,58.28 v2(25.35,58.45) ; 25.18,58.28 25.41,58.05 26.04,58.05
PWR_VCORE_ISEN1N: length 31.5
  TOP w0.254: v2(49.99,60.45) 50.4,60.86 v1(50.4,60.91)
  L4 w0.254: v1(29.8,51.66) 29.66,51.53 28.89,51.53 28.72,51.7 28.72,52.72 29.11,53.11 34.97,53.11 36.96,55.1 40.26,55.1 41.34,56.18 43.4,56.18 43.67,56.45 46.66,56.45 47.86,57.66 49.2,57.66 50.27,58.72 50.27,60.78 v1(50.4,60.91)
  BOTTOM w0.254: v1(29.8,51.66) 29.66,51.53 PR4613.1 ; PG4709.1 51.01,61.52 v1(50.4,60.91)
PWR_VCORE_ISEN1P: length 34.3
  L4 w0.254: v1(29.8,51.01) 29.66,51.15 28.73,51.15 28.33,51.54 28.33,52.88 28.95,53.49 34.82,53.49 36.8,55.48 40.1,55.48 41.18,56.56 43.24,56.56 43.52,56.84 46.5,56.84 47.7,58.04 49.04,58.04 49.89,58.88 49.89,61.12 49.89,61.12 49.89,61.17 v1(50.26,61.54)
  BOTTOM w0.254: PR4617.2 27.45,50.57 v2(28.73,50.57) 29.05,50.57 29.46,50.99 29.77,50.99 v1(29.8,51.01) ; PG4707.1 50.25,61.52 v1(50.26,61.54)
PWR_VCORE_LG1: length 11.9
  TOP w0.508: v3(39.33,59.3) v2(39.33,58.49)
  L4 w1.016: v3(39.33,59.3) 39.33,59.16 37.58,57.42 36,57.42 34.37,55.79 32.28,55.79 v3(31.63,56.44)
  BOTTOM w0.203: v3(31.63,56.44) 31.39,56.67 30.88,56.67 30.7,56.85 PU4601.12
PWR_VCORE_PH1: length 20.7
  TOP w0.508: v3(46.36,63.76) v2(46.36,64.62)
  L4 w1.016: v3(31.91,57.56) 32.14,57.79 33.34,57.79 39.31,63.76 v3(46.36,63.76)
  BOTTOM w0.203: PU4601.10 31.81,57.65 v3(31.91,57.56)
  BOTTOM w0.508: v3(31.91,57.56) 32.47,58.12 PC4609.1
PWR_VCORE_RGND_1: length 66.7
  TOP w0.254: PR4610.2 PC4605.1 21.32,59.94 PC4619.1 20.96,59.94 20.11,59.09 20.08,59.09 v1(19.86,58.87) ; PR4678.2 61.96,44.23 v1(61.65,44.23) 61.54,44.34 60.82,44.34 ; 60.82,44.34 59.57,44.34 PR4652.1 ; 60.82,44.34 v2(60.82,44.48)
  L3 w0.254: v1(61.65,44.23) 61.49,44.39 58.64,44.39 57.29,45.74 57.29,49.09 56.39,49.99 56.39,52.62 55.12,53.89 55.12,54.61 v1(55,54.72)
  L4 w0.254: v1(19.86,58.87) 20.38,58.87 21.44,57.81 21.44,56.97 22.5,55.91 25.55,55.91 27.13,54.33 27.13,51.1 28.24,49.99 28.55,49.99 30.67,49.99 31.71,51.02 34.54,51.02 37.47,53.95 40.73,53.95 41.82,55.04 43.87,55.04 44.15,55.31 47.13,55.31 48.31,56.49 52.22,56.49 52.54,56.17 53.75,56.17 55,54.92 v1(55,54.72)
PWR_VCORE_SEN_1: length 68.5
  TOP w0.254: PR4605.2 21.34,60.73 PC4620.1 20.77,60.73 20.37,60.34 20.37,59.89 20.06,59.57 v1(19.86,59.57) ; PR4676.2 61.69,43.72 v1(61.54,43.57) 61.16,43.96 60.38,43.96 59.74,43.32
  L3 w0.254: v1(61.54,43.57) 61.69,43.72 61.86,43.72 62.16,44.02 62.16,44.44 61.82,44.78 58.79,44.78 57.67,45.9 57.67,49.25 56.77,50.15 56.77,52.78 55.5,54.05 55.5,54.59 v1(55.64,54.74)
  L4 w0.254: v1(55.64,54.74) 55.64,54.82 53.91,56.55 52.7,56.55 52.38,56.87 48.15,56.87 46.98,55.69 43.99,55.69 43.72,55.42 41.66,55.42 40.57,54.34 37.31,54.34 34.38,51.41 31.55,51.41 30.52,50.37 28.39,50.37 27.51,51.26 27.51,54.49 25.71,56.29 22.66,56.29 21.82,57.13 21.82,57.97 20.21,59.57 v1(19.86,59.57)
  BOTTOM w0.254: v2(62.31,43.83) 62.21,43.83 61.96,43.57 v1(61.54,43.57)
PWR_VCORE_SNUB: length 2.7
  BOTTOM w0.508: v2(46.16,54.09) PC4710.1 46.34,55.48 PR4704.2
PWR_VCORE_VRHOT#: length 4.2
  BOTTOM w0.102: PR4635.2 26.46,61.19 PR4621.2 27.87,61.19 PR4640.1 27.88,60.98 27.28,60.38 v2(27.28,60.29) 27.28,60 27.57,59.7 PU4601.2
PWR_VGG_BT: length 2.5
  TOP w0.203: PU4802.8 32.79,76.75 v1(33.28,76.27) 33.58,75.97 v2(33.96,75.97)
  BOTTOM w0.508: v1(33.28,76.27) 32.76,75.74 PR4823.1
PWR_VGG_BTR:
  vias: v2(33.06,73.04)
PWR_VGG_COMP: length 3.6
  TOP w0.203: PU4802.23 28.66,78.75 28.31,79.1
  TOP w0.254: PC4816.1 26.77,80.12 PC4818.1 27.09,80.11 v2(27.72,79.48) 27.93,79.48 28.31,79.1
PWR_VGG_COMP1: length 1.9
  TOP w0.254: PC4804.2 25.89,78.33 PR4801.1 25.89,76.88 v2(26.14,76.63)
PWR_VGG_COMP2: length 1.8
  TOP w0.254: PC4816.2 26.77,81.83 PR4831.1 25,81.83 v2(25,81.83)
PWR_VGG_CSCOMP: length 51.4
  TOP w0.203: PU4802.19 30.49,80.36
  TOP w0.254: 30.49,80.36 30.49,81.85 30.57,81.93 PC4810.2 PC4802.2 30.58,83.61 PR4825.2 30.27,84.81 28.7,84.81 28.36,84.46 28.36,83.87 PR4820.2 28.07,83.63 27.49,84.2 25.92,84.2 v2(25.29,83.57) 23.91,82.19 v1(23.91,81.36)
  L4 w0.254: v1(50.6,68.66) 50.48,68.66 49.02,67.2 42.78,67.2 38.12,71.86 37.81,71.86 37.81,71.86 33.33,71.86 29.12,76.07 29.12,78.84 27.83,80.13 24.91,80.13 23.91,81.13 v1(23.91,81.36)
  BOTTOM w0.254: v1(50.6,68.66) 50.42,68.66 50.06,68.31 50.06,67.32 PR4810.1
PWR_VGG_CSMP1: length 46.9
  TOP w0.254: v1(23.33,80.9) 23.33,82.34 v2(23.75,82.75) 25.6,84.61 27.83,84.61 28.6,85.38 PR4825.1 PR4830.1
  L4 w0.254: v1(50.57,68.01) 50.57,68.01 50.36,68.01 49.17,66.82 42.63,66.82 37.97,71.48 33.18,71.48 28.74,75.91 28.74,78.68 27.67,79.75 24.76,79.75 23.6,80.9 v1(23.33,80.9)
  BOTTOM w0.254: PR4810.2 50.57,67.33 50.57,68.01 v1(50.57,68.01)
PWR_VGG_CSREF: length 4.4
  TOP w0.203: 31.29,80.36 PU4802.17
  TOP w0.254: 31.29,80.76 31.29,80.36 ; 31.29,80.76 v2(31.45,80.76) ; 31.29,80.76 31.29,81.36 32.05,82.13 32.05,82.65 PC4812.1 PR4824.2
PWR_VGG_CSSUM: length 6.3
  TOP w0.203: PU4802.18 30.89,80.35 30.91,80.36
  TOP w0.254: 31.29,81.9 31.67,82.28 31.67,82.66 PC4810.1 PC4802.1 31.46,84.47 PR4830.2 32.16,84.51 PR4832.1 ; 31.29,81.9 v2(31.23,81.96) ; 31.29,81.9 30.91,81.52 30.91,80.36
PWR_VGG_DIFFOUT: length 3.3
  TOP w0.203: PU4802.25 28.32,77.95
  TOP w0.254: 28.32,77.95 28.28,77.99 v2(27.69,77.99) 27.29,78.4 PR4803.2 26.77,77.6 PR4801.2
PWR_VGG_FB: length 6.8
  TOP w0.203: 28.17,78.35 PU4802.24
  TOP w0.254: PR4831.2 25.93,80.15 PC4818.2 25.9,79.35 PC4804.1 PR4803.1 27.2,79.29 v1(27.68,78.81) 28.13,78.35 28.17,78.35
  BOTTOM w0.254: v1(27.68,78.81) 27.69,78.82 PR4802.1 28.33,78.17 v2(28.61,77.89)
PWR_VGG_HG: length 17.4
  TOP w0.203: PU4802.9 33.21,77.15 33.99,76.38 34.29,76.38 34.37,76.3 34.62,76.3
  TOP w0.508: 34.62,76.3 v3(35.29,76.3) 35.51,76.52 v2(35.91,76.52)
  L4 w1.016: v3(35.29,76.3) 35.66,76.3 37.86,74.09 39.99,74.09 40.75,73.33 41.12,73.33 45.7,68.75 v3(45.7,68.52)
PWR_VGG_ILIM: length 3.5
  TOP w0.203: 29.69,80.36 PU4802.21
  TOP w0.254: 29.69,80.36 29.69,80.48 v2(28.56,81.61) 28.07,82.1 PR4820.1
PWR_VGG_IMAX: length 3.5
  TOP w0.203: PU4802.16 31.69,80.3 31.75,80.36
  TOP w0.254: 31.75,80.36 31.88,80.5 32.39,80.5 v2(33.15,81.26) 33.69,81.8 PR4821.1
PWR_VGG_IOUT: length 4.2
  TOP w0.203: PU4802.20 30.09,80.36
  TOP w0.254: PC4805.1 PR4819.1 28.88,82.6 29.69,81.79 v2(29.69,81.15) 29.69,81.02 30.09,80.62 30.09,80.36
PWR_VGG_LG: length 17
  TOP w0.203: PU4802.12 33.52,78.35 33.87,78.71 34.2,78.71 v3(34.32,78.83)
  L4 w1.016: v3(46.03,74.28) 46.03,75.49 42.69,78.83 v3(34.32,78.83)
  BOTTOM w0.508: v2(35.06,78.29) 34.52,78.83 v3(34.32,78.83)
PWR_VGG_PVCC: length 4.8
  TOP w0.254: PU4802.15 32.45,79.81 v1(32.72,80.08)
  BOTTOM w0.254: PC4808.1 32.78,80.02 v1(32.72,80.08) ; PC4808.1 33.77,79.23 33.5,78.96 PR4818.2 ; PC4808.1 v2(34.97,80.02)
PWR_VGG_ROSC: length 5.3
  TOP w0.203: 29.03,79.48 PU4802.22
  TOP w0.254: 29.03,79.48 29.03,80.47 27.23,82.27 PR4828.1 26.28,82.69 v2(26.23,82.74)
PWR_VGG_SW: length 25.4
  TOP w0.203: v3(34.24,77.02) 33.71,77.55 PU4802.10
  L4 w1.016: v3(46.87,69.25) 46.81,69.25 41.59,74.48 41.22,74.48 40.46,75.24 38.34,75.24 36.13,77.44 34.67,77.44 v3(34.24,77.02)
  BOTTOM w0.508: v2(35.06,77.02) v3(34.24,77.02) 34.03,76.8 PC4813.1 ; 47.87,71.53 47.87,74.38 48.61,75.12 PR4847.1
PWR_VGG_TSEN: length 4.4
  TOP w0.203: PU4802.13 33.33,78.75 33.46,78.89
  TOP w0.254: v2(35.09,77.78) 35.09,77.78 PR4834.1 PC4814.2 34.09,79.52 33.46,78.89
PWR_VGG_TSEN1: length 5.3
  TOP w0.254: v1(38.78,76.8) 38,76.8 v2(37.5,77.3) 36.83,77.97 PR4833.1 36.79,78.71 PR4834.2
  BOTTOM w0.254: PR4812.1 39.07,76.51 v1(38.78,76.8)
PWR_VGG_VBOOT/ADDR: length 2.9
  TOP w0.203: 33.37,79.41 33.12,79.15 PU4802.14
  TOP w0.254: PR4822.1 34.33,80.37 v2(34.09,80.13) 33.37,79.41
PWR_VGG_VCC: length 4.5
  TOP w0.203: 29.03,76.38 PU4802.28
  TOP w0.254: 29.03,76.38 29.03,76.36 28.56,75.9 v1(28.22,75.9) 28.22,74.9 PC4807.1
  BOTTOM w0.254: v1(28.22,75.9) 27.99,75.67 v2(27.99,75.22) 28.21,75 28.7,75 PR4817.2
PWR_VGG_VRMP: length 4.7
  TOP w0.203: 32.68,75.83 32.41,76.09 PU4802.7
  TOP w0.254: 32.68,75.83 33.78,74.73 v2(33.86,74.73) 34.11,74.73 34.34,74.96 34.34,75.21 34.63,75.5 PC4806.2 PR4827.2
PWR_VGG_VSN: length 6.1
  TOP w0.203: 28.43,77.55 PU4802.26
  TOP w0.254: 28.43,77.55 28.11,77.55 27.03,76.48 27.03,75.23 ; PC4819.1 27.03,73.83 PR4835.1 27.03,75.23 ; 27.03,75.23 v2(26.86,75.23)
PWR_VGG_VSP: length 5.5
  TOP w0.203: 28.43,77.15 PU4802.27
  TOP w0.254: 27.82,76.72 28.25,77.15 28.43,77.15 ; 27.82,76.72 v2(27.88,76.66) ; 27.82,76.72 27.41,76.32 27.41,74.47 27.84,74.04 PC4815.2 PR4836.1
Q3601_2: length 12.7
  TOP w0.102: v1(150.14,37.22) 150.34,37.02 150.34,36.5 150.9,35.94 150.9,35.05 150.65,34.81 R4010.2
  BOTTOM w0.102: Q4001.2 143.18,37.54 143.48,37.24 143.84,37.24 145.42,35.66 149.73,35.66 v2(149.96,35.89) 150.24,36.17 150.24,37.12 v1(150.14,37.22)
Q3615_G: length 6
  TOP w0.102: v1(141.03,40.09) 140.93,39.99 R4055.1
  BOTTOM w0.102: Q4015.G 136.49,39.79 136.91,40.21 v2(139.6,40.21) 140.92,40.21 v1(141.03,40.09)
Q6203_S: length 3.9
  TOP w0.508: R6501.2 43.16,4.38 42.75,3.98 v1(42.75,3.73) 42.75,3.54 43.83,2.46 C6504.2
  vias: v2(41.87,4.79)
Q6204_S: length 4.5
  TOP w0.203: v1(47.23,3.95) 46.75,3.48 C6505.2 46.79,3.38 R6514.2 48.49,3.38 R6518.2 49.41,3.38 v2(49.45,3.43)
  BOTTOM w0.203: v1(47.23,3.95) 47.22,3.96 Q6504.S
Q6205_D: length 2.4
  TOP w0.254: Q6507.6 45.83,7.95 R6505.2 v2(45.94,9.16)
Q6206_D: length 2.8
  TOP w0.254: v2(48.47,5.27) 48.69,5.05 R6506.2 48.15,4.34 47.59,4.9 Q6507.3
RCOMP_LPC_HVT: length 6.5
  TOP w0.254: R1859.2 64.63,60.89 64.63,61.32 v1(64.5,61.45)
  BOTTOM w0.102: 64.56,61.02 64.67,60.91 64.67,59.97 64.88,59.76 64.88,59.3 65.11,59.07 65.23,59.07 65.43,58.88 65.43,58.74 65.6,58.57 65.74,58.57 66.03,58.28 CPU1.T4
  BOTTOM w0.254: 64.56,61.02 64.56,61.39 v1(64.5,61.45) 64.38,61.57 v2(63.73,61.57)
RING2: length 3.9
  TOP w0.762: v3(148.66,95.31) 148.66,95.87 v2(149.05,96.25) 149.34,96.55 R2906.1
  BOTTOM w0.203: v3(144.93,91.12) 144.19,90.38 U2701.17
RING2_R:
  vias: v2(153.48,96.7) v3(152.52,96.28)
RSMRST#_KBC: length 162.2
  TOP w0.102: v1(98.83,25.01) 98.96,24.88 99.95,24.88 107,31.92 133.58,31.92 136.98,35.32 136.98,39.6 139.75,42.37 139.75,51.68 141.63,53.56 141.63,60.63 138.29,63.97 138.29,70.03 140.62,72.36 140.62,72.49 141.46,73.33 141.46,76.1 v2(141.44,76.12) 141.39,76.18 140.41,76.18 EC1812.1 139.32,76 v1(139.18,75.86)
  L3 w0.127: v1(98.83,25.01) 98.83,24.9 97.87,23.94 97.87,22.82 94.1,19.06 86.75,19.06 85.51,17.82 85.49,17.82 85.36,17.69 84.8,17.69 84.41,18.09 82.72,18.09 82.15,18.65 79.9,18.65 79.46,18.21 77.02,18.21 76.17,19.06 72.4,19.06 70.67,20.79 66.71,20.79 65.2,22.29 63.47,22.29 62.91,22.85 61.73,22.85 61.7,22.89 61.7,22.9 v1(61.69,22.9)
  BOTTOM w0.102: R1841.2 59.19,36.61 59.31,36.48 59.32,36.48 59.45,36.36 59.45,32.54 59.47,32.51 59.47,32.46 59.93,32 59.93,31.5 60.15,31.29 60.15,29.75 61.48,28.42 61.48,27.59 61.48,27.59 61.48,26.56 61.98,26.06 U2401.15 61.98,24.27 61.7,23.98 61.7,23.32 61.7,23.32 61.7,22.9 v1(61.69,22.9) ; v1(139.18,75.86) 139.18,75.25 138.9,74.97 138.9,74.73 137.1,72.92 136.33,72.92 135.18,71.77 135.18,66.48 134.67,65.97 R2528.2
RSMRST#_KBC_G: length 5.7
  BOTTOM w0.102: R1820.1 59.51,31 59.51,31.78 v2(59.54,31.8) 59.23,32.11 59.23,32.43 59.22,32.44 59.22,32.99 58.55,33.66 Q1801.6 57.94,34.15 57.81,34.28 57.81,34.67 57.94,34.8 Q1801.5
RSMRST#_KBC_MUX: length 5.3
  BOTTOM w0.102: U2503.9 135.16,62.46 134.37,63.25 v2(134.37,63.7) 134.37,64.35 R2528.1
RSVD_VSS#A3: length 5.4
  BOTTOM w0.102: TP2101.1 56.9,54.16 57.59,53.47 58.21,53.47 58.51,53.17 CPU1.A3
RTC_AUX_S5: length 192.3
  TOP w0.508: 50.13,54.65 49.41,53.93 46.19,53.93 43.57,51.31 43.57,48.07 43.34,47.84 43.34,42.42 47.22,38.53 47.22,36.23 47.95,35.51 47.95,33.8 47.67,33.53 47.67,29.25 46.86,28.44 46.86,23.08 ; v1(61.6,53.36) 61.56,53.32 C1132.1 60.75,52.72 59.73,51.7 59.68,51.7 ; 51.61,54.32 51.61,51.99 51.53,51.92 51.53,51.39 52.61,50.31 54.57,50.31 57.02,47.86 57.02,45.54 57.03,45.53 57.03,45.52 57.43,45.11 58,45.11 58.15,45.26 59.26,45.26 59.95,45.96 61.21,45.96 61.45,46.2 R1863.1
  L3 w0.508: v1(49.91,19.79) 48.09,19.79 47.22,20.66 46.75,20.66 v1(46.7,20.7)
  L4 w0.508: 60.78,62.79 60.78,64.61 62.08,65.91 62.08,75.07 64.06,77.05 66.08,77.05 67.55,75.58 69.03,75.58 69.09,75.64 69.09,75.64 72.08,78.63 72.75,78.63 78.36,84.25 81.86,84.25 83.41,85.8 83.41,87.47 85.22,89.28 87.54,89.28 88.24,89.98 89.5,89.98 92.18,87.3 96.22,87.3 96.6,87.68 96.6,87.78 v3(96.62,87.81) ; 60.78,62.79 60.78,61.68 63.4,59.06 63.4,56.99 61.8,55.39 61.8,53.56 v1(61.6,53.36) ; 60.78,62.79 60.27,62.29 53.52,62.29 52.17,60.94 52.17,58.1 v1(52.34,57.93)
  BOTTOM w0.305: v1(61.6,53.36) 61.93,53.03 CPU1.C5 61.68,52.72 CPU1.B6
  BOTTOM w0.508: v3(96.62,87.81) 97.41,87.02 125.95,87.02 127.8,88.87 127.8,90.66 128.89,91.75 128.89,93.14 128.94,93.19 128.94,93.19 131.29,95.55 R2513.1 131.3,96.34 131.64,96.34 133.24,97.95 Q2501.3 ; R2425.2 49.91,18.91 v1(49.91,19.79)
  vias: v2(46.71,21.64)
RTC_DET#: length 241.7
  TOP w0.102: v1(56.46,29.54) 56.46,29.02 R2403.2
  L3 w0.102: v1(56.46,29.54) 56.46,29.39 55.61,28.54 53.2,28.54 53.11,28.45 53.11,28.45 53.03,28.37 51.12,28.37 50.73,28.75 49.93,28.75 49.29,29.39 47.34,29.39 46.75,28.79 44.49,28.79 44.27,29.01 43.91,29.01 43.31,28.41 41.35,28.41 41.02,28.09 41.02,27.43 39.6,26 37.18,26 36.63,25.45 30.52,25.45 29.35,24.28 24.08,24.28 23.51,24.85 23.51,26.91 23.52,26.91 23.52,33.45 v1(22.87,34.09)
  L4 w0.102: v1(22.87,34.09) 22.68,34.28 21.77,34.28 21.38,33.89 16.96,33.89 16.03,34.83 16.03,35.99 16.04,36 16.04,38.57 15.93,38.68 15.93,43.56 16.87,44.5 16.87,47.58 16.1,48.35 16.1,58.45 15.35,59.19 15.35,62.42 14.45,63.32 14.45,65.05 16.66,67.26 16.66,72.09 15.97,72.78 15.97,73.6 17.19,74.82 17.19,82.42 19.23,84.47 21.32,84.47 23.89,87.03 38.79,87.03 43.11,91.36 51.82,91.36 53.72,89.46 59.89,89.46 61.82,91.4 68.44,91.4 77.22,100.18 77.22,100.18 77.72,100.68 93.96,100.68 95.44,102.16 131.32,102.16 132.92,100.55 132.92,99.96 v1(132.97,99.91)
  BOTTOM w0.102: v1(132.97,99.91) 132.95,99.89 132.95,99.63 131.45,98.13 131.12,98.13 Q2502.D ; U2401.6 58.38,25.99 57.4,26.98 57.1,26.98 56.46,27.61 v1(56.46,29.54) 56.46,29.62 v2(55.85,30.23)
RTC_DET#_G: length 9.2
  BOTTOM w0.508: v1(133.77,100.88) 136.92,100.88 R2501.1 ; v1(133.77,100.88) 133.77,100.88 Q2501.1 ; v1(133.77,100.88) 132.61,100.88 132.54,100.95 131.3,100.95 131.29,100.96 130.77,100.96 130.76,100.95 130.34,100.95 130,100.62 Q2502.G
  vias: v2(133.64,99.92)
RTC_INTRUDER: length 2.5
  TOP w0.102: v2(68.17,50.39) 68.17,49.9 R1823.1 67.21,50.03 v1(67.21,50.12)
  BOTTOM w0.102: v1(67.21,50.12) 67.37,49.97 CPU1.G18
RTC_RST#: length 20.3
  TOP w0.102: v1(63.22,46.2) R1863.2 62.59,45.54 C1802.1
  BOTTOM w0.102: G1801.2 63.05,44.02 63.05,43.65 62.38,42.98 62.38,42.5 62.97,41.91 62.97,40.87 63.53,40.31 63.53,39.17 62.08,37.72 62.08,36.73 61.84,36.5 61.84,35.31 Q1813.3 ; CPU1.D18 66.73,48.57 66.45,48.29 66.2,48.29 66.11,48.38 65.71,48.38 65.54,48.2 65.54,48.01 64.74,47.21 62.7,47.21 62.43,46.94 v2(62.43,46.33) 62.56,46.2 63.22,46.2 v1(63.22,46.2) 62.75,45.72 EC1811.1
RTC_TEST#: length 13
  TOP w0.102: C1803.1 58.9,51.15 60.23,51.15 R1862.2 60.3,50.73 v1(59.87,50.29)
  L3 w0.127: v1(59.87,50.29) 60.36,50.78 61.57,50.78 61.57,50.78 61.92,50.78 61.92,50.78 62.08,50.78 62.65,50.21 63.93,50.21 64.52,49.62 66.04,49.62 67.04,50.62 v1(67.66,50.62)
  BOTTOM w0.102: v1(67.66,50.62) 67.55,50.73 CPU1.J16 ; v2(59.49,49.58) 59.87,49.96 v1(59.87,50.29)
RTCRST_ON: length 20.6
  TOP w0.102: v1(60.9,23.95) 61.63,23.95 61.83,24.15 61.83,25.95 62.43,26.55 62.43,26.75 62.62,26.93 v2(62.62,26.96) 63.08,27.41 v1(63.28,27.41)
  BOTTOM w0.102: v1(60.9,23.95) 60.9,23.47 59.6,22.17 59.6,21.12 58.85,20.37 57.89,20.37 57.61,20.09 56.36,20.09 55.94,20.51 U2401.120 ; Q1813.5 61.16,32.94 61.33,32.78 61.33,32.08 61.61,31.8 61.61,31.45 R1828.1 61.66,31.11 62.34,30.43 62.34,30.33 EC1810.1 63.28,29.4 v1(63.28,27.41)
RUN_ON#: length 10.4
  BOTTOM w0.102: R4014.2 145.61,40.12 144.78,39.3 v2(144.75,39.3) 143.1,39.3 142.9,39.5 142.9,40.6 Q4014.5 142.62,40.56 142.62,39.05 141.84,38.27 141.84,37.77 141.53,37.45 141.53,36.55 141.96,36.12 Q4001.6
RUN_ON_R: length 8.2
  TOP w0.102: R4003.2 v2(144.07,46.27) 143.64,46.69 v1(143.29,46.69)
  BOTTOM w0.102: U4001.3 145.47,46.91 145.36,46.81 144.07,46.81 143.95,46.69 v1(143.29,46.69) 143.29,47.1 C4051.1 144.12,47.93 145.13,47.93 145.35,47.71 U4001.5
S5_ENABLE: length 147.1
  TOP w0.152: v1(149.49,34.04) 149.53,34.08 R4001.2 ; v1(59.2,12.71) 59.21,12.71 59.94,11.98 59.94,10.69 61.43,9.2 61.85,9.2 62.53,8.52 62.53,8.46 62.6,8.39 v2(62.6,8.29) 63.02,7.87 v1(63.02,7.57) 63.02,6.07 62.92,5.97 62.92,4.44 62.67,4.19 R2490.2
  L3 w0.152: v1(63.02,7.57) 63.08,7.57 63.27,7.38 65.27,7.38 66.25,8.36 72.65,8.36 72.99,8.02 74.5,8.02 75.87,9.39 84,9.39 84.32,9.07 88.33,9.07 88.58,8.81 92.39,8.81 93.6,10.02 94.23,10.66 99.2,10.66 101.07,12.53 103.45,12.53 103.66,12.31 104.43,12.31 105.13,11.61 105.32,11.61 105.73,11.21 107.76,11.21 108.07,11.52 114.16,11.52 119.56,6.11 130.2,6.11 131.57,4.74 135.94,4.74 140.04,8.84 141.07,8.84 148.84,16.61 148.84,20.57 149.77,21.5 149.77,25.45 149.38,25.85 149.38,26.42 148.99,26.8 148.99,28.34 149.91,29.26 149.91,30.79 149.49,31.21 v1(149.49,34.04)
  BOTTOM w0.152: U2401.14 61.58,24.22 61.44,24.08 61.44,23.29 61.23,23.08 61.23,22.47 60.8,22.04 60.63,22.04 60.11,21.52 60.11,20.91 59.83,20.63 59.83,18.91 59.57,18.66 59.57,17.53 60.12,16.98 60.12,13.64 v1(59.2,12.71) ; v1(63.02,7.57) 63.19,7.4 63.19,4.6 62.84,4.24 61.89,4.24 Q2403.D
SATA_OBSN: length 1.5
  TOP w0.102: R1931.1 73.42,46.32 v1(73.42,46.84)
  BOTTOM w0.102: v1(73.42,46.84) 73.41,46.84 73.41,46.87 73.35,46.94 CPU1.M30
SATA_OBSP: length 1.5
  TOP w0.102: R1931.2 73.92,47.07 v1(73.92,47.33)
  BOTTOM w0.102: 73.85,47.87 73.85,47.4 v1(73.92,47.33)
SATA_RXN0: length 1.9
  TOP w0.102: v1(72.77,47.53) 72.77,46.67 R1903.2
  BOTTOM w0.102: 72.66,48.06 72.66,47.65 v1(72.77,47.53)
SATA_RXN1: length 1.3
  TOP w0.102: v1(72.23,47.04) 71.87,47.41 R1907.2
  BOTTOM w0.102: v1(72.23,47.04) 72.16,47.12 CPU1.K28
SATA_RXP0: length 3.2
  TOP w0.102: v1(73.29,47.98) 73.29,47.3 73,47.02 73,45.69 R1901.2
  BOTTOM w0.102: v1(73.29,47.98) 73.16,48.1 CPU1.N28
SATA_RXP1: length 1.3
  TOP w0.102: v1(71.71,46.54) 71.4,46.85 R1906.2
  BOTTOM w0.102: CPU1.J28 71.65,46.59 v1(71.71,46.54)
SD_CD#: length 25.2
  TOP w0.102: R3309.2 7.54,43.45 8.3,43.45 v2(8.37,43.37) 8.37,43.37 v1(8.82,42.92) 8.92,42.83 R3308.2
  BOTTOM w0.102: v1(8.82,42.92) 7.86,42.92 Q3301.G 6.9,41.96 6.9,40 6.18,39.28 6.18,34.65 6.56,34.27 14.1,34.27 15.85,32.52 15.85,31.72 15.42,31.3 SD1.1
SD_CD#_CARD: length 11.1
  TOP w0.102: R3309.1 6.96,42.45 6.1,41.59 v1(6.1,41.07) 7.07,40.09 v2(7.39,40.09) 7.82,40.09 8.25,39.66 9.51,39.66 10.12,40.27 10.78,40.27 v1(10.83,40.22)
  BOTTOM w0.102: U3301.10 11.63,41.02 v1(10.83,40.22) 10.76,40.29 R3307.2 ; v1(6.1,41.07) 5.96,41.21 Q3301.D
SD_MMC_CLK/MS_DATA2: length 19.3
  TOP w0.102: v1(15.44,27.17) 16.46,28.2 16.46,34.07 15.9,34.63 15.9,40.16 16.76,41.02 v2(16.76,41.4) 16.71,41.45 15.86,41.45 EC3307.1 15.84,41.62 15.07,42.38 EC3305.1 15.09,42.43 R3303.2
  BOTTOM w0.102: SD1.5 15.26,27 v1(15.44,27.17)
SD_MMC_CMM/MS_DATA3: length 20.5
  TOP w0.102: v1(17.06,41.9) 17.19,41.77 17.67,41.77 EC3304.1 17.78,41.37 16.47,40.07 v2(16.47,35.2) 16.47,34.74 16.9,34.31 16.9,27.96 15.29,26.34 v1(15.29,25.21)
  BOTTOM w0.102: SD1.7 15,25.2 15.01,25.21 v1(15.29,25.21) ; v1(17.06,41.9) 16.68,41.52 16.13,41.52
SD_MMC_DAT1: length 20.1
  TOP w0.102: v1(15.43,29.7) 15.43,33.79 14.48,34.75 12.48,34.75 11.6,35.63 11.6,37.01 11.49,37.11 10.88,37.11 10.78,37.21 10.78,37.45 10.88,37.55 11.49,37.55 11.6,37.65 11.6,37.9 11.49,38 10.88,38 10.78,38.1 10.78,38.94 11.44,39.6 v2(11.44,40.53) EC3301.1 11.41,41.99 10.82,41.99 v1(10.82,41.99)
  BOTTOM w0.102: U3301.12 10.85,42.02 v1(10.82,41.99) ; SD1.2 v1(15.43,29.7)
SD_MMC_DATA0/MS_DATA5: length 21.2
  TOP w0.102: v1(12.71,44.5) 12.71,43.61 13.37,42.95 EC3306.1 13.37,41.67 v2(13.08,41.38) 12.73,41.02 12.73,35.87 13.32,35.28 14.58,35.28 16.01,33.84 16.01,29.39 v1(15.43,28.8)
  BOTTOM w0.102: v1(12.71,44.5) 12.85,44.36 U3301.13 ; SD1.3 v1(15.43,28.8)
SD_MMC_DATA2/MS_BS: length 21.4
  TOP w0.102: v1(15.35,23.4) 15.66,23.4 16.66,24.4 16.66,26.23 v2(17.8,27.38) 17.8,34.93 17.89,35.02 17.89,38.77 v1(18.13,39.01)
  BOTTOM w0.102: SD1.9 15.06,23.4 15.06,23.4 v1(15.35,23.4) ; 16.13,40.02 16.78,40.02 17.2,39.6 18.47,39.6 18.68,39.39 EC3302.1 18.59,39.01 v1(18.13,39.01)
SD_MMC_DATA3/MS_CLK: length 21.1
  TOP w0.102: v1(17.51,40.06) 16.91,39.46 16.91,35.01 17.35,34.58 v2(17.35,30.92) 17.35,27.77 16.21,26.63 16.21,24.61 15.89,24.29 v1(15.32,24.29)
  BOTTOM w0.102: 16.13,40.52 16.91,40.52 17.24,40.84 17.92,40.84 EC3303.1 18.03,40.58 v1(17.51,40.06) ; v1(15.32,24.29) 15.31,24.3 SD1.8
SD_WP#/MS_DATA1_C: length 2.5
  BOTTOM w0.102: R3311.1 10.45,41.11 v2(10.67,41.33) 11.13,41.33 11.32,41.52 U3301.11
SDMMC1_RCOMP: length 3.4
  TOP w0.254: v2(68.63,52.25) 68.15,52.73 67.59,52.73 67.59,54 v1(67.75,54.15)
  BOTTOM w0.254: CPU1.P13 68.32,54.21 67.81,54.21 v1(67.75,54.15)
SDMMC3_RCOMP: length 3.2
  TOP w0.254: v2(65.05,54.69) 65.15,54.69 65.63,54.2 R815.1 66.79,54.2 v1(67.25,54.66)
  BOTTOM w0.254: 67.84,54.69 67.27,54.69 v1(67.25,54.66)
SDREG: length 4.8
  TOP w0.305: C3309.2 14.17,44.65 13.84,44.99 v1(13.84,45.26)
  BOTTOM w0.305: v1(13.84,45.26) 14.18,44.92 v2(14.18,44.59) 14.35,44.43 U3301.16
SEC_GPIO_SUS8: length 11.1
  BOTTOM w0.102: CPU1.AF51 85.83,44.92 85.83,44.52 86.03,44.32 86.15,44.32 87.67,42.8 88.12,42.8 v2(88.21,42.7) 88.68,42.24 88.68,41.25 88.31,40.88 88.31,39.76 88.81,39.25 R1522.1 89.72,39.25 90.2,38.78 90.53,38.78 91.24,38.08 R1523.2
SEC_GPIO_SUS9: length 10.6
  BOTTOM w0.102: R1525.2 91.69,38.44 91.69,38.91 90.74,39.87 90.74,39.89 R1524.1 90.11,40.1 v2(90.83,40.82) 90.55,41.1 89.62,41.1 89.23,41.49 89.23,42.23 88.37,43.09 87.68,43.09 CPU1.AF52
SEC_GPIO_SUS10: length 11.1
  BOTTOM w0.102: R1527.2 90.68,37.17 90.68,38.31 90.44,38.55 89.53,38.55 89.05,39.03 88.72,39.03 88.65,39.1 R1526.1 88.08,40.97 88.3,41.2 v2(88.3,41.49) 87.7,42.09 87.23,42.09 86.6,42.72 86.6,43.07 85.74,43.93 85.74,44.06 85.54,44.26 CPU1.AE51
SENSOR_HUB_RST#_R: length 1.3
  TOP w0.102: v1(62.6,55.09) 62.95,54.74 TP805.1
  BOTTOM w0.102: 62.08,55.47 62.47,55.09 v1(62.6,55.09)
SENSOR_I2C_SCL: length 129.9
  TOP w0.102: U6901.1 58.08,90.01 60.64,90.01 v2(61.32,90.68) 61.32,91.01 60.35,91.98 RN6901.4 60.94,92.16 v1(60.99,92.2) 61.7,91.49 62.3,91.49 64.39,89.4 64.39,88.72 64.16,88.5 64.16,88.43 R6906.2
  L3 w0.127: v1(60.99,92.2) 62.03,93.25 69.28,93.25 76.1,100.07 80.1,100.07 82.17,102.14 135.99,102.14 137.93,100.19 145.54,100.19 146.34,100.99 155.19,100.99 157.25,98.93 157.25,89.21 155.64,87.59 155.61,87.59 v1(155.56,87.55)
  BOTTOM w0.102: IOBD1.20 155.06,88.05 v1(155.56,87.55)
SENSOR_I2C_SCL_ALS: length 6.8
  TOP w0.102: R6906.1 63.25,87.19 v2(62.74,87.7) 62.74,87.79 62.69,87.83 v1(62.69,88.37)
  BOTTOM w0.102: LCD1.31 61.1,86.78 v1(62.69,88.37)
SENSOR_I2C_SDA: length 129.7
  TOP w0.102: 59.69,92.17 59.21,92.65 59.21,94.53 59,94.74 57.71,94.74 v2(57.68,94.72) 57.25,94.29 57.25,93.09 57.43,92.92 U6901.4 ; 59.69,92.17 59.69,92.56 59.87,92.74 61.16,92.74 v1(61.72,92.18) 61.77,92.23 62.24,92.23 63.93,90.54 64.87,89.6 64.87,88.52 64.64,88.3 R6907.2 ; 59.69,92.17 RN6901.3
  L3 w0.127: v1(61.72,92.18) 62.28,92.74 69.49,92.74 76.31,99.56 80.31,99.56 82.38,101.63 135.78,101.63 137.72,99.68 145.75,99.68 146.55,100.48 154.98,100.48 156.74,98.72 156.74,89.42 155.43,88.1 155.4,88.1 155.06,87.76 155.06,87.68 v1(154.93,87.55)
  BOTTOM w0.102: IOBD1.21 v1(154.93,87.55)
SENSOR_I2C_SDA_ALS: length 9.4
  TOP w0.102: R6907.1 64.64,86.84 64.41,86.62 63.07,86.62 61.91,87.77 v2(61.52,87.77) 61.81,88.06 v1(61.81,88.38)
  BOTTOM w0.102: LCD1.30 60.6,87.18 v1(61.81,88.38)
SENSOR_KB_DIS: length 178.8
  TOP w0.102: v1(68.13,24.02) 68.51,24.4 69.32,24.4 69.52,24.2 70.19,24.2 70.47,23.92 R2428.2 ; v2(63.81,19.28) 63.81,19.53 v1(64.11,19.83)
  L3 w0.102: v1(158.82,80.04) 157.65,80.04 157.32,79.7 154.91,79.7 154.73,79.52 151.96,79.52 150.58,78.15 147.5,78.15 144.16,74.81 144.16,65.48 144.16,64.97 144.16,64.97 145.58,63.55 145.58,55.3 145.68,55.19 145.68,51.96 146.44,51.2 146.44,48.48 146.44,48.47 146.31,48.34 146.11,48.14 146.11,46.89 145.97,46.76 143.44,44.23 143.44,42.44 142.92,41.91 142.92,36.7 141.71,35.49 141.71,33.89 140.72,32.9 139.9,32.9 139.5,32.5 139.5,31.56 138.04,30.1 131.93,30.1 130.65,28.82 115.39,28.82 113.8,27.24 106.5,27.24 105.1,28.64 100.39,28.64 99.83,28.08 99.83,24.13 98.97,23.27 98.97,22.11 98.46,21.6 98.03,21.6 97.06,20.63 97.06,20.34 96.35,19.62 95.33,19.62 94.29,18.59 86.97,18.59 86.62,18.25 86.6,18.25 84.97,16.62 82.36,16.62 80.96,18.02 80.02,18.02 79.75,17.74 76.72,17.74 75.96,18.51 72.29,18.51 70.58,20.22 67.08,20.22 66.26,19.4 64.54,19.4 v1(64.11,19.83)
  BOTTOM w0.102: IOBD1.15 156.32,90.55 158.21,88.66 158.21,85.38 158.32,85.28 158.32,82.96 158.21,82.86 158.21,82.31 158.32,82.2 158.32,82.15 158.82,81.65 v1(158.82,80.04) ; v1(64.11,19.83) 64.54,20.26 64.99,20.26 67.92,23.19 67.92,23.81 v1(68.13,24.02) 68.38,24.28 U2401.31
SIO_I2C5_CLK: length 197.5
  TOP w0.102: Q1606.1 57.63,9.72 57.56,9.8 55.81,9.8 v1(55.65,9.63)
  L3 w0.127: v1(63.15,65.34) 62.88,65.6 62.88,66.46 61.16,68.18 61.16,73.98 61.73,74.55 61.73,76.33 62.85,77.45 62.85,83.03 61.8,84.08 58.27,84.08 58.24,84.05 57.58,84.05 57.56,84.08 57.37,84.08 56.67,84.78 56.67,85.39 56.62,85.44 56.62,85.52 55.76,86.38 48.56,86.38 46.6,88.34 40.54,88.34 38.01,85.8 24.12,85.8 22.19,83.87 19.41,83.87 17.87,82.34 16.55,82.34 15.81,81.59 15.81,78.65 14.34,77.18 14.34,68.34 13.72,67.72 13.72,66.65 14.89,65.48 14.89,64.03 15.74,63.18 15.74,60.06 17.07,58.73 17.07,44.6 18.24,43.43 18.24,41.41 17.55,40.72 17.54,40.72 17.06,40.24 17.06,38.94 17.87,38.13 17.87,34.94 17.72,34.79 17.72,31.65 17.97,31.39 17.97,26.45 18.56,25.87 18.56,14.1 25.7,6.96 37.5,6.96 38.27,6.2 40.36,6.2 40.57,6.41 41.94,6.41 42.46,6.94 48.17,6.94 49.48,8.25 50.27,8.25 50.46,8.43 51.99,8.43 52.19,8.63 53.17,8.63 53.92,7.88 55.04,7.88 55.95,8.8 55.95,9.33 v1(55.65,9.63)
  BOTTOM w0.102: CPU1.AB2 67.18,61.06 66.66,61.59 66.66,63.71 65.6,64.77 63.6,64.77 v2(63.48,64.65) 63.48,65.01 v1(63.15,65.34) 63.15,65.42 62.64,65.93
SIO_I2C5_DATA: length 197
  TOP w0.102: v1(56.1,8.22) 56.12,8.22 56.33,8.01 Q1606.4
  L3 w0.127: v1(63.65,65.88) 63.65,66.41 61.72,68.34 61.72,73.82 62.24,74.34 62.24,74.35 62.25,74.36 62.25,76 63.35,77.1 63.35,82.82 63.35,83.24 62.01,84.58 57.58,84.58 57.18,84.99 57.18,85.6 57.12,85.65 57.12,85.73 55.97,86.89 48.77,86.89 46.81,88.84 40.33,88.84 37.79,86.31 23.91,86.31 21.98,84.38 19.2,84.38 17.75,82.93 16.43,82.93 15.3,81.8 15.3,78.86 13.83,77.39 13.83,68.58 13.21,67.96 13.21,66.43 14.38,65.26 14.38,64.24 14.38,63.82 15.2,63.01 15.2,61.19 15.24,61.15 15.24,59.84 16.56,58.52 16.56,44.39 17.73,43.22 17.73,41.62 17.34,41.23 17.33,41.23 16.56,40.45 16.56,34.13 17.19,33.5 17.19,31.46 17.46,31.18 17.46,26.24 18.05,25.66 18.05,13.89 25.49,6.45 37.21,6.45 37.98,5.69 40.73,5.69 40.95,5.9 42.2,5.9 42.7,6.4 48.4,6.4 48.61,6.61 48.9,6.61 50.03,7.74 50.48,7.74 50.67,7.92 52.2,7.92 52.4,8.12 52.95,8.12 53.7,7.37 55.25,7.37 v1(56.1,8.22)
  BOTTOM w0.102: RN1603.1 63.6,65.88 v1(63.65,65.88) 63.99,65.88 v2(64.57,65.31) 65.76,65.31 67.1,63.96 67.1,63.09 66.93,62.92 66.93,62.18 67.57,61.54 67.57,61.14 CPU1.AC3
SIO_SLP_S4: length 7.6
  BOTTOM w0.102: Q4015.D 138.61,40.77 139.22,41.38 v2(140.76,41.38) 141.15,41.38 141.27,41.51 142.53,41.51 142.78,41.76 Q4014.2 142.78,42.91 142.36,43.32 R4053.2
SLEEVE: length 12.5
  TOP w0.762: v3(148.52,93.03) 149.1,93.61 149.1,94.22 149.82,94.94 R2911.1
  L3 w0.762: v3(148.52,93.03) 149.88,93.03 150.86,92.06 150.86,90.12 v3(148.36,87.62)
  BOTTOM w0.203: v3(144.93,90.15) 144.76,89.98 U2701.18
  vias: v2(145.32,87.99)
SLEEVE_CTRL: length 4.6
  BOTTOM w0.102: U2901.5 149.73,89.17 149.86,89.3 150.23,89.3 150.38,89.15 U2901.6 150.7,88.5 150.92,88.72 v2(151.88,88.72) 151.88,87.95 R2915.2
SLEEVE_R:
  vias: v2(153.48,95.43) v3(152.37,94.79)
SM_DRAMRST#: length 180.7
  TOP w0.102: v1(136.7,43.27) v2(136.28,43.69)
  L3 w0.127: v1(136.7,74.37) 136.71,74.37 138.46,74.37 139.18,73.65 139.18,71.43 139.84,70.76 139.84,69.97 140.32,69.5 140.32,60.77 140.51,60.57 140.51,58.36 v1(140.5,58.35) 140.52,58.33 140.52,55.94 140.32,55.75 140.32,46.85 136.73,43.27 v1(136.7,43.27)
  L4 w0.127: v1(133.62,35.6) 134.1,35.6 136.7,38.2 v1(136.7,43.27) 136.7,47.92 136.55,48.08 136.55,49.54 135.05,51.04 v1(133.24,51.04) ; v1(87.17,53.6) 87.05,53.72 86.54,53.72 85.77,52.95 85.23,52.95 84.93,53.25 84.93,53.5 84.49,53.95 84.46,53.98 84.46,54.92 89.25,59.71 89.25,59.76 91.79,62.29 91.79,64.15 97.42,69.78 97.7,69.78 v1(97.74,69.82) 97.74,69.94 98.8,71.01 102.47,71.01 103.3,70.18 114.54,70.18 115.22,69.5 115.22,68.88 118.67,65.43 120.37,65.43 121.22,64.58 121.59,64.58 122.2,65.2 126.22,65.2 126.83,64.58 127.18,64.58 127.47,64.87 137.05,64.87 140.5,61.41 v1(140.5,58.35) ; v1(133.24,82.14) 133.24,81.97 134.53,80.67 134.53,80.52 136.7,78.35 v1(136.7,74.37) 136.7,69.3 134.1,66.7 v1(133.62,66.7)
  BOTTOM w0.102: RAM3.T2 130.02,39.1 130.53,39.62 132.61,39.62 133.4,38.82 133.4,37.26 133.22,37.07 133.22,36.58 133.39,36.41 133.47,36.32 133.47,35.74 v1(133.62,35.6) ; v1(133.24,82.14) 133.24,83.19 132.5,83.93 130.8,83.93 130.27,83.4 RAM4.T2 ; EC502.1 97,69.09 v1(97.74,69.82) ; v1(133.62,66.7) 133.39,66.92 133.39,67.54 133.22,67.72 133.22,68.22 133.4,68.4 133.4,69.92 132.6,70.72 130.44,70.72 129.91,70.2 RAM2.T2 ; v1(133.24,51.04) 133.24,52.08 132.49,52.83 130.8,52.83 130.27,52.3 RAM1.T2 ; CPU1.BA42 87.19,53.58 v1(87.17,53.6)
SM_RCOMP_0: length 3.9
  TOP w0.254: R504.1 84.7,58.72 v2(84.66,58.72) 84.02,58.09 83.31,58.09 v1(83.13,57.9)
  BOTTOM w0.254: v1(83.13,57.9) 83.13,57.94 83.03,58.04 CPU1.BA28
SMB_CLK: length 21.6
  TOP w0.102: v1(76.22,73.59) 76.22,73.59 76.22,74.16 75.28,75.1 75.28,76.11 74.15,77.23 RN1601.3
  L3 w0.127: v1(70.81,62.12) 71.36,62.12 73.41,64.18 73.41,65.18 74.78,66.54 74.78,69.02 76.22,70.46 v1(76.22,73.59)
  BOTTOM w0.102: CPU1.AM6 71.57,62.88 70.93,62.25 70.93,62.24 v1(70.81,62.12) ; v2(75.56,74.35) 75.56,74.24 v1(76.22,73.59)
SMB_DATA: length 21.5
  TOP w0.102: v1(76.6,74.32) 76.6,74.46 75.76,75.3 75.76,76.3 74.8,77.27 RN1601.4
  L3 w0.127: v1(76.6,74.32) 76.6,74.34 76.64,74.3 76.64,70.52 75.03,68.91 75.03,66.47 73.64,65.08 73.64,64.07 71.37,61.81 v1(71.37,61.47)
  BOTTOM w0.102: v2(76.68,74.91) 76.6,74.83 v1(76.6,74.32) ; 72.52,62.38 72.02,62.38 71.37,61.73 v1(71.37,61.47)
SML1_CLK: length 128.2
  TOP w0.102: RN2401.3 68.49,12.7 68.3,12.88 68.3,13.3 v1(68.2,13.4) ; v1(104.45,27.78) v2(104.45,28.37)
  L3 w0.127: v1(68.2,13.4) 69.89,15.09 74.33,15.09 74.72,14.69 87.8,14.69 90.11,12.38 90.9,12.38 95.33,16.82 95.63,16.82 96.67,17.86 96.67,17.95 97.04,18.32 97.61,18.32 98.56,19.27 99.2,19.27 100.16,20.24 100.16,22.6 104.3,26.74 104.3,27.62 v1(104.45,27.78)
  L4 w0.127: v1(94.47,29.59) 95.03,30.15 97.12,30.15 97.78,29.49 102.8,29.49 104.45,27.84 v1(104.45,27.78)
  BOTTOM w0.102: v1(68.2,13.4) 67.98,13.18 U2401.67 ; Q2604.6 95.29,81.27 95.46,81.44 96.8,81.44 97.46,82.09 98.56,82.09 99.57,81.08 99.57,75.98 100.82,74.73 100.82,63.13 106.06,57.9 106.06,40.97 95.24,30.15 95.03,30.15 v1(94.47,29.59)
SML1_DATA: length 125.6
  TOP w0.102: RN2401.4 68.01,12.05 67.77,12.29 67.77,12.72 67.48,13.01 v1(67.48,13.4) ; v1(103.79,27.78) v2(103.79,27.19)
  L3 w0.127: v1(103.79,27.78) 103.79,26.99 99.65,22.85 99.65,21.85 98.9,21.1 98.9,20.51 97.7,19.31 96.91,19.31 96.09,18.48 96.09,18.03 95.38,17.33 95.12,17.33 90.69,12.89 90.32,12.89 88.01,15.2 87.96,15.2 74.93,15.2 74.54,15.59 69.68,15.59 v1(67.48,13.4)
  L4 w0.127: v1(95.2,29.61) 96.94,29.61 97.57,28.98 102.59,28.98 v1(103.79,27.78)
  BOTTOM w0.102: Q2604.3 97.06,82.39 97.26,82.58 98.76,82.58 100.06,81.28 100.06,76.18 101.3,74.93 101.3,63.4 106.54,58.16 106.54,40.77 95.38,29.61 v1(95.2,29.61) ; v1(67.48,13.4) 67.48,10.85 67.58,10.74 U2401.68
SOC_EXTSMI_N: length 59.8
  TOP w0.102: R2461.2 60.29,20.26 60.73,20.7 61.18,20.7 61.46,20.97 61.46,22.03 62.38,22.96 62.52,23.09 63.52,23.09 64.02,22.59 65.7,22.59 65.77,22.66 66.35,22.66 66.78,23.08 66.78,23.5 68.03,24.75 69.35,24.75 69.67,24.43 72.24,24.43 72.72,24.91 72.72,25.33 73.24,25.84 73.42,25.84 73.67,26.09 75.99,26.09 76.06,26.16 79.81,26.16 80.21,26.56 82.69,29.05 87.42,29.05 88.36,29.05 90.81,31.5 92.23,31.5 93.82,33.09 93.82,35.14 95.5,36.81 95.5,38.05 v1(96.38,38.94)
  BOTTOM w0.102: v1(96.38,38.94) 96.38,39.11 95.72,39.78 94.94,39.78 R1514.2 93.57,41.14 R1515.1 93.03,41.67 92.7,41.67 91.77,42.6 90.65,42.6 90.64,42.58 v2(90.56,42.58) 89.7,42.58 88.79,43.49 87.88,43.49 86.75,44.62 CPU1.AG53
SOC_RUNTIME_SCI#: length 58
  TOP w0.102: R2496.2 62.33,25.76 62.92,26.35 62.92,26.55 63.3,26.93 63.4,26.93 63.4,26.93 63.64,26.93 64.01,27.3 69.59,27.3 69.95,26.94 69.95,26.24 69.51,25.81 69.51,24.93 69.78,24.66 72.14,24.66 72.49,25.01 72.49,25.42 73.14,26.07 73.25,26.07 73.49,26.32 75.89,26.32 75.97,26.39 79.71,26.39 79.98,26.66 82.6,29.28 88.27,29.28 90.72,31.72 91.52,31.72 92.8,33.01 92.8,34.44 95.16,36.81 v1(95.16,38.63)
  BOTTOM w0.102: CPU1.AG51 86.44,45.01 86.44,44.61 87.76,43.29 88.45,43.29 89.43,42.31 89.43,41.57 89.66,41.34 R1513.1 92.53,40.67 92.76,40.67 v2(92.82,40.6) 92.95,40.6 93.11,40.44 93.58,40.44 95.16,38.86 v1(95.16,38.63) 95.19,38.63 95.19,38.64 95.75,38.64 R1506.2
SOC_RUNTIME_SCI#_KBC: length 3.7
  TOP w0.102: R2496.1 62.64,24.42 v1(62.64,23.58) v2(61.99,23.58)
  BOTTOM w0.102: v1(62.64,23.58) 62.64,24.12 62.78,24.26 U2401.17
SP5: length 5.1
  TOP w0.102: R3303.1 15.9,44.13 v1(14.75,45.27)
  BOTTOM w0.102: v1(14.75,45.27) 15.35,44.68 v2(15.35,44.15) U3301.18
SPI_CLK_CPU: length 7
  TOP w0.102: R1911.1 65.95,64.12 v2(65.47,64.12) 65.37,64.01 v1(64.83,64.01)
  BOTTOM w0.102: CPU1.W3 66.41,59.79 66.21,59.99 66.21,61.18 65.78,61.61 65.78,63.15 64.92,64.01 v1(64.83,64.01)
SPI_CLK_CPU_MUX: length 3.8
  BOTTOM w0.102: U2503.4 141.44,61.46 141.95,60.95 141.96,60.95 R2526.2 142.18,60.57 141.73,60.12 141.73,59.01 v2(141.68,58.96)
SPI_CLK_KBC: length 14.6
  TOP w0.102: v1(58.71,19.13) 58.72,19.13 59.28,19.69 60.3,19.69 60.61,19.69 60.63,19.71 v2(61.46,19.71) 62.19,20.44 R2418.1
  BOTTOM w0.102: v1(58.71,19.13) 58.71,17.36 59.39,16.68 59.39,14.22 58.28,13.12 58.28,12.33 57.84,11.89 57.84,10.62 57.98,10.48 U2401.92
SPI_CLK_KBC_MUX: length 1.4
  BOTTOM w0.102: R2524.2 142.13,62.46 U2503.2
SPI_CLK_KBC_R: length 113.5
  TOP w0.102: R2418.2 62.19,21.76 62.68,22.25 63.35,22.25 63.73,21.87 65.99,21.87 66.06,21.94 69.54,21.94 69.59,21.99 79.45,21.99 79.46,21.98 79.99,21.46 89.04,21.46 89.7,22.12 92.42,22.12 94.3,24 97.89,24 98.44,23.45 99.53,23.45 v2(99.86,23.78) 102.89,26.81 104.14,26.81 105.19,27.85 105.19,29.11 107.29,31.21 133.87,31.21 137.71,35.05 137.71,37.13 138.83,38.24 138.83,40.42 140.46,42.05 140.46,48.99 141.89,50.42 141.89,52.28 142.58,52.97 142.58,57.43 143.72,58.58 v1(143.72,59.56)
  BOTTOM w0.102: v1(143.72,59.56) 144.22,60.05 144.22,61.26 R2524.1
SPI_CLK_ROM: length 136.8
  TOP w0.102: v1(82.19,87.61) 82,87.61 81.75,87.35 80.96,87.35 76.53,82.92 72.57,82.92 72.09,83.41 71.76,83.41 70.06,81.71 70.06,76.08 70.43,75.7 71.52,74.62 71.52,70.5 71.95,70.06 71.95,68.02 70.1,66.17 68.01,66.17 R1911.2 ; v1(128.45,87.77) 128.76,87.46 129.07,87.46 129.91,86.62 129.91,86.33 131.87,84.37 132.47,84.37 133.32,83.52 134.07,83.52 137.44,80.14 143.19,80.14 143.81,79.52 143.81,78.99 144.85,77.95 144.85,76.2 143.15,74.5 143.15,73.04 142.02,71.91 142.02,71.78 141.32,71.08 140.83,70.6 v2(140.83,70.14) 140.83,65.64 v1(141.19,65.28)
  L3 w0.127: v1(82.19,87.61) 82.53,87.94 82.53,89.03 84.09,90.59 84.09,90.74 86.07,92.72 87.58,92.72 89.24,91.06 90.57,91.06 93.31,88.32 95.62,88.32 95.94,88.63 101.67,88.63 102.45,87.85 103.67,87.85 104.3,88.47 108.03,88.47 108.78,87.71 113.33,87.71 114.11,88.5 117.32,88.5 117.79,88.03 123.76,88.03 124.02,87.77 v1(128.45,87.77)
  BOTTOM w0.102: R2526.1 142.98,59.04 144.16,59.04 144.72,59.6 144.72,62.51 141.95,65.28 v1(141.19,65.28) 140.73,65.28 140.7,65.31 139.31,65.31 138.86,65.76 138.86,65.86 R2527.1
SPI_CLK_ROM_MUX: length 1.5
  BOTTOM w0.102: R2522.2 136.83,61.09 137.2,61.46 U2503.7
SPI_CLK_ROM_R: length 18.4
  TOP w0.102: v1(133.62,65.92) v2(133.62,65.36)
  L4 w0.127: v1(133.62,65.92) 136.43,65.92 139.06,68.55 v1(139.18,68.55)
  BOTTOM w0.102: v1(133.62,65.92) 133.56,65.92 133.28,65.64 133.28,62.3 134.49,61.09 R2522.1 ; U2501.6 138.85,68.88 v1(139.18,68.55) 139.61,68.12 139.61,67.7 139.55,67.63 EC2502.1 139.49,66.88 R2527.2
SPI_CS_CPU_MUX: length 3
  BOTTOM w0.102: v2(143.26,60.56) 142.77,61.05 142.62,61.05 142.27,61.39 R2525.2 141.82,61.96 U2503.3
SPI_CS_CPU_N0: length 3.4
  TOP w0.102: v2(66.27,59.41) 66.27,59.07 66.75,58.59 v1(67.25,58.59) 67.25,59.5 R1909.1
  BOTTOM w0.102: CPU1.V4 67.03,58.55 67.07,58.59 v1(67.25,58.59)
SPI_CS_KBC_MUX: length 2.4
  BOTTOM w0.102: v2(142.43,64.05) 142.43,63.29 R2523.2 142.1,62.96 U2503.1
SPI_CS_KBC_N0: length 15
  TOP w0.102: R2416.1 63.02,20.58 61.65,19.21 v2(60.1,19.21) 59.99,19.1 v1(59.37,19.1)
  BOTTOM w0.102: v1(59.37,19.1) 59.26,18.99 59.26,17.49 59.87,16.88 59.87,13.99 58.76,12.89 58.76,12.13 58.32,11.69 58.32,10.95 58.78,10.49 U2401.90
SPI_CS_KBC_R_N0: length 114.2
  TOP w0.102: v1(143.84,62.26) 143.84,61.43 144.21,61.05 144.21,58.31 143.06,57.16 143.06,53.04 143.06,53.04 143.06,52.77 142.37,52.08 142.37,50.22 141.37,49.21 141.37,44.13 140.94,43.71 140.94,41.85 139.31,40.21 139.31,35.97 134.07,30.73 107.49,30.73 105.67,28.91 105.67,27.65 104.3,26.29 103.05,26.29 99.73,22.96 98.19,22.96 v2(97.94,23.22) 97.64,23.51 94.5,23.51 92.62,21.64 89.9,21.64 89.24,20.98 79.79,20.98 79.25,21.51 69.79,21.51 69.74,21.46 66.26,21.46 65.8,21 63.91,21 63.15,21.76 R2416.2
  BOTTOM w0.102: v1(143.84,62.26) 143.84,62.67 143.38,63.13 R2523.1
SPI_CS_ROM_MUX: length 1.4
  BOTTOM w0.102: U2503.8 136.48,61.96 R2521.2
SPI_CS_ROM_N0: length 154.9
  TOP w0.102: R1909.2 66.66,60.74 66.66,62.74 67.88,63.95 67.88,64.31 68.92,65.36 70.48,65.36 72.89,67.77 72.89,70.06 73.3,70.46 73.3,72.89 73.29,72.9 73.29,72.91 72.69,73.51 72.69,75.1 71.57,76.22 71.57,79.27 71.22,79.61 71.22,80.86 72.02,81.65 72.84,81.65 72.95,81.75 77.02,81.75 79.67,84.41 80.26,84.41 81.42,85.57 v1(82.07,85.57) ; v1(135.79,80.17) 136.73,80.17 137.24,79.66 138.05,79.66 138.73,78.97 v2(139.31,78.97) 139.74,79.4 140.29,79.4 140.5,79.19 140.5,78.43 141.18,77.76 141.81,77.76 142.29,77.28 142.29,73.19 141.3,72.2 141.3,72.07 140.12,70.89 140.12,64.19 142.68,61.63 142.99,61.63 v1(143.73,60.89)
  L3 w0.127: v1(135.79,80.17) 135.79,80.6 133.46,82.93 133.11,82.93 131.36,84.68 131.18,84.68 130.69,84.19 130.51,84.19 130.34,84.37 130.34,84.55 130.82,85.04 130.82,85.22 130.64,85.4 129.32,85.4 129.19,85.27 129.19,84.64 129.06,84.51 128.81,84.51 128.68,84.64 128.68,85.27 128.55,85.4 127.99,85.4 127.32,86.06 124.23,86.06 123.85,86.44 123.55,86.44 123.24,86.76 115.66,86.76 115.53,86.63 115.5,86.63 115.31,86.44 100.42,86.44 99.4,85.43 99.12,85.43 98.99,85.3 98.99,84.54 98.86,84.41 95.19,84.41 95.07,84.54 95.07,84.79 95.19,84.92 98.36,84.92 98.48,85.04 98.48,85.3 98.36,85.43 95.03,85.43 94.71,85.75 93.74,85.75 93.57,85.92 93.39,85.92 92.8,85.33 92.62,85.33 92.44,85.51 92.44,85.69 93.03,86.28 93.03,86.46 92.79,86.7 92.79,87.04 90.83,89.01 90.65,89.01 90.47,88.83 90.47,88.65 92.26,86.85 92.26,86.67 92.08,86.49 91.9,86.49 89.75,88.65 89.75,88.83 90.29,89.37 90.29,89.54 90.04,89.79 88.72,89.79 87.05,91.45 86.6,91.45 86.24,91.09 86.24,89.67 84.62,88.05 84.62,87.87 85.17,87.32 85.17,87.14 84.99,86.96 84.81,86.96 84.26,87.51 84.08,87.51 83.9,87.33 83.9,87.15 84.45,86.6 84.45,86.42 84.27,86.24 84.1,86.24 83.54,86.79 83.36,86.79 82.14,85.57 v1(82.07,85.57)
  BOTTOM w0.102: R2516.2 135.56,81.01 135.79,80.78 v1(135.79,80.17) ; v1(143.73,60.89) 143.73,60.93 R2525.1
SPI_CS_ROM_N0_R: length 29.5
  TOP w0.102: RN2501.2 139.49,74.12 v1(138.46,75.14) 138.75,75.43 138.75,75.98 v2(136.46,78.28) 136.38,78.35 136.38,79.17 v1(136.58,79.37)
  BOTTOM w0.102: R2521.1 134.34,61.92 133.76,62.5 133.76,65.39 134.95,66.58 134.95,71.87 136.23,73.15 137,73.15 138.46,74.62 v1(138.46,75.14) ; v1(136.58,79.37) 136.58,79.37 135.95,79.37 135.19,80.12 R2516.1 135.03,79.29 136.31,78.02 SSKT1.1
SPI_HOLD_CPU: length 133.6
  TOP w0.102: v1(141.21,64.63) 140.8,64.63 140.35,65.08 140.35,70.8 141.53,71.98 141.53,72.11 142.67,73.24 142.67,77.41 143.17,77.91 143.17,79.48 143.01,79.64 139.14,79.64 v1(138.95,79.45) ; v1(64.48,62.84) 65.15,63.51 66.1,63.51 68.56,65.97 70.19,65.97 72.28,68.06 72.28,70.31 72.59,70.62 72.59,72.63 72,73.22 72,74.82 70.54,76.28 70.54,81.14 71.73,82.33 72.55,82.33 72.66,82.44 76.73,82.44 81.16,86.87 v1(81.56,86.87)
  L3 w0.127: v1(81.56,86.87) 81.74,87.05 82.36,87.05 83.06,87.75 83.06,88.84 84.6,90.38 84.6,90.53 86.28,92.22 87.37,92.22 89.03,90.55 90.36,90.55 93.1,87.81 95.85,87.81 96.45,87.21 99.5,87.21 100.25,87.96 101.57,87.96 102.32,87.21 115.03,87.21 115.34,87.52 123.55,87.52 123.87,87.21 124.33,87.21 124.69,86.85 128.79,86.85 129.45,86.19 130.92,86.19 133.42,83.69 133.81,83.69 137.81,79.69 138.35,79.69 138.59,79.45 v1(138.95,79.45)
  BOTTOM w0.102: v1(64.48,62.84) 64.48,62.8 65.11,62.16 65.11,60.1 65.52,59.7 65.52,59.34 65.72,59.13 CPU1.U3 ; v1(141.21,64.63) 141.2,64.62 138.73,64.62 v2(138.56,64.8) 137.89,65.46 R2536.1
SPI_HOLD_ROM: length 13.2
  TOP w0.102: v1(139.88,75.45) 139.88,74.79 v2(139.95,74.73) 140.14,74.54 RN2501.1
  BOTTOM w0.102: R2536.2 137.89,68.79 137.58,69.1 U2501.7 SSKT1.7 137.58,70.84 141.27,74.53 141.27,75.12 140.94,75.45 v1(139.88,75.45)
SPI_SI_CPU: length 6.9
  TOP w0.102: v1(64.46,63.49) 64.3,63.64 64.3,64.63 R1910.1
  BOTTOM w0.102: CPU1.V2 65.81,59.7 65.34,60.17 65.34,62.24 64.95,62.63 64.95,63.19 64.65,63.49 v1(64.46,63.49) 63.75,63.49 v2(63.72,63.46)
SPI_SI_KBC: length 10.7
  TOP w0.102: v1(60.56,18.06) v2(61.04,17.57) R2401.1
  BOTTOM w0.102: v1(60.56,18.06) 60.77,17.84 60.77,14.66 61.26,14.17 61.26,12.7 59.99,11.42 59.98,11.42 U2401.87
SPI_SI_KBC_R: length 115.8
  TOP w0.102: R2401.2 61.96,18.88 62.89,19.81 62.89,19.94 63.72,20.77 65.89,20.77 66.36,21.23 69.83,21.23 69.88,21.28 79.16,21.28 79.69,20.75 89.33,20.75 89.99,21.41 92.72,21.41 92.85,21.54 94.59,23.29 97.32,23.29 97.87,22.73 99.83,22.73 102.77,25.67 v2(103.45,25.67) 104.01,25.67 105.9,27.56 105.9,28.8 107.34,30.25 109.71,30.25 110.68,29.28 134.64,29.28 137.16,31.79 137.16,33.41 139.54,35.79 139.54,40.11 140.99,41.56 141.69,41.56 141.95,41.81 141.95,42.17 141.2,42.92 141.2,43.64 141.59,44.04 141.59,49.12 142.6,50.12 142.6,51.99 143.29,52.68 143.29,52.76 143.29,56.92 144.7,58.33 R2511.1
SPI_SI_ROM: length 139
  TOP w0.102: R2511.2 144.81,60.94 144.81,61.9 143.98,62.73 141.91,62.73 141.3,63.34 141.3,64.09 141.7,64.49 141.7,66.43 v1(141.52,66.61) 141.8,66.89 141.8,70.88 142.5,71.58 142.5,71.71 143.63,72.84 143.63,74.3 145.33,76 145.33,78.68 v2(144.81,79.21) 143.39,80.62 137.64,80.62 134.27,84 133.52,84 132.67,84.85 132.07,84.85 130.4,86.53 130.4,86.85 129.15,88.09 v1(129.01,88.09) ; v1(81.56,87.84) 80.76,87.84 76.33,83.41 72.77,83.41 72.25,83.93 71.6,83.93 69.57,81.91 69.57,75.88 71.03,74.42 71.03,70.27 71.58,69.72 71.68,69.62 71.68,68.04 70.02,66.38 68.51,66.38 68.23,66.65 66.33,66.65 R1910.2
  L3 w0.127: v1(129.01,88.09) 128.83,88.28 124.23,88.28 123.97,88.54 118,88.54 117.53,89.01 113.9,89.01 113.12,88.22 108.99,88.22 108.24,88.98 104.09,88.98 103.46,88.36 102.66,88.36 101.88,89.14 95.73,89.14 95.41,88.83 94.46,88.83 93.78,89.5 93.74,89.5 93.14,90.1 93.14,90.15 91.91,91.38 91,91.38 90.99,91.39 90.96,91.39 90.78,91.57 89.66,91.57 88,93.23 85.86,93.23 83.58,90.95 83.58,90.8 82.02,89.24 82.02,88.3 v1(81.56,87.84)
  BOTTOM w0.102: U2501.5 140.12,67.19 EC2503.1 141.2,66.93 v1(141.52,66.61)
SPI_SO_CPU: length 128.6
  TOP w0.102: v1(140.05,78.96) 140.05,78.12 R2529.2 ; v1(66.81,59.11) 66.81,59.46 66.22,60.04 66.22,60.2 66.43,60.4 66.43,62.47 66.33,62.56 65.94,62.56 65.81,62.7 65.81,62.92 65.89,63.01 66.64,63.01 66.93,63.31 66.93,63.65 68.84,65.56 70.38,65.56 72.69,67.87 72.69,70.14 73.06,70.51 73.06,72.82 72.46,73.42 72.46,75.01 71.17,76.3 v2(71.17,78.49) 71.17,79.1 71,79.27 71,80.95 71.92,81.87 72.74,81.87 72.85,81.98 76.92,81.98 79.83,84.89 80.39,84.89 81.51,86.01 v1(81.56,86.01)
  L3 w0.127: v1(81.56,86.01) 81.62,86.06 82.27,86.06 85.38,89.18 85.38,89.62 85.51,89.74 85.81,89.74 85.94,89.87 85.94,90.12 85.81,90.25 85.51,90.25 85.38,90.38 85.38,90.59 86.5,91.71 87.16,91.71 88.82,90.04 90.15,90.04 93.05,87.15 93.05,86.8 93.81,86.04 94.42,86.04 94.54,86.17 94.54,86.55 94.69,86.7 95.07,86.7 95.2,86.57 95.2,85.81 95.32,85.68 99.3,85.68 99.42,85.81 99.42,86.06 99.3,86.19 95.83,86.19 95.71,86.32 95.71,86.57 95.83,86.7 115.24,86.7 115.55,87.01 123.34,87.01 123.65,86.7 123.96,86.7 124.34,86.31 127.47,86.31 128.1,85.69 130.71,85.69 133.21,83.18 133.59,83.18 136.33,80.44 136.33,80.26 136.25,80.18 136.25,80 136.43,79.83 136.61,79.83 136.69,79.9 136.87,79.9 137.59,79.18 138.14,79.18 138.38,78.94 138.38,78.39 138.28,78.29 137.88,78.29 137.78,78.19 137.78,77.93 137.99,77.71 138.73,77.71 138.86,77.59 138.86,77.44 138.99,77.32 139.24,77.32 139.37,77.44 139.37,77.59 139.5,77.71 139.75,77.71 139.88,77.59 139.88,77.44 140,77.32 140.26,77.32 140.38,77.44 140.38,77.59 140.51,77.71 140.78,77.71 140.91,77.84 140.91,78.09 140.78,78.22 139.03,78.22 138.9,78.35 138.9,78.6 139.03,78.73 139.95,78.73 140.05,78.82 v1(140.05,78.96)
  BOTTOM w0.102: CPU1.V3 66.45,59.11 v1(66.81,59.11)
SPI_SO_KBC: length 121.8
  TOP w0.102: R2517.1 141.86,59.29 141.86,53.47 139.98,51.58 139.98,42.26 138.34,40.63 138.34,38.44 137.23,37.33 137.23,35.25 133.67,31.69 107.09,31.69 99.94,24.54 94.16,24.54 92.22,22.6 89.5,22.6 88.84,21.94 80.19,21.94 79.65,22.48 69.39,22.48 69.34,22.43 v2(67.15,22.43) 65.86,22.43 65.79,22.36 63.93,22.36 63.42,22.86 62.61,22.86 61.68,21.94 61.68,20.84 v1(61.11,20.27)
  BOTTOM w0.102: v1(61.11,20.27) 61.13,20.29 61.34,20.08 61.34,18.59 61.04,18.29 61.04,14.72 61.49,14.27 61.49,12.61 60.38,11.5 U2401.86
SPI_SO_ROM: length 25.3
  TOP w0.102: R2517.2 v2(140.65,62.32) 138.52,64.45 138.52,69.94 140.85,72.26 140.85,72.39 141.8,73.34 141.8,76.31 141.43,76.68 141.43,76.93 141.08,77.29 139.99,77.29 R2529.1 EC2501.1 138.4,78.27 v1(137.93,78.74)
  BOTTOM w0.102: v1(137.93,78.74) 137.58,78.38 SSKT1.2
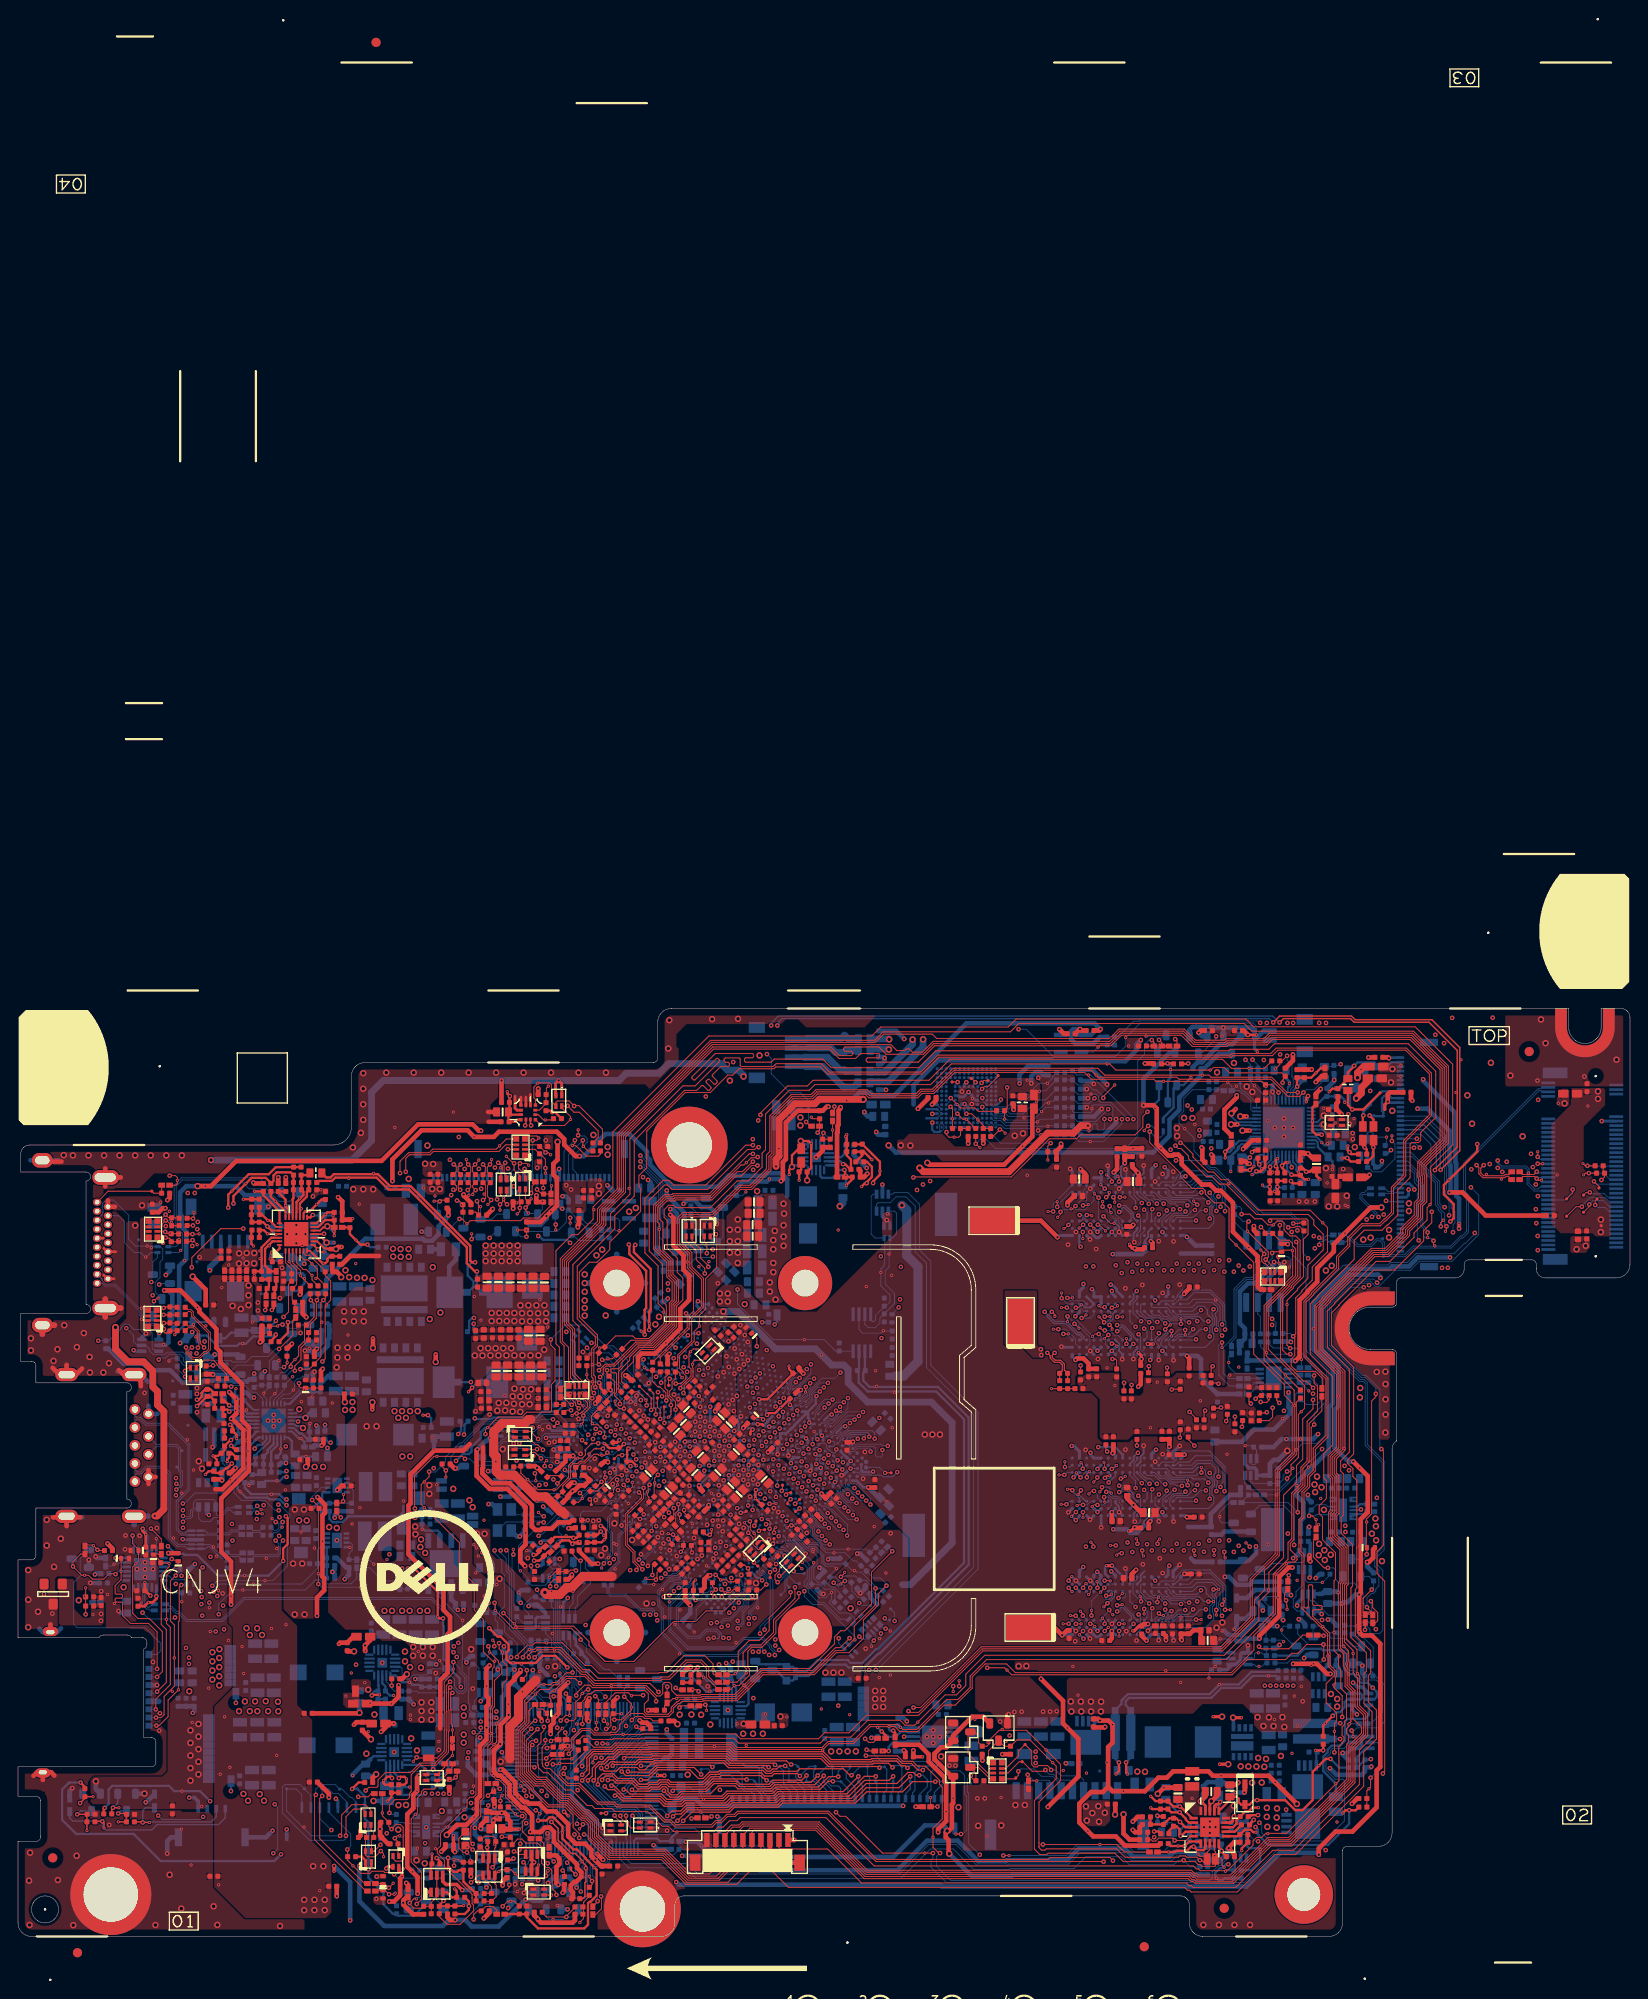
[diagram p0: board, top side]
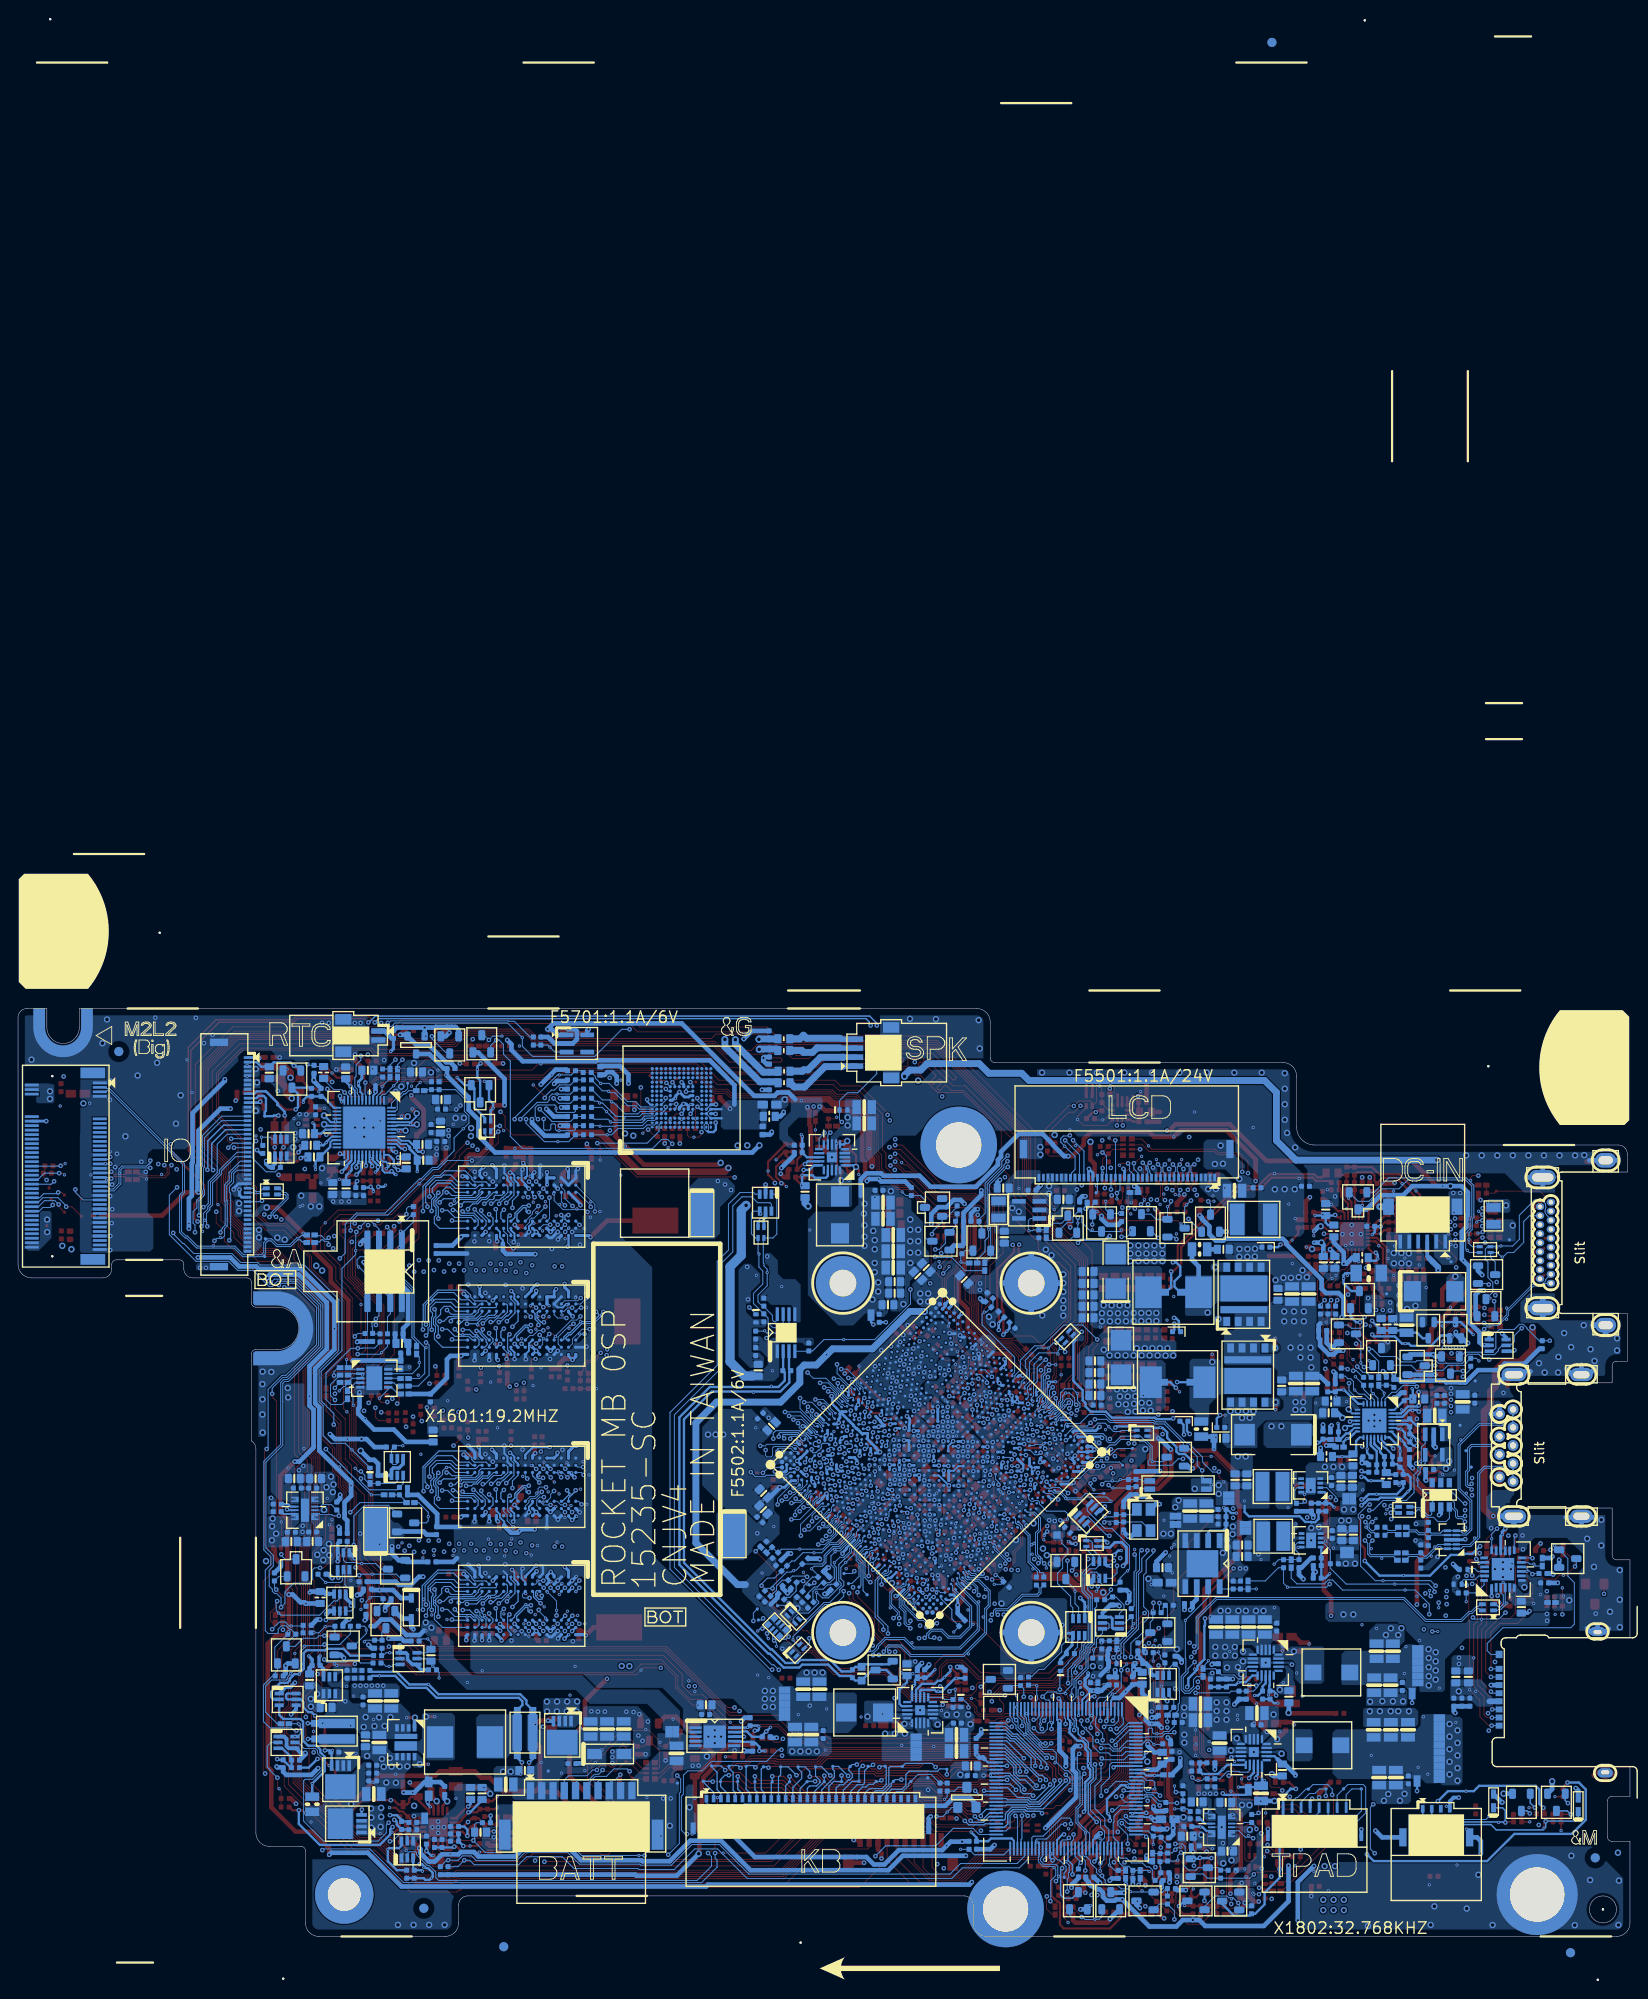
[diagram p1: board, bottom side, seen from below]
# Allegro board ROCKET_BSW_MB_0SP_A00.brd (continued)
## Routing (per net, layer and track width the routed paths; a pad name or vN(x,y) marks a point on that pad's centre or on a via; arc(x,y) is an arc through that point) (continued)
SPI_WP_CPU: length 125.8
  TOP w0.102: v1(141.53,79.15) 142.15,79.15 142.2,79.2 R2531.2 ; v1(82.09,86.52) 82.01,86.44 81.38,86.44 v2(80.83,85.9) 80.58,85.64 80.25,85.64 76.83,82.21 72.75,82.21 72.65,82.1 71.83,82.1 70.77,81.04 70.77,76.38 72.23,74.91 72.23,73.33 72.25,73.3 72.25,73.29 72.83,72.72 72.83,70.57 72.49,70.23 72.49,67.98 70.27,65.77 68.67,65.77 66.21,63.31 65.25,63.31 64.95,63 64.95,62.43 v1(64.61,62.09)
  L3 w0.127: v1(141.53,79.15) 141.53,78.98 141.66,78.85 142.31,78.85 142.44,78.97 142.44,79.4 142.54,79.51 142.97,79.51 143.26,79.8 143.26,80.05 143.1,80.21 141.72,80.21 141.6,80.08 141.6,79.79 141.47,79.67 141.21,79.67 141.09,79.79 141.09,80.08 140.96,80.21 140.71,80.21 140.58,80.08 140.58,79.52 140.45,79.39 140.2,79.39 140.07,79.52 140.07,80.08 139.94,80.21 139.16,80.21 139.07,80.12 139.07,79.98 139.46,79.59 139.46,79.13 139.31,78.98 138.7,78.98 138.25,79.44 137.69,79.44 133.69,83.43 133.32,83.43 130.81,85.94 129.34,85.94 128.69,86.59 124.58,86.59 124.23,86.95 123.76,86.95 123.45,87.27 115.45,87.27 115.13,86.95 101.9,86.95 101.77,87.08 101.77,87.39 101.65,87.51 101.39,87.51 101.27,87.39 101.27,87.08 101.14,86.95 100.89,86.95 100.76,87.08 100.76,87.59 100.66,87.7 100.35,87.7 100.25,87.59 100.25,87.08 100.12,86.95 95.59,86.95 95.46,87.08 95.46,87.41 95.33,87.53 95.08,87.53 94.95,87.41 94.95,87.08 94.83,86.95 94.55,86.95 94.44,87.06 94.44,87.42 94.32,87.54 93.99,87.54 93.86,87.42 93.86,86.99 93.73,86.86 93.48,86.86 93.35,86.99 93.35,87.43 93.22,87.56 93,87.56 90.25,90.3 88.93,90.3 87.26,91.96 86.39,91.96 85.13,90.7 85.13,89.29 84.98,89.15 84.8,89.15 84.41,89.54 84.23,89.54 84.05,89.36 84.05,89.18 84.44,88.79 84.44,88.61 84.26,88.43 84.08,88.43 83.69,88.82 83.51,88.82 83.33,88.64 83.33,88.46 83.72,88.07 83.72,87.89 82.35,86.52 v1(82.09,86.52)
  BOTTOM w0.102: v1(64.61,62.09) 64.91,61.79 64.91,60.02 65.19,59.74 65.19,59.38
SPI_WP_ROM: length 11
  TOP w0.102: v2(137.93,76.19) 138.31,75.81 v1(138.31,75.76) 138.03,75.48 138.03,74.96 138.29,74.71 138.4,74.71 138.99,74.13 RN2501.3 ; v1(140.97,78.71) 141.7,78.71 141.81,78.82 142.2,78.82 R2531.1
  BOTTOM w0.102: v1(140.97,78.71) 140.22,79.46 139.78,79.46 138.85,78.53 SSKT1.3 138.85,76.58 138.31,76.04 v1(138.31,75.76)
SUS_PWR_ACK_R: length 3.7
  BOTTOM w0.102: U2401.25 65.98,26.07 65.76,26.29 65.76,26.71 65.84,26.79 v2(65.84,27.84) 65.9,27.9 R2411.2
SUS_PWRDN_ACK: length 23.6
  TOP w0.102: v1(62.44,32.93) 62.44,33.17 61.4,34.22 54.93,34.22 v2(52.96,36.18) 52.96,36.96 v1(52.89,37.03)
  BOTTOM w0.102: v1(62.44,32.93) 63.07,32.31 63.07,31.62 63.09,31.59 65.04,29.65 65.6,29.65 66.38,28.87 66.68,28.87 R2411.1 ; v1(52.89,37.03) 52.89,35.98 R1811.2 52.96,35.9 52.96,35.16 53.24,34.87 Q1811.D 54.39,32.58 R1858.1
SUS_PWRDN_ACK_CPU: length 57.6
  TOP w0.102: v1(59.13,66.26) 59.13,65.64 59.6,65.17 59.6,61.67 59.21,61.28 59.21,58.35 59.05,58.19 56.46,58.19 55.93,57.66 53.29,57.66 v2(52.12,56.49) 51.88,56.25 v1(51.88,55.76)
  L4 w0.127: v1(51.88,55.76) 52.16,55.47 53.2,55.47 54.86,53.81 54.86,52.6 55.4,52.06 55.4,48.98 55.83,48.55 55.83,44.92 56.14,44.62 56.14,44.02 54.98,42.86 54.81,42.86 54.53,42.58 54.53,39.59 53.69,38.76 53.69,38.48 v1(52.22,37.01)
  BOTTOM w0.102: v1(52.22,37.01) 52.22,36.13 R1811.1 51.82,36.16 51.82,36.51 R1850.1 51.34,36.52 Q1811.S ; v1(59.13,66.26) 60.73,67.87 62.86,67.87 65.17,65.56 66.07,65.56 67.66,63.97 67.66,62.88 68.27,62.27 68.27,61.95 68.47,61.75 CPU1.AE3
SUSPWRDNACK_SOC_EC: length 131.4
  TOP w0.102: v1(148.01,22.86) 148.01,22.77 148.16,22.61 v2(148.16,22.18)
  L3 w0.102: v1(55.74,10.28) 55.88,10.14 59.88,10.14 61.49,11.75 63.33,11.75 64.69,10.39 69.49,10.39 70.18,11.08 70.86,11.08 71.56,10.39 73.64,10.39 73.94,10.09 74.3,10.09 75.01,10.8 85.55,10.8 85.89,11.14 88.23,11.14 89.16,10.21 91.81,10.21 92.2,10.6 93.65,12.05 94.6,12.05 94.6,12.05 98.63,12.05 100.5,13.93 102.77,13.93 103.15,14.3 103.65,14.3 104.24,13.71 105,13.71 105.21,13.5 107.28,13.5 107.62,13.84 109.76,13.84 110.51,13.09 114.56,13.09 120.14,7.51 130.78,7.51 132.08,6.21 135.44,6.21 139.61,10.39 140.38,10.39 147.45,17.45 147.45,20.39 147.45,20.39 147.45,21.15 148.01,21.71 v1(148.01,22.86)
  BOTTOM w0.102: U2401.100 55.71,12.51 56.2,13 56.58,13 56.83,12.75 56.83,12.36 55.75,11.28 55.75,11.14 55.74,11.13 v1(55.74,10.28) ; R4016.1 150.41,32.1 150.41,30.6 Q4020.G 150.1,29.52 150.36,29.27 R4011.2 150.65,28.92 151.61,27.95 151.61,27.92 151.67,27.87 151.67,23.86 150.96,23.15 148.58,23.15 148.29,22.86 v1(148.01,22.86)
SYS_PRES1#: length 5.5
  TOP w0.102: v2(113.06,17.27) 113.06,17.27 R4301.2 112.05,17.37 v1(112.05,17.95)
  BOTTOM w0.102: v1(112.05,17.95) 112.68,17.33 114.41,17.33 114.53,17.22 BATT1.7
SYS_PWROK: length 386.9
  TOP w0.102: R2426.2 60.66,7.11 v1(60.45,7.32)
  L3 w0.127: v1(60.45,7.32) 60.15,7.32 59.26,6.42 59.26,6.13 59.26,6.13 59.26,5.76 59.26,5.76 59.26,5.72 58.42,4.89 58.42,4.81 58.4,4.79 58.4,3.75 57.44,2.78 54.66,2.78 54.58,2.71 54.21,2.71 54.14,2.78 49.71,2.78 49.31,3.18 48.31,3.18 47.68,2.55 39.89,2.55 36.92,5.52 25.19,5.52 17.18,13.53 17.18,25.3 16.6,25.88 16.6,30.82 15.91,31.51 15.91,33.55 15.69,33.78 15.69,35.85 14.24,37.31 14.24,38.04 15.69,39.49 15.69,43.89 16.08,44.28 16.08,58.32 14.75,59.64 14.75,60.95 14.71,60.99 14.71,62.81 13.9,63.62 13.9,64.02 13.9,64.02 13.9,64.44 13.9,65.02 12.73,66.19 12.73,67.76 12.73,68.16 13.35,68.78 13.35,77.64 14.82,79.11 14.82,82 16.42,83.61 17.74,83.61 19,84.87 21.78,84.87 23.71,86.79 37.59,86.79 40.13,89.33 47.01,89.33 48.27,88.07 55.47,88.07 57.27,86.26 57.99,86.26 58,86.25 59.09,86.25 59.1,86.26 61.13,86.26 61.71,85.68 68.42,85.68 68.78,86.04 v1(69.08,86.04) 69.54,86.49 69.54,90.09 75.73,96.29 79.58,96.29 82.58,99.29 93.2,99.29 94.6,100.69 110.17,100.69 110.64,100.21 129.01,100.21 131.09,98.13 139.84,98.13 v1(140.07,97.9)
  L4 w0.127: v1(161.68,78.09) 162.3,78.72 170.68,78.72 172.46,80.49 172.46,81.77 173.02,82.33 173.02,84.07 172.46,84.63 172.46,94.08 165.9,100.64 156.55,100.64 155.97,100.05 143.11,100.05 141.41,98.36 140.53,98.36 v1(140.07,97.9)
  BOTTOM w0.102: U2401.84 61.18,9.14 61.04,9 61.04,8.94 60.95,8.85 60.89,8.85 60.45,8.41 v1(60.45,7.32) ; R4029.1 139.83,51.61 139.84,51.62 EC2402.1 v2(141.84,54.01) 142.57,54.73 144.16,54.73 145.03,55.61 145.03,58.9 145.49,59.36 145.49,62.86 143.31,65.04 143.31,70.72 147.05,74.46 147.23,74.46 147.3,74.53 152.02,74.53 152.3,74.8 154.17,74.8 155.16,75.8 159.39,75.8 160.51,76.93 160.61,76.93 161.57,77.89 161.57,77.98 v1(161.68,78.09) ; R2609.2 72.45,75.14 71.58,76.01 71.58,77.23 71.18,77.63 71.18,78.59 71.34,78.74 71.34,83.51 69.48,85.36 69.48,85.64 v1(69.08,86.04)
SYS_PWROK_G: length 3.3
  BOTTOM w0.102: R2609.1 74.14,74.75 v2(74.26,74.87) 74.26,75.66 R2607.1 73.8,76.12 Q2603.G
T_CRIT#: length 27.5
  L3 w0.102: v1(79.86,71.82) 79.86,72.72 v1(77.12,75.46)
  BOTTOM w0.102: v1(77.12,75.46) 77.03,75.36 75.26,75.36 73.8,73.9 R2601.1 ; U2601.4 91.17,64.96 R2606.2 90.72,64.99 89.45,66.25 v2(87.27,66.25) 83.83,66.25 79.86,70.22 v1(79.86,71.82)
THERM_SYS_SHDN#: length 185.7
  TOP w0.102: v1(53.79,3.34) 54.35,3.91 v2(54.68,3.91) 55.1,3.91 R2602.1
  L3 w0.102: v1(69.05,85.41) 61.65,85.41 61.03,86.02 59.2,86.02 59.19,86.01 57.9,86.01 57.89,86.02 57.17,86.02 55.39,87.81 48.19,87.81 46.91,89.08 40.23,89.08 37.69,86.55 23.81,86.55 21.88,84.62 19.1,84.62 17.75,83.27 16.43,83.27 15.06,81.9 15.06,79.01 13.59,77.54 13.59,68.68 12.97,68.06 12.97,67.86 12.97,66.33 14.14,65.16 14.14,64.34 14.14,63.72 14.96,62.91 14.96,61.09 15,61.05 15,59.74 16.32,58.42 16.32,44.29 17.49,43.12 17.49,41.72 17.24,41.47 17.23,41.47 16.31,40.55 16.31,34.03 16.54,33.81 16.54,31.77 17.22,31.08 17.22,26.14 17.81,25.56 17.81,13.79 25.39,6.21 25.59,6.21 37.11,6.21 40.15,3.17 47.42,3.17 48.05,3.81 49.12,3.81 49.12,3.81 49.9,3.81 50.16,4.06 50.55,4.06 51.27,3.34 v1(53.79,3.34)
  BOTTOM w0.102: R2601.2 70.95,75.45 Q2603.S 70.95,78.68 71.11,78.84 71.11,83.41 69.12,85.41 v1(69.05,85.41)
TOUCH_PANEL_EN: length 166.4
  TOP w0.102: v2(66.98,24.72) R2427.2 66.04,24.72 65.74,24.42 65.74,23.78 65.81,23.71 65.81,23.38 65.46,23.03 v1(65.27,23.03)
  L3 w0.102: v1(65.27,23.03) 67.22,21.08 70.72,21.08 72.5,19.3 81.85,19.3 82.81,18.34 84.5,18.34 84.9,17.94 85.26,17.94 85.39,18.06 85.41,18.06 86.65,19.3 94,19.3 96.69,21.99 96.69,23.1 98.36,24.77 98.36,26.93 100.3,28.87 105.19,28.87 106.59,27.47 113.71,27.47 115.29,29.05 130.56,29.05 131.83,30.33 137.95,30.33 139.28,31.65 139.28,32.59 139.81,33.12 140.62,33.12 141.48,33.98 141.48,35.59 142.69,36.8 142.69,42.01 143.21,42.54 143.21,44.32 145.88,46.99 145.88,48.23 146.21,48.57 146.21,50.84 146.21,51.03 145.45,51.78 145.45,55.1 145.35,55.2 145.35,63.46 145.35,63.46 143.93,64.88 143.93,74.9 144.06,75.04 147.41,78.38 150.49,78.38 151.86,79.75 154.64,79.75 154.82,79.93 157.22,79.93 157.99,80.7 158.08,80.7 v1(158.33,80.95)
  BOTTOM w0.102: IOBD1.18 155.68,89.05 156.79,87.94 156.79,84.79 157.78,83.8 157.78,81.36 158.19,80.95 v1(158.33,80.95) ; v1(65.27,23.03) 65.46,23.21 65.46,24.15 65.18,24.42 U2401.23
TP_CLK: length 17
  TOP w0.102: R6509.2 38.46,5.87 33.48,10.86 33.48,15.31 v1(33.76,15.6)
  BOTTOM w0.102: TPAD1.3 36.5,14.92 35.55,15.87 34.95,15.87 34.45,16.37 AFTP6232.1 33.74,15.62 v1(33.76,15.6)
TP_CLK_C: length 19.7
  TOP w0.102: RN6502.3 39.17,13.99 38.53,14.62 37.05,14.62 35.91,13.48 35.91,11.34 v1(35.75,11.18)
  BOTTOM w0.102: v1(35.75,11.18) 35.74,11.17 32.57,11.17 31.1,12.64 29.82,13.92 AFTP6229.1 30.86,16.37 31.5,15.73 TPAD1.8
TP_DAT: length 20
  TOP w0.102: R6508.2 38.61,5.04 32.91,10.74 32.91,15.58 v1(33.05,15.72)
  BOTTOM w0.102: v1(33.05,15.72) 33.05,16.37 33.54,16.86 35.18,16.86 AFTP6231.1 35.96,16.35 36.88,15.43 37.04,15.43 37.5,14.97 TPAD1.2
TP_DATA_C: length 21.7
  TOP w0.102: RN6502.4 38.52,13.85 38.23,14.14 37.25,14.14 36.4,13.28 v1(36.4,11.18)
  BOTTOM w0.102: v1(36.4,11.18) 36.4,10.9 36.17,10.67 32.36,10.67 29.33,13.7 29.33,16.58 29.62,16.87 31.3,16.87 AFTP6230.1 32.5,15.67 TPAD1.7
TP_DISABLE#: length 25.5
  TOP w0.102: v2(53.72,15.66) 53.53,15.47 v1(53.53,15.05) R2494.1
  L3 w0.102: v1(34.77,11.81) 35.26,12.29 39.38,12.29 39.89,12.8 41.8,12.8 41.93,12.93 44.65,12.93 44.88,13.16 45.74,13.16 46.49,12.41 47.81,12.41 49.18,13.78 50.55,13.78 50.71,13.95 53.02,13.95 53.53,14.46 v1(53.53,15.05)
  BOTTOM w0.102: TPAD1.6 33.5,13.08 v1(34.77,11.81)
TP_DISABLE#_R: length 3.3
  TOP w0.102: R2494.2 v2(55.19,13.61) 55.44,13.36 v1(55.95,13.36)
  BOTTOM w0.102: U2401.101 55.52,12.91 55.75,13.14 55.75,13.16 v1(55.95,13.36)
TP_I2C_CLK: length 20.1
  TOP w0.102: R6509.1 40.45,5.87 EC6505.1 40.74,5.82 v1(41.16,5.4) 41.64,5.87 v2(41.64,5.9) ; v1(52.67,7.68) 52.91,7.92 Q1622.1 52.91,9.81 53.02,9.93 R1623.2 53.02,10.86 52.77,11.11 51.76,11.11 51.46,10.81 R1618.2
  L3 w0.127: v1(41.16,5.4) 43.41,5.4 43.91,5.9 48.61,5.9 48.82,6.1 49.11,6.1 50.24,7.23 50.69,7.23 50.88,7.42 52.41,7.42 v1(52.67,7.68)
TP_I2C_CLK_D: length 10
  TOP w0.102: R1616.2 51.77,3.89 R1619.1 53.07,4.42 53.07,5.7 52.91,5.85 Q1622.6 53.53,7.41 R1621.2 54.72,7.41 v2(55.17,6.96) 55.65,6.48 57.33,6.48 57.63,6.78 Q1606.6
TP_I2C_DATA: length 16.8
  TOP w0.102: R6508.1 39.73,5.11 EC6504.1 40.76,5.11 v1(41.18,4.68) v2(41.74,4.68) ; R1622.2 51.74,4.78 R1619.2 52.54,5.53 51.61,6.47 Q1622.4 51.13,6.79 50.34,6 v1(50.28,6)
  L3 w0.127: v1(50.28,6) 49.87,5.59 49.03,5.59 48.82,5.39 47.93,5.39 47.93,5.39 44.16,5.39 43.66,4.89 41.38,4.89 v1(41.18,4.68)
TP_I2C_DATA_D: length 19
  TOP w0.102: v1(48.39,7.85) v2(48.39,8.55) 48.84,8.55 49.15,8.24 R1610.2 49.43,8.25 R1620.2 50.77,8.25 50.98,8.46 50.98,9.6 R1618.1 51.61,9.62 Q1622.3 ; v1(55.04,9.43) 55.21,9.43 55.53,9.11 Q1606.3
  L3 w0.127: v1(48.39,7.85) 47.72,7.85 47.16,8.42 47.16,8.93 48.94,10.71 50.64,10.71 50.77,10.59 50.88,10.59 51.1,10.36 52.61,10.36 53.18,9.79 54.32,9.79 54.68,9.43 v1(55.04,9.43)
TP_ON#: length 50.4
  TOP w0.102: v1(51.36,23.18) 51.36,22.78 50.83,22.26 50.83,15.76 50.53,15.46 50.15,15.46 49.83,15.14 49.83,14.39 v2(49.51,14.06) 46.89,11.45 46.89,10.05 46.53,9.69 46.53,9.25 47.34,8.43 47.34,7.73 50.4,4.67 50.4,4.3 50.39,4.29 50.39,3.64 50.55,3.48 50.55,2.82 49.07,1.35 47.61,1.35 46.75,2.21 R6516.1 ; R2407.2 68.84,23.06 v1(68.61,23.28)
  L3 w0.102: v1(51.36,23.18) 51.94,23.76 55.04,23.76 55.68,24.4 60.4,24.4 60.42,24.38 65.22,24.38 65.99,23.62 66.4,23.62 66.58,23.8 67.66,23.8 68.17,23.28 v1(68.61,23.28)
  BOTTOM w0.102: v1(68.61,23.28) 68.93,23.28 69.36,23.71 U2401.33
TP_ON#_GATE: length 14
  TOP w0.102: C6505.1 45.03,3.34 C6504.1 44.81,3.13 43.95,3.13 43.47,3.61 v1(43.47,3.72) 43.92,4.17 v2(44.22,4.17) ; C6505.1 45.86,2.53 R6516.2 ; C6505.1 45.86,3.77 46.48,4.39 Q6507.2 Q6507.5
  BOTTOM w0.102: 43.47,3.71 44.05,4.29 44.52,4.29 44.71,4.48 46.05,4.48 47.22,3.32 Q6504.G ; 43.47,3.71 v1(43.47,3.72) ; 43.47,3.71 43.36,3.61 Q6503.G
TP_VDD: length 57.4
  TOP w0.254: R1623.1 52.14,9.93 v1(52.07,9.86) 52.07,9.55 52.26,9.35 Q1622.2 52.16,8.58 52.16,7.23 52.26,7.14 Q1622.5 ; v1(47.72,8.73) 47.72,7.78 48.32,7.18 48.75,7.18 48.93,7.36 R1610.1 49.42,6.09 50.21,5.31 50.3,5.31 R1622.1 50.84,4.76 R1616.1 ; v1(37.08,16.38) 37.8,17.1 EC6502.1 ; R6505.1 46.83,8.33 v1(46.46,8.7) ; RN6503.2 39.22,7.78 v1(38.89,7.45) 38.57,7.77 RN6503.1 38.57,8.45 38.16,8.86 R6512.1 ; v1(54.99,8.65) 54.84,8.49 R6504.1
  L3 w0.254: v1(54.99,8.65) 54.17,9.48 53.05,9.48 52.66,9.86 v1(52.07,9.86) 51.21,9 50.22,9 50.04,8.82 49.22,8.82 49,8.6 47.85,8.6 v1(47.72,8.73) ; v1(46.46,8.7) 46.25,8.49 46.25,8.37 45.39,7.51 41.57,7.51 41.08,7.03 40.14,7.03 40.02,7.15 39.19,7.15 v1(38.89,7.45)
  BOTTOM w0.254: v1(37.08,16.38) AFTP6228.1 38.5,15.53 TPAD1.1 38.5,13.05 38.89,12.67 v1(38.89,7.45) 38.89,6.52 40.55,4.85 40.55,3.56 41.6,2.52 R6513.1 42.22,2.31 43.96,2.31 45.27,3.62 Q6503.D ; Q6502.G 47.84,8.61 v1(47.72,8.73) 47.7,8.7 v1(46.46,8.7)
TP_VDD_1D8V: length 143.1
  TOP w0.254: v1(29.43,41.68) 29.43,43.05 29.93,43.55 29.93,46.44 v1(29.73,46.64) ; R6506.1 50.04,3.87 v1(50.04,3.36) 50.04,2.95 49.58,2.49 R6518.1
  L3 w0.254: v1(16.64,43.31) 16.01,42.68 16.01,33.91 16.23,33.69 16.23,31.64 16.92,30.95 16.92,26.02 17.5,25.43 17.5,13.66 25.32,5.84 37.05,5.84 40.03,2.87 47.54,2.87 48.18,3.5 49.9,3.5 v1(50.04,3.36) ; v1(50.7,57.51) 51.37,56.84 51.37,55.54 51.48,55.43 51.48,53.61 48.95,51.07 45.69,51.07 44.59,49.96 44.59,46.8 44.25,46.46 v1(44.05,46.46)
  L4 w0.254: v1(29.73,46.64) 30.81,45.56 32.52,45.56 34.23,47.26 42.63,47.26 43.43,46.46 v1(44.05,46.46)
  BOTTOM w0.254: 61.52,66.19 61.77,65.94 61.77,61.66 60.74,60.63 60.74,59.52 60.43,59.21 60.43,58.85 59.84,58.25 58.17,58.25 57.51,57.58 52.71,57.58 52.55,57.42 50.78,57.42 v1(50.7,57.51) ; v1(50.04,3.36) 49.46,3.94 Q6504.D ; v1(29.43,41.68) 27.8,40.05 v2(25.13,40.05) 22.19,40.05 19.89,42.35 18.48,42.35 18.36,42.47 17.48,42.47 v1(16.64,43.31)
TPCLK: length 35.6
  TOP w0.102: v1(40.23,10.17) 39.5,9.45 RN6503.3 39.22,10.73 EC6501.1 39.47,11.55 39.17,11.86 RN6502.2 ; v1(62.69,12.45) 62.69,12.32 v2(62.31,11.94)
  L3 w0.127: v1(62.69,12.45) 62.69,12.82 62.54,12.97 61.75,12.97 61.39,12.6 61.28,12.6 59.57,10.89 56.48,10.89 56.14,11.23 56.06,11.23 56.06,11.24 55.12,11.24 54.5,10.62 53.43,10.62 52.92,11.13 51.42,11.13 51.19,11.35 51.09,11.35 50.96,11.47 48.56,11.47 47.81,10.72 46.15,10.72 45.57,11.31 43.41,11.31 42.28,10.17 v1(40.23,10.17)
  BOTTOM w0.102: U2401.72 65.98,10.66 65.83,10.81 64.74,10.81 63.11,12.45 v1(62.69,12.45)
TPDATA: length 37.8
  TOP w0.102: v2(40.57,8.85) 40.57,9.17 v1(40.26,9.48) 39.63,8.84 38.76,8.84 38.57,9.03 RN6503.4 38.57,10.88 EC6503.1 38.68,11.6 38.52,11.76 RN6502.1
  L3 w0.127: v1(62.04,12.51) 61.62,12.1 61.49,12.1 59.78,10.38 56.82,10.38 56.27,10.38 55.93,10.73 55.85,10.73 55.85,10.73 55.53,10.73 54.89,10.09 53.25,10.09 52.71,10.62 51.21,10.62 50.98,10.84 50.88,10.84 50.75,10.97 48.77,10.97 48.02,10.22 45.94,10.22 45.36,10.8 43.62,10.8 42.49,9.67 40.45,9.67 v1(40.26,9.48)
  BOTTOM w0.102: v1(62.04,12.51) 62.04,12.96 62.22,13.14 63.11,13.14 65.12,11.13 66.21,11.13 66.38,10.96 U2401.71
UART1_CTS: length 3
  TOP w0.102: TP1610.1 70.96,58.76 71.27,58.45 v1(71.27,57.44)
  BOTTOM w0.102: CPU1.AD13 71.44,57.62 v1(71.27,57.44)
UART1_RTS: length 2.4
  TOP w0.102: TP1611.1 71.69,58.51 71.69,57.05 v1(71.74,57)
  BOTTOM w0.102: v1(71.74,57) 71.85,57.12 CPU1.AD14
UART1_RX: length 1.7
  TOP w0.102: v1(83.47,40.42) 83.48,40.41 TP802.1
  BOTTOM w0.102: v1(83.47,40.42) CPU1.T52
UART1_RXD: length 3.6
  TOP w0.102: v1(70.78,57.94) 70.78,58.51 70.56,58.73 70.56,60.25 TP1609.1
  BOTTOM w0.102: 71.28,58.12 71.26,58.1 70.94,58.1 v1(70.78,57.94)
UART1_TX: length 1.2
  TOP w0.102: TP801.1 82.07,41.11 v1(81.67,41.51)
  BOTTOM w0.102: v1(81.67,41.51) 82.03,41.51 CPU1.T51
UART1_TXD: length 3.7
  TOP w0.102: v1(70.27,58.44) 70.27,59.76 TP1608.1
  BOTTOM w0.102: v1(70.27,58.44) 70.45,58.63 70.78,58.63
USB3_OBSN: length 1.9
  TOP w0.102: R1642.1 73.15,44.15 v1(72.71,44.6) 72.68,44.63 72.25,44.63 v2(72.16,44.72)
  BOTTOM w0.102: v1(72.71,44.6) 72.73,44.58 CPU1.F34
USB3_OBSP: length 1.3
  TOP w0.102: v1(72.19,44.1) 72.57,43.72 R1642.2
  BOTTOM w0.102: v1(72.19,44.1) 72.23,44.07 CPU1.D34
USB30_RX_CON_N0: length 22.1
  BOTTOM w0.102: v2(22.05,42.21) 22.18,42.34 ; 22.18,42.34 22.53,41.99 23,41.99 C3511.1 23.61,42.17 24.52,42.17 R3502.2 ; 22.18,42.34 21.45,43.07 21.22,43.3 21.07,43.3 20.81,43.03 EU3501.10 EU3501.1 18.77,43.03 18.5,43.3 17.67,43.3 17,43.97 16.67,44.3 16.67,51.39 16.09,51.97 14.3,51.97 13.68,51.35 13.14,51.35 12.98,51.18 USB1.5
USB30_RX_CON_P0: length 21.7
  BOTTOM w0.102: R3503.2 24.74,42.38 23.42,42.38 C3510.1 22.83,42.2 22.62,42.2 21.31,43.51 EU3501.9 EU3501.2 17.76,43.51 17.15,44.12 ; 17.15,44.12 16.89,44.39 16.89,51.48 16.18,52.19 14.21,52.19 13.59,51.56 13.23,51.56 12.98,51.82 USB1.6 ; 17.15,44.12 v2(17.25,44.22)
USB30_RX_CPU_N0: length 55.1
  L3 w0.114: v1(70.31,45.01) 70.37,44.95 70.37,41.01 69.57,40.21 63.75,40.21 63.26,39.72 61.25,39.72 60.64,40.33 58.49,40.33 58.05,39.89 55.85,39.89 54.54,41.19 44.58,41.19 44.26,41.51 41.96,41.51 41.67,41.23 36.18,41.23 34.32,43.09 29.5,43.09 29.03,43.56 29.03,43.94 29.13,44.05 29.31,44.05 v1(29.41,43.95)
  BOTTOM w0.102: v1(29.41,43.95) 29.1,43.64 29.1,42.43 28.82,42.15 27.55,42.15 ; CPU1.D28 70.41,45.53 70.41,45.11 v1(70.31,45.01) ; 27.55,42.15 26.21,42.15 R3502.1 ; 27.55,42.15 v2(27.55,41.98)
USB30_RX_CPU_P0: length 55.4
  L3 w0.114: v1(28.58,43.94) 28.8,43.72 28.8,43.46 29.4,42.86 34.22,42.86 36.09,41 41.77,41 42.06,41.28 44.17,41.28 44.48,40.97 54.45,40.97 55.75,39.66 58.14,39.66 58.58,40.1 60.54,40.1 61.15,39.49 63.35,39.49 63.85,39.99 69.67,39.99 70.6,40.92 70.6,44.71 70.73,44.84 70.73,45.42 v1(70.83,45.53)
  BOTTOM w0.102: 28.89,43.05 v2(28.71,43.05) ; 28.89,43.05 28.89,42.52 28.73,42.37 26.02,42.37 R3503.1 ; 28.89,43.05 28.89,43.64 v1(28.58,43.94) ; v1(70.83,45.53) 70.73,45.63 CPU1.F28
USB30_TX_CMC_N0: length 1.7
  BOTTOM w0.102: C3506.2 26.88,44.84 25.96,44.84 R3509.1
USB30_TX_CMC_P0: length 1.8
  BOTTOM w0.102: R3512.1 26.07,45.06 26.83,45.06 C3505.2
USB30_TX_CON_N0: length 26
  BOTTOM w0.102: R3509.2 24.53,44.91 23.78,44.91 23.46,44.59 22.7,44.59 C3509.1 22.08,44.55 EU3501.7 EU3501.4 18.14,44.55 17.55,45.15 17.55,48.39 18.26,49.1 ; v2(18.16,49.2) 18.26,49.1 ; 18.26,49.1 18.86,49.7 18.86,54.54 18.69,54.71 17.09,56.31 16.66,56.75 14.17,56.75 13.51,57.4 13.2,57.4 12.98,57.18 USB1.8
USB30_TX_CON_P0: length 26.2
  BOTTOM w0.102: 18.68,55.03 19.08,54.63 19.08,49.61 17.77,48.3 17.77,45.24 18.23,44.77 18.59,44.77 18.86,45.03 EU3501.5 EU3501.6 20.77,45.03 21.04,44.77 22.07,44.77 C3508.1 22.65,44.8 23.37,44.8 23.69,45.12 24.53,45.12 R3512.2 ; 18.68,55.03 v2(18.79,55.13) ; 18.68,55.03 16.75,56.96 14.26,56.96 13.6,57.62 13.17,57.62 12.98,57.81 USB1.9
USB30_TX_CPU_N0: length 53.2
  L3 w0.114: v1(68.9,41.84) 68.9,41.4 68.82,41.33 67.2,41.33 66.81,40.94 62.55,40.94 62.15,41.33 61.6,41.33 61.32,41.05 58.19,41.05 57.75,40.61 56.15,40.61 54.85,41.92 44.88,41.92 44.56,42.24 41.66,42.24 41.39,41.96 36.54,41.96 34.66,43.85 30.27,43.85 30.13,43.98 30.13,44.2 30.27,44.34 31.71,44.34 31.99,44.62 31.99,45.01 31.71,45.29 29.48,45.29 29.2,45.58 29.2,45.83 v1(29.37,46)
  BOTTOM w0.102: CPU1.C32 70.9,43.77 70.7,43.57 70.52,43.57 70.35,43.4 70.35,43.05 69.13,41.84 v1(68.9,41.84) ; v1(29.37,46) 29.17,45.8 29.17,45.44 ; 29.17,45.44 v2(29.31,45.44) ; 29.17,45.44 29.17,45.25 28.73,44.82 28.37,44.82 C3506.1
USB30_TX_CPU_P0: length 53.4
  L3 w0.114: v1(69.33,41.4) 69.21,41.4 68.91,41.1 67.29,41.1 66.9,40.71 62.45,40.71 62.06,41.11 61.69,41.11 61.41,40.83 58.28,40.83 57.84,40.38 56.06,40.38 54.75,41.69 44.78,41.69 44.47,42.01 41.76,42.01 41.48,41.73 36.45,41.73 34.57,43.62 30.18,43.62 29.91,43.89 29.91,44.3 30.18,44.57 31.62,44.57 31.76,44.71 31.76,44.92 31.62,45.06 29.38,45.06 28.97,45.48 28.97,45.81 28.78,46 v1(28.6,46)
  BOTTOM w0.102: CPU1.B32 70.56,43.2 70.56,42.96 69.27,41.67 69.27,41.45 v1(69.33,41.4) ; C3505.1 28.47,45.03 28.64,45.03 28.95,45.34 28.95,45.85 28.8,46 v1(28.6,46) 28.22,46.38 v2(28.2,46.38)
USB_CON_PN0: length 23.7
  L3 w0.114: v1(18.31,46.03) 18.11,46.24 17.86,46.24 17.57,46.53 17.57,48.33 18.24,49 18.24,49.61 18.07,49.79 17.75,49.79 v1(17.58,49.61)
  BOTTOM w0.102: 18.02,53.92 18.02,51.83 18.23,51.62 18.23,50.06 18,49.82 17.79,49.82 v1(17.58,49.61) ; 18.02,53.92 AFTP3402.1 ; 18.02,53.92 18.02,54.21 17.61,54.61 15.37,54.61 USB1.2 ; TR3503.3 23.9,47.01 23.54,47.37 23.36,47.37 22.51,46.52 21.79,46.52 21.32,46.05 20.42,46.05 20.05,46.42 EU3505.3 19.87,47.67 19.36,47.17 19.36,46.6 19.13,46.37 18.65,46.37 v1(18.31,46.03)
USB_CON_PN1: length 2.4
  BOTTOM w0.102: TR6601.1 151.7,83.05 152.07,82.67 152.47,82.67 152.86,83.05 IOBD1.30
USB_CON_PN2: length 37.8
  BOTTOM w0.102: 151.65,75.6 AFTP6111.1 ; 151.65,75.6 151.42,75.83 151.42,76.94 151.15,77.22 150.84,77.22 150.19,76.57 148.63,76.57 147.87,77.33 147.6,77.33 147.37,77.09 146.93,77.09 R6103.1 ; 151.65,75.6 151.8,75.45 153.96,75.45 154.91,76.41 159.07,76.41 160.19,77.54 160.36,77.54 160.96,78.14 160.96,78.3 160.97,78.31 160.97,82.31 160.64,82.64 160.64,85.72 168.81,93.89 169.03,93.89 169.17,93.75 WLAN1.5
USB_CON_PN3: length 3.3
  BOTTOM w0.102: U3301.3 14.35,38.17 14.06,37.89 14.06,36.87 14.39,36.54 14.54,36.54 14.87,36.87 TR3301.4
USB_CON_PN4: length 4.1
  TOP w0.102: v1(54.07,85.88) 53.95,85.75 53.95,84.67 54.24,84.38 TR5501.1 54.24,83.97 54.34,83.87
  BOTTOM w0.102: v1(54.07,85.88) 53.72,85.53 53.72,85.14 53.51,84.93 53.51,84.7 53.6,84.61 LCD1.16
USB_CON_PP0: length 23.2
  L3 w0.114: v1(18.31,46.67) 18.11,46.47 17.96,46.47 17.8,46.62 17.8,48.24 18.47,48.9 18.47,49.71 18.16,50.01 17.81,50.01 v1(17.58,50.24)
  BOTTOM w0.102: USB1.3 15.38,54.4 17.52,54.4 17.8,54.12 17.8,52.09 ; TR3503.2 23.96,47.69 23.86,47.58 23.27,47.58 22.42,46.74 22.13,46.74 22.01,46.86 22.01,47.15 21.95,47.2 EU3505.1 21.95,48.24 21.7,48.49 19.8,48.49 19.48,48.17 19.48,47.59 19.15,47.26 19.15,46.69 19.04,46.59 18.39,46.59 v1(18.31,46.67) ; v1(17.58,50.24) 17.78,50.04 17.91,50.04 18.02,50.15 18.02,51.53 17.8,51.74 17.8,52.09 ; 17.8,52.09 AFTP3403.1
USB_CON_PP1: length 2.2
  BOTTOM w0.102: TR6601.4 151.44,82.45 152.56,82.45 152.66,82.55 IOBD1.31
USB_CON_PP2: length 37.8
  BOTTOM w0.102: WLAN1.3 169.15,94.25 169.01,94.1 168.72,94.1 160.43,85.81 160.43,82.55 160.75,82.22 160.75,78.4 160.74,78.39 160.74,78.23 160.27,77.75 160.1,77.75 158.98,76.62 154.82,76.62 153.87,75.67 151.89,75.67 151.64,75.92 151.64,77.03 151.34,77.33 ; 151.34,77.33 AFTP6113.1 ; 151.34,77.33 151.24,77.43 150.75,77.43 150.1,76.79 148.72,76.79 147.96,77.55 147.72,77.55 147.48,77.78 146.95,77.78 R6102.1
USB_CON_PP3: length 3.7
  BOTTOM w0.102: 13.85,37 v2(13.67,37) ; 13.85,37 U3301.4 ; 13.85,37 13.85,36.78 14.3,36.33 14.55,36.33 14.69,36.19 TR3301.1
USB_CON_PP4: length 4.5
  TOP w0.102: 53.46,83.86 53.55,83.96 TR5501.4 53.55,84.52 53.73,84.7 53.73,85.32 ; 53.73,85.32 53.73,85.57 53.42,85.88 v1(53.29,85.88) ; 53.73,85.32 v2(53.57,85.32)
  BOTTOM w0.102: v1(53.29,85.88) 53.5,85.67 53.5,85.23 53.29,85.02 53.29,84.77 53.1,84.58 LCD1.15
USB_CPU_PN0: length 59
  TOP w0.102: v2(27.1,46.92) 26.66,46.92 v1(26.55,47.02)
  L3 w0.114: v1(26.55,47.02) 26.55,47.11 26.65,47.21 27.06,47.21 27.13,47.14 27.13,43.03 29.68,40.49 33.88,40.49 35.54,38.83 37.63,38.83 38.25,39.45 52.57,39.45 53.11,38.91 54.41,38.91 55.12,38.2 56.88,38.2 57.69,37.39 59.73,37.39 60.37,38.03 63.93,38.03 64.45,38.54 69.93,38.54 70.34,38.13 71.41,38.13 71.68,38.4 72.27,38.4 72.38,38.29 72.38,37.98 v1(72.29,37.89)
  BOTTOM w0.089: v1(72.29,37.89) 72.38,37.98 72.38,38.79 72.9,39.3 73.54,39.3 CPU1.B42
  BOTTOM w0.102: TR3503.4 25.91,47.01 26.15,47.25 26.45,47.25 26.55,47.15 v1(26.55,47.02)
USB_CPU_PN1: length 134.5
  L3 w0.114: v1(84.47,31.79) 84.41,31.73 84.41,31.39 84.63,31.17 95.43,31.17 96.67,32.42 114.87,32.42 115.59,31.7 129.39,31.7 130.71,33.02 133.48,33.02 136.41,35.96 136.41,37.09 137.7,38.38 137.7,41.65 139.86,43.81 139.86,44.69 141.17,46 141.17,49.18 141.98,49.99 141.98,55.41 142.33,55.76 142.33,64.12 142.05,64.39 142.05,66.7 141.79,66.96 141.79,76.41 142.8,77.41 142.8,78.19 143.37,78.77 145.78,78.77 146.12,79.1 150.18,79.1 150.57,79.48 150.57,79.78 150.47,79.88 v1(150.26,79.88)
  BOTTOM w0.102: 79.81,32.49 80.49,33.17 82.7,33.17 83.62,32.26 83.62,32.08 84.03,31.66 84.34,31.66 v1(84.47,31.79) ; 79.81,32.49 79.44,32.12 74.38,32.12 72.44,34.06 72.44,36.76 74.76,39.08 CPU1.B44 ; 79.81,32.49 v2(79.69,32.61) ; v1(150.26,79.88) 150.44,79.88 150.6,80.03 150.6,80.23 148.94,81.89 148.94,82.35 149.16,82.58 149.42,82.58 149.89,83.05 TR6601.2
USB_CPU_PN2: length 127.7
  L3 w0.114: v1(144.42,76.78) 144.42,76.96 144.32,77.06 143.83,77.06 142.74,75.98 142.74,67.35 143,67.09 143,64.79 143.28,64.51 143.28,49.94 142.69,49.36 142.69,46.52 142.13,45.95 142.13,45.51 141.59,44.98 141.59,44.19 138.66,41.25 138.66,37.88 137.72,36.94 137.72,35.83 133.93,32.04 131.13,32.04 129.85,30.76 114.94,30.76 114.24,31.47 97.07,31.47 95.82,30.22 82.82,30.22 82.4,30.64 82.4,31.4 v1(82.19,31.6)
  BOTTOM w0.102: v1(144.42,76.78) 144.42,77.06 144.49,77.13 144.87,77.13 145.07,77.33 145.23,77.33 145.46,77.09 145.9,77.09 R6103.2 ; 73.54,31.49 73.96,31.07 79.86,31.07 80.92,32.13 82.22,32.13 82.4,31.95 82.4,31.81 v1(82.19,31.6) ; 73.54,31.49 v2(73.42,31.37) ; 73.54,31.49 71.4,33.63 71.4,36.3 71.01,36.69 71.01,38.39 72.26,39.65 72.6,39.65 72.76,39.8 73.35,39.8 CPU1.A41
USB_CPU_PN3: length 86.3
  L3 w0.114: v1(48.37,32.19) 48.37,32.14 48.74,31.78 49.62,31.78 50.05,31.35 50.15,31.35 50.75,30.74 53.43,30.74 53.82,30.35 57.89,30.35 58.31,30.78 59.97,30.78 60.4,30.35 60.4,27.92 60.6,27.71 61.54,27.71 61.72,27.54 62.43,27.54 63.3,28.4 69.51,28.4 71.05,29.94 73.6,29.94 75.65,32 77.16,32 77.79,32.63 77.79,33.26 77.69,33.37 77.32,33.37 77.22,33.26 v1(77.22,33.17)
  BOTTOM w0.102: TR3301.3 16.6,36.87 16.85,36.62 17.06,36.62 17.63,36.05 17.9,36.05 18.77,35.18 22.61,35.18 25.06,37.63 45.94,37.63 48.15,35.41 48.15,32.3 48.25,32.19 v1(48.37,32.19) ; 73.06,34.65 73.06,36.66 74.83,38.44 CPU1.A45 ; 73.06,34.65 73.06,34.34 74.29,33.11 75.68,33.11 76.45,33.89 77.47,33.89 77.83,33.53 77.83,33.18 77.73,33.08 77.31,33.08 v1(77.22,33.17) ; 73.06,34.65 v2(72.9,34.65)
USB_CPU_PN4: length 126.8
  TOP w0.102: v1(54.27,81.26) 54,81.53 54,82.07 54.24,82.31 TR5501.2 54.24,82.88 54.34,82.98
  L3 w0.114: v1(54.27,81.26) 54,80.99 54,80.45 53.63,80.09 48.34,80.09 47.95,80.48 46.97,80.48 45.56,81.89 36.49,81.89 35.37,83.01 31.88,83.01 30.45,81.59 25.19,81.59 22.66,79.06 22.66,77.42 22.18,76.93 22.18,73.03 20.94,71.79 20.94,69.67 25.69,64.92 25.69,59.7 25.82,59.57 25.82,55.55 26.94,54.43 26.94,50.4 28.09,49.24 28.09,43.46 29.2,42.35 34.02,42.35 35.97,40.41 53.06,40.41 53.12,40.47 54.22,40.47 55.53,39.16 58.35,39.16 58.79,39.61 60.32,39.61 60.93,38.99 63.55,38.99 64.05,39.49 70.26,39.49 70.6,39.15 71.03,39.15 71.39,39.51 v1(71.39,39.79)
  BOTTOM w0.102: v1(71.39,39.79) 71.46,39.86 72.53,39.86 72.73,40.06 73.13,40.06 73.31,40.23 73.51,40.23 73.68,40.4 73.68,40.54 73.88,40.75 CPU1.C40 ; v2(53.9,81.79) 53.9,81.64 v1(54.27,81.26)
USB_CPU_PP0: length 59.3
  L3 w0.114: v1(26.55,47.79) 26.9,47.43 27.16,47.43 27.36,47.23 27.36,43.13 29.77,40.72 33.98,40.72 35.63,39.06 37.53,39.06 38.15,39.68 52.67,39.68 53.21,39.14 54.5,39.14 55.21,38.43 56.97,38.43 57.78,37.62 59.64,37.62 60.27,38.25 63.84,38.25 64.35,38.77 70.02,38.77 70.43,38.36 71.32,38.36 71.59,38.63 72.37,38.63 72.67,38.32 v1(72.79,38.32)
  BOTTOM w0.089: CPU1.C42 74.39,40.15 74.39,39.74 74.19,39.54 74.05,39.54 73.62,39.11 72.97,39.11 72.57,38.71 72.57,38.54 v1(72.79,38.32)
  BOTTOM w0.102: v2(26.98,47.38) 26.96,47.38 v1(26.55,47.79) 26.22,47.46 26.11,47.46 25.88,47.69 TR3503.1
USB_CPU_PP1: length 134.7
  L3 w0.114: v1(151,79.86) 150.79,79.66 150.79,79.38 150.28,78.87 146.21,78.87 145.88,78.54 143.47,78.54 143.03,78.1 143.03,77.32 142.02,76.31 142.02,67.05 142.28,66.79 142.28,64.49 142.56,64.21 142.56,55.66 142.21,55.32 142.21,49.9 141.4,49.09 141.4,45.9 140.09,44.59 140.09,43.71 137.93,41.55 137.93,38.29 136.64,37 136.64,35.86 133.57,32.79 130.81,32.79 129.48,31.47 115.5,31.47 114.77,32.19 96.77,32.19 95.52,30.94 84.54,30.94 84.25,31.23 v1(84,31.23)
  BOTTOM w0.102: 72.4,37.02 v2(72.28,37.14) ; 72.4,37.02 72.22,36.85 72.22,33.97 74.29,31.9 79.53,31.9 80.58,32.96 82.61,32.96 83.4,32.17 83.4,31.99 84,31.4 v1(84,31.23) ; 72.4,37.02 74.47,39.09 74.47,39.27 74.67,39.47 CPU1.C43 ; TR6601.3 149.25,82.36 149.15,82.26 149.15,81.98 150.81,80.32 150.81,80.04 v1(151,79.86)
USB_CPU_PP2: length 127.7
  L3 w0.114: v1(144.42,77.56) 144.15,77.29 143.73,77.29 142.51,76.07 142.51,67.26 142.77,67 142.77,64.69 143.05,64.42 143.05,50.04 142.46,49.45 142.46,46.61 141.9,46.05 141.9,45.6 141.37,45.07 141.37,44.29 138.43,41.35 138.43,37.97 137.49,37.04 137.49,35.92 133.84,32.27 131.04,32.27 129.76,30.99 115.04,30.99 114.33,31.7 96.97,31.7 95.73,30.45 82.91,30.45 82.63,30.74 82.63,31.4 v1(82.83,31.6)
  BOTTOM w0.102: 71.62,35.46 71.62,36.39 71.22,36.78 71.22,38.3 72.35,39.43 72.69,39.43 72.85,39.59 73.53,39.59 73.78,39.84 73.78,40.13 73.99,40.34 CPU1.C41 ; 71.62,35.46 v2(71.78,35.46) ; 71.62,35.46 71.62,33.72 74.05,31.28 79.77,31.28 80.83,32.35 82.31,32.35 82.61,32.04 82.61,31.82 v1(82.83,31.6) ; v1(144.42,77.56) 144.63,77.34 144.78,77.34 145.21,77.78 145.89,77.78 R6102.2
USB_CPU_PP3: length 86.2
  L3 w0.114: v1(48.34,31.55) 49.52,31.55 49.95,31.12 50.05,31.12 50.65,30.51 53.34,30.51 53.72,30.13 57.98,30.13 58.41,30.55 59.87,30.55 60.17,30.25 60.17,27.82 60.51,27.48 61.45,27.48 61.63,27.31 62.53,27.31 63.39,28.17 69.6,28.17 71.14,29.71 73.69,29.71 75.75,31.77 77.25,31.77 78.02,32.54 78.02,32.88 v1(78.28,33.15)
  BOTTOM w0.102: v1(78.28,33.15) 78.04,33.39 78.04,33.62 77.56,34.1 76.37,34.1 75.59,33.33 74.38,33.33 73.28,34.43 73.28,36.25 ; CPU1.C45 75.16,38.93 75.16,38.45 73.28,36.57 73.28,36.25 ; v1(48.34,31.55) 47.93,31.95 47.93,35.32 45.85,37.41 25.15,37.41 22.7,34.96 18.68,34.96 17.81,35.84 17.54,35.84 16.97,36.41 16.8,36.41 16.58,36.19 TR3301.2 ; 73.28,36.25 v2(73.48,36.25)
USB_CPU_PP4: length 126.6
  TOP w0.102: v2(53.5,80.62) v1(53.5,81.26) 53.79,81.56 53.79,82.07 53.55,82.31 TR5501.3 53.55,82.88 53.46,82.98
  L3 w0.114: v1(53.5,81.26) 53.77,80.99 53.77,80.54 53.54,80.31 48.44,80.31 48.04,80.71 47.07,80.71 45.66,82.12 36.59,82.12 35.46,83.24 31.79,83.24 30.36,81.81 25.09,81.81 22.43,79.15 22.43,77.51 21.95,77.03 21.95,73.13 20.71,71.89 20.71,69.57 25.46,64.83 25.46,59.61 25.59,59.47 25.59,55.46 26.71,54.34 26.71,50.3 27.87,49.15 27.87,43.36 29.11,42.12 33.92,42.12 35.87,40.18 53.15,40.18 53.22,40.24 54.13,40.24 55.43,38.94 58.44,38.94 58.88,39.38 60.22,39.38 60.84,38.76 63.65,38.76 64.15,39.26 70.17,39.26 70.51,38.92 71.12,38.92 71.81,39.61 71.81,40.23 v1(71.84,40.27)
  BOTTOM w0.102: v1(71.84,40.27) 72.03,40.08 72.44,40.08 72.64,40.28 73.05,40.28 73.29,40.52 CPU1.B40
USB_HSIC_RCOMP: length 2.1
  TOP w0.152: R1637.2 76.37,44.59 v1(76.76,44.59) 76.98,44.8 v2(76.98,45.17)
  BOTTOM w0.152: v1(76.76,44.59) 76.6,44.75 CPU1.N38
USB_OC#0: length 159.6
  TOP w0.102: RN1607.4 56.88,56.06 v1(57.72,55.22)
  L3 w0.102: v1(69.37,84.28) 69.31,84.22 69.16,84.22 64.26,79.32 64.26,76.73 62.98,75.45 62.98,74.16 63.43,73.71 63.43,67.82 64.58,66.67 64.58,65.48 61.3,62.2 61.3,60.81 62.45,59.67 62.45,59.67 62.69,59.43 62.69,59.43 62.72,59.39 62.72,59.06 63.14,58.64 63.14,57.64 61.42,55.92 58.42,55.92 v1(57.72,55.22) 57.72,55.16 58.66,54.22 59.03,54.22 59.27,54.46 59.72,54.46 61.08,53.09 61.25,53.09 61.47,52.88 62.31,52.88 62.76,53.32 63.71,53.32 63.84,53.44 64.18,53.44 64.33,53.29 66.33,53.29 66.6,53.02 67.21,53.02 67.59,53.4 68.21,53.4 v1(68.3,53.49) ; v1(141.98,78.37) 142.27,78.37 143.53,79.63 147.65,79.63 149.66,81.64 151.8,81.64 v1(151.82,81.66)
  L4 w0.102: v1(128.51,86.13) 128.13,86.52 103.41,86.52 101.44,84.55 100.03,84.55 99.5,85.08 99.5,86.46 99.76,86.73 99.76,88.01 96.71,91.06 93.53,91.06 91.98,92.61 90.53,92.61 87.76,95.38 82.15,95.38 81.02,96.52 80.1,96.52 79.65,96.08 79.65,94.52 76.98,91.84 71.75,91.84 69.59,89.68 69.59,84.5 v1(69.37,84.28)
  BOTTOM w0.102: v1(141.98,78.37) 141.98,79.3 141.22,80.07 137.87,80.07 v2(134.39,83.55) 132.81,85.12 132.27,85.12 131.26,86.13 v1(128.51,86.13) ; v1(151.82,81.66) 151.93,81.55 IOBD1.33 ; 68.77,53.76 68.56,53.76 v1(68.3,53.49)
USB_OC#1: length 65.7
  TOP w0.102: RN1607.3 56.62,55.41 57.42,54.61 57.66,54.61 v1(58.25,54.01) ; v1(44.04,47.5) 44,47.54 44,51.13 46.16,53.29 v2(46.48,53.29) 49.33,53.29 v1(49.61,53.01)
  L3 w0.102: v1(58.25,54.01) 58.64,53.63 60.12,53.63 60.86,52.89 61.17,52.89 61.38,52.67 62.24,52.67 62.29,52.62 63.68,52.62 63.8,52.5 64.42,52.5 64.99,53.07 66.26,53.07 66.52,52.82 67.3,52.82 67.37,52.89 68.53,52.89 v1(68.61,52.96)
  L4 w0.102: v1(28.93,47.3) 29.13,47.11 29.87,47.11 30.2,46.78 33.31,46.78 34.13,47.6 43.63,47.6 43.73,47.5 v1(44.04,47.5)
  BOTTOM w0.102: CPU1.P16 68.83,53.17 68.62,52.96 v1(68.61,52.96) ; v1(49.61,53.01) 50.14,53.01 50.85,52.3 53.37,52.3 53.47,52.4 53.47,52.78 53.26,52.98 53.26,54.32 53.86,54.92 54.37,54.92 54.63,55.17 56.51,55.17 57.13,54.54 57.72,54.54 v1(58.25,54.01) ; v1(28.93,47.3) 28.49,47.3 27.85,47.95 27.39,48.4 24.82,48.4 23.96,49.25 23.96,51.25 23.53,51.67 23.53,52.06 23.16,52.43 23.16,54.29 22.73,54.72 U3601.3
USB_OTG_ID: length 5.1
  BOTTOM w0.102: v2(75.06,33.78) 74.45,34.39 74.45,34.45 75.26,35.26 75.26,36.29 76.46,37.48 CPU1.B48
USB_PWR_EN#: length 254.4
  L3 w0.102: v1(155.45,77.27) 154.22,76.03 153.57,76.03 153.57,76.04 152.38,76.04 152.37,76.03 151.08,74.75 150.07,74.75 150.07,74.75 149.48,74.75 145.73,71 145.73,65.63 146.59,64.77 147.15,64.21 147.15,64.2 147.15,55.95 147.26,55.85 149.65,53.46 149.65,52.84 149.65,50.4 149.51,50.27 148.49,49.24 148.49,46.29 148.49,44.39 148.35,44.25 147.65,43.55 147.65,42.79 147.65,41.77 147.65,41.77 147.65,41.37 147.65,41.37 147.65,39.68 147.09,39.12 146.56,38.59 146.56,35.43 145.58,34.44 144.52,34.44 143.93,33.86 143.93,32.77 143.5,32.34 142.11,30.94 141.48,30.94 138.8,28.27 132.69,28.27 131.41,27 116.14,27 114.54,25.39 109.8,25.39 104.73,20.33 104.73,18.72 104.3,18.29 103.52,18.29 101.98,16.75 101.08,16.75 100.87,16.54 100.44,16.11 98.48,16.11 94.95,12.58 93.53,12.58 91.62,10.67 89.36,10.67 88.18,11.85 72.61,11.85 72,12.46 70.01,12.46 69.76,12.2 69.04,11.49 66.13,11.49 63.09,14.53 59.44,14.53 59.35,14.44 55.44,14.44 55.31,14.57 54.34,15.54 53.07,15.54 52.55,15.02 50.49,15.02 v1(50.28,14.81) 49.46,14.81 47.63,12.98 46.57,12.98 45.93,13.62 41.97,13.62 41.61,13.26 39.7,13.26 39.19,12.75 34.59,12.75 32.89,11.05 24.31,11.05 20.56,14.8 20.56,24.56 18.47,26.66 18.47,31.6 18.21,31.85 18.21,34.58 18.58,34.95 18.58,41.05 18.75,41.22 18.75,47.66 18.35,48.06 v1(18.29,48.06)
  BOTTOM w0.102: IOBD1.26 154.59,85.05 154.97,84.67 154.97,83.69 155.45,83.21 155.45,82.64 155.3,82.49 155.3,77.42 v1(155.45,77.27) ; v1(50.28,14.81) 51.45,14.81 R2471.2 51.67,15.03 52.25,15.03 52.93,15.71 53.8,15.71 53.81,15.71 U2401.108 ; U3601.4 22.73,52.53 23.29,51.96 23.29,51.48 23.56,51.21 v2(23.56,50.68) 23.56,50.01 22.78,49.23 19.65,49.23 18.48,48.06 v1(18.29,48.06)
USB_RCOMP: length 3.2
  TOP w0.203: v1(75.21,37.34) 74.97,37.58 R1641.2 74.97,39.35 v2(75.18,39.57)
  BOTTOM w0.203: CPU1.A48 75.83,37.34 v1(75.21,37.34)
USB_VBUSSNS: length 3.1
  TOP w0.102: v2(76.96,38.18) 77.11,38.18 v1(77.43,38.5) 77.07,38.87 R1617.1
  BOTTOM w0.102: CPU1.B47 76.52,38.17 76.73,38.38 77.31,38.38 v1(77.43,38.5)
V_SM_VREF_CNT: length 1.2
  TOP w0.254: TP501.1 81.28,56.01 v1(81.53,56.26)
  BOTTOM w0.254: CPU1.AT28 81.38,56.41 v1(81.53,56.26)
VD1_EN#: length 6.5
  BOTTOM w0.203: 68.56,10.81 68.38,10.63 U2401.66
  BOTTOM w0.254: v2(73.13,11.58) 72.53,10.98 R2468.1 71.23,10.57 70.92,10.88 68.63,10.88 68.56,10.81
VD_IN1: length 21.8
  TOP w0.102: v1(49.83,9.33) 49.4,9.33 48.92,9.81 48.92,10.89 R2612.1
  BOTTOM w0.102: v1(49.83,9.33) 50.19,8.96 v2(50.19,8.47) 50.29,8.37 C2612.1 52.09,8.37 C2613.1 52.15,7.78 52.06,7.69 R2608.2 52.06,6.87 R2614.2 53.01,6.53 53.01,7.39 53.34,7.72 53.67,7.72 54.1,8.16 55.32,8.16 55.85,8.69 56.57,8.69 56.78,8.91 U2401.95 56.78,10.44 57.35,11.01 57.35,12.61 57.28,12.69 57.28,13.34 56.51,14.11 U2401.104
VD_IN1_C: length 4.5
  TOP w0.102: R2612.2 50,10.09 v1(50.46,9.63)
  BOTTOM w0.102: R2613.1 52.93,9.19 C2613.2 52.09,9.26 C2612.2 50.83,9.26 v1(50.46,9.63) 50.25,9.84 49.92,9.84 v2(49.84,9.91)
VD_OUT1#: length 33.2
  TOP w0.254: v1(57.72,12.87) 58.64,12.87 58.99,13.22 59.41,13.22 60.42,12.2 v2(60.42,11.48) 60.42,10.86 61.62,9.66 62.03,9.66 62.99,8.71 62.99,8.64 64.21,7.41 64.21,4.53 63.83,4.15 63.83,4.14 63.53,3.84 63.41,3.84 63.26,3.69 63.26,1.31 62.84,0.89 57.71,0.89 56.46,2.13 R2615.2 56.46,2.49 R2602.2 54.03,2.49 R2603.2
  BOTTOM w0.203: 55.88,16.61 55.78,16.51 U2401.110
  BOTTOM w0.254: v1(57.72,12.87) 57.72,13.34 58.04,13.67 58.04,15.25 56.51,16.78 56.05,16.78 55.88,16.61
VIDALERT#_CORE: length 3.9
  BOTTOM w0.102: PU4601.4 28.37,59.54 29.56,60.73 PR4663.1 29.56,61.22 v2(30.48,62.13)
VIDALERT#_CPU: length 28.4
  TOP w0.102: v1(86.22,38.75) 86.22,37.5 83.85,35.13 83.85,33.75 82.46,32.36 81.34,32.36 80.47,31.49 80.47,30.06 80.82,29.7 v2(80.82,29.25) 79.8,28.22 R1835.1
  L4 w0.127: v1(86.22,38.75) 85.34,39.63 85.34,41.12 85.84,41.62 85.84,43.93 82.87,46.91 81.36,46.91 81.03,47.24 v1(81.03,47.84)
  BOTTOM w0.102: v1(81.03,47.84) 81.03,48.34 CPU1.AD40
VIDALERT#_CPU_R: length 155.9
  TOP w0.102: v1(30.72,62.79) 30.72,63.33 31.4,64 31.4,65.35 R1824.1 PR4602.1 32.44,67.23 32.44,67.95 33.1,68.61 33.1,70.56 v1(33.17,70.63) 33.3,70.75 PR4854.2 ; v1(56.04,30.98) 56.04,31.15 v2(56.74,31.85) 57.31,31.85 57.53,32.08 60.25,32.08 62.73,29.6 63.41,29.6 64.36,28.65 71.21,28.65 71.37,28.81 72.24,28.81 74.12,30.69 75.84,30.69 76.65,29.87 76.65,28.84 77.27,28.22 R1835.2
  L3 w0.127: v1(30.72,62.79) 30.72,63.53 30.31,63.95 28.86,63.95 27.75,65.06 27.75,66.18 27.18,66.75 24.96,66.75 21.72,69.99 21.72,71.35 22.96,72.59 22.96,76.61 23.44,77.09 23.44,78.72 24.97,80.24 28.44,80.24 29,80.8 31.7,80.8 32,81.11 44.33,81.11 46.52,78.91 49.5,78.91 49.85,79.27 57.8,79.27 60.25,76.82 60.25,74.58 60.09,74.42 60.09,69.29 60.09,69.29 60.09,64.49 59.31,63.71 59.31,59.82 58.88,59.39 58.88,59.26 56.14,56.52 54.64,56.52 52.97,54.85 52.97,53.75 53.45,53.27 53.85,53.27 55.41,51.71 55.41,49.59 56.31,48.69 56.31,45.34 56.95,44.7 56.95,43.95 56.3,43.31 54.39,43.31 54.38,43.32 54.01,43.32 53.58,42.89 53.58,42.87 v1(53.56,42.84)
  BOTTOM w0.102: v1(30.72,62.79) 30.35,62.79 29.63,62.07 PR4663.2 ; v1(53.56,42.84) 53.62,42.78 53.62,42.52 54.18,41.96 54.18,40.57 54.53,40.22 54.53,34.14 56.18,32.49 56.18,31.13 v1(56.04,30.98) ; v1(33.17,70.63) 33.52,70.28 PR4805.1
VIDALERT#_GFX: length 5.1
  TOP w0.102: PU4802.4 30.89,74.8 31.64,74.05 31.97,74.05 v2(32.63,73.38) 32.63,72.88 PR4854.1
VIDSCK_CORE: length 5.2
  BOTTOM w0.102: PU4601.5 28.77,59.51 29.46,60.2 30.1,60.2 v2(30.56,60.66) 30.68,60.78 30.68,61.58 30.7,61.59 30.7,61.61 30.98,61.89 31.3,61.89 31.6,62.19 PR4645.2
VIDSCK_CPU: length 24.4
  TOP w0.102: R1833.1 79.49,29.05 v2(79.6,29.16) 79.93,29.49 79.93,31.64 81.14,32.84 82.26,32.84 83.37,33.95 83.37,35.35 85.74,37.72 v1(85.74,38.21)
  L4 w0.127: v1(82.54,46.34) 82.54,45.47 85.5,42.52 85.5,41.6 84.91,41.02 84.91,39.03 v1(85.74,38.21)
  BOTTOM w0.102: CPU1.AD42 82.24,47.17 82.24,46.64 v1(82.54,46.34)
VIDSCK_CPU_R: length 154.6
  TOP w0.102: R1833.2 77.26,29.05 77.14,29.17 77.14,30.24 76.21,31.17 73.92,31.17 72.04,29.29 71.16,29.29 71.11,29.23 64.47,29.23 63.61,30.09 62.93,30.09 60.42,32.59 v2(58.67,32.59) 57.36,32.59 57.11,32.34 56.54,32.34 55.37,31.16 v1(55.37,31.01) ; PR4875.2 34.13,70.87 v1(33.89,70.63) 33.6,70.34 33.6,64.33 32.89,63.62 PR4601.1 32.32,62.97 v1(31.33,62.97)
  L3 w0.127: v1(52.89,42.84) 52.89,42.91 53.8,43.82 54.59,43.82 54.6,43.82 55.8,43.82 56.15,44.16 56.15,44.77 55.8,45.13 55.8,48.48 54.9,49.38 54.9,51.5 53.64,52.76 53.24,52.76 52.46,53.54 52.46,55.06 54.43,57.03 55.8,57.03 58.8,60.03 58.8,63.96 59.58,64.74 59.58,69.5 59.58,69.5 59.58,74.63 59.74,74.79 59.74,76.61 57.59,78.76 50.06,78.76 49.71,78.4 46.31,78.4 44.12,80.6 32.21,80.6 31.91,80.3 29.22,80.3 28.65,79.73 25.17,79.73 23.95,78.51 23.95,76.88 23.47,76.4 23.47,72.38 22.23,71.14 22.23,70.2 25.17,67.26 27.39,67.26 28.25,66.4 28.25,65.27 29.07,64.45 30.52,64.45 31.33,63.64 v1(31.33,62.97)
  BOTTOM w0.102: v1(55.37,31.01) 55.4,31.03 55.4,32.53 54.85,33.07 54.74,33.07 54,33.81 54,34.8 53.44,35.36 53.44,36.07 53.98,36.6 53.98,40.1 53.7,40.37 53.7,41.76 52.92,42.53 52.92,42.8 v1(52.89,42.84) ; v1(31.33,62.97) 31.45,63.08 PR4645.1 ; PR4804.1 34.35,70.16 v1(33.89,70.63)
VIDSCK_GFX: length 5.3
  TOP w0.102: PU4802.5 31.29,75.57 31.76,75.1 32.18,75.1 v2(32.63,74.65) 33.22,74.06 33.22,73.13 PR4875.1
VIDSOUT_CORE: length 2.4
  BOTTOM w0.102: PU4601.3 27.97,59.72 v2(28.5,60.25) 28.5,60.25 28.72,60.47 PR4669.1
VIDSOUT_CPU: length 28.5
  TOP w0.102: v1(86.66,38.1) 86.66,37.55 84.11,34.99 84.11,33.65 82.57,32.11 81.45,32.11 81,31.66 81,29.88 81.18,29.71 81.18,29.01 80.01,27.84 v2(79.5,27.84) 79.07,27.4 R1821.1
  L4 w0.127: v1(81.53,47.34) 82.78,47.34 86.17,43.94 86.17,41.53 85.58,40.94 85.58,40.02 86.67,38.93 86.67,38.57 86.66,38.56 v1(86.66,38.1)
  BOTTOM w0.102: v1(81.53,47.34) 81.53,47.83 CPU1.AD41
VIDSOUT_CPU_R: length 155.2
  TOP w0.102: v1(30.27,63.25) 30.27,63.57 v2(30.74,64.03) 31.15,64.44 31.15,65.46 31.79,66.1 31.79,67.66 PR4665.1 32.85,68.72 32.85,70.27 v1(32.49,70.63) 32.43,70.69 PR4855.2 ; R1821.2 76.4,28.73 76.4,29.76 75.73,30.43 74.22,30.43 72.34,28.55 71.47,28.55 71.32,28.4 64.03,28.4 63.08,29.35 62.62,29.35 60.14,31.83 57.64,31.83 57.41,31.6 57.02,31.6 56.7,31.27 v1(56.7,30.99)
  L3 w0.127: v1(30.27,63.25) 29.85,63.67 28.75,63.67 27.47,64.95 27.47,66.02 27.02,66.47 24.84,66.47 21.44,69.88 21.44,71.46 22.68,72.71 22.68,76.73 23.17,77.21 23.17,78.84 24.88,80.56 28.36,80.56 28.89,81.08 31.58,81.08 31.89,81.39 44.44,81.39 46.63,79.2 49.38,79.2 49.72,79.55 57.92,79.55 60.53,76.93 60.53,74.46 60.37,74.3 60.37,69.17 60.37,64.35 59.61,63.59 59.61,59.72 59.16,59.27 59.16,59.14 56.26,56.24 55.16,56.24 53.25,54.32 53.25,53.87 53.57,53.55 53.96,53.55 55.69,51.82 55.69,49.7 56.59,48.8 56.59,45.45 57.23,44.81 57.23,43.84 56.42,43.03 54.35,43.03 v1(54.2,42.87)
  BOTTOM w0.102: PR4843.1 32.68,70.44 v1(32.49,70.63) ; v1(30.27,63.25) 29.64,62.62 29.27,62.62 PR4669.2 ; v1(54.2,42.87) 54.43,42.63 54.43,40.68 54.79,40.33 54.79,34.24 56.49,32.54 56.49,31.37 56.7,31.17 v1(56.7,30.99)
VIDSOUT_GFX: length 4.7
  TOP w0.102: PU4802.3 30.49,74.78 31.36,73.9 v2(31.36,73.38) 31.36,73.29 PR4855.1
VOL_DOWN#: length 165.6
  TOP w0.102: RN2403.3 67.36,11.72 67.54,11.9 67.54,12.53 66.84,13.23 v1(66.84,13.4) ; v2(158.42,78.27) 158.54,78.38 v1(158.54,78.82)
  L3 w0.102: v1(158.54,78.82) 158.11,79.25 157.72,79.25 157.57,79.09 156.04,79.09 155.84,78.89 155.31,78.89 153.42,77 152.6,77 152.59,77 152.38,77 152.38,77 151.98,77 151.98,77 151.97,77 150.68,75.71 150.47,75.71 148.97,75.71 144.77,71.5 144.77,65.23 146.19,63.81 146.19,63.8 146.19,55.55 146.29,55.45 148.68,53.06 148.68,50.8 147.05,49.17 147.05,48.22 147.05,48.22 146.72,47.89 146.72,45.96 146.69,45.93 146.69,43.95 146.69,40.08 145.6,38.99 145.6,38.46 143.37,36.23 143.37,35.28 143.36,35.27 143.36,35.25 142.71,34.61 142.71,33.28 141.73,32.29 141.09,32.29 138.3,29.49 132.18,29.49 130.91,28.21 115.64,28.21 114.06,26.63 109.32,26.63 103.43,20.74 101.39,20.74 94.45,13.8 93.03,13.8 91.12,11.89 89.86,11.89 88.68,13.07 78.72,13.07 78,13.79 74.79,13.79 73.99,14.59 70.1,14.59 68.44,12.94 67.31,12.94 v1(66.84,13.4)
  BOTTOM w0.102: v1(158.54,78.82) 158.33,79.02 158.33,80.24 157.84,80.74 157.84,80.98 157.53,81.29 157.53,83.73 156.57,84.69 156.57,85.07 154.58,87.05 IOBD1.22 ; U2401.63 69.24,11.71 68.8,12.15 68.8,13.41 68.38,13.83 67.28,13.83 v1(66.84,13.4)
VOL_UP#: length 174.8
  TOP w0.102: RN2403.4 66.94,12.61 66.21,13.34 v1(66.21,13.42) ; v2(158.18,79.51) 157.9,79.22 v1(157.9,78.81)
  L3 w0.102: v1(157.9,78.81) 157.85,78.87 156.14,78.87 155.93,78.66 155.4,78.66 153.65,76.91 153.52,76.77 152.5,76.77 152.29,76.77 152.07,76.77 150.78,75.48 150.38,75.48 149.07,75.48 145,71.41 145,65.32 146.28,64.04 146.42,63.9 146.42,63.9 146.42,55.65 146.52,55.54 148.91,53.15 148.91,50.71 147.75,49.54 147.75,46.59 147.75,44.72 146.92,43.89 146.92,43.86 146.92,39.99 146.78,39.85 145.83,38.9 145.83,38.36 143.6,36.14 143.6,35.63 143.6,35.19 143.59,35.17 143.59,35.16 142.94,34.51 142.94,33.18 141.82,32.06 141.19,32.06 138.39,29.26 132.28,29.26 131,27.99 115.73,27.99 114.15,26.4 109.41,26.4 103.52,20.51 102.23,20.51 101.91,20.2 101.91,18.99 100.02,17.1 98.07,17.1 94.54,13.57 93.12,13.57 91.21,11.66 89.77,11.66 88.59,12.84 75.65,12.84 74.95,13.54 74.69,13.54 73.87,14.36 70.19,14.36 68.54,12.71 66.92,12.71 66.41,13.22 66.41,13.22 v1(66.21,13.42) 66.21,13.68 65.56,14.33 64.62,14.33 63.49,15.47 58.83,15.47 v1(58.69,15.61)
  BOTTOM w0.102: IOBD1.23 154.75,86.55 156.34,84.97 156.34,84.6 157.3,83.63 157.3,81.2 157.61,80.89 157.61,80.64 157.99,80.27 157.99,78.9 v1(157.9,78.81) ; v1(58.69,15.61) 58.69,16.69 57.76,17.62 57.76,19.03 57.48,19.31 U2401.117
VRAM_CH_A_ZQ_1A: length 4.1
  TOP w0.356: v1(123.92,45.41) 123.51,45 v2(123.25,45)
  TOP w0.508: R1208.1 123.98,45.34 v1(123.92,45.41)
  BOTTOM w0.102: RAM1.L8 125,47.17 124.61,46.78 124.61,46.12 123.92,45.43 123.92,45.41 v1(123.92,45.41)
VRAM_CH_A_ZQ_2A: length 3
  TOP w0.356: v2(124.35,64.79) 124.68,64.46 v1(124.68,64.1)
  TOP w0.508: v1(124.68,64.1) 124.6,64.02 R1209.1
  BOTTOM w0.102: v1(124.68,64.1) 124.63,64.15 124.63,64.84 125,65.21 RAM2.L8
VRAM_CH_A_ZQ_3A: length 2.5
  TOP w0.356: R1210.1 124.42,34.45 123.89,33.92 v2(123.73,33.92)
  TOP w0.508: R1210.1 124.93,34.68 v1(125.4,34.68)
  BOTTOM w0.305: RAM3.L8 125.02,34.3 v1(125.4,34.68)
VRAM_CH_A_ZQ_4A: length 4.7
  TOP w0.356: v2(123.37,76.83) 123.37,76.71 123.69,76.38 v1(123.93,76.38)
  TOP w0.508: R1211.1 124.84,76.27 124.04,76.27 v1(123.93,76.38)
  BOTTOM w0.102: RAM4.L8 125,78.29 124.56,77.85 124.56,77.01 v1(123.93,76.38)
VREF_CA: length 76.6
  TOP w0.356: v1(125.39,65.77) 125.39,65.76 v2(125.99,65.76)
  L3 w0.254: v1(121.5,75.74) 120.56,75.74 119.87,75.05 119.87,73.83 119.65,73.61 119.65,72.24 119.7,72.19 119.7,70.93 119.27,70.5 119.27,68.21 116.41,65.36 116.41,63.45 117.07,62.79 117.07,56.45 121.14,52.38 121.6,52.38 121.88,52.09 121.88,51.28 121.62,51.02 121.62,48.94 120.91,48.23 120.91,45.84 v1(121.55,45.2)
  L4 w0.254: v1(121.5,75.74) 120.95,75.2 120.95,73.56 121.91,72.6 121.91,71.35 123.47,69.79 123.47,66.81 124.03,66.25 124.91,66.25 v1(125.39,65.77) ; v1(125.4,33.93) 123.56,35.77 123.56,36.46 123.41,36.61 123.41,38.76 121.91,40.26 121.91,41.8 121.12,42.59 121.12,44.76 v1(121.55,45.2)
  BOTTOM w0.203: RAM1.M8 125.8,47.24 125.42,46.86 125.42,46.51 124.94,46.04 124.94,45.64 ; 125.1,76.93 125.1,77.29 125.42,77.61 125.42,78.22 RAM4.M8 ; RAM2.M8 125.75,65.4 125.38,65.77 v1(125.39,65.77)
  BOTTOM w0.305: RAM3.M8 125.77,34.3 v1(125.4,33.93)
  BOTTOM w0.508: 124.94,45.64 124.94,45.57 124.17,44.8 123.45,44.8 123.05,45.2 v1(121.55,45.2) ; 125.1,76.93 125.1,76.12 124.72,75.74 121.5,75.74 v1(121.5,75.74)
VREF_CA_R1207:
  vias: v2(129.07,35.45)
VREF_DQ: length 64.5
  TOP w0.356: v1(121.41,41.16) v2(120.81,41.16)
  TOP w0.508: v1(122.83,85.84) 122.83,85.85 R1203.1 123.66,86.56 C1213.1
  L3 w0.254: v1(121.27,72.35) 120.19,71.26 120.19,70.41 119.62,69.84 119.62,68.03 116.84,65.24 116.84,63.61 117.45,63 117.45,56.76 v1(119.89,54.32)
  L4 w0.254: v1(121.27,72.35) 121.27,72.6 120.35,73.52 120.35,75.32 122.96,77.93 122.96,83.88 122.36,84.48 122.36,85.37 v1(122.83,85.84) ; v1(121.41,41.16) 120.74,41.83 120.74,45.07 122.28,46.61 122.39,46.61 122.87,47.08 122.87,51.06 122.34,51.59 122.34,53.73 121.75,54.32 v1(119.89,54.32)
  BOTTOM w0.203: RAM4.H1 122.4,84.4 122.4,85.41 v1(122.83,85.84)
  BOTTOM w0.254: v1(121.41,41.16) 122.6,39.97 RAM3.H1 ; v1(119.89,54.32) 121.75,54.32 122.6,53.46 RAM1.H1
  BOTTOM w0.305: v1(121.27,72.35) 121.43,72.35 121.92,71.86 121.92,71.68 RAM2.H1
VREF_DQ_R1203: length 2.8
  TOP w0.508: R1204.1 121.98,87.45 R1203.2 122.85,87.47 v2(123.76,87.47) 124.7,87.47 R1202.2
VTT_CT_1D8VC: length 2.4
  BOTTOM w0.203: 47.15,11.85 47.03,11.72 U4016.12
  BOTTOM w0.254: 47.15,11.85 47.45,12.14 v2(47.68,12.14) 47.73,12.19 C4041.1
VTT_CT_3D3V_S5_PRIME: length 1.7
  BOTTOM w0.203: 47.37,12.73 47.16,12.52 U4016.10
  BOTTOM w0.254: 47.37,12.73 47.7,13.06 C4043.1
VTT_EN: length 4.8
  TOP w0.254: PR5125.2 v1(96.63,20.59)
  BOTTOM w0.254: PU5102.7 98.73,21.68 98.66,21.6 97.5,21.6 PC5120.1 97.04,21.46 96.63,21.04 v1(96.63,20.59) v2(95.98,20.59)
WHITE_LED_BAT: length 3.8
  TOP w0.152: v2(11.12,12.72) R6408.2 12.03,13.17 12.04,13.19 EC6403.1 11.93,13.66 v1(11.12,13.66)
  BOTTOM w0.152: v1(11.12,13.66) 11.4,13.93 Q6403.C
WIFI_RF_EN: length 197.9
  TOP w0.102: AFTP6104.1 174.39,81.02 v1(174.39,81.25)
  L3 w0.102: v1(61.76,11.32) 61.76,10.84 62.43,10.16 69.59,10.16 70.28,10.85 70.77,10.85 71.46,10.16 73.54,10.16 73.85,9.86 74.39,9.86 75.1,10.57 84.47,10.57 84.8,10.24 88.81,10.24 89.07,9.98 91.91,9.98 92.43,10.5 93.75,11.83 94.51,11.83 98.72,11.83 100.59,13.69 103.93,13.69 104.15,13.48 104.91,13.48 105.12,13.27 107.54,13.27 107.88,13.61 109.67,13.61 110.42,12.86 114.47,12.86 120.04,7.28 130.69,7.28 132.06,5.91 135.46,5.91 139.6,10.05 140.62,10.05 147.68,17.1 147.68,20.49 147.68,21.06 148.46,21.84 148.46,23.79 147.78,24.47 147.78,26.37 146.7,27.45 145.62,27.45 144.16,28.9 144.16,33.73 144.65,34.22 145.68,34.22 145.94,34.48 146.79,35.33 146.79,35.71 146.79,38.5 147.18,38.89 147.88,39.59 147.88,41.27 147.88,42.89 147.88,42.89 147.88,43.46 148.45,44.02 148.71,44.29 148.71,46 148.71,46.19 149.67,47.15 149.67,50.1 149.88,50.3 149.88,52.75 149.88,53.55 149.52,53.9 149.52,53.91 149.26,54.17 149.25,54.17 147.38,56.05 147.38,64.3 147.38,64.3 146.68,65 145.96,65.72 145.96,70.9 149.58,74.52 149.6,74.52 149.98,74.52 149.98,74.52 151.18,74.52 152.47,75.81 152.48,75.81 153.48,75.81 154.7,75.81 156.85,77.95 157.25,77.95 157.36,77.85 157.75,77.85 158.26,78.35 158.77,78.35 160.13,79.71 170.47,79.71 172.2,81.44 174.2,81.44 v1(174.39,81.25)
  BOTTOM w0.102: WLAN1.56 176.63,81 175.96,81.67 174.81,81.67 v1(174.39,81.25) ; v1(61.76,11.32) 61.76,10.76 61.98,10.53 U2401.82
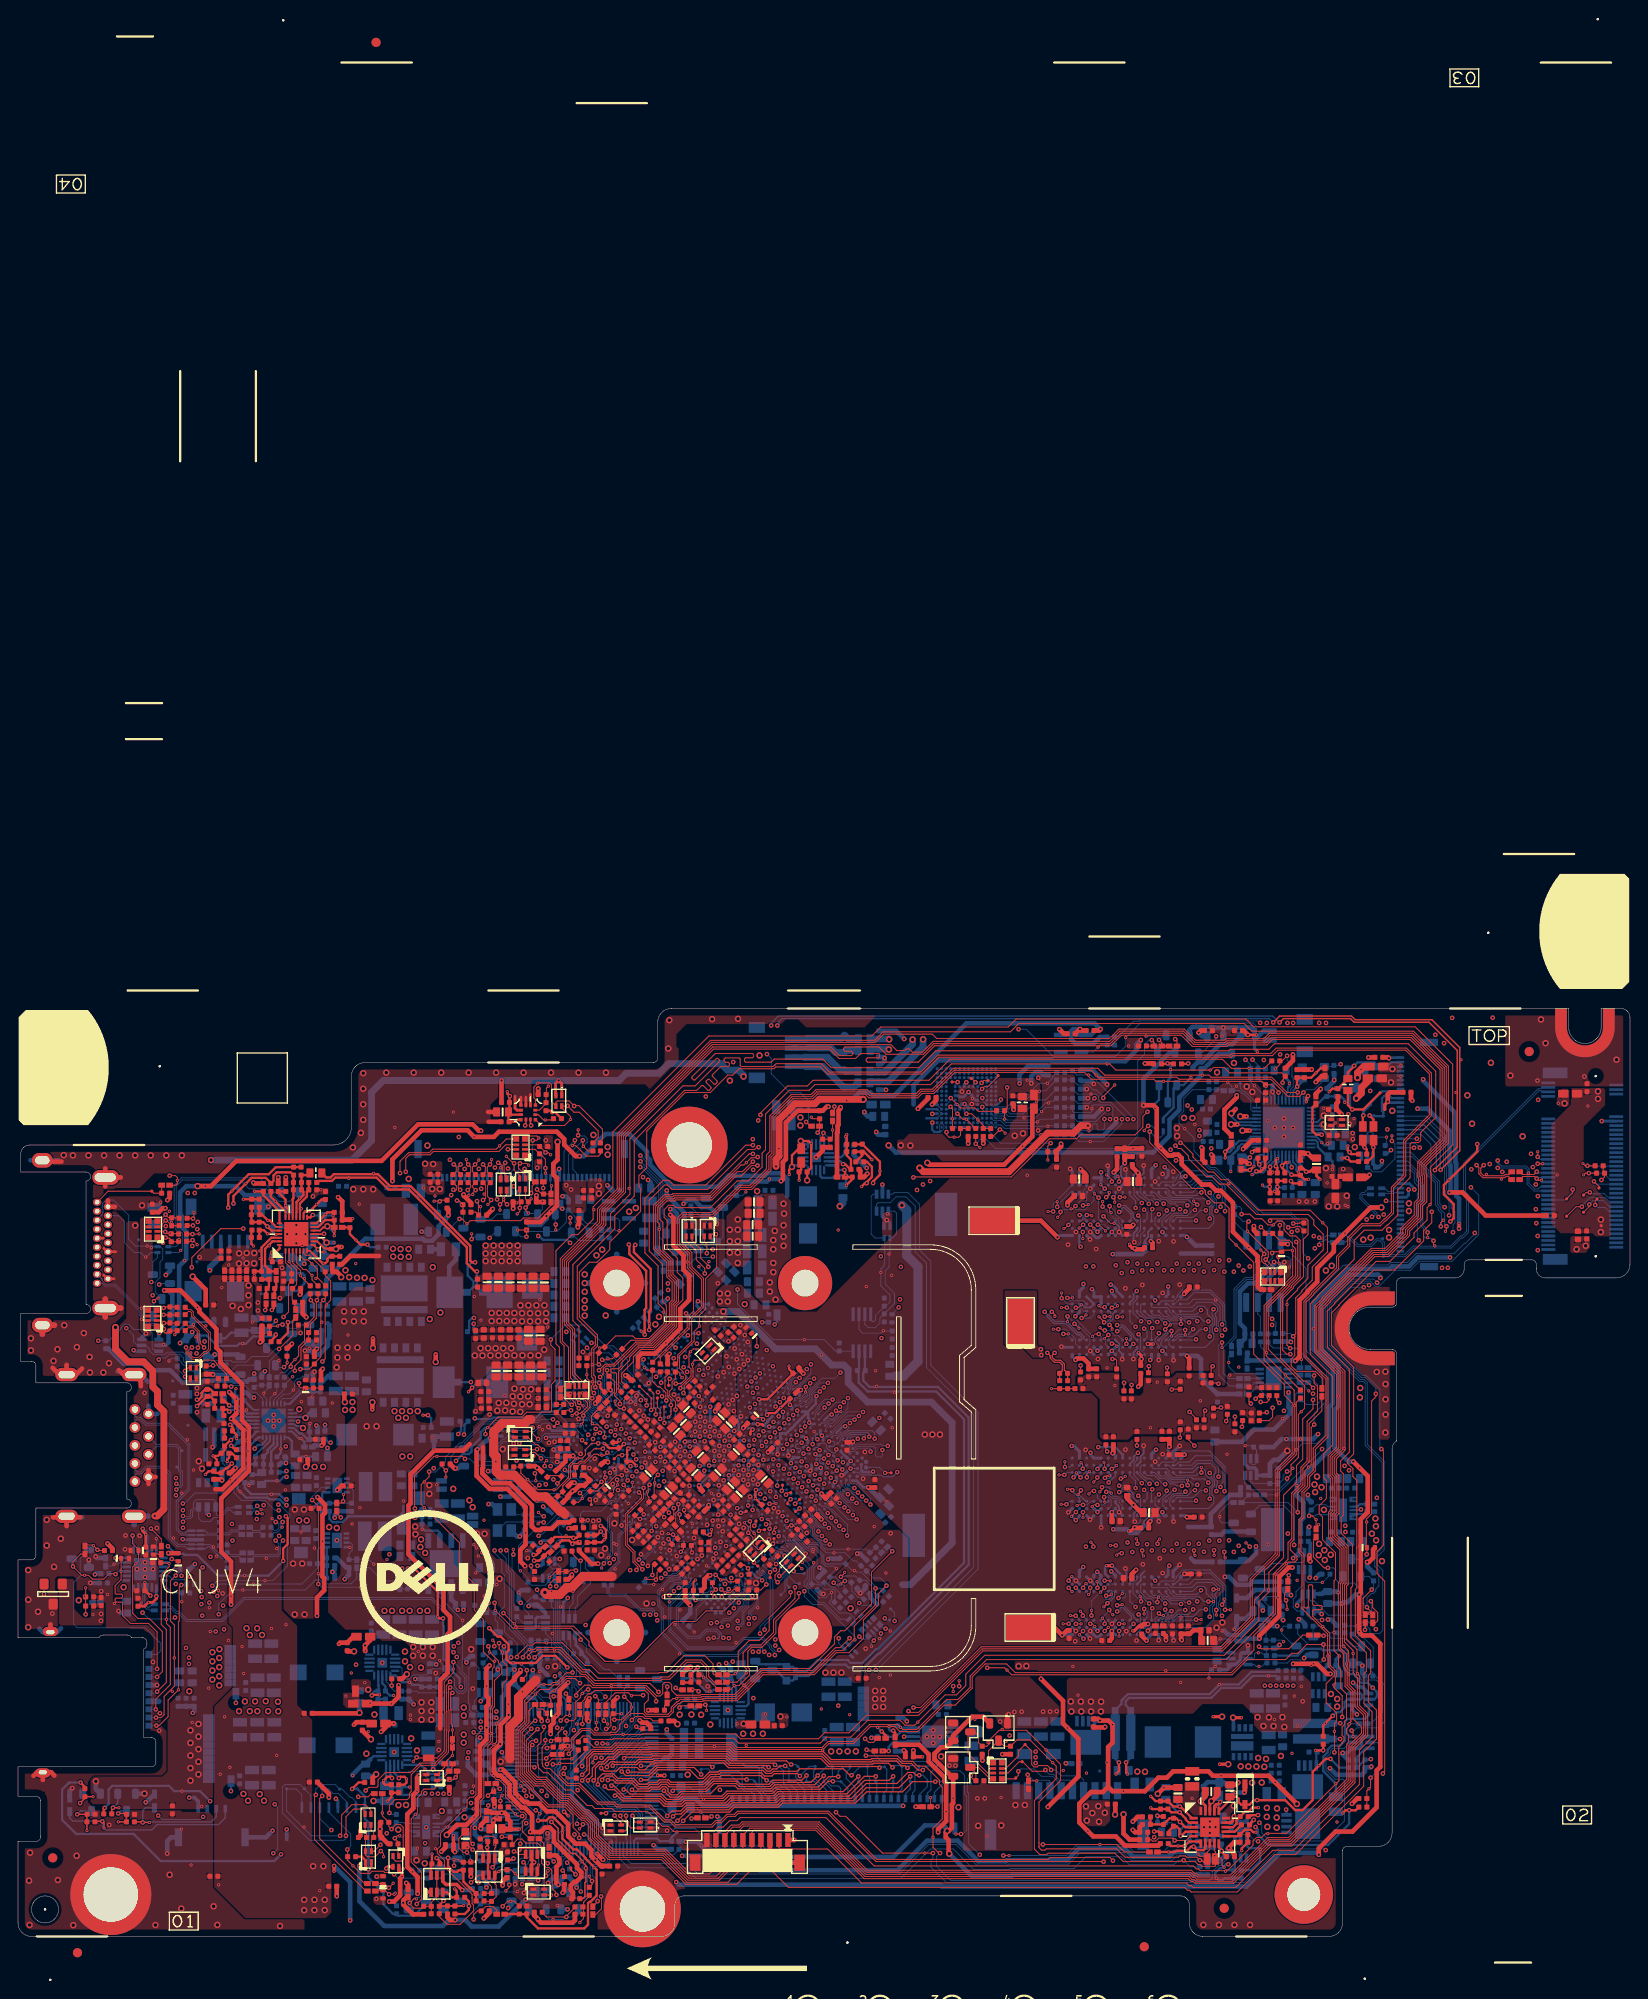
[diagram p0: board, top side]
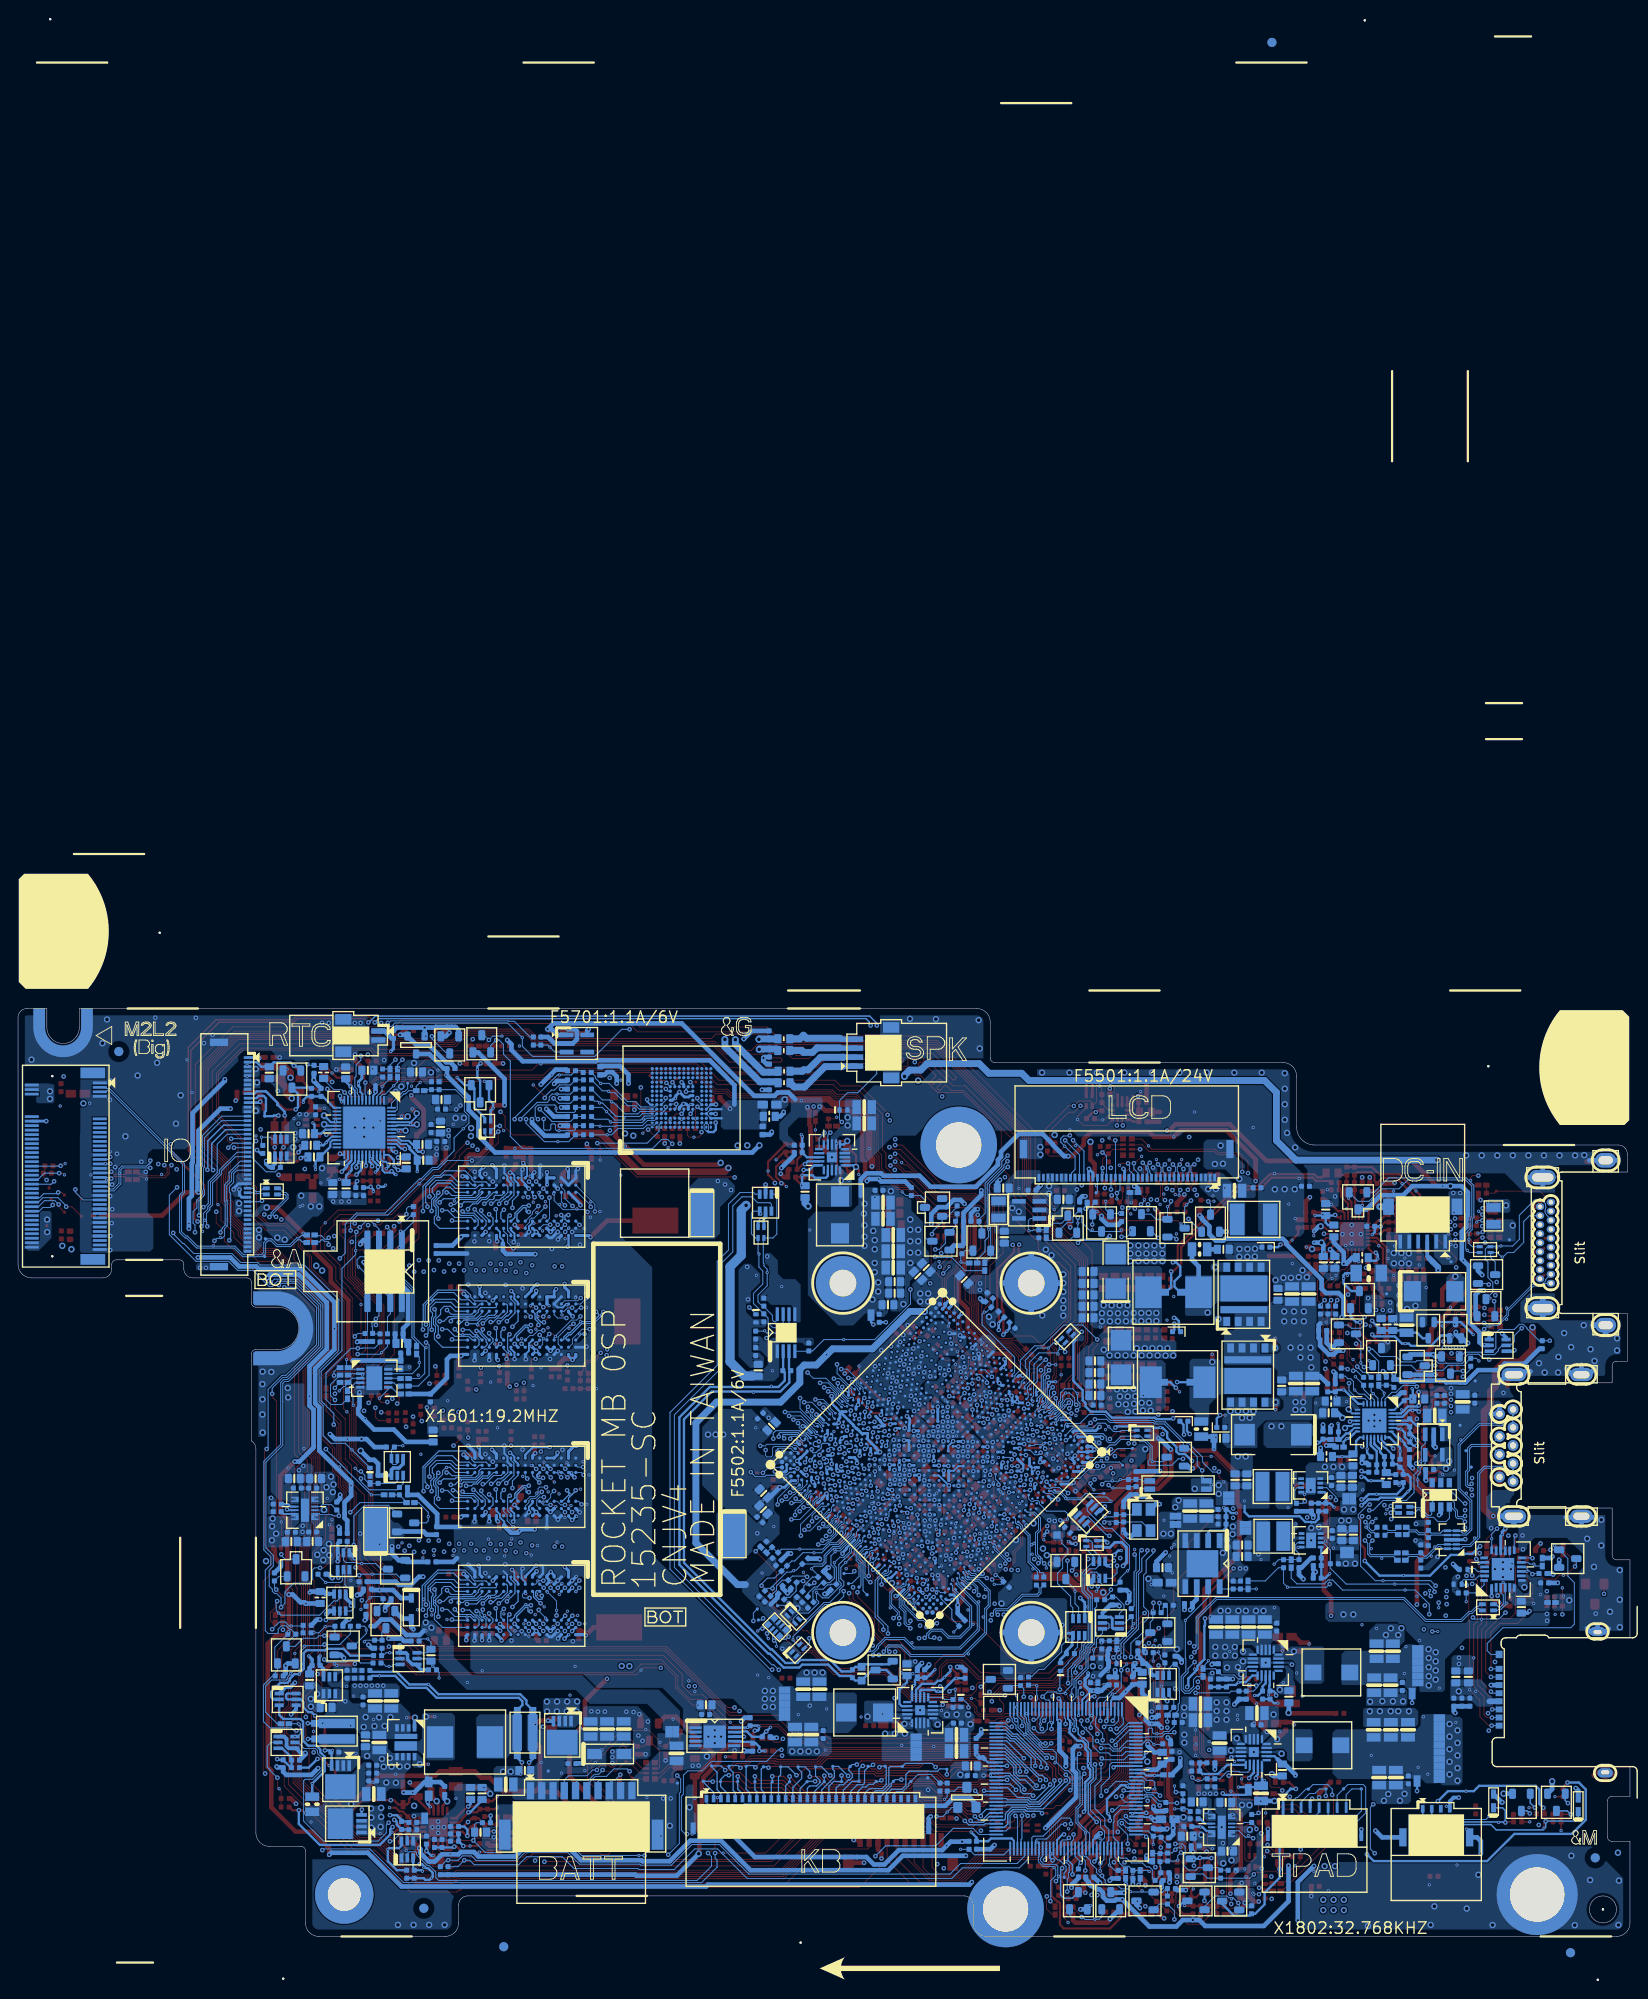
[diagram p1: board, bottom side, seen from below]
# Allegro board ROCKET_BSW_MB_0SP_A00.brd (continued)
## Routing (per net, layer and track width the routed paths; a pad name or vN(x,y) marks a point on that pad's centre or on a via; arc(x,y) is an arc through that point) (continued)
WLANTX_N3: length 4.1
  TOP w0.102: R6104.1 167,84.36 168.31,84.36 v1(168.55,84.12) 168.73,83.94 v2(169.08,83.94)
  BOTTOM w0.102: WLAN1.43 168.68,84.25 v1(168.55,84.12)
WLANTX_P3: length 3.6
  TOP w0.102: R6101.1 166.96,84.57 167.64,84.57 ; v1(168.55,84.89) 168.24,84.57 167.64,84.57 ; 167.64,84.57 v2(167.64,84.74)
  BOTTOM w0.102: v1(168.55,84.89) 168.68,84.75 WLAN1.41
XDP_PREQ#: length 23.6
  L3 w0.127: v1(96.29,34.16) 95.41,35.04 92.96,35.04 91.52,36.48 91.52,36.88 87.81,40.58 87.81,41.15 86.67,42.29 86.67,44.09 82.89,47.87 v1(82.89,48.59)
  BOTTOM w0.102: v2(96.8,33.9) 96.54,34.16 v1(96.29,34.16) 96.09,34.16 RN1805.5 ; CPU1.AF41 82.82,48.52 v1(82.89,48.59)
XDP_TCK: length 22.4
  TOP w0.102: v1(83.41,48.02) 84.1,48.02 v2(84.13,48.05)
  L4 w0.127: v1(87.27,38.33) 87.59,38.65 87.59,41.44 86.8,42.24 86.8,43.65 83.41,47.04 v1(83.41,48.02)
  BOTTOM w0.102: v1(87.27,38.33) 87.27,37.75 88.17,36.85 89.34,36.85 91.01,35.18 91.01,35.16 92.89,33.28 v2(92.89,32.92) 92.89,32.87 92.45,32.43 RN1806.4 ; v1(83.41,48.02) CPU1.AF42
XDP_TDI: length 21.6
  L3 w0.127: v1(94.98,32.84) 93.88,33.94 92.83,33.94 88.82,37.95 88.82,38.85 87.27,40.39 87.27,41.03 86.22,42.08 86.22,43.72 84.18,45.76 v1(83.02,45.76)
  BOTTOM w0.102: v1(83.02,45.76) 83.48,45.76 CPU1.AD47 ; RN1805.7 95.14,33.48 95.14,33 v1(94.98,32.84) 94.72,32.58 v2(94.72,32.21)
XDP_TDO: length 24.2
  L3 w0.127: v1(95.77,33.63) 94.86,34.54 93.02,34.54 90.95,36.61 90.95,37.08 87.55,40.49 87.55,41.08 86.45,42.18 86.45,43.99 82.38,48.06 v1(82.38,49.11)
  BOTTOM w0.102: v1(82.38,49.11) 82.29,49.03 81.72,49.03 ; RN1805.6 95.7,33.63 v1(95.77,33.63) 95.77,33.2 v2(95.62,33.06)
XDP_TMS: length 18.7
  TOP w0.102: v1(83.9,44.82) 83.9,45.22 v2(84.1,45.41)
  L3 w0.127: v1(83.9,44.82) 83.94,44.85 84.7,44.85 85.99,43.56 85.99,41.99 87.02,40.96 87.02,40.26 88.56,38.72 88.56,37.74 93.02,33.28 v1(93.38,33.28)
  BOTTOM w0.102: CPU1.AD48 83.9,45.26 v1(83.9,44.82) ; v1(93.38,33.28) 93.67,32.99 94.01,32.99 RN1805.8
XDP_TRST#: length 18.5
  TOP w0.102: v1(83.42,45.25) 83.46,45.29 83.46,46.06 v2(83.24,46.29)
  L3 w0.127: v1(83.42,45.25) 83.42,44.71 85.53,42.6 85.53,41.76 86.51,40.78 86.51,40.05 88.05,38.51 88.05,37.53 91.08,34.51 v1(91.08,33.09)
  BOTTOM w0.102: v1(83.42,45.25) 83.38,45.2 CPU1.AB48 ; v1(91.08,33.09) 91.08,32.55 RN1806.3
XTL_19D2M_X1_CPU: length 20.6
  TOP w0.102: v2(57.76,47.07) 58.19,46.64 v1(58.35,46.64)
  L3 w0.127: v1(58.35,46.64) 59.34,46.64 60,47.3 61.99,47.3 62.71,48.01 64.34,48.01 64.8,48.47 66.81,48.47 69.15,50.82 70.7,50.82 70.99,50.52 v1(71.7,50.52)
  BOTTOM w0.102: v1(58.35,46.64) 58.3,46.58 57.27,46.58 R1603.2 56.99,46.8 C1601.1 55.32,46.8 X1601.1 ; v1(71.7,50.52) 71.8,50.42 CPU1.P24
XTL_19D2M_X2_CPU: length 21.9
  TOP w0.102: v2(57.72,45.8) 57.72,45.83 57.88,46 58.3,46 v1(58.34,45.96)
  L3 w0.127: v1(58.34,45.96) 58.5,46.13 59.56,46.13 60.22,46.79 62.2,46.79 63.1,47.69 64.43,47.69 64.85,48.11 66.77,48.11 69.25,50.59 70.57,50.59 v1(71.14,50.02)
  BOTTOM w0.102: v1(71.14,50.02) 71.04,50.12 CPU1.M22 ; X1601.3 54.17,46.01 C1602.1 56.25,45.94 R1603.1 57.17,46.09 58.21,46.09 v1(58.34,45.96)
XTL_32D768K_X1_CPU: length 19.1
  L3 w0.127: v1(57.86,50.1) 57.95,50.1 58.37,49.68 58.48,49.68 59.87,48.29 62.33,48.29 62.61,48.57 62.63,48.57 63.03,48.96 64.16,48.96 64.31,48.82 66.83,48.82 68.64,50.63 68.64,51.52 68.65,51.53 v1(68.65,51.63)
  BOTTOM w0.102: CPU1.M18 68.8,51.48 v1(68.65,51.63) ; X1802.1 53.39,49.65 53.47,49.73 54.38,49.73 54.58,49.93 C1807.1 55.54,49.93 R1816.1 55.69,49.79 v2(57.38,49.79) 57.55,49.79 v1(57.86,50.1)
XTL_32D768K_X2_CPU: length 17.9
  L3 w0.127: v1(58.58,50.19) 58.69,50.19 60.08,48.8 62.19,48.8 62.19,48.8 62.54,48.8 62.96,49.22 64.23,49.22 64.4,49.05 66.74,49.05 68.24,50.55 68.24,51.03 v1(68.18,51.09)
  BOTTOM w0.102: X1802.4 54.19,50.56 54.36,50.73 C1806.1 55.63,50.73 R1816.2 v2(56.57,50.71) 56.75,50.53 58.23,50.53 v1(58.58,50.19) ; v1(68.18,51.09) 68.29,50.97 CPU1.K18

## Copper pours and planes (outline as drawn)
1V_CPU_CORE on TOP: 64.29,41.86 63.62,42.53 63.01,42.53 62.87,42.67 62.87,43.13 62.97,43.23 65.33,43.23 65.55,43.01 65.55,42.67 65.81,42.42 65.81,42.01 65.66,41.86 ; 1 cut-out
1V_CPU_CORE on TOP: 80.52,48.99 79.97,49.54 79.87,49.54 78.46,50.95 78.28,50.95 76.92,52.32 76.05,52.32 75.52,52.85 75.52,53.24 76.1,53.82 76.19,53.82 76.3,53.7 76.5,53.7 76.97,54.17 76.97,54.31 76.82,54.46 76.82,54.46 76.67,54.61 76.67,54.86 76.99,55.18 77.25,55.18 77.52,54.91 77.95,54.91 78.23,54.63 78.73,54.63 78.79,54.7 79.05,54.7 79.29,54.46 79.29,54.21 80.18,53.32 80.18,52.73 80.18,52.56 80.29,52.44 80.47,52.44 81.05,51.86 81.35,51.86 81.53,52.03 81.82,52.03 81.99,51.86 82.52,51.86 82.99,51.39 82.99,50.69 82.24,49.94 81.85,49.94 81.22,49.3 80.98,49.3 80.66,48.99 ; 12 cut-outs
1V_CPU_CORE on TOP: 52.93,57.91 52.55,58.29 52,58.29 51.91,58.38 51.91,60.92 51.68,61.15 51.68,61.81 52.47,62.6 58.53,62.6 58.65,62.49 58.65,61.8 58.04,61.19 58.04,58.57 57.91,58.45 57.91,58.42 56.42,58.42 55.91,57.91 ; 15 cut-outs
1V_CPU_CORE on TOP: 58.97,41.27 58.75,41.48 58.72,41.48 58.65,41.56 58.65,41.66 59.16,42.17 60.36,42.17 60.43,42.1 60.43,41.78 60.27,41.63 59.33,41.63
1V_CPU_CORE on BOTTOM: 80.37,50 80.3,50.07 80.3,50.76 79.67,51.39 79.4,51.39 79.19,51.59 79.19,51.84 79.01,52.02 78.29,52.02 77.58,52.73 77.58,53.48 77.43,53.63 77.18,53.63 77.03,53.78 77.03,54.04 77.16,54.16 77.48,54.16 77.58,54.26 77.58,54.45 77.85,54.71 78.13,54.71 78.18,54.66 79.09,54.66 79.21,54.55 79.21,53.76 79.41,53.55 79.48,53.55 79.69,53.35 80.52,52.51 80.65,52.51 81.11,52.05 81.72,52.05 82.3,51.47 82.3,50.08 82.21,50
1V_CPU_CORE on BOTTOM: 52.37,57.94 51.53,58.78 51.53,61.01 51.53,61.01 52.07,61.01 52.07,62.03 52.07,62.03 51.54,62.03 51.53,62.04 51.53,63.61 51.93,64.01 57.96,64.01 58.35,64.4 59.25,64.4 59.36,64.29 59.36,59.81 59,59.46 59,58.62 58.89,58.51 58.07,58.51 57.6,58.04 56.25,58.04 56.15,57.94 ; 7 cut-outs
1V_CPU_CORE on L3: 64.13,41.77 63.76,42.14 63.76,43.08 64.42,43.73 65.69,43.73 66.43,44.46 67.5,44.46 71.13,48.09 72.31,48.09 73.04,48.82 76.14,48.82 79.32,52.01 79.59,52.01 79.7,51.9 80.27,51.9 80.41,52.04 80.76,52.04 80.92,51.88 81.32,51.88 81.48,52.04 81.75,52.04 81.75,52.04 82.43,51.36 82.43,50 82.33,49.91 81.36,49.91 76.83,45.38 71.55,45.38 71.04,45.89 70.73,45.89 69.97,45.13 69.97,43.76 68.47,42.26 65.86,42.26 65.37,41.77 ; 1 cut-out
1V_CPU_CORE on L4: outline of 88 points within 52.76,40.52 83.06,61.44 ; 1 cut-out
1V_CPU_CORE on L5VCC: 59.87,41.71 59.14,42.44 59.14,50.41 58.35,51.2 57.23,51.2 56.27,52.15 56.27,54.18 56.28,55 54.17,57.11 53.27,57.11 52.92,57.45 52.92,60.93 54.03,62.04 62.48,62.04 63.18,61.34 63.18,59.31 63.56,58.93 63.56,56.18 64.88,54.87 67.56,54.87 68.13,54.3 68.86,54.3 71.12,56.56 72.15,56.56 72.28,56.43 73.24,55.47 73.24,54.75 74.69,53.3 75.91,53.3 77.44,54.84 80.77,54.84 80.77,53.89 82.27,52.39 82.27,50.31 80.49,48.53 71.42,48.53 70.41,47.51 69.14,47.51 68.25,46.62 65.96,46.62 65.33,45.99 65.33,42.66 64.68,42.01 64.09,42.01 63.78,41.71 ; 1 cut-out
5V_HDMI on TOP: 9.6,80.6 9.53,80.67 9.53,81.59 10.1,82.16 15.57,82.16 16.01,81.72 16.01,81.31 15.69,80.98 14.57,80.98 14.18,80.6 ; 2 cut-outs
5V_HDMI on BOTTOM: 13.48,80.32 13.28,80.53 13.28,81.59 13.54,81.85 15.69,81.85 15.95,81.59 15.95,80.46 15.81,80.32
5V_PWR on BOTTOM: 21.39,16.99 21.23,17.15 21.23,24.61 21.29,24.67 23.04,24.67 23.24,24.46 23.24,23.45 23.71,22.98 32.66,22.98 33.02,22.62 33.02,18.09 32.41,17.48 23.13,17.48 22.64,16.99 ; 2 cut-outs
5V_S0 on TOP: 145.11,80.7 144.98,80.83 144.98,82 145.58,82.6 147.65,82.6 147.85,82.4 147.85,80.98 147.84,80.96 147.84,80.79 147.75,80.7 ; 2 cut-outs
5V_S0 on BOTTOM: 148.91,43.18 148.68,43.41 148.68,44.94 147.71,45.91 147.71,46.6 147.78,46.68 151.1,46.68 151.49,46.29 151.49,43.49 151.18,43.18 ; 3 cut-outs
5V_S0 on BOTTOM: 133.68,88.55 133.45,88.78 133.45,89.7 133.32,89.83 130.92,89.83 130.85,89.76 129.66,89.76 129.04,90.38 129.04,91 129.46,91.42 131.83,91.42 132.04,91.63 132.04,93.33 132.22,93.5 135.65,93.5 136.71,92.44 136.71,91.54 136.96,91.29 137.91,91.29 137.94,91.26 137.94,91.1 137.92,91.08 136.62,91.08 136.39,90.85 136.39,89.4 136.51,89.28 137.92,89.28 137.94,89.26 137.94,89.1 137.91,89.07 136.85,89.07 136.33,88.55 ; 9 cut-outs
5V_S0 on BOTTOM: 149.07,76.99 146.17,79.9 145.63,79.9 144.98,80.55 144.98,81.43 144.99,81.44 144.99,82.02 145.59,82.62 147.68,82.62 148,82.3 148,81.06 149.82,79.24 153.82,79.24 153.86,79.2 153.86,78.9 153.84,78.88 151.58,78.88 151.3,78.59 151.3,78.27 150.02,76.99
5V_S0 on L3: 150.44,77.92 147.52,77.92 144.59,74.99 144.59,73.4 144.84,73.14 145.61,73.14 148.72,76.26 150.39,76.26 150.64,76.5 150.64,77.72
5V_S0 on L4: 144.68,81.02 138.84,81.02 136.96,82.89 135.43,82.89 131.97,86.35 131.97,90.43 131.19,91.21 128.99,91.21 128.89,91.11 128.89,90.25 129.07,90.07 129.07,85.93 131.67,83.32 132.92,83.32 135.23,81.01 135.93,81.01 137.48,79.47 138.22,79.47 139.21,78.48 140.45,78.48 141.43,79.46 145.56,79.46 146.76,80.66 146.76,81.35 146.58,81.53 145.19,81.53
5V_S0 on L5VCC: 149.44,43.3 149.13,43.61 149.13,50.07 147.61,51.59 144.75,51.59 144.75,58.68 145.43,59.37 145.43,63.2 144.75,63.89 144.75,73.83 145.52,74.6 147.58,74.6 148.01,74.16 148.01,71 146.4,69.39 146.4,64.43 147.3,63.52 147.3,55.77 151.53,51.55 151.53,43.63 151.2,43.3
5V_S5 on TOP: 11.3,14.13 10.74,14.68 8.3,14.68 8.06,14.92 8.06,17.39 8.41,17.74 16.01,17.74 16.6,18.33 16.6,24.02 16.78,24.2 16.78,25.81 18.13,27.16 18.13,38.5 18.54,38.91 18.54,39.45 17.45,40.54 17.45,43.08 16.03,44.5 16.03,60.84 11.28,65.6 11.28,67.86 12.02,68.6 12.02,79.17 12.25,79.4 13.22,79.4 13.4,79.22 13.4,67.18 14.49,66.1 16.15,66.1 17.8,64.44 17.8,63.73 17.93,63.61 17.93,62 19.03,60.9 19.03,57.79 20.74,56.08 20.74,51.71 20.47,51.44 20.47,51.11 22.17,49.4 22.17,42.55 23.24,41.48 23.24,34.78 23.75,34.28 23.75,27.65 21.7,25.6 21.7,15.14 20.69,14.13 ; 2 cut-outs
5V_S5 on BOTTOM: 18.94,16.77 18.59,17.12 18.59,24.1 18.88,24.38 19.57,24.38 19.83,24.64 21.01,24.64 21.01,16.95 20.83,16.77
5V_S5 on BOTTOM: 152.58,75.86 151.8,76.65 151.8,78.62 151.93,78.75 153.82,78.75 153.93,78.64 153.93,75.96 153.84,75.86
5V_S5 on BOTTOM: 143.98,41.3 143.77,41.51 143.77,46.24 144.17,46.63 146.37,46.63 146.39,46.62 146.39,45.93 146.11,45.65 146.11,43.33 146.34,43.1 146.34,41.56 146.08,41.3 ; 4 cut-outs
5V_S5 on BOTTOM: 41.95,11.43 41.84,11.53 41.84,12.06 42.06,12.27 42.94,12.27 42.99,12.22 44.59,12.22 44.61,12.2 44.61,12.05 44.58,12.02 43.36,12.02 42.77,11.43
5V_S5 on BOTTOM: 21.55,51.5 21.25,51.81 19.93,51.81 19.69,52.05 19.69,54.05 19.96,54.33 20.95,54.33 21.03,54.26 21.03,53.92 22.09,52.86 22.09,51.54 22.05,51.5 ; 1 cut-out
5V_S5 on BOTTOM: 22.4,59.18 22.38,59.2 22.38,60.49 22.63,60.73 23.54,60.73 23.72,60.55 23.72,60.34 23.52,60.15 23.52,59.59 23.12,59.18 ; 1 cut-out
5V_S5 on BOTTOM: 12.83,77.13 12.68,77.28 12.68,79.27 13.01,79.6 15.92,79.6 15.95,79.57 15.95,77.55 15.53,77.13
5V_S5 on BOTTOM: 144.64,46.99 144.52,47.1 144.52,47.6 144.67,47.75 145.06,47.75 145.4,47.41 146.33,47.41 146.35,47.38 146.35,47.23 146.33,47.21 145.44,47.21 145.22,46.99
5V_S5 on L4: 131.5,0.51 130.8,0.8 130.51,1.5 130.51,3.5 130.07,4.57 129,5.01 113.95,5.01 113.95,5.26 73.97,5.26 72.73,6.51 67.49,6.51 66.25,5.26 21.42,5.26 16.06,10.62 16.06,23.57 16.67,24.17 20.14,24.17 21.29,23.02 21.29,14.23 24.35,11.17 41.11,11.17 42.18,12.24 43.32,12.24 44.39,11.17 99.58,11.17 100.56,12.14 105.5,12.14 106.48,11.17 121.33,11.17 121.45,11.05 139.78,11.05 140.37,11.64 140.37,12.01 142.46,14.1 142.46,24.01 143.61,25.16 143.61,35.93 144.66,36.99 144.66,40.24 143.92,40.98 143.92,48.42 144.66,49.17 144.66,53.36 145.06,53.76 145.06,57.86 144.37,58.54 144.37,60.98 142,63.36 142,72.71 148.45,79.16 148.47,79.16 148.57,79.25 152.43,79.25 152.53,79.16 152.53,77.88 152.52,77.87 152.52,77.41 152.29,77.18 151.84,77.18 144.48,69.82 144.48,65.47 147.05,62.9 147.05,59.21 147.52,58.74 147.52,56.01 150.27,53.26 150.27,43.31 151.85,41.73 151.85,21.48 151.84,21.47 151.84,12.25 150.35,10.76 147.67,10.76 147.42,10.5 146.76,10.18 146.49,9.5 146.49,1.5 146.2,0.8 145.5,0.51 ; 2 cut-outs
5V_USB30 on BOTTOM: 20.79,49.83 20.72,49.9 20.72,50.89 20.58,51.03 19.47,51.03 19.04,51.46 19.04,54.92 18.99,54.97 18.83,54.97 17.14,56.66 14.77,56.66 14.22,57.21 14.22,59.16 14.56,59.49 21.65,59.49 21.72,59.42 21.72,57.05 21.34,56.66 21.33,56.66 21.09,56.42 21.09,55.12 20.94,54.97 20.19,54.97 19.58,54.36 19.58,51.98 19.91,51.65 21.1,51.65 21.32,51.42 21.32,49.89 21.26,49.83 ; 3 cut-outs
12V_BT+ on BOTTOM: 118.99,15.16 118.87,15.29 118.87,17.4 118.21,18.06 116.22,18.06 116.2,18.08 115.72,18.08 115.14,18.66 113.73,18.66 113.62,18.77 113.62,20.59 113.18,21.02 111.14,21.02 110.89,21.27 110.89,22.78 111.06,22.95 121.09,22.95 121.21,23.07 121.21,24.56 121.31,24.65 122.34,24.65 122.43,24.57 122.43,20.78 122.42,20.77 122.42,20.64 122.32,20.54 121.22,20.54 121.14,20.47 121.14,19.35 121.55,18.94 122.34,18.94 122.63,18.65 122.63,17.76 122.76,17.63 124.01,17.63 124.05,17.59 124.05,15.4 123.81,15.16 ; 4 cut-outs
19V_AD+ on BOTTOM: 141.67,10.81 141.64,10.84 141.64,14.16 140.93,14.87 139.99,14.87 139.7,15.16 139.7,19.26 139.77,19.34 140.56,19.34 141.85,18.04 144.81,18.04 144.84,18.01 144.84,15.97 144.96,14.81 145.22,14.55 146.84,14.55 147.02,14.36 147.02,12.88 144.95,10.81 ; 5 cut-outs
19V_DCBATOUT on TOP: 137.93,22.67 137.18,23.42 137.18,24.54 135.93,25.79 131.45,25.79 130.38,24.72 116.68,24.72 116.4,25 116.4,28.46 116.64,28.7 134.94,28.7 135.9,29.66 142.03,29.66 143.52,28.17 143.52,24 142.19,22.67
19V_DCBATOUT on TOP: 43.48,23.72 43.11,24.09 43.11,28.64 43.57,29.11 43.57,32.08 42.85,32.8 40.38,32.8 39.15,34.04 39.07,34.04 39.07,34.05 36.33,34.05 34.42,35.96 34.42,39.06 35.79,40.44 35.79,45.67 36.42,46.3 36.42,56.81 37.6,57.98 37.6,59.64 37.29,59.94 36.91,59.94 36.83,60.02 36.83,60.52 36.69,60.66 36.11,60.66 34.87,61.9 34.87,69.56 36.19,70.88 36.22,70.88 36.22,70.9 37.43,72.1 38.96,72.1 39.55,72.69 39.55,78.29 36.83,81.01 36.83,83.17 37.05,83.39 39.55,83.39 40.87,82.07 42.95,82.07 48.9,76.12 48.9,74.05 49.44,73.5 49.44,56.65 49.33,56.54 48.53,56.54 48.08,56.08 48.08,54.44 47.91,54.28 46.11,54.28 43.67,51.84 43.67,47.08 43.58,46.98 43.58,42.84 47.29,39.13 47.29,29.34 46.51,28.56 46.51,23.93 46.29,23.72 ; 3 cut-outs
19V_DCBATOUT on BOTTOM: 117.49,23.18 117.49,23.18 117.07,23.18 116.57,23.68 116.57,26.05 116.98,26.47 120.41,26.47 120.61,26.26 120.61,24.88 120.34,24.61 119.15,24.61 119.08,24.54 119.08,23.38 118.88,23.18
19V_DCBATOUT on BOTTOM: 34.7,61.35 34.37,61.68 34.37,64.61 34.78,65.02 34.78,70.79 34.97,70.98 39.24,70.98 40.23,69.99 45.38,69.99 45.45,69.92 45.45,69.28 45.34,69.18 43.98,69.18 43.87,69.07 43.87,67.43 44.02,67.27 44.86,67.27 45.06,67.07 45.06,63.62 44.86,63.41 39.75,63.41 39.15,62.81 39.15,61.55 38.95,61.35 ; 3 cut-outs
19V_DCBATOUT on BOTTOM: 79.55,19.45 79.37,19.63 79.37,22.53 79.63,22.8 82.83,22.8 83.06,22.57 83.06,19.64 82.86,19.45
19V_DCBATOUT on BOTTOM: 134.58,21.92 134.48,22.01 134.48,22.41 134.6,22.53 135.27,22.53 135.37,22.63 135.37,24.8 136.43,25.86 141.75,25.86 142.2,26.31 142.2,27.27 142.35,27.42 143.1,27.42 143.2,27.53 143.78,27.53 143.93,27.39 143.93,26.44 144.52,25.85 144.52,24.98 144.92,24.58 145.42,24.58 145.56,24.44 145.56,23.15 145.5,23.09 141.52,23.09 140.35,21.92 ; 6 cut-outs
19V_DCBATOUT on BOTTOM: 41.21,21.3 41.16,21.35 41.16,22.91 41.49,23.24 41.49,25.35 41.73,25.59 43.33,25.59 43.54,25.38 44.09,25.38 44.3,25.58 44.3,26.36 44.6,26.66 47.43,26.66 47.65,26.44 47.65,23.01 46.43,21.79 44.8,21.79 44.76,21.83 44.76,22.38 44.59,22.55 43.16,22.55 42.99,22.38 42.99,21.87 42.42,21.3 ; 2 cut-outs
19V_DCBATOUT on BOTTOM: 35.36,54.21 35.16,54.41 35.16,56.72 35.59,57.15 40.32,57.15 40.68,56.8 40.68,54.57 40.31,54.21
19V_DCBATOUT on BOTTOM: 43.72,30.76 43.51,30.97 43.51,32.3 43.46,32.34 41.92,32.34 41.47,31.9 41.47,31.6 41.07,31.2 39.91,31.2 39.83,31.28 39.83,32.56 39.62,32.77 39.24,32.77 38.94,33.07 38.94,34.17 39.07,34.31 46.54,34.31 46.73,34.12 46.73,30.93 46.56,30.76 ; 1 cut-out
19V_DCBATOUT on BOTTOM: 36.6,77.67 36.15,78.13 36.15,84.51 39.72,88.09 39.72,93.55 40.66,94.49 66.32,94.49 68.03,96.2 68.6,96.2 68.61,96.21 77.3,96.21 78.58,94.93 80.56,94.93 81.02,94.47 83.9,94.47 85.05,93.33 85.05,89.24 86.77,87.51 87.37,87.51 87.73,87.16 87.73,85.93 87.71,85.91 84.69,85.91 81.73,88.88 79.29,88.88 76.76,91.41 72.46,91.41 70.49,89.45 61.95,89.45 61.3,88.8 50,88.8 49.35,89.45 44.49,89.45 43.8,88.76 43.8,87.12 43.75,87.07 43.73,87.07 41.27,84.61 41.27,83.79 41.27,83.79 41.27,78.26 40.68,77.67 ; 4 cut-outs
19V_DCBATOUT on L4: 119.5,18.47 118.07,17.05 52.74,17.05 52.15,17.91 51.55,17.05 46.34,17.05 45.82,17.57 45.82,19.53 45.82,19.53 45.82,21.84 43.96,23.7 43.96,23.7 43.83,23.83 43.83,25.53 44.03,25.73 44.03,26.81 43.83,27.01 43.83,30.21 43.47,30.57 43.47,32.29 43.7,32.51 46.19,32.51 46.38,32.32 46.38,29.7 47.61,28.47 48.39,28.47 48.64,28.23 50.98,28.23 51.53,27.68 57.8,27.68 58.33,27.15 61.31,27.15 61.37,27.09 61.37,27.01 61.98,26.11 62.5,27.06 62.6,27.16 62.7,27.16 63.55,26.84 63.84,27.7 63.84,27.81 63.94,27.91 71.17,27.91 71.83,27.26 73.46,27.26 73.66,27.46 73.66,30.1 74.27,30.71 77.04,30.71 78.02,29.74 85.11,29.74 85.85,30.48 88.9,30.48 89.52,31.1 91.85,31.1 94.46,28.49 95.04,28.49 95.05,28.48 102.11,28.48 103.36,27.23 105.2,27.23 105.89,27.93 111.67,27.93 111.84,27.76 114.07,27.76 115.34,29.03 136.41,29.03 140.93,24.51 140.93,22.99 140.61,22.67 140.37,22.67 137.71,22.67 137.2,23.18 137.2,24.6 135.58,26.23 121.86,26.23 119.5,23.87 ; 11 cut-outs
19V_DCBATOUT_LCD on TOP: 45.47,82.33 44.74,83.06 44.74,83.98 44.86,84.1 47.17,84.1 47.33,83.94 47.33,82.54 47.12,82.34 45.75,82.34 45.74,82.33 ; 3 cut-outs
19V_DCBATOUT_LCD on BOTTOM: 42.83,77.78 42.69,77.92 42.69,81.56 42.88,81.74 43.63,81.74 43.78,81.88 43.78,83.31 45.2,84.73 47.68,84.73 47.76,84.65 47.76,83.17 46.66,82.07 46.07,82.07 44.45,80.45 44.45,77.89 44.34,77.78
+5V_AVDD on TOP: 145.02,83.02 144.76,83.28 144.76,85.57 144.91,85.71 145.95,85.71 146.23,85.43 146.23,84.14 146.47,83.9 146.76,83.9 146.89,83.78 146.89,83.13 146.79,83.02 ; 3 cut-outs
+5V_AVDD on BOTTOM: 143.52,83.28 143.41,83.38 143.41,85.34 143.17,85.58 142.64,85.58 142.47,85.75 142.47,85.98 142.6,86.11 143.51,86.11 143.81,85.8 145.2,85.8 145.53,85.48 145.53,83.47 145.33,83.28 ; 1 cut-out
GND on TOP: 138.95,48.11 136.25,50.81 136.25,55.86 136.78,56.39 138.21,56.39 139.71,57.89 140.9,57.89 141.25,57.54 141.25,53.78 139.34,51.87 139.34,51.87 139.34,48.25 139.2,48.11
GND on TOP: 62.94,63.89 62.83,64 62.83,64.37 62.41,64.79 62.41,64.97 62.63,65.19 62.77,65.19 63.47,64.48 63.47,64.01 63.36,63.89
GND on TOP: 59.37,52.4 59,52.78 59,53.99 59.17,54.16 59.58,54.16 59.85,54.43 61.07,54.43 61.18,54.32 61.18,53.98 61.04,53.83 60.39,53.83 60.14,53.59 60.14,52.72 59.82,52.4 ; 3 cut-outs
GND on TOP: 60.88,56.43 60.81,56.5 60.81,56.51 59.44,57.89 59.44,58.4 59.49,58.45 59.99,58.45 60.05,58.4 60.05,58.04 60.55,57.53 61.62,57.53 61.8,57.71 62.26,57.71 62.48,57.48 62.48,57.3 62.2,57.02 62.2,56.55 62.08,56.43 ; 2 cut-outs
GND on TOP: 172.42,75.87 172.28,76.02 172.28,77.58 172.43,77.73 174.4,77.73 174.47,77.66 174.47,76.28 174.06,75.87 ; 3 cut-outs
GND on TOP: 39.75,3.49 39.42,3.83 39.42,4.28 39.65,4.52 40.7,4.52 40.82,4.39 40.82,3.58 40.74,3.49
GND on TOP: 20.11,74.98 19.86,75.23 19.86,75.62 20.6,76.37 22.8,76.37 22.84,76.33 22.84,75.06 22.76,74.98 ; 1 cut-out
GND on TOP: 53.44,8.61 53.35,8.7 53.35,9.63 53.63,9.92 53.63,10.46 53.71,10.53 54.45,10.53 54.58,10.4 54.58,9.11 54.39,8.92 54.16,8.92 53.85,8.61 ; 1 cut-out
GND on TOP: 165.21,94.36 165.06,94.51 165.06,102.49 170.89,102.49 170.89,100.9 173.9,97.89 176.91,100.9 176.91,102.49 177.9,102.49 178.25,102.35 178.39,102 178.39,94.51 178.38,94.51 178.23,94.36 ; 1 cut-out
GND on TOP: 72.46,55.94 71.94,56.45 71.94,56.55 72.09,56.69 72.09,57 73.43,58.35 73.43,58.56 73,58.99 73,59.23 72.47,59.77 72.47,60.3 72.64,60.48 72.99,60.48 73.53,59.94 73.74,59.73 73.93,59.73 74.48,60.28 74.48,60.5 74.13,60.86 74.13,61.11 74.41,61.39 74.6,61.39 75.41,60.58 75.41,60.31 74.43,59.34 74.43,58.65 73.96,58.18 73.96,57.58 73.2,56.82 73.2,56.59 72.55,55.94 ; 1 cut-out
GND on TOP: 50.74,72.65 50.66,72.72 50.66,73.31 50.78,73.43 51.35,73.43 51.53,73.6 51.53,76.92 51.61,77 59.31,77 59.49,76.82 59.49,73.14 59.27,72.92 51.75,72.92 51.47,72.65 ; 6 cut-outs
GND on TOP: 113.18,89.13 112.98,89.33 112.98,91.11 113.16,91.29 113.49,91.29 113.64,91.44 113.64,94.59 112.98,95.25 112.98,95.56 113.11,95.68 117.09,95.68 117.27,95.51 117.27,89.84 117.12,89.69 113.84,89.69 113.28,89.13
GND on TOP: 100.76,21 100.1,21.66 100.1,22.09 102.18,24.18 103.43,24.18 103.44,24.16 104.16,24.16 104.34,23.99 104.34,23.55 101.8,21
GND on TOP: 113.34,29.3 113.08,29.56 110.81,29.56 110.63,29.73 110.63,30.46 110.75,30.58 134.21,30.58 136.37,32.74 136.61,32.74 136.96,32.39 136.96,31.84 134.43,29.3
GND on TOP: 58.55,87.3 58.34,87.5 58.34,88.77 58.51,88.94 58.91,88.94 58.92,88.94 59.27,88.94 59.36,88.85 59.36,87.43 59.23,87.3 ; 1 cut-out
GND on TOP: 80.89,53.06 80.71,53.24 80.45,53.24 79.44,54.25 79.44,54.46 79.08,54.82 78.76,54.82 78.68,54.74 78.3,54.74 78.13,54.91 78.13,55.07 79.02,55.96 79.02,56.49 77.77,57.74 77.77,58.28 78.29,58.79 78.29,59 77.8,59.49 77.56,59.49 77.27,59.2 77.02,59.2 76.77,59.46 76.77,59.65 77.08,59.96 77.08,60.44 76.75,60.77 76.75,61.01 77.36,61.61 77.36,62.35 78.26,63.25 78.26,64.72 79.91,66.36 79.91,66.71 78.97,67.64 78.17,67.64 77.43,66.9 77.1,66.9 76.85,67.16 76.85,67.67 77.44,68.26 80.74,68.26 81.33,67.67 81.33,67.51 80.93,67.1 80.93,66.78 81.46,66.24 81.46,63.93 79.69,62.15 79.69,60.56 79.99,60.26 79.99,59.83 79.71,59.54 79.71,57.61 79.98,57.33 79.98,57.04 79.15,56.2 79.15,55.92 80.96,54.11 81.95,54.11 82.45,53.61 82.45,53.33 82.3,53.18 82.05,53.18 81.84,53.39 81.46,53.39 81.13,53.06 ; 9 cut-outs
GND on TOP: 26.82,68.32 26.74,68.4 26.74,68.68 26.36,69.06 26.36,72.22 25.94,72.64 25.94,73.24 26,73.31 26.5,73.31 26.6,73.21 26.6,72.68 26.86,72.41 27.01,72.41 27.09,72.34 27.09,71.6 26.98,71.49 26.98,69.31 27.37,68.91 27.67,68.91 27.68,68.92 28.13,68.92 28.2,68.85 28.2,68.4 28.12,68.32
GND on TOP: 32.58,81.86 32.46,81.98 32.46,82.27 32.84,82.65 32.84,82.99 32.93,83.08 34.36,83.08 34.45,82.99 34.45,82.42 34.36,82.32 33.36,82.32 32.89,81.86 ; 1 cut-out
GND on TOP: 92.68,28.14 91.95,28.88 89.45,28.88 89.25,29.08 89.25,29.5 90.99,31.24 92.32,31.24 94.08,33 94.08,34.84 95.73,36.49 95.73,37.64 96.74,38.64 96.74,39.18 96.53,39.4 95.05,39.4 94.9,39.54 94.9,39.74 94.73,39.74 94.51,39.52 94.51,36.93 92.02,34.44 89.48,34.44 88.72,35.2 88.72,38.22 93.26,42.77 93.48,42.77 95.85,45.13 97.8,45.13 98.79,44.14 98.79,35.75 98.79,35.75 98.79,35.2 93.86,30.27 93.86,29.76 93.62,29.52 93.62,28.29 93.47,28.14 ; 2 cut-outs
GND on TOP: 31.69,61.47 31.59,61.57 31.59,62.08 31.73,62.22 31.73,62.63 32.06,62.96 33.03,62.96 33.14,62.85 33.14,61.57 33.05,61.47 ; 1 cut-out
GND on TOP: 64.18,57.39 63.89,57.67 63.89,57.79 64.32,58.22 64.77,58.22 65.48,58.93 65.66,58.93 66.02,58.57 66.02,58.45 65.72,58.15 65.72,57.68 65.58,57.54 65.14,57.54 64.98,57.7 64.64,57.7 64.32,57.39
GND on TOP: 74.66,7.2 74.13,7.74 74.13,9.03 74.26,9.16 75.84,9.16 75.96,9.05 75.96,8.24 76.43,7.76 76.43,7.4 76.24,7.2
GND on TOP: 151.22,55.14 151,55.35 151,60.56 149,62.56 148.98,62.56 145.96,65.58 145.96,69.12 148.94,72.1 152.49,72.1 152.49,70.51 150.24,70.51 147.23,67.5 150.24,64.49 152.49,64.49 152.49,62.56 152.52,62.53 152.52,55.35 152.31,55.14
GND on TOP: 57.47,85 57.3,85.17 57.3,86.1 57.54,86.34 58.05,86.34 58.22,86.17 58.22,85.47 57.75,85 ; 1 cut-out
GND on TOP: outline of 204 points within 0.51,0.51 95.26,102.5 ; 11 cut-outs
GND on TOP: 61.47,80.29 60.92,80.84 60.92,82.4 60.42,82.9 60.42,83.59 60.8,83.97 62.93,83.97 63.07,83.82 63.07,80.54 62.82,80.29 ; 5 cut-outs
GND on TOP: 105.02,9.5 104.86,9.66 104.86,16.71 104.96,16.81 106.65,16.81 106.91,17.07 106.91,17.48 106.98,17.55 107.37,17.55 107.47,17.45 107.47,17.02 107.62,16.87 112.42,16.87 112.62,16.68 112.62,9.59 112.53,9.5 ; 1 cut-out
GND on TOP: outline of 186 points within 62.54,39.83 88.04,60.23 ; 59 cut-outs
GND on TOP: 56.34,41.7 56.1,41.94 56.1,42.75 57.12,43.78 57.26,43.78 57.56,43.48 57.56,43.36 56.85,42.65 56.85,41.86 56.69,41.7
GND on TOP: 112.65,64.24 111.3,65.58 109.63,65.58 109.47,65.74 109.47,71.68 109.5,71.71 112.98,71.71 113.11,71.58 113.11,65.66 113.31,65.46 113.74,65.46 113.82,65.38 113.82,64.31 113.74,64.24
GND on TOP: 138.23,86.96 138.15,87.05 138.15,87.7 138.45,88 138.45,88.95 138.15,89.26 138.15,93.87 138.29,94.01 139.36,94.01 139.54,93.84 139.54,92.56 140.15,91.94 142.56,91.94 142.62,91.89 142.62,87.81 142.39,87.58 139.35,87.58 138.73,86.96 ; 6 cut-outs
GND on TOP: 64.32,0.51 64.32,4.18 64.56,4.41 64.56,7.13 64.63,7.21 66.06,7.21 66.25,7.4 66.25,8.03 66.32,8.11 71.34,8.11 74.01,5.43 74.01,5.01 73.9,5.01 72.83,4.57 72.39,3.5 72.39,1.5 72.1,0.8 71.4,0.51 ; 2 cut-outs
GND on TOP: 50.55,57.94 50.44,58.04 50.44,58.45 50.65,58.65 50.65,61.87 50.3,62.21 50.3,66.57 50.53,66.8 58.88,66.8 59.44,66.24 59.44,59.02 58.83,58.41 58.46,58.41 58.32,58.55 58.32,61.25 58.78,61.72 58.78,62.72 58.54,62.97 52.62,62.97 51.55,61.89 51.55,61.05 51.75,60.85 51.75,58.31 51.38,57.94 ; 26 cut-outs
GND on TOP: 103.28,18.63 102.14,19.78 102.14,20.08 102.42,20.36 104.14,20.36 104.37,20.14 104.37,18.81 104.19,18.63
GND on TOP: 45.23,84.29 44.88,84.65 44.88,85.88 45.04,86.04 46.96,86.04 47.09,85.91 47.09,84.53 46.86,84.29 ; 3 cut-outs
GND on TOP: 75.13,53.28 73.72,54.68 73.72,55 73.93,55.21 75.21,55.21 75.37,55.05 75.89,55.05 76.08,55.25 76.31,55.25 76.54,55.02 76.54,54.54 76.79,54.28 76.79,54.16 76.46,53.83 76.37,53.83 76.18,54.03 76.07,54.03 75.33,53.28
GND on TOP: 63.48,45.06 63.4,45.13 63.4,46.17 63.69,46.47 64.62,46.47 64.75,46.34 64.75,45.94 64.68,45.87 64.68,45.15 64.59,45.06 ; 1 cut-out
GND on TOP: 109.47,23.09 108.61,23.95 108.61,24.21 107.87,24.94 106.68,24.94 106.22,25.4 106.22,28.68 106.48,28.93 112.17,28.93 115.57,25.53 115.57,24.59 114.07,23.09
GND on TOP: 79.28,74.32 78.62,74.98 78.62,79.96 80.86,82.2 81.22,82.2 81.25,82.17 81.25,75.1 80.47,74.32 ; 4 cut-outs
GND on TOP: 21,52.35 20.91,52.44 20.91,56.66 19.63,57.95 19.63,58.38 19.71,58.46 19.85,58.46 20.72,59.33 21.33,59.33 21.41,59.25 21.41,57.97 22.08,57.3 23.01,57.3 23.16,57.16 23.16,56.75 23.05,56.64 22.5,56.64 21.84,55.98 21.84,54.15 21.61,53.92 21.61,52.53 21.44,52.35 ; 1 cut-out
GND on TOP: 131.5,0.51 130.8,0.8 130.51,1.5 130.51,3.5 130.36,4.14 129.96,4.66 135.46,4.66 139.59,8.8 142.35,8.8 142.56,9.01 143.83,9.01 144.15,8.69 146.49,8.69 146.49,1.5 146.2,0.8 145.5,0.51
GND on TOP: 19.63,59.94 19.48,60.09 19.48,61.03 19.62,61.17 20.25,61.17 20.4,61.31 20.4,61.8 20.51,61.91 21.68,61.91 22,62.23 22.49,62.23 22.58,62.15 22.58,61.62 22.39,61.43 22.39,60.86 22.32,60.79 21.82,60.79 21.46,61.16 20.82,61.16 20.13,60.47 20.13,60.12 19.95,59.94 ; 1 cut-out
GND on TOP: 28.94,70.56 28.79,70.71 28.79,70.95 29.08,71.24 29.08,74.08 28.81,74.35 28.81,75.13 28.89,75.21 29.34,75.21 29.53,75.02 29.53,74.43 29.69,74.27 29.69,71.04 29.21,70.56
GND on BOTTOM: 44.94,7.77 44.79,7.92 44.79,15.21 44.99,15.41 45.92,15.41 46.13,15.2 46.13,13.91 45.76,13.54 45.76,12.35 45.88,12.23 46.81,12.23 46.83,12.21 46.83,12.04 46.8,12.02 45.88,12.02 45.83,11.97 45.83,8.15 45.45,7.77 ; 2 cut-outs
GND on BOTTOM: 18.47,80.1 18.37,80.2 18.37,82.63 18.51,82.78 19.98,82.78 20.15,82.6 20.15,80.21 20.04,80.1
GND on BOTTOM: 45.01,19.82 44.57,20.26 44.03,20.26 43.96,20.33 42.45,20.33 42.36,20.23 42.36,19.94 42.31,19.89 41.2,19.89 41.18,19.92 41.18,20.28 41.12,20.34 39.24,20.34 38.83,19.93 38.45,19.93 38.3,20.08 38.3,20.45 38.55,20.7 39.28,20.7 39.38,20.6 41.09,20.6 41.18,20.68 41.18,21 41.22,21.04 44.64,21.04 45.23,21.63 46.54,21.63 47.88,22.98 47.88,26.43 48.09,26.64 49.66,26.64 49.79,26.5 49.79,26 50.01,25.79 50.01,21.29 48.54,19.82 ; 2 cut-outs
GND on BOTTOM: 138.18,15.07 138.02,15.23 138.02,16.02 137.64,16.4 136.2,16.4 135.99,16.62 135.99,18.04 135.31,18.72 135.31,20.27 135.39,20.36 137.35,20.36 137.84,20.85 137.84,21.53 137.98,21.67 140.61,21.67 140.83,21.44 140.83,19.95 140.52,19.63 139.68,19.63 139.38,19.33 139.38,16.96 139.39,16.95 139.39,15.29 139.17,15.07 ; 8 cut-outs
GND on BOTTOM: 92.61,30.61 92,31.22 92,31.5 93.22,32.72 93.93,32.72 94.41,32.23 94.41,31.83 93.19,30.61
GND on BOTTOM: 29.62,76.07 28.9,76.79 28.9,79.11 29.06,79.27 31.8,79.27 32.16,78.91 32.16,76.88 31.35,76.07 ; 1 cut-out
GND on BOTTOM: 103.65,11.33 103.62,11.36 103.62,13.58 103.94,13.9 103.94,16.77 104.04,16.87 104.52,16.87 104.81,16.58 104.81,11.7 104.44,11.33
GND on BOTTOM: 152.96,84.71 152.96,83.44 153.03,83.36 154.03,83.36 154.1,83.29 154.1,82.25 154.28,82.07 154.81,82.07 155.09,82.35 155.09,82.55 155.19,82.65 155.19,83.16 154.74,83.62 154.74,84.43 154.46,84.71
GND on BOTTOM: 22.76,45.52 22.61,45.67 22.17,45.67 22.12,45.72 22.12,46.13 22.23,46.23 23.77,46.23 24.03,45.98 24.03,45.65 23.9,45.52
GND on BOTTOM: 34.95,49.01 34.89,49.07 34.89,50.47 34.7,50.66 30.44,50.66 30.34,50.75 30.34,52.45 30.51,52.62 30.73,52.62 30.74,52.61 35.59,52.61 35.99,52.2 35.99,49.55 36.07,49.47 36.76,49.47 36.81,49.42 36.81,49.09 36.73,49.01 ; 4 cut-outs
GND on BOTTOM: 106.43,9.6 105.82,10.21 105.82,15.82 105.53,16.1 105.53,17.17 106.12,17.76 106.12,18.06 105.71,18.47 103.17,18.47 100.99,20.64 100.65,20.64 100.31,20.99 100.31,25.61 100.91,26.21 102.23,26.21 102.44,26.01 102.44,24.31 102.86,23.89 102.86,21.92 102.94,21.84 104.38,21.84 104.4,21.82 104.4,21.57 104.34,21.51 102.95,21.51 102.9,21.45 102.9,20.88 103.21,20.56 107.67,20.56 111.09,17.14 113.68,17.14 113.71,17.11 113.71,9.87 113.44,9.6 ; 3 cut-outs
GND on BOTTOM: 124.37,15.99 124.28,16.08 124.28,17.66 124.14,17.8 123,17.8 122.92,17.88 122.92,18.83 123.02,18.92 123.47,18.92 123.48,18.92 125.81,18.92 126.11,18.61 126.11,16.25 125.85,15.99
GND on BOTTOM: 0.51,33.66 0.51,41.29 2.22,41.29 2.56,41.63 2.56,46.94 2.76,47.14 10.78,47.14 11.91,46.68 12.66,47.65 12.66,49.56 15.18,49.56 15.95,48.79 15.95,45.36 15.49,44.9 14.74,44.9 14.04,45.6 12.6,45.6 12.39,45.39 12.39,42.97 12.09,42.66 11.77,42.66 11.41,43.03 11.41,43.41 10.58,44.24 7.01,44.24 5.19,42.42 5.19,40.96 5.63,40.53 5.63,33.66
GND on BOTTOM: 81.15,94.67 81,94.82 81,96.65 80.19,97.46 71.55,97.46 71.63,97.54 71.63,101.86 72.05,102.29 83.21,102.29 83.21,100.08 82.73,99.6 82.73,97.06 82.88,96.9 82.88,94.74 82.8,94.67
GND on BOTTOM: 80.74,69.37 79.92,70.19 79.92,72.72 77.79,74.85 77.79,76 78.49,76.7 78.49,79.33 79.76,80.6 79.76,81.74 81.38,83.36 83.13,83.36 83.25,83.24 83.25,82.64 82.6,81.99 82.6,78.98 82.45,78.84 81.92,78.84 81.44,78.35 81.44,71.22 82.08,70.58 82.08,69.52 81.93,69.37 ; 10 cut-outs
GND on BOTTOM: 35.05,71.54 34.88,71.71 34.88,73.06 37.87,76.05 40.41,76.05 40.56,76.2 40.56,76.89 40.71,77.04 44.68,77.04 44.93,76.79 44.93,75.41 44.69,75.17 44.08,75.17 43.86,74.94 43.86,73.9 43.73,73.77 41.57,73.77 40.06,73.77 39.57,73.28 39.57,71.65 39.45,71.54 ; 5 cut-outs
GND on BOTTOM: 58.83,27.89 58.77,27.95 58.77,28.54 58.46,28.85 58.46,29.45 58.52,29.5 59.57,29.5 60.14,28.93 60.14,28.03 60,27.89 ; 1 cut-out
GND on BOTTOM: 18.36,70.36 18.33,70.39 18.33,73.11 18.81,73.59 19.93,73.59 20.38,73.14 20.38,70.46 20.28,70.36
GND on BOTTOM: 79.68,29.8 79.07,30.41 79.07,30.63 79.2,30.76 80.64,30.76 80.77,30.63 80.77,29.87 80.7,29.8
GND on BOTTOM: 145.13,24.87 144.79,25.2 144.79,25.97 144.16,26.6 144.16,27.46 144.39,27.68 145.23,27.68 145.86,28.32 147.12,28.32 147.26,28.17 147.26,25.11 147.02,24.87 ; 3 cut-outs
GND on BOTTOM: 52.47,83.81 52.45,83.83 52.45,85.21 52.83,85.6 53.05,85.6 53.21,85.44 53.21,85.17 52.75,84.71 52.75,83.83 52.74,83.81
GND on BOTTOM: 101.63,77.4 100.99,78.03 100.99,80.95 99.34,82.6 99.34,83.36 100.15,84.18 103.4,84.18 104.47,83.11 104.47,77.5 104.37,77.4
GND on BOTTOM: 136.96,26.46 136.95,26.47 136.74,26.47 136.54,26.66 136.54,27.73 136.89,28.08 141.83,28.08 141.91,28 141.91,26.55 141.82,26.46 ; 2 cut-outs
GND on BOTTOM: 32.51,80.93 32.34,81.1 32.34,83.96 31.6,84.7 13.88,84.7 11.73,82.55 7.8,82.55 7.8,83.62 7.93,83.7 8.21,83.99 8.3,84.38 8.3,84.62 8.52,84.84 8.52,84.97 8.02,85.47 1.1,85.47 0.9,85.68 0.9,87.04 1.08,87.22 13.87,87.22 13.98,87.34 35,87.34 36.1,87.59 36.97,88.3 37.37,89.03 37.51,89.85 37.51,95.5 37.8,96.2 38.5,96.49 65.51,96.49 65.81,96.19 65.81,95.61 65.69,95.48 40.45,95.48 38.93,93.96 38.93,88.63 36.61,86.3 36.61,85.92 35.81,85.12 35.81,83.17 35.66,83.01 34.58,83.01 34.27,82.7 34.27,81.09 34.1,80.93 ; 2 cut-outs
GND on BOTTOM: 24.64,14.68 24.3,15.02 24.3,17.2 24.39,17.3 28.51,17.3 28.68,17.13 28.68,15.17 28.19,14.68 ; 1 cut-out
GND on BOTTOM: 65.31,86.26 65.2,86.37 65.2,88.51 65.39,88.7 67.67,88.7 67.8,88.57 67.8,86.43 67.63,86.26
GND on BOTTOM: 49.21,10.44 49.12,10.53 49.12,11.83 49.25,11.97 49.25,12.52 49.1,12.67 48.66,12.67 48.51,12.82 48.51,13.29 48.68,13.45 49.88,13.45 50.04,13.3 50.04,12.4 50.21,12.23 50.21,10.55 50.1,10.44 ; 2 cut-outs
GND on BOTTOM: 48.36,14.37 48.25,14.48 48.25,15.35 48.05,15.55 48.02,15.58 45.82,15.58 45.74,15.66 45.74,16.8 45.86,16.92 48.25,16.92 48.35,17.03 48.35,19.43 48.98,20.06 49.82,20.9 51.02,20.9 51.14,20.79 51.14,20.29 51.01,20.17 50.43,20.17 49.64,19.38 49.64,17.65 50.02,17.26 50.02,16.54 49.93,16.44 49.42,16.44 49.1,16.12 49.1,14.46 49.01,14.37 ; 6 cut-outs
GND on BOTTOM: 137.44,41.71 137.08,42.06 137.08,44.1 136.96,44.22 136.27,44.22 136.02,44.48 136.02,45.24 136.7,45.92 137.16,45.92 137.67,46.43 137.67,47.58 137.82,47.73 140.46,47.73 141.2,46.99 141.2,43.05 141.27,43.13 142.29,43.13 142.34,43.08 142.34,41.99 142.06,41.71
GND on BOTTOM: 46.41,49.32 46.25,49.49 46.25,50.66 46.45,50.85 48.62,50.85 48.73,50.74 48.73,49.47 48.58,49.32
GND on BOTTOM: 131.5,0.51 130.8,0.8 130.51,1.5 130.51,3.5 130.46,3.88 130.31,4.24 131.3,5.23 135.92,5.23 139.26,8.56 146.49,8.56 146.49,1.5 146.2,0.8 145.5,0.51
GND on BOTTOM: 25.76,32.01 25.01,32.76 25.01,34.4 25.33,34.72 28.17,34.72 28.96,33.93 28.96,32.12 28.85,32.01
GND on BOTTOM: 110.92,18.97 110.17,19.72 109.06,19.72 108.7,20.08 108.7,24.12 109.5,24.92 110.15,25.57 115.97,25.57 116.18,25.35 116.18,23.48 115.92,23.23 110.9,23.23 110.65,22.98 110.65,21.16 111.01,20.8 112.98,20.8 113.17,20.62 113.17,19.1 113.06,18.98 112.28,18.98 112.27,18.97
GND on BOTTOM: 131.53,87.2 131.53,87.2 131.06,87.2 130.86,87.4 130.86,89.61 131,89.75 131.38,89.75 131.58,89.55 133.28,89.55 133.34,89.49 133.34,88.88 133.27,88.8 132.07,88.8 132,88.73 132,88.3 132,88.29 132,87.33 131.86,87.2 ; 2 cut-outs
GND on BOTTOM: 150.38,46.86 150.27,46.97 150.27,48.34 150.28,48.34 150.28,48.54 150.6,48.87 151.25,48.87 151.34,48.78 151.34,48.66 151.47,48.53 151.47,47.12 151.21,46.86 ; 2 cut-outs
GND on BOTTOM: 138.94,60.11 138.77,60.28 138.77,63.42 138.9,63.55 140.26,63.55 140.3,63.51 140.3,61.17 140.36,61.12 141.45,61.12 141.58,60.99 141.58,60.29 141.4,60.11
GND on BOTTOM: 38.9,34.48 38.86,34.53 38.86,36.5 39.1,36.75 45.63,36.75 46.78,35.6 46.78,34.77 46.7,34.69 39.76,34.69 39.55,34.48 ; 1 cut-out
GND on BOTTOM: 146.51,43.23 146.35,43.4 146.35,45.71 146.52,45.88 146.52,49.21 146.52,49.21 146.52,49.33 146.36,49.48 146.36,50.15 146.13,50.38 146.13,52.2 146.42,52.48 147.38,52.48 147.96,51.9 147.96,50.38 147.75,50.17 147.75,49.55 147.53,49.34 147.53,48.39 147.53,48.39 147.53,45.91 148.43,45.01 148.43,43.38 148.29,43.23 ; 8 cut-outs
GND on BOTTOM: 22.31,40.64 21.08,41.87 21.08,42.3 21.18,42.4 21.51,42.4 22.66,41.25 22.73,41.18 23.39,41.18 23.5,41.07 23.5,40.72 23.42,40.64
GND on BOTTOM: 89,20.01 88.61,20.41 88.61,22.09 88.79,22.27 93.35,22.27 93.57,22.05 93.57,20.37 93.21,20.01 ; 2 cut-outs
GND on BOTTOM: 130.1,91.58 129.5,92.19 129.5,92.89 130.08,93.47 131.65,93.47 131.74,93.38 131.74,91.63 131.69,91.58 ; 2 cut-outs
GND on BOTTOM: 24.92,25.59 24.7,25.8 24.7,27.26 25.03,27.59 29.15,27.59 29.29,27.45 29.29,25.62 29.25,25.59 ; 2 cut-outs
GND on BOTTOM: 152.22,92.23 153.92,92.23 154,92.15 154,91.42 153.93,91.34 152.85,91.34 152.77,91.27 152.16,91.27 151.99,91.44 151.99,92
GND on BOTTOM: 22.23,43.16 22.1,43.28 22.1,43.66 22.2,43.77 22.73,43.77 23.16,44.2 23.93,44.2 24.05,44.07 24.05,43.79 23.42,43.16 ; 1 cut-out
GND on BOTTOM: 88.49,84.45 88.41,84.53 88.41,85.75 88.31,85.86 88.09,85.86 87.96,85.98 87.96,87.07 87.99,87.1 87.99,88.56 87.74,88.82 85.98,88.82 85.29,89.51 85.29,92.91 85.33,92.95 87.02,92.95 87.15,92.82 87.15,91.24 87.21,91.18 87.21,90.76 87.08,90.64 87.08,90.21 87.34,89.96 87.55,89.96 88.7,88.81 88.7,87.23 88.78,87.15 89.05,87.15 89.18,87.02 89.18,85.97 89.07,85.86 88.84,85.86 88.72,85.74 88.72,84.5 88.67,84.45
GND on BOTTOM: 41.45,54.21 41.36,54.3 41.36,56.39 40.47,57.28 35.41,57.28 35.26,57.43 35.26,59.73 34.94,60.05 34.55,60.05 34.49,60.11 34.49,60.92 34.58,61.01 39.05,61.01 39.17,60.9 39.17,60.15 38.45,59.43 38.45,58.67 38.85,58.28 41.29,58.28 41.36,58.34 41.36,59.79 41.4,59.83 44.7,59.83 44.8,59.74 44.8,57.97 45.24,57.54 45.24,54.76 44.68,54.21 ; 5 cut-outs
GND on BOTTOM: 73.42,19.72 73.15,19.98 73.15,22.61 72.75,23.01 72.75,24.58 73.96,25.78 76,25.78 76.52,25.26 78.15,25.26 78.21,25.32 78.21,25.63 78.25,25.68 79.34,25.68 79.38,25.64 79.38,25.36 79.48,25.25 80.87,25.25 81.3,25.67 81.3,26.61 81.4,26.72 81.77,26.72 81.87,26.61 81.87,26.35 81.62,26.09 81.62,25.14 81.46,24.99 79.41,24.99 79.34,24.92 79.34,24.61 79.26,24.53 76.7,24.53 76.28,24.11 74.76,24.11 74.56,23.91 74.56,19.89 74.38,19.72 ; 4 cut-outs
GND on BOTTOM: 45.38,47.11 45.32,47.18 45.32,47.61 45.44,47.73 46.06,47.73 46.17,47.84 46.17,48.46 46.5,48.79 50.48,48.79 50.85,48.42 50.85,47.41 50.76,47.32 49.67,47.32 49.47,47.11
GND on BOTTOM: 18.82,37.84 18.75,37.91 18.75,38.36 19.15,38.76 19.15,39.39 18.81,39.73 18.81,40.02 18.97,40.18 19.4,40.18 19.76,39.82 19.76,38.32 19.29,37.84 ; 1 cut-out
GND on BOTTOM: 77.63,46.13 76.99,46.77 76.99,46.87 77.2,47.07 78.24,47.07 78.42,46.9 78.42,46.77 77.78,46.13
GND on BOTTOM: outline of 115 points within 73.64,52.66 85.62,69.13 ; 2 cut-outs
GND on BOTTOM: 67.06,28.44 65.67,29.82 65.11,29.82 63.25,31.69 63.25,32.6 62.28,33.57 62.28,35.9 62.47,36.09 62.47,37.32 62.71,37.56 67.32,37.56 68.98,35.9 69.44,35.9 69.59,35.74 69.59,35.28 69.9,34.98 69.9,29.11 69.23,28.44 ; 1 cut-out
GND on BOTTOM: 138.27,87.38 138.02,87.63 138.02,91.86 138.35,92.19 142.75,92.19 142.81,92.19 142.9,92.1 142.9,87.54 142.74,87.38
GND on BOTTOM: 122.68,9.48 121.26,10.9 121.26,13.71 122.2,14.65 125.71,14.65 125.87,14.49 125.87,12.28 125.98,12.17 127.29,12.17 127.43,12.03 127.43,9.95 126.96,9.48 ; 1 cut-out
GND on BOTTOM: 63.91,42.37 64.59,41.69 64.59,41.18 64.26,40.84 63.5,40.84 63.25,41.1 63.25,42.24 63.37,42.37
GND on BOTTOM: 89.23,27.74 89.13,27.84 89.13,29.36 89.43,29.67 91.85,29.67 92.53,28.99 92.53,27.79 92.48,27.74
GND on BOTTOM: 41.74,81.95 41.55,82.14 41.55,83.67 42.73,84.86 42.73,85.63 43.97,86.87 43.97,88.33 44.09,88.45 46.97,88.45 47.33,88.1 47.33,85.46 47,85.13 44.93,85.13 43.55,83.75 43.55,81.98 43.51,81.95 ; 2 cut-outs
GND on BOTTOM: 59.41,58.7 59.31,58.8 59.31,59.51 59.54,59.74 59.54,64.34 59.34,64.54 58.31,64.54 57.91,64.14 50.49,64.14 50.34,64.28 50.34,65.97 50.54,66.17 51.59,66.17 51.97,66.55 51.97,67.39 52.27,67.69 57.97,67.69 60.05,65.61 60.33,65.61 61.39,64.54 61.39,61.83 60.44,60.88 60.44,59.84 60.43,59.83 60.43,59.29 59.84,58.7 ; 4 cut-outs
GND on BOTTOM: 78.65,49.38 78.24,49.79 77.7,49.79 77.54,49.95 77.54,50.25 77.62,50.33 77.9,50.33 78.06,50.49 78.06,50.75 77.9,50.9 77.72,50.9 77.51,51.11 77.51,51.42 77.42,51.52 76.63,51.52 76.56,51.59 76.56,51.82 76.62,51.88 78.99,51.88 79.05,51.82 79.05,51.62 78.66,51.23 78.66,50.34 79.03,49.97 79.03,49.46 78.95,49.38
GND on BOTTOM: 64.71,65.85 63.21,67.35 62.81,67.35 62.13,68.02 60.57,68.02 60.27,68.32 60.27,74.31 59.98,74.6 51.71,74.6 51.5,74.81 51.5,76.96 51.6,77.06 65.19,77.06 65.33,77.21 65.33,77.72 65.45,77.83 69.99,77.83 70.43,77.38 70.43,74.16 71.2,73.4 73.08,73.4 74.04,72.43 74.04,72.03 73.33,71.32 71.88,71.32 71.14,70.57 70.95,70.57 70.53,70.99 70.18,70.99 68.31,69.12 68.31,67.85 68.87,67.28 68.87,67.12 67.6,65.85 ; 15 cut-outs
GND on BOTTOM: 63.19,45.47 63.48,45.77 63.48,46.39 64.03,46.93 64.87,46.93 65.59,47.65 66.02,47.65 66.08,47.59 66.08,47.41 64.71,46.04 64.65,46.04 64.3,45.69 64.3,44.29 64.21,44.2 64.03,44.2 63.19,45.04
GND on BOTTOM: outline of 81 points within 137.91,74.89 178.39,102.49 ; 6 cut-outs
GND on BOTTOM: 19.61,74.55 19.08,75.07 19.08,76.79 19.81,77.53 19.81,77.7 20.14,78.03 21.72,78.03 21.76,77.99 21.76,75.47 20.83,74.55
GND on BOTTOM: 27.14,68.16 27.06,68.23 27.06,69.08 27,69.14 26.22,69.14 26.14,69.22 26.14,70.46 26.43,70.75 27.34,70.75 27.82,71.23 29.31,71.23 29.46,71.08 29.46,69.34 29.04,68.92 28.32,68.92 28.17,68.77 28.17,68.25 28.07,68.16
GND on BOTTOM: 62.24,44.44 61.63,45.05 60.88,45.05 60.73,45.2 60.73,45.31 60.99,45.57 61.21,45.57 61.5,45.87 61.5,46.22 60.76,46.97 60.76,47.09 60.96,47.29 61.31,47.29 62.09,46.51 62.09,45.28 62.52,44.84 62.52,44.68 62.28,44.44
GND on BOTTOM: 76.62,14.7 76.26,15.05 76.26,16.37 76.37,16.47 76.85,16.47 77.07,16.7 77.07,16.99 77.88,17.8 78.75,17.8 79.57,16.97 79.57,14.78 79.49,14.7 ; 1 cut-out
GND on BOTTOM: 53.97,83.81 53.95,83.83 53.95,85.16 54.29,85.5 54.51,85.5 54.66,85.34 54.66,85.13 54.25,84.72 54.25,83.83 54.24,83.81
GND on BOTTOM: 1.5,0.51 0.8,0.8 0.51,1.5 0.51,6.25 4.25,9.99 11.43,9.99 11.44,9.99 13.84,9.99 15.56,8.27 34.09,8.27 36.49,5.86 36.49,0.51
GND on BOTTOM: 42.99,28.74 42.8,28.92 42.8,29.82 42.62,30 42.62,30.18 42.55,30.26 41.19,30.26 41.1,30.16 41.1,29.81 41.05,29.77 39.88,29.77 39.84,29.81 39.84,30.19 39.77,30.26 37.97,30.26 37.61,29.91 37.39,29.91 37.27,30.02 37.27,30.3 37.48,30.51 39.77,30.51 39.84,30.59 39.84,30.92 39.94,31.02 43.28,31.02 43.67,30.63 45.15,30.63 45.21,30.57 45.21,29.33 45.09,29.21 43.84,29.21 43.36,28.74
GND on BOTTOM: 132.78,94.58 132.74,94.62 132.74,96.02 133.17,96.45 134.37,96.45 134.44,96.37 134.44,95.35 133.67,94.58 ; 2 cut-outs
GND on BOTTOM: 73.54,17.48 73.21,17.8 73.21,19.31 73.31,19.41 74.95,19.41 75.47,18.89 75.47,17.61 75.34,17.48 ; 2 cut-outs
GND on BOTTOM: 98.4,41.76 97.36,42.8 97.36,43.23 96.69,43.91 96.36,43.91 95.9,43.45 95.58,43.45 94.37,44.67 94.37,46.65 94.98,47.26 94.98,48.68 94.04,49.62 94.04,49.99 94.18,50.13 94.83,50.13 95.63,49.32 95.63,49.32 96.31,48.64 96.31,48.56 95.94,48.19 95.94,47.55 96.34,47.14 96.34,46.46 96.91,45.89 98.12,47.09 101.22,47.09 101.4,46.92 101.4,42.37 100.79,41.76 ; 5 cut-outs
GND on BOTTOM: 34.89,43.07 34.84,43.11 34.84,44.47 34.74,44.57 33.95,44.57 33.82,44.71 30.22,44.71 30.14,44.79 30.14,46.21 30.5,46.56 33.33,46.56 33.93,45.96 35.25,45.96 35.93,45.28 35.93,43.44 36,43.37 36.73,43.37 36.76,43.33 36.76,43.11 36.72,43.07 ; 4 cut-outs
GND on BOTTOM: 23.82,23.24 23.5,23.57 23.5,24.97 23.9,25.38 29.44,25.38 29.61,25.2 29.61,23.36 29.49,23.24
GND on BOTTOM: 151.57,55.45 151.33,55.68 151.33,60.87 149.84,62.37 149.27,62.37 145.73,65.91 145.73,69.58 148.1,71.96 152.34,71.96 152.49,71.81 152.49,70.51 150.24,70.51 147.23,67.5 150.24,64.49 152.49,64.49 152.49,62.81 152.41,62.72 152.41,55.63 152.23,55.45
GND on BOTTOM: 42.04,51.02 41.86,51.21 41.86,53.49 42.02,53.65 43.88,53.65 44.32,53.21 44.32,51.11 44.23,51.02 ; 1 cut-out
GND on BOTTOM: 155.69,73.94 155.56,74.06 155.56,74.65 155.67,74.76 158.89,74.76 159.15,74.51 159.15,74.1 158.98,73.94 156.34,73.94
GND on BOTTOM: 74.42,60.16 74.31,60.28 74.31,61.05 72.18,63.18 71.27,63.18 71.06,62.97 71.06,62.6 70.97,62.51 70.76,62.51 70.51,62.77 70.51,62.97 71.26,63.72 71.26,63.99 70.39,64.85 70.39,66.07 71.1,66.78 71.84,66.78 74.37,64.25 74.38,64.25 75.37,63.26 75.37,62.6 75.13,62.36 75.13,62.13 75.89,61.37 75.89,60.88 75.17,60.16
GND on BOTTOM: 94.61,56.47 94.23,56.85 94.23,57.1 95.89,58.75 96.14,58.75 96.58,58.31 96.58,58.18 94.87,56.47 ; 1 cut-out
GND on BOTTOM: 43.03,39.14 42.94,39.23 42.94,39.97 42.33,40.58 42.33,41.05 42.48,41.2 42.81,41.2 43.2,41.59 43.2,43.85 43.53,44.18 44.21,44.18 44.83,44.8 45.82,44.8 45.86,44.76 45.86,43.11 45.59,43.11 45.49,43.01 45.49,40.73 45.11,40.35 45.11,40.01 44.25,39.14 ; 5 cut-outs
GND on BOTTOM: 17.5,29.09 17.35,29.23 17.35,30.94 17.64,31.22 19.54,31.22 19.81,30.95 19.81,29.22 19.67,29.09 ; 2 cut-outs
GND on BOTTOM: outline of 261 points within 62.77,38.54 88.45,61.85 ; 2 cut-outs
GND on BOTTOM: 63.07,79.58 62.46,80.19 62.31,80.19 61.55,80.95 61.55,82.09 61.38,82.25 61.38,84.68 61.41,84.71 61.76,84.71 61.81,84.66 61.81,83.69 61.85,83.64 62.35,83.64 62.4,83.69 62.4,84.63 62.48,84.72 63.26,84.72 63.32,84.66 63.32,83.74 63.05,83.48 63.05,81.17 63.25,80.98 63.25,80.88 63.78,80.34 64.07,80.34 64.67,80.94 66.27,80.94 66.36,80.85 66.36,80.42 66.28,80.35 64.83,80.35 64.47,79.99 64.47,79.68 64.36,79.58 ; 4 cut-outs
GND on BOTTOM: 96.29,63.12 96.11,63.3 96.11,64.29 96.65,64.82 97.36,64.82 97.49,64.95 97.49,67.41 97.31,67.59 96.04,67.59 95.83,67.79 95.83,68.45 95.91,68.53 97.33,68.53 98.09,69.29 98.09,70.18 98.02,70.26 97.71,70.26 97.55,70.42 97.55,71.57 96.52,72.59 96.52,73.56 97.61,74.65 98.3,74.65 98.93,74.02 98.93,64.39 97.66,63.12 ; 4 cut-outs
GND on BOTTOM: 22.05,56.95 21.85,57.14 21.85,59.53 21.64,59.74 20.32,59.74 20.12,59.95 19.53,59.95 19.38,59.8 12.93,59.8 12.93,59.8 12.93,60.2 13.16,60.43 13.16,61.31 13.09,61.38 12.43,61.38 12.43,61.85 12.11,62.17 11.15,62.17 11.14,62.16 2.97,62.16 2.53,62.6 2.53,64 2.22,64.31 0.94,64.31 0.94,68.48 0.95,68.49 7.98,68.49 8.47,68.98 8.47,70.28 8.21,70.54 8.21,71.38 11.2,71.38 11.68,70.89 11.68,70.89 12.17,70.4 12.17,68.22 12.03,68.08 10.19,68.08 8.41,66.29 8.41,65.49 9.25,64.65 10.02,64.65 11.47,63.19 13.75,63.19 14.47,62.48 16.74,62.48 18.08,61.14 22.04,61.14 22.23,60.95 22.23,59.08 22.35,58.96 22.91,58.96 23.01,58.85 23.01,57.05 22.91,56.95 ; 5 cut-outs
GND on BOTTOM: 39.26,23.17 38.96,23.47 38.96,25.32 39.22,25.59 41.02,25.59 41.18,25.42 41.18,23.9 41.27,23.81 41.27,23.25 41.19,23.17 ; 1 cut-out
GND on BOTTOM: 92.15,68.15 92.03,68.27 92.03,72.37 92.62,72.95 93.95,72.95 94.56,73.56 94.56,75.03 95.4,75.87 95.91,75.87 96.04,75.74 96.04,74.86 95.55,74.37 95.55,72.14 96.52,71.17 96.52,70.54 96.49,70.51 95.73,70.51 95.31,70.09 93.15,70.09 92.89,69.83 92.89,68.25 92.79,68.15 ; 1 cut-out
GND on L2GND: outline of 126 points within 0.51,0.51 178.39,102.49 ; 2 cut-outs
GND on L3: 1.5,0.51 0.8,0.8 0.51,1.5 0.51,10.04 2.63,10.04 3.01,10.42 3.01,16.06 0.51,16.06 0.51,18.34 14.8,18.34 15.51,18.63 15.81,19.34 15.81,21.58 15.51,22.29 14.8,22.58 14.46,22.58 14.46,26.27 14.79,26.27 16.34,24.72 16.34,13.3 24.87,4.77 36.42,4.77 39.68,1.51 58.3,1.51 60.27,3.48 65.07,3.48 67.78,6.19 71.21,6.19 72.76,4.64 72.76,4.48 72.49,4.02 72.39,3.5 72.39,1.5 72.1,0.8 71.4,0.51
GND on L3: 130.71,3.72 130.71,1.08 131.15,0.64 145.8,0.64 146.35,1.19 146.35,8.93 146.27,9.01 144.74,9.01 143.49,7.76 140.69,7.76 136.48,3.55 131.19,3.55 131,3.74 130.73,3.74
GND on L3: 43.96,21.03 43.96,20.44 44.14,20.26 44.58,20.26 45.01,19.82 48.57,19.82 50.02,21.28 50.02,25.5 49.76,25.76 48.06,25.76 47.88,25.58 47.88,22.97 46.54,21.64 45.23,21.64 44.64,21.05 43.97,21.05
GND on L3: 35.86,87.49 37.05,88.41 37.51,89.85 37.51,95.5 37.8,96.2 38.5,96.49 70.5,96.49 71.21,96.79 71.51,97.5 71.51,101.5 71.8,102.2 72.5,102.49 80.36,102.49 80.64,102.21 80.67,102.21 80.67,101.25 79.81,100.38 75.84,100.38 69.2,93.74 61.13,93.74 60.25,92.86 60.25,91.19 60.15,91.09 56.85,91.09 55.45,89.69 49.26,89.69 48.88,89.31 47.73,89.31 46.94,90.1 40.46,90.1 39.67,89.31 39.53,89.31 37.38,87.16 37.38,87.12 35.86,87.12
GND on L3: outline of 93 points within 0.51,31.5 22.86,87.34 ; 1 cut-out
GND on L4: 11.9,62.33 11.41,62.33 10.98,62.1 2.99,62.1 2.56,62.53 2.56,64.05 2.25,64.36 0.71,64.36 0.71,68.64 7.43,68.64 8.56,68.18 9.31,69.15 9.31,70.91 12.35,70.91 12.37,70.93 12.6,70.93 15.98,67.55 15.98,66.88 14.73,65.63 14.73,60.36 14.3,59.93 13.04,59.93 13.04,62.03 12.71,62.37 11.94,62.37
GND on L4: 133.63,96.22 133.63,94.42 135.09,92.96 136.02,92.96 136.38,92.6 142.25,92.6 142.62,92.23 142.62,87.81 142.39,87.58 138.63,87.58 138.44,87.78 138.44,88.96 138.16,89.24 136.41,89.24 136.04,88.86 131.81,88.86 131.52,89.16 131.52,90.15 130.44,91.23 130.43,91.23 130.19,91.47 130.18,91.47 129.65,92 125.89,92 124.35,90.46 108.99,90.46 107.63,89.1 102.11,89.1 100.47,90.74 100.47,92.06 101.79,93.37 101.79,93.37 101.79,94.07 101.7,94.17 98.48,94.17 95.68,96.96 95.68,99.79 96.3,100.41 100.91,100.41 101.64,99.68 129.31,99.68 129.32,99.67 130.18,99.67
GND on L4: 15.74,42.6 15.74,38.12 15.17,37.55 14.53,37.55 10.47,41.61 10.47,42.65 10.92,43.11 15.24,43.11
GND on L4: 1.5,0.51 0.8,0.8 0.51,1.5 0.51,10.04 2.6,10.04 3.01,10.45 3.01,15.82 2.77,16.06 0.51,16.06 0.51,18.34 14.8,18.34 15.28,18.46 15.64,18.79 15.92,18.51 15.92,10.42 21.19,5.14 40.34,5.14 40.84,4.64 40.84,3.71 41.34,3.22 45.05,3.22 45.45,2.81 45.45,2 45.04,1.59 37.65,1.59 37.04,2.2 36.6,2.2 36.49,2.08 36.49,1.02 36.24,0.77 36.24,0.51
GND on L4: 169.5,73.61 169.15,73.75 169.01,74.1 169.01,74.6 168.71,75.31 168,75.61 161.35,75.61 161.35,76.05 162.11,76.81 170.49,76.81 173.38,79.7 173.38,94.58 166.41,101.56 156.03,101.56 155.46,100.98 139.05,100.98 137.69,99.62 136.1,99.62 133.23,102.49 170.89,102.49 170.89,100.9 173.9,97.89 176.91,100.9 176.91,102.49 177.9,102.49 178.25,102.35 178.39,102 178.39,74.6 178.1,73.9 177.4,73.61
GND on L4: 154.68,97.99 164.92,97.99 170.31,92.59 170.31,83.76 169.85,83.3 169.27,83.3 169.13,83.43 169.13,86.66 168.88,86.92 168.4,86.92 168.1,86.62 164.22,86.62 163.84,86.24 152.24,86.24 150.1,84.09 149.68,84.09 149.39,84.38 149.39,84.5 151.86,86.98 151.86,90.44 152.34,90.91 152.34,91.96 152.4,92.03 153.92,92.03 154.41,92.51 154.41,97.72
GND on L4: 62.36,55.3 62.36,53.95 62.18,53.77 62.18,52.78 63.27,51.69 63.37,51.69 63.37,51.64 64.9,50.12 64.9,46.81 64.52,46.43 63.75,46.43 63.63,46.31 63.63,46.05 63.75,45.92 65.28,45.92 65.41,46.05 65.41,46.69 70.1,51.39 71.75,51.39 71.75,51.89 67.82,51.89 67.56,52.15 65.15,52.15 65.02,52.27 65.02,52.99 65.2,53.16 66.6,53.16 67.64,54.21 67.64,54.97 65.68,56.92 65.68,57.94 65.05,58.57 65.05,61.47 63.7,62.82 63.7,64.29 62.71,65.28 62.18,65.28 61.39,64.49 61.39,61.67 63.73,59.34 63.73,56.67
GND on L4: 62.21,88.49 68.71,88.49 69.32,87.89 69.32,84.36 68.71,83.74 67.91,83.74 66.51,82.35 61.85,82.35 61.02,83.18 60.24,83.18 59.78,83.64 59.78,86.07
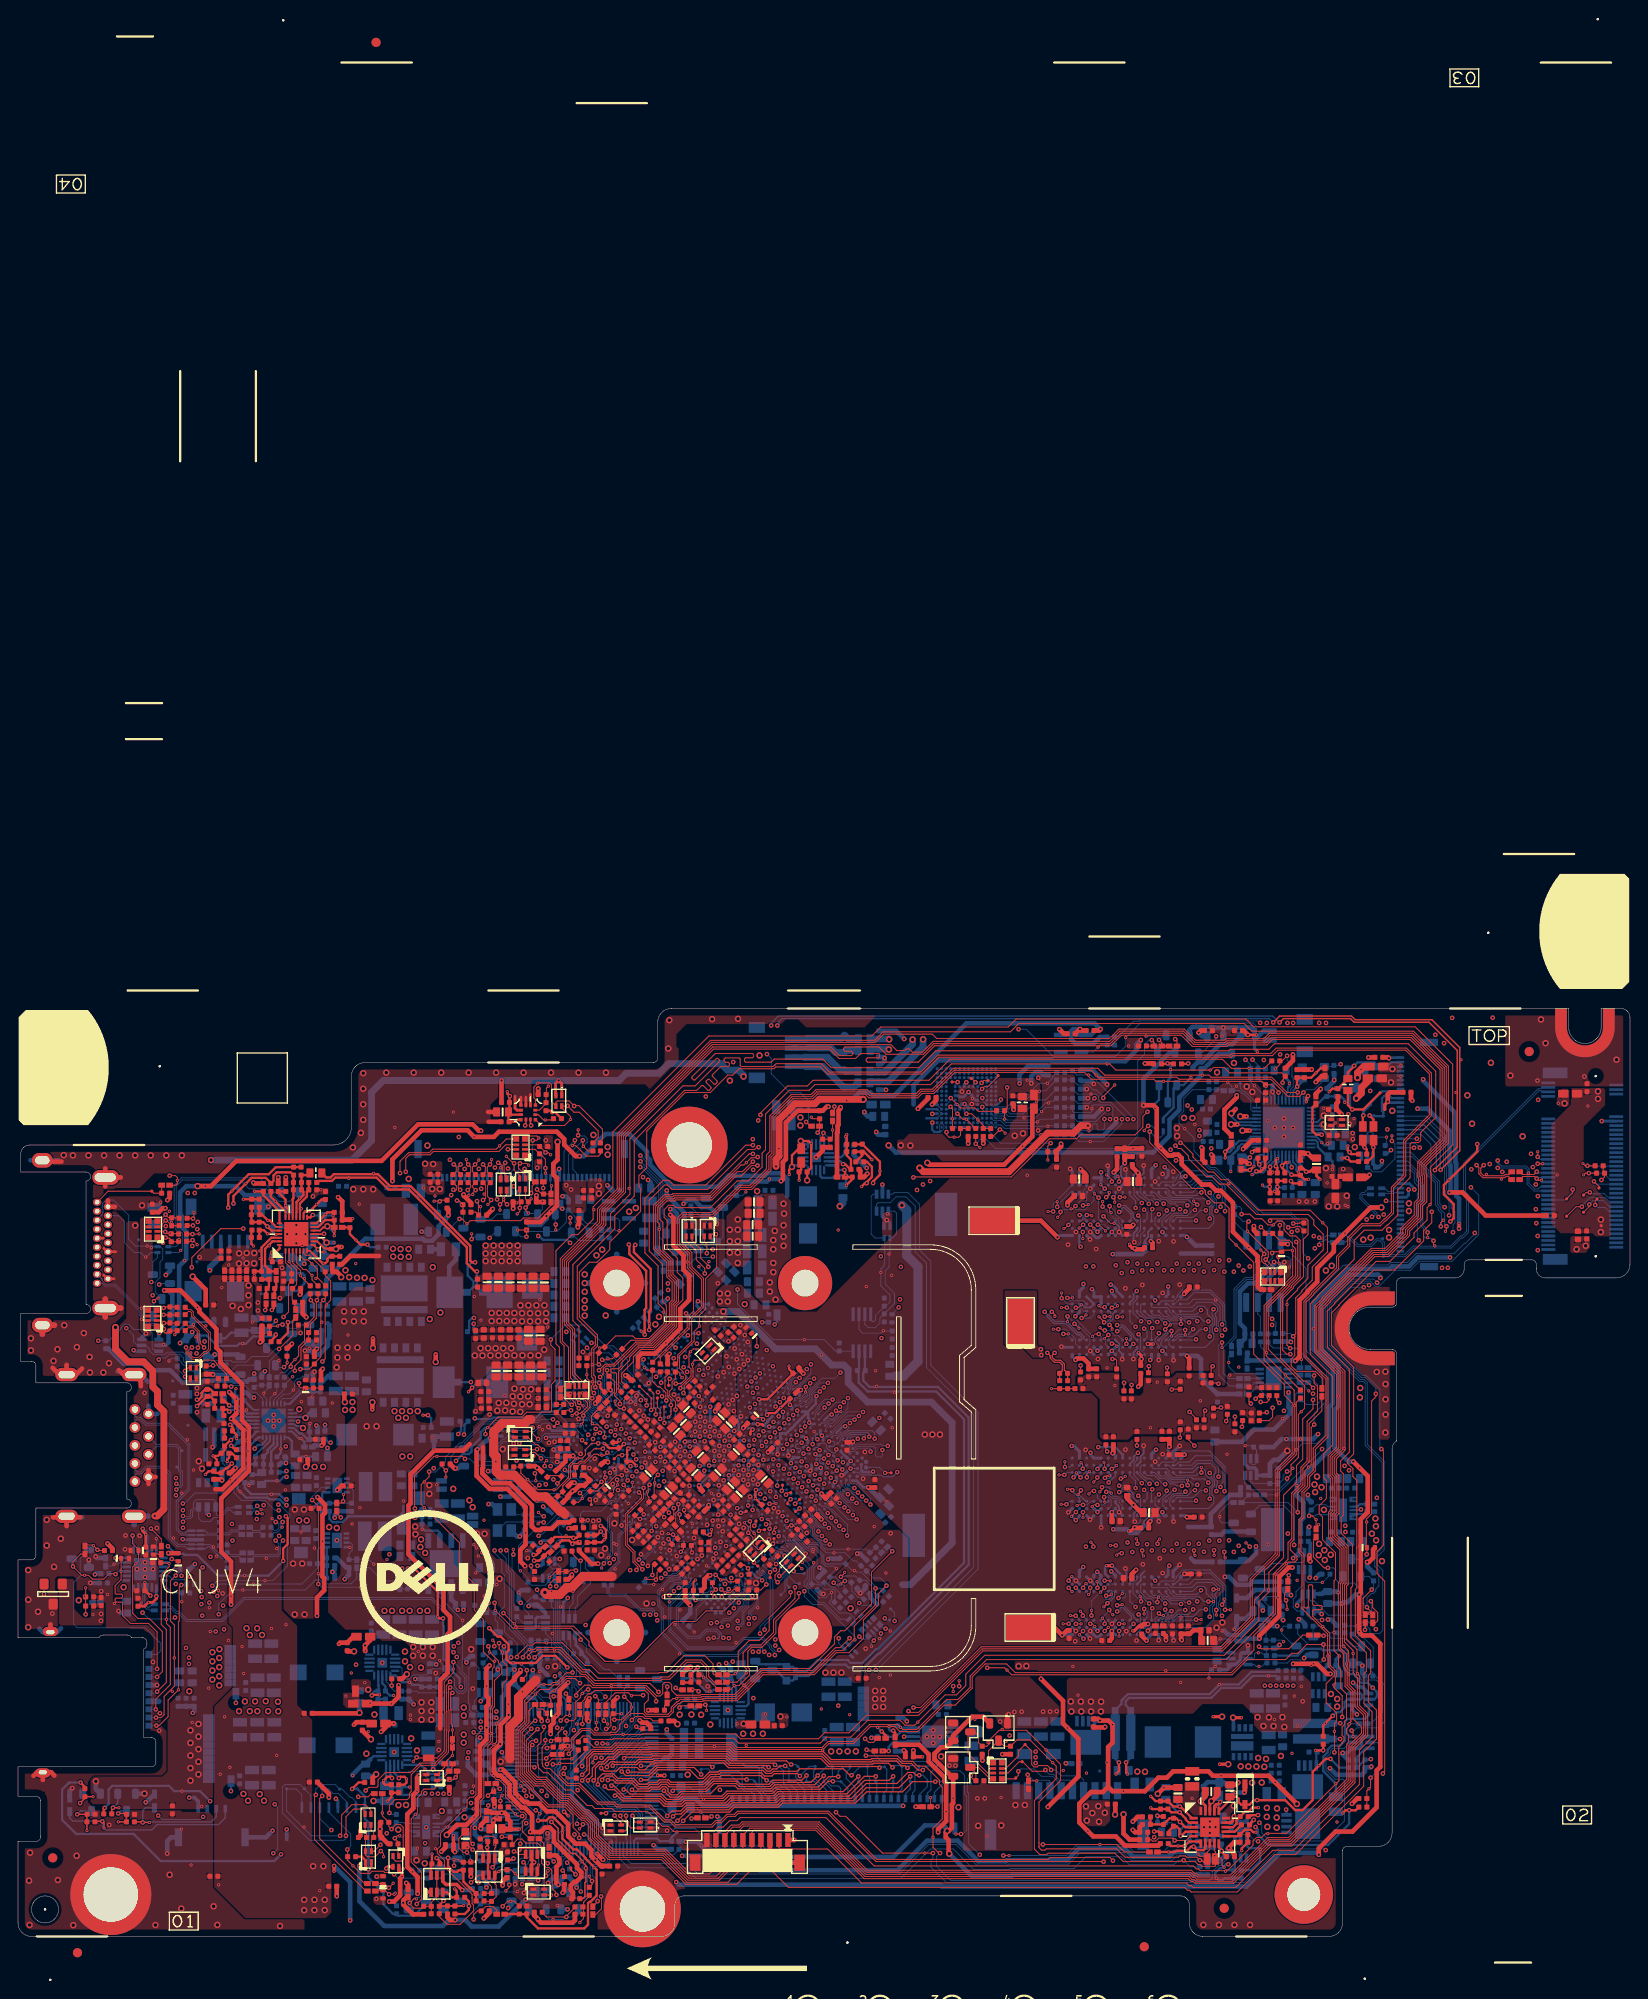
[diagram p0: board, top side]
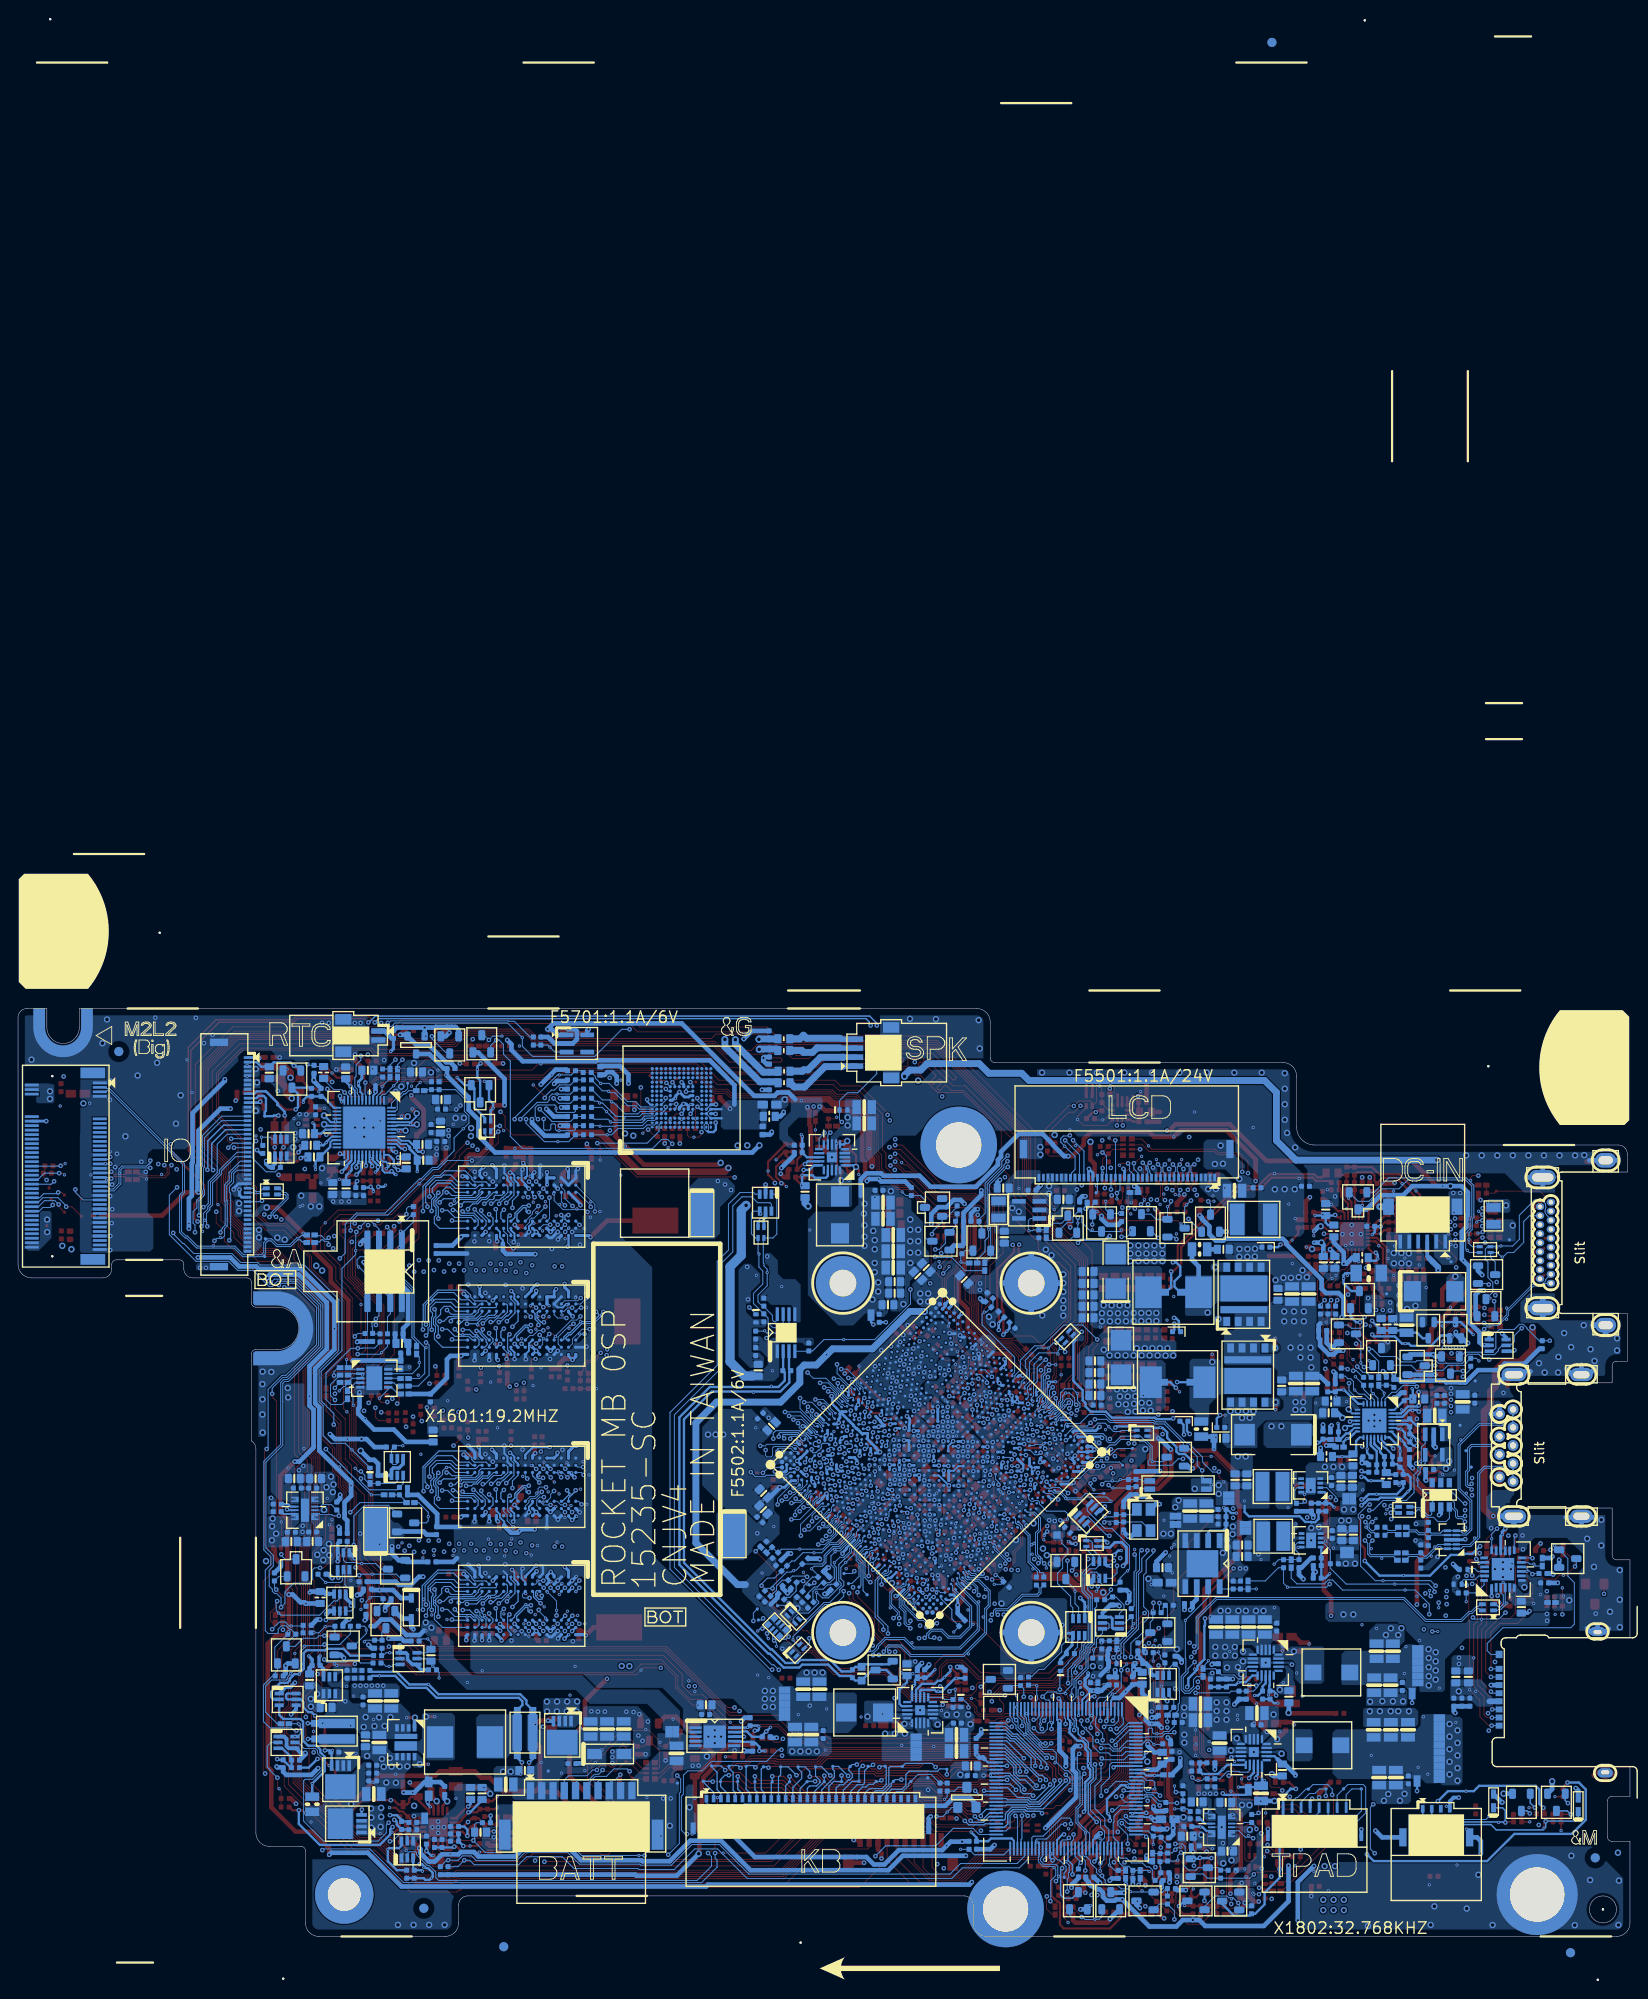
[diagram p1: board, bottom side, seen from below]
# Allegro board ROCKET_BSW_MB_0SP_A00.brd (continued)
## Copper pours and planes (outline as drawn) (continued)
GND on L4: 36.99,87.1 36.35,87.74 37.2,88.64 37.51,89.85 37.51,95.5 37.8,96.2 38.5,96.49 70.5,96.49 71.21,96.79 71.51,97.5 71.51,101.5 71.8,102.2 72.5,102.49 90.54,102.49 89.83,101.78 83.19,101.78 82.45,101.04 77.77,101.04 68.46,91.73 61.47,91.73 59.45,89.71 53.8,89.71 51.78,91.73 43.23,91.73 38.6,87.1
GND on L4: 43.57,91.18 51.62,91.18 53.57,89.23 59.88,89.23 60.22,88.89 60.22,88.03 58.21,86.02 58.21,85.1 58,84.89 57,84.89 55.77,83.66 55.77,80.55 55.34,80.13 54.2,80.13 52.8,81.52 52.8,82.41 54.98,84.59 54.98,87.29 54.49,87.78 54.03,87.78 53.87,87.62 53.87,86.09 54.58,85.38 54.58,84.7 52.39,82.51 49.37,82.51 46.86,85.02 45.25,85.02 43.63,86.63 43.63,88.48 43.76,88.61 47.99,88.61 48.29,88.31 48.97,88.31 49.35,88.69 49.35,89.08 48.75,89.67 44.06,89.67 43.4,90.33 43.4,91.01
GND on L4: 11.46,81.75 9.31,83.9 9.31,84.85 8.56,85.82 7.43,85.36 0.71,85.36 0.71,86.85 0.85,87.2 1.2,87.34 23.34,87.34 23.34,87.13 21.32,85.11 18.76,85.11 16.98,83.34 16.98,80.6 16.36,79.98 14.8,79.98 14.3,79.48 11.63,79.48 11.61,79.48 11.46,79.63
GND on L4: 52.05,51.97 51.52,51.44 46.54,51.44 46.22,51.12 46.22,49.29 46.52,48.99 51.4,48.99 51.89,48.49 51.89,47.9 52.14,47.65 52.14,43.92 52.25,43.81 55.66,43.81 55.92,44.07 55.92,44.57 55.68,44.81 55.68,48.49 55.27,48.9 55.27,51.84 55.14,51.97
GND on L4: 0.51,33.66 0.51,41.29 2.23,41.29 2.56,41.62 2.56,46.94 2.76,47.14 9.99,47.14 9.99,46.61 6.65,43.27 6.65,40.04 5.33,38.72 5.33,36.83 5.82,36.34 6.84,36.34 6.84,36.43 9.27,38.85 10.88,38.85 12.43,37.3 12.43,35.17 13.28,34.32 13.28,33.66 12.87,33.66 12.54,33.89 12.15,33.96 9.45,33.96 9.06,33.89 8.73,33.66
GND on L5VCC: outline of 178 points within 0.51,0.51 178.39,102.49 ; 3 cut-outs
0D675V_PWR on BOTTOM: 103.36,20.69 103.03,21.02 103.03,21.3 103.07,21.33 104.47,21.33 104.54,21.4 104.54,21.96 104.47,22.04 103.07,22.04 103.03,22.07 103.03,22.3 103.08,22.35 104.78,22.35 105.01,22.58 107.84,22.58 107.95,22.47 107.95,20.8 107.84,20.69
0D675V_VREF_S0 on TOP: outline of 92 points within 117.54,32.38 140.11,62.56 ; 48 cut-outs
0D675V_VREF_S0 on BOTTOM: 105.52,22.88 105.44,22.96 105.44,25.02 107.81,27.4 109.35,27.4 109.36,27.41 114.7,27.41 116.26,28.97 128.46,28.97 130.54,31.05 130.54,32.69 132.9,35.06 133.7,35.06 134.17,34.59 134.17,34.07 132.2,32.11 132.2,30.46 129.11,27.37 116.99,27.37 115.44,25.81 109.07,25.81 107.35,24.09 107.35,22.95 107.27,22.88
1D05V_PWR_PH on BOTTOM: 86.5,80.97 86.35,81.12 86.35,84.15 87.92,85.72 88.24,85.72 88.25,85.7 88.25,84.32 88.67,83.9 90.11,83.9 90.27,83.75 90.27,81.3 89.93,80.97
1D5V_S0 on TOP: 69.65,60.96 68.41,62.2 68.41,63.42 68.53,63.54 69.1,63.54 69.14,63.51 69.14,62.79 69.52,62.41 69.52,62.41 70.38,61.55 70.38,61.19 70.15,60.96 ; 2 cut-outs
1D05V_S5 on TOP: 82.58,70.31 81.69,71.2 81.69,82.32 81.81,82.45 84.95,82.45 85.8,81.61 85.8,74.83 85.04,74.07 85.04,70.66 84.68,70.31 ; 7 cut-outs
1D05V_S5 on TOP: 74.35,51.53 73.94,51.95 73.94,52.32 71.94,54.32 71.78,54.32 71.19,54.92 71.19,55.14 71.46,55.41 71.46,55.81 70.9,56.36 70.9,56.54 71.17,56.81 71.41,56.81 75.38,52.84 75.38,52.4 74.52,51.53 ; 6 cut-outs
1D05V_S5 on TOP: 75.39,47.32 74.49,48.22 74.49,48.39 74.02,48.86 73.16,48.86 72.77,49.26 72.2,49.26 71.72,49.74 71.72,49.99 72.09,50.36 72.09,50.71 71.92,50.89 71.92,51.81 71.68,52.05 71.4,52.05 71.07,51.72 70.99,51.72 70.54,51.26 70.26,51.26 69.57,51.94 69.57,52.2 69.33,52.44 69.07,52.44 68.97,52.54 68.97,53.28 65.35,56.89 65.02,56.89 64.9,56.77 64.82,56.77 64.49,57.1 64.49,57.17 64.83,57.52 65.01,57.52 65.12,57.41 65.68,57.41 65.89,57.62 65.89,58.09 66.37,58.57 66.66,58.57 66.91,58.32 67.19,58.32 70.25,55.26 70.25,53.84 70.78,53.31 71.57,53.31 73.12,51.76 73.12,51.23 74.07,50.28 74.61,50.28 74.74,50.15 74.74,49.89 75.73,48.91 76.02,48.91 76.93,49.82 77.43,49.82 78.08,49.17 78.08,49.17 78.63,48.63 78.63,48.37 77.72,47.47 77.64,47.47 77.13,47.98 76.31,47.98 75.65,47.32 ; 18 cut-outs
1D05V_S5 on TOP: 31.68,63.23 31.58,63.33 31.58,63.72 31.58,63.72 31.58,65.26 31.95,65.63 32.47,65.63 32.81,65.97 32.81,67.26 32.85,67.3 32.95,67.3 32.97,67.29 33.28,67.29 33.36,67.21 33.36,65.77 33.29,65.7 33.31,65.7 32.77,65.16 32.77,65.17 32.31,64.71 32.31,63.34 32.2,63.23
1D05V_S5 on TOP: 30.96,66.73 30.86,66.83 30.86,68.03 30.95,68.12 31.28,68.12 31.37,68.03 31.37,67.39 31.59,67.18 31.59,66.84 31.48,66.73
1D05V_S5 on BOTTOM: 71.28,52.46 71.13,52.61 71.13,53.88 71.2,53.96 71.41,53.96 71.53,53.83 71.53,53.7 71.74,53.5 71.86,53.5 72.09,53.27 72.09,52.64 71.91,52.46
1D05V_S5 on BOTTOM: 72.4,50.66 72.09,50.96 72.09,51.7 72.73,52.33 72.98,52.33 73.04,52.27 73.04,52.07 73.29,51.82 73.49,51.82 73.64,51.67 73.64,51.49 72.8,50.66
1D05V_S5 on BOTTOM: 74.52,52.07 72.04,54.54 72.04,54.97 72.83,55.76 73.34,55.76 75.55,53.55 76.18,53.55 76.89,52.84 76.89,52.74 76.79,52.64 76.16,52.64 75.58,52.07
1D05V_S5 on BOTTOM: 81.5,53.25 80.9,53.85 80.9,54.58 81.04,54.72 81.77,54.72 81.92,54.57 81.92,53.42 81.75,53.25
1D05V_S5 on BOTTOM: 33.44,67.82 32.77,68.49 32.48,68.49 32.33,68.64 32.33,69.25 32.49,69.4 34.54,69.4 34.63,69.32 34.63,68.14 34.31,67.82 ; 2 cut-outs
1D05V_S5 on BOTTOM: 73.92,49.82 73.74,50 73.74,50.68 73.89,50.83 74.49,50.83 74.68,50.65 74.68,50.4 74.87,50.2 75.11,50.2 75.22,50.1 75.22,49.97 75.06,49.82
1D05V_S5 on BOTTOM: 86.2,67.81 84.86,69.15 83.74,69.15 83.7,69.11 83.7,68.94 83.51,68.76 82.81,68.76 82.34,69.24 82.34,70.49 81.87,70.97 81.87,78.41 82.1,78.65 82.84,78.65 83.08,78.89 83.08,82.14 83.44,82.5 83.44,83.01 83.57,83.14 84.98,83.14 85.64,82.48 85.64,81.24 86.4,80.47 86.55,80.47 86.55,80.47 90.37,80.47 91.24,79.59 91.24,71.21 87.85,67.81 ; 8 cut-outs
1D05V_S5 on BOTTOM: 77.25,56.94 77.19,57.01 77.19,58.47 77.24,58.52 77.52,58.52 77.64,58.4 77.64,58.06 77.8,57.9 78.54,57.9 78.6,57.83 78.6,57.67 77.88,56.94
1D05V_S5 on BOTTOM: 76.61,48.25 76.4,48.45 76.4,49.2 76.26,49.35 76.08,49.35 75.97,49.47 75.97,50.18 76.03,50.25 76.75,50.25 77.3,50.8 77.86,50.8 77.96,50.7 77.96,50.53 77.87,50.44 77.58,50.44 77.43,50.29 77.43,49.88 77.58,49.73 78.23,49.73 78.97,48.98 78.97,48.42 78.81,48.25
1D05V_S5 on L4: 65.39,75.23 67.51,75.23 67.53,75.25 69.32,75.25 77.66,83.59 85.17,83.59 85.63,83.13 85.63,69 82.37,65.74 82.37,63.96 82.68,63.65 82.68,60.35 82.7,60.33 82.7,58.6 81.48,57.37 81.48,55.98 82.16,55.29 82.16,53.99 81.84,53.66 80.95,53.66 79.81,54.8 77.67,54.8 75,52.13 73.88,52.13 73.02,51.28 72.54,51.28 71.72,52.1 68.51,52.1 68.14,52.47 67.67,52.47 67.53,52.33 65.34,52.33 65.16,52.5 65.16,52.81 65.38,53.03 66.97,53.03 67.94,54 67.94,55.02 65.79,57.18 65.79,57.99 65.38,58.4 65.38,61.47 63.93,62.92 63.93,73.76
1D8V_S0 on BOTTOM: 46.11,9.55 46.01,9.65 46.01,11.42 46.01,11.42 47.15,11.42 47.44,11.72 48.8,11.72 48.88,11.63 48.88,10.88 48.33,10.33 48.33,9.67 48.22,9.55 ; 3 cut-outs
1D8V_S5 on TOP: 43.99,8.11 43.8,8.3 43.8,12.93 44.55,13.68 44.55,15.47 44.91,15.83 47.65,15.83 48.57,16.75 48.57,18.83 48.63,18.89 48.63,21.24 48.24,21.62 48.24,28.87 48.66,29.28 48.66,33.26 48.22,33.7 48.22,35.29 47.65,35.86 47.65,39.15 43.73,43.06 43.73,45.78 43.93,45.98 45.05,45.98 48.34,42.69 48.34,41.42 50.43,39.32 50.43,36.17 50.97,35.63 50.97,16.51 49.72,15.26 49.72,14.42 46.9,11.6 46.9,10.36 45.82,9.28 45.82,8.97 44.95,8.11
1D8V_S5 on TOP: 53.76,51.84 53.73,51.87 53.73,53.31 53.36,53.68 53.36,55.71 53.91,56.25 54.05,56.25 54.05,56.26 55.44,56.26 55.51,56.19 55.51,55.91 55.49,55.89 54.79,55.89 54.74,55.85 54.74,55.66 54.8,55.6 55.46,55.6 55.5,55.57 55.5,53.92 55.44,53.87 54.45,53.87 54.41,53.83 54.41,53.6 54.44,53.57 55.42,53.57 55.44,53.56 55.44,53.22 55.42,53.2 55.08,53.2 55.08,53.2 54.84,53.2 54.43,52.79 54.43,51.93 54.33,51.84
1D8V_S5 on TOP: 69.42,43.33 70.41,44.32 70.41,44.43 69.49,45.34 69.39,45.34 68.43,44.38 68.02,44.38 67.84,44.2 67.84,43.82 68.33,43.33
1D8V_S5 on TOP: 118.62,89.53 118.15,89.99 118.15,94.46 118.55,94.87 121.01,94.87 121.13,94.74 121.13,94.29 120.02,93.17 120.02,92.97 120.29,92.69 125.05,92.69 125.35,92.39 125.35,89.92 124.96,89.53
1D8V_S5 on TOP: 55.34,34.69 52.78,37.24 52.78,40 52.94,40.16 53.59,40.16 53.97,39.78 53.97,39.39 55.01,38.36 55.01,37.05 55.86,36.19 62.06,36.19 63.78,37.91 70.83,37.91 72.15,36.58 75,36.58 75.75,37.34 78.42,37.34 79.29,38.2 80.37,38.2 80.58,38.41 80.58,39.47 80.83,39.72 81.35,39.72 81.64,40 81.64,40.22 83,41.59 83,41.59 85.14,43.73 87.02,43.73 87.51,44.22 88.19,44.22 88.86,43.55 88.86,42.59 87.86,41.59 86.45,41.59 85.37,42.67 84.99,42.67 83.08,40.76 83.08,40.54 82.25,39.7 82.25,38.99 82.08,38.82 81.82,38.82 80.58,37.59 79.65,37.59 78.36,36.3 76.34,36.3 75.18,35.15 70.13,35.15 68.86,36.42 64.65,36.42 62.92,34.69 ; 4 cut-outs
1D8V_S5 on TOP: 76.11,57.94 75.35,58.71 75.05,58.71 74.73,59.02 74.73,59.35 75.57,60.18 75.57,60.71 74.69,61.59 74.69,61.86 75.09,62.26 75.09,63.23 75.59,63.73 76.3,63.73 76.94,64.37 76.94,64.7 75.9,65.74 75.9,68.91 76.47,69.47 76.47,72.94 77.73,74.2 77.73,78.2 77.48,78.45 73.98,78.45 73.82,78.61 73.82,79.5 73.97,79.65 78.29,79.65 78.49,79.46 78.49,72.83 77.41,71.76 77.41,69.93 77.58,69.76 78.51,69.76 78.73,69.54 78.73,68.57 78.57,68.41 77.38,68.41 76.74,67.76 76.74,67.27 78.53,65.48 78.53,65.16 78.13,64.76 78.13,63.3 77.28,62.45 77.28,61.68 76.57,60.97 76.57,60.67 76.95,60.29 76.95,59.99 76.67,59.71 76.67,58.1 76.51,57.94 ; 5 cut-outs
1D8V_S5 on BOTTOM: 93.69,33.53 93.14,34.08 93.14,34.48 92.02,35.6 91.69,35.6 91.18,36.11 91.18,36.11 90.95,36.33 90.95,36.62 92.32,37.99 92.54,37.99 92.85,37.68 92.85,37.03 93.29,36.6 93.42,36.6 93.43,36.6 93.8,36.6 94.14,36.26 94.65,36.26 96.69,38.3 96.69,39.21 95.9,39.99 95.52,39.99 94.43,41.09 94.43,41.25 94.74,41.57 94.74,42.01 95.04,42.32 95.28,42.32 98.54,39.06 98.54,38.21 93.86,33.53 ; 8 cut-outs
1D8V_S5 on BOTTOM: 69.1,36.56 67.59,38.07 66.83,38.07 66.31,38.6 66.31,40.73 67.03,41.45 67.03,44.16 67.26,44.39 68.23,44.39 69.11,43.52 69.11,42.82 68.56,42.27 68.56,39.71 70.13,38.13 70.13,36.79 69.9,36.56 ; 2 cut-outs
1D8V_S5 on BOTTOM: 76.19,57.54 76.11,57.62 76.11,57.86 75.89,58.08 75.61,58.08 75.55,58.14 75.55,58.33 75.44,58.43 75.44,58.92 75.57,59.05 75.86,59.05 76.04,58.87 76.04,58.65 76.51,58.19 76.51,57.67 76.38,57.54
1D8V_S5 on BOTTOM: 51.45,30.91 51.34,31.02 51.34,31.55 51.27,31.62 49.86,31.62 49.5,31.98 49.5,34.85 49.83,35.18 49.83,37.72 50.64,38.53 51.77,38.53 51.94,38.7 51.94,39.64 52.39,40.1 53.52,40.1 53.7,39.92 53.7,38.32 52.8,37.42 51.51,37.42 51.04,36.94 51.04,35.44 50.63,35.03 50.63,34.1 51.35,33.38 51.7,33.38 51.96,33.13 51.96,31.01 51.85,30.91 ; 4 cut-outs
1D8V_S5 on BOTTOM: 52.94,24.7 52.52,25.12 51.27,25.12 51.2,25.19 51.2,25.66 51.28,25.74 51.88,25.74 52.08,25.95 52.08,27.69 52.01,27.76 50.84,27.76 50.74,27.65 50.74,27.31 50.6,27.17 50.24,27.17 50.18,27.24 50.18,28.21 50.3,28.32 52.93,28.32 53.23,28.02 53.23,27.2 53.32,27.12 53.32,24.77 53.24,24.7 ; 1 cut-out
1D8V_S5 on BOTTOM: 43.63,8.07 43.32,8.38 43.32,11.17 43.58,11.43 44.63,11.43 44.66,11.4 44.66,8.34 44.38,8.07 ; 4 cut-outs
1D8V_S5 on BOTTOM: 43.07,44.41 42.94,44.54 42.94,46.14 43.06,46.26 43.56,46.26 43.86,45.95 44.25,45.95 44.43,45.78 44.43,44.58 44.25,44.41
1D8V_S5 on BOTTOM: 61.39,49.14 60.73,49.81 60.73,49.83 59.67,50.89 59.16,50.89 58.97,50.7 55.99,50.7 53.67,53.01 53.67,54.47 53.91,54.71 54.48,54.71 56.45,52.73 59.04,52.73 61.86,49.91 61.86,49.32 61.68,49.14
1D8V_S5 on BOTTOM: 94.17,91.77 94.09,91.85 93.8,91.85 93.4,92.25 93.4,93.12 93.57,93.3 94.11,93.3 94.48,92.92 95.17,92.92 95.3,92.79 95.3,91.86 95.21,91.77
1D8V_S5 on L3: 76.21,59.05 76.46,58.8 76.46,58.05 76.35,57.94 75.46,57.94 74.81,57.29 74.81,55.78 76.35,54.23 76.35,52.13 76.42,52.07 76.42,51.46 76.3,51.33 76.05,51.33 75.89,51.5 75.89,51.97 75.98,52.06 75.98,52.45 75.84,52.59 75.52,52.59 74.77,51.84 72.39,51.84 72.32,51.91 72.32,52.67 71.58,53.41 69.66,53.41 69.35,53.72 69.35,53.99 70.95,55.58 71.4,55.58 74.87,59.05
1D8V_S5 on L4: 66.37,43.65 65.59,44.43 65.59,46.69 69.8,50.9 70.08,50.9 70.09,50.91 71.14,50.91 71.4,51.16 73.12,51.16 73.92,51.96 78.69,51.96 79.25,51.4 79.25,51.19 78.98,50.91 74.2,50.91 72.51,49.23 71.17,49.23 69.88,47.93 68.73,47.93 68.3,47.5 68.3,44.5 68.56,44.24 68.56,43.89 68.32,43.65 ; 1 cut-out
1D8V_S5 on L4: 43.56,46.83 43.56,42.86 43.96,42.46 45.56,42.46 46,42.89 46,47.45 44.78,48.67 44.78,50.43 46.9,52.55 48.53,52.55 49.14,53.16 53.98,53.16 54.18,53.36 54.18,54.22 53.18,55.22 51.88,55.22 51.05,56.06 49.58,56.06 47.55,54.03 45.1,54.03 42.44,51.36 42.44,47.95
1D8V_SPI on TOP: 139.02,71.37 138.83,71.55 138.83,73.07 138.86,73.1 140.44,73.1 140.64,73.3 140.64,74.04 140.25,74.43 140.25,75.01 140.37,75.13 141.1,75.13 141.28,74.95 141.28,73.4 139.25,71.37 ; 1 cut-out
1D8V_SPI on BOTTOM: 136.8,66.6 136.72,66.68 136.72,67.98 135.95,68.75 135.95,71.44 136.64,72.12 137.42,72.12 137.7,72.4 137.87,72.4 138.1,72.17 138.1,72.04 137.66,71.6 136.9,71.6 136.64,71.34 136.64,69.02 137.34,68.32 137.34,66.65 137.29,66.6
1D15V_S5 on TOP: 78.36,65.81 77.6,66.58 77.6,66.73 78.33,67.46 78.84,67.46 79.76,66.55 79.76,66.4 79.17,65.81 ; 3 cut-outs
1D15V_S5 on TOP: 64.41,29.4 63.68,30.14 62.94,30.14 60.3,32.78 57.3,32.78 56.83,32.31 54.48,32.31 50.81,35.98 50.81,39.26 49.02,41.05 49.02,44.09 45.02,48.09 45.02,50.15 45.32,50.45 46.66,50.45 46.77,50.34 46.77,48.07 50.44,44.41 50.44,41.31 51.94,39.81 51.94,36.91 54.78,34.06 61.03,34.06 63.09,32 64.05,32 65.2,30.85 68.74,30.85 72.77,34.87 74.95,34.87 76.23,36.16 79.28,36.16 79.84,36.72 81.26,36.72 83.05,38.52 84.04,38.52 85.87,40.35 87.2,40.35 88.98,42.14 88.98,43.67 88.12,44.54 88.12,45.15 87.1,46.18 87.1,48.52 85.06,50.55 84.11,50.55 82.67,51.99 82.01,51.99 81.82,52.17 81.45,52.17 81.26,51.99 81.07,51.99 80.86,52.2 80.86,52.53 81.59,53.26 81.8,53.26 82.54,52.52 83.25,52.52 83.72,52.99 84.84,52.99 89.59,48.24 89.76,48.24 90.88,49.35 91.38,49.35 91.83,49.81 92.15,49.81 94.12,47.84 94.13,47.84 96.14,45.83 96.14,45.54 93.41,42.81 93.19,42.81 88.94,38.56 87.08,38.56 87.07,38.56 86.74,38.56 83.81,35.62 83.29,35.62 79.31,31.64 73.87,31.64 71.64,29.4 ; 6 cut-outs
1D15V_S5 on BOTTOM: 44.62,47.84 44.57,47.9 44.57,50.39 44.86,50.67 45.8,50.67 45.98,50.49 45.98,48.47 45.98,48.46 45.98,47.9 45.92,47.84
1D15V_S5 on L3: 81,52 80.82,52.17 80.82,52.5 80.95,52.63 80.95,53.14 79.2,54.89 78.97,54.89 76.52,57.34 76.52,57.95 76.59,58.01 76.59,59.31 78.34,61.06 78.34,66.36 78.69,66.71 80.04,66.71 81.64,65.1 81.64,62.79 80.32,61.47 80.32,60.75 80.91,60.17 80.91,58.46 81.43,57.94 81.43,55.2 83.21,53.42 83.21,52.38 82.82,52 81.94,52 81.79,52.15 81.43,52.15 81.28,52
1D24V_S5 on TOP: 57.21,36.34 54.11,39.44 54.11,39.83 53.65,40.29 51.64,40.29 50.57,41.36 50.57,45.13 50.72,45.27 52.27,45.27 52.43,45.11 52.43,42.56 53.09,41.91 53.75,41.91 58.34,37.31 60.9,37.31 62.79,39.2 71.35,39.2 72.3,40.15 73.08,40.15 74.73,41.79 74.96,41.79 75.27,41.48 75.64,41.48 76.37,42.21 76.37,43.97 76.56,44.16 76.87,44.16 77.2,44.48 77.2,44.71 76.87,45.04 76.87,46.22 77.09,46.44 78.06,46.44 78.32,46.71 78.7,46.71 79.46,45.95 79.46,45.6 79.14,45.29 79.14,45.03 80.61,43.56 80.61,43.28 80.27,42.93 79.87,42.93 77.65,40.72 76.72,40.72 75.83,39.84 75.06,39.84 74.2,38.98 72.94,38.98 71.79,37.83 63.64,37.83 62.15,36.34 ; 13 cut-outs
1D24V_S5 on BOTTOM: 77.41,43.51 77.36,43.56 77.35,43.56 77.2,43.71 77.2,44.28 77.04,44.43 77.04,44.89 76.79,45.14 76.79,46.21 76.36,46.64 76.36,47.73 76.74,48.12 78.8,48.12 79.12,48.44 79.12,50.04 79.88,50.81 80.06,50.81 80.14,50.73 80.14,50.19 79.69,49.73 79.69,49.42 79.81,49.3 80.49,49.3 80.63,49.16 80.63,49.14 80.64,49.13 80.64,48.87 80.55,48.78 79.89,48.78 78.6,47.49 78.6,47.17 78.76,47.01 78.76,46.48 78.67,46.39 78.67,45.83 78.59,45.75 78.59,44.53 78.25,44.19 78.25,43.65 78.11,43.51
1D24V_S5 on BOTTOM: 75.44,49.34 75.37,49.41 75.37,50.07 75.37,50.07 75.37,50.14 74.28,51.23 74.28,51.8 74.38,51.9 75.14,51.9 75.32,51.72 75.32,50.58 75.85,50.05 75.85,49.39 75.8,49.34
1D24V_S5 on BOTTOM: 50.73,44.09 50.52,44.3 50.52,47.01 50.67,47.16 52.07,47.16 52.27,46.96 52.27,44.23 52.14,44.09
1D35V_CPU_VDDQ_S3 on TOP: outline of 127 points within 77.58,24.56 134,88.74 ; 51 cut-outs
1D35V_CPU_VDDQ_S3 on BOTTOM: 82.62,52.22 82.5,52.33 82.5,53.49 82.61,53.6 82.8,53.6 83.42,52.99 83.42,52.54 83.09,52.22
1D35V_CPU_VDDQ_S3 on BOTTOM: 76.7,58.55 76.62,58.63 76.23,58.63 76.12,58.74 76.12,58.99 76.61,59.48 76.61,59.94 76.01,60.54 76.01,61.94 75.53,62.42 75.53,63.29 75.4,63.41 75.4,64.11 75.59,64.3 76.33,64.3 76.45,64.18 77.17,63.46 77.17,63.07 76.64,62.54 76.64,61.97 76.94,61.68 77.98,61.68 78.29,61.37 78.29,60.3 78.16,60.18 77.52,60.18 77.33,59.99 77.33,59.7 77.6,59.43 77.6,58.75 77.48,58.63 77.1,58.63 77.02,58.55
1D35V_CPU_VDDQ_S3 on BOTTOM: outline of 342 points within 93.98,22.52 133.51,86.64 ; 7 cut-outs
1D35V_CPU_VDDQ_S3 on BOTTOM: 96.77,46.2 96.52,46.46 96.52,47.25 96.06,47.71 96.06,48.08 96.49,48.52 96.49,48.88 95.12,50.25 93.61,50.25 92.94,50.92 92.94,51.18 93.05,51.3 93.28,51.3 93.51,51.07 93.95,51.07 93.99,51.02 95.65,51.02 95.93,51.3 95.93,51.72 95.59,52.06 95.05,52.06 94.69,52.42 94.25,52.42 94.24,52.41 94.01,52.41 93.73,52.69 93.5,52.69 92.97,52.15 92.69,52.15 92.56,52.28 92.56,52.41 92.82,52.66 92.82,52.89 92.56,53.15 92.56,53.37 93.07,53.88 93.71,53.88 93.88,54.06 94.09,54.06 94.39,53.75 94.39,53.52 94.46,53.45 96.37,53.45 96.94,54.01 96.94,54.61 96.73,54.81 96.2,54.81 95.14,55.87 95.14,56.2 97.5,58.56 100.95,58.56 102.98,56.54 102.98,50.08 100.07,47.18 97.97,47.18 97,46.2 ; 9 cut-outs
1D35V_CPU_VDDQ_S3 on BOTTOM: 75.46,67.94 75.39,68.01 75.39,68.17 76.72,69.51 76.72,69.72 76.34,70.11 76.34,70.25 76.37,70.29 76.37,70.75 76.26,70.87 75.22,70.87 74.97,70.62 74.97,69.78 75.21,69.53 75.21,69.12 75.08,68.98 74.9,68.98 74.44,69.45 74.44,71.42 74.44,71.42 74.44,72.66 73.71,73.4 73.71,73.65 75.07,75.02 77.06,75.02 79.64,72.43 79.64,70.85 78.97,70.18 77.38,68.59 76.99,68.59 76.91,68.66 76.38,68.66 75.65,67.94 ; 4 cut-outs
1D35V_CPU_VDDQ_S3 on L3: 77.65,71.98 79.08,71.98 79.67,71.4 79.67,68.46 77.82,66.61 77.82,63.27 76.52,61.96 75.63,61.96 75.02,62.58 75.02,64.44 76.27,65.69 76.27,69.37 77.37,70.47 77.37,71.7
1D35V_PWR on TOP: 76.35,27.04 75.28,28.11 75.28,29.21 75.42,29.35 75.96,29.35 76.16,29.15 76.16,28.67 76.97,27.86 76.97,27.12 76.89,27.04 ; 2 cut-outs
1D35V_PWR on BOTTOM: 86.76,22.57 85.81,23.53 85.81,26.83 86.06,27.08 92.24,27.08 92.96,27.8 93.58,27.8 93.62,27.76 93.62,23.15 93.04,22.57 ; 2 cut-outs
1D35V_S3_DISCHG on BOTTOM: 140.8,38.76 140.67,38.9 140.67,39.51 140.77,39.61 141.43,39.61 141.83,40.01 141.83,41.22 141.87,41.26 142.34,41.26 142.44,41.17 142.44,38.88 142.31,38.76 ; 1 cut-out
3D3V_AUX_KBC on TOP: 56.08,3.07 55.99,3.16 55.99,3.67 54.91,4.76 54.91,6.09 55.11,6.3 57.52,6.3 57.86,5.96 57.86,4.18 58.02,4.02 59.56,4.02 59.89,4.35 60.73,4.35 61.06,4.68 61.77,4.68 61.9,4.55 61.9,4.09 61.2,3.39 60.72,3.39 60.4,3.07 ; 1 cut-out
3D3V_AUX_S5 on TOP: 44.27,17.11 44.11,17.26 44.11,18.03 44.27,18.19 45.59,18.19 45.65,18.13 45.65,17.16 45.59,17.11
3D3V_AUX_S5 on BOTTOM: 58.65,29.64 58.37,29.92 58.37,30.56 58.32,30.61 58.32,32.23 58.34,32.26 58.9,32.26 58.9,31.5 59.16,31.24 59.61,31.24 59.74,31.12 59.74,30.61 59.51,30.38 59.33,30.38 59.08,30.13 59.08,29.8 58.93,29.64
3D3V_AUX_S5_MUX on BOTTOM: 135.38,62.74 135.17,62.95 135.17,63.34 135.33,63.5 138.07,63.5 138.29,63.28 138.29,62.82 138.26,62.79 138.23,62.79 138.18,62.74
3D3V_CAMERA_S0 on BOTTOM: 69.24,80.98 69.14,81.09 69.14,81.49 69.13,81.5 69.13,81.57 68.58,82.12 67,82.12 66.5,82.63 66.5,83.42 66.12,83.79 65.43,83.79 65.41,83.82 65.41,84.96 65.51,85.06 68.02,85.06 69.67,83.41 69.67,82.55 69.83,82.4 70.76,82.4 70.88,82.28 70.88,81.1 70.76,80.98 ; 5 cut-outs
3D3V_CARD on BOTTOM: 15.61,25.5 15.6,25.51 15.46,25.51 15.29,25.68 15.29,26.65 15.4,26.76 15.58,26.76 15.94,27.12 15.94,27.93 16.55,28.53 19.8,28.53 19.95,28.39 19.95,26.3 19.85,26.21 17.67,26.21 17.02,25.56 16.96,25.5 ; 8 cut-outs
3D3V_CARD on BOTTOM: 11.58,38.38 11.33,38.64 11.33,39.42 11.58,39.68 12.4,39.68 12.42,39.65 12.42,38.97 11.84,38.38
3D3V_CARD_S0 on BOTTOM: 9.09,36.09 8.85,36.33 8.85,37.85 8.94,37.94 9.37,37.94 9.63,38.21 9.63,39.67 9.84,39.87 11.01,39.87 11.3,40.17 12.51,40.17 12.54,40.14 12.54,39.91 12.49,39.86 11.52,39.86 11.07,39.41 11.07,38.47 11.44,38.1 11.87,38.1 12.52,38.76 12.52,38.97 12.77,39.22 13.49,39.22 13.51,39.2 13.51,37.37 12.85,36.7 11.04,36.7 10.81,36.47 10.81,36.18 10.72,36.09 ; 6 cut-outs
3D3V_LCDVDD_S0 on TOP: 63.28,81.52 63.21,81.59 63.21,83.36 63.21,83.36 63.21,83.97 63.38,84.13 64.75,84.13 65.16,83.72 65.16,82.72 63.96,81.52 ; 2 cut-outs
3D3V_LCDVDD_S0 on BOTTOM: 63.78,80.55 63.33,80.99 63.33,81.17 63.14,81.36 63.14,83.16 63.34,83.35 63.58,83.35 63.88,83.66 63.88,84.7 63.92,84.74 64.75,84.74 64.8,84.69 64.8,83.68 65.08,83.4 65.1,83.4 66.3,82.2 66.3,81.35 66.25,81.3 64.8,81.3 64.27,80.77 64.26,80.77 64.03,80.55 ; 2 cut-outs
3D3V_PU5402 on BOTTOM: 49.05,37.97 49.02,38 49.02,39.63 48.86,39.78 45.77,39.78 45.7,39.85 45.7,42.83 45.75,42.88 50.73,42.88 51.84,41.77 51.84,40.01 51.64,39.81 51.64,38.81 51.54,38.71 50.62,38.71 49.88,37.97 ; 5 cut-outs
3D3V_PWR on BOTTOM: 23.93,27.11 23.71,27.33 23.71,32.24 23.88,32.41 24.88,32.41 25.59,31.71 31.61,31.71 32.02,31.29 32.02,28.01 31.91,27.9 25.12,27.9 24.33,27.11 ; 2 cut-outs
3D3V_PWR_2 on TOP: 36.48,25.33 36.08,25.73 36.08,26.98 36.14,27.05 37.85,27.05 37.9,27 37.9,25.45 37.77,25.33 ; 1 cut-out
3D3V_S0 on TOP: 102.66,85.94 101.88,86.71 98.12,86.71 97.56,87.27 97.56,88.32 97.69,88.45 98.25,88.45 98.89,89.09 102.57,89.09 103.96,87.7 107.39,87.7 107.87,88.17 108.95,88.17 110.07,89.29 110.07,90.16 110.85,90.93 110.85,92.23 110.97,92.35 112.01,92.35 112.01,92.31 112.09,92.23 112.09,88.9 109.12,85.94
3D3V_S0 on TOP: 76.76,7.69 76.17,8.29 76.17,9.04 75.66,9.55 73.82,9.55 73.12,10.25 65.68,10.25 64.62,11.31 64.62,12.43 64.82,12.63 66.03,12.63 66.21,12.46 66.21,11.5 66.37,11.34 72.23,11.34 72.25,11.36 73.14,11.36 73.22,11.44 76.85,11.44 77.01,11.28 77.01,9.34 77.12,9.24 77.12,7.82 76.99,7.69
3D3V_S0 on TOP: 96.14,77.73 95.89,77.98 95.89,80.11 96.14,80.37 96.9,80.37 97.03,80.24 97.03,77.98 96.77,77.73
3D3V_S0 on TOP: 129.12,88.15 129.11,88.16 128.54,88.16 128.24,88.45 128.24,90.09 128.4,90.24 129.61,90.24 131.69,92.33 131.69,92.73 133.82,94.86 137.26,94.86 137.98,94.14 137.98,92.72 137.78,92.53 136.04,92.53 135.63,92.93 135.63,93.55 135.43,93.76 135.09,93.76 134.86,93.52 134.86,93.3 132.22,90.66 132.22,89.21 131.16,88.15 ; 1 cut-out
3D3V_S0 on TOP: 171.06,92.09 170.76,92.38 170.76,93.07 171.17,93.47 171.17,93.94 171.31,94.09 171.97,94.09 172.17,93.89 172.17,92.26 172,92.09 ; 1 cut-out
3D3V_S0 on BOTTOM: 94.97,61.62 94.41,62.18 94.41,65.83 94.34,65.9 91.88,65.9 91.57,65.58 90.75,65.58 90.6,65.74 90.6,66.35 90.7,66.45 95.2,66.45 95.48,66.17 96.06,66.17 96.52,66.63 97.31,66.63 97.36,66.58 97.36,65.13 97.23,65 96.47,65 95.71,64.24 95.71,63.45 96.27,62.89 97.61,62.89 97.66,62.84 97.66,61.72 97.56,61.62 ; 6 cut-outs
3D3V_S0 on BOTTOM: 137.95,92.29 135.94,94.31 135.54,94.31 134.62,95.23 134.62,96.39 134.44,96.57 133.03,96.57 132.51,96.05 132.51,94.66 132.41,94.56 131.9,94.56 131.8,94.66 131.8,96.25 132.76,97.21 132.79,97.21 132.89,97.31 135.68,97.31 136.36,96.63 136.36,94.87 137.94,93.29 138.34,93.29 138.4,93.23 138.4,92.37 138.32,92.29 ; 4 cut-outs
3D3V_S0 on BOTTOM: 147.78,47.98 147.74,48.01 147.74,49.18 148.05,49.48 148.05,50.07 148.15,50.17 148.15,50.96 148.15,50.97 148.15,52.41 146.49,54.06 146.49,58.32 147.12,58.94 147.12,61.22 147.28,61.39 149.28,61.39 149.34,61.33 149.34,59.09 149.32,59.07 149.32,54.61 150.86,53.07 150.86,49.36 149.91,48.41 149.12,48.41 148.69,47.98 ; 5 cut-outs
3D3V_S0 on BOTTOM: 154.18,79.88 154.04,80.02 154.04,80.29 153.95,80.38 153.02,80.38 152.98,80.42 152.98,80.69 152.99,80.7 153.9,80.7 153.98,80.78 153.98,81.51 154.29,81.82 154.78,81.82 154.86,81.75 154.86,80.04 154.69,79.88
3D3V_S0 on BOTTOM: 6.5,36.13 6.33,36.3 6.33,37.87 6.51,38.04 8.46,38.04 8.63,37.88 8.63,36.34 8.42,36.13 ; 2 cut-outs
3D3V_S0 on BOTTOM: 67.31,78 67.06,78.25 67.06,81.82 67.12,81.88 68.58,81.88 68.99,81.46 68.99,80.76 69.25,80.5 70.76,80.5 70.9,80.37 70.9,79.2 70.59,78.89 70.59,78.13 70.46,78 ; 2 cut-outs
3D3V_S0 on L4: 147.82,59.37 147.27,59.93 147.27,62.78 144.62,65.43 144.62,69.58 144.64,69.59 144.64,69.79 151.9,77.05 152.35,77.05 152.65,77.35 152.65,77.81 153.56,78.71 153.56,81.08 154.6,82.12 170.09,82.12 170.59,82.62 170.59,92.46 164.92,98.13 147.95,98.13 146.79,96.97 146.79,95.53 146.21,94.94 145.14,94.94 144.77,95.32 139.72,95.32 139.15,94.75 138.82,94.75 137.44,93.37 136.65,93.37 134.51,95.51 134.51,97.06 134.76,97.3 135.5,97.3 135.74,97.06 138.38,97.06 138.74,97.43 142.47,97.43 144.76,99.72 166.56,99.72 172.21,94.07 172.21,80.51 170.98,79.29 163.98,79.29 162.75,80.51 159.22,80.51 158.8,80.09 158.28,80.09 156.55,78.37 155.48,78.37 155.23,78.11 155.23,77.8 155.21,77.79 155.21,76.28 154.21,75.28 152.71,75.28 150.5,73.08 150.5,71.88 150.05,71.42 148.85,71.42 146.48,69.05 146.48,66.05 149.65,62.87 149.65,59.77 149.26,59.37
3D3V_S0 on L4: 113.59,86.97 114.16,87.54 127.87,87.54 128.97,88.64 128.97,89.92 128.74,90.15 127.69,90.15 126.55,89.01 117.34,89.01 116.54,89.81 110.92,89.81 110.24,89.13 110.24,87.3 110.57,86.97
3D3V_S0 on L4: 95.22,83.72 96.9,85.4 96.9,87.63 96.72,87.81 92.1,87.81 91.31,88.6 89.66,90.25 83.36,90.25 75.52,82.42 73.21,82.42 72.92,82.13 72.92,81.74 72.71,81.53 69.32,81.53 69.12,81.33 69.12,80.22 68.97,80.07 67.53,80.07 67.32,80.28 67.32,82.29 68.34,83.31 72.36,83.31 80.06,91.01 80.06,95.84 80.24,96.01 80.95,96.01 81.99,94.97 87.45,94.97 90.56,91.86 92.47,91.86 93.35,90.97 96.86,90.97 98.89,88.94 98.89,88.65 99.47,88.07 99.47,86.9 99.23,86.65 99.23,84.8 98.45,84.02 98.45,80.57 97.13,79.25 95.99,79.25 95.22,80.01
3D3V_S0 on L4: 5.48,38.68 5.48,36.81 5.81,36.48 6.73,36.48 10.18,39.93 10.18,42.78 10.76,43.36 15.09,43.36 16.41,44.68 16.41,47.17 16.33,47.25 13.04,47.25 12.16,46.37 10.14,46.37 6.73,42.96 6.73,39.92
3D3V_S5 on TOP: 4.74,34.53 4.53,34.74 4.53,38.47 4.39,38.61 4.39,39.61 4.47,39.69 6.11,39.69 6.23,39.57 6.23,36.37 7.24,35.36 7.94,35.36 8.11,35.53 8.11,36.91 8.22,37.03 9.37,37.03 9.56,36.83 9.56,34.83 9.26,34.53 ; 1 cut-out
3D3V_S5 on TOP: 69.73,11.44 69.6,11.58 69.6,12.94 69.68,13.03 70.46,13.03 71.41,12.08 72.13,12.08 72.3,11.9 72.3,11.59 72.16,11.44
3D3V_S5 on TOP: 56.56,39.36 56,39.92 56,41.17 56.18,41.35 56.47,41.35 56.58,41.25 56.58,41.01 56.58,41 56.58,40.54 57.03,40.1 58,40.1 59.44,41.53 60.27,41.53 60.48,41.73 60.48,42.27 60.22,42.52 60.22,42.95 60.35,43.08 60.99,43.08 60.99,42.39 61.09,42.29 61.09,41.35 60.65,40.91 59.86,40.91 58.3,39.36
3D3V_S5 on TOP: 18.92,61.32 18.9,61.34 18.9,62.26 18.97,62.33 20.17,62.33 20.55,62.71 21.74,62.71 21.82,62.64 21.82,62.18 21.72,62.08 20.37,62.08 20.24,61.95 20.24,61.44 20.12,61.32
3D3V_S5 on TOP: 30.51,35.27 29.46,36.32 29.46,43.18 30.03,43.75 30.03,47.51 30.51,47.99 32.53,47.99 32.93,47.58 32.93,47.18 33.38,46.74 33.38,41.99 33.37,41.99 33.37,35.78 32.86,35.27 ; 1 cut-out
3D3V_S5 on TOP: 118.75,12.24 118.16,12.83 118.16,14.61 118.67,15.11 121.08,15.11 121.21,14.99 121.21,12.8 120.65,12.24 ; 1 cut-out
3D3V_S5 on BOTTOM: 20.79,27.13 20.53,27.38 20.53,30.75 18.23,33.06 15.66,33.06 14.23,34.48 9.16,34.48 8.88,34.76 8.88,35.96 8.92,36 9.34,36 9.4,35.94 10.67,35.94 11.26,35.35 17.69,35.35 18.24,34.8 21.67,34.8 21.71,34.85 22.74,34.85 25.01,37.12 33.5,37.12 33.8,36.82 33.8,35.28 33.45,34.92 25.85,34.92 23.38,32.45 23.38,27.27 23.24,27.13
3D3V_S5 on BOTTOM: 30.31,41 30.11,41.2 30.11,42.34 30.21,42.45 32.58,42.45 32.65,42.37 32.65,41.18 32.48,41 ; 1 cut-out
3D3V_S5 on BOTTOM: 92.48,87.51 92.4,87.59 92.4,87.91 93.45,88.96 93.45,89.74 92.3,90.89 90.62,90.89 89.61,91.9 89.61,92.99 89.77,93.15 92.96,93.15 93.14,92.97 93.14,91.57 94.41,90.29 94.41,88.55 93.38,87.51 ; 1 cut-out
3D3V_S5 on BOTTOM: 152.42,79.87 151.76,80.53 151.11,80.53 150.93,80.72 150.93,81.09 151.12,81.29 151.86,81.29 152.92,80.22 153.84,80.22 153.88,80.18 153.88,79.92 153.83,79.87
3D3V_S5 on BOTTOM: 30.44,46.8 30.31,46.93 30.31,48.37 30.34,48.4 32.06,48.4 32.17,48.29 32.17,47.04 31.94,46.8
3D3V_S5 on BOTTOM: 41.65,5.51 40.64,6.52 40.64,11.54 40.79,11.69 41.12,11.69 41.45,11.36 41.45,8.98 42.71,7.71 43.9,7.71 44.01,7.6 44.01,7.18 43.94,7.11 42.58,7.11 42.36,6.89 42.36,6.54 42.61,6.29 43.84,6.29 44.06,6.07 49.23,6.07 49.48,6.32 49.48,6.95 49.53,7 50.54,7 50.59,6.95 50.59,6.47 50.51,6.38 50.1,6.38 49.89,6.17 49.89,5.65 49.74,5.51
3D3V_S5 on BOTTOM: 144.37,47.99 143.69,48.67 143.69,51.17 144.11,51.59 145.92,51.59 146.08,51.43 146.08,49.54 146.39,49.24 146.39,48.05 146.34,47.99 ; 5 cut-outs
3D3V_S5 on BOTTOM: 43.41,12.8 41.87,14.34 41.87,15.08 42.19,15.4 44.59,15.4 44.65,15.34 44.65,12.85 44.6,12.8 ; 1 cut-out
3D3V_S5 on BOTTOM: 52.32,54.94 51.97,55.3 51.98,55.31 51.98,55.39 52.43,55.83 52.65,55.83 53.21,56.39 53.8,56.39 53.9,56.29 53.9,55.4 53.84,55.34 53.68,55.34 53.29,54.94
3D3V_S5 on L3: 141.37,64.34 141.7,64.34 141.89,64.14 141.89,62.67 141.69,62.47 141.36,62.47 141.3,62.53 141.3,64.26
3D3V_S5 on L3: 50.21,6.92 50.7,6.92 50.8,7.01 52.99,7.01 54.07,5.93 54.07,5.51 53.94,5.38 53.44,5.38 52.46,6.36 50.15,6.36 49.98,6.53 49.98,6.69
3D3V_S5 on L4: 24,11.16 41.09,11.16 42.12,12.18 43.33,12.18 44.35,11.16 99.29,11.16 100.49,12.36 105.73,12.36 106.93,11.16 120.76,11.16 121.1,11.5 121.1,16.44 120.8,16.74 42.11,16.74 41.95,16.9 30.19,16.9 29.46,17.63 29.46,31.7 28.57,32.59 20.41,32.59 19.79,31.96 19.79,24.52 21.31,23 21.31,13.85
3D3V_S5 on L5VCC: 118.21,11.32 116.92,12.61 116.65,12.88 116.65,21.33 119.59,24.27 120.35,24.27 120.84,24.76 120.84,29.59 121.38,30.13 130.3,30.13 131.04,30.88 140.56,30.88 141.54,31.86 141.54,47.98 143.02,49.46 143.02,50.86 143.37,51.21 147.45,51.21 148.75,49.91 148.75,43.45 149.79,42.42 149.79,42.03 150.43,41.38 150.43,29.37 147.5,26.43 125.4,26.43 125.03,26.06 125.03,24.27 124.69,23.81 124.02,22.87 124.02,11.59 123.75,11.32
3D3V_S5_PRIME on TOP: 62.21,53.35 61.34,54.22 61.34,54.59 61.17,54.75 59.83,54.75 59.4,54.32 58.6,54.32 57.97,54.95 57.97,55.36 57.61,55.73 57.61,56.36 56.77,57.2 56.77,57.84 56.87,57.94 58.19,57.94 59.24,56.88 60.15,56.88 60.9,56.14 62.13,56.14 62.27,56 62.27,54.79 62.71,54.35 62.71,53.41 62.65,53.35 ; 4 cut-outs
3D3V_S5_PRIME on TOP: 56.72,27.48 56.54,27.66 56.54,28.35 57.63,29.44 57.63,30.2 58.34,30.91 59.72,30.91 60.3,30.33 60.3,29.85 59.23,28.78 58.57,28.78 57.28,27.48
3D3V_S5_PRIME on TOP: 65.16,39.4 64.96,39.6 64.96,40.42 65.08,40.54 65.3,40.54 66.51,41.75 66.51,42 65.81,42.7 65.81,45.18 65.54,45.46 65.54,45.84 64.99,46.39 64.97,46.39 64.79,46.57 61.24,46.57 61.05,46.37 60.53,46.37 60.43,46.47 60.43,47.64 60.58,47.8 65.7,47.8 66.32,47.18 66.63,47.18 66.76,47.05 66.76,45.93 66.64,45.81 66.64,45.46 67.24,44.85 67.24,43.46 67.24,43.46 67.24,43.37 67.93,42.68 67.93,41.11 66.23,39.4 ; 1 cut-out
3D3V_S5_PRIME on TOP: 53.37,18.87 53.16,19.08 53.16,19.76 53.39,19.99 53.92,19.99 54.33,20.4 54.61,20.4 54.64,20.42 54.99,20.42 55.08,20.33 55.08,19.18 54.77,18.87
3D3V_S5_PRIME on BOTTOM: 62.2,53.28 61.73,53.75 61.73,53.87 60.85,54.75 59.74,54.75 59.42,54.42 58.71,54.42 58.62,54.51 58.62,54.88 58.91,55.17 61.06,55.17 61.55,54.68 62.42,54.68 62.68,54.41 62.68,53.43 62.54,53.28
3D3V_S5_PRIME on BOTTOM: 66.07,45.72 65.89,45.9 65.89,46.26 66.17,46.53 66.21,46.53 66.78,46.53 67.11,46.86 67.8,46.86 67.93,46.73 67.93,46.51 67.86,46.43 67.25,46.43 66.74,45.92 66.73,45.92 66.53,45.72
3D3V_S5_PRIME on BOTTOM: 46.04,12.78 45.98,12.84 45.98,13.47 46.42,13.91 46.42,15.18 46.69,15.45 47.8,15.45 47.88,15.36 47.88,14.52 48.22,14.18 48.22,13.57 48.18,13.53 47.62,13.53 46.87,12.78 ; 2 cut-outs
3D3V_S5_PRIME on L3: 60.54,55.83 59.51,55.83 58.65,54.97 58.65,54.65 58.79,54.51 59.06,54.51 59.16,54.61 60.55,54.61 60.69,54.74 60.69,55.68
3D3V_S5_PRIME on L4: 58.34,38.36 59.03,38.36 59.23,38.15 59.23,35.51 60.33,34.42 60.33,30.11 59.86,29.64 59.32,29.64 59.11,29.86 59.11,33.83 58.06,34.88 58.06,37.75 58.22,37.9 58.22,38.23
3D3V_WLAN_S0 on TOP: 175.08,77.7 174.73,78.06 171.21,78.06 170.18,79.08 170.18,90.17 172.34,92.32 172.34,94.11 172.41,94.18 175.97,94.18 176.14,94.01 176.14,92.8 176.14,92.8 176.14,92.26 173.76,89.88 173.76,85.22 175.23,83.75 175.23,82.81 176.77,81.26 176.77,77.81 176.66,77.7 ; 9 cut-outs
3D3V_WLAN_S0 on BOTTOM: 175.06,92.49 174.87,92.67 174.87,94.48 175.09,94.7 178.15,94.7 178.18,94.67 178.18,93.88 178.12,93.82 176.92,93.82 176.89,93.78 176.89,92.64 176.73,92.49
3D3V_WLAN_S0 on BOTTOM: 176.61,76.1 175.18,77.52 175.18,80.37 175.35,80.53 175.36,80.52 176.28,80.52 176.91,79.88 176.91,77.19 176.92,77.18 177.89,77.18 177.93,77.14 177.93,76.23 177.8,76.1
+DC_IN on TOP: 25.22,2.04 21.76,5.49 21.76,25.51 23.85,27.6 23.85,34.3 23.38,34.77 23.38,42.32 22.81,42.89 22.81,49.15 25.27,51.6 25.27,60.97 22.75,63.49 22.75,64.89 22.16,65.48 22.16,67.78 21.23,68.71 21.23,73.09 21.55,73.41 25.65,73.41 25.76,73.31 25.76,72.59 26.08,72.27 26.08,69.15 26.59,68.64 26.59,66.73 29.24,64.08 29.24,62.87 31.61,60.5 35.55,60.5 35.82,60.23 35.82,58.23 36.29,57.76 36.29,51.59 34,49.3 29.43,49.3 28.27,48.14 28.27,43.72 28.63,43.36 29,43.36 29.27,43.09 29.27,40.69 29.27,40.69 29.27,36.18 30.98,34.47 30.98,25.69 32.64,24.03 32.64,10.56 34.78,8.43 34.78,2.68 34.14,2.04 ; 20 cut-outs
+DC_IN on BOTTOM: 138.58,11.2 138.2,11.58 138.2,14.3 138.43,14.52 139.75,14.52 140.06,14.21 140.06,13.15 140.18,13.04 141.31,13.04 141.38,12.97 141.38,11.26 141.31,11.2
+DC_IN on BOTTOM: 22.73,67.62 22.5,67.85 22.5,73.52 22.79,73.81 26.36,73.81 27.16,74.61 28.3,74.61 28.42,74.48 28.42,72.03 27.3,70.91 26.4,70.91 26.02,70.53 26.02,69.11 26.15,68.98 26.76,68.98 26.85,68.89 26.85,67.98 26.64,67.77 23.82,67.77 23.67,67.62 ; 1 cut-out
+DC_IN on L5VCC: 131.5,1.27 131.34,1.34 131.27,1.5 131.27,3.5 130.61,5.1 129,5.77 73.9,5.77 72.29,5.1 71.63,3.5 71.63,1.5 71.56,1.34 71.4,1.27 30.54,1.27 30.54,6.35 33.23,9.03 63.07,9.03 65.23,11.19 77.68,11.19 79.45,12.97 116.02,12.97 118.06,10.94 130.48,10.94 131.33,10.09 133.47,10.09 134.64,11.26 137.65,11.26 138.19,11.8 138.19,14.34 138.98,15.13 142.79,15.13 146.75,11.17 146.75,11.1 146.01,10.45 145.73,9.5 145.73,1.5 145.66,1.34 145.5,1.27
+DC_IN_C on TOP: 22.71,73.63 22.62,73.72 22.62,74.47 23.1,74.96 23.1,76.47 23.33,76.7 25.6,76.7 25.97,76.33 26.49,76.33 26.67,76.15 26.67,74.46 26.47,74.26 25.82,74.26 25.73,74.16 25.73,73.79 25.57,73.63 ; 6 cut-outs
+DC_IN_C on BOTTOM: 22.96,74.09 22.73,74.32 22.73,75.62 23.14,76.03 24.08,76.03 24.23,76.18 24.23,77.95 24.46,78.18 26.88,78.18 27.07,77.99 27.07,74.77 26.4,74.09
AD+_TO_SYS on BOTTOM: 141.96,18.26 141.37,18.86 141.37,18.9 141.05,19.22 141.05,22.18 141.32,22.45 145.38,22.45 145.46,22.37 145.46,21.27 145.3,21.11 143.96,21.11 143.67,20.83 143.67,18.34 143.59,18.26 ; 2 cut-outs
AUD_AGND on TOP: 138.89,81.15 138.61,81.43 138.61,81.81 138.78,81.98 144.23,81.98 144.36,81.85 144.36,81.37 144.14,81.15 ; 2 cut-outs
AUD_AGND on TOP: 147.86,88.04 147.62,88.29 146.35,88.29 146.08,88.56 146.08,89.14 146.36,89.43 148.26,89.43 148.43,89.26 148.43,88.33 148.14,88.04 ; 2 cut-outs
AUD_AGND on TOP: 147.41,83.79 147.11,84.09 146.6,84.09 146.48,84.21 146.48,85.26 146.65,85.43 147.91,85.43 148.23,85.11 148.23,83.89 148.13,83.79 ; 1 cut-out
AUD_AGND on BOTTOM: 149.52,93.59 149.04,94.08 149.04,96.67 149.07,96.71 149.77,96.71 150.04,96.44 150.04,95.87 150.27,95.63 151.44,95.63 151.56,95.51 151.56,94.92 151.42,94.78 150.94,94.78 150.36,94.2 150.36,93.71 150.24,93.59 ; 1 cut-out
AUD_AGND on BOTTOM: 148.84,87.97 148.76,88.04 147.77,88.04 147.35,88.47 146.58,88.47 146.52,88.53 146.52,90.65 146.37,90.8 145.78,90.8 145.59,90.98 145.59,91.47 145.62,91.49 147.76,91.49 149.34,89.91 149.34,88.01 149.3,87.97 ; 3 cut-outs
AUD_AGND on BOTTOM: 140.22,81.18 140.2,81.2 140.2,82.46 140.4,82.65 141.8,82.65 141.95,82.8 144.53,82.8 144.6,82.72 144.6,81.92 143.87,81.18 ; 4 cut-outs
AUD_AGND on BOTTOM: 132.76,85.63 132.16,86.23 132.16,88.5 132.28,88.62 133.65,88.62 133.76,88.52 133.76,87.66 133.75,87.65 133.75,86.88 134.01,86.62 134.01,85.78 133.86,85.63 ; 3 cut-outs
AUD_AGND on L2GND, L5VCC: 138.89,81.17 138.62,81.44 138.62,82.33 137.87,83.07 136.04,83.07 134.41,84.7 133.83,84.7 132.14,86.39 132.14,88.26 132.29,88.41 136.22,88.41 136.6,88.79 137.97,88.79 137.99,88.77 137.99,87.96 137.84,87.82 136.94,87.82 136.25,87.14 135.18,87.14 134.81,86.77 134.81,85.44 136.04,84.21 138.25,84.22 138.62,84.58 138.62,85.61 139.31,86.3 139.31,86.93 139.51,87.14 142.57,87.14 143.07,87.63 143.07,91.95 143.33,92.22 143.72,92.22 148.41,96.92 150.45,96.92 150.81,97.28 150.81,97.53 150.95,97.68 153.85,97.68 153.99,97.53 153.99,92.61 153.85,92.47 152.32,92.47 151.96,92.11 151.95,91.09 151.32,90.46 151.32,87.28 149.65,85.61 148.77,85.61 148.4,85.25 148.4,84.1 147.21,82.92 145.56,82.92 143.81,81.17
AUD_AGND on L4: 138.89,81.17 138.62,81.44 138.62,82.33 137.87,83.07 136.04,83.07 134.41,84.7 133.83,84.7 132.14,86.39 132.14,88.26 132.29,88.41 136.22,88.41 136.6,88.79 137.97,88.79 137.99,88.77 137.99,87.96 137.84,87.82 136.94,87.82 136.25,87.14 135.18,87.14 134.81,86.77 134.81,85.44 136.04,84.21 138.25,84.22 138.62,84.58 138.62,85.61 139.31,86.3 139.31,86.93 139.51,87.14 142.57,87.14 143.07,87.63 143.07,91.95 143.33,92.22 143.72,92.22 148.41,96.92 150.45,96.92 150.81,97.28 150.81,97.53 150.95,97.68 153.85,97.68 153.99,97.53 153.99,92.62 153.85,92.48 152.33,92.48 151.95,92.1 151.95,91.09 151.32,90.46 151.32,87.28 149.65,85.61 148.77,85.61 148.4,85.25 148.4,84.1 147.21,82.92 145.56,82.92 143.81,81.17
BT+_R on BOTTOM: 124.74,19.71 123.97,20.48 123.14,20.48 122.98,20.64 122.98,24.55 123.09,24.66 127.66,24.66 128.06,24.27 128.06,19.89 127.88,19.71
CARD_RREF on BOTTOM: 14.57,37.56 14.4,37.72 14.4,37.94 14.67,38.21 14.67,39.23 14.7,39.26 14.99,39.26 15.02,39.23 15.02,37.75 14.82,37.56
CHG_AGND on BOTTOM: 136.09,8.06 136.02,8.13 136.02,9.34 135.79,9.57 134.82,9.57 134.74,9.66 134.74,10.48 134.42,10.8 133.19,10.8 132.9,10.51 130.7,10.51 130.5,10.71 130.5,12.34 129.3,13.54 129.3,15.85 129.04,16.11 127.22,16.11 126.65,15.54 126.29,15.54 126.18,15.65 126.18,16.09 127.03,16.94 130.07,16.94 130.5,16.52 130.5,15.66 130.28,14.79 130.85,14.08 131.87,13.06 132.18,13.06 133.22,13.06 133.32,12.96 134.89,12.96 135.03,12.81 135.03,11.68 135.35,11.36 135.35,9.98 135.39,9.95 136.07,9.95 136.59,9.43 136.59,8.12 136.53,8.06 ; 11 cut-outs
DDR_VREF_S3 on BOTTOM: 98.89,20.36 98.78,20.47 98.78,21.3 98.81,21.33 100.07,21.33 100.11,21.29 100.11,20.49 99.98,20.36
EC_VCC1V8 on TOP: 58.62,9.58 58.56,9.64 58.56,10.37 58.46,10.46 58.46,11.57 58.61,11.72 58.83,11.72 59.07,11.48 59.07,10.31 59.29,10.08 59.29,9.68 59.2,9.58
EMMC_VCC on TOP: 104.86,92.16 104.33,92.68 104.33,93.97 104.94,94.57 105.95,94.57 106.38,94.15 107.61,94.15 108.74,95.28 112.77,95.28 113.46,94.59 113.46,92.81 113.38,92.74 111.26,92.74 110.97,93.03 109.34,93.03 108.46,92.16 ; 2 cut-outs
EMMC_VCCQ on TOP: 123.19,98.53 123.04,98.68 123.04,99.55 123.23,99.74 124.75,99.74 124.87,99.62 124.87,99.37 124.72,99.22 124.72,98.68 124.57,98.53 ; 1 cut-out
EMMC_VCCQ on BOTTOM: 95.96,89.56 95.81,89.71 95.81,90.67 95.81,90.67 95.81,92.78 95.86,92.82 99.73,92.82 99.75,92.83 100.14,92.83 100.9,92.07 100.9,89.9 100.57,89.56 ; 2 cut-outs
GFX_CORE on TOP: 73.37,55.02 72.77,55.63 72.77,55.9 74.24,57.37 74.24,57.75 74.08,57.91 74.08,58.05 74.65,58.62 75.29,58.62 76.07,57.84 77.5,57.84 79.02,56.32 79.02,56.1 77.96,55.04 77.57,55.04 77.37,55.24 76.48,55.24 76.27,55.45 76.02,55.45 75.79,55.21 75.48,55.21 75.29,55.41 73.95,55.41 73.56,55.02 ; 7 cut-outs
GFX_CORE on TOP: 50.48,67.01 50.37,67.11 50.37,71.99 50.85,72.47 58.8,72.47 59.05,72.21 59.05,67.51 58.55,67.01 ; 17 cut-outs
GFX_CORE on BOTTOM: 70.57,67.51 70.36,67.72 70.36,68.55 69.96,68.95 69.96,68.96 69.7,69.23 69.7,69.42 69.98,69.7 70.33,69.7 70.84,69.19 71.27,69.19 71.53,68.94 71.53,68.1 70.95,67.51
GFX_CORE on BOTTOM: 58.45,67.49 58.1,67.84 52.13,67.84 51.94,68.02 51.94,74.16 52.2,74.41 59.72,74.41 59.96,74.17 59.96,67.96 59.49,67.49 ; 5 cut-outs
GFX_CORE on BOTTOM: 75.65,54.82 75.16,55.3 74,55.3 72.88,56.42 72.88,56.65 74.05,57.82 74.3,57.82 74.44,57.96 74.74,57.96 74.91,57.79 74.91,57.54 75.02,57.44 75.35,57.44 75.46,57.54 75.46,57.79 75.61,57.95 75.84,57.95 75.98,57.81 75.98,57.6 76.19,57.39 76.37,57.39 77.06,56.69 77.06,56.49 77.19,56.36 77.93,56.36 78.1,56.19 78.1,55.45 77.97,55.32 77.31,55.32 76.82,54.82 76.69,54.82 76.61,54.9 76.61,55.13 76.38,55.35 76.08,55.35 75.83,55.1 75.83,54.87 75.77,54.82
GFX_CORE on L3: 75.83,57.94 75.61,57.94 74.89,57.22 74.89,55.93 75.57,55.25 75.79,55.25 75.95,55.41 76.52,55.41 76.69,55.24 77.89,55.24 78.11,55.46 78.11,55.66
GFX_CORE on L4: 74.6,56.22 75.57,55.25 75.79,55.25 75.91,55.37 76.33,55.37 76.44,55.25 77.9,55.25 78.11,55.46 78.11,56.52 77.01,57.63 77.01,58.68 76.99,58.7 76.99,62.68 77.2,62.88 77.2,63.48 71.4,69.28 70.9,69.28 69.75,68.13 69.75,67.03 69.82,66.96 69.82,61.19 74.6,56.41
GFX_CORE on L5VCC: 74.85,53.68 73.62,54.91 73.62,55.63 72.69,56.56 73.52,57.4 73.52,58.68 72.14,60.07 69.19,60.07 63.62,65.63 55.24,65.63 52.01,68.86 52.01,77.47 53.94,79.4 78.24,79.4 83.13,74.51 83.13,61.43 81.57,59.86 81.57,59.01 82.4,58.18 82.4,56.74 80.88,55.22 77.29,55.22 75.75,53.68
HDMI_PLL_GND on TOP: 14.13,66.6 13.53,67.19 13.53,79.61 13.69,79.78 14.13,79.78 14.15,79.75 14.74,79.75 14.8,79.69 14.8,77.24 14.96,77.08 14.96,70.15 14.8,69.99 14.8,66.83 14.57,66.6
JDREF on BOTTOM: 143.08,91.05 143.03,91.1 143.03,91.28 143.05,91.3 144.07,91.3 144.15,91.38 144.15,91.78 144.71,92.34 144.73,92.34 144.77,92.38 146.08,92.38 146.15,92.31 146.15,91.85 146.02,91.72 144.77,91.72 144.39,91.33 144.39,91.09 144.35,91.05
KBC_VCC on BOTTOM: 71.6,17.5 71.37,17.73 71.37,18.24 71.2,18.42 69.57,18.42 69.55,18.44 69.55,18.57 69.57,18.59 71.27,18.59 72.14,19.46 72.75,19.46 72.85,19.36 72.85,18.49 72.75,18.39 72.75,17.6 72.64,17.5 ; 2 cut-outs
MIC2_VREFO on TOP: 146.38,89.77 146.3,89.84 146.3,90.78 146.37,90.85 147.71,90.85 147.84,90.99 148.38,90.99 148.54,90.82 148.54,90.17 148.14,89.77
MIC_GND on BOTTOM: 55.27,81.24 55.16,81.35 55.16,82.65 55.45,82.93 55.45,84.58 55.5,84.63 55.68,84.63 55.75,84.56 55.75,83.78 55.98,83.55 55.98,81.4 55.82,81.24 ; 2 cut-outs
PS_ID_R on BOTTOM: 27.05,64.73 26.58,65.2 26.58,66.13 26.7,66.25 27.54,66.25 27.97,65.82 27.97,64.84 27.86,64.73
PU4401_4 on BOTTOM: 143.54,28.32 143.49,28.37 143.49,28.95 143.23,29.21 140.51,29.21 140.41,29.31 140.41,29.76 140.47,29.82 141.69,29.82 142.16,30.29 143.73,30.29 143.89,30.12 143.89,28.35 143.86,28.32 ; 2 cut-outs
PU4401_5 on BOTTOM: 142.32,27.57 142.23,27.67 142.23,28.19 142.03,28.38 140.49,28.38 140.4,28.48 140.4,28.9 140.49,28.99 142.55,28.99 143.36,28.18 144.03,28.18 144.13,28.28 144.13,29.3 144.16,29.32 144.51,29.32 144.54,29.29 144.54,28.03 144.18,27.66 143.2,27.66 143.11,27.57 ; 1 cut-out
PWR_1D8V on BOTTOM: 40.01,41.65 39.93,41.73 39.93,45.94 40.26,46.27 42.24,46.27 42.5,46.01 42.5,44.47 42.85,44.12 42.85,41.83 42.67,41.65 ; 2 cut-outs
PWR_1D8V_PHASE on BOTTOM: 37.54,42.8 37.36,42.99 37.36,43.63 36.91,44.07 36.13,44.07 36.07,44.13 36.07,44.3 36.14,44.38 36.99,44.38 37.23,44.61 37.23,44.92 36.86,45.29 36.86,45.8 37.11,46.05 39.25,46.05 39.25,42.92 39.13,42.8
PWR_1D8V_PVDD on BOTTOM: 30.15,42.85 30.04,42.96 30.04,44.37 30.25,44.58 33.75,44.58 33.93,44.39 34.57,44.39 34.65,44.31 34.65,44.13 34.6,44.08 33.94,44.08 33.85,43.98 33.85,43.76 32.95,42.85 ; 6 cut-outs
PWR_1D15V on BOTTOM: 40.13,47.48 40.01,47.6 40.01,51.57 40.03,51.59 41.6,51.59 41.71,51.48 41.71,51.07 42.02,50.76 44.37,50.76 44.37,48.42 44.38,48.41 44.38,47.65 44.22,47.48 ; 4 cut-outs
PWR_1D15V_PHASE on BOTTOM: 37.74,47.42 37.38,47.79 37.38,49.64 37.38,49.66 36.88,50.16 36.18,50.16 36.15,50.18 36.15,50.44 36.18,50.47 36.88,50.47 36.94,50.53 36.94,51.49 37.02,51.57 39.33,51.57 39.33,51.57 39.33,48.32 39.33,48.31 39.33,47.71 39.04,47.42
PWR_1D15V_PVDD on BOTTOM: 30.15,48.74 29.39,49.5 29.39,50.25 29.6,50.46 34.64,50.46 34.69,50.42 34.69,50.21 34.64,50.16 33.85,50.16 32.43,48.74 ; 7 cut-outs
PWR_1D24V on BOTTOM: 47.73,43.11 47.66,43.18 47.66,44.85 47.19,45.32 45.52,45.32 45.31,45.53 45.31,46.78 45.41,46.88 49.45,46.88 49.76,47.19 50.27,47.19 50.27,44.25 50.85,43.67 50.85,43.21 50.75,43.11 ; 1 cut-out
PWR_1D35V_BOOT on TOP: 79.79,23.05 79.63,23.21 79.63,23.77 79.9,24.04 81.83,24.04 81.92,23.95 81.92,23.17 81.8,23.05
PWR_1D35V_BOOT on BOTTOM: 79.64,22.99 79.54,23.08 79.54,24.01 79.56,24.02 79.79,24.02 79.86,23.95 80.79,23.95 81.06,23.68 81.06,23.15 80.9,22.99
PWR_1D35V_BOOT_R on TOP: 82.63,23.01 82.47,23.17 82.47,24.75 82.64,24.92 83.02,24.92 83.16,24.79 83.16,24.12 83.48,23.8 84.1,23.8 84.28,23.62 84.28,23.12 84.17,23.01
PWR_1D35V_PHASE on TOP: 84.48,23.16 84.41,23.23 84.41,24.1 84.26,24.25 84.26,24.62 84.43,24.79 85.39,24.79 85.51,24.66 85.51,23.4 85.27,23.16 ; 1 cut-out
PWR_1D35V_PHASE on BOTTOM: 81.4,23.67 80.98,24.08 79.98,24.08 79.63,24.44 79.63,24.77 79.65,24.8 81.64,24.8 81.75,24.91 81.75,25.97 81.94,26.17 84.83,26.17 85,26.01 85,23.83 84.84,23.67
PWR_1D35V_PHASE on BOTTOM: 76.6,23.15 76.42,23.33 76.42,24 76.77,24.36 77.66,24.36 77.7,24.31 77.7,24.08 77.4,23.79 77.4,23.37 77.18,23.15
PWR_3D3V_BOOT on BOTTOM: 39.5,31.46 39.37,31.59 38.46,31.59 38.27,31.78 38.27,32.3 38.39,32.42 39.63,32.42 39.66,32.4 39.66,31.48 39.64,31.46
PWR_3D3V_LDO on TOP: 38.33,27.1 38.05,27.38 37.03,27.38 36.98,27.43 36.98,28.42 37.11,28.55 38.89,28.55 39.17,28.27 39.17,27.26 39.01,27.1
PWR_3D3V_LDO on BOTTOM: 37.28,26.85 37.2,26.92 37.2,28.28 37.35,28.43 37.35,29.45 37.97,30.07 39.54,30.07 39.58,30.03 39.58,29.85 39.54,29.81 38.35,29.81 38.19,29.66 38.19,28.83 39.24,27.78 39.24,27.23 38.86,26.85 ; 1 cut-out
PWR_3D3V_PH on BOTTOM: 34.25,28.04 33.94,28.36 33.94,32 34.11,32.18 37.65,32.18 38.39,31.44 39.33,31.44 39.64,31.13 39.64,30.71 39.63,30.7 37.51,30.7 37.2,30.39 37.2,28.61 36.63,28.04
PWR_3D3V_PH on BOTTOM: 41.53,31.15 41.51,31.17 41.51,31.36 42.14,31.99 43.16,31.99 43.33,31.83 43.33,31.42 43.05,31.15
PWR_5V_BOOT on BOTTOM: 40.8,21.52 39.81,22.51 39.81,22.91 40.07,23.17 40.43,23.17 40.98,22.61 40.98,21.57 40.93,21.52
PWR_5V_PH on BOTTOM: 35.55,19.43 35.24,19.74 35.24,22.82 35.42,23 39.04,23 40.9,21.14 40.9,20.8 40.89,20.79 39.38,20.79 39.33,20.84 38.49,20.84 38.07,20.42 38.07,19.7 37.81,19.43
PWR_5V_PH on BOTTOM: 42.87,21.22 42.79,21.31 42.79,21.41 43.2,21.83 43.2,22.14 43.46,22.4 44.01,22.4 44.18,22.23 44.18,21.47 43.94,21.22
PWR_CHG_LODRV on TOP: 133.62,12.97 133.61,12.98 133.61,13.68 134.79,14.86 135.13,14.86 135.29,14.69 135.29,14.35 134.54,13.6 134.54,12.98 134.53,12.97
PWR_CHG_LODRV on BOTTOM: 134.09,18.73 133.96,18.86 133.96,19.71 134.62,20.38 135.08,20.38 135.11,20.35 135.11,18.91 134.93,18.73
PWR_CHG_PHASE on BOTTOM: 130.6,19.54 130.4,19.73 130.4,23.44 130.41,23.44 130.41,24.45 130.75,24.8 133.89,24.8 134.07,24.62 134.07,21.95 134.37,21.65 137.08,21.65 137.15,21.57 137.15,20.67 137.07,20.59 134.46,20.59 133.41,19.54
PWR_CHG_VCC on TOP: 130.47,13.46 129.13,14.8 128.26,14.8 128.15,14.92 128.15,15.88 128.28,16.01 129.26,16.01 129.44,16.19 129.44,17.02 129.54,17.12 131.09,17.12 131.09,14.72 131.43,14.38 131.43,13.47 131.42,13.46 ; 1 cut-out
PWR_DCBATOUT_1D35V on BOTTOM: 75.28,19.46 74.75,19.99 74.75,23.82 74.89,23.96 75.35,23.96 76.44,22.87 77.19,22.87 77.55,23.23 77.55,23.75 78.14,24.34 79.27,24.34 79.34,24.27 79.34,23 79.07,22.72 79.07,19.73 78.79,19.46 ; 1 cut-out
PWR_VCC0_BT on BOTTOM: 29.97,58.36 29.94,58.39 29.94,58.59 31.29,59.95 32.98,59.95 33.24,59.68 33.24,58.85 33.14,58.75 30.91,58.75 30.51,58.36
PWR_VCC0_BTR on BOTTOM: 33.75,57.41 33.58,57.58 33.58,58.62 33.4,58.8 33.4,59.84 33.48,59.92 34.85,59.92 35.1,59.67 35.1,57.76 34.75,57.41 ; 2 cut-outs
PWR_VCC0_HG on BOTTOM: 39.18,64.81 38.89,65.1 38.89,65.54 39.18,65.83 40.84,65.83 40.89,65.78 40.89,64.87 40.84,64.81
PWR_VCORE_LG1 on BOTTOM: 38.99,58.79 38.82,58.97 38.82,59.61 39.01,59.81 40.81,59.81 40.89,59.73 40.89,58.87 40.81,58.79
PWR_VCORE_PH1 on BOTTOM: 46.86,56.72 46.7,56.87 46.7,58.99 45.51,60.18 39.83,60.18 39.81,60.21 39.81,63.1 39.83,63.12 45.35,63.12 45.47,63.25 45.47,63.89 45.71,64.12 48.6,64.12 48.88,63.84 48.88,62.09 48.82,62.03 48.44,62.03 48.44,61.01 48.88,61.01 48.88,61.01 48.88,58.78 48.22,58.12 48.22,56.88 48.06,56.72
PWR_VGG_BTR on BOTTOM: 32.48,72.81 32.25,73.04 32.25,74.42 32.39,74.56 34.44,74.56 34.55,74.46 34.55,73.85 33.51,72.81 ; 1 cut-out
PWR_VGG_HG on BOTTOM: 44.48,67.75 44.37,67.85 44.37,68.65 44.49,68.77 45.31,68.77 45.43,68.9 45.93,68.9 46.11,68.72 46.11,68.06 45.8,67.75
PWR_VGG_LG on BOTTOM: 44.44,73.78 44.37,73.86 44.37,74.69 44.47,74.79 46.28,74.79 46.54,74.52 46.54,74.07 46.26,73.78
PWR_VGG_SW on BOTTOM: 46.56,68.87 46.37,69.06 46.37,69.87 45.75,70.49 40.18,70.49 40.06,70.61 40.06,73.23 40.21,73.38 49.28,73.38 49.39,73.28 49.39,69.04 49.22,68.87
Q6203_S on BOTTOM: 41.68,3.09 41.6,3.18 41.6,5.16 41.82,5.38 43.78,5.38 43.98,5.19 43.98,4.55 42.52,3.09 ; 1 cut-out
RING2 on TOP: 145.21,90.5 145.01,90.7 144.5,90.7 144.44,90.76 144.44,92.06 144.57,92.19 145.69,92.19 145.84,92.04 145.84,91.55 146.09,91.3 146.09,90.53 146.06,90.5 ; 1 cut-out
RING2 on BOTTOM: 143.04,90.27 143.01,90.3 143.01,90.48 144.06,90.48 144.51,90.94 144.51,91.27 144.75,91.51 145.12,91.51 145.32,91.31 145.32,90.96 145.02,90.66 144.68,90.66 144.28,90.27
RING2 on L3: 144.75,90.68 145.11,90.68 145.34,90.91 145.34,92.47 147.7,94.83 148.88,94.83 149.07,95.02 149.07,95.4 148.86,95.61 147.37,95.61 144.55,92.8 144.55,90.88
RING2_R on TOP: 151.08,95.9 150.99,95.99 150.99,96.94 151.09,97.04 153.5,97.04 153.66,96.89 153.66,96.29 153.26,95.9
RING2_R on BOTTOM: 152.08,96.31 152.45,96.67 153.8,96.67 153.85,96.62 153.85,95.38 152.3,95.38 152.08,95.59
RTC_AUX_S5 on TOP: 46.45,20.23 46.31,20.37 46.31,23.33 46.42,23.44 46.99,23.44 47.17,23.26 47.17,20.63 46.77,20.23
RTC_AUX_S5 on TOP: 51.42,53.72 51.32,53.82 51.32,54.46 51.31,54.47 50.4,54.47 49.79,53.86 48.55,53.86 48.47,53.94 48.47,54.36 48.56,54.45 49.5,54.45 50.5,55.45 50.5,56.56 52.14,58.2 52.45,58.2 52.63,58.02 52.63,57.76 51.3,56.44 51.3,55.33 51.86,54.77 51.86,53.72
RTC_DET#_G on TOP: 133.51,99.73 133.07,100.18 132.26,100.18 132.13,100.31 132.13,101.06 132.2,101.13 135.26,101.13 135.36,101.03 135.36,100.11 135.14,99.89 133.94,99.89 133.78,99.73 ; 3 cut-outs
RTC_RST# on BOTTOM: 62.66,45.08 62.33,45.41 62.33,45.52 62.56,45.75 62.69,45.75 62.98,45.46 62.98,45.1 63.98,44.1 63.98,43.99 63.86,43.87 63.2,43.87 62.66,44.4
SLEEVE on TOP: 145.19,87.78 145.06,87.92 145.06,89.25 144.34,89.97 144.34,90.24 144.64,90.54 144.91,90.54 145.25,90.2 146.07,90.2 146.08,90.18 146.08,89.6 145.83,89.35 145.83,88 145.62,87.78
